<?xml version="1.0" encoding="utf-8" standalone="no"?>
<device schemaVersion="1.1">
  <name>STM32H755ZIT7@M4</name>
  <version>1.0</version>
  <description>STM32H755BIT3@M4,STM32H755BIT6@M4,STM32H755BIT7@M4,STM32H755IIK3@M4,STM32H755IIK6@M4,STM32H755IIK7@M4,STM32H755IIT3@M4,STM32H755IIT6@M4,STM32H755IIT7@M4,STM32H755XIH3@M4,STM32H755XIH6@M4,STM32H755XIH7@M4,STM32H755ZIT3@M4,STM32H755ZIT6@M4,STM32H755ZIT7@M4</description>
  <addressUnitBits>8</addressUnitBits>
  <width>32</width>
  <size>0x20</size>
  <resetValue>0</resetValue>
  <resetMask>0xFFFFFFFF</resetMask>
  <peripherals>
    <peripheral>
      <name>TIM2</name>
      <baseAddress>0x40000000</baseAddress>
      <registers>
        <register>
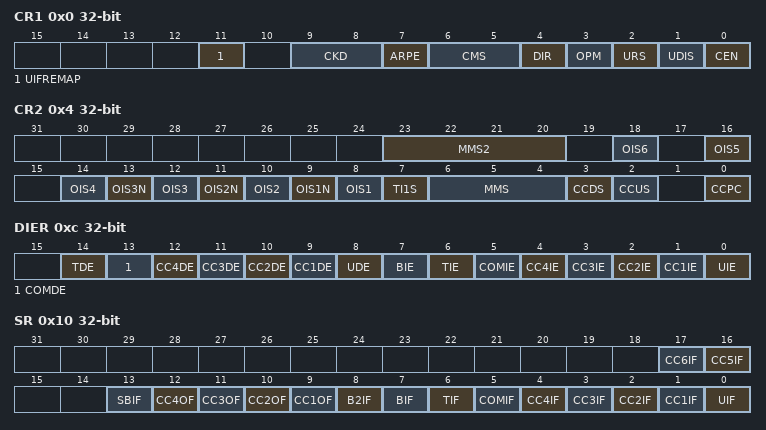
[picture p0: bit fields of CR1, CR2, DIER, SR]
          <name>CR1</name>
          <addressOffset>0x0</addressOffset>
          <size>0x20</size>
          <fields>
            <field>
              <name>CEN</name>
              <bitOffset>0</bitOffset>
              <bitWidth>1</bitWidth>
            </field>
            <field>
              <name>UDIS</name>
              <bitOffset>1</bitOffset>
              <bitWidth>1</bitWidth>
            </field>
            <field>
              <name>URS</name>
              <bitOffset>2</bitOffset>
              <bitWidth>1</bitWidth>
            </field>
            <field>
              <name>OPM</name>
              <bitOffset>3</bitOffset>
              <bitWidth>1</bitWidth>
            </field>
            <field>
              <name>DIR</name>
              <bitOffset>4</bitOffset>
              <bitWidth>1</bitWidth>
            </field>
            <field>
              <name>CMS</name>
              <bitOffset>5</bitOffset>
              <bitWidth>2</bitWidth>
            </field>
            <field>
              <name>ARPE</name>
              <bitOffset>7</bitOffset>
              <bitWidth>1</bitWidth>
            </field>
            <field>
              <name>CKD</name>
              <bitOffset>8</bitOffset>
              <bitWidth>2</bitWidth>
            </field>
            <field>
              <name>UIFREMAP</name>
              <bitOffset>11</bitOffset>
              <bitWidth>1</bitWidth>
            </field>
          </fields>
        </register>
        <register>
          <name>CR2</name>
          <addressOffset>0x4</addressOffset>
          <size>0x20</size>
          <fields>
            <field>
              <name>CCPC</name>
              <bitOffset>0</bitOffset>
              <bitWidth>1</bitWidth>
            </field>
            <field>
              <name>CCUS</name>
              <bitOffset>2</bitOffset>
              <bitWidth>1</bitWidth>
            </field>
            <field>
              <name>CCDS</name>
              <bitOffset>3</bitOffset>
              <bitWidth>1</bitWidth>
            </field>
            <field>
              <name>MMS</name>
              <bitOffset>4</bitOffset>
              <bitWidth>3</bitWidth>
            </field>
            <field>
              <name>TI1S</name>
              <bitOffset>7</bitOffset>
              <bitWidth>1</bitWidth>
            </field>
            <field>
              <name>OIS1</name>
              <bitOffset>8</bitOffset>
              <bitWidth>1</bitWidth>
            </field>
            <field>
              <name>OIS1N</name>
              <bitOffset>9</bitOffset>
              <bitWidth>1</bitWidth>
            </field>
            <field>
              <name>OIS2</name>
              <bitOffset>10</bitOffset>
              <bitWidth>1</bitWidth>
            </field>
            <field>
              <name>OIS2N</name>
              <bitOffset>11</bitOffset>
              <bitWidth>1</bitWidth>
            </field>
            <field>
              <name>OIS3</name>
              <bitOffset>12</bitOffset>
              <bitWidth>1</bitWidth>
            </field>
            <field>
              <name>OIS3N</name>
              <bitOffset>13</bitOffset>
              <bitWidth>1</bitWidth>
            </field>
            <field>
              <name>OIS4</name>
              <bitOffset>14</bitOffset>
              <bitWidth>1</bitWidth>
            </field>
            <field>
              <name>OIS5</name>
              <bitOffset>16</bitOffset>
              <bitWidth>1</bitWidth>
            </field>
            <field>
              <name>OIS6</name>
              <bitOffset>18</bitOffset>
              <bitWidth>1</bitWidth>
            </field>
            <field>
              <name>MMS2</name>
              <bitOffset>20</bitOffset>
              <bitWidth>4</bitWidth>
            </field>
          </fields>
        </register>
        <register>
          <name>SMCR</name>
          <addressOffset>0x8</addressOffset>
          <size>0x20</size>
          <fields>
            <field>
              <name>SMS</name>
              <bitOffset>0</bitOffset>
              <bitWidth>17</bitWidth>
            </field>
            <field>
              <name>TS</name>
              <bitOffset>4</bitOffset>
              <bitWidth>18</bitWidth>
            </field>
            <field>
              <name>MSM</name>
              <bitOffset>7</bitOffset>
              <bitWidth>1</bitWidth>
            </field>
            <field>
              <name>ETF</name>
              <bitOffset>8</bitOffset>
              <bitWidth>4</bitWidth>
            </field>
            <field>
              <name>ETPS</name>
              <bitOffset>12</bitOffset>
              <bitWidth>2</bitWidth>
            </field>
            <field>
              <name>ECE</name>
              <bitOffset>14</bitOffset>
              <bitWidth>1</bitWidth>
            </field>
            <field>
              <name>ETP</name>
              <bitOffset>15</bitOffset>
              <bitWidth>1</bitWidth>
            </field>
          </fields>
        </register>
        <register>
          <name>DIER</name>
          <addressOffset>0xc</addressOffset>
          <size>0x20</size>
          <fields>
            <field>
              <name>UIE</name>
              <bitOffset>0</bitOffset>
              <bitWidth>1</bitWidth>
            </field>
            <field>
              <name>CC1IE</name>
              <bitOffset>1</bitOffset>
              <bitWidth>1</bitWidth>
            </field>
            <field>
              <name>CC2IE</name>
              <bitOffset>2</bitOffset>
              <bitWidth>1</bitWidth>
            </field>
            <field>
              <name>CC3IE</name>
              <bitOffset>3</bitOffset>
              <bitWidth>1</bitWidth>
            </field>
            <field>
              <name>CC4IE</name>
              <bitOffset>4</bitOffset>
              <bitWidth>1</bitWidth>
            </field>
            <field>
              <name>COMIE</name>
              <bitOffset>5</bitOffset>
              <bitWidth>1</bitWidth>
            </field>
            <field>
              <name>TIE</name>
              <bitOffset>6</bitOffset>
              <bitWidth>1</bitWidth>
            </field>
            <field>
              <name>BIE</name>
              <bitOffset>7</bitOffset>
              <bitWidth>1</bitWidth>
            </field>
            <field>
              <name>UDE</name>
              <bitOffset>8</bitOffset>
              <bitWidth>1</bitWidth>
            </field>
            <field>
              <name>CC1DE</name>
              <bitOffset>9</bitOffset>
              <bitWidth>1</bitWidth>
            </field>
            <field>
              <name>CC2DE</name>
              <bitOffset>10</bitOffset>
              <bitWidth>1</bitWidth>
            </field>
            <field>
              <name>CC3DE</name>
              <bitOffset>11</bitOffset>
              <bitWidth>1</bitWidth>
            </field>
            <field>
              <name>CC4DE</name>
              <bitOffset>12</bitOffset>
              <bitWidth>1</bitWidth>
            </field>
            <field>
              <name>COMDE</name>
              <bitOffset>13</bitOffset>
              <bitWidth>1</bitWidth>
            </field>
            <field>
              <name>TDE</name>
              <bitOffset>14</bitOffset>
              <bitWidth>1</bitWidth>
            </field>
          </fields>
        </register>
        <register>
          <name>SR</name>
          <addressOffset>0x10</addressOffset>
          <size>0x20</size>
          <fields>
            <field>
              <name>UIF</name>
              <bitOffset>0</bitOffset>
              <bitWidth>1</bitWidth>
            </field>
            <field>
              <name>CC1IF</name>
              <bitOffset>1</bitOffset>
              <bitWidth>1</bitWidth>
            </field>
            <field>
              <name>CC2IF</name>
              <bitOffset>2</bitOffset>
              <bitWidth>1</bitWidth>
            </field>
            <field>
              <name>CC3IF</name>
              <bitOffset>3</bitOffset>
              <bitWidth>1</bitWidth>
            </field>
            <field>
              <name>CC4IF</name>
              <bitOffset>4</bitOffset>
              <bitWidth>1</bitWidth>
            </field>
            <field>
              <name>COMIF</name>
              <bitOffset>5</bitOffset>
              <bitWidth>1</bitWidth>
            </field>
            <field>
              <name>TIF</name>
              <bitOffset>6</bitOffset>
              <bitWidth>1</bitWidth>
            </field>
            <field>
              <name>BIF</name>
              <bitOffset>7</bitOffset>
              <bitWidth>1</bitWidth>
            </field>
            <field>
              <name>B2IF</name>
              <bitOffset>8</bitOffset>
              <bitWidth>1</bitWidth>
            </field>
            <field>
              <name>CC1OF</name>
              <bitOffset>9</bitOffset>
              <bitWidth>1</bitWidth>
            </field>
            <field>
              <name>CC2OF</name>
              <bitOffset>10</bitOffset>
              <bitWidth>1</bitWidth>
            </field>
            <field>
              <name>CC3OF</name>
              <bitOffset>11</bitOffset>
              <bitWidth>1</bitWidth>
            </field>
            <field>
              <name>CC4OF</name>
              <bitOffset>12</bitOffset>
              <bitWidth>1</bitWidth>
            </field>
            <field>
              <name>SBIF</name>
              <bitOffset>13</bitOffset>
              <bitWidth>1</bitWidth>
            </field>
            <field>
              <name>CC5IF</name>
              <bitOffset>16</bitOffset>
              <bitWidth>1</bitWidth>
            </field>
            <field>
              <name>CC6IF</name>
              <bitOffset>17</bitOffset>
              <bitWidth>1</bitWidth>
            </field>
          </fields>
        </register>
        <register>
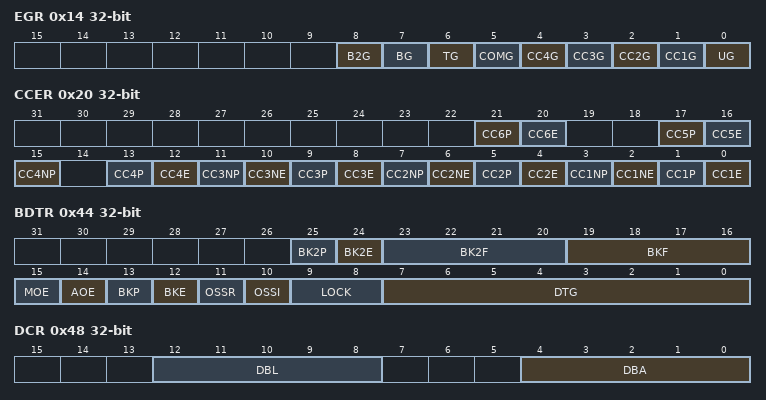
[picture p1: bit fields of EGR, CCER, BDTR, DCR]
          <name>EGR</name>
          <addressOffset>0x14</addressOffset>
          <size>0x20</size>
          <fields>
            <field>
              <name>UG</name>
              <bitOffset>0</bitOffset>
              <bitWidth>1</bitWidth>
            </field>
            <field>
              <name>CC1G</name>
              <bitOffset>1</bitOffset>
              <bitWidth>1</bitWidth>
            </field>
            <field>
              <name>CC2G</name>
              <bitOffset>2</bitOffset>
              <bitWidth>1</bitWidth>
            </field>
            <field>
              <name>CC3G</name>
              <bitOffset>3</bitOffset>
              <bitWidth>1</bitWidth>
            </field>
            <field>
              <name>CC4G</name>
              <bitOffset>4</bitOffset>
              <bitWidth>1</bitWidth>
            </field>
            <field>
              <name>COMG</name>
              <bitOffset>5</bitOffset>
              <bitWidth>1</bitWidth>
            </field>
            <field>
              <name>TG</name>
              <bitOffset>6</bitOffset>
              <bitWidth>1</bitWidth>
            </field>
            <field>
              <name>BG</name>
              <bitOffset>7</bitOffset>
              <bitWidth>1</bitWidth>
            </field>
            <field>
              <name>B2G</name>
              <bitOffset>8</bitOffset>
              <bitWidth>1</bitWidth>
            </field>
          </fields>
        </register>
        <register>
          <name>CCMR1</name>
          <addressOffset>0x18</addressOffset>
          <size>0x20</size>
          <fields>
            <field>
              <name>CC1S</name>
              <bitOffset>0</bitOffset>
              <bitWidth>2</bitWidth>
            </field>
            <field>
              <name>OC1FE</name>
              <bitOffset>2</bitOffset>
              <bitWidth>1</bitWidth>
            </field>
            <field>
              <name>OC1PE</name>
              <bitOffset>3</bitOffset>
              <bitWidth>1</bitWidth>
            </field>
            <field>
              <name>OC1M</name>
              <bitOffset>4</bitOffset>
              <bitWidth>13</bitWidth>
            </field>
            <field>
              <name>OC1CE</name>
              <bitOffset>7</bitOffset>
              <bitWidth>1</bitWidth>
            </field>
            <field>
              <name>CC2S</name>
              <bitOffset>8</bitOffset>
              <bitWidth>2</bitWidth>
            </field>
            <field>
              <name>OC2FE</name>
              <bitOffset>10</bitOffset>
              <bitWidth>1</bitWidth>
            </field>
            <field>
              <name>OC2PE</name>
              <bitOffset>11</bitOffset>
              <bitWidth>1</bitWidth>
            </field>
            <field>
              <name>OC2M</name>
              <bitOffset>12</bitOffset>
              <bitWidth>13</bitWidth>
            </field>
            <field>
              <name>OC2CE</name>
              <bitOffset>15</bitOffset>
              <bitWidth>1</bitWidth>
            </field>
          </fields>
        </register>
        <register>
          <name>CCMR2</name>
          <addressOffset>0x1c</addressOffset>
          <size>0x20</size>
          <fields>
            <field>
              <name>CC3S</name>
              <bitOffset>0</bitOffset>
              <bitWidth>2</bitWidth>
            </field>
            <field>
              <name>OC3FE</name>
              <bitOffset>2</bitOffset>
              <bitWidth>1</bitWidth>
            </field>
            <field>
              <name>OC3PE</name>
              <bitOffset>3</bitOffset>
              <bitWidth>1</bitWidth>
            </field>
            <field>
              <name>OC3M</name>
              <bitOffset>4</bitOffset>
              <bitWidth>13</bitWidth>
            </field>
            <field>
              <name>OC3CE</name>
              <bitOffset>7</bitOffset>
              <bitWidth>1</bitWidth>
            </field>
            <field>
              <name>CC4S</name>
              <bitOffset>8</bitOffset>
              <bitWidth>2</bitWidth>
            </field>
            <field>
              <name>OC4FE</name>
              <bitOffset>10</bitOffset>
              <bitWidth>1</bitWidth>
            </field>
            <field>
              <name>OC4PE</name>
              <bitOffset>11</bitOffset>
              <bitWidth>1</bitWidth>
            </field>
            <field>
              <name>OC4M</name>
              <bitOffset>12</bitOffset>
              <bitWidth>13</bitWidth>
            </field>
            <field>
              <name>OC4CE</name>
              <bitOffset>15</bitOffset>
              <bitWidth>1</bitWidth>
            </field>
          </fields>
        </register>
        <register>
          <name>CCER</name>
          <addressOffset>0x20</addressOffset>
          <size>0x20</size>
          <fields>
            <field>
              <name>CC1E</name>
              <bitOffset>0</bitOffset>
              <bitWidth>1</bitWidth>
            </field>
            <field>
              <name>CC1P</name>
              <bitOffset>1</bitOffset>
              <bitWidth>1</bitWidth>
            </field>
            <field>
              <name>CC1NE</name>
              <bitOffset>2</bitOffset>
              <bitWidth>1</bitWidth>
            </field>
            <field>
              <name>CC1NP</name>
              <bitOffset>3</bitOffset>
              <bitWidth>1</bitWidth>
            </field>
            <field>
              <name>CC2E</name>
              <bitOffset>4</bitOffset>
              <bitWidth>1</bitWidth>
            </field>
            <field>
              <name>CC2P</name>
              <bitOffset>5</bitOffset>
              <bitWidth>1</bitWidth>
            </field>
            <field>
              <name>CC2NE</name>
              <bitOffset>6</bitOffset>
              <bitWidth>1</bitWidth>
            </field>
            <field>
              <name>CC2NP</name>
              <bitOffset>7</bitOffset>
              <bitWidth>1</bitWidth>
            </field>
            <field>
              <name>CC3E</name>
              <bitOffset>8</bitOffset>
              <bitWidth>1</bitWidth>
            </field>
            <field>
              <name>CC3P</name>
              <bitOffset>9</bitOffset>
              <bitWidth>1</bitWidth>
            </field>
            <field>
              <name>CC3NE</name>
              <bitOffset>10</bitOffset>
              <bitWidth>1</bitWidth>
            </field>
            <field>
              <name>CC3NP</name>
              <bitOffset>11</bitOffset>
              <bitWidth>1</bitWidth>
            </field>
            <field>
              <name>CC4E</name>
              <bitOffset>12</bitOffset>
              <bitWidth>1</bitWidth>
            </field>
            <field>
              <name>CC4P</name>
              <bitOffset>13</bitOffset>
              <bitWidth>1</bitWidth>
            </field>
            <field>
              <name>CC4NP</name>
              <bitOffset>15</bitOffset>
              <bitWidth>1</bitWidth>
            </field>
            <field>
              <name>CC5E</name>
              <bitOffset>16</bitOffset>
              <bitWidth>1</bitWidth>
            </field>
            <field>
              <name>CC5P</name>
              <bitOffset>17</bitOffset>
              <bitWidth>1</bitWidth>
            </field>
            <field>
              <name>CC6E</name>
              <bitOffset>20</bitOffset>
              <bitWidth>1</bitWidth>
            </field>
            <field>
              <name>CC6P</name>
              <bitOffset>21</bitOffset>
              <bitWidth>1</bitWidth>
            </field>
          </fields>
        </register>
        <register>
          <name>CNT</name>
          <addressOffset>0x24</addressOffset>
          <size>0x20</size>
          <fields>
            <field>
              <name>CNT</name>
              <bitOffset>0</bitOffset>
              <bitWidth>32</bitWidth>
            </field>
            <field>
              <name>UIFCPY</name>
              <bitOffset>31</bitOffset>
              <bitWidth>1</bitWidth>
            </field>
          </fields>
        </register>
        <register>
          <name>PSC</name>
          <addressOffset>0x28</addressOffset>
          <size>0x20</size>
          <fields>
            <field>
              <name>PSC</name>
              <bitOffset>0</bitOffset>
              <bitWidth>16</bitWidth>
            </field>
          </fields>
        </register>
        <register>
          <name>ARR</name>
          <addressOffset>0x2c</addressOffset>
          <size>0x20</size>
          <fields>
            <field>
              <name>ARR</name>
              <bitOffset>0</bitOffset>
              <bitWidth>32</bitWidth>
            </field>
          </fields>
        </register>
        <register>
          <name>RCR</name>
          <addressOffset>0x30</addressOffset>
          <size>0x20</size>
          <fields>
            <field>
              <name>REP</name>
              <bitOffset>0</bitOffset>
              <bitWidth>8</bitWidth>
            </field>
          </fields>
        </register>
        <register>
          <name>CCR1</name>
          <addressOffset>0x34</addressOffset>
          <size>0x20</size>
          <fields>
            <field>
              <name>CCR1</name>
              <bitOffset>0</bitOffset>
              <bitWidth>16</bitWidth>
            </field>
          </fields>
        </register>
        <register>
          <name>CCR2</name>
          <addressOffset>0x38</addressOffset>
          <size>0x20</size>
          <fields>
            <field>
              <name>CCR2</name>
              <bitOffset>0</bitOffset>
              <bitWidth>16</bitWidth>
            </field>
          </fields>
        </register>
        <register>
          <name>CCR3</name>
          <addressOffset>0x3c</addressOffset>
          <size>0x20</size>
          <fields>
            <field>
              <name>CCR3</name>
              <bitOffset>0</bitOffset>
              <bitWidth>16</bitWidth>
            </field>
          </fields>
        </register>
        <register>
          <name>CCR4</name>
          <addressOffset>0x40</addressOffset>
          <size>0x20</size>
          <fields>
            <field>
              <name>CCR4</name>
              <bitOffset>0</bitOffset>
              <bitWidth>16</bitWidth>
            </field>
          </fields>
        </register>
        <register>
          <name>BDTR</name>
          <addressOffset>0x44</addressOffset>
          <size>0x20</size>
          <fields>
            <field>
              <name>DTG</name>
              <bitOffset>0</bitOffset>
              <bitWidth>8</bitWidth>
            </field>
            <field>
              <name>LOCK</name>
              <bitOffset>8</bitOffset>
              <bitWidth>2</bitWidth>
            </field>
            <field>
              <name>OSSI</name>
              <bitOffset>10</bitOffset>
              <bitWidth>1</bitWidth>
            </field>
            <field>
              <name>OSSR</name>
              <bitOffset>11</bitOffset>
              <bitWidth>1</bitWidth>
            </field>
            <field>
              <name>BKE</name>
              <bitOffset>12</bitOffset>
              <bitWidth>1</bitWidth>
            </field>
            <field>
              <name>BKP</name>
              <bitOffset>13</bitOffset>
              <bitWidth>1</bitWidth>
            </field>
            <field>
              <name>AOE</name>
              <bitOffset>14</bitOffset>
              <bitWidth>1</bitWidth>
            </field>
            <field>
              <name>MOE</name>
              <bitOffset>15</bitOffset>
              <bitWidth>1</bitWidth>
            </field>
            <field>
              <name>BKF</name>
              <bitOffset>16</bitOffset>
              <bitWidth>4</bitWidth>
            </field>
            <field>
              <name>BK2F</name>
              <bitOffset>20</bitOffset>
              <bitWidth>4</bitWidth>
            </field>
            <field>
              <name>BK2E</name>
              <bitOffset>24</bitOffset>
              <bitWidth>1</bitWidth>
            </field>
            <field>
              <name>BK2P</name>
              <bitOffset>25</bitOffset>
              <bitWidth>1</bitWidth>
            </field>
          </fields>
        </register>
        <register>
          <name>DCR</name>
          <addressOffset>0x48</addressOffset>
          <size>0x20</size>
          <fields>
            <field>
              <name>DBA</name>
              <bitOffset>0</bitOffset>
              <bitWidth>5</bitWidth>
            </field>
            <field>
              <name>DBL</name>
              <bitOffset>8</bitOffset>
              <bitWidth>5</bitWidth>
            </field>
          </fields>
        </register>
        <register>
          <name>DMAR</name>
          <addressOffset>0x4c</addressOffset>
          <size>0x20</size>
          <fields>
            <field>
              <name>DMAB</name>
              <bitOffset>0</bitOffset>
              <bitWidth>16</bitWidth>
            </field>
          </fields>
        </register>
        <register>
          <name>CCMR3</name>
          <addressOffset>0x54</addressOffset>
          <size>0x20</size>
          <fields>
            <field>
              <name>OC5FE</name>
              <bitOffset>2</bitOffset>
              <bitWidth>1</bitWidth>
            </field>
            <field>
              <name>OC5PE</name>
              <bitOffset>3</bitOffset>
              <bitWidth>1</bitWidth>
            </field>
            <field>
              <name>OC5M</name>
              <bitOffset>4</bitOffset>
              <bitWidth>13</bitWidth>
            </field>
            <field>
              <name>OC5CE</name>
              <bitOffset>7</bitOffset>
              <bitWidth>1</bitWidth>
            </field>
            <field>
              <name>OC6FE</name>
              <bitOffset>10</bitOffset>
              <bitWidth>1</bitWidth>
            </field>
            <field>
              <name>OC6PE</name>
              <bitOffset>11</bitOffset>
              <bitWidth>1</bitWidth>
            </field>
            <field>
              <name>OC6M</name>
              <bitOffset>12</bitOffset>
              <bitWidth>13</bitWidth>
            </field>
            <field>
              <name>OC6CE</name>
              <bitOffset>15</bitOffset>
              <bitWidth>1</bitWidth>
            </field>
          </fields>
        </register>
        <register>
          <name>CCR5</name>
          <addressOffset>0x58</addressOffset>
          <size>0x20</size>
          <fields>
            <field>
              <name>CCR5</name>
              <bitOffset>0</bitOffset>
              <bitWidth>32</bitWidth>
            </field>
            <field>
              <name>GC5C1</name>
              <bitOffset>29</bitOffset>
              <bitWidth>1</bitWidth>
            </field>
            <field>
              <name>GC5C2</name>
              <bitOffset>30</bitOffset>
              <bitWidth>1</bitWidth>
            </field>
            <field>
              <name>GC5C3</name>
              <bitOffset>31</bitOffset>
              <bitWidth>1</bitWidth>
            </field>
          </fields>
        </register>
        <register>
          <name>CCR6</name>
          <addressOffset>0x5c</addressOffset>
          <size>0x20</size>
          <fields>
            <field>
              <name>CCR6</name>
              <bitOffset>0</bitOffset>
              <bitWidth>16</bitWidth>
            </field>
          </fields>
        </register>
        <register>
          <name>AF1</name>
          <addressOffset>0x60</addressOffset>
          <size>0x20</size>
        </register>
        <register>
          <name>AF2</name>
          <addressOffset>0x64</addressOffset>
          <size>0x20</size>
        </register>
        <register>
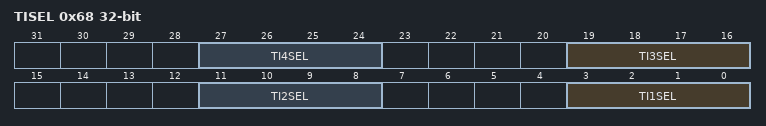
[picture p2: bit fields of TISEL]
          <name>TISEL</name>
          <addressOffset>0x68</addressOffset>
          <size>0x20</size>
          <fields>
            <field>
              <name>TI1SEL</name>
              <bitOffset>0</bitOffset>
              <bitWidth>4</bitWidth>
            </field>
            <field>
              <name>TI2SEL</name>
              <bitOffset>8</bitOffset>
              <bitWidth>4</bitWidth>
            </field>
            <field>
              <name>TI3SEL</name>
              <bitOffset>16</bitOffset>
              <bitWidth>4</bitWidth>
            </field>
            <field>
              <name>TI4SEL</name>
              <bitOffset>24</bitOffset>
              <bitWidth>4</bitWidth>
            </field>
          </fields>
        </register>
      </registers>
    </peripheral>
    <peripheral>
      <name>TIM3</name>
      <baseAddress>0x40000400</baseAddress>
      <registers>
        <register>
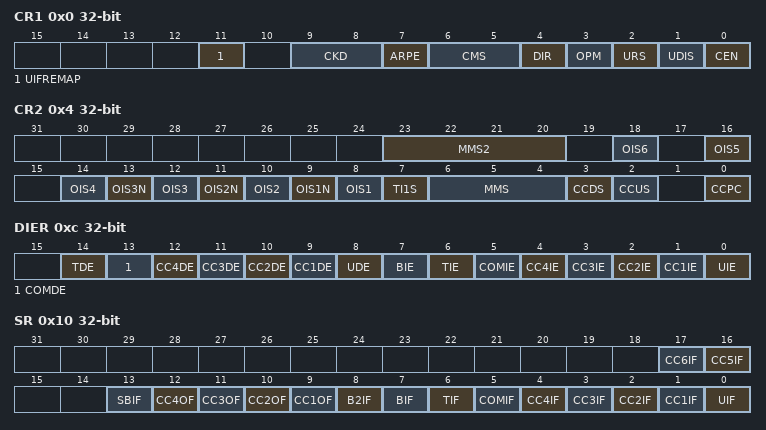
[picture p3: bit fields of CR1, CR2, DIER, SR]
          <name>CR1</name>
          <addressOffset>0x0</addressOffset>
          <size>0x20</size>
          <fields>
            <field>
              <name>CEN</name>
              <bitOffset>0</bitOffset>
              <bitWidth>1</bitWidth>
            </field>
            <field>
              <name>UDIS</name>
              <bitOffset>1</bitOffset>
              <bitWidth>1</bitWidth>
            </field>
            <field>
              <name>URS</name>
              <bitOffset>2</bitOffset>
              <bitWidth>1</bitWidth>
            </field>
            <field>
              <name>OPM</name>
              <bitOffset>3</bitOffset>
              <bitWidth>1</bitWidth>
            </field>
            <field>
              <name>DIR</name>
              <bitOffset>4</bitOffset>
              <bitWidth>1</bitWidth>
            </field>
            <field>
              <name>CMS</name>
              <bitOffset>5</bitOffset>
              <bitWidth>2</bitWidth>
            </field>
            <field>
              <name>ARPE</name>
              <bitOffset>7</bitOffset>
              <bitWidth>1</bitWidth>
            </field>
            <field>
              <name>CKD</name>
              <bitOffset>8</bitOffset>
              <bitWidth>2</bitWidth>
            </field>
            <field>
              <name>UIFREMAP</name>
              <bitOffset>11</bitOffset>
              <bitWidth>1</bitWidth>
            </field>
          </fields>
        </register>
        <register>
          <name>CR2</name>
          <addressOffset>0x4</addressOffset>
          <size>0x20</size>
          <fields>
            <field>
              <name>CCPC</name>
              <bitOffset>0</bitOffset>
              <bitWidth>1</bitWidth>
            </field>
            <field>
              <name>CCUS</name>
              <bitOffset>2</bitOffset>
              <bitWidth>1</bitWidth>
            </field>
            <field>
              <name>CCDS</name>
              <bitOffset>3</bitOffset>
              <bitWidth>1</bitWidth>
            </field>
            <field>
              <name>MMS</name>
              <bitOffset>4</bitOffset>
              <bitWidth>3</bitWidth>
            </field>
            <field>
              <name>TI1S</name>
              <bitOffset>7</bitOffset>
              <bitWidth>1</bitWidth>
            </field>
            <field>
              <name>OIS1</name>
              <bitOffset>8</bitOffset>
              <bitWidth>1</bitWidth>
            </field>
            <field>
              <name>OIS1N</name>
              <bitOffset>9</bitOffset>
              <bitWidth>1</bitWidth>
            </field>
            <field>
              <name>OIS2</name>
              <bitOffset>10</bitOffset>
              <bitWidth>1</bitWidth>
            </field>
            <field>
              <name>OIS2N</name>
              <bitOffset>11</bitOffset>
              <bitWidth>1</bitWidth>
            </field>
            <field>
              <name>OIS3</name>
              <bitOffset>12</bitOffset>
              <bitWidth>1</bitWidth>
            </field>
            <field>
              <name>OIS3N</name>
              <bitOffset>13</bitOffset>
              <bitWidth>1</bitWidth>
            </field>
            <field>
              <name>OIS4</name>
              <bitOffset>14</bitOffset>
              <bitWidth>1</bitWidth>
            </field>
            <field>
              <name>OIS5</name>
              <bitOffset>16</bitOffset>
              <bitWidth>1</bitWidth>
            </field>
            <field>
              <name>OIS6</name>
              <bitOffset>18</bitOffset>
              <bitWidth>1</bitWidth>
            </field>
            <field>
              <name>MMS2</name>
              <bitOffset>20</bitOffset>
              <bitWidth>4</bitWidth>
            </field>
          </fields>
        </register>
        <register>
          <name>SMCR</name>
          <addressOffset>0x8</addressOffset>
          <size>0x20</size>
          <fields>
            <field>
              <name>SMS</name>
              <bitOffset>0</bitOffset>
              <bitWidth>17</bitWidth>
            </field>
            <field>
              <name>TS</name>
              <bitOffset>4</bitOffset>
              <bitWidth>18</bitWidth>
            </field>
            <field>
              <name>MSM</name>
              <bitOffset>7</bitOffset>
              <bitWidth>1</bitWidth>
            </field>
            <field>
              <name>ETF</name>
              <bitOffset>8</bitOffset>
              <bitWidth>4</bitWidth>
            </field>
            <field>
              <name>ETPS</name>
              <bitOffset>12</bitOffset>
              <bitWidth>2</bitWidth>
            </field>
            <field>
              <name>ECE</name>
              <bitOffset>14</bitOffset>
              <bitWidth>1</bitWidth>
            </field>
            <field>
              <name>ETP</name>
              <bitOffset>15</bitOffset>
              <bitWidth>1</bitWidth>
            </field>
          </fields>
        </register>
        <register>
          <name>DIER</name>
          <addressOffset>0xc</addressOffset>
          <size>0x20</size>
          <fields>
            <field>
              <name>UIE</name>
              <bitOffset>0</bitOffset>
              <bitWidth>1</bitWidth>
            </field>
            <field>
              <name>CC1IE</name>
              <bitOffset>1</bitOffset>
              <bitWidth>1</bitWidth>
            </field>
            <field>
              <name>CC2IE</name>
              <bitOffset>2</bitOffset>
              <bitWidth>1</bitWidth>
            </field>
            <field>
              <name>CC3IE</name>
              <bitOffset>3</bitOffset>
              <bitWidth>1</bitWidth>
            </field>
            <field>
              <name>CC4IE</name>
              <bitOffset>4</bitOffset>
              <bitWidth>1</bitWidth>
            </field>
            <field>
              <name>COMIE</name>
              <bitOffset>5</bitOffset>
              <bitWidth>1</bitWidth>
            </field>
            <field>
              <name>TIE</name>
              <bitOffset>6</bitOffset>
              <bitWidth>1</bitWidth>
            </field>
            <field>
              <name>BIE</name>
              <bitOffset>7</bitOffset>
              <bitWidth>1</bitWidth>
            </field>
            <field>
              <name>UDE</name>
              <bitOffset>8</bitOffset>
              <bitWidth>1</bitWidth>
            </field>
            <field>
              <name>CC1DE</name>
              <bitOffset>9</bitOffset>
              <bitWidth>1</bitWidth>
            </field>
            <field>
              <name>CC2DE</name>
              <bitOffset>10</bitOffset>
              <bitWidth>1</bitWidth>
            </field>
            <field>
              <name>CC3DE</name>
              <bitOffset>11</bitOffset>
              <bitWidth>1</bitWidth>
            </field>
            <field>
              <name>CC4DE</name>
              <bitOffset>12</bitOffset>
              <bitWidth>1</bitWidth>
            </field>
            <field>
              <name>COMDE</name>
              <bitOffset>13</bitOffset>
              <bitWidth>1</bitWidth>
            </field>
            <field>
              <name>TDE</name>
              <bitOffset>14</bitOffset>
              <bitWidth>1</bitWidth>
            </field>
          </fields>
        </register>
        <register>
          <name>SR</name>
          <addressOffset>0x10</addressOffset>
          <size>0x20</size>
          <fields>
            <field>
              <name>UIF</name>
              <bitOffset>0</bitOffset>
              <bitWidth>1</bitWidth>
            </field>
            <field>
              <name>CC1IF</name>
              <bitOffset>1</bitOffset>
              <bitWidth>1</bitWidth>
            </field>
            <field>
              <name>CC2IF</name>
              <bitOffset>2</bitOffset>
              <bitWidth>1</bitWidth>
            </field>
            <field>
              <name>CC3IF</name>
              <bitOffset>3</bitOffset>
              <bitWidth>1</bitWidth>
            </field>
            <field>
              <name>CC4IF</name>
              <bitOffset>4</bitOffset>
              <bitWidth>1</bitWidth>
            </field>
            <field>
              <name>COMIF</name>
              <bitOffset>5</bitOffset>
              <bitWidth>1</bitWidth>
            </field>
            <field>
              <name>TIF</name>
              <bitOffset>6</bitOffset>
              <bitWidth>1</bitWidth>
            </field>
            <field>
              <name>BIF</name>
              <bitOffset>7</bitOffset>
              <bitWidth>1</bitWidth>
            </field>
            <field>
              <name>B2IF</name>
              <bitOffset>8</bitOffset>
              <bitWidth>1</bitWidth>
            </field>
            <field>
              <name>CC1OF</name>
              <bitOffset>9</bitOffset>
              <bitWidth>1</bitWidth>
            </field>
            <field>
              <name>CC2OF</name>
              <bitOffset>10</bitOffset>
              <bitWidth>1</bitWidth>
            </field>
            <field>
              <name>CC3OF</name>
              <bitOffset>11</bitOffset>
              <bitWidth>1</bitWidth>
            </field>
            <field>
              <name>CC4OF</name>
              <bitOffset>12</bitOffset>
              <bitWidth>1</bitWidth>
            </field>
            <field>
              <name>SBIF</name>
              <bitOffset>13</bitOffset>
              <bitWidth>1</bitWidth>
            </field>
            <field>
              <name>CC5IF</name>
              <bitOffset>16</bitOffset>
              <bitWidth>1</bitWidth>
            </field>
            <field>
              <name>CC6IF</name>
              <bitOffset>17</bitOffset>
              <bitWidth>1</bitWidth>
            </field>
          </fields>
        </register>
        <register>
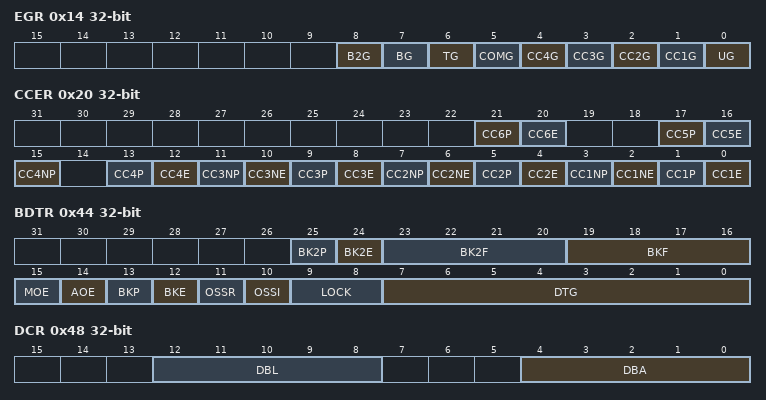
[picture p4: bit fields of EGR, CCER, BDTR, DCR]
          <name>EGR</name>
          <addressOffset>0x14</addressOffset>
          <size>0x20</size>
          <fields>
            <field>
              <name>UG</name>
              <bitOffset>0</bitOffset>
              <bitWidth>1</bitWidth>
            </field>
            <field>
              <name>CC1G</name>
              <bitOffset>1</bitOffset>
              <bitWidth>1</bitWidth>
            </field>
            <field>
              <name>CC2G</name>
              <bitOffset>2</bitOffset>
              <bitWidth>1</bitWidth>
            </field>
            <field>
              <name>CC3G</name>
              <bitOffset>3</bitOffset>
              <bitWidth>1</bitWidth>
            </field>
            <field>
              <name>CC4G</name>
              <bitOffset>4</bitOffset>
              <bitWidth>1</bitWidth>
            </field>
            <field>
              <name>COMG</name>
              <bitOffset>5</bitOffset>
              <bitWidth>1</bitWidth>
            </field>
            <field>
              <name>TG</name>
              <bitOffset>6</bitOffset>
              <bitWidth>1</bitWidth>
            </field>
            <field>
              <name>BG</name>
              <bitOffset>7</bitOffset>
              <bitWidth>1</bitWidth>
            </field>
            <field>
              <name>B2G</name>
              <bitOffset>8</bitOffset>
              <bitWidth>1</bitWidth>
            </field>
          </fields>
        </register>
        <register>
          <name>CCMR1</name>
          <addressOffset>0x18</addressOffset>
          <size>0x20</size>
          <fields>
            <field>
              <name>CC1S</name>
              <bitOffset>0</bitOffset>
              <bitWidth>2</bitWidth>
            </field>
            <field>
              <name>OC1FE</name>
              <bitOffset>2</bitOffset>
              <bitWidth>1</bitWidth>
            </field>
            <field>
              <name>OC1PE</name>
              <bitOffset>3</bitOffset>
              <bitWidth>1</bitWidth>
            </field>
            <field>
              <name>OC1M</name>
              <bitOffset>4</bitOffset>
              <bitWidth>13</bitWidth>
            </field>
            <field>
              <name>OC1CE</name>
              <bitOffset>7</bitOffset>
              <bitWidth>1</bitWidth>
            </field>
            <field>
              <name>CC2S</name>
              <bitOffset>8</bitOffset>
              <bitWidth>2</bitWidth>
            </field>
            <field>
              <name>OC2FE</name>
              <bitOffset>10</bitOffset>
              <bitWidth>1</bitWidth>
            </field>
            <field>
              <name>OC2PE</name>
              <bitOffset>11</bitOffset>
              <bitWidth>1</bitWidth>
            </field>
            <field>
              <name>OC2M</name>
              <bitOffset>12</bitOffset>
              <bitWidth>13</bitWidth>
            </field>
            <field>
              <name>OC2CE</name>
              <bitOffset>15</bitOffset>
              <bitWidth>1</bitWidth>
            </field>
          </fields>
        </register>
        <register>
          <name>CCMR2</name>
          <addressOffset>0x1c</addressOffset>
          <size>0x20</size>
          <fields>
            <field>
              <name>CC3S</name>
              <bitOffset>0</bitOffset>
              <bitWidth>2</bitWidth>
            </field>
            <field>
              <name>OC3FE</name>
              <bitOffset>2</bitOffset>
              <bitWidth>1</bitWidth>
            </field>
            <field>
              <name>OC3PE</name>
              <bitOffset>3</bitOffset>
              <bitWidth>1</bitWidth>
            </field>
            <field>
              <name>OC3M</name>
              <bitOffset>4</bitOffset>
              <bitWidth>13</bitWidth>
            </field>
            <field>
              <name>OC3CE</name>
              <bitOffset>7</bitOffset>
              <bitWidth>1</bitWidth>
            </field>
            <field>
              <name>CC4S</name>
              <bitOffset>8</bitOffset>
              <bitWidth>2</bitWidth>
            </field>
            <field>
              <name>OC4FE</name>
              <bitOffset>10</bitOffset>
              <bitWidth>1</bitWidth>
            </field>
            <field>
              <name>OC4PE</name>
              <bitOffset>11</bitOffset>
              <bitWidth>1</bitWidth>
            </field>
            <field>
              <name>OC4M</name>
              <bitOffset>12</bitOffset>
              <bitWidth>13</bitWidth>
            </field>
            <field>
              <name>OC4CE</name>
              <bitOffset>15</bitOffset>
              <bitWidth>1</bitWidth>
            </field>
          </fields>
        </register>
        <register>
          <name>CCER</name>
          <addressOffset>0x20</addressOffset>
          <size>0x20</size>
          <fields>
            <field>
              <name>CC1E</name>
              <bitOffset>0</bitOffset>
              <bitWidth>1</bitWidth>
            </field>
            <field>
              <name>CC1P</name>
              <bitOffset>1</bitOffset>
              <bitWidth>1</bitWidth>
            </field>
            <field>
              <name>CC1NE</name>
              <bitOffset>2</bitOffset>
              <bitWidth>1</bitWidth>
            </field>
            <field>
              <name>CC1NP</name>
              <bitOffset>3</bitOffset>
              <bitWidth>1</bitWidth>
            </field>
            <field>
              <name>CC2E</name>
              <bitOffset>4</bitOffset>
              <bitWidth>1</bitWidth>
            </field>
            <field>
              <name>CC2P</name>
              <bitOffset>5</bitOffset>
              <bitWidth>1</bitWidth>
            </field>
            <field>
              <name>CC2NE</name>
              <bitOffset>6</bitOffset>
              <bitWidth>1</bitWidth>
            </field>
            <field>
              <name>CC2NP</name>
              <bitOffset>7</bitOffset>
              <bitWidth>1</bitWidth>
            </field>
            <field>
              <name>CC3E</name>
              <bitOffset>8</bitOffset>
              <bitWidth>1</bitWidth>
            </field>
            <field>
              <name>CC3P</name>
              <bitOffset>9</bitOffset>
              <bitWidth>1</bitWidth>
            </field>
            <field>
              <name>CC3NE</name>
              <bitOffset>10</bitOffset>
              <bitWidth>1</bitWidth>
            </field>
            <field>
              <name>CC3NP</name>
              <bitOffset>11</bitOffset>
              <bitWidth>1</bitWidth>
            </field>
            <field>
              <name>CC4E</name>
              <bitOffset>12</bitOffset>
              <bitWidth>1</bitWidth>
            </field>
            <field>
              <name>CC4P</name>
              <bitOffset>13</bitOffset>
              <bitWidth>1</bitWidth>
            </field>
            <field>
              <name>CC4NP</name>
              <bitOffset>15</bitOffset>
              <bitWidth>1</bitWidth>
            </field>
            <field>
              <name>CC5E</name>
              <bitOffset>16</bitOffset>
              <bitWidth>1</bitWidth>
            </field>
            <field>
              <name>CC5P</name>
              <bitOffset>17</bitOffset>
              <bitWidth>1</bitWidth>
            </field>
            <field>
              <name>CC6E</name>
              <bitOffset>20</bitOffset>
              <bitWidth>1</bitWidth>
            </field>
            <field>
              <name>CC6P</name>
              <bitOffset>21</bitOffset>
              <bitWidth>1</bitWidth>
            </field>
          </fields>
        </register>
        <register>
          <name>CNT</name>
          <addressOffset>0x24</addressOffset>
          <size>0x20</size>
          <fields>
            <field>
              <name>CNT</name>
              <bitOffset>0</bitOffset>
              <bitWidth>32</bitWidth>
            </field>
            <field>
              <name>UIFCPY</name>
              <bitOffset>31</bitOffset>
              <bitWidth>1</bitWidth>
            </field>
          </fields>
        </register>
        <register>
          <name>PSC</name>
          <addressOffset>0x28</addressOffset>
          <size>0x20</size>
          <fields>
            <field>
              <name>PSC</name>
              <bitOffset>0</bitOffset>
              <bitWidth>16</bitWidth>
            </field>
          </fields>
        </register>
        <register>
          <name>ARR</name>
          <addressOffset>0x2c</addressOffset>
          <size>0x20</size>
          <fields>
            <field>
              <name>ARR</name>
              <bitOffset>0</bitOffset>
              <bitWidth>32</bitWidth>
            </field>
          </fields>
        </register>
        <register>
          <name>RCR</name>
          <addressOffset>0x30</addressOffset>
          <size>0x20</size>
          <fields>
            <field>
              <name>REP</name>
              <bitOffset>0</bitOffset>
              <bitWidth>8</bitWidth>
            </field>
          </fields>
        </register>
        <register>
          <name>CCR1</name>
          <addressOffset>0x34</addressOffset>
          <size>0x20</size>
          <fields>
            <field>
              <name>CCR1</name>
              <bitOffset>0</bitOffset>
              <bitWidth>16</bitWidth>
            </field>
          </fields>
        </register>
        <register>
          <name>CCR2</name>
          <addressOffset>0x38</addressOffset>
          <size>0x20</size>
          <fields>
            <field>
              <name>CCR2</name>
              <bitOffset>0</bitOffset>
              <bitWidth>16</bitWidth>
            </field>
          </fields>
        </register>
        <register>
          <name>CCR3</name>
          <addressOffset>0x3c</addressOffset>
          <size>0x20</size>
          <fields>
            <field>
              <name>CCR3</name>
              <bitOffset>0</bitOffset>
              <bitWidth>16</bitWidth>
            </field>
          </fields>
        </register>
        <register>
          <name>CCR4</name>
          <addressOffset>0x40</addressOffset>
          <size>0x20</size>
          <fields>
            <field>
              <name>CCR4</name>
              <bitOffset>0</bitOffset>
              <bitWidth>16</bitWidth>
            </field>
          </fields>
        </register>
        <register>
          <name>BDTR</name>
          <addressOffset>0x44</addressOffset>
          <size>0x20</size>
          <fields>
            <field>
              <name>DTG</name>
              <bitOffset>0</bitOffset>
              <bitWidth>8</bitWidth>
            </field>
            <field>
              <name>LOCK</name>
              <bitOffset>8</bitOffset>
              <bitWidth>2</bitWidth>
            </field>
            <field>
              <name>OSSI</name>
              <bitOffset>10</bitOffset>
              <bitWidth>1</bitWidth>
            </field>
            <field>
              <name>OSSR</name>
              <bitOffset>11</bitOffset>
              <bitWidth>1</bitWidth>
            </field>
            <field>
              <name>BKE</name>
              <bitOffset>12</bitOffset>
              <bitWidth>1</bitWidth>
            </field>
            <field>
              <name>BKP</name>
              <bitOffset>13</bitOffset>
              <bitWidth>1</bitWidth>
            </field>
            <field>
              <name>AOE</name>
              <bitOffset>14</bitOffset>
              <bitWidth>1</bitWidth>
            </field>
            <field>
              <name>MOE</name>
              <bitOffset>15</bitOffset>
              <bitWidth>1</bitWidth>
            </field>
            <field>
              <name>BKF</name>
              <bitOffset>16</bitOffset>
              <bitWidth>4</bitWidth>
            </field>
            <field>
              <name>BK2F</name>
              <bitOffset>20</bitOffset>
              <bitWidth>4</bitWidth>
            </field>
            <field>
              <name>BK2E</name>
              <bitOffset>24</bitOffset>
              <bitWidth>1</bitWidth>
            </field>
            <field>
              <name>BK2P</name>
              <bitOffset>25</bitOffset>
              <bitWidth>1</bitWidth>
            </field>
          </fields>
        </register>
        <register>
          <name>DCR</name>
          <addressOffset>0x48</addressOffset>
          <size>0x20</size>
          <fields>
            <field>
              <name>DBA</name>
              <bitOffset>0</bitOffset>
              <bitWidth>5</bitWidth>
            </field>
            <field>
              <name>DBL</name>
              <bitOffset>8</bitOffset>
              <bitWidth>5</bitWidth>
            </field>
          </fields>
        </register>
        <register>
          <name>DMAR</name>
          <addressOffset>0x4c</addressOffset>
          <size>0x20</size>
          <fields>
            <field>
              <name>DMAB</name>
              <bitOffset>0</bitOffset>
              <bitWidth>16</bitWidth>
            </field>
          </fields>
        </register>
        <register>
          <name>CCMR3</name>
          <addressOffset>0x54</addressOffset>
          <size>0x20</size>
          <fields>
            <field>
              <name>OC5FE</name>
              <bitOffset>2</bitOffset>
              <bitWidth>1</bitWidth>
            </field>
            <field>
              <name>OC5PE</name>
              <bitOffset>3</bitOffset>
              <bitWidth>1</bitWidth>
            </field>
            <field>
              <name>OC5M</name>
              <bitOffset>4</bitOffset>
              <bitWidth>13</bitWidth>
            </field>
            <field>
              <name>OC5CE</name>
              <bitOffset>7</bitOffset>
              <bitWidth>1</bitWidth>
            </field>
            <field>
              <name>OC6FE</name>
              <bitOffset>10</bitOffset>
              <bitWidth>1</bitWidth>
            </field>
            <field>
              <name>OC6PE</name>
              <bitOffset>11</bitOffset>
              <bitWidth>1</bitWidth>
            </field>
            <field>
              <name>OC6M</name>
              <bitOffset>12</bitOffset>
              <bitWidth>13</bitWidth>
            </field>
            <field>
              <name>OC6CE</name>
              <bitOffset>15</bitOffset>
              <bitWidth>1</bitWidth>
            </field>
          </fields>
        </register>
        <register>
          <name>CCR5</name>
          <addressOffset>0x58</addressOffset>
          <size>0x20</size>
          <fields>
            <field>
              <name>CCR5</name>
              <bitOffset>0</bitOffset>
              <bitWidth>32</bitWidth>
            </field>
            <field>
              <name>GC5C1</name>
              <bitOffset>29</bitOffset>
              <bitWidth>1</bitWidth>
            </field>
            <field>
              <name>GC5C2</name>
              <bitOffset>30</bitOffset>
              <bitWidth>1</bitWidth>
            </field>
            <field>
              <name>GC5C3</name>
              <bitOffset>31</bitOffset>
              <bitWidth>1</bitWidth>
            </field>
          </fields>
        </register>
        <register>
          <name>CCR6</name>
          <addressOffset>0x5c</addressOffset>
          <size>0x20</size>
          <fields>
            <field>
              <name>CCR6</name>
              <bitOffset>0</bitOffset>
              <bitWidth>16</bitWidth>
            </field>
          </fields>
        </register>
        <register>
          <name>AF1</name>
          <addressOffset>0x60</addressOffset>
          <size>0x20</size>
        </register>
        <register>
          <name>AF2</name>
          <addressOffset>0x64</addressOffset>
          <size>0x20</size>
        </register>
        <register>
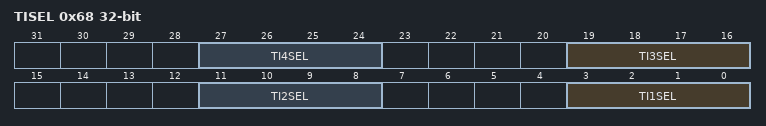
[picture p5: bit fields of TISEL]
          <name>TISEL</name>
          <addressOffset>0x68</addressOffset>
          <size>0x20</size>
          <fields>
            <field>
              <name>TI1SEL</name>
              <bitOffset>0</bitOffset>
              <bitWidth>4</bitWidth>
            </field>
            <field>
              <name>TI2SEL</name>
              <bitOffset>8</bitOffset>
              <bitWidth>4</bitWidth>
            </field>
            <field>
              <name>TI3SEL</name>
              <bitOffset>16</bitOffset>
              <bitWidth>4</bitWidth>
            </field>
            <field>
              <name>TI4SEL</name>
              <bitOffset>24</bitOffset>
              <bitWidth>4</bitWidth>
            </field>
          </fields>
        </register>
      </registers>
    </peripheral>
    <peripheral>
      <name>TIM4</name>
      <baseAddress>0x40000800</baseAddress>
      <registers>
        <register>
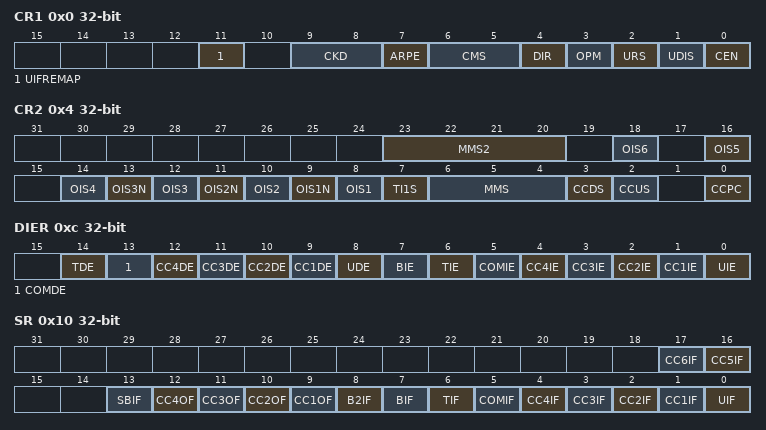
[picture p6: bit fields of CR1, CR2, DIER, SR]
          <name>CR1</name>
          <addressOffset>0x0</addressOffset>
          <size>0x20</size>
          <fields>
            <field>
              <name>CEN</name>
              <bitOffset>0</bitOffset>
              <bitWidth>1</bitWidth>
            </field>
            <field>
              <name>UDIS</name>
              <bitOffset>1</bitOffset>
              <bitWidth>1</bitWidth>
            </field>
            <field>
              <name>URS</name>
              <bitOffset>2</bitOffset>
              <bitWidth>1</bitWidth>
            </field>
            <field>
              <name>OPM</name>
              <bitOffset>3</bitOffset>
              <bitWidth>1</bitWidth>
            </field>
            <field>
              <name>DIR</name>
              <bitOffset>4</bitOffset>
              <bitWidth>1</bitWidth>
            </field>
            <field>
              <name>CMS</name>
              <bitOffset>5</bitOffset>
              <bitWidth>2</bitWidth>
            </field>
            <field>
              <name>ARPE</name>
              <bitOffset>7</bitOffset>
              <bitWidth>1</bitWidth>
            </field>
            <field>
              <name>CKD</name>
              <bitOffset>8</bitOffset>
              <bitWidth>2</bitWidth>
            </field>
            <field>
              <name>UIFREMAP</name>
              <bitOffset>11</bitOffset>
              <bitWidth>1</bitWidth>
            </field>
          </fields>
        </register>
        <register>
          <name>CR2</name>
          <addressOffset>0x4</addressOffset>
          <size>0x20</size>
          <fields>
            <field>
              <name>CCPC</name>
              <bitOffset>0</bitOffset>
              <bitWidth>1</bitWidth>
            </field>
            <field>
              <name>CCUS</name>
              <bitOffset>2</bitOffset>
              <bitWidth>1</bitWidth>
            </field>
            <field>
              <name>CCDS</name>
              <bitOffset>3</bitOffset>
              <bitWidth>1</bitWidth>
            </field>
            <field>
              <name>MMS</name>
              <bitOffset>4</bitOffset>
              <bitWidth>3</bitWidth>
            </field>
            <field>
              <name>TI1S</name>
              <bitOffset>7</bitOffset>
              <bitWidth>1</bitWidth>
            </field>
            <field>
              <name>OIS1</name>
              <bitOffset>8</bitOffset>
              <bitWidth>1</bitWidth>
            </field>
            <field>
              <name>OIS1N</name>
              <bitOffset>9</bitOffset>
              <bitWidth>1</bitWidth>
            </field>
            <field>
              <name>OIS2</name>
              <bitOffset>10</bitOffset>
              <bitWidth>1</bitWidth>
            </field>
            <field>
              <name>OIS2N</name>
              <bitOffset>11</bitOffset>
              <bitWidth>1</bitWidth>
            </field>
            <field>
              <name>OIS3</name>
              <bitOffset>12</bitOffset>
              <bitWidth>1</bitWidth>
            </field>
            <field>
              <name>OIS3N</name>
              <bitOffset>13</bitOffset>
              <bitWidth>1</bitWidth>
            </field>
            <field>
              <name>OIS4</name>
              <bitOffset>14</bitOffset>
              <bitWidth>1</bitWidth>
            </field>
            <field>
              <name>OIS5</name>
              <bitOffset>16</bitOffset>
              <bitWidth>1</bitWidth>
            </field>
            <field>
              <name>OIS6</name>
              <bitOffset>18</bitOffset>
              <bitWidth>1</bitWidth>
            </field>
            <field>
              <name>MMS2</name>
              <bitOffset>20</bitOffset>
              <bitWidth>4</bitWidth>
            </field>
          </fields>
        </register>
        <register>
          <name>SMCR</name>
          <addressOffset>0x8</addressOffset>
          <size>0x20</size>
          <fields>
            <field>
              <name>SMS</name>
              <bitOffset>0</bitOffset>
              <bitWidth>17</bitWidth>
            </field>
            <field>
              <name>TS</name>
              <bitOffset>4</bitOffset>
              <bitWidth>18</bitWidth>
            </field>
            <field>
              <name>MSM</name>
              <bitOffset>7</bitOffset>
              <bitWidth>1</bitWidth>
            </field>
            <field>
              <name>ETF</name>
              <bitOffset>8</bitOffset>
              <bitWidth>4</bitWidth>
            </field>
            <field>
              <name>ETPS</name>
              <bitOffset>12</bitOffset>
              <bitWidth>2</bitWidth>
            </field>
            <field>
              <name>ECE</name>
              <bitOffset>14</bitOffset>
              <bitWidth>1</bitWidth>
            </field>
            <field>
              <name>ETP</name>
              <bitOffset>15</bitOffset>
              <bitWidth>1</bitWidth>
            </field>
          </fields>
        </register>
        <register>
          <name>DIER</name>
          <addressOffset>0xc</addressOffset>
          <size>0x20</size>
          <fields>
            <field>
              <name>UIE</name>
              <bitOffset>0</bitOffset>
              <bitWidth>1</bitWidth>
            </field>
            <field>
              <name>CC1IE</name>
              <bitOffset>1</bitOffset>
              <bitWidth>1</bitWidth>
            </field>
            <field>
              <name>CC2IE</name>
              <bitOffset>2</bitOffset>
              <bitWidth>1</bitWidth>
            </field>
            <field>
              <name>CC3IE</name>
              <bitOffset>3</bitOffset>
              <bitWidth>1</bitWidth>
            </field>
            <field>
              <name>CC4IE</name>
              <bitOffset>4</bitOffset>
              <bitWidth>1</bitWidth>
            </field>
            <field>
              <name>COMIE</name>
              <bitOffset>5</bitOffset>
              <bitWidth>1</bitWidth>
            </field>
            <field>
              <name>TIE</name>
              <bitOffset>6</bitOffset>
              <bitWidth>1</bitWidth>
            </field>
            <field>
              <name>BIE</name>
              <bitOffset>7</bitOffset>
              <bitWidth>1</bitWidth>
            </field>
            <field>
              <name>UDE</name>
              <bitOffset>8</bitOffset>
              <bitWidth>1</bitWidth>
            </field>
            <field>
              <name>CC1DE</name>
              <bitOffset>9</bitOffset>
              <bitWidth>1</bitWidth>
            </field>
            <field>
              <name>CC2DE</name>
              <bitOffset>10</bitOffset>
              <bitWidth>1</bitWidth>
            </field>
            <field>
              <name>CC3DE</name>
              <bitOffset>11</bitOffset>
              <bitWidth>1</bitWidth>
            </field>
            <field>
              <name>CC4DE</name>
              <bitOffset>12</bitOffset>
              <bitWidth>1</bitWidth>
            </field>
            <field>
              <name>COMDE</name>
              <bitOffset>13</bitOffset>
              <bitWidth>1</bitWidth>
            </field>
            <field>
              <name>TDE</name>
              <bitOffset>14</bitOffset>
              <bitWidth>1</bitWidth>
            </field>
          </fields>
        </register>
        <register>
          <name>SR</name>
          <addressOffset>0x10</addressOffset>
          <size>0x20</size>
          <fields>
            <field>
              <name>UIF</name>
              <bitOffset>0</bitOffset>
              <bitWidth>1</bitWidth>
            </field>
            <field>
              <name>CC1IF</name>
              <bitOffset>1</bitOffset>
              <bitWidth>1</bitWidth>
            </field>
            <field>
              <name>CC2IF</name>
              <bitOffset>2</bitOffset>
              <bitWidth>1</bitWidth>
            </field>
            <field>
              <name>CC3IF</name>
              <bitOffset>3</bitOffset>
              <bitWidth>1</bitWidth>
            </field>
            <field>
              <name>CC4IF</name>
              <bitOffset>4</bitOffset>
              <bitWidth>1</bitWidth>
            </field>
            <field>
              <name>COMIF</name>
              <bitOffset>5</bitOffset>
              <bitWidth>1</bitWidth>
            </field>
            <field>
              <name>TIF</name>
              <bitOffset>6</bitOffset>
              <bitWidth>1</bitWidth>
            </field>
            <field>
              <name>BIF</name>
              <bitOffset>7</bitOffset>
              <bitWidth>1</bitWidth>
            </field>
            <field>
              <name>B2IF</name>
              <bitOffset>8</bitOffset>
              <bitWidth>1</bitWidth>
            </field>
            <field>
              <name>CC1OF</name>
              <bitOffset>9</bitOffset>
              <bitWidth>1</bitWidth>
            </field>
            <field>
              <name>CC2OF</name>
              <bitOffset>10</bitOffset>
              <bitWidth>1</bitWidth>
            </field>
            <field>
              <name>CC3OF</name>
              <bitOffset>11</bitOffset>
              <bitWidth>1</bitWidth>
            </field>
            <field>
              <name>CC4OF</name>
              <bitOffset>12</bitOffset>
              <bitWidth>1</bitWidth>
            </field>
            <field>
              <name>SBIF</name>
              <bitOffset>13</bitOffset>
              <bitWidth>1</bitWidth>
            </field>
            <field>
              <name>CC5IF</name>
              <bitOffset>16</bitOffset>
              <bitWidth>1</bitWidth>
            </field>
            <field>
              <name>CC6IF</name>
              <bitOffset>17</bitOffset>
              <bitWidth>1</bitWidth>
            </field>
          </fields>
        </register>
        <register>
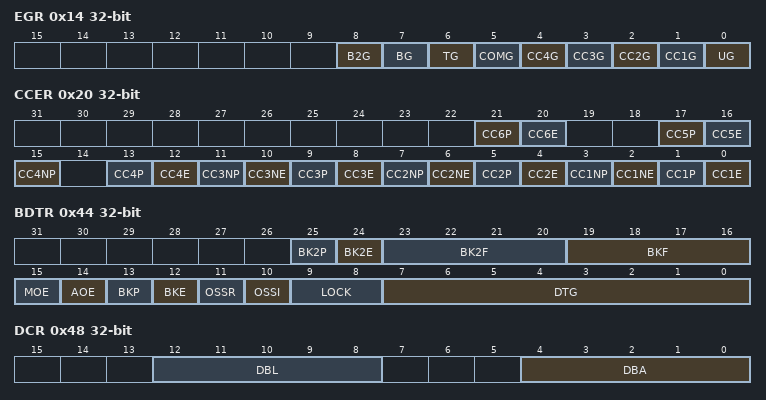
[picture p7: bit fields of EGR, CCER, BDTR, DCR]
          <name>EGR</name>
          <addressOffset>0x14</addressOffset>
          <size>0x20</size>
          <fields>
            <field>
              <name>UG</name>
              <bitOffset>0</bitOffset>
              <bitWidth>1</bitWidth>
            </field>
            <field>
              <name>CC1G</name>
              <bitOffset>1</bitOffset>
              <bitWidth>1</bitWidth>
            </field>
            <field>
              <name>CC2G</name>
              <bitOffset>2</bitOffset>
              <bitWidth>1</bitWidth>
            </field>
            <field>
              <name>CC3G</name>
              <bitOffset>3</bitOffset>
              <bitWidth>1</bitWidth>
            </field>
            <field>
              <name>CC4G</name>
              <bitOffset>4</bitOffset>
              <bitWidth>1</bitWidth>
            </field>
            <field>
              <name>COMG</name>
              <bitOffset>5</bitOffset>
              <bitWidth>1</bitWidth>
            </field>
            <field>
              <name>TG</name>
              <bitOffset>6</bitOffset>
              <bitWidth>1</bitWidth>
            </field>
            <field>
              <name>BG</name>
              <bitOffset>7</bitOffset>
              <bitWidth>1</bitWidth>
            </field>
            <field>
              <name>B2G</name>
              <bitOffset>8</bitOffset>
              <bitWidth>1</bitWidth>
            </field>
          </fields>
        </register>
        <register>
          <name>CCMR1</name>
          <addressOffset>0x18</addressOffset>
          <size>0x20</size>
          <fields>
            <field>
              <name>CC1S</name>
              <bitOffset>0</bitOffset>
              <bitWidth>2</bitWidth>
            </field>
            <field>
              <name>OC1FE</name>
              <bitOffset>2</bitOffset>
              <bitWidth>1</bitWidth>
            </field>
            <field>
              <name>OC1PE</name>
              <bitOffset>3</bitOffset>
              <bitWidth>1</bitWidth>
            </field>
            <field>
              <name>OC1M</name>
              <bitOffset>4</bitOffset>
              <bitWidth>13</bitWidth>
            </field>
            <field>
              <name>OC1CE</name>
              <bitOffset>7</bitOffset>
              <bitWidth>1</bitWidth>
            </field>
            <field>
              <name>CC2S</name>
              <bitOffset>8</bitOffset>
              <bitWidth>2</bitWidth>
            </field>
            <field>
              <name>OC2FE</name>
              <bitOffset>10</bitOffset>
              <bitWidth>1</bitWidth>
            </field>
            <field>
              <name>OC2PE</name>
              <bitOffset>11</bitOffset>
              <bitWidth>1</bitWidth>
            </field>
            <field>
              <name>OC2M</name>
              <bitOffset>12</bitOffset>
              <bitWidth>13</bitWidth>
            </field>
            <field>
              <name>OC2CE</name>
              <bitOffset>15</bitOffset>
              <bitWidth>1</bitWidth>
            </field>
          </fields>
        </register>
        <register>
          <name>CCMR2</name>
          <addressOffset>0x1c</addressOffset>
          <size>0x20</size>
          <fields>
            <field>
              <name>CC3S</name>
              <bitOffset>0</bitOffset>
              <bitWidth>2</bitWidth>
            </field>
            <field>
              <name>OC3FE</name>
              <bitOffset>2</bitOffset>
              <bitWidth>1</bitWidth>
            </field>
            <field>
              <name>OC3PE</name>
              <bitOffset>3</bitOffset>
              <bitWidth>1</bitWidth>
            </field>
            <field>
              <name>OC3M</name>
              <bitOffset>4</bitOffset>
              <bitWidth>13</bitWidth>
            </field>
            <field>
              <name>OC3CE</name>
              <bitOffset>7</bitOffset>
              <bitWidth>1</bitWidth>
            </field>
            <field>
              <name>CC4S</name>
              <bitOffset>8</bitOffset>
              <bitWidth>2</bitWidth>
            </field>
            <field>
              <name>OC4FE</name>
              <bitOffset>10</bitOffset>
              <bitWidth>1</bitWidth>
            </field>
            <field>
              <name>OC4PE</name>
              <bitOffset>11</bitOffset>
              <bitWidth>1</bitWidth>
            </field>
            <field>
              <name>OC4M</name>
              <bitOffset>12</bitOffset>
              <bitWidth>13</bitWidth>
            </field>
            <field>
              <name>OC4CE</name>
              <bitOffset>15</bitOffset>
              <bitWidth>1</bitWidth>
            </field>
          </fields>
        </register>
        <register>
          <name>CCER</name>
          <addressOffset>0x20</addressOffset>
          <size>0x20</size>
          <fields>
            <field>
              <name>CC1E</name>
              <bitOffset>0</bitOffset>
              <bitWidth>1</bitWidth>
            </field>
            <field>
              <name>CC1P</name>
              <bitOffset>1</bitOffset>
              <bitWidth>1</bitWidth>
            </field>
            <field>
              <name>CC1NE</name>
              <bitOffset>2</bitOffset>
              <bitWidth>1</bitWidth>
            </field>
            <field>
              <name>CC1NP</name>
              <bitOffset>3</bitOffset>
              <bitWidth>1</bitWidth>
            </field>
            <field>
              <name>CC2E</name>
              <bitOffset>4</bitOffset>
              <bitWidth>1</bitWidth>
            </field>
            <field>
              <name>CC2P</name>
              <bitOffset>5</bitOffset>
              <bitWidth>1</bitWidth>
            </field>
            <field>
              <name>CC2NE</name>
              <bitOffset>6</bitOffset>
              <bitWidth>1</bitWidth>
            </field>
            <field>
              <name>CC2NP</name>
              <bitOffset>7</bitOffset>
              <bitWidth>1</bitWidth>
            </field>
            <field>
              <name>CC3E</name>
              <bitOffset>8</bitOffset>
              <bitWidth>1</bitWidth>
            </field>
            <field>
              <name>CC3P</name>
              <bitOffset>9</bitOffset>
              <bitWidth>1</bitWidth>
            </field>
            <field>
              <name>CC3NE</name>
              <bitOffset>10</bitOffset>
              <bitWidth>1</bitWidth>
            </field>
            <field>
              <name>CC3NP</name>
              <bitOffset>11</bitOffset>
              <bitWidth>1</bitWidth>
            </field>
            <field>
              <name>CC4E</name>
              <bitOffset>12</bitOffset>
              <bitWidth>1</bitWidth>
            </field>
            <field>
              <name>CC4P</name>
              <bitOffset>13</bitOffset>
              <bitWidth>1</bitWidth>
            </field>
            <field>
              <name>CC4NP</name>
              <bitOffset>15</bitOffset>
              <bitWidth>1</bitWidth>
            </field>
            <field>
              <name>CC5E</name>
              <bitOffset>16</bitOffset>
              <bitWidth>1</bitWidth>
            </field>
            <field>
              <name>CC5P</name>
              <bitOffset>17</bitOffset>
              <bitWidth>1</bitWidth>
            </field>
            <field>
              <name>CC6E</name>
              <bitOffset>20</bitOffset>
              <bitWidth>1</bitWidth>
            </field>
            <field>
              <name>CC6P</name>
              <bitOffset>21</bitOffset>
              <bitWidth>1</bitWidth>
            </field>
          </fields>
        </register>
        <register>
          <name>CNT</name>
          <addressOffset>0x24</addressOffset>
          <size>0x20</size>
          <fields>
            <field>
              <name>CNT</name>
              <bitOffset>0</bitOffset>
              <bitWidth>32</bitWidth>
            </field>
            <field>
              <name>UIFCPY</name>
              <bitOffset>31</bitOffset>
              <bitWidth>1</bitWidth>
            </field>
          </fields>
        </register>
        <register>
          <name>PSC</name>
          <addressOffset>0x28</addressOffset>
          <size>0x20</size>
          <fields>
            <field>
              <name>PSC</name>
              <bitOffset>0</bitOffset>
              <bitWidth>16</bitWidth>
            </field>
          </fields>
        </register>
        <register>
          <name>ARR</name>
          <addressOffset>0x2c</addressOffset>
          <size>0x20</size>
          <fields>
            <field>
              <name>ARR</name>
              <bitOffset>0</bitOffset>
              <bitWidth>32</bitWidth>
            </field>
          </fields>
        </register>
        <register>
          <name>RCR</name>
          <addressOffset>0x30</addressOffset>
          <size>0x20</size>
          <fields>
            <field>
              <name>REP</name>
              <bitOffset>0</bitOffset>
              <bitWidth>8</bitWidth>
            </field>
          </fields>
        </register>
        <register>
          <name>CCR1</name>
          <addressOffset>0x34</addressOffset>
          <size>0x20</size>
          <fields>
            <field>
              <name>CCR1</name>
              <bitOffset>0</bitOffset>
              <bitWidth>16</bitWidth>
            </field>
          </fields>
        </register>
        <register>
          <name>CCR2</name>
          <addressOffset>0x38</addressOffset>
          <size>0x20</size>
          <fields>
            <field>
              <name>CCR2</name>
              <bitOffset>0</bitOffset>
              <bitWidth>16</bitWidth>
            </field>
          </fields>
        </register>
        <register>
          <name>CCR3</name>
          <addressOffset>0x3c</addressOffset>
          <size>0x20</size>
          <fields>
            <field>
              <name>CCR3</name>
              <bitOffset>0</bitOffset>
              <bitWidth>16</bitWidth>
            </field>
          </fields>
        </register>
        <register>
          <name>CCR4</name>
          <addressOffset>0x40</addressOffset>
          <size>0x20</size>
          <fields>
            <field>
              <name>CCR4</name>
              <bitOffset>0</bitOffset>
              <bitWidth>16</bitWidth>
            </field>
          </fields>
        </register>
        <register>
          <name>BDTR</name>
          <addressOffset>0x44</addressOffset>
          <size>0x20</size>
          <fields>
            <field>
              <name>DTG</name>
              <bitOffset>0</bitOffset>
              <bitWidth>8</bitWidth>
            </field>
            <field>
              <name>LOCK</name>
              <bitOffset>8</bitOffset>
              <bitWidth>2</bitWidth>
            </field>
            <field>
              <name>OSSI</name>
              <bitOffset>10</bitOffset>
              <bitWidth>1</bitWidth>
            </field>
            <field>
              <name>OSSR</name>
              <bitOffset>11</bitOffset>
              <bitWidth>1</bitWidth>
            </field>
            <field>
              <name>BKE</name>
              <bitOffset>12</bitOffset>
              <bitWidth>1</bitWidth>
            </field>
            <field>
              <name>BKP</name>
              <bitOffset>13</bitOffset>
              <bitWidth>1</bitWidth>
            </field>
            <field>
              <name>AOE</name>
              <bitOffset>14</bitOffset>
              <bitWidth>1</bitWidth>
            </field>
            <field>
              <name>MOE</name>
              <bitOffset>15</bitOffset>
              <bitWidth>1</bitWidth>
            </field>
            <field>
              <name>BKF</name>
              <bitOffset>16</bitOffset>
              <bitWidth>4</bitWidth>
            </field>
            <field>
              <name>BK2F</name>
              <bitOffset>20</bitOffset>
              <bitWidth>4</bitWidth>
            </field>
            <field>
              <name>BK2E</name>
              <bitOffset>24</bitOffset>
              <bitWidth>1</bitWidth>
            </field>
            <field>
              <name>BK2P</name>
              <bitOffset>25</bitOffset>
              <bitWidth>1</bitWidth>
            </field>
          </fields>
        </register>
        <register>
          <name>DCR</name>
          <addressOffset>0x48</addressOffset>
          <size>0x20</size>
          <fields>
            <field>
              <name>DBA</name>
              <bitOffset>0</bitOffset>
              <bitWidth>5</bitWidth>
            </field>
            <field>
              <name>DBL</name>
              <bitOffset>8</bitOffset>
              <bitWidth>5</bitWidth>
            </field>
          </fields>
        </register>
        <register>
          <name>DMAR</name>
          <addressOffset>0x4c</addressOffset>
          <size>0x20</size>
          <fields>
            <field>
              <name>DMAB</name>
              <bitOffset>0</bitOffset>
              <bitWidth>16</bitWidth>
            </field>
          </fields>
        </register>
        <register>
          <name>CCMR3</name>
          <addressOffset>0x54</addressOffset>
          <size>0x20</size>
          <fields>
            <field>
              <name>OC5FE</name>
              <bitOffset>2</bitOffset>
              <bitWidth>1</bitWidth>
            </field>
            <field>
              <name>OC5PE</name>
              <bitOffset>3</bitOffset>
              <bitWidth>1</bitWidth>
            </field>
            <field>
              <name>OC5M</name>
              <bitOffset>4</bitOffset>
              <bitWidth>13</bitWidth>
            </field>
            <field>
              <name>OC5CE</name>
              <bitOffset>7</bitOffset>
              <bitWidth>1</bitWidth>
            </field>
            <field>
              <name>OC6FE</name>
              <bitOffset>10</bitOffset>
              <bitWidth>1</bitWidth>
            </field>
            <field>
              <name>OC6PE</name>
              <bitOffset>11</bitOffset>
              <bitWidth>1</bitWidth>
            </field>
            <field>
              <name>OC6M</name>
              <bitOffset>12</bitOffset>
              <bitWidth>13</bitWidth>
            </field>
            <field>
              <name>OC6CE</name>
              <bitOffset>15</bitOffset>
              <bitWidth>1</bitWidth>
            </field>
          </fields>
        </register>
        <register>
          <name>CCR5</name>
          <addressOffset>0x58</addressOffset>
          <size>0x20</size>
          <fields>
            <field>
              <name>CCR5</name>
              <bitOffset>0</bitOffset>
              <bitWidth>32</bitWidth>
            </field>
            <field>
              <name>GC5C1</name>
              <bitOffset>29</bitOffset>
              <bitWidth>1</bitWidth>
            </field>
            <field>
              <name>GC5C2</name>
              <bitOffset>30</bitOffset>
              <bitWidth>1</bitWidth>
            </field>
            <field>
              <name>GC5C3</name>
              <bitOffset>31</bitOffset>
              <bitWidth>1</bitWidth>
            </field>
          </fields>
        </register>
        <register>
          <name>CCR6</name>
          <addressOffset>0x5c</addressOffset>
          <size>0x20</size>
          <fields>
            <field>
              <name>CCR6</name>
              <bitOffset>0</bitOffset>
              <bitWidth>16</bitWidth>
            </field>
          </fields>
        </register>
        <register>
          <name>AF1</name>
          <addressOffset>0x60</addressOffset>
          <size>0x20</size>
        </register>
        <register>
          <name>AF2</name>
          <addressOffset>0x64</addressOffset>
          <size>0x20</size>
        </register>
        <register>
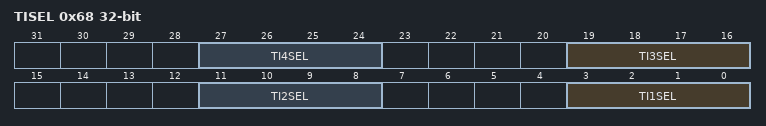
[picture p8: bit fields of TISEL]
          <name>TISEL</name>
          <addressOffset>0x68</addressOffset>
          <size>0x20</size>
          <fields>
            <field>
              <name>TI1SEL</name>
              <bitOffset>0</bitOffset>
              <bitWidth>4</bitWidth>
            </field>
            <field>
              <name>TI2SEL</name>
              <bitOffset>8</bitOffset>
              <bitWidth>4</bitWidth>
            </field>
            <field>
              <name>TI3SEL</name>
              <bitOffset>16</bitOffset>
              <bitWidth>4</bitWidth>
            </field>
            <field>
              <name>TI4SEL</name>
              <bitOffset>24</bitOffset>
              <bitWidth>4</bitWidth>
            </field>
          </fields>
        </register>
      </registers>
    </peripheral>
    <peripheral>
      <name>TIM5</name>
      <baseAddress>0x40000c00</baseAddress>
      <registers>
        <register>
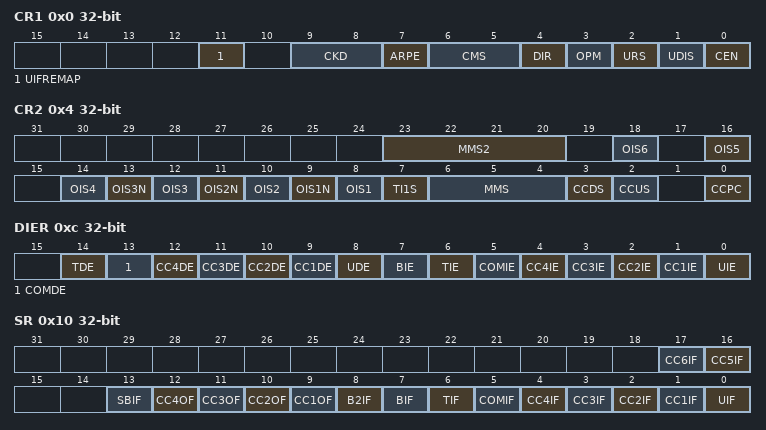
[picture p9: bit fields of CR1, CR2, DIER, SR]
          <name>CR1</name>
          <addressOffset>0x0</addressOffset>
          <size>0x20</size>
          <fields>
            <field>
              <name>CEN</name>
              <bitOffset>0</bitOffset>
              <bitWidth>1</bitWidth>
            </field>
            <field>
              <name>UDIS</name>
              <bitOffset>1</bitOffset>
              <bitWidth>1</bitWidth>
            </field>
            <field>
              <name>URS</name>
              <bitOffset>2</bitOffset>
              <bitWidth>1</bitWidth>
            </field>
            <field>
              <name>OPM</name>
              <bitOffset>3</bitOffset>
              <bitWidth>1</bitWidth>
            </field>
            <field>
              <name>DIR</name>
              <bitOffset>4</bitOffset>
              <bitWidth>1</bitWidth>
            </field>
            <field>
              <name>CMS</name>
              <bitOffset>5</bitOffset>
              <bitWidth>2</bitWidth>
            </field>
            <field>
              <name>ARPE</name>
              <bitOffset>7</bitOffset>
              <bitWidth>1</bitWidth>
            </field>
            <field>
              <name>CKD</name>
              <bitOffset>8</bitOffset>
              <bitWidth>2</bitWidth>
            </field>
            <field>
              <name>UIFREMAP</name>
              <bitOffset>11</bitOffset>
              <bitWidth>1</bitWidth>
            </field>
          </fields>
        </register>
        <register>
          <name>CR2</name>
          <addressOffset>0x4</addressOffset>
          <size>0x20</size>
          <fields>
            <field>
              <name>CCPC</name>
              <bitOffset>0</bitOffset>
              <bitWidth>1</bitWidth>
            </field>
            <field>
              <name>CCUS</name>
              <bitOffset>2</bitOffset>
              <bitWidth>1</bitWidth>
            </field>
            <field>
              <name>CCDS</name>
              <bitOffset>3</bitOffset>
              <bitWidth>1</bitWidth>
            </field>
            <field>
              <name>MMS</name>
              <bitOffset>4</bitOffset>
              <bitWidth>3</bitWidth>
            </field>
            <field>
              <name>TI1S</name>
              <bitOffset>7</bitOffset>
              <bitWidth>1</bitWidth>
            </field>
            <field>
              <name>OIS1</name>
              <bitOffset>8</bitOffset>
              <bitWidth>1</bitWidth>
            </field>
            <field>
              <name>OIS1N</name>
              <bitOffset>9</bitOffset>
              <bitWidth>1</bitWidth>
            </field>
            <field>
              <name>OIS2</name>
              <bitOffset>10</bitOffset>
              <bitWidth>1</bitWidth>
            </field>
            <field>
              <name>OIS2N</name>
              <bitOffset>11</bitOffset>
              <bitWidth>1</bitWidth>
            </field>
            <field>
              <name>OIS3</name>
              <bitOffset>12</bitOffset>
              <bitWidth>1</bitWidth>
            </field>
            <field>
              <name>OIS3N</name>
              <bitOffset>13</bitOffset>
              <bitWidth>1</bitWidth>
            </field>
            <field>
              <name>OIS4</name>
              <bitOffset>14</bitOffset>
              <bitWidth>1</bitWidth>
            </field>
            <field>
              <name>OIS5</name>
              <bitOffset>16</bitOffset>
              <bitWidth>1</bitWidth>
            </field>
            <field>
              <name>OIS6</name>
              <bitOffset>18</bitOffset>
              <bitWidth>1</bitWidth>
            </field>
            <field>
              <name>MMS2</name>
              <bitOffset>20</bitOffset>
              <bitWidth>4</bitWidth>
            </field>
          </fields>
        </register>
        <register>
          <name>SMCR</name>
          <addressOffset>0x8</addressOffset>
          <size>0x20</size>
          <fields>
            <field>
              <name>SMS</name>
              <bitOffset>0</bitOffset>
              <bitWidth>17</bitWidth>
            </field>
            <field>
              <name>TS</name>
              <bitOffset>4</bitOffset>
              <bitWidth>18</bitWidth>
            </field>
            <field>
              <name>MSM</name>
              <bitOffset>7</bitOffset>
              <bitWidth>1</bitWidth>
            </field>
            <field>
              <name>ETF</name>
              <bitOffset>8</bitOffset>
              <bitWidth>4</bitWidth>
            </field>
            <field>
              <name>ETPS</name>
              <bitOffset>12</bitOffset>
              <bitWidth>2</bitWidth>
            </field>
            <field>
              <name>ECE</name>
              <bitOffset>14</bitOffset>
              <bitWidth>1</bitWidth>
            </field>
            <field>
              <name>ETP</name>
              <bitOffset>15</bitOffset>
              <bitWidth>1</bitWidth>
            </field>
          </fields>
        </register>
        <register>
          <name>DIER</name>
          <addressOffset>0xc</addressOffset>
          <size>0x20</size>
          <fields>
            <field>
              <name>UIE</name>
              <bitOffset>0</bitOffset>
              <bitWidth>1</bitWidth>
            </field>
            <field>
              <name>CC1IE</name>
              <bitOffset>1</bitOffset>
              <bitWidth>1</bitWidth>
            </field>
            <field>
              <name>CC2IE</name>
              <bitOffset>2</bitOffset>
              <bitWidth>1</bitWidth>
            </field>
            <field>
              <name>CC3IE</name>
              <bitOffset>3</bitOffset>
              <bitWidth>1</bitWidth>
            </field>
            <field>
              <name>CC4IE</name>
              <bitOffset>4</bitOffset>
              <bitWidth>1</bitWidth>
            </field>
            <field>
              <name>COMIE</name>
              <bitOffset>5</bitOffset>
              <bitWidth>1</bitWidth>
            </field>
            <field>
              <name>TIE</name>
              <bitOffset>6</bitOffset>
              <bitWidth>1</bitWidth>
            </field>
            <field>
              <name>BIE</name>
              <bitOffset>7</bitOffset>
              <bitWidth>1</bitWidth>
            </field>
            <field>
              <name>UDE</name>
              <bitOffset>8</bitOffset>
              <bitWidth>1</bitWidth>
            </field>
            <field>
              <name>CC1DE</name>
              <bitOffset>9</bitOffset>
              <bitWidth>1</bitWidth>
            </field>
            <field>
              <name>CC2DE</name>
              <bitOffset>10</bitOffset>
              <bitWidth>1</bitWidth>
            </field>
            <field>
              <name>CC3DE</name>
              <bitOffset>11</bitOffset>
              <bitWidth>1</bitWidth>
            </field>
            <field>
              <name>CC4DE</name>
              <bitOffset>12</bitOffset>
              <bitWidth>1</bitWidth>
            </field>
            <field>
              <name>COMDE</name>
              <bitOffset>13</bitOffset>
              <bitWidth>1</bitWidth>
            </field>
            <field>
              <name>TDE</name>
              <bitOffset>14</bitOffset>
              <bitWidth>1</bitWidth>
            </field>
          </fields>
        </register>
        <register>
          <name>SR</name>
          <addressOffset>0x10</addressOffset>
          <size>0x20</size>
          <fields>
            <field>
              <name>UIF</name>
              <bitOffset>0</bitOffset>
              <bitWidth>1</bitWidth>
            </field>
            <field>
              <name>CC1IF</name>
              <bitOffset>1</bitOffset>
              <bitWidth>1</bitWidth>
            </field>
            <field>
              <name>CC2IF</name>
              <bitOffset>2</bitOffset>
              <bitWidth>1</bitWidth>
            </field>
            <field>
              <name>CC3IF</name>
              <bitOffset>3</bitOffset>
              <bitWidth>1</bitWidth>
            </field>
            <field>
              <name>CC4IF</name>
              <bitOffset>4</bitOffset>
              <bitWidth>1</bitWidth>
            </field>
            <field>
              <name>COMIF</name>
              <bitOffset>5</bitOffset>
              <bitWidth>1</bitWidth>
            </field>
            <field>
              <name>TIF</name>
              <bitOffset>6</bitOffset>
              <bitWidth>1</bitWidth>
            </field>
            <field>
              <name>BIF</name>
              <bitOffset>7</bitOffset>
              <bitWidth>1</bitWidth>
            </field>
            <field>
              <name>B2IF</name>
              <bitOffset>8</bitOffset>
              <bitWidth>1</bitWidth>
            </field>
            <field>
              <name>CC1OF</name>
              <bitOffset>9</bitOffset>
              <bitWidth>1</bitWidth>
            </field>
            <field>
              <name>CC2OF</name>
              <bitOffset>10</bitOffset>
              <bitWidth>1</bitWidth>
            </field>
            <field>
              <name>CC3OF</name>
              <bitOffset>11</bitOffset>
              <bitWidth>1</bitWidth>
            </field>
            <field>
              <name>CC4OF</name>
              <bitOffset>12</bitOffset>
              <bitWidth>1</bitWidth>
            </field>
            <field>
              <name>SBIF</name>
              <bitOffset>13</bitOffset>
              <bitWidth>1</bitWidth>
            </field>
            <field>
              <name>CC5IF</name>
              <bitOffset>16</bitOffset>
              <bitWidth>1</bitWidth>
            </field>
            <field>
              <name>CC6IF</name>
              <bitOffset>17</bitOffset>
              <bitWidth>1</bitWidth>
            </field>
          </fields>
        </register>
        <register>
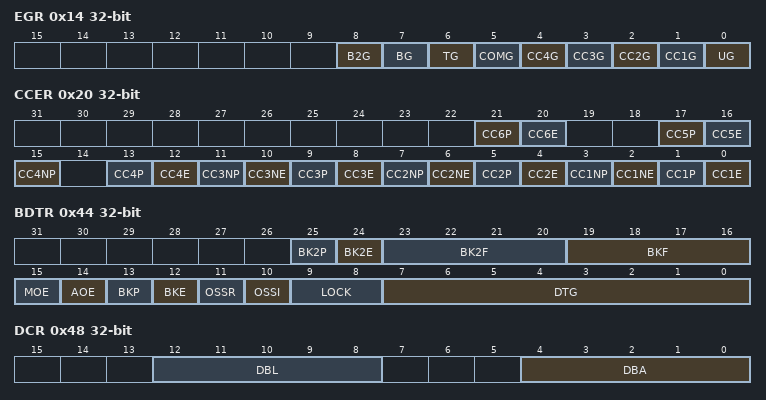
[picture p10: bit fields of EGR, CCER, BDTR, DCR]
          <name>EGR</name>
          <addressOffset>0x14</addressOffset>
          <size>0x20</size>
          <fields>
            <field>
              <name>UG</name>
              <bitOffset>0</bitOffset>
              <bitWidth>1</bitWidth>
            </field>
            <field>
              <name>CC1G</name>
              <bitOffset>1</bitOffset>
              <bitWidth>1</bitWidth>
            </field>
            <field>
              <name>CC2G</name>
              <bitOffset>2</bitOffset>
              <bitWidth>1</bitWidth>
            </field>
            <field>
              <name>CC3G</name>
              <bitOffset>3</bitOffset>
              <bitWidth>1</bitWidth>
            </field>
            <field>
              <name>CC4G</name>
              <bitOffset>4</bitOffset>
              <bitWidth>1</bitWidth>
            </field>
            <field>
              <name>COMG</name>
              <bitOffset>5</bitOffset>
              <bitWidth>1</bitWidth>
            </field>
            <field>
              <name>TG</name>
              <bitOffset>6</bitOffset>
              <bitWidth>1</bitWidth>
            </field>
            <field>
              <name>BG</name>
              <bitOffset>7</bitOffset>
              <bitWidth>1</bitWidth>
            </field>
            <field>
              <name>B2G</name>
              <bitOffset>8</bitOffset>
              <bitWidth>1</bitWidth>
            </field>
          </fields>
        </register>
        <register>
          <name>CCMR1</name>
          <addressOffset>0x18</addressOffset>
          <size>0x20</size>
          <fields>
            <field>
              <name>CC1S</name>
              <bitOffset>0</bitOffset>
              <bitWidth>2</bitWidth>
            </field>
            <field>
              <name>OC1FE</name>
              <bitOffset>2</bitOffset>
              <bitWidth>1</bitWidth>
            </field>
            <field>
              <name>OC1PE</name>
              <bitOffset>3</bitOffset>
              <bitWidth>1</bitWidth>
            </field>
            <field>
              <name>OC1M</name>
              <bitOffset>4</bitOffset>
              <bitWidth>13</bitWidth>
            </field>
            <field>
              <name>OC1CE</name>
              <bitOffset>7</bitOffset>
              <bitWidth>1</bitWidth>
            </field>
            <field>
              <name>CC2S</name>
              <bitOffset>8</bitOffset>
              <bitWidth>2</bitWidth>
            </field>
            <field>
              <name>OC2FE</name>
              <bitOffset>10</bitOffset>
              <bitWidth>1</bitWidth>
            </field>
            <field>
              <name>OC2PE</name>
              <bitOffset>11</bitOffset>
              <bitWidth>1</bitWidth>
            </field>
            <field>
              <name>OC2M</name>
              <bitOffset>12</bitOffset>
              <bitWidth>13</bitWidth>
            </field>
            <field>
              <name>OC2CE</name>
              <bitOffset>15</bitOffset>
              <bitWidth>1</bitWidth>
            </field>
          </fields>
        </register>
        <register>
          <name>CCMR2</name>
          <addressOffset>0x1c</addressOffset>
          <size>0x20</size>
          <fields>
            <field>
              <name>CC3S</name>
              <bitOffset>0</bitOffset>
              <bitWidth>2</bitWidth>
            </field>
            <field>
              <name>OC3FE</name>
              <bitOffset>2</bitOffset>
              <bitWidth>1</bitWidth>
            </field>
            <field>
              <name>OC3PE</name>
              <bitOffset>3</bitOffset>
              <bitWidth>1</bitWidth>
            </field>
            <field>
              <name>OC3M</name>
              <bitOffset>4</bitOffset>
              <bitWidth>13</bitWidth>
            </field>
            <field>
              <name>OC3CE</name>
              <bitOffset>7</bitOffset>
              <bitWidth>1</bitWidth>
            </field>
            <field>
              <name>CC4S</name>
              <bitOffset>8</bitOffset>
              <bitWidth>2</bitWidth>
            </field>
            <field>
              <name>OC4FE</name>
              <bitOffset>10</bitOffset>
              <bitWidth>1</bitWidth>
            </field>
            <field>
              <name>OC4PE</name>
              <bitOffset>11</bitOffset>
              <bitWidth>1</bitWidth>
            </field>
            <field>
              <name>OC4M</name>
              <bitOffset>12</bitOffset>
              <bitWidth>13</bitWidth>
            </field>
            <field>
              <name>OC4CE</name>
              <bitOffset>15</bitOffset>
              <bitWidth>1</bitWidth>
            </field>
          </fields>
        </register>
        <register>
          <name>CCER</name>
          <addressOffset>0x20</addressOffset>
          <size>0x20</size>
          <fields>
            <field>
              <name>CC1E</name>
              <bitOffset>0</bitOffset>
              <bitWidth>1</bitWidth>
            </field>
            <field>
              <name>CC1P</name>
              <bitOffset>1</bitOffset>
              <bitWidth>1</bitWidth>
            </field>
            <field>
              <name>CC1NE</name>
              <bitOffset>2</bitOffset>
              <bitWidth>1</bitWidth>
            </field>
            <field>
              <name>CC1NP</name>
              <bitOffset>3</bitOffset>
              <bitWidth>1</bitWidth>
            </field>
            <field>
              <name>CC2E</name>
              <bitOffset>4</bitOffset>
              <bitWidth>1</bitWidth>
            </field>
            <field>
              <name>CC2P</name>
              <bitOffset>5</bitOffset>
              <bitWidth>1</bitWidth>
            </field>
            <field>
              <name>CC2NE</name>
              <bitOffset>6</bitOffset>
              <bitWidth>1</bitWidth>
            </field>
            <field>
              <name>CC2NP</name>
              <bitOffset>7</bitOffset>
              <bitWidth>1</bitWidth>
            </field>
            <field>
              <name>CC3E</name>
              <bitOffset>8</bitOffset>
              <bitWidth>1</bitWidth>
            </field>
            <field>
              <name>CC3P</name>
              <bitOffset>9</bitOffset>
              <bitWidth>1</bitWidth>
            </field>
            <field>
              <name>CC3NE</name>
              <bitOffset>10</bitOffset>
              <bitWidth>1</bitWidth>
            </field>
            <field>
              <name>CC3NP</name>
              <bitOffset>11</bitOffset>
              <bitWidth>1</bitWidth>
            </field>
            <field>
              <name>CC4E</name>
              <bitOffset>12</bitOffset>
              <bitWidth>1</bitWidth>
            </field>
            <field>
              <name>CC4P</name>
              <bitOffset>13</bitOffset>
              <bitWidth>1</bitWidth>
            </field>
            <field>
              <name>CC4NP</name>
              <bitOffset>15</bitOffset>
              <bitWidth>1</bitWidth>
            </field>
            <field>
              <name>CC5E</name>
              <bitOffset>16</bitOffset>
              <bitWidth>1</bitWidth>
            </field>
            <field>
              <name>CC5P</name>
              <bitOffset>17</bitOffset>
              <bitWidth>1</bitWidth>
            </field>
            <field>
              <name>CC6E</name>
              <bitOffset>20</bitOffset>
              <bitWidth>1</bitWidth>
            </field>
            <field>
              <name>CC6P</name>
              <bitOffset>21</bitOffset>
              <bitWidth>1</bitWidth>
            </field>
          </fields>
        </register>
        <register>
          <name>CNT</name>
          <addressOffset>0x24</addressOffset>
          <size>0x20</size>
          <fields>
            <field>
              <name>CNT</name>
              <bitOffset>0</bitOffset>
              <bitWidth>32</bitWidth>
            </field>
            <field>
              <name>UIFCPY</name>
              <bitOffset>31</bitOffset>
              <bitWidth>1</bitWidth>
            </field>
          </fields>
        </register>
        <register>
          <name>PSC</name>
          <addressOffset>0x28</addressOffset>
          <size>0x20</size>
          <fields>
            <field>
              <name>PSC</name>
              <bitOffset>0</bitOffset>
              <bitWidth>16</bitWidth>
            </field>
          </fields>
        </register>
        <register>
          <name>ARR</name>
          <addressOffset>0x2c</addressOffset>
          <size>0x20</size>
          <fields>
            <field>
              <name>ARR</name>
              <bitOffset>0</bitOffset>
              <bitWidth>32</bitWidth>
            </field>
          </fields>
        </register>
        <register>
          <name>RCR</name>
          <addressOffset>0x30</addressOffset>
          <size>0x20</size>
          <fields>
            <field>
              <name>REP</name>
              <bitOffset>0</bitOffset>
              <bitWidth>8</bitWidth>
            </field>
          </fields>
        </register>
        <register>
          <name>CCR1</name>
          <addressOffset>0x34</addressOffset>
          <size>0x20</size>
          <fields>
            <field>
              <name>CCR1</name>
              <bitOffset>0</bitOffset>
              <bitWidth>16</bitWidth>
            </field>
          </fields>
        </register>
        <register>
          <name>CCR2</name>
          <addressOffset>0x38</addressOffset>
          <size>0x20</size>
          <fields>
            <field>
              <name>CCR2</name>
              <bitOffset>0</bitOffset>
              <bitWidth>16</bitWidth>
            </field>
          </fields>
        </register>
        <register>
          <name>CCR3</name>
          <addressOffset>0x3c</addressOffset>
          <size>0x20</size>
          <fields>
            <field>
              <name>CCR3</name>
              <bitOffset>0</bitOffset>
              <bitWidth>16</bitWidth>
            </field>
          </fields>
        </register>
        <register>
          <name>CCR4</name>
          <addressOffset>0x40</addressOffset>
          <size>0x20</size>
          <fields>
            <field>
              <name>CCR4</name>
              <bitOffset>0</bitOffset>
              <bitWidth>16</bitWidth>
            </field>
          </fields>
        </register>
        <register>
          <name>BDTR</name>
          <addressOffset>0x44</addressOffset>
          <size>0x20</size>
          <fields>
            <field>
              <name>DTG</name>
              <bitOffset>0</bitOffset>
              <bitWidth>8</bitWidth>
            </field>
            <field>
              <name>LOCK</name>
              <bitOffset>8</bitOffset>
              <bitWidth>2</bitWidth>
            </field>
            <field>
              <name>OSSI</name>
              <bitOffset>10</bitOffset>
              <bitWidth>1</bitWidth>
            </field>
            <field>
              <name>OSSR</name>
              <bitOffset>11</bitOffset>
              <bitWidth>1</bitWidth>
            </field>
            <field>
              <name>BKE</name>
              <bitOffset>12</bitOffset>
              <bitWidth>1</bitWidth>
            </field>
            <field>
              <name>BKP</name>
              <bitOffset>13</bitOffset>
              <bitWidth>1</bitWidth>
            </field>
            <field>
              <name>AOE</name>
              <bitOffset>14</bitOffset>
              <bitWidth>1</bitWidth>
            </field>
            <field>
              <name>MOE</name>
              <bitOffset>15</bitOffset>
              <bitWidth>1</bitWidth>
            </field>
            <field>
              <name>BKF</name>
              <bitOffset>16</bitOffset>
              <bitWidth>4</bitWidth>
            </field>
            <field>
              <name>BK2F</name>
              <bitOffset>20</bitOffset>
              <bitWidth>4</bitWidth>
            </field>
            <field>
              <name>BK2E</name>
              <bitOffset>24</bitOffset>
              <bitWidth>1</bitWidth>
            </field>
            <field>
              <name>BK2P</name>
              <bitOffset>25</bitOffset>
              <bitWidth>1</bitWidth>
            </field>
          </fields>
        </register>
        <register>
          <name>DCR</name>
          <addressOffset>0x48</addressOffset>
          <size>0x20</size>
          <fields>
            <field>
              <name>DBA</name>
              <bitOffset>0</bitOffset>
              <bitWidth>5</bitWidth>
            </field>
            <field>
              <name>DBL</name>
              <bitOffset>8</bitOffset>
              <bitWidth>5</bitWidth>
            </field>
          </fields>
        </register>
        <register>
          <name>DMAR</name>
          <addressOffset>0x4c</addressOffset>
          <size>0x20</size>
          <fields>
            <field>
              <name>DMAB</name>
              <bitOffset>0</bitOffset>
              <bitWidth>16</bitWidth>
            </field>
          </fields>
        </register>
        <register>
          <name>CCMR3</name>
          <addressOffset>0x54</addressOffset>
          <size>0x20</size>
          <fields>
            <field>
              <name>OC5FE</name>
              <bitOffset>2</bitOffset>
              <bitWidth>1</bitWidth>
            </field>
            <field>
              <name>OC5PE</name>
              <bitOffset>3</bitOffset>
              <bitWidth>1</bitWidth>
            </field>
            <field>
              <name>OC5M</name>
              <bitOffset>4</bitOffset>
              <bitWidth>13</bitWidth>
            </field>
            <field>
              <name>OC5CE</name>
              <bitOffset>7</bitOffset>
              <bitWidth>1</bitWidth>
            </field>
            <field>
              <name>OC6FE</name>
              <bitOffset>10</bitOffset>
              <bitWidth>1</bitWidth>
            </field>
            <field>
              <name>OC6PE</name>
              <bitOffset>11</bitOffset>
              <bitWidth>1</bitWidth>
            </field>
            <field>
              <name>OC6M</name>
              <bitOffset>12</bitOffset>
              <bitWidth>13</bitWidth>
            </field>
            <field>
              <name>OC6CE</name>
              <bitOffset>15</bitOffset>
              <bitWidth>1</bitWidth>
            </field>
          </fields>
        </register>
        <register>
          <name>CCR5</name>
          <addressOffset>0x58</addressOffset>
          <size>0x20</size>
          <fields>
            <field>
              <name>CCR5</name>
              <bitOffset>0</bitOffset>
              <bitWidth>32</bitWidth>
            </field>
            <field>
              <name>GC5C1</name>
              <bitOffset>29</bitOffset>
              <bitWidth>1</bitWidth>
            </field>
            <field>
              <name>GC5C2</name>
              <bitOffset>30</bitOffset>
              <bitWidth>1</bitWidth>
            </field>
            <field>
              <name>GC5C3</name>
              <bitOffset>31</bitOffset>
              <bitWidth>1</bitWidth>
            </field>
          </fields>
        </register>
        <register>
          <name>CCR6</name>
          <addressOffset>0x5c</addressOffset>
          <size>0x20</size>
          <fields>
            <field>
              <name>CCR6</name>
              <bitOffset>0</bitOffset>
              <bitWidth>16</bitWidth>
            </field>
          </fields>
        </register>
        <register>
          <name>AF1</name>
          <addressOffset>0x60</addressOffset>
          <size>0x20</size>
        </register>
        <register>
          <name>AF2</name>
          <addressOffset>0x64</addressOffset>
          <size>0x20</size>
        </register>
        <register>
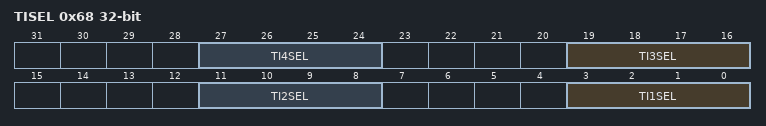
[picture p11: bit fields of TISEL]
          <name>TISEL</name>
          <addressOffset>0x68</addressOffset>
          <size>0x20</size>
          <fields>
            <field>
              <name>TI1SEL</name>
              <bitOffset>0</bitOffset>
              <bitWidth>4</bitWidth>
            </field>
            <field>
              <name>TI2SEL</name>
              <bitOffset>8</bitOffset>
              <bitWidth>4</bitWidth>
            </field>
            <field>
              <name>TI3SEL</name>
              <bitOffset>16</bitOffset>
              <bitWidth>4</bitWidth>
            </field>
            <field>
              <name>TI4SEL</name>
              <bitOffset>24</bitOffset>
              <bitWidth>4</bitWidth>
            </field>
          </fields>
        </register>
      </registers>
    </peripheral>
    <peripheral>
      <name>TIM6</name>
      <baseAddress>0x40001000</baseAddress>
      <registers>
        <register>
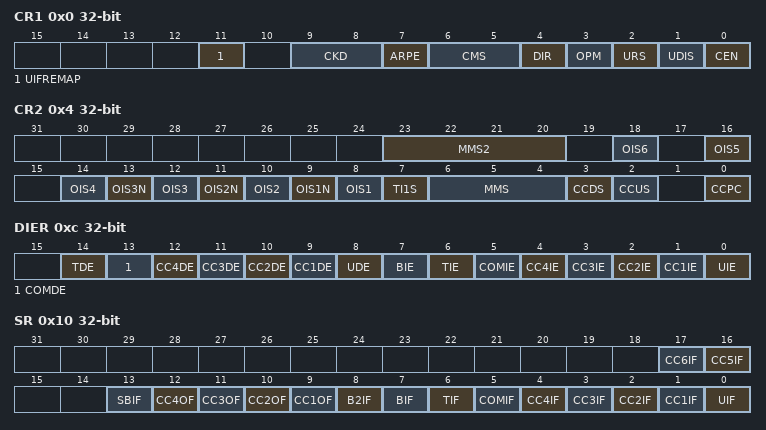
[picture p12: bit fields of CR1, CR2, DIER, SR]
          <name>CR1</name>
          <addressOffset>0x0</addressOffset>
          <size>0x20</size>
          <fields>
            <field>
              <name>CEN</name>
              <bitOffset>0</bitOffset>
              <bitWidth>1</bitWidth>
            </field>
            <field>
              <name>UDIS</name>
              <bitOffset>1</bitOffset>
              <bitWidth>1</bitWidth>
            </field>
            <field>
              <name>URS</name>
              <bitOffset>2</bitOffset>
              <bitWidth>1</bitWidth>
            </field>
            <field>
              <name>OPM</name>
              <bitOffset>3</bitOffset>
              <bitWidth>1</bitWidth>
            </field>
            <field>
              <name>DIR</name>
              <bitOffset>4</bitOffset>
              <bitWidth>1</bitWidth>
            </field>
            <field>
              <name>CMS</name>
              <bitOffset>5</bitOffset>
              <bitWidth>2</bitWidth>
            </field>
            <field>
              <name>ARPE</name>
              <bitOffset>7</bitOffset>
              <bitWidth>1</bitWidth>
            </field>
            <field>
              <name>CKD</name>
              <bitOffset>8</bitOffset>
              <bitWidth>2</bitWidth>
            </field>
            <field>
              <name>UIFREMAP</name>
              <bitOffset>11</bitOffset>
              <bitWidth>1</bitWidth>
            </field>
          </fields>
        </register>
        <register>
          <name>CR2</name>
          <addressOffset>0x4</addressOffset>
          <size>0x20</size>
          <fields>
            <field>
              <name>CCPC</name>
              <bitOffset>0</bitOffset>
              <bitWidth>1</bitWidth>
            </field>
            <field>
              <name>CCUS</name>
              <bitOffset>2</bitOffset>
              <bitWidth>1</bitWidth>
            </field>
            <field>
              <name>CCDS</name>
              <bitOffset>3</bitOffset>
              <bitWidth>1</bitWidth>
            </field>
            <field>
              <name>MMS</name>
              <bitOffset>4</bitOffset>
              <bitWidth>3</bitWidth>
            </field>
            <field>
              <name>TI1S</name>
              <bitOffset>7</bitOffset>
              <bitWidth>1</bitWidth>
            </field>
            <field>
              <name>OIS1</name>
              <bitOffset>8</bitOffset>
              <bitWidth>1</bitWidth>
            </field>
            <field>
              <name>OIS1N</name>
              <bitOffset>9</bitOffset>
              <bitWidth>1</bitWidth>
            </field>
            <field>
              <name>OIS2</name>
              <bitOffset>10</bitOffset>
              <bitWidth>1</bitWidth>
            </field>
            <field>
              <name>OIS2N</name>
              <bitOffset>11</bitOffset>
              <bitWidth>1</bitWidth>
            </field>
            <field>
              <name>OIS3</name>
              <bitOffset>12</bitOffset>
              <bitWidth>1</bitWidth>
            </field>
            <field>
              <name>OIS3N</name>
              <bitOffset>13</bitOffset>
              <bitWidth>1</bitWidth>
            </field>
            <field>
              <name>OIS4</name>
              <bitOffset>14</bitOffset>
              <bitWidth>1</bitWidth>
            </field>
            <field>
              <name>OIS5</name>
              <bitOffset>16</bitOffset>
              <bitWidth>1</bitWidth>
            </field>
            <field>
              <name>OIS6</name>
              <bitOffset>18</bitOffset>
              <bitWidth>1</bitWidth>
            </field>
            <field>
              <name>MMS2</name>
              <bitOffset>20</bitOffset>
              <bitWidth>4</bitWidth>
            </field>
          </fields>
        </register>
        <register>
          <name>SMCR</name>
          <addressOffset>0x8</addressOffset>
          <size>0x20</size>
          <fields>
            <field>
              <name>SMS</name>
              <bitOffset>0</bitOffset>
              <bitWidth>17</bitWidth>
            </field>
            <field>
              <name>TS</name>
              <bitOffset>4</bitOffset>
              <bitWidth>18</bitWidth>
            </field>
            <field>
              <name>MSM</name>
              <bitOffset>7</bitOffset>
              <bitWidth>1</bitWidth>
            </field>
            <field>
              <name>ETF</name>
              <bitOffset>8</bitOffset>
              <bitWidth>4</bitWidth>
            </field>
            <field>
              <name>ETPS</name>
              <bitOffset>12</bitOffset>
              <bitWidth>2</bitWidth>
            </field>
            <field>
              <name>ECE</name>
              <bitOffset>14</bitOffset>
              <bitWidth>1</bitWidth>
            </field>
            <field>
              <name>ETP</name>
              <bitOffset>15</bitOffset>
              <bitWidth>1</bitWidth>
            </field>
          </fields>
        </register>
        <register>
          <name>DIER</name>
          <addressOffset>0xc</addressOffset>
          <size>0x20</size>
          <fields>
            <field>
              <name>UIE</name>
              <bitOffset>0</bitOffset>
              <bitWidth>1</bitWidth>
            </field>
            <field>
              <name>CC1IE</name>
              <bitOffset>1</bitOffset>
              <bitWidth>1</bitWidth>
            </field>
            <field>
              <name>CC2IE</name>
              <bitOffset>2</bitOffset>
              <bitWidth>1</bitWidth>
            </field>
            <field>
              <name>CC3IE</name>
              <bitOffset>3</bitOffset>
              <bitWidth>1</bitWidth>
            </field>
            <field>
              <name>CC4IE</name>
              <bitOffset>4</bitOffset>
              <bitWidth>1</bitWidth>
            </field>
            <field>
              <name>COMIE</name>
              <bitOffset>5</bitOffset>
              <bitWidth>1</bitWidth>
            </field>
            <field>
              <name>TIE</name>
              <bitOffset>6</bitOffset>
              <bitWidth>1</bitWidth>
            </field>
            <field>
              <name>BIE</name>
              <bitOffset>7</bitOffset>
              <bitWidth>1</bitWidth>
            </field>
            <field>
              <name>UDE</name>
              <bitOffset>8</bitOffset>
              <bitWidth>1</bitWidth>
            </field>
            <field>
              <name>CC1DE</name>
              <bitOffset>9</bitOffset>
              <bitWidth>1</bitWidth>
            </field>
            <field>
              <name>CC2DE</name>
              <bitOffset>10</bitOffset>
              <bitWidth>1</bitWidth>
            </field>
            <field>
              <name>CC3DE</name>
              <bitOffset>11</bitOffset>
              <bitWidth>1</bitWidth>
            </field>
            <field>
              <name>CC4DE</name>
              <bitOffset>12</bitOffset>
              <bitWidth>1</bitWidth>
            </field>
            <field>
              <name>COMDE</name>
              <bitOffset>13</bitOffset>
              <bitWidth>1</bitWidth>
            </field>
            <field>
              <name>TDE</name>
              <bitOffset>14</bitOffset>
              <bitWidth>1</bitWidth>
            </field>
          </fields>
        </register>
        <register>
          <name>SR</name>
          <addressOffset>0x10</addressOffset>
          <size>0x20</size>
          <fields>
            <field>
              <name>UIF</name>
              <bitOffset>0</bitOffset>
              <bitWidth>1</bitWidth>
            </field>
            <field>
              <name>CC1IF</name>
              <bitOffset>1</bitOffset>
              <bitWidth>1</bitWidth>
            </field>
            <field>
              <name>CC2IF</name>
              <bitOffset>2</bitOffset>
              <bitWidth>1</bitWidth>
            </field>
            <field>
              <name>CC3IF</name>
              <bitOffset>3</bitOffset>
              <bitWidth>1</bitWidth>
            </field>
            <field>
              <name>CC4IF</name>
              <bitOffset>4</bitOffset>
              <bitWidth>1</bitWidth>
            </field>
            <field>
              <name>COMIF</name>
              <bitOffset>5</bitOffset>
              <bitWidth>1</bitWidth>
            </field>
            <field>
              <name>TIF</name>
              <bitOffset>6</bitOffset>
              <bitWidth>1</bitWidth>
            </field>
            <field>
              <name>BIF</name>
              <bitOffset>7</bitOffset>
              <bitWidth>1</bitWidth>
            </field>
            <field>
              <name>B2IF</name>
              <bitOffset>8</bitOffset>
              <bitWidth>1</bitWidth>
            </field>
            <field>
              <name>CC1OF</name>
              <bitOffset>9</bitOffset>
              <bitWidth>1</bitWidth>
            </field>
            <field>
              <name>CC2OF</name>
              <bitOffset>10</bitOffset>
              <bitWidth>1</bitWidth>
            </field>
            <field>
              <name>CC3OF</name>
              <bitOffset>11</bitOffset>
              <bitWidth>1</bitWidth>
            </field>
            <field>
              <name>CC4OF</name>
              <bitOffset>12</bitOffset>
              <bitWidth>1</bitWidth>
            </field>
            <field>
              <name>SBIF</name>
              <bitOffset>13</bitOffset>
              <bitWidth>1</bitWidth>
            </field>
            <field>
              <name>CC5IF</name>
              <bitOffset>16</bitOffset>
              <bitWidth>1</bitWidth>
            </field>
            <field>
              <name>CC6IF</name>
              <bitOffset>17</bitOffset>
              <bitWidth>1</bitWidth>
            </field>
          </fields>
        </register>
        <register>
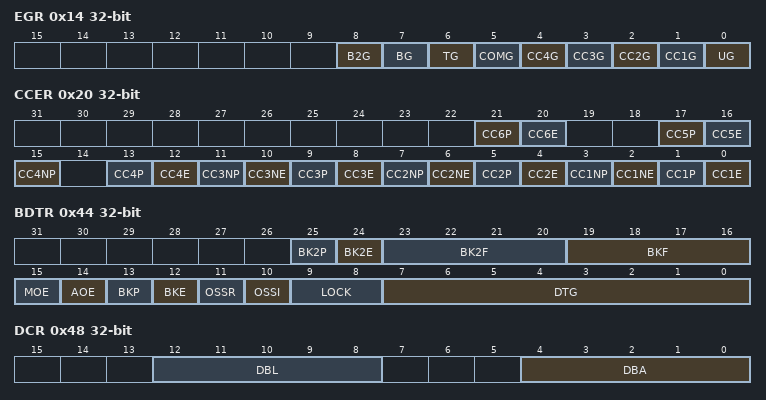
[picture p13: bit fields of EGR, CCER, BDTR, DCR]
          <name>EGR</name>
          <addressOffset>0x14</addressOffset>
          <size>0x20</size>
          <fields>
            <field>
              <name>UG</name>
              <bitOffset>0</bitOffset>
              <bitWidth>1</bitWidth>
            </field>
            <field>
              <name>CC1G</name>
              <bitOffset>1</bitOffset>
              <bitWidth>1</bitWidth>
            </field>
            <field>
              <name>CC2G</name>
              <bitOffset>2</bitOffset>
              <bitWidth>1</bitWidth>
            </field>
            <field>
              <name>CC3G</name>
              <bitOffset>3</bitOffset>
              <bitWidth>1</bitWidth>
            </field>
            <field>
              <name>CC4G</name>
              <bitOffset>4</bitOffset>
              <bitWidth>1</bitWidth>
            </field>
            <field>
              <name>COMG</name>
              <bitOffset>5</bitOffset>
              <bitWidth>1</bitWidth>
            </field>
            <field>
              <name>TG</name>
              <bitOffset>6</bitOffset>
              <bitWidth>1</bitWidth>
            </field>
            <field>
              <name>BG</name>
              <bitOffset>7</bitOffset>
              <bitWidth>1</bitWidth>
            </field>
            <field>
              <name>B2G</name>
              <bitOffset>8</bitOffset>
              <bitWidth>1</bitWidth>
            </field>
          </fields>
        </register>
        <register>
          <name>CCMR1</name>
          <addressOffset>0x18</addressOffset>
          <size>0x20</size>
          <fields>
            <field>
              <name>CC1S</name>
              <bitOffset>0</bitOffset>
              <bitWidth>2</bitWidth>
            </field>
            <field>
              <name>OC1FE</name>
              <bitOffset>2</bitOffset>
              <bitWidth>1</bitWidth>
            </field>
            <field>
              <name>OC1PE</name>
              <bitOffset>3</bitOffset>
              <bitWidth>1</bitWidth>
            </field>
            <field>
              <name>OC1M</name>
              <bitOffset>4</bitOffset>
              <bitWidth>13</bitWidth>
            </field>
            <field>
              <name>OC1CE</name>
              <bitOffset>7</bitOffset>
              <bitWidth>1</bitWidth>
            </field>
            <field>
              <name>CC2S</name>
              <bitOffset>8</bitOffset>
              <bitWidth>2</bitWidth>
            </field>
            <field>
              <name>OC2FE</name>
              <bitOffset>10</bitOffset>
              <bitWidth>1</bitWidth>
            </field>
            <field>
              <name>OC2PE</name>
              <bitOffset>11</bitOffset>
              <bitWidth>1</bitWidth>
            </field>
            <field>
              <name>OC2M</name>
              <bitOffset>12</bitOffset>
              <bitWidth>13</bitWidth>
            </field>
            <field>
              <name>OC2CE</name>
              <bitOffset>15</bitOffset>
              <bitWidth>1</bitWidth>
            </field>
          </fields>
        </register>
        <register>
          <name>CCMR2</name>
          <addressOffset>0x1c</addressOffset>
          <size>0x20</size>
          <fields>
            <field>
              <name>CC3S</name>
              <bitOffset>0</bitOffset>
              <bitWidth>2</bitWidth>
            </field>
            <field>
              <name>OC3FE</name>
              <bitOffset>2</bitOffset>
              <bitWidth>1</bitWidth>
            </field>
            <field>
              <name>OC3PE</name>
              <bitOffset>3</bitOffset>
              <bitWidth>1</bitWidth>
            </field>
            <field>
              <name>OC3M</name>
              <bitOffset>4</bitOffset>
              <bitWidth>13</bitWidth>
            </field>
            <field>
              <name>OC3CE</name>
              <bitOffset>7</bitOffset>
              <bitWidth>1</bitWidth>
            </field>
            <field>
              <name>CC4S</name>
              <bitOffset>8</bitOffset>
              <bitWidth>2</bitWidth>
            </field>
            <field>
              <name>OC4FE</name>
              <bitOffset>10</bitOffset>
              <bitWidth>1</bitWidth>
            </field>
            <field>
              <name>OC4PE</name>
              <bitOffset>11</bitOffset>
              <bitWidth>1</bitWidth>
            </field>
            <field>
              <name>OC4M</name>
              <bitOffset>12</bitOffset>
              <bitWidth>13</bitWidth>
            </field>
            <field>
              <name>OC4CE</name>
              <bitOffset>15</bitOffset>
              <bitWidth>1</bitWidth>
            </field>
          </fields>
        </register>
        <register>
          <name>CCER</name>
          <addressOffset>0x20</addressOffset>
          <size>0x20</size>
          <fields>
            <field>
              <name>CC1E</name>
              <bitOffset>0</bitOffset>
              <bitWidth>1</bitWidth>
            </field>
            <field>
              <name>CC1P</name>
              <bitOffset>1</bitOffset>
              <bitWidth>1</bitWidth>
            </field>
            <field>
              <name>CC1NE</name>
              <bitOffset>2</bitOffset>
              <bitWidth>1</bitWidth>
            </field>
            <field>
              <name>CC1NP</name>
              <bitOffset>3</bitOffset>
              <bitWidth>1</bitWidth>
            </field>
            <field>
              <name>CC2E</name>
              <bitOffset>4</bitOffset>
              <bitWidth>1</bitWidth>
            </field>
            <field>
              <name>CC2P</name>
              <bitOffset>5</bitOffset>
              <bitWidth>1</bitWidth>
            </field>
            <field>
              <name>CC2NE</name>
              <bitOffset>6</bitOffset>
              <bitWidth>1</bitWidth>
            </field>
            <field>
              <name>CC2NP</name>
              <bitOffset>7</bitOffset>
              <bitWidth>1</bitWidth>
            </field>
            <field>
              <name>CC3E</name>
              <bitOffset>8</bitOffset>
              <bitWidth>1</bitWidth>
            </field>
            <field>
              <name>CC3P</name>
              <bitOffset>9</bitOffset>
              <bitWidth>1</bitWidth>
            </field>
            <field>
              <name>CC3NE</name>
              <bitOffset>10</bitOffset>
              <bitWidth>1</bitWidth>
            </field>
            <field>
              <name>CC3NP</name>
              <bitOffset>11</bitOffset>
              <bitWidth>1</bitWidth>
            </field>
            <field>
              <name>CC4E</name>
              <bitOffset>12</bitOffset>
              <bitWidth>1</bitWidth>
            </field>
            <field>
              <name>CC4P</name>
              <bitOffset>13</bitOffset>
              <bitWidth>1</bitWidth>
            </field>
            <field>
              <name>CC4NP</name>
              <bitOffset>15</bitOffset>
              <bitWidth>1</bitWidth>
            </field>
            <field>
              <name>CC5E</name>
              <bitOffset>16</bitOffset>
              <bitWidth>1</bitWidth>
            </field>
            <field>
              <name>CC5P</name>
              <bitOffset>17</bitOffset>
              <bitWidth>1</bitWidth>
            </field>
            <field>
              <name>CC6E</name>
              <bitOffset>20</bitOffset>
              <bitWidth>1</bitWidth>
            </field>
            <field>
              <name>CC6P</name>
              <bitOffset>21</bitOffset>
              <bitWidth>1</bitWidth>
            </field>
          </fields>
        </register>
        <register>
          <name>CNT</name>
          <addressOffset>0x24</addressOffset>
          <size>0x20</size>
          <fields>
            <field>
              <name>CNT</name>
              <bitOffset>0</bitOffset>
              <bitWidth>32</bitWidth>
            </field>
            <field>
              <name>UIFCPY</name>
              <bitOffset>31</bitOffset>
              <bitWidth>1</bitWidth>
            </field>
          </fields>
        </register>
        <register>
          <name>PSC</name>
          <addressOffset>0x28</addressOffset>
          <size>0x20</size>
          <fields>
            <field>
              <name>PSC</name>
              <bitOffset>0</bitOffset>
              <bitWidth>16</bitWidth>
            </field>
          </fields>
        </register>
        <register>
          <name>ARR</name>
          <addressOffset>0x2c</addressOffset>
          <size>0x20</size>
          <fields>
            <field>
              <name>ARR</name>
              <bitOffset>0</bitOffset>
              <bitWidth>32</bitWidth>
            </field>
          </fields>
        </register>
        <register>
          <name>RCR</name>
          <addressOffset>0x30</addressOffset>
          <size>0x20</size>
          <fields>
            <field>
              <name>REP</name>
              <bitOffset>0</bitOffset>
              <bitWidth>8</bitWidth>
            </field>
          </fields>
        </register>
        <register>
          <name>CCR1</name>
          <addressOffset>0x34</addressOffset>
          <size>0x20</size>
          <fields>
            <field>
              <name>CCR1</name>
              <bitOffset>0</bitOffset>
              <bitWidth>16</bitWidth>
            </field>
          </fields>
        </register>
        <register>
          <name>CCR2</name>
          <addressOffset>0x38</addressOffset>
          <size>0x20</size>
          <fields>
            <field>
              <name>CCR2</name>
              <bitOffset>0</bitOffset>
              <bitWidth>16</bitWidth>
            </field>
          </fields>
        </register>
        <register>
          <name>CCR3</name>
          <addressOffset>0x3c</addressOffset>
          <size>0x20</size>
          <fields>
            <field>
              <name>CCR3</name>
              <bitOffset>0</bitOffset>
              <bitWidth>16</bitWidth>
            </field>
          </fields>
        </register>
        <register>
          <name>CCR4</name>
          <addressOffset>0x40</addressOffset>
          <size>0x20</size>
          <fields>
            <field>
              <name>CCR4</name>
              <bitOffset>0</bitOffset>
              <bitWidth>16</bitWidth>
            </field>
          </fields>
        </register>
        <register>
          <name>BDTR</name>
          <addressOffset>0x44</addressOffset>
          <size>0x20</size>
          <fields>
            <field>
              <name>DTG</name>
              <bitOffset>0</bitOffset>
              <bitWidth>8</bitWidth>
            </field>
            <field>
              <name>LOCK</name>
              <bitOffset>8</bitOffset>
              <bitWidth>2</bitWidth>
            </field>
            <field>
              <name>OSSI</name>
              <bitOffset>10</bitOffset>
              <bitWidth>1</bitWidth>
            </field>
            <field>
              <name>OSSR</name>
              <bitOffset>11</bitOffset>
              <bitWidth>1</bitWidth>
            </field>
            <field>
              <name>BKE</name>
              <bitOffset>12</bitOffset>
              <bitWidth>1</bitWidth>
            </field>
            <field>
              <name>BKP</name>
              <bitOffset>13</bitOffset>
              <bitWidth>1</bitWidth>
            </field>
            <field>
              <name>AOE</name>
              <bitOffset>14</bitOffset>
              <bitWidth>1</bitWidth>
            </field>
            <field>
              <name>MOE</name>
              <bitOffset>15</bitOffset>
              <bitWidth>1</bitWidth>
            </field>
            <field>
              <name>BKF</name>
              <bitOffset>16</bitOffset>
              <bitWidth>4</bitWidth>
            </field>
            <field>
              <name>BK2F</name>
              <bitOffset>20</bitOffset>
              <bitWidth>4</bitWidth>
            </field>
            <field>
              <name>BK2E</name>
              <bitOffset>24</bitOffset>
              <bitWidth>1</bitWidth>
            </field>
            <field>
              <name>BK2P</name>
              <bitOffset>25</bitOffset>
              <bitWidth>1</bitWidth>
            </field>
          </fields>
        </register>
        <register>
          <name>DCR</name>
          <addressOffset>0x48</addressOffset>
          <size>0x20</size>
          <fields>
            <field>
              <name>DBA</name>
              <bitOffset>0</bitOffset>
              <bitWidth>5</bitWidth>
            </field>
            <field>
              <name>DBL</name>
              <bitOffset>8</bitOffset>
              <bitWidth>5</bitWidth>
            </field>
          </fields>
        </register>
        <register>
          <name>DMAR</name>
          <addressOffset>0x4c</addressOffset>
          <size>0x20</size>
          <fields>
            <field>
              <name>DMAB</name>
              <bitOffset>0</bitOffset>
              <bitWidth>16</bitWidth>
            </field>
          </fields>
        </register>
        <register>
          <name>CCMR3</name>
          <addressOffset>0x54</addressOffset>
          <size>0x20</size>
          <fields>
            <field>
              <name>OC5FE</name>
              <bitOffset>2</bitOffset>
              <bitWidth>1</bitWidth>
            </field>
            <field>
              <name>OC5PE</name>
              <bitOffset>3</bitOffset>
              <bitWidth>1</bitWidth>
            </field>
            <field>
              <name>OC5M</name>
              <bitOffset>4</bitOffset>
              <bitWidth>13</bitWidth>
            </field>
            <field>
              <name>OC5CE</name>
              <bitOffset>7</bitOffset>
              <bitWidth>1</bitWidth>
            </field>
            <field>
              <name>OC6FE</name>
              <bitOffset>10</bitOffset>
              <bitWidth>1</bitWidth>
            </field>
            <field>
              <name>OC6PE</name>
              <bitOffset>11</bitOffset>
              <bitWidth>1</bitWidth>
            </field>
            <field>
              <name>OC6M</name>
              <bitOffset>12</bitOffset>
              <bitWidth>13</bitWidth>
            </field>
            <field>
              <name>OC6CE</name>
              <bitOffset>15</bitOffset>
              <bitWidth>1</bitWidth>
            </field>
          </fields>
        </register>
        <register>
          <name>CCR5</name>
          <addressOffset>0x58</addressOffset>
          <size>0x20</size>
          <fields>
            <field>
              <name>CCR5</name>
              <bitOffset>0</bitOffset>
              <bitWidth>32</bitWidth>
            </field>
            <field>
              <name>GC5C1</name>
              <bitOffset>29</bitOffset>
              <bitWidth>1</bitWidth>
            </field>
            <field>
              <name>GC5C2</name>
              <bitOffset>30</bitOffset>
              <bitWidth>1</bitWidth>
            </field>
            <field>
              <name>GC5C3</name>
              <bitOffset>31</bitOffset>
              <bitWidth>1</bitWidth>
            </field>
          </fields>
        </register>
        <register>
          <name>CCR6</name>
          <addressOffset>0x5c</addressOffset>
          <size>0x20</size>
          <fields>
            <field>
              <name>CCR6</name>
              <bitOffset>0</bitOffset>
              <bitWidth>16</bitWidth>
            </field>
          </fields>
        </register>
        <register>
          <name>AF1</name>
          <addressOffset>0x60</addressOffset>
          <size>0x20</size>
        </register>
        <register>
          <name>AF2</name>
          <addressOffset>0x64</addressOffset>
          <size>0x20</size>
        </register>
        <register>
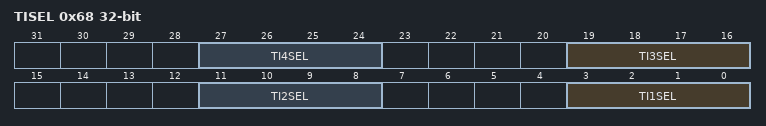
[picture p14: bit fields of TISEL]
          <name>TISEL</name>
          <addressOffset>0x68</addressOffset>
          <size>0x20</size>
          <fields>
            <field>
              <name>TI1SEL</name>
              <bitOffset>0</bitOffset>
              <bitWidth>4</bitWidth>
            </field>
            <field>
              <name>TI2SEL</name>
              <bitOffset>8</bitOffset>
              <bitWidth>4</bitWidth>
            </field>
            <field>
              <name>TI3SEL</name>
              <bitOffset>16</bitOffset>
              <bitWidth>4</bitWidth>
            </field>
            <field>
              <name>TI4SEL</name>
              <bitOffset>24</bitOffset>
              <bitWidth>4</bitWidth>
            </field>
          </fields>
        </register>
      </registers>
    </peripheral>
    <peripheral>
      <name>TIM7</name>
      <baseAddress>0x40001400</baseAddress>
      <registers>
        <register>
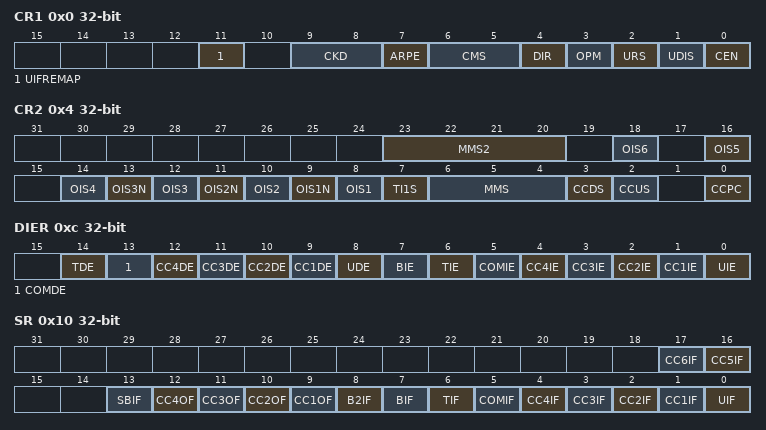
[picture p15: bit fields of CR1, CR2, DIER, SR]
          <name>CR1</name>
          <addressOffset>0x0</addressOffset>
          <size>0x20</size>
          <fields>
            <field>
              <name>CEN</name>
              <bitOffset>0</bitOffset>
              <bitWidth>1</bitWidth>
            </field>
            <field>
              <name>UDIS</name>
              <bitOffset>1</bitOffset>
              <bitWidth>1</bitWidth>
            </field>
            <field>
              <name>URS</name>
              <bitOffset>2</bitOffset>
              <bitWidth>1</bitWidth>
            </field>
            <field>
              <name>OPM</name>
              <bitOffset>3</bitOffset>
              <bitWidth>1</bitWidth>
            </field>
            <field>
              <name>DIR</name>
              <bitOffset>4</bitOffset>
              <bitWidth>1</bitWidth>
            </field>
            <field>
              <name>CMS</name>
              <bitOffset>5</bitOffset>
              <bitWidth>2</bitWidth>
            </field>
            <field>
              <name>ARPE</name>
              <bitOffset>7</bitOffset>
              <bitWidth>1</bitWidth>
            </field>
            <field>
              <name>CKD</name>
              <bitOffset>8</bitOffset>
              <bitWidth>2</bitWidth>
            </field>
            <field>
              <name>UIFREMAP</name>
              <bitOffset>11</bitOffset>
              <bitWidth>1</bitWidth>
            </field>
          </fields>
        </register>
        <register>
          <name>CR2</name>
          <addressOffset>0x4</addressOffset>
          <size>0x20</size>
          <fields>
            <field>
              <name>CCPC</name>
              <bitOffset>0</bitOffset>
              <bitWidth>1</bitWidth>
            </field>
            <field>
              <name>CCUS</name>
              <bitOffset>2</bitOffset>
              <bitWidth>1</bitWidth>
            </field>
            <field>
              <name>CCDS</name>
              <bitOffset>3</bitOffset>
              <bitWidth>1</bitWidth>
            </field>
            <field>
              <name>MMS</name>
              <bitOffset>4</bitOffset>
              <bitWidth>3</bitWidth>
            </field>
            <field>
              <name>TI1S</name>
              <bitOffset>7</bitOffset>
              <bitWidth>1</bitWidth>
            </field>
            <field>
              <name>OIS1</name>
              <bitOffset>8</bitOffset>
              <bitWidth>1</bitWidth>
            </field>
            <field>
              <name>OIS1N</name>
              <bitOffset>9</bitOffset>
              <bitWidth>1</bitWidth>
            </field>
            <field>
              <name>OIS2</name>
              <bitOffset>10</bitOffset>
              <bitWidth>1</bitWidth>
            </field>
            <field>
              <name>OIS2N</name>
              <bitOffset>11</bitOffset>
              <bitWidth>1</bitWidth>
            </field>
            <field>
              <name>OIS3</name>
              <bitOffset>12</bitOffset>
              <bitWidth>1</bitWidth>
            </field>
            <field>
              <name>OIS3N</name>
              <bitOffset>13</bitOffset>
              <bitWidth>1</bitWidth>
            </field>
            <field>
              <name>OIS4</name>
              <bitOffset>14</bitOffset>
              <bitWidth>1</bitWidth>
            </field>
            <field>
              <name>OIS5</name>
              <bitOffset>16</bitOffset>
              <bitWidth>1</bitWidth>
            </field>
            <field>
              <name>OIS6</name>
              <bitOffset>18</bitOffset>
              <bitWidth>1</bitWidth>
            </field>
            <field>
              <name>MMS2</name>
              <bitOffset>20</bitOffset>
              <bitWidth>4</bitWidth>
            </field>
          </fields>
        </register>
        <register>
          <name>SMCR</name>
          <addressOffset>0x8</addressOffset>
          <size>0x20</size>
          <fields>
            <field>
              <name>SMS</name>
              <bitOffset>0</bitOffset>
              <bitWidth>17</bitWidth>
            </field>
            <field>
              <name>TS</name>
              <bitOffset>4</bitOffset>
              <bitWidth>18</bitWidth>
            </field>
            <field>
              <name>MSM</name>
              <bitOffset>7</bitOffset>
              <bitWidth>1</bitWidth>
            </field>
            <field>
              <name>ETF</name>
              <bitOffset>8</bitOffset>
              <bitWidth>4</bitWidth>
            </field>
            <field>
              <name>ETPS</name>
              <bitOffset>12</bitOffset>
              <bitWidth>2</bitWidth>
            </field>
            <field>
              <name>ECE</name>
              <bitOffset>14</bitOffset>
              <bitWidth>1</bitWidth>
            </field>
            <field>
              <name>ETP</name>
              <bitOffset>15</bitOffset>
              <bitWidth>1</bitWidth>
            </field>
          </fields>
        </register>
        <register>
          <name>DIER</name>
          <addressOffset>0xc</addressOffset>
          <size>0x20</size>
          <fields>
            <field>
              <name>UIE</name>
              <bitOffset>0</bitOffset>
              <bitWidth>1</bitWidth>
            </field>
            <field>
              <name>CC1IE</name>
              <bitOffset>1</bitOffset>
              <bitWidth>1</bitWidth>
            </field>
            <field>
              <name>CC2IE</name>
              <bitOffset>2</bitOffset>
              <bitWidth>1</bitWidth>
            </field>
            <field>
              <name>CC3IE</name>
              <bitOffset>3</bitOffset>
              <bitWidth>1</bitWidth>
            </field>
            <field>
              <name>CC4IE</name>
              <bitOffset>4</bitOffset>
              <bitWidth>1</bitWidth>
            </field>
            <field>
              <name>COMIE</name>
              <bitOffset>5</bitOffset>
              <bitWidth>1</bitWidth>
            </field>
            <field>
              <name>TIE</name>
              <bitOffset>6</bitOffset>
              <bitWidth>1</bitWidth>
            </field>
            <field>
              <name>BIE</name>
              <bitOffset>7</bitOffset>
              <bitWidth>1</bitWidth>
            </field>
            <field>
              <name>UDE</name>
              <bitOffset>8</bitOffset>
              <bitWidth>1</bitWidth>
            </field>
            <field>
              <name>CC1DE</name>
              <bitOffset>9</bitOffset>
              <bitWidth>1</bitWidth>
            </field>
            <field>
              <name>CC2DE</name>
              <bitOffset>10</bitOffset>
              <bitWidth>1</bitWidth>
            </field>
            <field>
              <name>CC3DE</name>
              <bitOffset>11</bitOffset>
              <bitWidth>1</bitWidth>
            </field>
            <field>
              <name>CC4DE</name>
              <bitOffset>12</bitOffset>
              <bitWidth>1</bitWidth>
            </field>
            <field>
              <name>COMDE</name>
              <bitOffset>13</bitOffset>
              <bitWidth>1</bitWidth>
            </field>
            <field>
              <name>TDE</name>
              <bitOffset>14</bitOffset>
              <bitWidth>1</bitWidth>
            </field>
          </fields>
        </register>
        <register>
          <name>SR</name>
          <addressOffset>0x10</addressOffset>
          <size>0x20</size>
          <fields>
            <field>
              <name>UIF</name>
              <bitOffset>0</bitOffset>
              <bitWidth>1</bitWidth>
            </field>
            <field>
              <name>CC1IF</name>
              <bitOffset>1</bitOffset>
              <bitWidth>1</bitWidth>
            </field>
            <field>
              <name>CC2IF</name>
              <bitOffset>2</bitOffset>
              <bitWidth>1</bitWidth>
            </field>
            <field>
              <name>CC3IF</name>
              <bitOffset>3</bitOffset>
              <bitWidth>1</bitWidth>
            </field>
            <field>
              <name>CC4IF</name>
              <bitOffset>4</bitOffset>
              <bitWidth>1</bitWidth>
            </field>
            <field>
              <name>COMIF</name>
              <bitOffset>5</bitOffset>
              <bitWidth>1</bitWidth>
            </field>
            <field>
              <name>TIF</name>
              <bitOffset>6</bitOffset>
              <bitWidth>1</bitWidth>
            </field>
            <field>
              <name>BIF</name>
              <bitOffset>7</bitOffset>
              <bitWidth>1</bitWidth>
            </field>
            <field>
              <name>B2IF</name>
              <bitOffset>8</bitOffset>
              <bitWidth>1</bitWidth>
            </field>
            <field>
              <name>CC1OF</name>
              <bitOffset>9</bitOffset>
              <bitWidth>1</bitWidth>
            </field>
            <field>
              <name>CC2OF</name>
              <bitOffset>10</bitOffset>
              <bitWidth>1</bitWidth>
            </field>
            <field>
              <name>CC3OF</name>
              <bitOffset>11</bitOffset>
              <bitWidth>1</bitWidth>
            </field>
            <field>
              <name>CC4OF</name>
              <bitOffset>12</bitOffset>
              <bitWidth>1</bitWidth>
            </field>
            <field>
              <name>SBIF</name>
              <bitOffset>13</bitOffset>
              <bitWidth>1</bitWidth>
            </field>
            <field>
              <name>CC5IF</name>
              <bitOffset>16</bitOffset>
              <bitWidth>1</bitWidth>
            </field>
            <field>
              <name>CC6IF</name>
              <bitOffset>17</bitOffset>
              <bitWidth>1</bitWidth>
            </field>
          </fields>
        </register>
        <register>
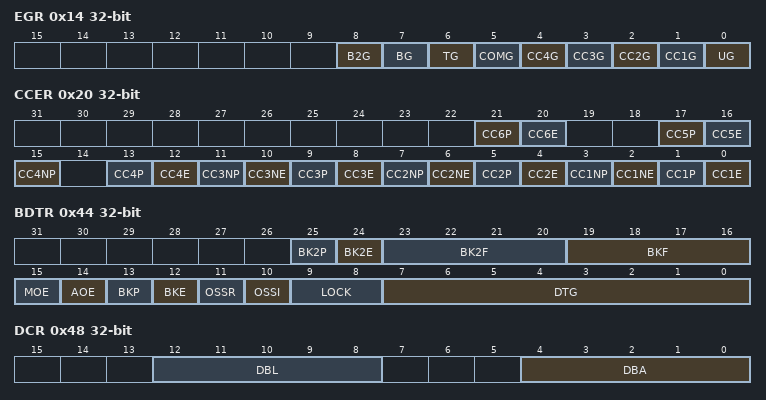
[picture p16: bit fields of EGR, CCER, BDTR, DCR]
          <name>EGR</name>
          <addressOffset>0x14</addressOffset>
          <size>0x20</size>
          <fields>
            <field>
              <name>UG</name>
              <bitOffset>0</bitOffset>
              <bitWidth>1</bitWidth>
            </field>
            <field>
              <name>CC1G</name>
              <bitOffset>1</bitOffset>
              <bitWidth>1</bitWidth>
            </field>
            <field>
              <name>CC2G</name>
              <bitOffset>2</bitOffset>
              <bitWidth>1</bitWidth>
            </field>
            <field>
              <name>CC3G</name>
              <bitOffset>3</bitOffset>
              <bitWidth>1</bitWidth>
            </field>
            <field>
              <name>CC4G</name>
              <bitOffset>4</bitOffset>
              <bitWidth>1</bitWidth>
            </field>
            <field>
              <name>COMG</name>
              <bitOffset>5</bitOffset>
              <bitWidth>1</bitWidth>
            </field>
            <field>
              <name>TG</name>
              <bitOffset>6</bitOffset>
              <bitWidth>1</bitWidth>
            </field>
            <field>
              <name>BG</name>
              <bitOffset>7</bitOffset>
              <bitWidth>1</bitWidth>
            </field>
            <field>
              <name>B2G</name>
              <bitOffset>8</bitOffset>
              <bitWidth>1</bitWidth>
            </field>
          </fields>
        </register>
        <register>
          <name>CCMR1</name>
          <addressOffset>0x18</addressOffset>
          <size>0x20</size>
          <fields>
            <field>
              <name>CC1S</name>
              <bitOffset>0</bitOffset>
              <bitWidth>2</bitWidth>
            </field>
            <field>
              <name>OC1FE</name>
              <bitOffset>2</bitOffset>
              <bitWidth>1</bitWidth>
            </field>
            <field>
              <name>OC1PE</name>
              <bitOffset>3</bitOffset>
              <bitWidth>1</bitWidth>
            </field>
            <field>
              <name>OC1M</name>
              <bitOffset>4</bitOffset>
              <bitWidth>13</bitWidth>
            </field>
            <field>
              <name>OC1CE</name>
              <bitOffset>7</bitOffset>
              <bitWidth>1</bitWidth>
            </field>
            <field>
              <name>CC2S</name>
              <bitOffset>8</bitOffset>
              <bitWidth>2</bitWidth>
            </field>
            <field>
              <name>OC2FE</name>
              <bitOffset>10</bitOffset>
              <bitWidth>1</bitWidth>
            </field>
            <field>
              <name>OC2PE</name>
              <bitOffset>11</bitOffset>
              <bitWidth>1</bitWidth>
            </field>
            <field>
              <name>OC2M</name>
              <bitOffset>12</bitOffset>
              <bitWidth>13</bitWidth>
            </field>
            <field>
              <name>OC2CE</name>
              <bitOffset>15</bitOffset>
              <bitWidth>1</bitWidth>
            </field>
          </fields>
        </register>
        <register>
          <name>CCMR2</name>
          <addressOffset>0x1c</addressOffset>
          <size>0x20</size>
          <fields>
            <field>
              <name>CC3S</name>
              <bitOffset>0</bitOffset>
              <bitWidth>2</bitWidth>
            </field>
            <field>
              <name>OC3FE</name>
              <bitOffset>2</bitOffset>
              <bitWidth>1</bitWidth>
            </field>
            <field>
              <name>OC3PE</name>
              <bitOffset>3</bitOffset>
              <bitWidth>1</bitWidth>
            </field>
            <field>
              <name>OC3M</name>
              <bitOffset>4</bitOffset>
              <bitWidth>13</bitWidth>
            </field>
            <field>
              <name>OC3CE</name>
              <bitOffset>7</bitOffset>
              <bitWidth>1</bitWidth>
            </field>
            <field>
              <name>CC4S</name>
              <bitOffset>8</bitOffset>
              <bitWidth>2</bitWidth>
            </field>
            <field>
              <name>OC4FE</name>
              <bitOffset>10</bitOffset>
              <bitWidth>1</bitWidth>
            </field>
            <field>
              <name>OC4PE</name>
              <bitOffset>11</bitOffset>
              <bitWidth>1</bitWidth>
            </field>
            <field>
              <name>OC4M</name>
              <bitOffset>12</bitOffset>
              <bitWidth>13</bitWidth>
            </field>
            <field>
              <name>OC4CE</name>
              <bitOffset>15</bitOffset>
              <bitWidth>1</bitWidth>
            </field>
          </fields>
        </register>
        <register>
          <name>CCER</name>
          <addressOffset>0x20</addressOffset>
          <size>0x20</size>
          <fields>
            <field>
              <name>CC1E</name>
              <bitOffset>0</bitOffset>
              <bitWidth>1</bitWidth>
            </field>
            <field>
              <name>CC1P</name>
              <bitOffset>1</bitOffset>
              <bitWidth>1</bitWidth>
            </field>
            <field>
              <name>CC1NE</name>
              <bitOffset>2</bitOffset>
              <bitWidth>1</bitWidth>
            </field>
            <field>
              <name>CC1NP</name>
              <bitOffset>3</bitOffset>
              <bitWidth>1</bitWidth>
            </field>
            <field>
              <name>CC2E</name>
              <bitOffset>4</bitOffset>
              <bitWidth>1</bitWidth>
            </field>
            <field>
              <name>CC2P</name>
              <bitOffset>5</bitOffset>
              <bitWidth>1</bitWidth>
            </field>
            <field>
              <name>CC2NE</name>
              <bitOffset>6</bitOffset>
              <bitWidth>1</bitWidth>
            </field>
            <field>
              <name>CC2NP</name>
              <bitOffset>7</bitOffset>
              <bitWidth>1</bitWidth>
            </field>
            <field>
              <name>CC3E</name>
              <bitOffset>8</bitOffset>
              <bitWidth>1</bitWidth>
            </field>
            <field>
              <name>CC3P</name>
              <bitOffset>9</bitOffset>
              <bitWidth>1</bitWidth>
            </field>
            <field>
              <name>CC3NE</name>
              <bitOffset>10</bitOffset>
              <bitWidth>1</bitWidth>
            </field>
            <field>
              <name>CC3NP</name>
              <bitOffset>11</bitOffset>
              <bitWidth>1</bitWidth>
            </field>
            <field>
              <name>CC4E</name>
              <bitOffset>12</bitOffset>
              <bitWidth>1</bitWidth>
            </field>
            <field>
              <name>CC4P</name>
              <bitOffset>13</bitOffset>
              <bitWidth>1</bitWidth>
            </field>
            <field>
              <name>CC4NP</name>
              <bitOffset>15</bitOffset>
              <bitWidth>1</bitWidth>
            </field>
            <field>
              <name>CC5E</name>
              <bitOffset>16</bitOffset>
              <bitWidth>1</bitWidth>
            </field>
            <field>
              <name>CC5P</name>
              <bitOffset>17</bitOffset>
              <bitWidth>1</bitWidth>
            </field>
            <field>
              <name>CC6E</name>
              <bitOffset>20</bitOffset>
              <bitWidth>1</bitWidth>
            </field>
            <field>
              <name>CC6P</name>
              <bitOffset>21</bitOffset>
              <bitWidth>1</bitWidth>
            </field>
          </fields>
        </register>
        <register>
          <name>CNT</name>
          <addressOffset>0x24</addressOffset>
          <size>0x20</size>
          <fields>
            <field>
              <name>CNT</name>
              <bitOffset>0</bitOffset>
              <bitWidth>32</bitWidth>
            </field>
            <field>
              <name>UIFCPY</name>
              <bitOffset>31</bitOffset>
              <bitWidth>1</bitWidth>
            </field>
          </fields>
        </register>
        <register>
          <name>PSC</name>
          <addressOffset>0x28</addressOffset>
          <size>0x20</size>
          <fields>
            <field>
              <name>PSC</name>
              <bitOffset>0</bitOffset>
              <bitWidth>16</bitWidth>
            </field>
          </fields>
        </register>
        <register>
          <name>ARR</name>
          <addressOffset>0x2c</addressOffset>
          <size>0x20</size>
          <fields>
            <field>
              <name>ARR</name>
              <bitOffset>0</bitOffset>
              <bitWidth>32</bitWidth>
            </field>
          </fields>
        </register>
        <register>
          <name>RCR</name>
          <addressOffset>0x30</addressOffset>
          <size>0x20</size>
          <fields>
            <field>
              <name>REP</name>
              <bitOffset>0</bitOffset>
              <bitWidth>8</bitWidth>
            </field>
          </fields>
        </register>
        <register>
          <name>CCR1</name>
          <addressOffset>0x34</addressOffset>
          <size>0x20</size>
          <fields>
            <field>
              <name>CCR1</name>
              <bitOffset>0</bitOffset>
              <bitWidth>16</bitWidth>
            </field>
          </fields>
        </register>
        <register>
          <name>CCR2</name>
          <addressOffset>0x38</addressOffset>
          <size>0x20</size>
          <fields>
            <field>
              <name>CCR2</name>
              <bitOffset>0</bitOffset>
              <bitWidth>16</bitWidth>
            </field>
          </fields>
        </register>
        <register>
          <name>CCR3</name>
          <addressOffset>0x3c</addressOffset>
          <size>0x20</size>
          <fields>
            <field>
              <name>CCR3</name>
              <bitOffset>0</bitOffset>
              <bitWidth>16</bitWidth>
            </field>
          </fields>
        </register>
        <register>
          <name>CCR4</name>
          <addressOffset>0x40</addressOffset>
          <size>0x20</size>
          <fields>
            <field>
              <name>CCR4</name>
              <bitOffset>0</bitOffset>
              <bitWidth>16</bitWidth>
            </field>
          </fields>
        </register>
        <register>
          <name>BDTR</name>
          <addressOffset>0x44</addressOffset>
          <size>0x20</size>
          <fields>
            <field>
              <name>DTG</name>
              <bitOffset>0</bitOffset>
              <bitWidth>8</bitWidth>
            </field>
            <field>
              <name>LOCK</name>
              <bitOffset>8</bitOffset>
              <bitWidth>2</bitWidth>
            </field>
            <field>
              <name>OSSI</name>
              <bitOffset>10</bitOffset>
              <bitWidth>1</bitWidth>
            </field>
            <field>
              <name>OSSR</name>
              <bitOffset>11</bitOffset>
              <bitWidth>1</bitWidth>
            </field>
            <field>
              <name>BKE</name>
              <bitOffset>12</bitOffset>
              <bitWidth>1</bitWidth>
            </field>
            <field>
              <name>BKP</name>
              <bitOffset>13</bitOffset>
              <bitWidth>1</bitWidth>
            </field>
            <field>
              <name>AOE</name>
              <bitOffset>14</bitOffset>
              <bitWidth>1</bitWidth>
            </field>
            <field>
              <name>MOE</name>
              <bitOffset>15</bitOffset>
              <bitWidth>1</bitWidth>
            </field>
            <field>
              <name>BKF</name>
              <bitOffset>16</bitOffset>
              <bitWidth>4</bitWidth>
            </field>
            <field>
              <name>BK2F</name>
              <bitOffset>20</bitOffset>
              <bitWidth>4</bitWidth>
            </field>
            <field>
              <name>BK2E</name>
              <bitOffset>24</bitOffset>
              <bitWidth>1</bitWidth>
            </field>
            <field>
              <name>BK2P</name>
              <bitOffset>25</bitOffset>
              <bitWidth>1</bitWidth>
            </field>
          </fields>
        </register>
        <register>
          <name>DCR</name>
          <addressOffset>0x48</addressOffset>
          <size>0x20</size>
          <fields>
            <field>
              <name>DBA</name>
              <bitOffset>0</bitOffset>
              <bitWidth>5</bitWidth>
            </field>
            <field>
              <name>DBL</name>
              <bitOffset>8</bitOffset>
              <bitWidth>5</bitWidth>
            </field>
          </fields>
        </register>
        <register>
          <name>DMAR</name>
          <addressOffset>0x4c</addressOffset>
          <size>0x20</size>
          <fields>
            <field>
              <name>DMAB</name>
              <bitOffset>0</bitOffset>
              <bitWidth>16</bitWidth>
            </field>
          </fields>
        </register>
        <register>
          <name>CCMR3</name>
          <addressOffset>0x54</addressOffset>
          <size>0x20</size>
          <fields>
            <field>
              <name>OC5FE</name>
              <bitOffset>2</bitOffset>
              <bitWidth>1</bitWidth>
            </field>
            <field>
              <name>OC5PE</name>
              <bitOffset>3</bitOffset>
              <bitWidth>1</bitWidth>
            </field>
            <field>
              <name>OC5M</name>
              <bitOffset>4</bitOffset>
              <bitWidth>13</bitWidth>
            </field>
            <field>
              <name>OC5CE</name>
              <bitOffset>7</bitOffset>
              <bitWidth>1</bitWidth>
            </field>
            <field>
              <name>OC6FE</name>
              <bitOffset>10</bitOffset>
              <bitWidth>1</bitWidth>
            </field>
            <field>
              <name>OC6PE</name>
              <bitOffset>11</bitOffset>
              <bitWidth>1</bitWidth>
            </field>
            <field>
              <name>OC6M</name>
              <bitOffset>12</bitOffset>
              <bitWidth>13</bitWidth>
            </field>
            <field>
              <name>OC6CE</name>
              <bitOffset>15</bitOffset>
              <bitWidth>1</bitWidth>
            </field>
          </fields>
        </register>
        <register>
          <name>CCR5</name>
          <addressOffset>0x58</addressOffset>
          <size>0x20</size>
          <fields>
            <field>
              <name>CCR5</name>
              <bitOffset>0</bitOffset>
              <bitWidth>32</bitWidth>
            </field>
            <field>
              <name>GC5C1</name>
              <bitOffset>29</bitOffset>
              <bitWidth>1</bitWidth>
            </field>
            <field>
              <name>GC5C2</name>
              <bitOffset>30</bitOffset>
              <bitWidth>1</bitWidth>
            </field>
            <field>
              <name>GC5C3</name>
              <bitOffset>31</bitOffset>
              <bitWidth>1</bitWidth>
            </field>
          </fields>
        </register>
        <register>
          <name>CCR6</name>
          <addressOffset>0x5c</addressOffset>
          <size>0x20</size>
          <fields>
            <field>
              <name>CCR6</name>
              <bitOffset>0</bitOffset>
              <bitWidth>16</bitWidth>
            </field>
          </fields>
        </register>
        <register>
          <name>AF1</name>
          <addressOffset>0x60</addressOffset>
          <size>0x20</size>
        </register>
        <register>
          <name>AF2</name>
          <addressOffset>0x64</addressOffset>
          <size>0x20</size>
        </register>
        <register>
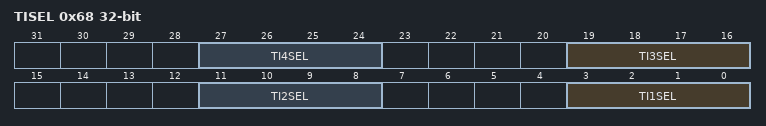
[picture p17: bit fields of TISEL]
          <name>TISEL</name>
          <addressOffset>0x68</addressOffset>
          <size>0x20</size>
          <fields>
            <field>
              <name>TI1SEL</name>
              <bitOffset>0</bitOffset>
              <bitWidth>4</bitWidth>
            </field>
            <field>
              <name>TI2SEL</name>
              <bitOffset>8</bitOffset>
              <bitWidth>4</bitWidth>
            </field>
            <field>
              <name>TI3SEL</name>
              <bitOffset>16</bitOffset>
              <bitWidth>4</bitWidth>
            </field>
            <field>
              <name>TI4SEL</name>
              <bitOffset>24</bitOffset>
              <bitWidth>4</bitWidth>
            </field>
          </fields>
        </register>
      </registers>
    </peripheral>
    <peripheral>
      <name>TIM12</name>
      <baseAddress>0x40001800</baseAddress>
      <registers>
        <register>
          <name>CR1</name>
          <addressOffset>0x0</addressOffset>
          <size>0x20</size>
          <fields>
            <field>
              <name>CEN</name>
              <bitOffset>0</bitOffset>
              <bitWidth>1</bitWidth>
            </field>
            <field>
              <name>UDIS</name>
              <bitOffset>1</bitOffset>
              <bitWidth>1</bitWidth>
            </field>
            <field>
              <name>URS</name>
              <bitOffset>2</bitOffset>
              <bitWidth>1</bitWidth>
            </field>
            <field>
              <name>OPM</name>
              <bitOffset>3</bitOffset>
              <bitWidth>1</bitWidth>
            </field>
            <field>
              <name>DIR</name>
              <bitOffset>4</bitOffset>
              <bitWidth>1</bitWidth>
            </field>
            <field>
              <name>CMS</name>
              <bitOffset>5</bitOffset>
              <bitWidth>2</bitWidth>
            </field>
            <field>
              <name>ARPE</name>
              <bitOffset>7</bitOffset>
              <bitWidth>1</bitWidth>
            </field>
            <field>
              <name>CKD</name>
              <bitOffset>8</bitOffset>
              <bitWidth>2</bitWidth>
            </field>
            <field>
              <name>UIFREMAP</name>
              <bitOffset>11</bitOffset>
              <bitWidth>1</bitWidth>
            </field>
          </fields>
        </register>
        <register>
          <name>CR2</name>
          <addressOffset>0x4</addressOffset>
          <size>0x20</size>
          <fields>
            <field>
              <name>CCPC</name>
              <bitOffset>0</bitOffset>
              <bitWidth>1</bitWidth>
            </field>
            <field>
              <name>CCUS</name>
              <bitOffset>2</bitOffset>
              <bitWidth>1</bitWidth>
            </field>
            <field>
              <name>CCDS</name>
              <bitOffset>3</bitOffset>
              <bitWidth>1</bitWidth>
            </field>
            <field>
              <name>MMS</name>
              <bitOffset>4</bitOffset>
              <bitWidth>3</bitWidth>
            </field>
            <field>
              <name>TI1S</name>
              <bitOffset>7</bitOffset>
              <bitWidth>1</bitWidth>
            </field>
            <field>
              <name>OIS1</name>
              <bitOffset>8</bitOffset>
              <bitWidth>1</bitWidth>
            </field>
            <field>
              <name>OIS1N</name>
              <bitOffset>9</bitOffset>
              <bitWidth>1</bitWidth>
            </field>
            <field>
              <name>OIS2</name>
              <bitOffset>10</bitOffset>
              <bitWidth>1</bitWidth>
            </field>
            <field>
              <name>OIS2N</name>
              <bitOffset>11</bitOffset>
              <bitWidth>1</bitWidth>
            </field>
            <field>
              <name>OIS3</name>
              <bitOffset>12</bitOffset>
              <bitWidth>1</bitWidth>
            </field>
            <field>
              <name>OIS3N</name>
              <bitOffset>13</bitOffset>
              <bitWidth>1</bitWidth>
            </field>
            <field>
              <name>OIS4</name>
              <bitOffset>14</bitOffset>
              <bitWidth>1</bitWidth>
            </field>
            <field>
              <name>OIS5</name>
              <bitOffset>16</bitOffset>
              <bitWidth>1</bitWidth>
            </field>
            <field>
              <name>OIS6</name>
              <bitOffset>18</bitOffset>
              <bitWidth>1</bitWidth>
            </field>
            <field>
              <name>MMS2</name>
              <bitOffset>20</bitOffset>
              <bitWidth>4</bitWidth>
            </field>
          </fields>
        </register>
        <register>
          <name>SMCR</name>
          <addressOffset>0x8</addressOffset>
          <size>0x20</size>
          <fields>
            <field>
              <name>SMS</name>
              <bitOffset>0</bitOffset>
              <bitWidth>17</bitWidth>
            </field>
            <field>
              <name>TS</name>
              <bitOffset>4</bitOffset>
              <bitWidth>18</bitWidth>
            </field>
            <field>
              <name>MSM</name>
              <bitOffset>7</bitOffset>
              <bitWidth>1</bitWidth>
            </field>
            <field>
              <name>ETF</name>
              <bitOffset>8</bitOffset>
              <bitWidth>4</bitWidth>
            </field>
            <field>
              <name>ETPS</name>
              <bitOffset>12</bitOffset>
              <bitWidth>2</bitWidth>
            </field>
            <field>
              <name>ECE</name>
              <bitOffset>14</bitOffset>
              <bitWidth>1</bitWidth>
            </field>
            <field>
              <name>ETP</name>
              <bitOffset>15</bitOffset>
              <bitWidth>1</bitWidth>
            </field>
          </fields>
        </register>
        <register>
          <name>DIER</name>
          <addressOffset>0xc</addressOffset>
          <size>0x20</size>
          <fields>
            <field>
              <name>UIE</name>
              <bitOffset>0</bitOffset>
              <bitWidth>1</bitWidth>
            </field>
            <field>
              <name>CC1IE</name>
              <bitOffset>1</bitOffset>
              <bitWidth>1</bitWidth>
            </field>
            <field>
              <name>CC2IE</name>
              <bitOffset>2</bitOffset>
              <bitWidth>1</bitWidth>
            </field>
            <field>
              <name>CC3IE</name>
              <bitOffset>3</bitOffset>
              <bitWidth>1</bitWidth>
            </field>
            <field>
              <name>CC4IE</name>
              <bitOffset>4</bitOffset>
              <bitWidth>1</bitWidth>
            </field>
            <field>
              <name>COMIE</name>
              <bitOffset>5</bitOffset>
              <bitWidth>1</bitWidth>
            </field>
            <field>
              <name>TIE</name>
              <bitOffset>6</bitOffset>
              <bitWidth>1</bitWidth>
            </field>
            <field>
              <name>BIE</name>
              <bitOffset>7</bitOffset>
              <bitWidth>1</bitWidth>
            </field>
            <field>
              <name>UDE</name>
              <bitOffset>8</bitOffset>
              <bitWidth>1</bitWidth>
            </field>
            <field>
              <name>CC1DE</name>
              <bitOffset>9</bitOffset>
              <bitWidth>1</bitWidth>
            </field>
            <field>
              <name>CC2DE</name>
              <bitOffset>10</bitOffset>
              <bitWidth>1</bitWidth>
            </field>
            <field>
              <name>CC3DE</name>
              <bitOffset>11</bitOffset>
              <bitWidth>1</bitWidth>
            </field>
            <field>
              <name>CC4DE</name>
              <bitOffset>12</bitOffset>
              <bitWidth>1</bitWidth>
            </field>
            <field>
              <name>COMDE</name>
              <bitOffset>13</bitOffset>
              <bitWidth>1</bitWidth>
            </field>
            <field>
              <name>TDE</name>
              <bitOffset>14</bitOffset>
              <bitWidth>1</bitWidth>
            </field>
          </fields>
        </register>
        <register>
          <name>SR</name>
          <addressOffset>0x10</addressOffset>
          <size>0x20</size>
          <fields>
            <field>
              <name>UIF</name>
              <bitOffset>0</bitOffset>
              <bitWidth>1</bitWidth>
            </field>
            <field>
              <name>CC1IF</name>
              <bitOffset>1</bitOffset>
              <bitWidth>1</bitWidth>
            </field>
            <field>
              <name>CC2IF</name>
              <bitOffset>2</bitOffset>
              <bitWidth>1</bitWidth>
            </field>
            <field>
              <name>CC3IF</name>
              <bitOffset>3</bitOffset>
              <bitWidth>1</bitWidth>
            </field>
            <field>
              <name>CC4IF</name>
              <bitOffset>4</bitOffset>
              <bitWidth>1</bitWidth>
            </field>
            <field>
              <name>COMIF</name>
              <bitOffset>5</bitOffset>
              <bitWidth>1</bitWidth>
            </field>
            <field>
              <name>TIF</name>
              <bitOffset>6</bitOffset>
              <bitWidth>1</bitWidth>
            </field>
            <field>
              <name>BIF</name>
              <bitOffset>7</bitOffset>
              <bitWidth>1</bitWidth>
            </field>
            <field>
              <name>B2IF</name>
              <bitOffset>8</bitOffset>
              <bitWidth>1</bitWidth>
            </field>
            <field>
              <name>CC1OF</name>
              <bitOffset>9</bitOffset>
              <bitWidth>1</bitWidth>
            </field>
            <field>
              <name>CC2OF</name>
              <bitOffset>10</bitOffset>
              <bitWidth>1</bitWidth>
            </field>
            <field>
              <name>CC3OF</name>
              <bitOffset>11</bitOffset>
              <bitWidth>1</bitWidth>
            </field>
            <field>
              <name>CC4OF</name>
              <bitOffset>12</bitOffset>
              <bitWidth>1</bitWidth>
            </field>
            <field>
              <name>SBIF</name>
              <bitOffset>13</bitOffset>
              <bitWidth>1</bitWidth>
            </field>
            <field>
              <name>CC5IF</name>
              <bitOffset>16</bitOffset>
              <bitWidth>1</bitWidth>
            </field>
            <field>
              <name>CC6IF</name>
              <bitOffset>17</bitOffset>
              <bitWidth>1</bitWidth>
            </field>
          </fields>
        </register>
        <register>
          <name>EGR</name>
          <addressOffset>0x14</addressOffset>
          <size>0x20</size>
          <fields>
            <field>
              <name>UG</name>
              <bitOffset>0</bitOffset>
              <bitWidth>1</bitWidth>
            </field>
            <field>
              <name>CC1G</name>
              <bitOffset>1</bitOffset>
              <bitWidth>1</bitWidth>
            </field>
            <field>
              <name>CC2G</name>
              <bitOffset>2</bitOffset>
              <bitWidth>1</bitWidth>
            </field>
            <field>
              <name>CC3G</name>
              <bitOffset>3</bitOffset>
              <bitWidth>1</bitWidth>
            </field>
            <field>
              <name>CC4G</name>
              <bitOffset>4</bitOffset>
              <bitWidth>1</bitWidth>
            </field>
            <field>
              <name>COMG</name>
              <bitOffset>5</bitOffset>
              <bitWidth>1</bitWidth>
            </field>
            <field>
              <name>TG</name>
              <bitOffset>6</bitOffset>
              <bitWidth>1</bitWidth>
            </field>
            <field>
              <name>BG</name>
              <bitOffset>7</bitOffset>
              <bitWidth>1</bitWidth>
            </field>
            <field>
              <name>B2G</name>
              <bitOffset>8</bitOffset>
              <bitWidth>1</bitWidth>
            </field>
          </fields>
        </register>
        <register>
          <name>CCMR1</name>
          <addressOffset>0x18</addressOffset>
          <size>0x20</size>
          <fields>
            <field>
              <name>CC1S</name>
              <bitOffset>0</bitOffset>
              <bitWidth>2</bitWidth>
            </field>
            <field>
              <name>OC1FE</name>
              <bitOffset>2</bitOffset>
              <bitWidth>1</bitWidth>
            </field>
            <field>
              <name>OC1PE</name>
              <bitOffset>3</bitOffset>
              <bitWidth>1</bitWidth>
            </field>
            <field>
              <name>OC1M</name>
              <bitOffset>4</bitOffset>
              <bitWidth>13</bitWidth>
            </field>
            <field>
              <name>OC1CE</name>
              <bitOffset>7</bitOffset>
              <bitWidth>1</bitWidth>
            </field>
            <field>
              <name>CC2S</name>
              <bitOffset>8</bitOffset>
              <bitWidth>2</bitWidth>
            </field>
            <field>
              <name>OC2FE</name>
              <bitOffset>10</bitOffset>
              <bitWidth>1</bitWidth>
            </field>
            <field>
              <name>OC2PE</name>
              <bitOffset>11</bitOffset>
              <bitWidth>1</bitWidth>
            </field>
            <field>
              <name>OC2M</name>
              <bitOffset>12</bitOffset>
              <bitWidth>13</bitWidth>
            </field>
            <field>
              <name>OC2CE</name>
              <bitOffset>15</bitOffset>
              <bitWidth>1</bitWidth>
            </field>
          </fields>
        </register>
        <register>
          <name>CCMR2</name>
          <addressOffset>0x1c</addressOffset>
          <size>0x20</size>
          <fields>
            <field>
              <name>CC3S</name>
              <bitOffset>0</bitOffset>
              <bitWidth>2</bitWidth>
            </field>
            <field>
              <name>OC3FE</name>
              <bitOffset>2</bitOffset>
              <bitWidth>1</bitWidth>
            </field>
            <field>
              <name>OC3PE</name>
              <bitOffset>3</bitOffset>
              <bitWidth>1</bitWidth>
            </field>
            <field>
              <name>OC3M</name>
              <bitOffset>4</bitOffset>
              <bitWidth>13</bitWidth>
            </field>
            <field>
              <name>OC3CE</name>
              <bitOffset>7</bitOffset>
              <bitWidth>1</bitWidth>
            </field>
            <field>
              <name>CC4S</name>
              <bitOffset>8</bitOffset>
              <bitWidth>2</bitWidth>
            </field>
            <field>
              <name>OC4FE</name>
              <bitOffset>10</bitOffset>
              <bitWidth>1</bitWidth>
            </field>
            <field>
              <name>OC4PE</name>
              <bitOffset>11</bitOffset>
              <bitWidth>1</bitWidth>
            </field>
            <field>
              <name>OC4M</name>
              <bitOffset>12</bitOffset>
              <bitWidth>13</bitWidth>
            </field>
            <field>
              <name>OC4CE</name>
              <bitOffset>15</bitOffset>
              <bitWidth>1</bitWidth>
            </field>
          </fields>
        </register>
        <register>
          <name>CCER</name>
          <addressOffset>0x20</addressOffset>
          <size>0x20</size>
          <fields>
            <field>
              <name>CC1E</name>
              <bitOffset>0</bitOffset>
              <bitWidth>1</bitWidth>
            </field>
            <field>
              <name>CC1P</name>
              <bitOffset>1</bitOffset>
              <bitWidth>1</bitWidth>
            </field>
            <field>
              <name>CC1NE</name>
              <bitOffset>2</bitOffset>
              <bitWidth>1</bitWidth>
            </field>
            <field>
              <name>CC1NP</name>
              <bitOffset>3</bitOffset>
              <bitWidth>1</bitWidth>
            </field>
            <field>
              <name>CC2E</name>
              <bitOffset>4</bitOffset>
              <bitWidth>1</bitWidth>
            </field>
            <field>
              <name>CC2P</name>
              <bitOffset>5</bitOffset>
              <bitWidth>1</bitWidth>
            </field>
            <field>
              <name>CC2NE</name>
              <bitOffset>6</bitOffset>
              <bitWidth>1</bitWidth>
            </field>
            <field>
              <name>CC2NP</name>
              <bitOffset>7</bitOffset>
              <bitWidth>1</bitWidth>
            </field>
            <field>
              <name>CC3E</name>
              <bitOffset>8</bitOffset>
              <bitWidth>1</bitWidth>
            </field>
            <field>
              <name>CC3P</name>
              <bitOffset>9</bitOffset>
              <bitWidth>1</bitWidth>
            </field>
            <field>
              <name>CC3NE</name>
              <bitOffset>10</bitOffset>
              <bitWidth>1</bitWidth>
            </field>
            <field>
              <name>CC3NP</name>
              <bitOffset>11</bitOffset>
              <bitWidth>1</bitWidth>
            </field>
            <field>
              <name>CC4E</name>
              <bitOffset>12</bitOffset>
              <bitWidth>1</bitWidth>
            </field>
            <field>
              <name>CC4P</name>
              <bitOffset>13</bitOffset>
              <bitWidth>1</bitWidth>
            </field>
            <field>
              <name>CC4NP</name>
              <bitOffset>15</bitOffset>
              <bitWidth>1</bitWidth>
            </field>
            <field>
              <name>CC5E</name>
              <bitOffset>16</bitOffset>
              <bitWidth>1</bitWidth>
            </field>
            <field>
              <name>CC5P</name>
              <bitOffset>17</bitOffset>
              <bitWidth>1</bitWidth>
            </field>
            <field>
              <name>CC6E</name>
              <bitOffset>20</bitOffset>
              <bitWidth>1</bitWidth>
            </field>
            <field>
              <name>CC6P</name>
              <bitOffset>21</bitOffset>
              <bitWidth>1</bitWidth>
            </field>
          </fields>
        </register>
        <register>
          <name>CNT</name>
          <addressOffset>0x24</addressOffset>
          <size>0x20</size>
          <fields>
            <field>
              <name>CNT</name>
              <bitOffset>0</bitOffset>
              <bitWidth>32</bitWidth>
            </field>
            <field>
              <name>UIFCPY</name>
              <bitOffset>31</bitOffset>
              <bitWidth>1</bitWidth>
            </field>
          </fields>
        </register>
        <register>
          <name>PSC</name>
          <addressOffset>0x28</addressOffset>
          <size>0x20</size>
          <fields>
            <field>
              <name>PSC</name>
              <bitOffset>0</bitOffset>
              <bitWidth>16</bitWidth>
            </field>
          </fields>
        </register>
        <register>
          <name>ARR</name>
          <addressOffset>0x2c</addressOffset>
          <size>0x20</size>
          <fields>
            <field>
              <name>ARR</name>
              <bitOffset>0</bitOffset>
              <bitWidth>32</bitWidth>
            </field>
          </fields>
        </register>
        <register>
          <name>RCR</name>
          <addressOffset>0x30</addressOffset>
          <size>0x20</size>
          <fields>
            <field>
              <name>REP</name>
              <bitOffset>0</bitOffset>
              <bitWidth>8</bitWidth>
            </field>
          </fields>
        </register>
        <register>
          <name>CCR1</name>
          <addressOffset>0x34</addressOffset>
          <size>0x20</size>
          <fields>
            <field>
              <name>CCR1</name>
              <bitOffset>0</bitOffset>
              <bitWidth>16</bitWidth>
            </field>
          </fields>
        </register>
        <register>
          <name>CCR2</name>
          <addressOffset>0x38</addressOffset>
          <size>0x20</size>
          <fields>
            <field>
              <name>CCR2</name>
              <bitOffset>0</bitOffset>
              <bitWidth>16</bitWidth>
            </field>
          </fields>
        </register>
        <register>
          <name>CCR3</name>
          <addressOffset>0x3c</addressOffset>
          <size>0x20</size>
          <fields>
            <field>
              <name>CCR3</name>
              <bitOffset>0</bitOffset>
              <bitWidth>16</bitWidth>
            </field>
          </fields>
        </register>
        <register>
          <name>CCR4</name>
          <addressOffset>0x40</addressOffset>
          <size>0x20</size>
          <fields>
            <field>
              <name>CCR4</name>
              <bitOffset>0</bitOffset>
              <bitWidth>16</bitWidth>
            </field>
          </fields>
        </register>
        <register>
          <name>BDTR</name>
          <addressOffset>0x44</addressOffset>
          <size>0x20</size>
          <fields>
            <field>
              <name>DTG</name>
              <bitOffset>0</bitOffset>
              <bitWidth>8</bitWidth>
            </field>
            <field>
              <name>LOCK</name>
              <bitOffset>8</bitOffset>
              <bitWidth>2</bitWidth>
            </field>
            <field>
              <name>OSSI</name>
              <bitOffset>10</bitOffset>
              <bitWidth>1</bitWidth>
            </field>
            <field>
              <name>OSSR</name>
              <bitOffset>11</bitOffset>
              <bitWidth>1</bitWidth>
            </field>
            <field>
              <name>BKE</name>
              <bitOffset>12</bitOffset>
              <bitWidth>1</bitWidth>
            </field>
            <field>
              <name>BKP</name>
              <bitOffset>13</bitOffset>
              <bitWidth>1</bitWidth>
            </field>
            <field>
              <name>AOE</name>
              <bitOffset>14</bitOffset>
              <bitWidth>1</bitWidth>
            </field>
            <field>
              <name>MOE</name>
              <bitOffset>15</bitOffset>
              <bitWidth>1</bitWidth>
            </field>
            <field>
              <name>BKF</name>
              <bitOffset>16</bitOffset>
              <bitWidth>4</bitWidth>
            </field>
            <field>
              <name>BK2F</name>
              <bitOffset>20</bitOffset>
              <bitWidth>4</bitWidth>
            </field>
            <field>
              <name>BK2E</name>
              <bitOffset>24</bitOffset>
              <bitWidth>1</bitWidth>
            </field>
            <field>
              <name>BK2P</name>
              <bitOffset>25</bitOffset>
              <bitWidth>1</bitWidth>
            </field>
          </fields>
        </register>
        <register>
          <name>DCR</name>
          <addressOffset>0x48</addressOffset>
          <size>0x20</size>
          <fields>
            <field>
              <name>DBA</name>
              <bitOffset>0</bitOffset>
              <bitWidth>5</bitWidth>
            </field>
            <field>
              <name>DBL</name>
              <bitOffset>8</bitOffset>
              <bitWidth>5</bitWidth>
            </field>
          </fields>
        </register>
        <register>
          <name>DMAR</name>
          <addressOffset>0x4c</addressOffset>
          <size>0x20</size>
          <fields>
            <field>
              <name>DMAB</name>
              <bitOffset>0</bitOffset>
              <bitWidth>16</bitWidth>
            </field>
          </fields>
        </register>
        <register>
          <name>CCMR3</name>
          <addressOffset>0x54</addressOffset>
          <size>0x20</size>
          <fields>
            <field>
              <name>OC5FE</name>
              <bitOffset>2</bitOffset>
              <bitWidth>1</bitWidth>
            </field>
            <field>
              <name>OC5PE</name>
              <bitOffset>3</bitOffset>
              <bitWidth>1</bitWidth>
            </field>
            <field>
              <name>OC5M</name>
              <bitOffset>4</bitOffset>
              <bitWidth>13</bitWidth>
            </field>
            <field>
              <name>OC5CE</name>
              <bitOffset>7</bitOffset>
              <bitWidth>1</bitWidth>
            </field>
            <field>
              <name>OC6FE</name>
              <bitOffset>10</bitOffset>
              <bitWidth>1</bitWidth>
            </field>
            <field>
              <name>OC6PE</name>
              <bitOffset>11</bitOffset>
              <bitWidth>1</bitWidth>
            </field>
            <field>
              <name>OC6M</name>
              <bitOffset>12</bitOffset>
              <bitWidth>13</bitWidth>
            </field>
            <field>
              <name>OC6CE</name>
              <bitOffset>15</bitOffset>
              <bitWidth>1</bitWidth>
            </field>
          </fields>
        </register>
        <register>
          <name>CCR5</name>
          <addressOffset>0x58</addressOffset>
          <size>0x20</size>
          <fields>
            <field>
              <name>CCR5</name>
              <bitOffset>0</bitOffset>
              <bitWidth>32</bitWidth>
            </field>
            <field>
              <name>GC5C1</name>
              <bitOffset>29</bitOffset>
              <bitWidth>1</bitWidth>
            </field>
            <field>
              <name>GC5C2</name>
              <bitOffset>30</bitOffset>
              <bitWidth>1</bitWidth>
            </field>
            <field>
              <name>GC5C3</name>
              <bitOffset>31</bitOffset>
              <bitWidth>1</bitWidth>
            </field>
          </fields>
        </register>
        <register>
          <name>CCR6</name>
          <addressOffset>0x5c</addressOffset>
          <size>0x20</size>
          <fields>
            <field>
              <name>CCR6</name>
              <bitOffset>0</bitOffset>
              <bitWidth>16</bitWidth>
            </field>
          </fields>
        </register>
        <register>
          <name>AF1</name>
          <addressOffset>0x60</addressOffset>
          <size>0x20</size>
        </register>
        <register>
          <name>AF2</name>
          <addressOffset>0x64</addressOffset>
          <size>0x20</size>
        </register>
        <register>
          <name>TISEL</name>
          <addressOffset>0x68</addressOffset>
          <size>0x20</size>
          <fields>
            <field>
              <name>TI1SEL</name>
              <bitOffset>0</bitOffset>
              <bitWidth>4</bitWidth>
            </field>
            <field>
              <name>TI2SEL</name>
              <bitOffset>8</bitOffset>
              <bitWidth>4</bitWidth>
            </field>
            <field>
              <name>TI3SEL</name>
              <bitOffset>16</bitOffset>
              <bitWidth>4</bitWidth>
            </field>
            <field>
              <name>TI4SEL</name>
              <bitOffset>24</bitOffset>
              <bitWidth>4</bitWidth>
            </field>
          </fields>
        </register>
      </registers>
    </peripheral>
    <peripheral>
      <name>TIM13</name>
      <baseAddress>0x40001c00</baseAddress>
      <registers>
        <register>
          <name>CR1</name>
          <addressOffset>0x0</addressOffset>
          <size>0x20</size>
          <fields>
            <field>
              <name>CEN</name>
              <bitOffset>0</bitOffset>
              <bitWidth>1</bitWidth>
            </field>
            <field>
              <name>UDIS</name>
              <bitOffset>1</bitOffset>
              <bitWidth>1</bitWidth>
            </field>
            <field>
              <name>URS</name>
              <bitOffset>2</bitOffset>
              <bitWidth>1</bitWidth>
            </field>
            <field>
              <name>OPM</name>
              <bitOffset>3</bitOffset>
              <bitWidth>1</bitWidth>
            </field>
            <field>
              <name>DIR</name>
              <bitOffset>4</bitOffset>
              <bitWidth>1</bitWidth>
            </field>
            <field>
              <name>CMS</name>
              <bitOffset>5</bitOffset>
              <bitWidth>2</bitWidth>
            </field>
            <field>
              <name>ARPE</name>
              <bitOffset>7</bitOffset>
              <bitWidth>1</bitWidth>
            </field>
            <field>
              <name>CKD</name>
              <bitOffset>8</bitOffset>
              <bitWidth>2</bitWidth>
            </field>
            <field>
              <name>UIFREMAP</name>
              <bitOffset>11</bitOffset>
              <bitWidth>1</bitWidth>
            </field>
          </fields>
        </register>
        <register>
          <name>CR2</name>
          <addressOffset>0x4</addressOffset>
          <size>0x20</size>
          <fields>
            <field>
              <name>CCPC</name>
              <bitOffset>0</bitOffset>
              <bitWidth>1</bitWidth>
            </field>
            <field>
              <name>CCUS</name>
              <bitOffset>2</bitOffset>
              <bitWidth>1</bitWidth>
            </field>
            <field>
              <name>CCDS</name>
              <bitOffset>3</bitOffset>
              <bitWidth>1</bitWidth>
            </field>
            <field>
              <name>MMS</name>
              <bitOffset>4</bitOffset>
              <bitWidth>3</bitWidth>
            </field>
            <field>
              <name>TI1S</name>
              <bitOffset>7</bitOffset>
              <bitWidth>1</bitWidth>
            </field>
            <field>
              <name>OIS1</name>
              <bitOffset>8</bitOffset>
              <bitWidth>1</bitWidth>
            </field>
            <field>
              <name>OIS1N</name>
              <bitOffset>9</bitOffset>
              <bitWidth>1</bitWidth>
            </field>
            <field>
              <name>OIS2</name>
              <bitOffset>10</bitOffset>
              <bitWidth>1</bitWidth>
            </field>
            <field>
              <name>OIS2N</name>
              <bitOffset>11</bitOffset>
              <bitWidth>1</bitWidth>
            </field>
            <field>
              <name>OIS3</name>
              <bitOffset>12</bitOffset>
              <bitWidth>1</bitWidth>
            </field>
            <field>
              <name>OIS3N</name>
              <bitOffset>13</bitOffset>
              <bitWidth>1</bitWidth>
            </field>
            <field>
              <name>OIS4</name>
              <bitOffset>14</bitOffset>
              <bitWidth>1</bitWidth>
            </field>
            <field>
              <name>OIS5</name>
              <bitOffset>16</bitOffset>
              <bitWidth>1</bitWidth>
            </field>
            <field>
              <name>OIS6</name>
              <bitOffset>18</bitOffset>
              <bitWidth>1</bitWidth>
            </field>
            <field>
              <name>MMS2</name>
              <bitOffset>20</bitOffset>
              <bitWidth>4</bitWidth>
            </field>
          </fields>
        </register>
        <register>
          <name>SMCR</name>
          <addressOffset>0x8</addressOffset>
          <size>0x20</size>
          <fields>
            <field>
              <name>SMS</name>
              <bitOffset>0</bitOffset>
              <bitWidth>17</bitWidth>
            </field>
            <field>
              <name>TS</name>
              <bitOffset>4</bitOffset>
              <bitWidth>18</bitWidth>
            </field>
            <field>
              <name>MSM</name>
              <bitOffset>7</bitOffset>
              <bitWidth>1</bitWidth>
            </field>
            <field>
              <name>ETF</name>
              <bitOffset>8</bitOffset>
              <bitWidth>4</bitWidth>
            </field>
            <field>
              <name>ETPS</name>
              <bitOffset>12</bitOffset>
              <bitWidth>2</bitWidth>
            </field>
            <field>
              <name>ECE</name>
              <bitOffset>14</bitOffset>
              <bitWidth>1</bitWidth>
            </field>
            <field>
              <name>ETP</name>
              <bitOffset>15</bitOffset>
              <bitWidth>1</bitWidth>
            </field>
          </fields>
        </register>
        <register>
          <name>DIER</name>
          <addressOffset>0xc</addressOffset>
          <size>0x20</size>
          <fields>
            <field>
              <name>UIE</name>
              <bitOffset>0</bitOffset>
              <bitWidth>1</bitWidth>
            </field>
            <field>
              <name>CC1IE</name>
              <bitOffset>1</bitOffset>
              <bitWidth>1</bitWidth>
            </field>
            <field>
              <name>CC2IE</name>
              <bitOffset>2</bitOffset>
              <bitWidth>1</bitWidth>
            </field>
            <field>
              <name>CC3IE</name>
              <bitOffset>3</bitOffset>
              <bitWidth>1</bitWidth>
            </field>
            <field>
              <name>CC4IE</name>
              <bitOffset>4</bitOffset>
              <bitWidth>1</bitWidth>
            </field>
            <field>
              <name>COMIE</name>
              <bitOffset>5</bitOffset>
              <bitWidth>1</bitWidth>
            </field>
            <field>
              <name>TIE</name>
              <bitOffset>6</bitOffset>
              <bitWidth>1</bitWidth>
            </field>
            <field>
              <name>BIE</name>
              <bitOffset>7</bitOffset>
              <bitWidth>1</bitWidth>
            </field>
            <field>
              <name>UDE</name>
              <bitOffset>8</bitOffset>
              <bitWidth>1</bitWidth>
            </field>
            <field>
              <name>CC1DE</name>
              <bitOffset>9</bitOffset>
              <bitWidth>1</bitWidth>
            </field>
            <field>
              <name>CC2DE</name>
              <bitOffset>10</bitOffset>
              <bitWidth>1</bitWidth>
            </field>
            <field>
              <name>CC3DE</name>
              <bitOffset>11</bitOffset>
              <bitWidth>1</bitWidth>
            </field>
            <field>
              <name>CC4DE</name>
              <bitOffset>12</bitOffset>
              <bitWidth>1</bitWidth>
            </field>
            <field>
              <name>COMDE</name>
              <bitOffset>13</bitOffset>
              <bitWidth>1</bitWidth>
            </field>
            <field>
              <name>TDE</name>
              <bitOffset>14</bitOffset>
              <bitWidth>1</bitWidth>
            </field>
          </fields>
        </register>
        <register>
          <name>SR</name>
          <addressOffset>0x10</addressOffset>
          <size>0x20</size>
          <fields>
            <field>
              <name>UIF</name>
              <bitOffset>0</bitOffset>
              <bitWidth>1</bitWidth>
            </field>
            <field>
              <name>CC1IF</name>
              <bitOffset>1</bitOffset>
              <bitWidth>1</bitWidth>
            </field>
            <field>
              <name>CC2IF</name>
              <bitOffset>2</bitOffset>
              <bitWidth>1</bitWidth>
            </field>
            <field>
              <name>CC3IF</name>
              <bitOffset>3</bitOffset>
              <bitWidth>1</bitWidth>
            </field>
            <field>
              <name>CC4IF</name>
              <bitOffset>4</bitOffset>
              <bitWidth>1</bitWidth>
            </field>
            <field>
              <name>COMIF</name>
              <bitOffset>5</bitOffset>
              <bitWidth>1</bitWidth>
            </field>
            <field>
              <name>TIF</name>
              <bitOffset>6</bitOffset>
              <bitWidth>1</bitWidth>
            </field>
            <field>
              <name>BIF</name>
              <bitOffset>7</bitOffset>
              <bitWidth>1</bitWidth>
            </field>
            <field>
              <name>B2IF</name>
              <bitOffset>8</bitOffset>
              <bitWidth>1</bitWidth>
            </field>
            <field>
              <name>CC1OF</name>
              <bitOffset>9</bitOffset>
              <bitWidth>1</bitWidth>
            </field>
            <field>
              <name>CC2OF</name>
              <bitOffset>10</bitOffset>
              <bitWidth>1</bitWidth>
            </field>
            <field>
              <name>CC3OF</name>
              <bitOffset>11</bitOffset>
              <bitWidth>1</bitWidth>
            </field>
            <field>
              <name>CC4OF</name>
              <bitOffset>12</bitOffset>
              <bitWidth>1</bitWidth>
            </field>
            <field>
              <name>SBIF</name>
              <bitOffset>13</bitOffset>
              <bitWidth>1</bitWidth>
            </field>
            <field>
              <name>CC5IF</name>
              <bitOffset>16</bitOffset>
              <bitWidth>1</bitWidth>
            </field>
            <field>
              <name>CC6IF</name>
              <bitOffset>17</bitOffset>
              <bitWidth>1</bitWidth>
            </field>
          </fields>
        </register>
        <register>
          <name>EGR</name>
          <addressOffset>0x14</addressOffset>
          <size>0x20</size>
          <fields>
            <field>
              <name>UG</name>
              <bitOffset>0</bitOffset>
              <bitWidth>1</bitWidth>
            </field>
            <field>
              <name>CC1G</name>
              <bitOffset>1</bitOffset>
              <bitWidth>1</bitWidth>
            </field>
            <field>
              <name>CC2G</name>
              <bitOffset>2</bitOffset>
              <bitWidth>1</bitWidth>
            </field>
            <field>
              <name>CC3G</name>
              <bitOffset>3</bitOffset>
              <bitWidth>1</bitWidth>
            </field>
            <field>
              <name>CC4G</name>
              <bitOffset>4</bitOffset>
              <bitWidth>1</bitWidth>
            </field>
            <field>
              <name>COMG</name>
              <bitOffset>5</bitOffset>
              <bitWidth>1</bitWidth>
            </field>
            <field>
              <name>TG</name>
              <bitOffset>6</bitOffset>
              <bitWidth>1</bitWidth>
            </field>
            <field>
              <name>BG</name>
              <bitOffset>7</bitOffset>
              <bitWidth>1</bitWidth>
            </field>
            <field>
              <name>B2G</name>
              <bitOffset>8</bitOffset>
              <bitWidth>1</bitWidth>
            </field>
          </fields>
        </register>
        <register>
          <name>CCMR1</name>
          <addressOffset>0x18</addressOffset>
          <size>0x20</size>
          <fields>
            <field>
              <name>CC1S</name>
              <bitOffset>0</bitOffset>
              <bitWidth>2</bitWidth>
            </field>
            <field>
              <name>OC1FE</name>
              <bitOffset>2</bitOffset>
              <bitWidth>1</bitWidth>
            </field>
            <field>
              <name>OC1PE</name>
              <bitOffset>3</bitOffset>
              <bitWidth>1</bitWidth>
            </field>
            <field>
              <name>OC1M</name>
              <bitOffset>4</bitOffset>
              <bitWidth>13</bitWidth>
            </field>
            <field>
              <name>OC1CE</name>
              <bitOffset>7</bitOffset>
              <bitWidth>1</bitWidth>
            </field>
            <field>
              <name>CC2S</name>
              <bitOffset>8</bitOffset>
              <bitWidth>2</bitWidth>
            </field>
            <field>
              <name>OC2FE</name>
              <bitOffset>10</bitOffset>
              <bitWidth>1</bitWidth>
            </field>
            <field>
              <name>OC2PE</name>
              <bitOffset>11</bitOffset>
              <bitWidth>1</bitWidth>
            </field>
            <field>
              <name>OC2M</name>
              <bitOffset>12</bitOffset>
              <bitWidth>13</bitWidth>
            </field>
            <field>
              <name>OC2CE</name>
              <bitOffset>15</bitOffset>
              <bitWidth>1</bitWidth>
            </field>
          </fields>
        </register>
        <register>
          <name>CCMR2</name>
          <addressOffset>0x1c</addressOffset>
          <size>0x20</size>
          <fields>
            <field>
              <name>CC3S</name>
              <bitOffset>0</bitOffset>
              <bitWidth>2</bitWidth>
            </field>
            <field>
              <name>OC3FE</name>
              <bitOffset>2</bitOffset>
              <bitWidth>1</bitWidth>
            </field>
            <field>
              <name>OC3PE</name>
              <bitOffset>3</bitOffset>
              <bitWidth>1</bitWidth>
            </field>
            <field>
              <name>OC3M</name>
              <bitOffset>4</bitOffset>
              <bitWidth>13</bitWidth>
            </field>
            <field>
              <name>OC3CE</name>
              <bitOffset>7</bitOffset>
              <bitWidth>1</bitWidth>
            </field>
            <field>
              <name>CC4S</name>
              <bitOffset>8</bitOffset>
              <bitWidth>2</bitWidth>
            </field>
            <field>
              <name>OC4FE</name>
              <bitOffset>10</bitOffset>
              <bitWidth>1</bitWidth>
            </field>
            <field>
              <name>OC4PE</name>
              <bitOffset>11</bitOffset>
              <bitWidth>1</bitWidth>
            </field>
            <field>
              <name>OC4M</name>
              <bitOffset>12</bitOffset>
              <bitWidth>13</bitWidth>
            </field>
            <field>
              <name>OC4CE</name>
              <bitOffset>15</bitOffset>
              <bitWidth>1</bitWidth>
            </field>
          </fields>
        </register>
        <register>
          <name>CCER</name>
          <addressOffset>0x20</addressOffset>
          <size>0x20</size>
          <fields>
            <field>
              <name>CC1E</name>
              <bitOffset>0</bitOffset>
              <bitWidth>1</bitWidth>
            </field>
            <field>
              <name>CC1P</name>
              <bitOffset>1</bitOffset>
              <bitWidth>1</bitWidth>
            </field>
            <field>
              <name>CC1NE</name>
              <bitOffset>2</bitOffset>
              <bitWidth>1</bitWidth>
            </field>
            <field>
              <name>CC1NP</name>
              <bitOffset>3</bitOffset>
              <bitWidth>1</bitWidth>
            </field>
            <field>
              <name>CC2E</name>
              <bitOffset>4</bitOffset>
              <bitWidth>1</bitWidth>
            </field>
            <field>
              <name>CC2P</name>
              <bitOffset>5</bitOffset>
              <bitWidth>1</bitWidth>
            </field>
            <field>
              <name>CC2NE</name>
              <bitOffset>6</bitOffset>
              <bitWidth>1</bitWidth>
            </field>
            <field>
              <name>CC2NP</name>
              <bitOffset>7</bitOffset>
              <bitWidth>1</bitWidth>
            </field>
            <field>
              <name>CC3E</name>
              <bitOffset>8</bitOffset>
              <bitWidth>1</bitWidth>
            </field>
            <field>
              <name>CC3P</name>
              <bitOffset>9</bitOffset>
              <bitWidth>1</bitWidth>
            </field>
            <field>
              <name>CC3NE</name>
              <bitOffset>10</bitOffset>
              <bitWidth>1</bitWidth>
            </field>
            <field>
              <name>CC3NP</name>
              <bitOffset>11</bitOffset>
              <bitWidth>1</bitWidth>
            </field>
            <field>
              <name>CC4E</name>
              <bitOffset>12</bitOffset>
              <bitWidth>1</bitWidth>
            </field>
            <field>
              <name>CC4P</name>
              <bitOffset>13</bitOffset>
              <bitWidth>1</bitWidth>
            </field>
            <field>
              <name>CC4NP</name>
              <bitOffset>15</bitOffset>
              <bitWidth>1</bitWidth>
            </field>
            <field>
              <name>CC5E</name>
              <bitOffset>16</bitOffset>
              <bitWidth>1</bitWidth>
            </field>
            <field>
              <name>CC5P</name>
              <bitOffset>17</bitOffset>
              <bitWidth>1</bitWidth>
            </field>
            <field>
              <name>CC6E</name>
              <bitOffset>20</bitOffset>
              <bitWidth>1</bitWidth>
            </field>
            <field>
              <name>CC6P</name>
              <bitOffset>21</bitOffset>
              <bitWidth>1</bitWidth>
            </field>
          </fields>
        </register>
        <register>
          <name>CNT</name>
          <addressOffset>0x24</addressOffset>
          <size>0x20</size>
          <fields>
            <field>
              <name>CNT</name>
              <bitOffset>0</bitOffset>
              <bitWidth>32</bitWidth>
            </field>
            <field>
              <name>UIFCPY</name>
              <bitOffset>31</bitOffset>
              <bitWidth>1</bitWidth>
            </field>
          </fields>
        </register>
        <register>
          <name>PSC</name>
          <addressOffset>0x28</addressOffset>
          <size>0x20</size>
          <fields>
            <field>
              <name>PSC</name>
              <bitOffset>0</bitOffset>
              <bitWidth>16</bitWidth>
            </field>
          </fields>
        </register>
        <register>
          <name>ARR</name>
          <addressOffset>0x2c</addressOffset>
          <size>0x20</size>
          <fields>
            <field>
              <name>ARR</name>
              <bitOffset>0</bitOffset>
              <bitWidth>32</bitWidth>
            </field>
          </fields>
        </register>
        <register>
          <name>RCR</name>
          <addressOffset>0x30</addressOffset>
          <size>0x20</size>
          <fields>
            <field>
              <name>REP</name>
              <bitOffset>0</bitOffset>
              <bitWidth>8</bitWidth>
            </field>
          </fields>
        </register>
        <register>
          <name>CCR1</name>
          <addressOffset>0x34</addressOffset>
          <size>0x20</size>
          <fields>
            <field>
              <name>CCR1</name>
              <bitOffset>0</bitOffset>
              <bitWidth>16</bitWidth>
            </field>
          </fields>
        </register>
        <register>
          <name>CCR2</name>
          <addressOffset>0x38</addressOffset>
          <size>0x20</size>
          <fields>
            <field>
              <name>CCR2</name>
              <bitOffset>0</bitOffset>
              <bitWidth>16</bitWidth>
            </field>
          </fields>
        </register>
        <register>
          <name>CCR3</name>
          <addressOffset>0x3c</addressOffset>
          <size>0x20</size>
          <fields>
            <field>
              <name>CCR3</name>
              <bitOffset>0</bitOffset>
              <bitWidth>16</bitWidth>
            </field>
          </fields>
        </register>
        <register>
          <name>CCR4</name>
          <addressOffset>0x40</addressOffset>
          <size>0x20</size>
          <fields>
            <field>
              <name>CCR4</name>
              <bitOffset>0</bitOffset>
              <bitWidth>16</bitWidth>
            </field>
          </fields>
        </register>
        <register>
          <name>BDTR</name>
          <addressOffset>0x44</addressOffset>
          <size>0x20</size>
          <fields>
            <field>
              <name>DTG</name>
              <bitOffset>0</bitOffset>
              <bitWidth>8</bitWidth>
            </field>
            <field>
              <name>LOCK</name>
              <bitOffset>8</bitOffset>
              <bitWidth>2</bitWidth>
            </field>
            <field>
              <name>OSSI</name>
              <bitOffset>10</bitOffset>
              <bitWidth>1</bitWidth>
            </field>
            <field>
              <name>OSSR</name>
              <bitOffset>11</bitOffset>
              <bitWidth>1</bitWidth>
            </field>
            <field>
              <name>BKE</name>
              <bitOffset>12</bitOffset>
              <bitWidth>1</bitWidth>
            </field>
            <field>
              <name>BKP</name>
              <bitOffset>13</bitOffset>
              <bitWidth>1</bitWidth>
            </field>
            <field>
              <name>AOE</name>
              <bitOffset>14</bitOffset>
              <bitWidth>1</bitWidth>
            </field>
            <field>
              <name>MOE</name>
              <bitOffset>15</bitOffset>
              <bitWidth>1</bitWidth>
            </field>
            <field>
              <name>BKF</name>
              <bitOffset>16</bitOffset>
              <bitWidth>4</bitWidth>
            </field>
            <field>
              <name>BK2F</name>
              <bitOffset>20</bitOffset>
              <bitWidth>4</bitWidth>
            </field>
            <field>
              <name>BK2E</name>
              <bitOffset>24</bitOffset>
              <bitWidth>1</bitWidth>
            </field>
            <field>
              <name>BK2P</name>
              <bitOffset>25</bitOffset>
              <bitWidth>1</bitWidth>
            </field>
          </fields>
        </register>
        <register>
          <name>DCR</name>
          <addressOffset>0x48</addressOffset>
          <size>0x20</size>
          <fields>
            <field>
              <name>DBA</name>
              <bitOffset>0</bitOffset>
              <bitWidth>5</bitWidth>
            </field>
            <field>
              <name>DBL</name>
              <bitOffset>8</bitOffset>
              <bitWidth>5</bitWidth>
            </field>
          </fields>
        </register>
        <register>
          <name>DMAR</name>
          <addressOffset>0x4c</addressOffset>
          <size>0x20</size>
          <fields>
            <field>
              <name>DMAB</name>
              <bitOffset>0</bitOffset>
              <bitWidth>16</bitWidth>
            </field>
          </fields>
        </register>
        <register>
          <name>CCMR3</name>
          <addressOffset>0x54</addressOffset>
          <size>0x20</size>
          <fields>
            <field>
              <name>OC5FE</name>
              <bitOffset>2</bitOffset>
              <bitWidth>1</bitWidth>
            </field>
            <field>
              <name>OC5PE</name>
              <bitOffset>3</bitOffset>
              <bitWidth>1</bitWidth>
            </field>
            <field>
              <name>OC5M</name>
              <bitOffset>4</bitOffset>
              <bitWidth>13</bitWidth>
            </field>
            <field>
              <name>OC5CE</name>
              <bitOffset>7</bitOffset>
              <bitWidth>1</bitWidth>
            </field>
            <field>
              <name>OC6FE</name>
              <bitOffset>10</bitOffset>
              <bitWidth>1</bitWidth>
            </field>
            <field>
              <name>OC6PE</name>
              <bitOffset>11</bitOffset>
              <bitWidth>1</bitWidth>
            </field>
            <field>
              <name>OC6M</name>
              <bitOffset>12</bitOffset>
              <bitWidth>13</bitWidth>
            </field>
            <field>
              <name>OC6CE</name>
              <bitOffset>15</bitOffset>
              <bitWidth>1</bitWidth>
            </field>
          </fields>
        </register>
        <register>
          <name>CCR5</name>
          <addressOffset>0x58</addressOffset>
          <size>0x20</size>
          <fields>
            <field>
              <name>CCR5</name>
              <bitOffset>0</bitOffset>
              <bitWidth>32</bitWidth>
            </field>
            <field>
              <name>GC5C1</name>
              <bitOffset>29</bitOffset>
              <bitWidth>1</bitWidth>
            </field>
            <field>
              <name>GC5C2</name>
              <bitOffset>30</bitOffset>
              <bitWidth>1</bitWidth>
            </field>
            <field>
              <name>GC5C3</name>
              <bitOffset>31</bitOffset>
              <bitWidth>1</bitWidth>
            </field>
          </fields>
        </register>
        <register>
          <name>CCR6</name>
          <addressOffset>0x5c</addressOffset>
          <size>0x20</size>
          <fields>
            <field>
              <name>CCR6</name>
              <bitOffset>0</bitOffset>
              <bitWidth>16</bitWidth>
            </field>
          </fields>
        </register>
        <register>
          <name>AF1</name>
          <addressOffset>0x60</addressOffset>
          <size>0x20</size>
        </register>
        <register>
          <name>AF2</name>
          <addressOffset>0x64</addressOffset>
          <size>0x20</size>
        </register>
        <register>
          <name>TISEL</name>
          <addressOffset>0x68</addressOffset>
          <size>0x20</size>
          <fields>
            <field>
              <name>TI1SEL</name>
              <bitOffset>0</bitOffset>
              <bitWidth>4</bitWidth>
            </field>
            <field>
              <name>TI2SEL</name>
              <bitOffset>8</bitOffset>
              <bitWidth>4</bitWidth>
            </field>
            <field>
              <name>TI3SEL</name>
              <bitOffset>16</bitOffset>
              <bitWidth>4</bitWidth>
            </field>
            <field>
              <name>TI4SEL</name>
              <bitOffset>24</bitOffset>
              <bitWidth>4</bitWidth>
            </field>
          </fields>
        </register>
      </registers>
    </peripheral>
    <peripheral>
      <name>TIM14</name>
      <baseAddress>0x40002000</baseAddress>
      <registers>
        <register>
          <name>CR1</name>
          <addressOffset>0x0</addressOffset>
          <size>0x20</size>
          <fields>
            <field>
              <name>CEN</name>
              <bitOffset>0</bitOffset>
              <bitWidth>1</bitWidth>
            </field>
            <field>
              <name>UDIS</name>
              <bitOffset>1</bitOffset>
              <bitWidth>1</bitWidth>
            </field>
            <field>
              <name>URS</name>
              <bitOffset>2</bitOffset>
              <bitWidth>1</bitWidth>
            </field>
            <field>
              <name>OPM</name>
              <bitOffset>3</bitOffset>
              <bitWidth>1</bitWidth>
            </field>
            <field>
              <name>DIR</name>
              <bitOffset>4</bitOffset>
              <bitWidth>1</bitWidth>
            </field>
            <field>
              <name>CMS</name>
              <bitOffset>5</bitOffset>
              <bitWidth>2</bitWidth>
            </field>
            <field>
              <name>ARPE</name>
              <bitOffset>7</bitOffset>
              <bitWidth>1</bitWidth>
            </field>
            <field>
              <name>CKD</name>
              <bitOffset>8</bitOffset>
              <bitWidth>2</bitWidth>
            </field>
            <field>
              <name>UIFREMAP</name>
              <bitOffset>11</bitOffset>
              <bitWidth>1</bitWidth>
            </field>
          </fields>
        </register>
        <register>
          <name>CR2</name>
          <addressOffset>0x4</addressOffset>
          <size>0x20</size>
          <fields>
            <field>
              <name>CCPC</name>
              <bitOffset>0</bitOffset>
              <bitWidth>1</bitWidth>
            </field>
            <field>
              <name>CCUS</name>
              <bitOffset>2</bitOffset>
              <bitWidth>1</bitWidth>
            </field>
            <field>
              <name>CCDS</name>
              <bitOffset>3</bitOffset>
              <bitWidth>1</bitWidth>
            </field>
            <field>
              <name>MMS</name>
              <bitOffset>4</bitOffset>
              <bitWidth>3</bitWidth>
            </field>
            <field>
              <name>TI1S</name>
              <bitOffset>7</bitOffset>
              <bitWidth>1</bitWidth>
            </field>
            <field>
              <name>OIS1</name>
              <bitOffset>8</bitOffset>
              <bitWidth>1</bitWidth>
            </field>
            <field>
              <name>OIS1N</name>
              <bitOffset>9</bitOffset>
              <bitWidth>1</bitWidth>
            </field>
            <field>
              <name>OIS2</name>
              <bitOffset>10</bitOffset>
              <bitWidth>1</bitWidth>
            </field>
            <field>
              <name>OIS2N</name>
              <bitOffset>11</bitOffset>
              <bitWidth>1</bitWidth>
            </field>
            <field>
              <name>OIS3</name>
              <bitOffset>12</bitOffset>
              <bitWidth>1</bitWidth>
            </field>
            <field>
              <name>OIS3N</name>
              <bitOffset>13</bitOffset>
              <bitWidth>1</bitWidth>
            </field>
            <field>
              <name>OIS4</name>
              <bitOffset>14</bitOffset>
              <bitWidth>1</bitWidth>
            </field>
            <field>
              <name>OIS5</name>
              <bitOffset>16</bitOffset>
              <bitWidth>1</bitWidth>
            </field>
            <field>
              <name>OIS6</name>
              <bitOffset>18</bitOffset>
              <bitWidth>1</bitWidth>
            </field>
            <field>
              <name>MMS2</name>
              <bitOffset>20</bitOffset>
              <bitWidth>4</bitWidth>
            </field>
          </fields>
        </register>
        <register>
          <name>SMCR</name>
          <addressOffset>0x8</addressOffset>
          <size>0x20</size>
          <fields>
            <field>
              <name>SMS</name>
              <bitOffset>0</bitOffset>
              <bitWidth>17</bitWidth>
            </field>
            <field>
              <name>TS</name>
              <bitOffset>4</bitOffset>
              <bitWidth>18</bitWidth>
            </field>
            <field>
              <name>MSM</name>
              <bitOffset>7</bitOffset>
              <bitWidth>1</bitWidth>
            </field>
            <field>
              <name>ETF</name>
              <bitOffset>8</bitOffset>
              <bitWidth>4</bitWidth>
            </field>
            <field>
              <name>ETPS</name>
              <bitOffset>12</bitOffset>
              <bitWidth>2</bitWidth>
            </field>
            <field>
              <name>ECE</name>
              <bitOffset>14</bitOffset>
              <bitWidth>1</bitWidth>
            </field>
            <field>
              <name>ETP</name>
              <bitOffset>15</bitOffset>
              <bitWidth>1</bitWidth>
            </field>
          </fields>
        </register>
        <register>
          <name>DIER</name>
          <addressOffset>0xc</addressOffset>
          <size>0x20</size>
          <fields>
            <field>
              <name>UIE</name>
              <bitOffset>0</bitOffset>
              <bitWidth>1</bitWidth>
            </field>
            <field>
              <name>CC1IE</name>
              <bitOffset>1</bitOffset>
              <bitWidth>1</bitWidth>
            </field>
            <field>
              <name>CC2IE</name>
              <bitOffset>2</bitOffset>
              <bitWidth>1</bitWidth>
            </field>
            <field>
              <name>CC3IE</name>
              <bitOffset>3</bitOffset>
              <bitWidth>1</bitWidth>
            </field>
            <field>
              <name>CC4IE</name>
              <bitOffset>4</bitOffset>
              <bitWidth>1</bitWidth>
            </field>
            <field>
              <name>COMIE</name>
              <bitOffset>5</bitOffset>
              <bitWidth>1</bitWidth>
            </field>
            <field>
              <name>TIE</name>
              <bitOffset>6</bitOffset>
              <bitWidth>1</bitWidth>
            </field>
            <field>
              <name>BIE</name>
              <bitOffset>7</bitOffset>
              <bitWidth>1</bitWidth>
            </field>
            <field>
              <name>UDE</name>
              <bitOffset>8</bitOffset>
              <bitWidth>1</bitWidth>
            </field>
            <field>
              <name>CC1DE</name>
              <bitOffset>9</bitOffset>
              <bitWidth>1</bitWidth>
            </field>
            <field>
              <name>CC2DE</name>
              <bitOffset>10</bitOffset>
              <bitWidth>1</bitWidth>
            </field>
            <field>
              <name>CC3DE</name>
              <bitOffset>11</bitOffset>
              <bitWidth>1</bitWidth>
            </field>
            <field>
              <name>CC4DE</name>
              <bitOffset>12</bitOffset>
              <bitWidth>1</bitWidth>
            </field>
            <field>
              <name>COMDE</name>
              <bitOffset>13</bitOffset>
              <bitWidth>1</bitWidth>
            </field>
            <field>
              <name>TDE</name>
              <bitOffset>14</bitOffset>
              <bitWidth>1</bitWidth>
            </field>
          </fields>
        </register>
        <register>
          <name>SR</name>
          <addressOffset>0x10</addressOffset>
          <size>0x20</size>
          <fields>
            <field>
              <name>UIF</name>
              <bitOffset>0</bitOffset>
              <bitWidth>1</bitWidth>
            </field>
            <field>
              <name>CC1IF</name>
              <bitOffset>1</bitOffset>
              <bitWidth>1</bitWidth>
            </field>
            <field>
              <name>CC2IF</name>
              <bitOffset>2</bitOffset>
              <bitWidth>1</bitWidth>
            </field>
            <field>
              <name>CC3IF</name>
              <bitOffset>3</bitOffset>
              <bitWidth>1</bitWidth>
            </field>
            <field>
              <name>CC4IF</name>
              <bitOffset>4</bitOffset>
              <bitWidth>1</bitWidth>
            </field>
            <field>
              <name>COMIF</name>
              <bitOffset>5</bitOffset>
              <bitWidth>1</bitWidth>
            </field>
            <field>
              <name>TIF</name>
              <bitOffset>6</bitOffset>
              <bitWidth>1</bitWidth>
            </field>
            <field>
              <name>BIF</name>
              <bitOffset>7</bitOffset>
              <bitWidth>1</bitWidth>
            </field>
            <field>
              <name>B2IF</name>
              <bitOffset>8</bitOffset>
              <bitWidth>1</bitWidth>
            </field>
            <field>
              <name>CC1OF</name>
              <bitOffset>9</bitOffset>
              <bitWidth>1</bitWidth>
            </field>
            <field>
              <name>CC2OF</name>
              <bitOffset>10</bitOffset>
              <bitWidth>1</bitWidth>
            </field>
            <field>
              <name>CC3OF</name>
              <bitOffset>11</bitOffset>
              <bitWidth>1</bitWidth>
            </field>
            <field>
              <name>CC4OF</name>
              <bitOffset>12</bitOffset>
              <bitWidth>1</bitWidth>
            </field>
            <field>
              <name>SBIF</name>
              <bitOffset>13</bitOffset>
              <bitWidth>1</bitWidth>
            </field>
            <field>
              <name>CC5IF</name>
              <bitOffset>16</bitOffset>
              <bitWidth>1</bitWidth>
            </field>
            <field>
              <name>CC6IF</name>
              <bitOffset>17</bitOffset>
              <bitWidth>1</bitWidth>
            </field>
          </fields>
        </register>
        <register>
          <name>EGR</name>
          <addressOffset>0x14</addressOffset>
          <size>0x20</size>
          <fields>
            <field>
              <name>UG</name>
              <bitOffset>0</bitOffset>
              <bitWidth>1</bitWidth>
            </field>
            <field>
              <name>CC1G</name>
              <bitOffset>1</bitOffset>
              <bitWidth>1</bitWidth>
            </field>
            <field>
              <name>CC2G</name>
              <bitOffset>2</bitOffset>
              <bitWidth>1</bitWidth>
            </field>
            <field>
              <name>CC3G</name>
              <bitOffset>3</bitOffset>
              <bitWidth>1</bitWidth>
            </field>
            <field>
              <name>CC4G</name>
              <bitOffset>4</bitOffset>
              <bitWidth>1</bitWidth>
            </field>
            <field>
              <name>COMG</name>
              <bitOffset>5</bitOffset>
              <bitWidth>1</bitWidth>
            </field>
            <field>
              <name>TG</name>
              <bitOffset>6</bitOffset>
              <bitWidth>1</bitWidth>
            </field>
            <field>
              <name>BG</name>
              <bitOffset>7</bitOffset>
              <bitWidth>1</bitWidth>
            </field>
            <field>
              <name>B2G</name>
              <bitOffset>8</bitOffset>
              <bitWidth>1</bitWidth>
            </field>
          </fields>
        </register>
        <register>
          <name>CCMR1</name>
          <addressOffset>0x18</addressOffset>
          <size>0x20</size>
          <fields>
            <field>
              <name>CC1S</name>
              <bitOffset>0</bitOffset>
              <bitWidth>2</bitWidth>
            </field>
            <field>
              <name>OC1FE</name>
              <bitOffset>2</bitOffset>
              <bitWidth>1</bitWidth>
            </field>
            <field>
              <name>OC1PE</name>
              <bitOffset>3</bitOffset>
              <bitWidth>1</bitWidth>
            </field>
            <field>
              <name>OC1M</name>
              <bitOffset>4</bitOffset>
              <bitWidth>13</bitWidth>
            </field>
            <field>
              <name>OC1CE</name>
              <bitOffset>7</bitOffset>
              <bitWidth>1</bitWidth>
            </field>
            <field>
              <name>CC2S</name>
              <bitOffset>8</bitOffset>
              <bitWidth>2</bitWidth>
            </field>
            <field>
              <name>OC2FE</name>
              <bitOffset>10</bitOffset>
              <bitWidth>1</bitWidth>
            </field>
            <field>
              <name>OC2PE</name>
              <bitOffset>11</bitOffset>
              <bitWidth>1</bitWidth>
            </field>
            <field>
              <name>OC2M</name>
              <bitOffset>12</bitOffset>
              <bitWidth>13</bitWidth>
            </field>
            <field>
              <name>OC2CE</name>
              <bitOffset>15</bitOffset>
              <bitWidth>1</bitWidth>
            </field>
          </fields>
        </register>
        <register>
          <name>CCMR2</name>
          <addressOffset>0x1c</addressOffset>
          <size>0x20</size>
          <fields>
            <field>
              <name>CC3S</name>
              <bitOffset>0</bitOffset>
              <bitWidth>2</bitWidth>
            </field>
            <field>
              <name>OC3FE</name>
              <bitOffset>2</bitOffset>
              <bitWidth>1</bitWidth>
            </field>
            <field>
              <name>OC3PE</name>
              <bitOffset>3</bitOffset>
              <bitWidth>1</bitWidth>
            </field>
            <field>
              <name>OC3M</name>
              <bitOffset>4</bitOffset>
              <bitWidth>13</bitWidth>
            </field>
            <field>
              <name>OC3CE</name>
              <bitOffset>7</bitOffset>
              <bitWidth>1</bitWidth>
            </field>
            <field>
              <name>CC4S</name>
              <bitOffset>8</bitOffset>
              <bitWidth>2</bitWidth>
            </field>
            <field>
              <name>OC4FE</name>
              <bitOffset>10</bitOffset>
              <bitWidth>1</bitWidth>
            </field>
            <field>
              <name>OC4PE</name>
              <bitOffset>11</bitOffset>
              <bitWidth>1</bitWidth>
            </field>
            <field>
              <name>OC4M</name>
              <bitOffset>12</bitOffset>
              <bitWidth>13</bitWidth>
            </field>
            <field>
              <name>OC4CE</name>
              <bitOffset>15</bitOffset>
              <bitWidth>1</bitWidth>
            </field>
          </fields>
        </register>
        <register>
          <name>CCER</name>
          <addressOffset>0x20</addressOffset>
          <size>0x20</size>
          <fields>
            <field>
              <name>CC1E</name>
              <bitOffset>0</bitOffset>
              <bitWidth>1</bitWidth>
            </field>
            <field>
              <name>CC1P</name>
              <bitOffset>1</bitOffset>
              <bitWidth>1</bitWidth>
            </field>
            <field>
              <name>CC1NE</name>
              <bitOffset>2</bitOffset>
              <bitWidth>1</bitWidth>
            </field>
            <field>
              <name>CC1NP</name>
              <bitOffset>3</bitOffset>
              <bitWidth>1</bitWidth>
            </field>
            <field>
              <name>CC2E</name>
              <bitOffset>4</bitOffset>
              <bitWidth>1</bitWidth>
            </field>
            <field>
              <name>CC2P</name>
              <bitOffset>5</bitOffset>
              <bitWidth>1</bitWidth>
            </field>
            <field>
              <name>CC2NE</name>
              <bitOffset>6</bitOffset>
              <bitWidth>1</bitWidth>
            </field>
            <field>
              <name>CC2NP</name>
              <bitOffset>7</bitOffset>
              <bitWidth>1</bitWidth>
            </field>
            <field>
              <name>CC3E</name>
              <bitOffset>8</bitOffset>
              <bitWidth>1</bitWidth>
            </field>
            <field>
              <name>CC3P</name>
              <bitOffset>9</bitOffset>
              <bitWidth>1</bitWidth>
            </field>
            <field>
              <name>CC3NE</name>
              <bitOffset>10</bitOffset>
              <bitWidth>1</bitWidth>
            </field>
            <field>
              <name>CC3NP</name>
              <bitOffset>11</bitOffset>
              <bitWidth>1</bitWidth>
            </field>
            <field>
              <name>CC4E</name>
              <bitOffset>12</bitOffset>
              <bitWidth>1</bitWidth>
            </field>
            <field>
              <name>CC4P</name>
              <bitOffset>13</bitOffset>
              <bitWidth>1</bitWidth>
            </field>
            <field>
              <name>CC4NP</name>
              <bitOffset>15</bitOffset>
              <bitWidth>1</bitWidth>
            </field>
            <field>
              <name>CC5E</name>
              <bitOffset>16</bitOffset>
              <bitWidth>1</bitWidth>
            </field>
            <field>
              <name>CC5P</name>
              <bitOffset>17</bitOffset>
              <bitWidth>1</bitWidth>
            </field>
            <field>
              <name>CC6E</name>
              <bitOffset>20</bitOffset>
              <bitWidth>1</bitWidth>
            </field>
            <field>
              <name>CC6P</name>
              <bitOffset>21</bitOffset>
              <bitWidth>1</bitWidth>
            </field>
          </fields>
        </register>
        <register>
          <name>CNT</name>
          <addressOffset>0x24</addressOffset>
          <size>0x20</size>
          <fields>
            <field>
              <name>CNT</name>
              <bitOffset>0</bitOffset>
              <bitWidth>32</bitWidth>
            </field>
            <field>
              <name>UIFCPY</name>
              <bitOffset>31</bitOffset>
              <bitWidth>1</bitWidth>
            </field>
          </fields>
        </register>
        <register>
          <name>PSC</name>
          <addressOffset>0x28</addressOffset>
          <size>0x20</size>
          <fields>
            <field>
              <name>PSC</name>
              <bitOffset>0</bitOffset>
              <bitWidth>16</bitWidth>
            </field>
          </fields>
        </register>
        <register>
          <name>ARR</name>
          <addressOffset>0x2c</addressOffset>
          <size>0x20</size>
          <fields>
            <field>
              <name>ARR</name>
              <bitOffset>0</bitOffset>
              <bitWidth>32</bitWidth>
            </field>
          </fields>
        </register>
        <register>
          <name>RCR</name>
          <addressOffset>0x30</addressOffset>
          <size>0x20</size>
          <fields>
            <field>
              <name>REP</name>
              <bitOffset>0</bitOffset>
              <bitWidth>8</bitWidth>
            </field>
          </fields>
        </register>
        <register>
          <name>CCR1</name>
          <addressOffset>0x34</addressOffset>
          <size>0x20</size>
          <fields>
            <field>
              <name>CCR1</name>
              <bitOffset>0</bitOffset>
              <bitWidth>16</bitWidth>
            </field>
          </fields>
        </register>
        <register>
          <name>CCR2</name>
          <addressOffset>0x38</addressOffset>
          <size>0x20</size>
          <fields>
            <field>
              <name>CCR2</name>
              <bitOffset>0</bitOffset>
              <bitWidth>16</bitWidth>
            </field>
          </fields>
        </register>
        <register>
          <name>CCR3</name>
          <addressOffset>0x3c</addressOffset>
          <size>0x20</size>
          <fields>
            <field>
              <name>CCR3</name>
              <bitOffset>0</bitOffset>
              <bitWidth>16</bitWidth>
            </field>
          </fields>
        </register>
        <register>
          <name>CCR4</name>
          <addressOffset>0x40</addressOffset>
          <size>0x20</size>
          <fields>
            <field>
              <name>CCR4</name>
              <bitOffset>0</bitOffset>
              <bitWidth>16</bitWidth>
            </field>
          </fields>
        </register>
        <register>
          <name>BDTR</name>
          <addressOffset>0x44</addressOffset>
          <size>0x20</size>
          <fields>
            <field>
              <name>DTG</name>
              <bitOffset>0</bitOffset>
              <bitWidth>8</bitWidth>
            </field>
            <field>
              <name>LOCK</name>
              <bitOffset>8</bitOffset>
              <bitWidth>2</bitWidth>
            </field>
            <field>
              <name>OSSI</name>
              <bitOffset>10</bitOffset>
              <bitWidth>1</bitWidth>
            </field>
            <field>
              <name>OSSR</name>
              <bitOffset>11</bitOffset>
              <bitWidth>1</bitWidth>
            </field>
            <field>
              <name>BKE</name>
              <bitOffset>12</bitOffset>
              <bitWidth>1</bitWidth>
            </field>
            <field>
              <name>BKP</name>
              <bitOffset>13</bitOffset>
              <bitWidth>1</bitWidth>
            </field>
            <field>
              <name>AOE</name>
              <bitOffset>14</bitOffset>
              <bitWidth>1</bitWidth>
            </field>
            <field>
              <name>MOE</name>
              <bitOffset>15</bitOffset>
              <bitWidth>1</bitWidth>
            </field>
            <field>
              <name>BKF</name>
              <bitOffset>16</bitOffset>
              <bitWidth>4</bitWidth>
            </field>
            <field>
              <name>BK2F</name>
              <bitOffset>20</bitOffset>
              <bitWidth>4</bitWidth>
            </field>
            <field>
              <name>BK2E</name>
              <bitOffset>24</bitOffset>
              <bitWidth>1</bitWidth>
            </field>
            <field>
              <name>BK2P</name>
              <bitOffset>25</bitOffset>
              <bitWidth>1</bitWidth>
            </field>
          </fields>
        </register>
        <register>
          <name>DCR</name>
          <addressOffset>0x48</addressOffset>
          <size>0x20</size>
          <fields>
            <field>
              <name>DBA</name>
              <bitOffset>0</bitOffset>
              <bitWidth>5</bitWidth>
            </field>
            <field>
              <name>DBL</name>
              <bitOffset>8</bitOffset>
              <bitWidth>5</bitWidth>
            </field>
          </fields>
        </register>
        <register>
          <name>DMAR</name>
          <addressOffset>0x4c</addressOffset>
          <size>0x20</size>
          <fields>
            <field>
              <name>DMAB</name>
              <bitOffset>0</bitOffset>
              <bitWidth>16</bitWidth>
            </field>
          </fields>
        </register>
        <register>
          <name>CCMR3</name>
          <addressOffset>0x54</addressOffset>
          <size>0x20</size>
          <fields>
            <field>
              <name>OC5FE</name>
              <bitOffset>2</bitOffset>
              <bitWidth>1</bitWidth>
            </field>
            <field>
              <name>OC5PE</name>
              <bitOffset>3</bitOffset>
              <bitWidth>1</bitWidth>
            </field>
            <field>
              <name>OC5M</name>
              <bitOffset>4</bitOffset>
              <bitWidth>13</bitWidth>
            </field>
            <field>
              <name>OC5CE</name>
              <bitOffset>7</bitOffset>
              <bitWidth>1</bitWidth>
            </field>
            <field>
              <name>OC6FE</name>
              <bitOffset>10</bitOffset>
              <bitWidth>1</bitWidth>
            </field>
            <field>
              <name>OC6PE</name>
              <bitOffset>11</bitOffset>
              <bitWidth>1</bitWidth>
            </field>
            <field>
              <name>OC6M</name>
              <bitOffset>12</bitOffset>
              <bitWidth>13</bitWidth>
            </field>
            <field>
              <name>OC6CE</name>
              <bitOffset>15</bitOffset>
              <bitWidth>1</bitWidth>
            </field>
          </fields>
        </register>
        <register>
          <name>CCR5</name>
          <addressOffset>0x58</addressOffset>
          <size>0x20</size>
          <fields>
            <field>
              <name>CCR5</name>
              <bitOffset>0</bitOffset>
              <bitWidth>32</bitWidth>
            </field>
            <field>
              <name>GC5C1</name>
              <bitOffset>29</bitOffset>
              <bitWidth>1</bitWidth>
            </field>
            <field>
              <name>GC5C2</name>
              <bitOffset>30</bitOffset>
              <bitWidth>1</bitWidth>
            </field>
            <field>
              <name>GC5C3</name>
              <bitOffset>31</bitOffset>
              <bitWidth>1</bitWidth>
            </field>
          </fields>
        </register>
        <register>
          <name>CCR6</name>
          <addressOffset>0x5c</addressOffset>
          <size>0x20</size>
          <fields>
            <field>
              <name>CCR6</name>
              <bitOffset>0</bitOffset>
              <bitWidth>16</bitWidth>
            </field>
          </fields>
        </register>
        <register>
          <name>AF1</name>
          <addressOffset>0x60</addressOffset>
          <size>0x20</size>
        </register>
        <register>
          <name>AF2</name>
          <addressOffset>0x64</addressOffset>
          <size>0x20</size>
        </register>
        <register>
          <name>TISEL</name>
          <addressOffset>0x68</addressOffset>
          <size>0x20</size>
          <fields>
            <field>
              <name>TI1SEL</name>
              <bitOffset>0</bitOffset>
              <bitWidth>4</bitWidth>
            </field>
            <field>
              <name>TI2SEL</name>
              <bitOffset>8</bitOffset>
              <bitWidth>4</bitWidth>
            </field>
            <field>
              <name>TI3SEL</name>
              <bitOffset>16</bitOffset>
              <bitWidth>4</bitWidth>
            </field>
            <field>
              <name>TI4SEL</name>
              <bitOffset>24</bitOffset>
              <bitWidth>4</bitWidth>
            </field>
          </fields>
        </register>
      </registers>
    </peripheral>
    <peripheral>
      <name>LPTIM1</name>
      <baseAddress>0x40002400</baseAddress>
      <registers>
        <register>
          <name>ISR</name>
          <addressOffset>0x0</addressOffset>
          <size>0x20</size>
          <fields>
            <field>
              <name>CMPM</name>
              <bitOffset>0</bitOffset>
              <bitWidth>1</bitWidth>
            </field>
            <field>
              <name>ARRM</name>
              <bitOffset>1</bitOffset>
              <bitWidth>1</bitWidth>
            </field>
            <field>
              <name>EXTTRIG</name>
              <bitOffset>2</bitOffset>
              <bitWidth>1</bitWidth>
            </field>
            <field>
              <name>CMPOK</name>
              <bitOffset>3</bitOffset>
              <bitWidth>1</bitWidth>
            </field>
            <field>
              <name>ARROK</name>
              <bitOffset>4</bitOffset>
              <bitWidth>1</bitWidth>
            </field>
            <field>
              <name>UP</name>
              <bitOffset>5</bitOffset>
              <bitWidth>1</bitWidth>
            </field>
            <field>
              <name>DOWN</name>
              <bitOffset>6</bitOffset>
              <bitWidth>1</bitWidth>
            </field>
          </fields>
        </register>
        <register>
          <name>ICR</name>
          <addressOffset>0x4</addressOffset>
          <size>0x20</size>
          <fields>
            <field>
              <name>CMPMCF</name>
              <bitOffset>0</bitOffset>
              <bitWidth>1</bitWidth>
            </field>
            <field>
              <name>ARRMCF</name>
              <bitOffset>1</bitOffset>
              <bitWidth>1</bitWidth>
            </field>
            <field>
              <name>EXTTRIGCF</name>
              <bitOffset>2</bitOffset>
              <bitWidth>1</bitWidth>
            </field>
            <field>
              <name>CMPOKCF</name>
              <bitOffset>3</bitOffset>
              <bitWidth>1</bitWidth>
            </field>
            <field>
              <name>ARROKCF</name>
              <bitOffset>4</bitOffset>
              <bitWidth>1</bitWidth>
            </field>
            <field>
              <name>UPCF</name>
              <bitOffset>5</bitOffset>
              <bitWidth>1</bitWidth>
            </field>
            <field>
              <name>DOWNCF</name>
              <bitOffset>6</bitOffset>
              <bitWidth>1</bitWidth>
            </field>
          </fields>
        </register>
        <register>
          <name>IER</name>
          <addressOffset>0x8</addressOffset>
          <size>0x20</size>
          <fields>
            <field>
              <name>CMPMIE</name>
              <bitOffset>0</bitOffset>
              <bitWidth>1</bitWidth>
            </field>
            <field>
              <name>ARRMIE</name>
              <bitOffset>1</bitOffset>
              <bitWidth>1</bitWidth>
            </field>
            <field>
              <name>EXTTRIGIE</name>
              <bitOffset>2</bitOffset>
              <bitWidth>1</bitWidth>
            </field>
            <field>
              <name>CMPOKIE</name>
              <bitOffset>3</bitOffset>
              <bitWidth>1</bitWidth>
            </field>
            <field>
              <name>ARROKIE</name>
              <bitOffset>4</bitOffset>
              <bitWidth>1</bitWidth>
            </field>
            <field>
              <name>UPIE</name>
              <bitOffset>5</bitOffset>
              <bitWidth>1</bitWidth>
            </field>
            <field>
              <name>DOWNIE</name>
              <bitOffset>6</bitOffset>
              <bitWidth>1</bitWidth>
            </field>
          </fields>
        </register>
        <register>
          <name>CFGR</name>
          <addressOffset>0xc</addressOffset>
          <size>0x20</size>
          <fields>
            <field>
              <name>CKSEL</name>
              <bitOffset>0</bitOffset>
              <bitWidth>1</bitWidth>
            </field>
            <field>
              <name>CKPOL</name>
              <bitOffset>1</bitOffset>
              <bitWidth>2</bitWidth>
            </field>
            <field>
              <name>CKFLT</name>
              <bitOffset>3</bitOffset>
              <bitWidth>2</bitWidth>
            </field>
            <field>
              <name>TRGFLT</name>
              <bitOffset>6</bitOffset>
              <bitWidth>2</bitWidth>
            </field>
            <field>
              <name>PRESC</name>
              <bitOffset>9</bitOffset>
              <bitWidth>3</bitWidth>
            </field>
            <field>
              <name>TRIGSEL</name>
              <bitOffset>13</bitOffset>
              <bitWidth>3</bitWidth>
            </field>
            <field>
              <name>TRIGEN</name>
              <bitOffset>17</bitOffset>
              <bitWidth>2</bitWidth>
            </field>
            <field>
              <name>TIMOUT</name>
              <bitOffset>19</bitOffset>
              <bitWidth>1</bitWidth>
            </field>
            <field>
              <name>WAVE</name>
              <bitOffset>20</bitOffset>
              <bitWidth>1</bitWidth>
            </field>
            <field>
              <name>WAVPOL</name>
              <bitOffset>21</bitOffset>
              <bitWidth>1</bitWidth>
            </field>
            <field>
              <name>PRELOAD</name>
              <bitOffset>22</bitOffset>
              <bitWidth>1</bitWidth>
            </field>
            <field>
              <name>COUNTMODE</name>
              <bitOffset>23</bitOffset>
              <bitWidth>1</bitWidth>
            </field>
            <field>
              <name>ENC</name>
              <bitOffset>24</bitOffset>
              <bitWidth>1</bitWidth>
            </field>
          </fields>
        </register>
        <register>
          <name>CR</name>
          <addressOffset>0x10</addressOffset>
          <size>0x20</size>
          <fields>
            <field>
              <name>ENABLE</name>
              <bitOffset>0</bitOffset>
              <bitWidth>1</bitWidth>
            </field>
            <field>
              <name>SNGSTRT</name>
              <bitOffset>1</bitOffset>
              <bitWidth>19</bitWidth>
            </field>
            <field>
              <name>CNTSTRT</name>
              <bitOffset>2</bitOffset>
              <bitWidth>1</bitWidth>
            </field>
            <field>
              <name>COUNTRST</name>
              <bitOffset>3</bitOffset>
              <bitWidth>1</bitWidth>
            </field>
            <field>
              <name>RSTARE</name>
              <bitOffset>4</bitOffset>
              <bitWidth>1</bitWidth>
            </field>
          </fields>
        </register>
        <register>
          <name>CMP</name>
          <addressOffset>0x14</addressOffset>
          <size>0x20</size>
          <fields>
            <field>
              <name>CMP</name>
              <bitOffset>0</bitOffset>
              <bitWidth>16</bitWidth>
            </field>
          </fields>
        </register>
        <register>
          <name>ARR</name>
          <addressOffset>0x18</addressOffset>
          <size>0x20</size>
          <fields>
            <field>
              <name>ARR</name>
              <bitOffset>0</bitOffset>
              <bitWidth>16</bitWidth>
            </field>
          </fields>
        </register>
        <register>
          <name>CNT</name>
          <addressOffset>0x1c</addressOffset>
          <size>0x20</size>
          <fields>
            <field>
              <name>CNT</name>
              <bitOffset>0</bitOffset>
              <bitWidth>16</bitWidth>
            </field>
          </fields>
        </register>
        <register>
          <name>CFGR2</name>
          <addressOffset>0x24</addressOffset>
          <size>0x20</size>
          <fields>
            <field>
              <name>IN1SEL</name>
              <bitOffset>0</bitOffset>
              <bitWidth>2</bitWidth>
            </field>
            <field>
              <name>IN2SEL</name>
              <bitOffset>4</bitOffset>
              <bitWidth>2</bitWidth>
            </field>
          </fields>
        </register>
      </registers>
    </peripheral>
    <peripheral>
      <name>WWDG2</name>
      <baseAddress>0x40002c00</baseAddress>
      <registers>
        <register>
          <name>CR</name>
          <addressOffset>0x0</addressOffset>
          <size>0x20</size>
          <fields>
            <field>
              <name>T</name>
              <bitOffset>0</bitOffset>
              <bitWidth>7</bitWidth>
            </field>
            <field>
              <name>WDGA</name>
              <bitOffset>7</bitOffset>
              <bitWidth>1</bitWidth>
            </field>
          </fields>
        </register>
        <register>
          <name>CFR</name>
          <addressOffset>0x4</addressOffset>
          <size>0x20</size>
          <fields>
            <field>
              <name>W</name>
              <bitOffset>0</bitOffset>
              <bitWidth>7</bitWidth>
            </field>
            <field>
              <name>EWI</name>
              <bitOffset>9</bitOffset>
              <bitWidth>1</bitWidth>
            </field>
            <field>
              <name>WDGTB</name>
              <bitOffset>11</bitOffset>
              <bitWidth>3</bitWidth>
            </field>
          </fields>
        </register>
        <register>
          <name>SR</name>
          <addressOffset>0x8</addressOffset>
          <size>0x20</size>
          <fields>
            <field>
              <name>EWIF</name>
              <bitOffset>0</bitOffset>
              <bitWidth>1</bitWidth>
            </field>
          </fields>
        </register>
      </registers>
    </peripheral>
    <peripheral>
      <name>SPI2</name>
      <baseAddress>0x40003800</baseAddress>
      <registers>
        <register>
          <name>CR1</name>
          <addressOffset>0x0</addressOffset>
          <size>0x20</size>
          <fields>
            <field>
              <name>SPE</name>
              <bitOffset>0</bitOffset>
              <bitWidth>1</bitWidth>
            </field>
            <field>
              <name>MASRX</name>
              <bitOffset>8</bitOffset>
              <bitWidth>1</bitWidth>
            </field>
            <field>
              <name>CSTART</name>
              <bitOffset>9</bitOffset>
              <bitWidth>1</bitWidth>
            </field>
            <field>
              <name>CSUSP</name>
              <bitOffset>10</bitOffset>
              <bitWidth>1</bitWidth>
            </field>
            <field>
              <name>HDDIR</name>
              <bitOffset>11</bitOffset>
              <bitWidth>1</bitWidth>
            </field>
            <field>
              <name>SSI</name>
              <bitOffset>12</bitOffset>
              <bitWidth>1</bitWidth>
            </field>
            <field>
              <name>CRC33_17</name>
              <bitOffset>13</bitOffset>
              <bitWidth>1</bitWidth>
            </field>
            <field>
              <name>RCRCINI</name>
              <bitOffset>14</bitOffset>
              <bitWidth>1</bitWidth>
            </field>
            <field>
              <name>TCRCINI</name>
              <bitOffset>15</bitOffset>
              <bitWidth>1</bitWidth>
            </field>
            <field>
              <name>IOLOCK</name>
              <bitOffset>16</bitOffset>
              <bitWidth>1</bitWidth>
            </field>
          </fields>
        </register>
        <register>
          <name>CR2</name>
          <addressOffset>0x4</addressOffset>
          <size>0x20</size>
          <fields>
            <field>
              <name>TSIZE</name>
              <bitOffset>0</bitOffset>
              <bitWidth>16</bitWidth>
            </field>
            <field>
              <name>TSER</name>
              <bitOffset>16</bitOffset>
              <bitWidth>16</bitWidth>
            </field>
          </fields>
        </register>
        <register>
          <name>CFG1</name>
          <addressOffset>0x8</addressOffset>
          <size>0x20</size>
          <fields>
            <field>
              <name>DSIZE</name>
              <bitOffset>0</bitOffset>
              <bitWidth>5</bitWidth>
            </field>
            <field>
              <name>FTHLV</name>
              <bitOffset>5</bitOffset>
              <bitWidth>4</bitWidth>
            </field>
            <field>
              <name>UDRCFG</name>
              <bitOffset>9</bitOffset>
              <bitWidth>2</bitWidth>
            </field>
            <field>
              <name>UDRDET</name>
              <bitOffset>11</bitOffset>
              <bitWidth>2</bitWidth>
            </field>
            <field>
              <name>RXDMAEN</name>
              <bitOffset>14</bitOffset>
              <bitWidth>1</bitWidth>
            </field>
            <field>
              <name>TXDMAEN</name>
              <bitOffset>15</bitOffset>
              <bitWidth>1</bitWidth>
            </field>
            <field>
              <name>CRCSIZE</name>
              <bitOffset>16</bitOffset>
              <bitWidth>5</bitWidth>
            </field>
            <field>
              <name>CRCEN</name>
              <bitOffset>22</bitOffset>
              <bitWidth>1</bitWidth>
            </field>
            <field>
              <name>MBR</name>
              <bitOffset>28</bitOffset>
              <bitWidth>3</bitWidth>
            </field>
          </fields>
        </register>
        <register>
          <name>CFG2</name>
          <addressOffset>0xc</addressOffset>
          <size>0x20</size>
          <fields>
            <field>
              <name>MSSI</name>
              <bitOffset>0</bitOffset>
              <bitWidth>4</bitWidth>
            </field>
            <field>
              <name>MIDI</name>
              <bitOffset>4</bitOffset>
              <bitWidth>4</bitWidth>
            </field>
            <field>
              <name>IOSWP</name>
              <bitOffset>15</bitOffset>
              <bitWidth>1</bitWidth>
            </field>
            <field>
              <name>COMM</name>
              <bitOffset>17</bitOffset>
              <bitWidth>2</bitWidth>
            </field>
            <field>
              <name>SP</name>
              <bitOffset>19</bitOffset>
              <bitWidth>3</bitWidth>
            </field>
            <field>
              <name>MASTER</name>
              <bitOffset>22</bitOffset>
              <bitWidth>1</bitWidth>
            </field>
            <field>
              <name>LSBFRST</name>
              <bitOffset>23</bitOffset>
              <bitWidth>1</bitWidth>
            </field>
            <field>
              <name>CPHA</name>
              <bitOffset>24</bitOffset>
              <bitWidth>1</bitWidth>
            </field>
            <field>
              <name>CPOL</name>
              <bitOffset>25</bitOffset>
              <bitWidth>1</bitWidth>
            </field>
            <field>
              <name>SSM</name>
              <bitOffset>26</bitOffset>
              <bitWidth>1</bitWidth>
            </field>
            <field>
              <name>SSIOP</name>
              <bitOffset>28</bitOffset>
              <bitWidth>1</bitWidth>
            </field>
            <field>
              <name>SSOE</name>
              <bitOffset>29</bitOffset>
              <bitWidth>1</bitWidth>
            </field>
            <field>
              <name>SSOM</name>
              <bitOffset>30</bitOffset>
              <bitWidth>1</bitWidth>
            </field>
            <field>
              <name>AFCNTR</name>
              <bitOffset>31</bitOffset>
              <bitWidth>1</bitWidth>
            </field>
          </fields>
        </register>
        <register>
          <name>IER</name>
          <addressOffset>0x10</addressOffset>
          <size>0x20</size>
          <fields>
            <field>
              <name>RXPIE</name>
              <bitOffset>0</bitOffset>
              <bitWidth>1</bitWidth>
            </field>
            <field>
              <name>TXPIE</name>
              <bitOffset>1</bitOffset>
              <bitWidth>1</bitWidth>
            </field>
            <field>
              <name>DXPIE</name>
              <bitOffset>2</bitOffset>
              <bitWidth>1</bitWidth>
            </field>
            <field>
              <name>EOTIE</name>
              <bitOffset>3</bitOffset>
              <bitWidth>1</bitWidth>
            </field>
            <field>
              <name>TXTFIE</name>
              <bitOffset>4</bitOffset>
              <bitWidth>1</bitWidth>
            </field>
            <field>
              <name>UDRIE</name>
              <bitOffset>5</bitOffset>
              <bitWidth>1</bitWidth>
            </field>
            <field>
              <name>OVRIE</name>
              <bitOffset>6</bitOffset>
              <bitWidth>1</bitWidth>
            </field>
            <field>
              <name>CRCEIE</name>
              <bitOffset>7</bitOffset>
              <bitWidth>1</bitWidth>
            </field>
            <field>
              <name>TIFREIE</name>
              <bitOffset>8</bitOffset>
              <bitWidth>1</bitWidth>
            </field>
            <field>
              <name>MODFIE</name>
              <bitOffset>9</bitOffset>
              <bitWidth>1</bitWidth>
            </field>
            <field>
              <name>TSERFIE</name>
              <bitOffset>10</bitOffset>
              <bitWidth>1</bitWidth>
            </field>
          </fields>
        </register>
        <register>
          <name>SR</name>
          <addressOffset>0x14</addressOffset>
          <size>0x20</size>
          <fields>
            <field>
              <name>RXP</name>
              <bitOffset>0</bitOffset>
              <bitWidth>1</bitWidth>
            </field>
            <field>
              <name>TXP</name>
              <bitOffset>1</bitOffset>
              <bitWidth>1</bitWidth>
            </field>
            <field>
              <name>DXP</name>
              <bitOffset>2</bitOffset>
              <bitWidth>1</bitWidth>
            </field>
            <field>
              <name>EOT</name>
              <bitOffset>3</bitOffset>
              <bitWidth>1</bitWidth>
            </field>
            <field>
              <name>TXTF</name>
              <bitOffset>4</bitOffset>
              <bitWidth>1</bitWidth>
            </field>
            <field>
              <name>UDR</name>
              <bitOffset>5</bitOffset>
              <bitWidth>1</bitWidth>
            </field>
            <field>
              <name>OVR</name>
              <bitOffset>6</bitOffset>
              <bitWidth>1</bitWidth>
            </field>
            <field>
              <name>CRCE</name>
              <bitOffset>7</bitOffset>
              <bitWidth>1</bitWidth>
            </field>
            <field>
              <name>TIFRE</name>
              <bitOffset>8</bitOffset>
              <bitWidth>1</bitWidth>
            </field>
            <field>
              <name>MODF</name>
              <bitOffset>9</bitOffset>
              <bitWidth>1</bitWidth>
            </field>
            <field>
              <name>TSERF</name>
              <bitOffset>10</bitOffset>
              <bitWidth>1</bitWidth>
            </field>
            <field>
              <name>SUSP</name>
              <bitOffset>11</bitOffset>
              <bitWidth>1</bitWidth>
            </field>
            <field>
              <name>TXC</name>
              <bitOffset>12</bitOffset>
              <bitWidth>1</bitWidth>
            </field>
            <field>
              <name>RXPLVL</name>
              <bitOffset>13</bitOffset>
              <bitWidth>2</bitWidth>
            </field>
            <field>
              <name>RXWNE</name>
              <bitOffset>15</bitOffset>
              <bitWidth>1</bitWidth>
            </field>
            <field>
              <name>CTSIZE</name>
              <bitOffset>16</bitOffset>
              <bitWidth>16</bitWidth>
            </field>
          </fields>
        </register>
        <register>
          <name>IFCR</name>
          <addressOffset>0x18</addressOffset>
          <size>0x20</size>
          <fields>
            <field>
              <name>EOTC</name>
              <bitOffset>3</bitOffset>
              <bitWidth>1</bitWidth>
            </field>
            <field>
              <name>TXTFC</name>
              <bitOffset>4</bitOffset>
              <bitWidth>1</bitWidth>
            </field>
            <field>
              <name>UDRC</name>
              <bitOffset>5</bitOffset>
              <bitWidth>1</bitWidth>
            </field>
            <field>
              <name>OVRC</name>
              <bitOffset>6</bitOffset>
              <bitWidth>1</bitWidth>
            </field>
            <field>
              <name>CRCEC</name>
              <bitOffset>7</bitOffset>
              <bitWidth>1</bitWidth>
            </field>
            <field>
              <name>TIFREC</name>
              <bitOffset>8</bitOffset>
              <bitWidth>1</bitWidth>
            </field>
            <field>
              <name>MODFC</name>
              <bitOffset>9</bitOffset>
              <bitWidth>1</bitWidth>
            </field>
            <field>
              <name>TSERFC</name>
              <bitOffset>10</bitOffset>
              <bitWidth>1</bitWidth>
            </field>
            <field>
              <name>SUSPC</name>
              <bitOffset>11</bitOffset>
              <bitWidth>1</bitWidth>
            </field>
          </fields>
        </register>
        <register>
          <name>TXDR</name>
          <addressOffset>0x20</addressOffset>
          <size>0x20</size>
          <fields>
            <field>
              <name>TXDR</name>
              <bitOffset>0</bitOffset>
              <bitWidth>32</bitWidth>
            </field>
          </fields>
        </register>
        <register>
          <name>RXDR</name>
          <addressOffset>0x30</addressOffset>
          <size>0x20</size>
          <fields>
            <field>
              <name>RXDR</name>
              <bitOffset>0</bitOffset>
              <bitWidth>32</bitWidth>
            </field>
          </fields>
        </register>
        <register>
          <name>CRCPOLY</name>
          <addressOffset>0x40</addressOffset>
          <size>0x20</size>
          <fields>
            <field>
              <name>CRCPOLY</name>
              <bitOffset>0</bitOffset>
              <bitWidth>32</bitWidth>
            </field>
          </fields>
        </register>
        <register>
          <name>TXCRC</name>
          <addressOffset>0x44</addressOffset>
          <size>0x20</size>
          <fields>
            <field>
              <name>TXCRC</name>
              <bitOffset>0</bitOffset>
              <bitWidth>32</bitWidth>
            </field>
          </fields>
        </register>
        <register>
          <name>RXCRC</name>
          <addressOffset>0x48</addressOffset>
          <size>0x20</size>
          <fields>
            <field>
              <name>RXCRC</name>
              <bitOffset>0</bitOffset>
              <bitWidth>32</bitWidth>
            </field>
          </fields>
        </register>
        <register>
          <name>UDRDR</name>
          <addressOffset>0x4c</addressOffset>
          <size>0x20</size>
          <fields>
            <field>
              <name>UDRDR</name>
              <bitOffset>0</bitOffset>
              <bitWidth>32</bitWidth>
            </field>
          </fields>
        </register>
        <register>
          <name>I2SCFGR</name>
          <addressOffset>0x50</addressOffset>
          <size>0x20</size>
          <fields>
            <field>
              <name>I2SMOD</name>
              <bitOffset>0</bitOffset>
              <bitWidth>1</bitWidth>
            </field>
            <field>
              <name>I2SCFG</name>
              <bitOffset>1</bitOffset>
              <bitWidth>3</bitWidth>
            </field>
            <field>
              <name>I2SSTD</name>
              <bitOffset>4</bitOffset>
              <bitWidth>2</bitWidth>
            </field>
            <field>
              <name>PCMSYNC</name>
              <bitOffset>7</bitOffset>
              <bitWidth>1</bitWidth>
            </field>
            <field>
              <name>DATLEN</name>
              <bitOffset>8</bitOffset>
              <bitWidth>2</bitWidth>
            </field>
            <field>
              <name>CHLEN</name>
              <bitOffset>10</bitOffset>
              <bitWidth>1</bitWidth>
            </field>
            <field>
              <name>CKPOL</name>
              <bitOffset>11</bitOffset>
              <bitWidth>1</bitWidth>
            </field>
            <field>
              <name>FIXCH</name>
              <bitOffset>12</bitOffset>
              <bitWidth>1</bitWidth>
            </field>
            <field>
              <name>WSINV</name>
              <bitOffset>13</bitOffset>
              <bitWidth>1</bitWidth>
            </field>
            <field>
              <name>DATFMT</name>
              <bitOffset>14</bitOffset>
              <bitWidth>1</bitWidth>
            </field>
            <field>
              <name>I2SDIV</name>
              <bitOffset>16</bitOffset>
              <bitWidth>8</bitWidth>
            </field>
            <field>
              <name>ODD</name>
              <bitOffset>24</bitOffset>
              <bitWidth>1</bitWidth>
            </field>
            <field>
              <name>MCKOE</name>
              <bitOffset>25</bitOffset>
              <bitWidth>1</bitWidth>
            </field>
          </fields>
        </register>
      </registers>
    </peripheral>
    <peripheral>
      <name>SPI3</name>
      <baseAddress>0x40003c00</baseAddress>
      <registers>
        <register>
          <name>CR1</name>
          <addressOffset>0x0</addressOffset>
          <size>0x20</size>
          <fields>
            <field>
              <name>SPE</name>
              <bitOffset>0</bitOffset>
              <bitWidth>1</bitWidth>
            </field>
            <field>
              <name>MASRX</name>
              <bitOffset>8</bitOffset>
              <bitWidth>1</bitWidth>
            </field>
            <field>
              <name>CSTART</name>
              <bitOffset>9</bitOffset>
              <bitWidth>1</bitWidth>
            </field>
            <field>
              <name>CSUSP</name>
              <bitOffset>10</bitOffset>
              <bitWidth>1</bitWidth>
            </field>
            <field>
              <name>HDDIR</name>
              <bitOffset>11</bitOffset>
              <bitWidth>1</bitWidth>
            </field>
            <field>
              <name>SSI</name>
              <bitOffset>12</bitOffset>
              <bitWidth>1</bitWidth>
            </field>
            <field>
              <name>CRC33_17</name>
              <bitOffset>13</bitOffset>
              <bitWidth>1</bitWidth>
            </field>
            <field>
              <name>RCRCINI</name>
              <bitOffset>14</bitOffset>
              <bitWidth>1</bitWidth>
            </field>
            <field>
              <name>TCRCINI</name>
              <bitOffset>15</bitOffset>
              <bitWidth>1</bitWidth>
            </field>
            <field>
              <name>IOLOCK</name>
              <bitOffset>16</bitOffset>
              <bitWidth>1</bitWidth>
            </field>
          </fields>
        </register>
        <register>
          <name>CR2</name>
          <addressOffset>0x4</addressOffset>
          <size>0x20</size>
          <fields>
            <field>
              <name>TSIZE</name>
              <bitOffset>0</bitOffset>
              <bitWidth>16</bitWidth>
            </field>
            <field>
              <name>TSER</name>
              <bitOffset>16</bitOffset>
              <bitWidth>16</bitWidth>
            </field>
          </fields>
        </register>
        <register>
          <name>CFG1</name>
          <addressOffset>0x8</addressOffset>
          <size>0x20</size>
          <fields>
            <field>
              <name>DSIZE</name>
              <bitOffset>0</bitOffset>
              <bitWidth>5</bitWidth>
            </field>
            <field>
              <name>FTHLV</name>
              <bitOffset>5</bitOffset>
              <bitWidth>4</bitWidth>
            </field>
            <field>
              <name>UDRCFG</name>
              <bitOffset>9</bitOffset>
              <bitWidth>2</bitWidth>
            </field>
            <field>
              <name>UDRDET</name>
              <bitOffset>11</bitOffset>
              <bitWidth>2</bitWidth>
            </field>
            <field>
              <name>RXDMAEN</name>
              <bitOffset>14</bitOffset>
              <bitWidth>1</bitWidth>
            </field>
            <field>
              <name>TXDMAEN</name>
              <bitOffset>15</bitOffset>
              <bitWidth>1</bitWidth>
            </field>
            <field>
              <name>CRCSIZE</name>
              <bitOffset>16</bitOffset>
              <bitWidth>5</bitWidth>
            </field>
            <field>
              <name>CRCEN</name>
              <bitOffset>22</bitOffset>
              <bitWidth>1</bitWidth>
            </field>
            <field>
              <name>MBR</name>
              <bitOffset>28</bitOffset>
              <bitWidth>3</bitWidth>
            </field>
          </fields>
        </register>
        <register>
          <name>CFG2</name>
          <addressOffset>0xc</addressOffset>
          <size>0x20</size>
          <fields>
            <field>
              <name>MSSI</name>
              <bitOffset>0</bitOffset>
              <bitWidth>4</bitWidth>
            </field>
            <field>
              <name>MIDI</name>
              <bitOffset>4</bitOffset>
              <bitWidth>4</bitWidth>
            </field>
            <field>
              <name>IOSWP</name>
              <bitOffset>15</bitOffset>
              <bitWidth>1</bitWidth>
            </field>
            <field>
              <name>COMM</name>
              <bitOffset>17</bitOffset>
              <bitWidth>2</bitWidth>
            </field>
            <field>
              <name>SP</name>
              <bitOffset>19</bitOffset>
              <bitWidth>3</bitWidth>
            </field>
            <field>
              <name>MASTER</name>
              <bitOffset>22</bitOffset>
              <bitWidth>1</bitWidth>
            </field>
            <field>
              <name>LSBFRST</name>
              <bitOffset>23</bitOffset>
              <bitWidth>1</bitWidth>
            </field>
            <field>
              <name>CPHA</name>
              <bitOffset>24</bitOffset>
              <bitWidth>1</bitWidth>
            </field>
            <field>
              <name>CPOL</name>
              <bitOffset>25</bitOffset>
              <bitWidth>1</bitWidth>
            </field>
            <field>
              <name>SSM</name>
              <bitOffset>26</bitOffset>
              <bitWidth>1</bitWidth>
            </field>
            <field>
              <name>SSIOP</name>
              <bitOffset>28</bitOffset>
              <bitWidth>1</bitWidth>
            </field>
            <field>
              <name>SSOE</name>
              <bitOffset>29</bitOffset>
              <bitWidth>1</bitWidth>
            </field>
            <field>
              <name>SSOM</name>
              <bitOffset>30</bitOffset>
              <bitWidth>1</bitWidth>
            </field>
            <field>
              <name>AFCNTR</name>
              <bitOffset>31</bitOffset>
              <bitWidth>1</bitWidth>
            </field>
          </fields>
        </register>
        <register>
          <name>IER</name>
          <addressOffset>0x10</addressOffset>
          <size>0x20</size>
          <fields>
            <field>
              <name>RXPIE</name>
              <bitOffset>0</bitOffset>
              <bitWidth>1</bitWidth>
            </field>
            <field>
              <name>TXPIE</name>
              <bitOffset>1</bitOffset>
              <bitWidth>1</bitWidth>
            </field>
            <field>
              <name>DXPIE</name>
              <bitOffset>2</bitOffset>
              <bitWidth>1</bitWidth>
            </field>
            <field>
              <name>EOTIE</name>
              <bitOffset>3</bitOffset>
              <bitWidth>1</bitWidth>
            </field>
            <field>
              <name>TXTFIE</name>
              <bitOffset>4</bitOffset>
              <bitWidth>1</bitWidth>
            </field>
            <field>
              <name>UDRIE</name>
              <bitOffset>5</bitOffset>
              <bitWidth>1</bitWidth>
            </field>
            <field>
              <name>OVRIE</name>
              <bitOffset>6</bitOffset>
              <bitWidth>1</bitWidth>
            </field>
            <field>
              <name>CRCEIE</name>
              <bitOffset>7</bitOffset>
              <bitWidth>1</bitWidth>
            </field>
            <field>
              <name>TIFREIE</name>
              <bitOffset>8</bitOffset>
              <bitWidth>1</bitWidth>
            </field>
            <field>
              <name>MODFIE</name>
              <bitOffset>9</bitOffset>
              <bitWidth>1</bitWidth>
            </field>
            <field>
              <name>TSERFIE</name>
              <bitOffset>10</bitOffset>
              <bitWidth>1</bitWidth>
            </field>
          </fields>
        </register>
        <register>
          <name>SR</name>
          <addressOffset>0x14</addressOffset>
          <size>0x20</size>
          <fields>
            <field>
              <name>RXP</name>
              <bitOffset>0</bitOffset>
              <bitWidth>1</bitWidth>
            </field>
            <field>
              <name>TXP</name>
              <bitOffset>1</bitOffset>
              <bitWidth>1</bitWidth>
            </field>
            <field>
              <name>DXP</name>
              <bitOffset>2</bitOffset>
              <bitWidth>1</bitWidth>
            </field>
            <field>
              <name>EOT</name>
              <bitOffset>3</bitOffset>
              <bitWidth>1</bitWidth>
            </field>
            <field>
              <name>TXTF</name>
              <bitOffset>4</bitOffset>
              <bitWidth>1</bitWidth>
            </field>
            <field>
              <name>UDR</name>
              <bitOffset>5</bitOffset>
              <bitWidth>1</bitWidth>
            </field>
            <field>
              <name>OVR</name>
              <bitOffset>6</bitOffset>
              <bitWidth>1</bitWidth>
            </field>
            <field>
              <name>CRCE</name>
              <bitOffset>7</bitOffset>
              <bitWidth>1</bitWidth>
            </field>
            <field>
              <name>TIFRE</name>
              <bitOffset>8</bitOffset>
              <bitWidth>1</bitWidth>
            </field>
            <field>
              <name>MODF</name>
              <bitOffset>9</bitOffset>
              <bitWidth>1</bitWidth>
            </field>
            <field>
              <name>TSERF</name>
              <bitOffset>10</bitOffset>
              <bitWidth>1</bitWidth>
            </field>
            <field>
              <name>SUSP</name>
              <bitOffset>11</bitOffset>
              <bitWidth>1</bitWidth>
            </field>
            <field>
              <name>TXC</name>
              <bitOffset>12</bitOffset>
              <bitWidth>1</bitWidth>
            </field>
            <field>
              <name>RXPLVL</name>
              <bitOffset>13</bitOffset>
              <bitWidth>2</bitWidth>
            </field>
            <field>
              <name>RXWNE</name>
              <bitOffset>15</bitOffset>
              <bitWidth>1</bitWidth>
            </field>
            <field>
              <name>CTSIZE</name>
              <bitOffset>16</bitOffset>
              <bitWidth>16</bitWidth>
            </field>
          </fields>
        </register>
        <register>
          <name>IFCR</name>
          <addressOffset>0x18</addressOffset>
          <size>0x20</size>
          <fields>
            <field>
              <name>EOTC</name>
              <bitOffset>3</bitOffset>
              <bitWidth>1</bitWidth>
            </field>
            <field>
              <name>TXTFC</name>
              <bitOffset>4</bitOffset>
              <bitWidth>1</bitWidth>
            </field>
            <field>
              <name>UDRC</name>
              <bitOffset>5</bitOffset>
              <bitWidth>1</bitWidth>
            </field>
            <field>
              <name>OVRC</name>
              <bitOffset>6</bitOffset>
              <bitWidth>1</bitWidth>
            </field>
            <field>
              <name>CRCEC</name>
              <bitOffset>7</bitOffset>
              <bitWidth>1</bitWidth>
            </field>
            <field>
              <name>TIFREC</name>
              <bitOffset>8</bitOffset>
              <bitWidth>1</bitWidth>
            </field>
            <field>
              <name>MODFC</name>
              <bitOffset>9</bitOffset>
              <bitWidth>1</bitWidth>
            </field>
            <field>
              <name>TSERFC</name>
              <bitOffset>10</bitOffset>
              <bitWidth>1</bitWidth>
            </field>
            <field>
              <name>SUSPC</name>
              <bitOffset>11</bitOffset>
              <bitWidth>1</bitWidth>
            </field>
          </fields>
        </register>
        <register>
          <name>TXDR</name>
          <addressOffset>0x20</addressOffset>
          <size>0x20</size>
          <fields>
            <field>
              <name>TXDR</name>
              <bitOffset>0</bitOffset>
              <bitWidth>32</bitWidth>
            </field>
          </fields>
        </register>
        <register>
          <name>RXDR</name>
          <addressOffset>0x30</addressOffset>
          <size>0x20</size>
          <fields>
            <field>
              <name>RXDR</name>
              <bitOffset>0</bitOffset>
              <bitWidth>32</bitWidth>
            </field>
          </fields>
        </register>
        <register>
          <name>CRCPOLY</name>
          <addressOffset>0x40</addressOffset>
          <size>0x20</size>
          <fields>
            <field>
              <name>CRCPOLY</name>
              <bitOffset>0</bitOffset>
              <bitWidth>32</bitWidth>
            </field>
          </fields>
        </register>
        <register>
          <name>TXCRC</name>
          <addressOffset>0x44</addressOffset>
          <size>0x20</size>
          <fields>
            <field>
              <name>TXCRC</name>
              <bitOffset>0</bitOffset>
              <bitWidth>32</bitWidth>
            </field>
          </fields>
        </register>
        <register>
          <name>RXCRC</name>
          <addressOffset>0x48</addressOffset>
          <size>0x20</size>
          <fields>
            <field>
              <name>RXCRC</name>
              <bitOffset>0</bitOffset>
              <bitWidth>32</bitWidth>
            </field>
          </fields>
        </register>
        <register>
          <name>UDRDR</name>
          <addressOffset>0x4c</addressOffset>
          <size>0x20</size>
          <fields>
            <field>
              <name>UDRDR</name>
              <bitOffset>0</bitOffset>
              <bitWidth>32</bitWidth>
            </field>
          </fields>
        </register>
        <register>
          <name>I2SCFGR</name>
          <addressOffset>0x50</addressOffset>
          <size>0x20</size>
          <fields>
            <field>
              <name>I2SMOD</name>
              <bitOffset>0</bitOffset>
              <bitWidth>1</bitWidth>
            </field>
            <field>
              <name>I2SCFG</name>
              <bitOffset>1</bitOffset>
              <bitWidth>3</bitWidth>
            </field>
            <field>
              <name>I2SSTD</name>
              <bitOffset>4</bitOffset>
              <bitWidth>2</bitWidth>
            </field>
            <field>
              <name>PCMSYNC</name>
              <bitOffset>7</bitOffset>
              <bitWidth>1</bitWidth>
            </field>
            <field>
              <name>DATLEN</name>
              <bitOffset>8</bitOffset>
              <bitWidth>2</bitWidth>
            </field>
            <field>
              <name>CHLEN</name>
              <bitOffset>10</bitOffset>
              <bitWidth>1</bitWidth>
            </field>
            <field>
              <name>CKPOL</name>
              <bitOffset>11</bitOffset>
              <bitWidth>1</bitWidth>
            </field>
            <field>
              <name>FIXCH</name>
              <bitOffset>12</bitOffset>
              <bitWidth>1</bitWidth>
            </field>
            <field>
              <name>WSINV</name>
              <bitOffset>13</bitOffset>
              <bitWidth>1</bitWidth>
            </field>
            <field>
              <name>DATFMT</name>
              <bitOffset>14</bitOffset>
              <bitWidth>1</bitWidth>
            </field>
            <field>
              <name>I2SDIV</name>
              <bitOffset>16</bitOffset>
              <bitWidth>8</bitWidth>
            </field>
            <field>
              <name>ODD</name>
              <bitOffset>24</bitOffset>
              <bitWidth>1</bitWidth>
            </field>
            <field>
              <name>MCKOE</name>
              <bitOffset>25</bitOffset>
              <bitWidth>1</bitWidth>
            </field>
          </fields>
        </register>
      </registers>
    </peripheral>
    <peripheral>
      <name>SPDIFRX</name>
      <baseAddress>0x40004000</baseAddress>
      <registers>
        <register>
          <name>CR</name>
          <addressOffset>0x0</addressOffset>
          <size>0x20</size>
          <fields>
            <field>
              <name>SPDIFEN</name>
              <bitOffset>0</bitOffset>
              <bitWidth>2</bitWidth>
            </field>
            <field>
              <name>RXDMAEN</name>
              <bitOffset>2</bitOffset>
              <bitWidth>1</bitWidth>
            </field>
            <field>
              <name>RXSTEO</name>
              <bitOffset>3</bitOffset>
              <bitWidth>1</bitWidth>
            </field>
            <field>
              <name>DRFMT</name>
              <bitOffset>4</bitOffset>
              <bitWidth>2</bitWidth>
            </field>
            <field>
              <name>PMSK</name>
              <bitOffset>6</bitOffset>
              <bitWidth>1</bitWidth>
            </field>
            <field>
              <name>VMSK</name>
              <bitOffset>7</bitOffset>
              <bitWidth>1</bitWidth>
            </field>
            <field>
              <name>CUMSK</name>
              <bitOffset>8</bitOffset>
              <bitWidth>1</bitWidth>
            </field>
            <field>
              <name>PTMSK</name>
              <bitOffset>9</bitOffset>
              <bitWidth>1</bitWidth>
            </field>
            <field>
              <name>CBDMAEN</name>
              <bitOffset>10</bitOffset>
              <bitWidth>1</bitWidth>
            </field>
            <field>
              <name>CHSEL</name>
              <bitOffset>11</bitOffset>
              <bitWidth>1</bitWidth>
            </field>
            <field>
              <name>NBTR</name>
              <bitOffset>12</bitOffset>
              <bitWidth>2</bitWidth>
            </field>
            <field>
              <name>WFA</name>
              <bitOffset>14</bitOffset>
              <bitWidth>1</bitWidth>
            </field>
            <field>
              <name>INSEL</name>
              <bitOffset>16</bitOffset>
              <bitWidth>3</bitWidth>
            </field>
            <field>
              <name>CKSEN</name>
              <bitOffset>20</bitOffset>
              <bitWidth>1</bitWidth>
            </field>
            <field>
              <name>CKSBKPEN</name>
              <bitOffset>21</bitOffset>
              <bitWidth>1</bitWidth>
            </field>
          </fields>
        </register>
        <register>
          <name>IMR</name>
          <addressOffset>0x4</addressOffset>
          <size>0x20</size>
          <fields>
            <field>
              <name>RXNEIE</name>
              <bitOffset>0</bitOffset>
              <bitWidth>1</bitWidth>
            </field>
            <field>
              <name>CSRNEIE</name>
              <bitOffset>1</bitOffset>
              <bitWidth>1</bitWidth>
            </field>
            <field>
              <name>PERRIE</name>
              <bitOffset>2</bitOffset>
              <bitWidth>1</bitWidth>
            </field>
            <field>
              <name>OVRIE</name>
              <bitOffset>3</bitOffset>
              <bitWidth>1</bitWidth>
            </field>
            <field>
              <name>SBLKIE</name>
              <bitOffset>4</bitOffset>
              <bitWidth>1</bitWidth>
            </field>
            <field>
              <name>SYNCDIE</name>
              <bitOffset>5</bitOffset>
              <bitWidth>1</bitWidth>
            </field>
            <field>
              <name>IFEIE</name>
              <bitOffset>6</bitOffset>
              <bitWidth>1</bitWidth>
            </field>
          </fields>
        </register>
        <register>
          <name>SR</name>
          <addressOffset>0x8</addressOffset>
          <size>0x20</size>
          <fields>
            <field>
              <name>RXNE</name>
              <bitOffset>0</bitOffset>
              <bitWidth>1</bitWidth>
            </field>
            <field>
              <name>CSRNE</name>
              <bitOffset>1</bitOffset>
              <bitWidth>1</bitWidth>
            </field>
            <field>
              <name>PERR</name>
              <bitOffset>2</bitOffset>
              <bitWidth>1</bitWidth>
            </field>
            <field>
              <name>OVR</name>
              <bitOffset>3</bitOffset>
              <bitWidth>1</bitWidth>
            </field>
            <field>
              <name>SBD</name>
              <bitOffset>4</bitOffset>
              <bitWidth>1</bitWidth>
            </field>
            <field>
              <name>SYNCD</name>
              <bitOffset>5</bitOffset>
              <bitWidth>1</bitWidth>
            </field>
            <field>
              <name>FERR</name>
              <bitOffset>6</bitOffset>
              <bitWidth>1</bitWidth>
            </field>
            <field>
              <name>SERR</name>
              <bitOffset>7</bitOffset>
              <bitWidth>1</bitWidth>
            </field>
            <field>
              <name>TERR</name>
              <bitOffset>8</bitOffset>
              <bitWidth>1</bitWidth>
            </field>
            <field>
              <name>WIDTH5</name>
              <bitOffset>16</bitOffset>
              <bitWidth>15</bitWidth>
            </field>
          </fields>
        </register>
        <register>
          <name>IFCR</name>
          <addressOffset>0xc</addressOffset>
          <size>0x20</size>
          <fields>
            <field>
              <name>PERRCF</name>
              <bitOffset>2</bitOffset>
              <bitWidth>1</bitWidth>
            </field>
            <field>
              <name>OVRCF</name>
              <bitOffset>3</bitOffset>
              <bitWidth>1</bitWidth>
            </field>
            <field>
              <name>SBDCF</name>
              <bitOffset>4</bitOffset>
              <bitWidth>1</bitWidth>
            </field>
            <field>
              <name>SYNCDCF</name>
              <bitOffset>5</bitOffset>
              <bitWidth>1</bitWidth>
            </field>
          </fields>
        </register>
        <register>
          <name>DR</name>
          <addressOffset>0x10</addressOffset>
          <size>0x20</size>
        </register>
        <register>
          <name>CSR</name>
          <addressOffset>0x14</addressOffset>
          <size>0x20</size>
          <fields>
            <field>
              <name>USR</name>
              <bitOffset>0</bitOffset>
              <bitWidth>16</bitWidth>
            </field>
            <field>
              <name>CS</name>
              <bitOffset>16</bitOffset>
              <bitWidth>8</bitWidth>
            </field>
            <field>
              <name>SOB</name>
              <bitOffset>24</bitOffset>
              <bitWidth>1</bitWidth>
            </field>
          </fields>
        </register>
        <register>
          <name>DIR</name>
          <addressOffset>0x18</addressOffset>
          <size>0x20</size>
          <fields>
            <field>
              <name>THI</name>
              <bitOffset>0</bitOffset>
              <bitWidth>13</bitWidth>
            </field>
            <field>
              <name>TLO</name>
              <bitOffset>16</bitOffset>
              <bitWidth>13</bitWidth>
            </field>
          </fields>
        </register>
      </registers>
    </peripheral>
    <peripheral>
      <name>USART2</name>
      <baseAddress>0x40004400</baseAddress>
      <registers>
        <register>
          <name>CR1</name>
          <addressOffset>0x0</addressOffset>
          <size>0x20</size>
          <fields>
            <field>
              <name>UE</name>
              <bitOffset>0</bitOffset>
              <bitWidth>1</bitWidth>
            </field>
            <field>
              <name>UESM</name>
              <bitOffset>1</bitOffset>
              <bitWidth>1</bitWidth>
            </field>
            <field>
              <name>RE</name>
              <bitOffset>2</bitOffset>
              <bitWidth>1</bitWidth>
            </field>
            <field>
              <name>TE</name>
              <bitOffset>3</bitOffset>
              <bitWidth>1</bitWidth>
            </field>
            <field>
              <name>IDLEIE</name>
              <bitOffset>4</bitOffset>
              <bitWidth>1</bitWidth>
            </field>
            <field>
              <name>RXNEIE_RXFNEIE</name>
              <bitOffset>5</bitOffset>
              <bitWidth>1</bitWidth>
            </field>
            <field>
              <name>TCIE</name>
              <bitOffset>6</bitOffset>
              <bitWidth>1</bitWidth>
            </field>
            <field>
              <name>TXEIE_TXFNFIE</name>
              <bitOffset>7</bitOffset>
              <bitWidth>1</bitWidth>
            </field>
            <field>
              <name>PEIE</name>
              <bitOffset>8</bitOffset>
              <bitWidth>1</bitWidth>
            </field>
            <field>
              <name>PS</name>
              <bitOffset>9</bitOffset>
              <bitWidth>1</bitWidth>
            </field>
            <field>
              <name>PCE</name>
              <bitOffset>10</bitOffset>
              <bitWidth>1</bitWidth>
            </field>
            <field>
              <name>WAKE</name>
              <bitOffset>11</bitOffset>
              <bitWidth>1</bitWidth>
            </field>
            <field>
              <name>M0</name>
              <bitOffset>12</bitOffset>
              <bitWidth>1</bitWidth>
            </field>
            <field>
              <name>MME</name>
              <bitOffset>13</bitOffset>
              <bitWidth>1</bitWidth>
            </field>
            <field>
              <name>CMIE</name>
              <bitOffset>14</bitOffset>
              <bitWidth>1</bitWidth>
            </field>
            <field>
              <name>OVER8</name>
              <bitOffset>15</bitOffset>
              <bitWidth>1</bitWidth>
            </field>
            <field>
              <name>DEDT</name>
              <bitOffset>16</bitOffset>
              <bitWidth>5</bitWidth>
            </field>
            <field>
              <name>DEAT</name>
              <bitOffset>21</bitOffset>
              <bitWidth>5</bitWidth>
            </field>
            <field>
              <name>RTOIE</name>
              <bitOffset>26</bitOffset>
              <bitWidth>1</bitWidth>
            </field>
            <field>
              <name>EOBIE</name>
              <bitOffset>27</bitOffset>
              <bitWidth>1</bitWidth>
            </field>
            <field>
              <name>M1</name>
              <bitOffset>28</bitOffset>
              <bitWidth>1</bitWidth>
            </field>
            <field>
              <name>FIFOEN</name>
              <bitOffset>29</bitOffset>
              <bitWidth>1</bitWidth>
            </field>
            <field>
              <name>TXFEIE</name>
              <bitOffset>30</bitOffset>
              <bitWidth>1</bitWidth>
            </field>
            <field>
              <name>RXFFIE</name>
              <bitOffset>31</bitOffset>
              <bitWidth>1</bitWidth>
            </field>
          </fields>
        </register>
        <register>
          <name>CR2</name>
          <addressOffset>0x4</addressOffset>
          <size>0x20</size>
          <fields>
            <field>
              <name>SLVEN</name>
              <bitOffset>0</bitOffset>
              <bitWidth>1</bitWidth>
            </field>
            <field>
              <name>DIS_NSS</name>
              <bitOffset>3</bitOffset>
              <bitWidth>1</bitWidth>
            </field>
            <field>
              <name>ADDM7</name>
              <bitOffset>4</bitOffset>
              <bitWidth>1</bitWidth>
            </field>
            <field>
              <name>LBDL</name>
              <bitOffset>5</bitOffset>
              <bitWidth>1</bitWidth>
            </field>
            <field>
              <name>LBDIE</name>
              <bitOffset>6</bitOffset>
              <bitWidth>1</bitWidth>
            </field>
            <field>
              <name>LBCL</name>
              <bitOffset>8</bitOffset>
              <bitWidth>1</bitWidth>
            </field>
            <field>
              <name>CPHA</name>
              <bitOffset>9</bitOffset>
              <bitWidth>1</bitWidth>
            </field>
            <field>
              <name>CPOL</name>
              <bitOffset>10</bitOffset>
              <bitWidth>1</bitWidth>
            </field>
            <field>
              <name>CLKEN</name>
              <bitOffset>11</bitOffset>
              <bitWidth>1</bitWidth>
            </field>
            <field>
              <name>STOP</name>
              <bitOffset>12</bitOffset>
              <bitWidth>2</bitWidth>
            </field>
            <field>
              <name>LINEN</name>
              <bitOffset>14</bitOffset>
              <bitWidth>1</bitWidth>
            </field>
            <field>
              <name>SWAP</name>
              <bitOffset>15</bitOffset>
              <bitWidth>1</bitWidth>
            </field>
            <field>
              <name>RXINV</name>
              <bitOffset>16</bitOffset>
              <bitWidth>1</bitWidth>
            </field>
            <field>
              <name>TXINV</name>
              <bitOffset>17</bitOffset>
              <bitWidth>1</bitWidth>
            </field>
            <field>
              <name>DATAINV</name>
              <bitOffset>18</bitOffset>
              <bitWidth>1</bitWidth>
            </field>
            <field>
              <name>MSBFIRST</name>
              <bitOffset>19</bitOffset>
              <bitWidth>1</bitWidth>
            </field>
            <field>
              <name>ABREN</name>
              <bitOffset>20</bitOffset>
              <bitWidth>1</bitWidth>
            </field>
            <field>
              <name>ABRMODE</name>
              <bitOffset>21</bitOffset>
              <bitWidth>2</bitWidth>
            </field>
            <field>
              <name>RTOEN</name>
              <bitOffset>23</bitOffset>
              <bitWidth>1</bitWidth>
            </field>
            <field>
              <name>ADD</name>
              <bitOffset>24</bitOffset>
              <bitWidth>8</bitWidth>
            </field>
          </fields>
        </register>
        <register>
          <name>CR3</name>
          <addressOffset>0x8</addressOffset>
          <size>0x20</size>
          <fields>
            <field>
              <name>EIE</name>
              <bitOffset>0</bitOffset>
              <bitWidth>1</bitWidth>
            </field>
            <field>
              <name>IREN</name>
              <bitOffset>1</bitOffset>
              <bitWidth>1</bitWidth>
            </field>
            <field>
              <name>IRLP</name>
              <bitOffset>2</bitOffset>
              <bitWidth>1</bitWidth>
            </field>
            <field>
              <name>HDSEL</name>
              <bitOffset>3</bitOffset>
              <bitWidth>1</bitWidth>
            </field>
            <field>
              <name>NACK</name>
              <bitOffset>4</bitOffset>
              <bitWidth>1</bitWidth>
            </field>
            <field>
              <name>SCEN</name>
              <bitOffset>5</bitOffset>
              <bitWidth>1</bitWidth>
            </field>
            <field>
              <name>DMAR</name>
              <bitOffset>6</bitOffset>
              <bitWidth>1</bitWidth>
            </field>
            <field>
              <name>DMAT</name>
              <bitOffset>7</bitOffset>
              <bitWidth>1</bitWidth>
            </field>
            <field>
              <name>RTSE</name>
              <bitOffset>8</bitOffset>
              <bitWidth>1</bitWidth>
            </field>
            <field>
              <name>CTSE</name>
              <bitOffset>9</bitOffset>
              <bitWidth>1</bitWidth>
            </field>
            <field>
              <name>CTSIE</name>
              <bitOffset>10</bitOffset>
              <bitWidth>1</bitWidth>
            </field>
            <field>
              <name>ONEBIT</name>
              <bitOffset>11</bitOffset>
              <bitWidth>1</bitWidth>
            </field>
            <field>
              <name>OVRDIS</name>
              <bitOffset>12</bitOffset>
              <bitWidth>1</bitWidth>
            </field>
            <field>
              <name>DDRE</name>
              <bitOffset>13</bitOffset>
              <bitWidth>1</bitWidth>
            </field>
            <field>
              <name>DEM</name>
              <bitOffset>14</bitOffset>
              <bitWidth>1</bitWidth>
            </field>
            <field>
              <name>DEP</name>
              <bitOffset>15</bitOffset>
              <bitWidth>1</bitWidth>
            </field>
            <field>
              <name>SCARCNT</name>
              <bitOffset>17</bitOffset>
              <bitWidth>3</bitWidth>
            </field>
            <field>
              <name>WUS</name>
              <bitOffset>20</bitOffset>
              <bitWidth>2</bitWidth>
            </field>
            <field>
              <name>WUFIE</name>
              <bitOffset>22</bitOffset>
              <bitWidth>1</bitWidth>
            </field>
            <field>
              <name>TXFTIE</name>
              <bitOffset>23</bitOffset>
              <bitWidth>1</bitWidth>
            </field>
            <field>
              <name>TCBGTIE</name>
              <bitOffset>24</bitOffset>
              <bitWidth>1</bitWidth>
            </field>
            <field>
              <name>RXFTCFG</name>
              <bitOffset>25</bitOffset>
              <bitWidth>3</bitWidth>
            </field>
            <field>
              <name>RXFTIE</name>
              <bitOffset>28</bitOffset>
              <bitWidth>1</bitWidth>
            </field>
            <field>
              <name>TXFTCFG</name>
              <bitOffset>29</bitOffset>
              <bitWidth>3</bitWidth>
            </field>
          </fields>
        </register>
        <register>
          <name>BRR</name>
          <addressOffset>0xc</addressOffset>
          <size>0x20</size>
          <fields>
            <field>
              <name>DIV_FRACTION</name>
              <bitOffset>0</bitOffset>
              <bitWidth>4</bitWidth>
            </field>
            <field>
              <name>DIV_MANTISSA</name>
              <bitOffset>4</bitOffset>
              <bitWidth>12</bitWidth>
            </field>
          </fields>
        </register>
        <register>
          <name>GTPR</name>
          <addressOffset>0x10</addressOffset>
          <size>0x20</size>
          <fields>
            <field>
              <name>PSC</name>
              <bitOffset>0</bitOffset>
              <bitWidth>8</bitWidth>
            </field>
            <field>
              <name>GT</name>
              <bitOffset>8</bitOffset>
              <bitWidth>8</bitWidth>
            </field>
          </fields>
        </register>
        <register>
          <name>RTOR</name>
          <addressOffset>0x14</addressOffset>
          <size>0x20</size>
          <fields>
            <field>
              <name>RTO</name>
              <bitOffset>0</bitOffset>
              <bitWidth>24</bitWidth>
            </field>
            <field>
              <name>BLEN</name>
              <bitOffset>24</bitOffset>
              <bitWidth>8</bitWidth>
            </field>
          </fields>
        </register>
        <register>
          <name>RQR</name>
          <addressOffset>0x18</addressOffset>
          <size>0x20</size>
          <fields>
            <field>
              <name>ABRRQ</name>
              <bitOffset>0</bitOffset>
              <bitWidth>1</bitWidth>
            </field>
            <field>
              <name>SBKRQ</name>
              <bitOffset>1</bitOffset>
              <bitWidth>1</bitWidth>
            </field>
            <field>
              <name>MMRQ</name>
              <bitOffset>2</bitOffset>
              <bitWidth>1</bitWidth>
            </field>
            <field>
              <name>RXFRQ</name>
              <bitOffset>3</bitOffset>
              <bitWidth>1</bitWidth>
            </field>
            <field>
              <name>TXFRQ</name>
              <bitOffset>4</bitOffset>
              <bitWidth>1</bitWidth>
            </field>
          </fields>
        </register>
        <register>
          <name>ISR</name>
          <addressOffset>0x1c</addressOffset>
          <size>0x20</size>
          <fields>
            <field>
              <name>PE</name>
              <bitOffset>0</bitOffset>
              <bitWidth>1</bitWidth>
            </field>
            <field>
              <name>FE</name>
              <bitOffset>1</bitOffset>
              <bitWidth>1</bitWidth>
            </field>
            <field>
              <name>NE</name>
              <bitOffset>2</bitOffset>
              <bitWidth>1</bitWidth>
            </field>
            <field>
              <name>ORE</name>
              <bitOffset>3</bitOffset>
              <bitWidth>1</bitWidth>
            </field>
            <field>
              <name>IDLE</name>
              <bitOffset>4</bitOffset>
              <bitWidth>1</bitWidth>
            </field>
            <field>
              <name>RXNE_RXFNE</name>
              <bitOffset>5</bitOffset>
              <bitWidth>1</bitWidth>
            </field>
            <field>
              <name>TC</name>
              <bitOffset>6</bitOffset>
              <bitWidth>1</bitWidth>
            </field>
            <field>
              <name>TXE_TXFNF</name>
              <bitOffset>7</bitOffset>
              <bitWidth>1</bitWidth>
            </field>
            <field>
              <name>LBDF</name>
              <bitOffset>8</bitOffset>
              <bitWidth>1</bitWidth>
            </field>
            <field>
              <name>CTSIF</name>
              <bitOffset>9</bitOffset>
              <bitWidth>1</bitWidth>
            </field>
            <field>
              <name>CTS</name>
              <bitOffset>10</bitOffset>
              <bitWidth>1</bitWidth>
            </field>
            <field>
              <name>RTOF</name>
              <bitOffset>11</bitOffset>
              <bitWidth>1</bitWidth>
            </field>
            <field>
              <name>EOBF</name>
              <bitOffset>12</bitOffset>
              <bitWidth>1</bitWidth>
            </field>
            <field>
              <name>UDR</name>
              <bitOffset>13</bitOffset>
              <bitWidth>1</bitWidth>
            </field>
            <field>
              <name>ABRE</name>
              <bitOffset>14</bitOffset>
              <bitWidth>1</bitWidth>
            </field>
            <field>
              <name>ABRF</name>
              <bitOffset>15</bitOffset>
              <bitWidth>1</bitWidth>
            </field>
            <field>
              <name>BUSY</name>
              <bitOffset>16</bitOffset>
              <bitWidth>1</bitWidth>
            </field>
            <field>
              <name>CMF</name>
              <bitOffset>17</bitOffset>
              <bitWidth>1</bitWidth>
            </field>
            <field>
              <name>SBKF</name>
              <bitOffset>18</bitOffset>
              <bitWidth>1</bitWidth>
            </field>
            <field>
              <name>RWU</name>
              <bitOffset>19</bitOffset>
              <bitWidth>1</bitWidth>
            </field>
            <field>
              <name>WUF</name>
              <bitOffset>20</bitOffset>
              <bitWidth>1</bitWidth>
            </field>
            <field>
              <name>TEACK</name>
              <bitOffset>21</bitOffset>
              <bitWidth>1</bitWidth>
            </field>
            <field>
              <name>REACK</name>
              <bitOffset>22</bitOffset>
              <bitWidth>1</bitWidth>
            </field>
            <field>
              <name>TXFE</name>
              <bitOffset>23</bitOffset>
              <bitWidth>1</bitWidth>
            </field>
            <field>
              <name>RXFF</name>
              <bitOffset>24</bitOffset>
              <bitWidth>1</bitWidth>
            </field>
            <field>
              <name>TCBGT</name>
              <bitOffset>25</bitOffset>
              <bitWidth>1</bitWidth>
            </field>
            <field>
              <name>RXFT</name>
              <bitOffset>26</bitOffset>
              <bitWidth>1</bitWidth>
            </field>
            <field>
              <name>TXFT</name>
              <bitOffset>27</bitOffset>
              <bitWidth>1</bitWidth>
            </field>
          </fields>
        </register>
        <register>
          <name>ICR</name>
          <addressOffset>0x20</addressOffset>
          <size>0x20</size>
          <fields>
            <field>
              <name>PECF</name>
              <bitOffset>0</bitOffset>
              <bitWidth>1</bitWidth>
            </field>
            <field>
              <name>FECF</name>
              <bitOffset>1</bitOffset>
              <bitWidth>1</bitWidth>
            </field>
            <field>
              <name>NECF</name>
              <bitOffset>2</bitOffset>
              <bitWidth>1</bitWidth>
            </field>
            <field>
              <name>ORECF</name>
              <bitOffset>3</bitOffset>
              <bitWidth>1</bitWidth>
            </field>
            <field>
              <name>IDLECF</name>
              <bitOffset>4</bitOffset>
              <bitWidth>1</bitWidth>
            </field>
            <field>
              <name>TXFECF</name>
              <bitOffset>5</bitOffset>
              <bitWidth>1</bitWidth>
            </field>
            <field>
              <name>TCCF</name>
              <bitOffset>6</bitOffset>
              <bitWidth>1</bitWidth>
            </field>
            <field>
              <name>TCBGTCF</name>
              <bitOffset>7</bitOffset>
              <bitWidth>1</bitWidth>
            </field>
            <field>
              <name>LBDCF</name>
              <bitOffset>8</bitOffset>
              <bitWidth>1</bitWidth>
            </field>
            <field>
              <name>CTSCF</name>
              <bitOffset>9</bitOffset>
              <bitWidth>1</bitWidth>
            </field>
            <field>
              <name>RTOCF</name>
              <bitOffset>11</bitOffset>
              <bitWidth>1</bitWidth>
            </field>
            <field>
              <name>EOBCF</name>
              <bitOffset>12</bitOffset>
              <bitWidth>1</bitWidth>
            </field>
            <field>
              <name>UDRCF</name>
              <bitOffset>13</bitOffset>
              <bitWidth>1</bitWidth>
            </field>
            <field>
              <name>CMCF</name>
              <bitOffset>17</bitOffset>
              <bitWidth>1</bitWidth>
            </field>
            <field>
              <name>WUCF</name>
              <bitOffset>20</bitOffset>
              <bitWidth>1</bitWidth>
            </field>
          </fields>
        </register>
        <register>
          <name>RDR</name>
          <addressOffset>0x24</addressOffset>
          <size>0x20</size>
          <fields>
            <field>
              <name>RDR</name>
              <bitOffset>0</bitOffset>
              <bitWidth>9</bitWidth>
            </field>
          </fields>
        </register>
        <register>
          <name>TDR</name>
          <addressOffset>0x28</addressOffset>
          <size>0x20</size>
          <fields>
            <field>
              <name>TDR</name>
              <bitOffset>0</bitOffset>
              <bitWidth>9</bitWidth>
            </field>
          </fields>
        </register>
        <register>
          <name>PRESC</name>
          <addressOffset>0x2c</addressOffset>
          <size>0x20</size>
          <fields>
            <field>
              <name>PRESCALER</name>
              <bitOffset>0</bitOffset>
              <bitWidth>4</bitWidth>
            </field>
          </fields>
        </register>
      </registers>
    </peripheral>
    <peripheral>
      <name>USART3</name>
      <baseAddress>0x40004800</baseAddress>
      <registers>
        <register>
          <name>CR1</name>
          <addressOffset>0x0</addressOffset>
          <size>0x20</size>
          <fields>
            <field>
              <name>UE</name>
              <bitOffset>0</bitOffset>
              <bitWidth>1</bitWidth>
            </field>
            <field>
              <name>UESM</name>
              <bitOffset>1</bitOffset>
              <bitWidth>1</bitWidth>
            </field>
            <field>
              <name>RE</name>
              <bitOffset>2</bitOffset>
              <bitWidth>1</bitWidth>
            </field>
            <field>
              <name>TE</name>
              <bitOffset>3</bitOffset>
              <bitWidth>1</bitWidth>
            </field>
            <field>
              <name>IDLEIE</name>
              <bitOffset>4</bitOffset>
              <bitWidth>1</bitWidth>
            </field>
            <field>
              <name>RXNEIE_RXFNEIE</name>
              <bitOffset>5</bitOffset>
              <bitWidth>1</bitWidth>
            </field>
            <field>
              <name>TCIE</name>
              <bitOffset>6</bitOffset>
              <bitWidth>1</bitWidth>
            </field>
            <field>
              <name>TXEIE_TXFNFIE</name>
              <bitOffset>7</bitOffset>
              <bitWidth>1</bitWidth>
            </field>
            <field>
              <name>PEIE</name>
              <bitOffset>8</bitOffset>
              <bitWidth>1</bitWidth>
            </field>
            <field>
              <name>PS</name>
              <bitOffset>9</bitOffset>
              <bitWidth>1</bitWidth>
            </field>
            <field>
              <name>PCE</name>
              <bitOffset>10</bitOffset>
              <bitWidth>1</bitWidth>
            </field>
            <field>
              <name>WAKE</name>
              <bitOffset>11</bitOffset>
              <bitWidth>1</bitWidth>
            </field>
            <field>
              <name>M0</name>
              <bitOffset>12</bitOffset>
              <bitWidth>1</bitWidth>
            </field>
            <field>
              <name>MME</name>
              <bitOffset>13</bitOffset>
              <bitWidth>1</bitWidth>
            </field>
            <field>
              <name>CMIE</name>
              <bitOffset>14</bitOffset>
              <bitWidth>1</bitWidth>
            </field>
            <field>
              <name>OVER8</name>
              <bitOffset>15</bitOffset>
              <bitWidth>1</bitWidth>
            </field>
            <field>
              <name>DEDT</name>
              <bitOffset>16</bitOffset>
              <bitWidth>5</bitWidth>
            </field>
            <field>
              <name>DEAT</name>
              <bitOffset>21</bitOffset>
              <bitWidth>5</bitWidth>
            </field>
            <field>
              <name>RTOIE</name>
              <bitOffset>26</bitOffset>
              <bitWidth>1</bitWidth>
            </field>
            <field>
              <name>EOBIE</name>
              <bitOffset>27</bitOffset>
              <bitWidth>1</bitWidth>
            </field>
            <field>
              <name>M1</name>
              <bitOffset>28</bitOffset>
              <bitWidth>1</bitWidth>
            </field>
            <field>
              <name>FIFOEN</name>
              <bitOffset>29</bitOffset>
              <bitWidth>1</bitWidth>
            </field>
            <field>
              <name>TXFEIE</name>
              <bitOffset>30</bitOffset>
              <bitWidth>1</bitWidth>
            </field>
            <field>
              <name>RXFFIE</name>
              <bitOffset>31</bitOffset>
              <bitWidth>1</bitWidth>
            </field>
          </fields>
        </register>
        <register>
          <name>CR2</name>
          <addressOffset>0x4</addressOffset>
          <size>0x20</size>
          <fields>
            <field>
              <name>SLVEN</name>
              <bitOffset>0</bitOffset>
              <bitWidth>1</bitWidth>
            </field>
            <field>
              <name>DIS_NSS</name>
              <bitOffset>3</bitOffset>
              <bitWidth>1</bitWidth>
            </field>
            <field>
              <name>ADDM7</name>
              <bitOffset>4</bitOffset>
              <bitWidth>1</bitWidth>
            </field>
            <field>
              <name>LBDL</name>
              <bitOffset>5</bitOffset>
              <bitWidth>1</bitWidth>
            </field>
            <field>
              <name>LBDIE</name>
              <bitOffset>6</bitOffset>
              <bitWidth>1</bitWidth>
            </field>
            <field>
              <name>LBCL</name>
              <bitOffset>8</bitOffset>
              <bitWidth>1</bitWidth>
            </field>
            <field>
              <name>CPHA</name>
              <bitOffset>9</bitOffset>
              <bitWidth>1</bitWidth>
            </field>
            <field>
              <name>CPOL</name>
              <bitOffset>10</bitOffset>
              <bitWidth>1</bitWidth>
            </field>
            <field>
              <name>CLKEN</name>
              <bitOffset>11</bitOffset>
              <bitWidth>1</bitWidth>
            </field>
            <field>
              <name>STOP</name>
              <bitOffset>12</bitOffset>
              <bitWidth>2</bitWidth>
            </field>
            <field>
              <name>LINEN</name>
              <bitOffset>14</bitOffset>
              <bitWidth>1</bitWidth>
            </field>
            <field>
              <name>SWAP</name>
              <bitOffset>15</bitOffset>
              <bitWidth>1</bitWidth>
            </field>
            <field>
              <name>RXINV</name>
              <bitOffset>16</bitOffset>
              <bitWidth>1</bitWidth>
            </field>
            <field>
              <name>TXINV</name>
              <bitOffset>17</bitOffset>
              <bitWidth>1</bitWidth>
            </field>
            <field>
              <name>DATAINV</name>
              <bitOffset>18</bitOffset>
              <bitWidth>1</bitWidth>
            </field>
            <field>
              <name>MSBFIRST</name>
              <bitOffset>19</bitOffset>
              <bitWidth>1</bitWidth>
            </field>
            <field>
              <name>ABREN</name>
              <bitOffset>20</bitOffset>
              <bitWidth>1</bitWidth>
            </field>
            <field>
              <name>ABRMODE</name>
              <bitOffset>21</bitOffset>
              <bitWidth>2</bitWidth>
            </field>
            <field>
              <name>RTOEN</name>
              <bitOffset>23</bitOffset>
              <bitWidth>1</bitWidth>
            </field>
            <field>
              <name>ADD</name>
              <bitOffset>24</bitOffset>
              <bitWidth>8</bitWidth>
            </field>
          </fields>
        </register>
        <register>
          <name>CR3</name>
          <addressOffset>0x8</addressOffset>
          <size>0x20</size>
          <fields>
            <field>
              <name>EIE</name>
              <bitOffset>0</bitOffset>
              <bitWidth>1</bitWidth>
            </field>
            <field>
              <name>IREN</name>
              <bitOffset>1</bitOffset>
              <bitWidth>1</bitWidth>
            </field>
            <field>
              <name>IRLP</name>
              <bitOffset>2</bitOffset>
              <bitWidth>1</bitWidth>
            </field>
            <field>
              <name>HDSEL</name>
              <bitOffset>3</bitOffset>
              <bitWidth>1</bitWidth>
            </field>
            <field>
              <name>NACK</name>
              <bitOffset>4</bitOffset>
              <bitWidth>1</bitWidth>
            </field>
            <field>
              <name>SCEN</name>
              <bitOffset>5</bitOffset>
              <bitWidth>1</bitWidth>
            </field>
            <field>
              <name>DMAR</name>
              <bitOffset>6</bitOffset>
              <bitWidth>1</bitWidth>
            </field>
            <field>
              <name>DMAT</name>
              <bitOffset>7</bitOffset>
              <bitWidth>1</bitWidth>
            </field>
            <field>
              <name>RTSE</name>
              <bitOffset>8</bitOffset>
              <bitWidth>1</bitWidth>
            </field>
            <field>
              <name>CTSE</name>
              <bitOffset>9</bitOffset>
              <bitWidth>1</bitWidth>
            </field>
            <field>
              <name>CTSIE</name>
              <bitOffset>10</bitOffset>
              <bitWidth>1</bitWidth>
            </field>
            <field>
              <name>ONEBIT</name>
              <bitOffset>11</bitOffset>
              <bitWidth>1</bitWidth>
            </field>
            <field>
              <name>OVRDIS</name>
              <bitOffset>12</bitOffset>
              <bitWidth>1</bitWidth>
            </field>
            <field>
              <name>DDRE</name>
              <bitOffset>13</bitOffset>
              <bitWidth>1</bitWidth>
            </field>
            <field>
              <name>DEM</name>
              <bitOffset>14</bitOffset>
              <bitWidth>1</bitWidth>
            </field>
            <field>
              <name>DEP</name>
              <bitOffset>15</bitOffset>
              <bitWidth>1</bitWidth>
            </field>
            <field>
              <name>SCARCNT</name>
              <bitOffset>17</bitOffset>
              <bitWidth>3</bitWidth>
            </field>
            <field>
              <name>WUS</name>
              <bitOffset>20</bitOffset>
              <bitWidth>2</bitWidth>
            </field>
            <field>
              <name>WUFIE</name>
              <bitOffset>22</bitOffset>
              <bitWidth>1</bitWidth>
            </field>
            <field>
              <name>TXFTIE</name>
              <bitOffset>23</bitOffset>
              <bitWidth>1</bitWidth>
            </field>
            <field>
              <name>TCBGTIE</name>
              <bitOffset>24</bitOffset>
              <bitWidth>1</bitWidth>
            </field>
            <field>
              <name>RXFTCFG</name>
              <bitOffset>25</bitOffset>
              <bitWidth>3</bitWidth>
            </field>
            <field>
              <name>RXFTIE</name>
              <bitOffset>28</bitOffset>
              <bitWidth>1</bitWidth>
            </field>
            <field>
              <name>TXFTCFG</name>
              <bitOffset>29</bitOffset>
              <bitWidth>3</bitWidth>
            </field>
          </fields>
        </register>
        <register>
          <name>BRR</name>
          <addressOffset>0xc</addressOffset>
          <size>0x20</size>
          <fields>
            <field>
              <name>DIV_FRACTION</name>
              <bitOffset>0</bitOffset>
              <bitWidth>4</bitWidth>
            </field>
            <field>
              <name>DIV_MANTISSA</name>
              <bitOffset>4</bitOffset>
              <bitWidth>12</bitWidth>
            </field>
          </fields>
        </register>
        <register>
          <name>GTPR</name>
          <addressOffset>0x10</addressOffset>
          <size>0x20</size>
          <fields>
            <field>
              <name>PSC</name>
              <bitOffset>0</bitOffset>
              <bitWidth>8</bitWidth>
            </field>
            <field>
              <name>GT</name>
              <bitOffset>8</bitOffset>
              <bitWidth>8</bitWidth>
            </field>
          </fields>
        </register>
        <register>
          <name>RTOR</name>
          <addressOffset>0x14</addressOffset>
          <size>0x20</size>
          <fields>
            <field>
              <name>RTO</name>
              <bitOffset>0</bitOffset>
              <bitWidth>24</bitWidth>
            </field>
            <field>
              <name>BLEN</name>
              <bitOffset>24</bitOffset>
              <bitWidth>8</bitWidth>
            </field>
          </fields>
        </register>
        <register>
          <name>RQR</name>
          <addressOffset>0x18</addressOffset>
          <size>0x20</size>
          <fields>
            <field>
              <name>ABRRQ</name>
              <bitOffset>0</bitOffset>
              <bitWidth>1</bitWidth>
            </field>
            <field>
              <name>SBKRQ</name>
              <bitOffset>1</bitOffset>
              <bitWidth>1</bitWidth>
            </field>
            <field>
              <name>MMRQ</name>
              <bitOffset>2</bitOffset>
              <bitWidth>1</bitWidth>
            </field>
            <field>
              <name>RXFRQ</name>
              <bitOffset>3</bitOffset>
              <bitWidth>1</bitWidth>
            </field>
            <field>
              <name>TXFRQ</name>
              <bitOffset>4</bitOffset>
              <bitWidth>1</bitWidth>
            </field>
          </fields>
        </register>
        <register>
          <name>ISR</name>
          <addressOffset>0x1c</addressOffset>
          <size>0x20</size>
          <fields>
            <field>
              <name>PE</name>
              <bitOffset>0</bitOffset>
              <bitWidth>1</bitWidth>
            </field>
            <field>
              <name>FE</name>
              <bitOffset>1</bitOffset>
              <bitWidth>1</bitWidth>
            </field>
            <field>
              <name>NE</name>
              <bitOffset>2</bitOffset>
              <bitWidth>1</bitWidth>
            </field>
            <field>
              <name>ORE</name>
              <bitOffset>3</bitOffset>
              <bitWidth>1</bitWidth>
            </field>
            <field>
              <name>IDLE</name>
              <bitOffset>4</bitOffset>
              <bitWidth>1</bitWidth>
            </field>
            <field>
              <name>RXNE_RXFNE</name>
              <bitOffset>5</bitOffset>
              <bitWidth>1</bitWidth>
            </field>
            <field>
              <name>TC</name>
              <bitOffset>6</bitOffset>
              <bitWidth>1</bitWidth>
            </field>
            <field>
              <name>TXE_TXFNF</name>
              <bitOffset>7</bitOffset>
              <bitWidth>1</bitWidth>
            </field>
            <field>
              <name>LBDF</name>
              <bitOffset>8</bitOffset>
              <bitWidth>1</bitWidth>
            </field>
            <field>
              <name>CTSIF</name>
              <bitOffset>9</bitOffset>
              <bitWidth>1</bitWidth>
            </field>
            <field>
              <name>CTS</name>
              <bitOffset>10</bitOffset>
              <bitWidth>1</bitWidth>
            </field>
            <field>
              <name>RTOF</name>
              <bitOffset>11</bitOffset>
              <bitWidth>1</bitWidth>
            </field>
            <field>
              <name>EOBF</name>
              <bitOffset>12</bitOffset>
              <bitWidth>1</bitWidth>
            </field>
            <field>
              <name>UDR</name>
              <bitOffset>13</bitOffset>
              <bitWidth>1</bitWidth>
            </field>
            <field>
              <name>ABRE</name>
              <bitOffset>14</bitOffset>
              <bitWidth>1</bitWidth>
            </field>
            <field>
              <name>ABRF</name>
              <bitOffset>15</bitOffset>
              <bitWidth>1</bitWidth>
            </field>
            <field>
              <name>BUSY</name>
              <bitOffset>16</bitOffset>
              <bitWidth>1</bitWidth>
            </field>
            <field>
              <name>CMF</name>
              <bitOffset>17</bitOffset>
              <bitWidth>1</bitWidth>
            </field>
            <field>
              <name>SBKF</name>
              <bitOffset>18</bitOffset>
              <bitWidth>1</bitWidth>
            </field>
            <field>
              <name>RWU</name>
              <bitOffset>19</bitOffset>
              <bitWidth>1</bitWidth>
            </field>
            <field>
              <name>WUF</name>
              <bitOffset>20</bitOffset>
              <bitWidth>1</bitWidth>
            </field>
            <field>
              <name>TEACK</name>
              <bitOffset>21</bitOffset>
              <bitWidth>1</bitWidth>
            </field>
            <field>
              <name>REACK</name>
              <bitOffset>22</bitOffset>
              <bitWidth>1</bitWidth>
            </field>
            <field>
              <name>TXFE</name>
              <bitOffset>23</bitOffset>
              <bitWidth>1</bitWidth>
            </field>
            <field>
              <name>RXFF</name>
              <bitOffset>24</bitOffset>
              <bitWidth>1</bitWidth>
            </field>
            <field>
              <name>TCBGT</name>
              <bitOffset>25</bitOffset>
              <bitWidth>1</bitWidth>
            </field>
            <field>
              <name>RXFT</name>
              <bitOffset>26</bitOffset>
              <bitWidth>1</bitWidth>
            </field>
            <field>
              <name>TXFT</name>
              <bitOffset>27</bitOffset>
              <bitWidth>1</bitWidth>
            </field>
          </fields>
        </register>
        <register>
          <name>ICR</name>
          <addressOffset>0x20</addressOffset>
          <size>0x20</size>
          <fields>
            <field>
              <name>PECF</name>
              <bitOffset>0</bitOffset>
              <bitWidth>1</bitWidth>
            </field>
            <field>
              <name>FECF</name>
              <bitOffset>1</bitOffset>
              <bitWidth>1</bitWidth>
            </field>
            <field>
              <name>NECF</name>
              <bitOffset>2</bitOffset>
              <bitWidth>1</bitWidth>
            </field>
            <field>
              <name>ORECF</name>
              <bitOffset>3</bitOffset>
              <bitWidth>1</bitWidth>
            </field>
            <field>
              <name>IDLECF</name>
              <bitOffset>4</bitOffset>
              <bitWidth>1</bitWidth>
            </field>
            <field>
              <name>TXFECF</name>
              <bitOffset>5</bitOffset>
              <bitWidth>1</bitWidth>
            </field>
            <field>
              <name>TCCF</name>
              <bitOffset>6</bitOffset>
              <bitWidth>1</bitWidth>
            </field>
            <field>
              <name>TCBGTCF</name>
              <bitOffset>7</bitOffset>
              <bitWidth>1</bitWidth>
            </field>
            <field>
              <name>LBDCF</name>
              <bitOffset>8</bitOffset>
              <bitWidth>1</bitWidth>
            </field>
            <field>
              <name>CTSCF</name>
              <bitOffset>9</bitOffset>
              <bitWidth>1</bitWidth>
            </field>
            <field>
              <name>RTOCF</name>
              <bitOffset>11</bitOffset>
              <bitWidth>1</bitWidth>
            </field>
            <field>
              <name>EOBCF</name>
              <bitOffset>12</bitOffset>
              <bitWidth>1</bitWidth>
            </field>
            <field>
              <name>UDRCF</name>
              <bitOffset>13</bitOffset>
              <bitWidth>1</bitWidth>
            </field>
            <field>
              <name>CMCF</name>
              <bitOffset>17</bitOffset>
              <bitWidth>1</bitWidth>
            </field>
            <field>
              <name>WUCF</name>
              <bitOffset>20</bitOffset>
              <bitWidth>1</bitWidth>
            </field>
          </fields>
        </register>
        <register>
          <name>RDR</name>
          <addressOffset>0x24</addressOffset>
          <size>0x20</size>
          <fields>
            <field>
              <name>RDR</name>
              <bitOffset>0</bitOffset>
              <bitWidth>9</bitWidth>
            </field>
          </fields>
        </register>
        <register>
          <name>TDR</name>
          <addressOffset>0x28</addressOffset>
          <size>0x20</size>
          <fields>
            <field>
              <name>TDR</name>
              <bitOffset>0</bitOffset>
              <bitWidth>9</bitWidth>
            </field>
          </fields>
        </register>
        <register>
          <name>PRESC</name>
          <addressOffset>0x2c</addressOffset>
          <size>0x20</size>
          <fields>
            <field>
              <name>PRESCALER</name>
              <bitOffset>0</bitOffset>
              <bitWidth>4</bitWidth>
            </field>
          </fields>
        </register>
      </registers>
    </peripheral>
    <peripheral>
      <name>UART4</name>
      <baseAddress>0x40004c00</baseAddress>
      <registers>
        <register>
          <name>CR1</name>
          <addressOffset>0x0</addressOffset>
          <size>0x20</size>
          <fields>
            <field>
              <name>UE</name>
              <bitOffset>0</bitOffset>
              <bitWidth>1</bitWidth>
            </field>
            <field>
              <name>UESM</name>
              <bitOffset>1</bitOffset>
              <bitWidth>1</bitWidth>
            </field>
            <field>
              <name>RE</name>
              <bitOffset>2</bitOffset>
              <bitWidth>1</bitWidth>
            </field>
            <field>
              <name>TE</name>
              <bitOffset>3</bitOffset>
              <bitWidth>1</bitWidth>
            </field>
            <field>
              <name>IDLEIE</name>
              <bitOffset>4</bitOffset>
              <bitWidth>1</bitWidth>
            </field>
            <field>
              <name>RXNEIE_RXFNEIE</name>
              <bitOffset>5</bitOffset>
              <bitWidth>1</bitWidth>
            </field>
            <field>
              <name>TCIE</name>
              <bitOffset>6</bitOffset>
              <bitWidth>1</bitWidth>
            </field>
            <field>
              <name>TXEIE_TXFNFIE</name>
              <bitOffset>7</bitOffset>
              <bitWidth>1</bitWidth>
            </field>
            <field>
              <name>PEIE</name>
              <bitOffset>8</bitOffset>
              <bitWidth>1</bitWidth>
            </field>
            <field>
              <name>PS</name>
              <bitOffset>9</bitOffset>
              <bitWidth>1</bitWidth>
            </field>
            <field>
              <name>PCE</name>
              <bitOffset>10</bitOffset>
              <bitWidth>1</bitWidth>
            </field>
            <field>
              <name>WAKE</name>
              <bitOffset>11</bitOffset>
              <bitWidth>1</bitWidth>
            </field>
            <field>
              <name>M0</name>
              <bitOffset>12</bitOffset>
              <bitWidth>1</bitWidth>
            </field>
            <field>
              <name>MME</name>
              <bitOffset>13</bitOffset>
              <bitWidth>1</bitWidth>
            </field>
            <field>
              <name>CMIE</name>
              <bitOffset>14</bitOffset>
              <bitWidth>1</bitWidth>
            </field>
            <field>
              <name>OVER8</name>
              <bitOffset>15</bitOffset>
              <bitWidth>1</bitWidth>
            </field>
            <field>
              <name>DEDT</name>
              <bitOffset>16</bitOffset>
              <bitWidth>5</bitWidth>
            </field>
            <field>
              <name>DEAT</name>
              <bitOffset>21</bitOffset>
              <bitWidth>5</bitWidth>
            </field>
            <field>
              <name>RTOIE</name>
              <bitOffset>26</bitOffset>
              <bitWidth>1</bitWidth>
            </field>
            <field>
              <name>EOBIE</name>
              <bitOffset>27</bitOffset>
              <bitWidth>1</bitWidth>
            </field>
            <field>
              <name>M1</name>
              <bitOffset>28</bitOffset>
              <bitWidth>1</bitWidth>
            </field>
            <field>
              <name>FIFOEN</name>
              <bitOffset>29</bitOffset>
              <bitWidth>1</bitWidth>
            </field>
            <field>
              <name>TXFEIE</name>
              <bitOffset>30</bitOffset>
              <bitWidth>1</bitWidth>
            </field>
            <field>
              <name>RXFFIE</name>
              <bitOffset>31</bitOffset>
              <bitWidth>1</bitWidth>
            </field>
          </fields>
        </register>
        <register>
          <name>CR2</name>
          <addressOffset>0x4</addressOffset>
          <size>0x20</size>
          <fields>
            <field>
              <name>SLVEN</name>
              <bitOffset>0</bitOffset>
              <bitWidth>1</bitWidth>
            </field>
            <field>
              <name>DIS_NSS</name>
              <bitOffset>3</bitOffset>
              <bitWidth>1</bitWidth>
            </field>
            <field>
              <name>ADDM7</name>
              <bitOffset>4</bitOffset>
              <bitWidth>1</bitWidth>
            </field>
            <field>
              <name>LBDL</name>
              <bitOffset>5</bitOffset>
              <bitWidth>1</bitWidth>
            </field>
            <field>
              <name>LBDIE</name>
              <bitOffset>6</bitOffset>
              <bitWidth>1</bitWidth>
            </field>
            <field>
              <name>LBCL</name>
              <bitOffset>8</bitOffset>
              <bitWidth>1</bitWidth>
            </field>
            <field>
              <name>CPHA</name>
              <bitOffset>9</bitOffset>
              <bitWidth>1</bitWidth>
            </field>
            <field>
              <name>CPOL</name>
              <bitOffset>10</bitOffset>
              <bitWidth>1</bitWidth>
            </field>
            <field>
              <name>CLKEN</name>
              <bitOffset>11</bitOffset>
              <bitWidth>1</bitWidth>
            </field>
            <field>
              <name>STOP</name>
              <bitOffset>12</bitOffset>
              <bitWidth>2</bitWidth>
            </field>
            <field>
              <name>LINEN</name>
              <bitOffset>14</bitOffset>
              <bitWidth>1</bitWidth>
            </field>
            <field>
              <name>SWAP</name>
              <bitOffset>15</bitOffset>
              <bitWidth>1</bitWidth>
            </field>
            <field>
              <name>RXINV</name>
              <bitOffset>16</bitOffset>
              <bitWidth>1</bitWidth>
            </field>
            <field>
              <name>TXINV</name>
              <bitOffset>17</bitOffset>
              <bitWidth>1</bitWidth>
            </field>
            <field>
              <name>DATAINV</name>
              <bitOffset>18</bitOffset>
              <bitWidth>1</bitWidth>
            </field>
            <field>
              <name>MSBFIRST</name>
              <bitOffset>19</bitOffset>
              <bitWidth>1</bitWidth>
            </field>
            <field>
              <name>ABREN</name>
              <bitOffset>20</bitOffset>
              <bitWidth>1</bitWidth>
            </field>
            <field>
              <name>ABRMODE</name>
              <bitOffset>21</bitOffset>
              <bitWidth>2</bitWidth>
            </field>
            <field>
              <name>RTOEN</name>
              <bitOffset>23</bitOffset>
              <bitWidth>1</bitWidth>
            </field>
            <field>
              <name>ADD</name>
              <bitOffset>24</bitOffset>
              <bitWidth>8</bitWidth>
            </field>
          </fields>
        </register>
        <register>
          <name>CR3</name>
          <addressOffset>0x8</addressOffset>
          <size>0x20</size>
          <fields>
            <field>
              <name>EIE</name>
              <bitOffset>0</bitOffset>
              <bitWidth>1</bitWidth>
            </field>
            <field>
              <name>IREN</name>
              <bitOffset>1</bitOffset>
              <bitWidth>1</bitWidth>
            </field>
            <field>
              <name>IRLP</name>
              <bitOffset>2</bitOffset>
              <bitWidth>1</bitWidth>
            </field>
            <field>
              <name>HDSEL</name>
              <bitOffset>3</bitOffset>
              <bitWidth>1</bitWidth>
            </field>
            <field>
              <name>NACK</name>
              <bitOffset>4</bitOffset>
              <bitWidth>1</bitWidth>
            </field>
            <field>
              <name>SCEN</name>
              <bitOffset>5</bitOffset>
              <bitWidth>1</bitWidth>
            </field>
            <field>
              <name>DMAR</name>
              <bitOffset>6</bitOffset>
              <bitWidth>1</bitWidth>
            </field>
            <field>
              <name>DMAT</name>
              <bitOffset>7</bitOffset>
              <bitWidth>1</bitWidth>
            </field>
            <field>
              <name>RTSE</name>
              <bitOffset>8</bitOffset>
              <bitWidth>1</bitWidth>
            </field>
            <field>
              <name>CTSE</name>
              <bitOffset>9</bitOffset>
              <bitWidth>1</bitWidth>
            </field>
            <field>
              <name>CTSIE</name>
              <bitOffset>10</bitOffset>
              <bitWidth>1</bitWidth>
            </field>
            <field>
              <name>ONEBIT</name>
              <bitOffset>11</bitOffset>
              <bitWidth>1</bitWidth>
            </field>
            <field>
              <name>OVRDIS</name>
              <bitOffset>12</bitOffset>
              <bitWidth>1</bitWidth>
            </field>
            <field>
              <name>DDRE</name>
              <bitOffset>13</bitOffset>
              <bitWidth>1</bitWidth>
            </field>
            <field>
              <name>DEM</name>
              <bitOffset>14</bitOffset>
              <bitWidth>1</bitWidth>
            </field>
            <field>
              <name>DEP</name>
              <bitOffset>15</bitOffset>
              <bitWidth>1</bitWidth>
            </field>
            <field>
              <name>SCARCNT</name>
              <bitOffset>17</bitOffset>
              <bitWidth>3</bitWidth>
            </field>
            <field>
              <name>WUS</name>
              <bitOffset>20</bitOffset>
              <bitWidth>2</bitWidth>
            </field>
            <field>
              <name>WUFIE</name>
              <bitOffset>22</bitOffset>
              <bitWidth>1</bitWidth>
            </field>
            <field>
              <name>TXFTIE</name>
              <bitOffset>23</bitOffset>
              <bitWidth>1</bitWidth>
            </field>
            <field>
              <name>TCBGTIE</name>
              <bitOffset>24</bitOffset>
              <bitWidth>1</bitWidth>
            </field>
            <field>
              <name>RXFTCFG</name>
              <bitOffset>25</bitOffset>
              <bitWidth>3</bitWidth>
            </field>
            <field>
              <name>RXFTIE</name>
              <bitOffset>28</bitOffset>
              <bitWidth>1</bitWidth>
            </field>
            <field>
              <name>TXFTCFG</name>
              <bitOffset>29</bitOffset>
              <bitWidth>3</bitWidth>
            </field>
          </fields>
        </register>
        <register>
          <name>BRR</name>
          <addressOffset>0xc</addressOffset>
          <size>0x20</size>
          <fields>
            <field>
              <name>DIV_FRACTION</name>
              <bitOffset>0</bitOffset>
              <bitWidth>4</bitWidth>
            </field>
            <field>
              <name>DIV_MANTISSA</name>
              <bitOffset>4</bitOffset>
              <bitWidth>12</bitWidth>
            </field>
          </fields>
        </register>
        <register>
          <name>GTPR</name>
          <addressOffset>0x10</addressOffset>
          <size>0x20</size>
          <fields>
            <field>
              <name>PSC</name>
              <bitOffset>0</bitOffset>
              <bitWidth>8</bitWidth>
            </field>
            <field>
              <name>GT</name>
              <bitOffset>8</bitOffset>
              <bitWidth>8</bitWidth>
            </field>
          </fields>
        </register>
        <register>
          <name>RTOR</name>
          <addressOffset>0x14</addressOffset>
          <size>0x20</size>
          <fields>
            <field>
              <name>RTO</name>
              <bitOffset>0</bitOffset>
              <bitWidth>24</bitWidth>
            </field>
            <field>
              <name>BLEN</name>
              <bitOffset>24</bitOffset>
              <bitWidth>8</bitWidth>
            </field>
          </fields>
        </register>
        <register>
          <name>RQR</name>
          <addressOffset>0x18</addressOffset>
          <size>0x20</size>
          <fields>
            <field>
              <name>ABRRQ</name>
              <bitOffset>0</bitOffset>
              <bitWidth>1</bitWidth>
            </field>
            <field>
              <name>SBKRQ</name>
              <bitOffset>1</bitOffset>
              <bitWidth>1</bitWidth>
            </field>
            <field>
              <name>MMRQ</name>
              <bitOffset>2</bitOffset>
              <bitWidth>1</bitWidth>
            </field>
            <field>
              <name>RXFRQ</name>
              <bitOffset>3</bitOffset>
              <bitWidth>1</bitWidth>
            </field>
            <field>
              <name>TXFRQ</name>
              <bitOffset>4</bitOffset>
              <bitWidth>1</bitWidth>
            </field>
          </fields>
        </register>
        <register>
          <name>ISR</name>
          <addressOffset>0x1c</addressOffset>
          <size>0x20</size>
          <fields>
            <field>
              <name>PE</name>
              <bitOffset>0</bitOffset>
              <bitWidth>1</bitWidth>
            </field>
            <field>
              <name>FE</name>
              <bitOffset>1</bitOffset>
              <bitWidth>1</bitWidth>
            </field>
            <field>
              <name>NE</name>
              <bitOffset>2</bitOffset>
              <bitWidth>1</bitWidth>
            </field>
            <field>
              <name>ORE</name>
              <bitOffset>3</bitOffset>
              <bitWidth>1</bitWidth>
            </field>
            <field>
              <name>IDLE</name>
              <bitOffset>4</bitOffset>
              <bitWidth>1</bitWidth>
            </field>
            <field>
              <name>RXNE_RXFNE</name>
              <bitOffset>5</bitOffset>
              <bitWidth>1</bitWidth>
            </field>
            <field>
              <name>TC</name>
              <bitOffset>6</bitOffset>
              <bitWidth>1</bitWidth>
            </field>
            <field>
              <name>TXE_TXFNF</name>
              <bitOffset>7</bitOffset>
              <bitWidth>1</bitWidth>
            </field>
            <field>
              <name>LBDF</name>
              <bitOffset>8</bitOffset>
              <bitWidth>1</bitWidth>
            </field>
            <field>
              <name>CTSIF</name>
              <bitOffset>9</bitOffset>
              <bitWidth>1</bitWidth>
            </field>
            <field>
              <name>CTS</name>
              <bitOffset>10</bitOffset>
              <bitWidth>1</bitWidth>
            </field>
            <field>
              <name>RTOF</name>
              <bitOffset>11</bitOffset>
              <bitWidth>1</bitWidth>
            </field>
            <field>
              <name>EOBF</name>
              <bitOffset>12</bitOffset>
              <bitWidth>1</bitWidth>
            </field>
            <field>
              <name>UDR</name>
              <bitOffset>13</bitOffset>
              <bitWidth>1</bitWidth>
            </field>
            <field>
              <name>ABRE</name>
              <bitOffset>14</bitOffset>
              <bitWidth>1</bitWidth>
            </field>
            <field>
              <name>ABRF</name>
              <bitOffset>15</bitOffset>
              <bitWidth>1</bitWidth>
            </field>
            <field>
              <name>BUSY</name>
              <bitOffset>16</bitOffset>
              <bitWidth>1</bitWidth>
            </field>
            <field>
              <name>CMF</name>
              <bitOffset>17</bitOffset>
              <bitWidth>1</bitWidth>
            </field>
            <field>
              <name>SBKF</name>
              <bitOffset>18</bitOffset>
              <bitWidth>1</bitWidth>
            </field>
            <field>
              <name>RWU</name>
              <bitOffset>19</bitOffset>
              <bitWidth>1</bitWidth>
            </field>
            <field>
              <name>WUF</name>
              <bitOffset>20</bitOffset>
              <bitWidth>1</bitWidth>
            </field>
            <field>
              <name>TEACK</name>
              <bitOffset>21</bitOffset>
              <bitWidth>1</bitWidth>
            </field>
            <field>
              <name>REACK</name>
              <bitOffset>22</bitOffset>
              <bitWidth>1</bitWidth>
            </field>
            <field>
              <name>TXFE</name>
              <bitOffset>23</bitOffset>
              <bitWidth>1</bitWidth>
            </field>
            <field>
              <name>RXFF</name>
              <bitOffset>24</bitOffset>
              <bitWidth>1</bitWidth>
            </field>
            <field>
              <name>TCBGT</name>
              <bitOffset>25</bitOffset>
              <bitWidth>1</bitWidth>
            </field>
            <field>
              <name>RXFT</name>
              <bitOffset>26</bitOffset>
              <bitWidth>1</bitWidth>
            </field>
            <field>
              <name>TXFT</name>
              <bitOffset>27</bitOffset>
              <bitWidth>1</bitWidth>
            </field>
          </fields>
        </register>
        <register>
          <name>ICR</name>
          <addressOffset>0x20</addressOffset>
          <size>0x20</size>
          <fields>
            <field>
              <name>PECF</name>
              <bitOffset>0</bitOffset>
              <bitWidth>1</bitWidth>
            </field>
            <field>
              <name>FECF</name>
              <bitOffset>1</bitOffset>
              <bitWidth>1</bitWidth>
            </field>
            <field>
              <name>NECF</name>
              <bitOffset>2</bitOffset>
              <bitWidth>1</bitWidth>
            </field>
            <field>
              <name>ORECF</name>
              <bitOffset>3</bitOffset>
              <bitWidth>1</bitWidth>
            </field>
            <field>
              <name>IDLECF</name>
              <bitOffset>4</bitOffset>
              <bitWidth>1</bitWidth>
            </field>
            <field>
              <name>TXFECF</name>
              <bitOffset>5</bitOffset>
              <bitWidth>1</bitWidth>
            </field>
            <field>
              <name>TCCF</name>
              <bitOffset>6</bitOffset>
              <bitWidth>1</bitWidth>
            </field>
            <field>
              <name>TCBGTCF</name>
              <bitOffset>7</bitOffset>
              <bitWidth>1</bitWidth>
            </field>
            <field>
              <name>LBDCF</name>
              <bitOffset>8</bitOffset>
              <bitWidth>1</bitWidth>
            </field>
            <field>
              <name>CTSCF</name>
              <bitOffset>9</bitOffset>
              <bitWidth>1</bitWidth>
            </field>
            <field>
              <name>RTOCF</name>
              <bitOffset>11</bitOffset>
              <bitWidth>1</bitWidth>
            </field>
            <field>
              <name>EOBCF</name>
              <bitOffset>12</bitOffset>
              <bitWidth>1</bitWidth>
            </field>
            <field>
              <name>UDRCF</name>
              <bitOffset>13</bitOffset>
              <bitWidth>1</bitWidth>
            </field>
            <field>
              <name>CMCF</name>
              <bitOffset>17</bitOffset>
              <bitWidth>1</bitWidth>
            </field>
            <field>
              <name>WUCF</name>
              <bitOffset>20</bitOffset>
              <bitWidth>1</bitWidth>
            </field>
          </fields>
        </register>
        <register>
          <name>RDR</name>
          <addressOffset>0x24</addressOffset>
          <size>0x20</size>
          <fields>
            <field>
              <name>RDR</name>
              <bitOffset>0</bitOffset>
              <bitWidth>9</bitWidth>
            </field>
          </fields>
        </register>
        <register>
          <name>TDR</name>
          <addressOffset>0x28</addressOffset>
          <size>0x20</size>
          <fields>
            <field>
              <name>TDR</name>
              <bitOffset>0</bitOffset>
              <bitWidth>9</bitWidth>
            </field>
          </fields>
        </register>
        <register>
          <name>PRESC</name>
          <addressOffset>0x2c</addressOffset>
          <size>0x20</size>
          <fields>
            <field>
              <name>PRESCALER</name>
              <bitOffset>0</bitOffset>
              <bitWidth>4</bitWidth>
            </field>
          </fields>
        </register>
      </registers>
    </peripheral>
    <peripheral>
      <name>UART5</name>
      <baseAddress>0x40005000</baseAddress>
      <registers>
        <register>
          <name>CR1</name>
          <addressOffset>0x0</addressOffset>
          <size>0x20</size>
          <fields>
            <field>
              <name>UE</name>
              <bitOffset>0</bitOffset>
              <bitWidth>1</bitWidth>
            </field>
            <field>
              <name>UESM</name>
              <bitOffset>1</bitOffset>
              <bitWidth>1</bitWidth>
            </field>
            <field>
              <name>RE</name>
              <bitOffset>2</bitOffset>
              <bitWidth>1</bitWidth>
            </field>
            <field>
              <name>TE</name>
              <bitOffset>3</bitOffset>
              <bitWidth>1</bitWidth>
            </field>
            <field>
              <name>IDLEIE</name>
              <bitOffset>4</bitOffset>
              <bitWidth>1</bitWidth>
            </field>
            <field>
              <name>RXNEIE_RXFNEIE</name>
              <bitOffset>5</bitOffset>
              <bitWidth>1</bitWidth>
            </field>
            <field>
              <name>TCIE</name>
              <bitOffset>6</bitOffset>
              <bitWidth>1</bitWidth>
            </field>
            <field>
              <name>TXEIE_TXFNFIE</name>
              <bitOffset>7</bitOffset>
              <bitWidth>1</bitWidth>
            </field>
            <field>
              <name>PEIE</name>
              <bitOffset>8</bitOffset>
              <bitWidth>1</bitWidth>
            </field>
            <field>
              <name>PS</name>
              <bitOffset>9</bitOffset>
              <bitWidth>1</bitWidth>
            </field>
            <field>
              <name>PCE</name>
              <bitOffset>10</bitOffset>
              <bitWidth>1</bitWidth>
            </field>
            <field>
              <name>WAKE</name>
              <bitOffset>11</bitOffset>
              <bitWidth>1</bitWidth>
            </field>
            <field>
              <name>M0</name>
              <bitOffset>12</bitOffset>
              <bitWidth>1</bitWidth>
            </field>
            <field>
              <name>MME</name>
              <bitOffset>13</bitOffset>
              <bitWidth>1</bitWidth>
            </field>
            <field>
              <name>CMIE</name>
              <bitOffset>14</bitOffset>
              <bitWidth>1</bitWidth>
            </field>
            <field>
              <name>OVER8</name>
              <bitOffset>15</bitOffset>
              <bitWidth>1</bitWidth>
            </field>
            <field>
              <name>DEDT</name>
              <bitOffset>16</bitOffset>
              <bitWidth>5</bitWidth>
            </field>
            <field>
              <name>DEAT</name>
              <bitOffset>21</bitOffset>
              <bitWidth>5</bitWidth>
            </field>
            <field>
              <name>RTOIE</name>
              <bitOffset>26</bitOffset>
              <bitWidth>1</bitWidth>
            </field>
            <field>
              <name>EOBIE</name>
              <bitOffset>27</bitOffset>
              <bitWidth>1</bitWidth>
            </field>
            <field>
              <name>M1</name>
              <bitOffset>28</bitOffset>
              <bitWidth>1</bitWidth>
            </field>
            <field>
              <name>FIFOEN</name>
              <bitOffset>29</bitOffset>
              <bitWidth>1</bitWidth>
            </field>
            <field>
              <name>TXFEIE</name>
              <bitOffset>30</bitOffset>
              <bitWidth>1</bitWidth>
            </field>
            <field>
              <name>RXFFIE</name>
              <bitOffset>31</bitOffset>
              <bitWidth>1</bitWidth>
            </field>
          </fields>
        </register>
        <register>
          <name>CR2</name>
          <addressOffset>0x4</addressOffset>
          <size>0x20</size>
          <fields>
            <field>
              <name>SLVEN</name>
              <bitOffset>0</bitOffset>
              <bitWidth>1</bitWidth>
            </field>
            <field>
              <name>DIS_NSS</name>
              <bitOffset>3</bitOffset>
              <bitWidth>1</bitWidth>
            </field>
            <field>
              <name>ADDM7</name>
              <bitOffset>4</bitOffset>
              <bitWidth>1</bitWidth>
            </field>
            <field>
              <name>LBDL</name>
              <bitOffset>5</bitOffset>
              <bitWidth>1</bitWidth>
            </field>
            <field>
              <name>LBDIE</name>
              <bitOffset>6</bitOffset>
              <bitWidth>1</bitWidth>
            </field>
            <field>
              <name>LBCL</name>
              <bitOffset>8</bitOffset>
              <bitWidth>1</bitWidth>
            </field>
            <field>
              <name>CPHA</name>
              <bitOffset>9</bitOffset>
              <bitWidth>1</bitWidth>
            </field>
            <field>
              <name>CPOL</name>
              <bitOffset>10</bitOffset>
              <bitWidth>1</bitWidth>
            </field>
            <field>
              <name>CLKEN</name>
              <bitOffset>11</bitOffset>
              <bitWidth>1</bitWidth>
            </field>
            <field>
              <name>STOP</name>
              <bitOffset>12</bitOffset>
              <bitWidth>2</bitWidth>
            </field>
            <field>
              <name>LINEN</name>
              <bitOffset>14</bitOffset>
              <bitWidth>1</bitWidth>
            </field>
            <field>
              <name>SWAP</name>
              <bitOffset>15</bitOffset>
              <bitWidth>1</bitWidth>
            </field>
            <field>
              <name>RXINV</name>
              <bitOffset>16</bitOffset>
              <bitWidth>1</bitWidth>
            </field>
            <field>
              <name>TXINV</name>
              <bitOffset>17</bitOffset>
              <bitWidth>1</bitWidth>
            </field>
            <field>
              <name>DATAINV</name>
              <bitOffset>18</bitOffset>
              <bitWidth>1</bitWidth>
            </field>
            <field>
              <name>MSBFIRST</name>
              <bitOffset>19</bitOffset>
              <bitWidth>1</bitWidth>
            </field>
            <field>
              <name>ABREN</name>
              <bitOffset>20</bitOffset>
              <bitWidth>1</bitWidth>
            </field>
            <field>
              <name>ABRMODE</name>
              <bitOffset>21</bitOffset>
              <bitWidth>2</bitWidth>
            </field>
            <field>
              <name>RTOEN</name>
              <bitOffset>23</bitOffset>
              <bitWidth>1</bitWidth>
            </field>
            <field>
              <name>ADD</name>
              <bitOffset>24</bitOffset>
              <bitWidth>8</bitWidth>
            </field>
          </fields>
        </register>
        <register>
          <name>CR3</name>
          <addressOffset>0x8</addressOffset>
          <size>0x20</size>
          <fields>
            <field>
              <name>EIE</name>
              <bitOffset>0</bitOffset>
              <bitWidth>1</bitWidth>
            </field>
            <field>
              <name>IREN</name>
              <bitOffset>1</bitOffset>
              <bitWidth>1</bitWidth>
            </field>
            <field>
              <name>IRLP</name>
              <bitOffset>2</bitOffset>
              <bitWidth>1</bitWidth>
            </field>
            <field>
              <name>HDSEL</name>
              <bitOffset>3</bitOffset>
              <bitWidth>1</bitWidth>
            </field>
            <field>
              <name>NACK</name>
              <bitOffset>4</bitOffset>
              <bitWidth>1</bitWidth>
            </field>
            <field>
              <name>SCEN</name>
              <bitOffset>5</bitOffset>
              <bitWidth>1</bitWidth>
            </field>
            <field>
              <name>DMAR</name>
              <bitOffset>6</bitOffset>
              <bitWidth>1</bitWidth>
            </field>
            <field>
              <name>DMAT</name>
              <bitOffset>7</bitOffset>
              <bitWidth>1</bitWidth>
            </field>
            <field>
              <name>RTSE</name>
              <bitOffset>8</bitOffset>
              <bitWidth>1</bitWidth>
            </field>
            <field>
              <name>CTSE</name>
              <bitOffset>9</bitOffset>
              <bitWidth>1</bitWidth>
            </field>
            <field>
              <name>CTSIE</name>
              <bitOffset>10</bitOffset>
              <bitWidth>1</bitWidth>
            </field>
            <field>
              <name>ONEBIT</name>
              <bitOffset>11</bitOffset>
              <bitWidth>1</bitWidth>
            </field>
            <field>
              <name>OVRDIS</name>
              <bitOffset>12</bitOffset>
              <bitWidth>1</bitWidth>
            </field>
            <field>
              <name>DDRE</name>
              <bitOffset>13</bitOffset>
              <bitWidth>1</bitWidth>
            </field>
            <field>
              <name>DEM</name>
              <bitOffset>14</bitOffset>
              <bitWidth>1</bitWidth>
            </field>
            <field>
              <name>DEP</name>
              <bitOffset>15</bitOffset>
              <bitWidth>1</bitWidth>
            </field>
            <field>
              <name>SCARCNT</name>
              <bitOffset>17</bitOffset>
              <bitWidth>3</bitWidth>
            </field>
            <field>
              <name>WUS</name>
              <bitOffset>20</bitOffset>
              <bitWidth>2</bitWidth>
            </field>
            <field>
              <name>WUFIE</name>
              <bitOffset>22</bitOffset>
              <bitWidth>1</bitWidth>
            </field>
            <field>
              <name>TXFTIE</name>
              <bitOffset>23</bitOffset>
              <bitWidth>1</bitWidth>
            </field>
            <field>
              <name>TCBGTIE</name>
              <bitOffset>24</bitOffset>
              <bitWidth>1</bitWidth>
            </field>
            <field>
              <name>RXFTCFG</name>
              <bitOffset>25</bitOffset>
              <bitWidth>3</bitWidth>
            </field>
            <field>
              <name>RXFTIE</name>
              <bitOffset>28</bitOffset>
              <bitWidth>1</bitWidth>
            </field>
            <field>
              <name>TXFTCFG</name>
              <bitOffset>29</bitOffset>
              <bitWidth>3</bitWidth>
            </field>
          </fields>
        </register>
        <register>
          <name>BRR</name>
          <addressOffset>0xc</addressOffset>
          <size>0x20</size>
          <fields>
            <field>
              <name>DIV_FRACTION</name>
              <bitOffset>0</bitOffset>
              <bitWidth>4</bitWidth>
            </field>
            <field>
              <name>DIV_MANTISSA</name>
              <bitOffset>4</bitOffset>
              <bitWidth>12</bitWidth>
            </field>
          </fields>
        </register>
        <register>
          <name>GTPR</name>
          <addressOffset>0x10</addressOffset>
          <size>0x20</size>
          <fields>
            <field>
              <name>PSC</name>
              <bitOffset>0</bitOffset>
              <bitWidth>8</bitWidth>
            </field>
            <field>
              <name>GT</name>
              <bitOffset>8</bitOffset>
              <bitWidth>8</bitWidth>
            </field>
          </fields>
        </register>
        <register>
          <name>RTOR</name>
          <addressOffset>0x14</addressOffset>
          <size>0x20</size>
          <fields>
            <field>
              <name>RTO</name>
              <bitOffset>0</bitOffset>
              <bitWidth>24</bitWidth>
            </field>
            <field>
              <name>BLEN</name>
              <bitOffset>24</bitOffset>
              <bitWidth>8</bitWidth>
            </field>
          </fields>
        </register>
        <register>
          <name>RQR</name>
          <addressOffset>0x18</addressOffset>
          <size>0x20</size>
          <fields>
            <field>
              <name>ABRRQ</name>
              <bitOffset>0</bitOffset>
              <bitWidth>1</bitWidth>
            </field>
            <field>
              <name>SBKRQ</name>
              <bitOffset>1</bitOffset>
              <bitWidth>1</bitWidth>
            </field>
            <field>
              <name>MMRQ</name>
              <bitOffset>2</bitOffset>
              <bitWidth>1</bitWidth>
            </field>
            <field>
              <name>RXFRQ</name>
              <bitOffset>3</bitOffset>
              <bitWidth>1</bitWidth>
            </field>
            <field>
              <name>TXFRQ</name>
              <bitOffset>4</bitOffset>
              <bitWidth>1</bitWidth>
            </field>
          </fields>
        </register>
        <register>
          <name>ISR</name>
          <addressOffset>0x1c</addressOffset>
          <size>0x20</size>
          <fields>
            <field>
              <name>PE</name>
              <bitOffset>0</bitOffset>
              <bitWidth>1</bitWidth>
            </field>
            <field>
              <name>FE</name>
              <bitOffset>1</bitOffset>
              <bitWidth>1</bitWidth>
            </field>
            <field>
              <name>NE</name>
              <bitOffset>2</bitOffset>
              <bitWidth>1</bitWidth>
            </field>
            <field>
              <name>ORE</name>
              <bitOffset>3</bitOffset>
              <bitWidth>1</bitWidth>
            </field>
            <field>
              <name>IDLE</name>
              <bitOffset>4</bitOffset>
              <bitWidth>1</bitWidth>
            </field>
            <field>
              <name>RXNE_RXFNE</name>
              <bitOffset>5</bitOffset>
              <bitWidth>1</bitWidth>
            </field>
            <field>
              <name>TC</name>
              <bitOffset>6</bitOffset>
              <bitWidth>1</bitWidth>
            </field>
            <field>
              <name>TXE_TXFNF</name>
              <bitOffset>7</bitOffset>
              <bitWidth>1</bitWidth>
            </field>
            <field>
              <name>LBDF</name>
              <bitOffset>8</bitOffset>
              <bitWidth>1</bitWidth>
            </field>
            <field>
              <name>CTSIF</name>
              <bitOffset>9</bitOffset>
              <bitWidth>1</bitWidth>
            </field>
            <field>
              <name>CTS</name>
              <bitOffset>10</bitOffset>
              <bitWidth>1</bitWidth>
            </field>
            <field>
              <name>RTOF</name>
              <bitOffset>11</bitOffset>
              <bitWidth>1</bitWidth>
            </field>
            <field>
              <name>EOBF</name>
              <bitOffset>12</bitOffset>
              <bitWidth>1</bitWidth>
            </field>
            <field>
              <name>UDR</name>
              <bitOffset>13</bitOffset>
              <bitWidth>1</bitWidth>
            </field>
            <field>
              <name>ABRE</name>
              <bitOffset>14</bitOffset>
              <bitWidth>1</bitWidth>
            </field>
            <field>
              <name>ABRF</name>
              <bitOffset>15</bitOffset>
              <bitWidth>1</bitWidth>
            </field>
            <field>
              <name>BUSY</name>
              <bitOffset>16</bitOffset>
              <bitWidth>1</bitWidth>
            </field>
            <field>
              <name>CMF</name>
              <bitOffset>17</bitOffset>
              <bitWidth>1</bitWidth>
            </field>
            <field>
              <name>SBKF</name>
              <bitOffset>18</bitOffset>
              <bitWidth>1</bitWidth>
            </field>
            <field>
              <name>RWU</name>
              <bitOffset>19</bitOffset>
              <bitWidth>1</bitWidth>
            </field>
            <field>
              <name>WUF</name>
              <bitOffset>20</bitOffset>
              <bitWidth>1</bitWidth>
            </field>
            <field>
              <name>TEACK</name>
              <bitOffset>21</bitOffset>
              <bitWidth>1</bitWidth>
            </field>
            <field>
              <name>REACK</name>
              <bitOffset>22</bitOffset>
              <bitWidth>1</bitWidth>
            </field>
            <field>
              <name>TXFE</name>
              <bitOffset>23</bitOffset>
              <bitWidth>1</bitWidth>
            </field>
            <field>
              <name>RXFF</name>
              <bitOffset>24</bitOffset>
              <bitWidth>1</bitWidth>
            </field>
            <field>
              <name>TCBGT</name>
              <bitOffset>25</bitOffset>
              <bitWidth>1</bitWidth>
            </field>
            <field>
              <name>RXFT</name>
              <bitOffset>26</bitOffset>
              <bitWidth>1</bitWidth>
            </field>
            <field>
              <name>TXFT</name>
              <bitOffset>27</bitOffset>
              <bitWidth>1</bitWidth>
            </field>
          </fields>
        </register>
        <register>
          <name>ICR</name>
          <addressOffset>0x20</addressOffset>
          <size>0x20</size>
          <fields>
            <field>
              <name>PECF</name>
              <bitOffset>0</bitOffset>
              <bitWidth>1</bitWidth>
            </field>
            <field>
              <name>FECF</name>
              <bitOffset>1</bitOffset>
              <bitWidth>1</bitWidth>
            </field>
            <field>
              <name>NECF</name>
              <bitOffset>2</bitOffset>
              <bitWidth>1</bitWidth>
            </field>
            <field>
              <name>ORECF</name>
              <bitOffset>3</bitOffset>
              <bitWidth>1</bitWidth>
            </field>
            <field>
              <name>IDLECF</name>
              <bitOffset>4</bitOffset>
              <bitWidth>1</bitWidth>
            </field>
            <field>
              <name>TXFECF</name>
              <bitOffset>5</bitOffset>
              <bitWidth>1</bitWidth>
            </field>
            <field>
              <name>TCCF</name>
              <bitOffset>6</bitOffset>
              <bitWidth>1</bitWidth>
            </field>
            <field>
              <name>TCBGTCF</name>
              <bitOffset>7</bitOffset>
              <bitWidth>1</bitWidth>
            </field>
            <field>
              <name>LBDCF</name>
              <bitOffset>8</bitOffset>
              <bitWidth>1</bitWidth>
            </field>
            <field>
              <name>CTSCF</name>
              <bitOffset>9</bitOffset>
              <bitWidth>1</bitWidth>
            </field>
            <field>
              <name>RTOCF</name>
              <bitOffset>11</bitOffset>
              <bitWidth>1</bitWidth>
            </field>
            <field>
              <name>EOBCF</name>
              <bitOffset>12</bitOffset>
              <bitWidth>1</bitWidth>
            </field>
            <field>
              <name>UDRCF</name>
              <bitOffset>13</bitOffset>
              <bitWidth>1</bitWidth>
            </field>
            <field>
              <name>CMCF</name>
              <bitOffset>17</bitOffset>
              <bitWidth>1</bitWidth>
            </field>
            <field>
              <name>WUCF</name>
              <bitOffset>20</bitOffset>
              <bitWidth>1</bitWidth>
            </field>
          </fields>
        </register>
        <register>
          <name>RDR</name>
          <addressOffset>0x24</addressOffset>
          <size>0x20</size>
          <fields>
            <field>
              <name>RDR</name>
              <bitOffset>0</bitOffset>
              <bitWidth>9</bitWidth>
            </field>
          </fields>
        </register>
        <register>
          <name>TDR</name>
          <addressOffset>0x28</addressOffset>
          <size>0x20</size>
          <fields>
            <field>
              <name>TDR</name>
              <bitOffset>0</bitOffset>
              <bitWidth>9</bitWidth>
            </field>
          </fields>
        </register>
        <register>
          <name>PRESC</name>
          <addressOffset>0x2c</addressOffset>
          <size>0x20</size>
          <fields>
            <field>
              <name>PRESCALER</name>
              <bitOffset>0</bitOffset>
              <bitWidth>4</bitWidth>
            </field>
          </fields>
        </register>
      </registers>
    </peripheral>
    <peripheral>
      <name>I2C1</name>
      <baseAddress>0x40005400</baseAddress>
      <registers>
        <register>
          <name>CR1</name>
          <addressOffset>0x0</addressOffset>
          <size>0x20</size>
          <fields>
            <field>
              <name>PE</name>
              <bitOffset>0</bitOffset>
              <bitWidth>1</bitWidth>
            </field>
            <field>
              <name>TXIE</name>
              <bitOffset>1</bitOffset>
              <bitWidth>1</bitWidth>
            </field>
            <field>
              <name>RXIE</name>
              <bitOffset>2</bitOffset>
              <bitWidth>1</bitWidth>
            </field>
            <field>
              <name>ADDRIE</name>
              <bitOffset>3</bitOffset>
              <bitWidth>1</bitWidth>
            </field>
            <field>
              <name>NACKIE</name>
              <bitOffset>4</bitOffset>
              <bitWidth>1</bitWidth>
            </field>
            <field>
              <name>STOPIE</name>
              <bitOffset>5</bitOffset>
              <bitWidth>1</bitWidth>
            </field>
            <field>
              <name>TCIE</name>
              <bitOffset>6</bitOffset>
              <bitWidth>1</bitWidth>
            </field>
            <field>
              <name>ERRIE</name>
              <bitOffset>7</bitOffset>
              <bitWidth>1</bitWidth>
            </field>
            <field>
              <name>DNF</name>
              <bitOffset>8</bitOffset>
              <bitWidth>4</bitWidth>
            </field>
            <field>
              <name>ANFOFF</name>
              <bitOffset>12</bitOffset>
              <bitWidth>1</bitWidth>
            </field>
            <field>
              <name>TXDMAEN</name>
              <bitOffset>14</bitOffset>
              <bitWidth>1</bitWidth>
            </field>
            <field>
              <name>RXDMAEN</name>
              <bitOffset>15</bitOffset>
              <bitWidth>1</bitWidth>
            </field>
            <field>
              <name>SBC</name>
              <bitOffset>16</bitOffset>
              <bitWidth>1</bitWidth>
            </field>
            <field>
              <name>NOSTRETCH</name>
              <bitOffset>17</bitOffset>
              <bitWidth>1</bitWidth>
            </field>
            <field>
              <name>WUPEN</name>
              <bitOffset>18</bitOffset>
              <bitWidth>1</bitWidth>
            </field>
            <field>
              <name>GCEN</name>
              <bitOffset>19</bitOffset>
              <bitWidth>1</bitWidth>
            </field>
            <field>
              <name>SMBHEN</name>
              <bitOffset>20</bitOffset>
              <bitWidth>1</bitWidth>
            </field>
            <field>
              <name>SMBDEN</name>
              <bitOffset>21</bitOffset>
              <bitWidth>1</bitWidth>
            </field>
            <field>
              <name>ALERTEN</name>
              <bitOffset>22</bitOffset>
              <bitWidth>1</bitWidth>
            </field>
            <field>
              <name>PECEN</name>
              <bitOffset>23</bitOffset>
              <bitWidth>1</bitWidth>
            </field>
          </fields>
        </register>
        <register>
          <name>CR2</name>
          <addressOffset>0x4</addressOffset>
          <size>0x20</size>
          <fields>
            <field>
              <name>SADD</name>
              <bitOffset>0</bitOffset>
              <bitWidth>10</bitWidth>
            </field>
            <field>
              <name>RD_WRN</name>
              <bitOffset>10</bitOffset>
              <bitWidth>1</bitWidth>
            </field>
            <field>
              <name>ADD10</name>
              <bitOffset>11</bitOffset>
              <bitWidth>1</bitWidth>
            </field>
            <field>
              <name>HEAD10R</name>
              <bitOffset>12</bitOffset>
              <bitWidth>1</bitWidth>
            </field>
            <field>
              <name>START</name>
              <bitOffset>13</bitOffset>
              <bitWidth>1</bitWidth>
            </field>
            <field>
              <name>STOP</name>
              <bitOffset>14</bitOffset>
              <bitWidth>1</bitWidth>
            </field>
            <field>
              <name>NACK</name>
              <bitOffset>15</bitOffset>
              <bitWidth>1</bitWidth>
            </field>
            <field>
              <name>NBYTES</name>
              <bitOffset>16</bitOffset>
              <bitWidth>8</bitWidth>
            </field>
            <field>
              <name>RELOAD</name>
              <bitOffset>24</bitOffset>
              <bitWidth>1</bitWidth>
            </field>
            <field>
              <name>AUTOEND</name>
              <bitOffset>25</bitOffset>
              <bitWidth>1</bitWidth>
            </field>
            <field>
              <name>PECBYTE</name>
              <bitOffset>26</bitOffset>
              <bitWidth>1</bitWidth>
            </field>
          </fields>
        </register>
        <register>
          <name>OAR1</name>
          <addressOffset>0x8</addressOffset>
          <size>0x20</size>
          <fields>
            <field>
              <name>OA1</name>
              <bitOffset>0</bitOffset>
              <bitWidth>10</bitWidth>
            </field>
            <field>
              <name>OA1MODE</name>
              <bitOffset>10</bitOffset>
              <bitWidth>1</bitWidth>
            </field>
            <field>
              <name>OA1EN</name>
              <bitOffset>15</bitOffset>
              <bitWidth>1</bitWidth>
            </field>
          </fields>
        </register>
        <register>
          <name>OAR2</name>
          <addressOffset>0xc</addressOffset>
          <size>0x20</size>
          <fields>
            <field>
              <name>OA2</name>
              <bitOffset>1</bitOffset>
              <bitWidth>7</bitWidth>
            </field>
            <field>
              <name>OA2MSK</name>
              <bitOffset>8</bitOffset>
              <bitWidth>3</bitWidth>
            </field>
            <field>
              <name>OA2MASK06</name>
              <bitOffset>9</bitOffset>
              <bitWidth>2</bitWidth>
            </field>
            <field>
              <name>OA2MASK04</name>
              <bitOffset>10</bitOffset>
              <bitWidth>1</bitWidth>
            </field>
            <field>
              <name>OA2EN</name>
              <bitOffset>15</bitOffset>
              <bitWidth>1</bitWidth>
            </field>
          </fields>
        </register>
        <register>
          <name>TIMINGR</name>
          <addressOffset>0x10</addressOffset>
          <size>0x20</size>
          <fields>
            <field>
              <name>SCLL</name>
              <bitOffset>0</bitOffset>
              <bitWidth>8</bitWidth>
            </field>
            <field>
              <name>SCLH</name>
              <bitOffset>8</bitOffset>
              <bitWidth>8</bitWidth>
            </field>
            <field>
              <name>SDADEL</name>
              <bitOffset>16</bitOffset>
              <bitWidth>4</bitWidth>
            </field>
            <field>
              <name>SCLDEL</name>
              <bitOffset>20</bitOffset>
              <bitWidth>4</bitWidth>
            </field>
            <field>
              <name>PRESC</name>
              <bitOffset>28</bitOffset>
              <bitWidth>4</bitWidth>
            </field>
          </fields>
        </register>
        <register>
          <name>TIMEOUTR</name>
          <addressOffset>0x14</addressOffset>
          <size>0x20</size>
          <fields>
            <field>
              <name>TIMEOUTA</name>
              <bitOffset>0</bitOffset>
              <bitWidth>12</bitWidth>
            </field>
            <field>
              <name>TIDLE</name>
              <bitOffset>12</bitOffset>
              <bitWidth>1</bitWidth>
            </field>
            <field>
              <name>TIMOUTEN</name>
              <bitOffset>15</bitOffset>
              <bitWidth>1</bitWidth>
            </field>
            <field>
              <name>TIMEOUTB</name>
              <bitOffset>16</bitOffset>
              <bitWidth>12</bitWidth>
            </field>
            <field>
              <name>TEXTEN</name>
              <bitOffset>31</bitOffset>
              <bitWidth>1</bitWidth>
            </field>
          </fields>
        </register>
        <register>
          <name>ISR</name>
          <addressOffset>0x18</addressOffset>
          <size>0x20</size>
          <fields>
            <field>
              <name>TXE</name>
              <bitOffset>0</bitOffset>
              <bitWidth>1</bitWidth>
            </field>
            <field>
              <name>TXIS</name>
              <bitOffset>1</bitOffset>
              <bitWidth>1</bitWidth>
            </field>
            <field>
              <name>RXNE</name>
              <bitOffset>2</bitOffset>
              <bitWidth>1</bitWidth>
            </field>
            <field>
              <name>ADDR</name>
              <bitOffset>3</bitOffset>
              <bitWidth>1</bitWidth>
            </field>
            <field>
              <name>NACKF</name>
              <bitOffset>4</bitOffset>
              <bitWidth>1</bitWidth>
            </field>
            <field>
              <name>STOPF</name>
              <bitOffset>5</bitOffset>
              <bitWidth>1</bitWidth>
            </field>
            <field>
              <name>TC</name>
              <bitOffset>6</bitOffset>
              <bitWidth>1</bitWidth>
            </field>
            <field>
              <name>TCR</name>
              <bitOffset>7</bitOffset>
              <bitWidth>1</bitWidth>
            </field>
            <field>
              <name>BERR</name>
              <bitOffset>8</bitOffset>
              <bitWidth>1</bitWidth>
            </field>
            <field>
              <name>ARLO</name>
              <bitOffset>9</bitOffset>
              <bitWidth>1</bitWidth>
            </field>
            <field>
              <name>OVR</name>
              <bitOffset>10</bitOffset>
              <bitWidth>1</bitWidth>
            </field>
            <field>
              <name>PECERR</name>
              <bitOffset>11</bitOffset>
              <bitWidth>1</bitWidth>
            </field>
            <field>
              <name>TIMEOUT</name>
              <bitOffset>12</bitOffset>
              <bitWidth>1</bitWidth>
            </field>
            <field>
              <name>ALERT</name>
              <bitOffset>13</bitOffset>
              <bitWidth>1</bitWidth>
            </field>
            <field>
              <name>BUSY</name>
              <bitOffset>15</bitOffset>
              <bitWidth>1</bitWidth>
            </field>
            <field>
              <name>DIR</name>
              <bitOffset>16</bitOffset>
              <bitWidth>1</bitWidth>
            </field>
            <field>
              <name>ADDCODE</name>
              <bitOffset>17</bitOffset>
              <bitWidth>7</bitWidth>
            </field>
          </fields>
        </register>
        <register>
          <name>ICR</name>
          <addressOffset>0x1c</addressOffset>
          <size>0x20</size>
          <fields>
            <field>
              <name>ADDRCF</name>
              <bitOffset>3</bitOffset>
              <bitWidth>1</bitWidth>
            </field>
            <field>
              <name>NACKCF</name>
              <bitOffset>4</bitOffset>
              <bitWidth>1</bitWidth>
            </field>
            <field>
              <name>STOPCF</name>
              <bitOffset>5</bitOffset>
              <bitWidth>1</bitWidth>
            </field>
            <field>
              <name>BERRCF</name>
              <bitOffset>8</bitOffset>
              <bitWidth>1</bitWidth>
            </field>
            <field>
              <name>ARLOCF</name>
              <bitOffset>9</bitOffset>
              <bitWidth>1</bitWidth>
            </field>
            <field>
              <name>OVRCF</name>
              <bitOffset>10</bitOffset>
              <bitWidth>1</bitWidth>
            </field>
            <field>
              <name>PECCF</name>
              <bitOffset>11</bitOffset>
              <bitWidth>1</bitWidth>
            </field>
            <field>
              <name>TIMOUTCF</name>
              <bitOffset>12</bitOffset>
              <bitWidth>1</bitWidth>
            </field>
            <field>
              <name>ALERTCF</name>
              <bitOffset>13</bitOffset>
              <bitWidth>1</bitWidth>
            </field>
          </fields>
        </register>
        <register>
          <name>PECR</name>
          <addressOffset>0x20</addressOffset>
          <size>0x20</size>
          <fields>
            <field>
              <name>PEC</name>
              <bitOffset>0</bitOffset>
              <bitWidth>8</bitWidth>
            </field>
          </fields>
        </register>
        <register>
          <name>RXDR</name>
          <addressOffset>0x24</addressOffset>
          <size>0x20</size>
          <fields>
            <field>
              <name>RXDATA</name>
              <bitOffset>0</bitOffset>
              <bitWidth>8</bitWidth>
            </field>
          </fields>
        </register>
        <register>
          <name>TXDR</name>
          <addressOffset>0x28</addressOffset>
          <size>0x20</size>
          <fields>
            <field>
              <name>TXDATA</name>
              <bitOffset>0</bitOffset>
              <bitWidth>8</bitWidth>
            </field>
          </fields>
        </register>
      </registers>
    </peripheral>
    <peripheral>
      <name>I2C2</name>
      <baseAddress>0x40005800</baseAddress>
      <registers>
        <register>
          <name>CR1</name>
          <addressOffset>0x0</addressOffset>
          <size>0x20</size>
          <fields>
            <field>
              <name>PE</name>
              <bitOffset>0</bitOffset>
              <bitWidth>1</bitWidth>
            </field>
            <field>
              <name>TXIE</name>
              <bitOffset>1</bitOffset>
              <bitWidth>1</bitWidth>
            </field>
            <field>
              <name>RXIE</name>
              <bitOffset>2</bitOffset>
              <bitWidth>1</bitWidth>
            </field>
            <field>
              <name>ADDRIE</name>
              <bitOffset>3</bitOffset>
              <bitWidth>1</bitWidth>
            </field>
            <field>
              <name>NACKIE</name>
              <bitOffset>4</bitOffset>
              <bitWidth>1</bitWidth>
            </field>
            <field>
              <name>STOPIE</name>
              <bitOffset>5</bitOffset>
              <bitWidth>1</bitWidth>
            </field>
            <field>
              <name>TCIE</name>
              <bitOffset>6</bitOffset>
              <bitWidth>1</bitWidth>
            </field>
            <field>
              <name>ERRIE</name>
              <bitOffset>7</bitOffset>
              <bitWidth>1</bitWidth>
            </field>
            <field>
              <name>DNF</name>
              <bitOffset>8</bitOffset>
              <bitWidth>4</bitWidth>
            </field>
            <field>
              <name>ANFOFF</name>
              <bitOffset>12</bitOffset>
              <bitWidth>1</bitWidth>
            </field>
            <field>
              <name>TXDMAEN</name>
              <bitOffset>14</bitOffset>
              <bitWidth>1</bitWidth>
            </field>
            <field>
              <name>RXDMAEN</name>
              <bitOffset>15</bitOffset>
              <bitWidth>1</bitWidth>
            </field>
            <field>
              <name>SBC</name>
              <bitOffset>16</bitOffset>
              <bitWidth>1</bitWidth>
            </field>
            <field>
              <name>NOSTRETCH</name>
              <bitOffset>17</bitOffset>
              <bitWidth>1</bitWidth>
            </field>
            <field>
              <name>WUPEN</name>
              <bitOffset>18</bitOffset>
              <bitWidth>1</bitWidth>
            </field>
            <field>
              <name>GCEN</name>
              <bitOffset>19</bitOffset>
              <bitWidth>1</bitWidth>
            </field>
            <field>
              <name>SMBHEN</name>
              <bitOffset>20</bitOffset>
              <bitWidth>1</bitWidth>
            </field>
            <field>
              <name>SMBDEN</name>
              <bitOffset>21</bitOffset>
              <bitWidth>1</bitWidth>
            </field>
            <field>
              <name>ALERTEN</name>
              <bitOffset>22</bitOffset>
              <bitWidth>1</bitWidth>
            </field>
            <field>
              <name>PECEN</name>
              <bitOffset>23</bitOffset>
              <bitWidth>1</bitWidth>
            </field>
          </fields>
        </register>
        <register>
          <name>CR2</name>
          <addressOffset>0x4</addressOffset>
          <size>0x20</size>
          <fields>
            <field>
              <name>SADD</name>
              <bitOffset>0</bitOffset>
              <bitWidth>10</bitWidth>
            </field>
            <field>
              <name>RD_WRN</name>
              <bitOffset>10</bitOffset>
              <bitWidth>1</bitWidth>
            </field>
            <field>
              <name>ADD10</name>
              <bitOffset>11</bitOffset>
              <bitWidth>1</bitWidth>
            </field>
            <field>
              <name>HEAD10R</name>
              <bitOffset>12</bitOffset>
              <bitWidth>1</bitWidth>
            </field>
            <field>
              <name>START</name>
              <bitOffset>13</bitOffset>
              <bitWidth>1</bitWidth>
            </field>
            <field>
              <name>STOP</name>
              <bitOffset>14</bitOffset>
              <bitWidth>1</bitWidth>
            </field>
            <field>
              <name>NACK</name>
              <bitOffset>15</bitOffset>
              <bitWidth>1</bitWidth>
            </field>
            <field>
              <name>NBYTES</name>
              <bitOffset>16</bitOffset>
              <bitWidth>8</bitWidth>
            </field>
            <field>
              <name>RELOAD</name>
              <bitOffset>24</bitOffset>
              <bitWidth>1</bitWidth>
            </field>
            <field>
              <name>AUTOEND</name>
              <bitOffset>25</bitOffset>
              <bitWidth>1</bitWidth>
            </field>
            <field>
              <name>PECBYTE</name>
              <bitOffset>26</bitOffset>
              <bitWidth>1</bitWidth>
            </field>
          </fields>
        </register>
        <register>
          <name>OAR1</name>
          <addressOffset>0x8</addressOffset>
          <size>0x20</size>
          <fields>
            <field>
              <name>OA1</name>
              <bitOffset>0</bitOffset>
              <bitWidth>10</bitWidth>
            </field>
            <field>
              <name>OA1MODE</name>
              <bitOffset>10</bitOffset>
              <bitWidth>1</bitWidth>
            </field>
            <field>
              <name>OA1EN</name>
              <bitOffset>15</bitOffset>
              <bitWidth>1</bitWidth>
            </field>
          </fields>
        </register>
        <register>
          <name>OAR2</name>
          <addressOffset>0xc</addressOffset>
          <size>0x20</size>
          <fields>
            <field>
              <name>OA2</name>
              <bitOffset>1</bitOffset>
              <bitWidth>7</bitWidth>
            </field>
            <field>
              <name>OA2MSK</name>
              <bitOffset>8</bitOffset>
              <bitWidth>3</bitWidth>
            </field>
            <field>
              <name>OA2MASK06</name>
              <bitOffset>9</bitOffset>
              <bitWidth>2</bitWidth>
            </field>
            <field>
              <name>OA2MASK04</name>
              <bitOffset>10</bitOffset>
              <bitWidth>1</bitWidth>
            </field>
            <field>
              <name>OA2EN</name>
              <bitOffset>15</bitOffset>
              <bitWidth>1</bitWidth>
            </field>
          </fields>
        </register>
        <register>
          <name>TIMINGR</name>
          <addressOffset>0x10</addressOffset>
          <size>0x20</size>
          <fields>
            <field>
              <name>SCLL</name>
              <bitOffset>0</bitOffset>
              <bitWidth>8</bitWidth>
            </field>
            <field>
              <name>SCLH</name>
              <bitOffset>8</bitOffset>
              <bitWidth>8</bitWidth>
            </field>
            <field>
              <name>SDADEL</name>
              <bitOffset>16</bitOffset>
              <bitWidth>4</bitWidth>
            </field>
            <field>
              <name>SCLDEL</name>
              <bitOffset>20</bitOffset>
              <bitWidth>4</bitWidth>
            </field>
            <field>
              <name>PRESC</name>
              <bitOffset>28</bitOffset>
              <bitWidth>4</bitWidth>
            </field>
          </fields>
        </register>
        <register>
          <name>TIMEOUTR</name>
          <addressOffset>0x14</addressOffset>
          <size>0x20</size>
          <fields>
            <field>
              <name>TIMEOUTA</name>
              <bitOffset>0</bitOffset>
              <bitWidth>12</bitWidth>
            </field>
            <field>
              <name>TIDLE</name>
              <bitOffset>12</bitOffset>
              <bitWidth>1</bitWidth>
            </field>
            <field>
              <name>TIMOUTEN</name>
              <bitOffset>15</bitOffset>
              <bitWidth>1</bitWidth>
            </field>
            <field>
              <name>TIMEOUTB</name>
              <bitOffset>16</bitOffset>
              <bitWidth>12</bitWidth>
            </field>
            <field>
              <name>TEXTEN</name>
              <bitOffset>31</bitOffset>
              <bitWidth>1</bitWidth>
            </field>
          </fields>
        </register>
        <register>
          <name>ISR</name>
          <addressOffset>0x18</addressOffset>
          <size>0x20</size>
          <fields>
            <field>
              <name>TXE</name>
              <bitOffset>0</bitOffset>
              <bitWidth>1</bitWidth>
            </field>
            <field>
              <name>TXIS</name>
              <bitOffset>1</bitOffset>
              <bitWidth>1</bitWidth>
            </field>
            <field>
              <name>RXNE</name>
              <bitOffset>2</bitOffset>
              <bitWidth>1</bitWidth>
            </field>
            <field>
              <name>ADDR</name>
              <bitOffset>3</bitOffset>
              <bitWidth>1</bitWidth>
            </field>
            <field>
              <name>NACKF</name>
              <bitOffset>4</bitOffset>
              <bitWidth>1</bitWidth>
            </field>
            <field>
              <name>STOPF</name>
              <bitOffset>5</bitOffset>
              <bitWidth>1</bitWidth>
            </field>
            <field>
              <name>TC</name>
              <bitOffset>6</bitOffset>
              <bitWidth>1</bitWidth>
            </field>
            <field>
              <name>TCR</name>
              <bitOffset>7</bitOffset>
              <bitWidth>1</bitWidth>
            </field>
            <field>
              <name>BERR</name>
              <bitOffset>8</bitOffset>
              <bitWidth>1</bitWidth>
            </field>
            <field>
              <name>ARLO</name>
              <bitOffset>9</bitOffset>
              <bitWidth>1</bitWidth>
            </field>
            <field>
              <name>OVR</name>
              <bitOffset>10</bitOffset>
              <bitWidth>1</bitWidth>
            </field>
            <field>
              <name>PECERR</name>
              <bitOffset>11</bitOffset>
              <bitWidth>1</bitWidth>
            </field>
            <field>
              <name>TIMEOUT</name>
              <bitOffset>12</bitOffset>
              <bitWidth>1</bitWidth>
            </field>
            <field>
              <name>ALERT</name>
              <bitOffset>13</bitOffset>
              <bitWidth>1</bitWidth>
            </field>
            <field>
              <name>BUSY</name>
              <bitOffset>15</bitOffset>
              <bitWidth>1</bitWidth>
            </field>
            <field>
              <name>DIR</name>
              <bitOffset>16</bitOffset>
              <bitWidth>1</bitWidth>
            </field>
            <field>
              <name>ADDCODE</name>
              <bitOffset>17</bitOffset>
              <bitWidth>7</bitWidth>
            </field>
          </fields>
        </register>
        <register>
          <name>ICR</name>
          <addressOffset>0x1c</addressOffset>
          <size>0x20</size>
          <fields>
            <field>
              <name>ADDRCF</name>
              <bitOffset>3</bitOffset>
              <bitWidth>1</bitWidth>
            </field>
            <field>
              <name>NACKCF</name>
              <bitOffset>4</bitOffset>
              <bitWidth>1</bitWidth>
            </field>
            <field>
              <name>STOPCF</name>
              <bitOffset>5</bitOffset>
              <bitWidth>1</bitWidth>
            </field>
            <field>
              <name>BERRCF</name>
              <bitOffset>8</bitOffset>
              <bitWidth>1</bitWidth>
            </field>
            <field>
              <name>ARLOCF</name>
              <bitOffset>9</bitOffset>
              <bitWidth>1</bitWidth>
            </field>
            <field>
              <name>OVRCF</name>
              <bitOffset>10</bitOffset>
              <bitWidth>1</bitWidth>
            </field>
            <field>
              <name>PECCF</name>
              <bitOffset>11</bitOffset>
              <bitWidth>1</bitWidth>
            </field>
            <field>
              <name>TIMOUTCF</name>
              <bitOffset>12</bitOffset>
              <bitWidth>1</bitWidth>
            </field>
            <field>
              <name>ALERTCF</name>
              <bitOffset>13</bitOffset>
              <bitWidth>1</bitWidth>
            </field>
          </fields>
        </register>
        <register>
          <name>PECR</name>
          <addressOffset>0x20</addressOffset>
          <size>0x20</size>
          <fields>
            <field>
              <name>PEC</name>
              <bitOffset>0</bitOffset>
              <bitWidth>8</bitWidth>
            </field>
          </fields>
        </register>
        <register>
          <name>RXDR</name>
          <addressOffset>0x24</addressOffset>
          <size>0x20</size>
          <fields>
            <field>
              <name>RXDATA</name>
              <bitOffset>0</bitOffset>
              <bitWidth>8</bitWidth>
            </field>
          </fields>
        </register>
        <register>
          <name>TXDR</name>
          <addressOffset>0x28</addressOffset>
          <size>0x20</size>
          <fields>
            <field>
              <name>TXDATA</name>
              <bitOffset>0</bitOffset>
              <bitWidth>8</bitWidth>
            </field>
          </fields>
        </register>
      </registers>
    </peripheral>
    <peripheral>
      <name>I2C3</name>
      <baseAddress>0x40005c00</baseAddress>
      <registers>
        <register>
          <name>CR1</name>
          <addressOffset>0x0</addressOffset>
          <size>0x20</size>
          <fields>
            <field>
              <name>PE</name>
              <bitOffset>0</bitOffset>
              <bitWidth>1</bitWidth>
            </field>
            <field>
              <name>TXIE</name>
              <bitOffset>1</bitOffset>
              <bitWidth>1</bitWidth>
            </field>
            <field>
              <name>RXIE</name>
              <bitOffset>2</bitOffset>
              <bitWidth>1</bitWidth>
            </field>
            <field>
              <name>ADDRIE</name>
              <bitOffset>3</bitOffset>
              <bitWidth>1</bitWidth>
            </field>
            <field>
              <name>NACKIE</name>
              <bitOffset>4</bitOffset>
              <bitWidth>1</bitWidth>
            </field>
            <field>
              <name>STOPIE</name>
              <bitOffset>5</bitOffset>
              <bitWidth>1</bitWidth>
            </field>
            <field>
              <name>TCIE</name>
              <bitOffset>6</bitOffset>
              <bitWidth>1</bitWidth>
            </field>
            <field>
              <name>ERRIE</name>
              <bitOffset>7</bitOffset>
              <bitWidth>1</bitWidth>
            </field>
            <field>
              <name>DNF</name>
              <bitOffset>8</bitOffset>
              <bitWidth>4</bitWidth>
            </field>
            <field>
              <name>ANFOFF</name>
              <bitOffset>12</bitOffset>
              <bitWidth>1</bitWidth>
            </field>
            <field>
              <name>TXDMAEN</name>
              <bitOffset>14</bitOffset>
              <bitWidth>1</bitWidth>
            </field>
            <field>
              <name>RXDMAEN</name>
              <bitOffset>15</bitOffset>
              <bitWidth>1</bitWidth>
            </field>
            <field>
              <name>SBC</name>
              <bitOffset>16</bitOffset>
              <bitWidth>1</bitWidth>
            </field>
            <field>
              <name>NOSTRETCH</name>
              <bitOffset>17</bitOffset>
              <bitWidth>1</bitWidth>
            </field>
            <field>
              <name>WUPEN</name>
              <bitOffset>18</bitOffset>
              <bitWidth>1</bitWidth>
            </field>
            <field>
              <name>GCEN</name>
              <bitOffset>19</bitOffset>
              <bitWidth>1</bitWidth>
            </field>
            <field>
              <name>SMBHEN</name>
              <bitOffset>20</bitOffset>
              <bitWidth>1</bitWidth>
            </field>
            <field>
              <name>SMBDEN</name>
              <bitOffset>21</bitOffset>
              <bitWidth>1</bitWidth>
            </field>
            <field>
              <name>ALERTEN</name>
              <bitOffset>22</bitOffset>
              <bitWidth>1</bitWidth>
            </field>
            <field>
              <name>PECEN</name>
              <bitOffset>23</bitOffset>
              <bitWidth>1</bitWidth>
            </field>
          </fields>
        </register>
        <register>
          <name>CR2</name>
          <addressOffset>0x4</addressOffset>
          <size>0x20</size>
          <fields>
            <field>
              <name>SADD</name>
              <bitOffset>0</bitOffset>
              <bitWidth>10</bitWidth>
            </field>
            <field>
              <name>RD_WRN</name>
              <bitOffset>10</bitOffset>
              <bitWidth>1</bitWidth>
            </field>
            <field>
              <name>ADD10</name>
              <bitOffset>11</bitOffset>
              <bitWidth>1</bitWidth>
            </field>
            <field>
              <name>HEAD10R</name>
              <bitOffset>12</bitOffset>
              <bitWidth>1</bitWidth>
            </field>
            <field>
              <name>START</name>
              <bitOffset>13</bitOffset>
              <bitWidth>1</bitWidth>
            </field>
            <field>
              <name>STOP</name>
              <bitOffset>14</bitOffset>
              <bitWidth>1</bitWidth>
            </field>
            <field>
              <name>NACK</name>
              <bitOffset>15</bitOffset>
              <bitWidth>1</bitWidth>
            </field>
            <field>
              <name>NBYTES</name>
              <bitOffset>16</bitOffset>
              <bitWidth>8</bitWidth>
            </field>
            <field>
              <name>RELOAD</name>
              <bitOffset>24</bitOffset>
              <bitWidth>1</bitWidth>
            </field>
            <field>
              <name>AUTOEND</name>
              <bitOffset>25</bitOffset>
              <bitWidth>1</bitWidth>
            </field>
            <field>
              <name>PECBYTE</name>
              <bitOffset>26</bitOffset>
              <bitWidth>1</bitWidth>
            </field>
          </fields>
        </register>
        <register>
          <name>OAR1</name>
          <addressOffset>0x8</addressOffset>
          <size>0x20</size>
          <fields>
            <field>
              <name>OA1</name>
              <bitOffset>0</bitOffset>
              <bitWidth>10</bitWidth>
            </field>
            <field>
              <name>OA1MODE</name>
              <bitOffset>10</bitOffset>
              <bitWidth>1</bitWidth>
            </field>
            <field>
              <name>OA1EN</name>
              <bitOffset>15</bitOffset>
              <bitWidth>1</bitWidth>
            </field>
          </fields>
        </register>
        <register>
          <name>OAR2</name>
          <addressOffset>0xc</addressOffset>
          <size>0x20</size>
          <fields>
            <field>
              <name>OA2</name>
              <bitOffset>1</bitOffset>
              <bitWidth>7</bitWidth>
            </field>
            <field>
              <name>OA2MSK</name>
              <bitOffset>8</bitOffset>
              <bitWidth>3</bitWidth>
            </field>
            <field>
              <name>OA2MASK06</name>
              <bitOffset>9</bitOffset>
              <bitWidth>2</bitWidth>
            </field>
            <field>
              <name>OA2MASK04</name>
              <bitOffset>10</bitOffset>
              <bitWidth>1</bitWidth>
            </field>
            <field>
              <name>OA2EN</name>
              <bitOffset>15</bitOffset>
              <bitWidth>1</bitWidth>
            </field>
          </fields>
        </register>
        <register>
          <name>TIMINGR</name>
          <addressOffset>0x10</addressOffset>
          <size>0x20</size>
          <fields>
            <field>
              <name>SCLL</name>
              <bitOffset>0</bitOffset>
              <bitWidth>8</bitWidth>
            </field>
            <field>
              <name>SCLH</name>
              <bitOffset>8</bitOffset>
              <bitWidth>8</bitWidth>
            </field>
            <field>
              <name>SDADEL</name>
              <bitOffset>16</bitOffset>
              <bitWidth>4</bitWidth>
            </field>
            <field>
              <name>SCLDEL</name>
              <bitOffset>20</bitOffset>
              <bitWidth>4</bitWidth>
            </field>
            <field>
              <name>PRESC</name>
              <bitOffset>28</bitOffset>
              <bitWidth>4</bitWidth>
            </field>
          </fields>
        </register>
        <register>
          <name>TIMEOUTR</name>
          <addressOffset>0x14</addressOffset>
          <size>0x20</size>
          <fields>
            <field>
              <name>TIMEOUTA</name>
              <bitOffset>0</bitOffset>
              <bitWidth>12</bitWidth>
            </field>
            <field>
              <name>TIDLE</name>
              <bitOffset>12</bitOffset>
              <bitWidth>1</bitWidth>
            </field>
            <field>
              <name>TIMOUTEN</name>
              <bitOffset>15</bitOffset>
              <bitWidth>1</bitWidth>
            </field>
            <field>
              <name>TIMEOUTB</name>
              <bitOffset>16</bitOffset>
              <bitWidth>12</bitWidth>
            </field>
            <field>
              <name>TEXTEN</name>
              <bitOffset>31</bitOffset>
              <bitWidth>1</bitWidth>
            </field>
          </fields>
        </register>
        <register>
          <name>ISR</name>
          <addressOffset>0x18</addressOffset>
          <size>0x20</size>
          <fields>
            <field>
              <name>TXE</name>
              <bitOffset>0</bitOffset>
              <bitWidth>1</bitWidth>
            </field>
            <field>
              <name>TXIS</name>
              <bitOffset>1</bitOffset>
              <bitWidth>1</bitWidth>
            </field>
            <field>
              <name>RXNE</name>
              <bitOffset>2</bitOffset>
              <bitWidth>1</bitWidth>
            </field>
            <field>
              <name>ADDR</name>
              <bitOffset>3</bitOffset>
              <bitWidth>1</bitWidth>
            </field>
            <field>
              <name>NACKF</name>
              <bitOffset>4</bitOffset>
              <bitWidth>1</bitWidth>
            </field>
            <field>
              <name>STOPF</name>
              <bitOffset>5</bitOffset>
              <bitWidth>1</bitWidth>
            </field>
            <field>
              <name>TC</name>
              <bitOffset>6</bitOffset>
              <bitWidth>1</bitWidth>
            </field>
            <field>
              <name>TCR</name>
              <bitOffset>7</bitOffset>
              <bitWidth>1</bitWidth>
            </field>
            <field>
              <name>BERR</name>
              <bitOffset>8</bitOffset>
              <bitWidth>1</bitWidth>
            </field>
            <field>
              <name>ARLO</name>
              <bitOffset>9</bitOffset>
              <bitWidth>1</bitWidth>
            </field>
            <field>
              <name>OVR</name>
              <bitOffset>10</bitOffset>
              <bitWidth>1</bitWidth>
            </field>
            <field>
              <name>PECERR</name>
              <bitOffset>11</bitOffset>
              <bitWidth>1</bitWidth>
            </field>
            <field>
              <name>TIMEOUT</name>
              <bitOffset>12</bitOffset>
              <bitWidth>1</bitWidth>
            </field>
            <field>
              <name>ALERT</name>
              <bitOffset>13</bitOffset>
              <bitWidth>1</bitWidth>
            </field>
            <field>
              <name>BUSY</name>
              <bitOffset>15</bitOffset>
              <bitWidth>1</bitWidth>
            </field>
            <field>
              <name>DIR</name>
              <bitOffset>16</bitOffset>
              <bitWidth>1</bitWidth>
            </field>
            <field>
              <name>ADDCODE</name>
              <bitOffset>17</bitOffset>
              <bitWidth>7</bitWidth>
            </field>
          </fields>
        </register>
        <register>
          <name>ICR</name>
          <addressOffset>0x1c</addressOffset>
          <size>0x20</size>
          <fields>
            <field>
              <name>ADDRCF</name>
              <bitOffset>3</bitOffset>
              <bitWidth>1</bitWidth>
            </field>
            <field>
              <name>NACKCF</name>
              <bitOffset>4</bitOffset>
              <bitWidth>1</bitWidth>
            </field>
            <field>
              <name>STOPCF</name>
              <bitOffset>5</bitOffset>
              <bitWidth>1</bitWidth>
            </field>
            <field>
              <name>BERRCF</name>
              <bitOffset>8</bitOffset>
              <bitWidth>1</bitWidth>
            </field>
            <field>
              <name>ARLOCF</name>
              <bitOffset>9</bitOffset>
              <bitWidth>1</bitWidth>
            </field>
            <field>
              <name>OVRCF</name>
              <bitOffset>10</bitOffset>
              <bitWidth>1</bitWidth>
            </field>
            <field>
              <name>PECCF</name>
              <bitOffset>11</bitOffset>
              <bitWidth>1</bitWidth>
            </field>
            <field>
              <name>TIMOUTCF</name>
              <bitOffset>12</bitOffset>
              <bitWidth>1</bitWidth>
            </field>
            <field>
              <name>ALERTCF</name>
              <bitOffset>13</bitOffset>
              <bitWidth>1</bitWidth>
            </field>
          </fields>
        </register>
        <register>
          <name>PECR</name>
          <addressOffset>0x20</addressOffset>
          <size>0x20</size>
          <fields>
            <field>
              <name>PEC</name>
              <bitOffset>0</bitOffset>
              <bitWidth>8</bitWidth>
            </field>
          </fields>
        </register>
        <register>
          <name>RXDR</name>
          <addressOffset>0x24</addressOffset>
          <size>0x20</size>
          <fields>
            <field>
              <name>RXDATA</name>
              <bitOffset>0</bitOffset>
              <bitWidth>8</bitWidth>
            </field>
          </fields>
        </register>
        <register>
          <name>TXDR</name>
          <addressOffset>0x28</addressOffset>
          <size>0x20</size>
          <fields>
            <field>
              <name>TXDATA</name>
              <bitOffset>0</bitOffset>
              <bitWidth>8</bitWidth>
            </field>
          </fields>
        </register>
      </registers>
    </peripheral>
    <peripheral>
      <name>CEC</name>
      <baseAddress>0x40006c00</baseAddress>
      <registers>
        <register>
          <name>CR</name>
          <addressOffset>0x0</addressOffset>
          <size>0x20</size>
          <fields>
            <field>
              <name>CECEN</name>
              <bitOffset>0</bitOffset>
              <bitWidth>1</bitWidth>
            </field>
            <field>
              <name>TXSOM</name>
              <bitOffset>1</bitOffset>
              <bitWidth>1</bitWidth>
            </field>
            <field>
              <name>TXEOM</name>
              <bitOffset>2</bitOffset>
              <bitWidth>1</bitWidth>
            </field>
          </fields>
        </register>
        <register>
          <name>CFGR</name>
          <addressOffset>0x4</addressOffset>
          <size>0x20</size>
          <fields>
            <field>
              <name>SFT</name>
              <bitOffset>0</bitOffset>
              <bitWidth>3</bitWidth>
            </field>
            <field>
              <name>RXTOL</name>
              <bitOffset>3</bitOffset>
              <bitWidth>1</bitWidth>
            </field>
            <field>
              <name>BRESTP</name>
              <bitOffset>4</bitOffset>
              <bitWidth>1</bitWidth>
            </field>
            <field>
              <name>BREGEN</name>
              <bitOffset>5</bitOffset>
              <bitWidth>1</bitWidth>
            </field>
            <field>
              <name>LBPEGEN</name>
              <bitOffset>6</bitOffset>
              <bitWidth>1</bitWidth>
            </field>
            <field>
              <name>BRDNOGEN</name>
              <bitOffset>7</bitOffset>
              <bitWidth>1</bitWidth>
            </field>
            <field>
              <name>SFTOPT</name>
              <bitOffset>8</bitOffset>
              <bitWidth>1</bitWidth>
            </field>
            <field>
              <name>OAR</name>
              <bitOffset>16</bitOffset>
              <bitWidth>15</bitWidth>
            </field>
            <field>
              <name>LSTN</name>
              <bitOffset>31</bitOffset>
              <bitWidth>1</bitWidth>
            </field>
          </fields>
        </register>
        <register>
          <name>TXDR</name>
          <addressOffset>0x8</addressOffset>
          <size>0x20</size>
          <fields>
            <field>
              <name>TXD</name>
              <bitOffset>0</bitOffset>
              <bitWidth>8</bitWidth>
            </field>
          </fields>
        </register>
        <register>
          <name>RXDR</name>
          <addressOffset>0xc</addressOffset>
          <size>0x20</size>
          <fields>
            <field>
              <name>RXD</name>
              <bitOffset>0</bitOffset>
              <bitWidth>8</bitWidth>
            </field>
          </fields>
        </register>
        <register>
          <name>ISR</name>
          <addressOffset>0x10</addressOffset>
          <size>0x20</size>
          <fields>
            <field>
              <name>RXBR</name>
              <bitOffset>0</bitOffset>
              <bitWidth>1</bitWidth>
            </field>
            <field>
              <name>RXEND</name>
              <bitOffset>1</bitOffset>
              <bitWidth>1</bitWidth>
            </field>
            <field>
              <name>RXOVR</name>
              <bitOffset>2</bitOffset>
              <bitWidth>1</bitWidth>
            </field>
            <field>
              <name>BRE</name>
              <bitOffset>3</bitOffset>
              <bitWidth>1</bitWidth>
            </field>
            <field>
              <name>SBPE</name>
              <bitOffset>4</bitOffset>
              <bitWidth>1</bitWidth>
            </field>
            <field>
              <name>LBPE</name>
              <bitOffset>5</bitOffset>
              <bitWidth>1</bitWidth>
            </field>
            <field>
              <name>RXACKE</name>
              <bitOffset>6</bitOffset>
              <bitWidth>1</bitWidth>
            </field>
            <field>
              <name>ARBLST</name>
              <bitOffset>7</bitOffset>
              <bitWidth>1</bitWidth>
            </field>
            <field>
              <name>TXBR</name>
              <bitOffset>8</bitOffset>
              <bitWidth>1</bitWidth>
            </field>
            <field>
              <name>TXEND</name>
              <bitOffset>9</bitOffset>
              <bitWidth>1</bitWidth>
            </field>
            <field>
              <name>TXUDR</name>
              <bitOffset>10</bitOffset>
              <bitWidth>1</bitWidth>
            </field>
            <field>
              <name>TXERR</name>
              <bitOffset>11</bitOffset>
              <bitWidth>1</bitWidth>
            </field>
            <field>
              <name>TXACKE</name>
              <bitOffset>12</bitOffset>
              <bitWidth>1</bitWidth>
            </field>
          </fields>
        </register>
        <register>
          <name>IER</name>
          <addressOffset>0x14</addressOffset>
          <size>0x20</size>
          <fields>
            <field>
              <name>RXBRIE</name>
              <bitOffset>0</bitOffset>
              <bitWidth>1</bitWidth>
            </field>
            <field>
              <name>RXENDIE</name>
              <bitOffset>1</bitOffset>
              <bitWidth>1</bitWidth>
            </field>
            <field>
              <name>RXOVRIE</name>
              <bitOffset>2</bitOffset>
              <bitWidth>1</bitWidth>
            </field>
            <field>
              <name>BREIE</name>
              <bitOffset>3</bitOffset>
              <bitWidth>1</bitWidth>
            </field>
            <field>
              <name>SBPEIE</name>
              <bitOffset>4</bitOffset>
              <bitWidth>1</bitWidth>
            </field>
            <field>
              <name>LBPEIE</name>
              <bitOffset>5</bitOffset>
              <bitWidth>1</bitWidth>
            </field>
            <field>
              <name>RXACKEIE</name>
              <bitOffset>6</bitOffset>
              <bitWidth>1</bitWidth>
            </field>
            <field>
              <name>ARBLSTIE</name>
              <bitOffset>7</bitOffset>
              <bitWidth>1</bitWidth>
            </field>
            <field>
              <name>TXBRIE</name>
              <bitOffset>8</bitOffset>
              <bitWidth>1</bitWidth>
            </field>
            <field>
              <name>TXENDIE</name>
              <bitOffset>9</bitOffset>
              <bitWidth>1</bitWidth>
            </field>
            <field>
              <name>TXUDRIE</name>
              <bitOffset>10</bitOffset>
              <bitWidth>1</bitWidth>
            </field>
            <field>
              <name>TXERRIE</name>
              <bitOffset>11</bitOffset>
              <bitWidth>1</bitWidth>
            </field>
            <field>
              <name>TXACKEIE</name>
              <bitOffset>12</bitOffset>
              <bitWidth>1</bitWidth>
            </field>
          </fields>
        </register>
      </registers>
    </peripheral>
    <peripheral>
      <name>DAC1</name>
      <baseAddress>0x40007400</baseAddress>
      <registers>
        <register>
          <name>CR</name>
          <addressOffset>0x0</addressOffset>
          <size>0x20</size>
          <fields>
            <field>
              <name>EN1</name>
              <bitOffset>0</bitOffset>
              <bitWidth>1</bitWidth>
            </field>
            <field>
              <name>TEN1</name>
              <bitOffset>1</bitOffset>
              <bitWidth>1</bitWidth>
            </field>
            <field>
              <name>TSEL1</name>
              <bitOffset>2</bitOffset>
              <bitWidth>4</bitWidth>
            </field>
            <field>
              <name>WAVE1</name>
              <bitOffset>6</bitOffset>
              <bitWidth>2</bitWidth>
            </field>
            <field>
              <name>MAMP1</name>
              <bitOffset>8</bitOffset>
              <bitWidth>4</bitWidth>
            </field>
            <field>
              <name>DMAEN1</name>
              <bitOffset>12</bitOffset>
              <bitWidth>1</bitWidth>
            </field>
            <field>
              <name>DMAUDRIE1</name>
              <bitOffset>13</bitOffset>
              <bitWidth>1</bitWidth>
            </field>
            <field>
              <name>CEN1</name>
              <bitOffset>14</bitOffset>
              <bitWidth>1</bitWidth>
            </field>
            <field>
              <name>EN2</name>
              <bitOffset>16</bitOffset>
              <bitWidth>1</bitWidth>
            </field>
            <field>
              <name>TEN2</name>
              <bitOffset>17</bitOffset>
              <bitWidth>1</bitWidth>
            </field>
            <field>
              <name>TSEL2</name>
              <bitOffset>18</bitOffset>
              <bitWidth>4</bitWidth>
            </field>
            <field>
              <name>WAVE2</name>
              <bitOffset>22</bitOffset>
              <bitWidth>2</bitWidth>
            </field>
            <field>
              <name>MAMP2</name>
              <bitOffset>24</bitOffset>
              <bitWidth>4</bitWidth>
            </field>
            <field>
              <name>DMAEN2</name>
              <bitOffset>28</bitOffset>
              <bitWidth>1</bitWidth>
            </field>
            <field>
              <name>DMAUDRIE2</name>
              <bitOffset>29</bitOffset>
              <bitWidth>1</bitWidth>
            </field>
            <field>
              <name>CEN2</name>
              <bitOffset>30</bitOffset>
              <bitWidth>1</bitWidth>
            </field>
          </fields>
        </register>
        <register>
          <name>SWTRIGR</name>
          <addressOffset>0x4</addressOffset>
          <size>0x20</size>
          <fields>
            <field>
              <name>SWTRIG1</name>
              <bitOffset>0</bitOffset>
              <bitWidth>1</bitWidth>
            </field>
            <field>
              <name>SWTRIG2</name>
              <bitOffset>1</bitOffset>
              <bitWidth>1</bitWidth>
            </field>
          </fields>
        </register>
        <register>
          <name>DHR12R1</name>
          <addressOffset>0x8</addressOffset>
          <size>0x20</size>
          <fields>
            <field>
              <name>DACC1DHR</name>
              <bitOffset>0</bitOffset>
              <bitWidth>12</bitWidth>
            </field>
          </fields>
        </register>
        <register>
          <name>DHR12L1</name>
          <addressOffset>0xc</addressOffset>
          <size>0x20</size>
          <fields>
            <field>
              <name>DACC1DHR</name>
              <bitOffset>4</bitOffset>
              <bitWidth>12</bitWidth>
            </field>
          </fields>
        </register>
        <register>
          <name>DHR8R1</name>
          <addressOffset>0x10</addressOffset>
          <size>0x20</size>
          <fields>
            <field>
              <name>DACC1DHR</name>
              <bitOffset>0</bitOffset>
              <bitWidth>8</bitWidth>
            </field>
          </fields>
        </register>
        <register>
          <name>DHR12R2</name>
          <addressOffset>0x14</addressOffset>
          <size>0x20</size>
          <fields>
            <field>
              <name>DACC2DHR</name>
              <bitOffset>0</bitOffset>
              <bitWidth>12</bitWidth>
            </field>
          </fields>
        </register>
        <register>
          <name>DHR12L2</name>
          <addressOffset>0x18</addressOffset>
          <size>0x20</size>
          <fields>
            <field>
              <name>DACC2DHR</name>
              <bitOffset>4</bitOffset>
              <bitWidth>12</bitWidth>
            </field>
          </fields>
        </register>
        <register>
          <name>DHR8R2</name>
          <addressOffset>0x1c</addressOffset>
          <size>0x20</size>
          <fields>
            <field>
              <name>DACC2DHR</name>
              <bitOffset>0</bitOffset>
              <bitWidth>8</bitWidth>
            </field>
          </fields>
        </register>
        <register>
          <name>DHR12RD</name>
          <addressOffset>0x20</addressOffset>
          <size>0x20</size>
          <fields>
            <field>
              <name>DACC1DHR</name>
              <bitOffset>0</bitOffset>
              <bitWidth>12</bitWidth>
            </field>
            <field>
              <name>DACC2DHR</name>
              <bitOffset>16</bitOffset>
              <bitWidth>12</bitWidth>
            </field>
          </fields>
        </register>
        <register>
          <name>DHR12LD</name>
          <addressOffset>0x24</addressOffset>
          <size>0x20</size>
          <fields>
            <field>
              <name>DACC1DHR</name>
              <bitOffset>4</bitOffset>
              <bitWidth>12</bitWidth>
            </field>
            <field>
              <name>DACC2DHR</name>
              <bitOffset>20</bitOffset>
              <bitWidth>12</bitWidth>
            </field>
          </fields>
        </register>
        <register>
          <name>DHR8RD</name>
          <addressOffset>0x28</addressOffset>
          <size>0x20</size>
          <fields>
            <field>
              <name>DACC1DHR</name>
              <bitOffset>0</bitOffset>
              <bitWidth>8</bitWidth>
            </field>
            <field>
              <name>DACC2DHR</name>
              <bitOffset>8</bitOffset>
              <bitWidth>8</bitWidth>
            </field>
          </fields>
        </register>
        <register>
          <name>DOR1</name>
          <addressOffset>0x2c</addressOffset>
          <size>0x20</size>
          <fields>
            <field>
              <name>DACC1DOR</name>
              <bitOffset>0</bitOffset>
              <bitWidth>12</bitWidth>
            </field>
          </fields>
        </register>
        <register>
          <name>DOR2</name>
          <addressOffset>0x30</addressOffset>
          <size>0x20</size>
          <fields>
            <field>
              <name>DACC2DOR</name>
              <bitOffset>0</bitOffset>
              <bitWidth>12</bitWidth>
            </field>
          </fields>
        </register>
        <register>
          <name>SR</name>
          <addressOffset>0x34</addressOffset>
          <size>0x20</size>
          <fields>
            <field>
              <name>DMAUDR1</name>
              <bitOffset>13</bitOffset>
              <bitWidth>1</bitWidth>
            </field>
            <field>
              <name>CAL_FLAG1</name>
              <bitOffset>14</bitOffset>
              <bitWidth>1</bitWidth>
            </field>
            <field>
              <name>BWST1</name>
              <bitOffset>15</bitOffset>
              <bitWidth>15</bitWidth>
            </field>
            <field>
              <name>DMAUDR2</name>
              <bitOffset>29</bitOffset>
              <bitWidth>1</bitWidth>
            </field>
            <field>
              <name>CAL_FLAG2</name>
              <bitOffset>30</bitOffset>
              <bitWidth>1</bitWidth>
            </field>
            <field>
              <name>BWST2</name>
              <bitOffset>31</bitOffset>
              <bitWidth>1</bitWidth>
            </field>
          </fields>
        </register>
        <register>
          <name>CCR</name>
          <addressOffset>0x38</addressOffset>
          <size>0x20</size>
          <fields>
            <field>
              <name>OTRIM1</name>
              <bitOffset>0</bitOffset>
              <bitWidth>5</bitWidth>
            </field>
            <field>
              <name>OTRIM2</name>
              <bitOffset>16</bitOffset>
              <bitWidth>5</bitWidth>
            </field>
          </fields>
        </register>
        <register>
          <name>MCR</name>
          <addressOffset>0x3c</addressOffset>
          <size>0x20</size>
          <fields>
            <field>
              <name>MODE1</name>
              <bitOffset>0</bitOffset>
              <bitWidth>3</bitWidth>
            </field>
            <field>
              <name>MODE2</name>
              <bitOffset>16</bitOffset>
              <bitWidth>3</bitWidth>
            </field>
          </fields>
        </register>
        <register>
          <name>SHSR1</name>
          <addressOffset>0x40</addressOffset>
          <size>0x20</size>
          <fields>
            <field>
              <name>TSAMPLE1</name>
              <bitOffset>0</bitOffset>
              <bitWidth>10</bitWidth>
            </field>
          </fields>
        </register>
        <register>
          <name>SHSR2</name>
          <addressOffset>0x44</addressOffset>
          <size>0x20</size>
          <fields>
            <field>
              <name>TSAMPLE2</name>
              <bitOffset>0</bitOffset>
              <bitWidth>10</bitWidth>
            </field>
          </fields>
        </register>
        <register>
          <name>SHHR</name>
          <addressOffset>0x48</addressOffset>
          <size>0x20</size>
          <fields>
            <field>
              <name>THOLD1</name>
              <bitOffset>0</bitOffset>
              <bitWidth>10</bitWidth>
            </field>
            <field>
              <name>THOLD2</name>
              <bitOffset>16</bitOffset>
              <bitWidth>10</bitWidth>
            </field>
          </fields>
        </register>
        <register>
          <name>SHRR</name>
          <addressOffset>0x4c</addressOffset>
          <size>0x20</size>
          <fields>
            <field>
              <name>TREFRESH1</name>
              <bitOffset>0</bitOffset>
              <bitWidth>8</bitWidth>
            </field>
            <field>
              <name>TREFRESH2</name>
              <bitOffset>16</bitOffset>
              <bitWidth>8</bitWidth>
            </field>
          </fields>
        </register>
      </registers>
    </peripheral>
    <peripheral>
      <name>UART7</name>
      <baseAddress>0x40007800</baseAddress>
      <registers>
        <register>
          <name>CR1</name>
          <addressOffset>0x0</addressOffset>
          <size>0x20</size>
          <fields>
            <field>
              <name>UE</name>
              <bitOffset>0</bitOffset>
              <bitWidth>1</bitWidth>
            </field>
            <field>
              <name>UESM</name>
              <bitOffset>1</bitOffset>
              <bitWidth>1</bitWidth>
            </field>
            <field>
              <name>RE</name>
              <bitOffset>2</bitOffset>
              <bitWidth>1</bitWidth>
            </field>
            <field>
              <name>TE</name>
              <bitOffset>3</bitOffset>
              <bitWidth>1</bitWidth>
            </field>
            <field>
              <name>IDLEIE</name>
              <bitOffset>4</bitOffset>
              <bitWidth>1</bitWidth>
            </field>
            <field>
              <name>RXNEIE_RXFNEIE</name>
              <bitOffset>5</bitOffset>
              <bitWidth>1</bitWidth>
            </field>
            <field>
              <name>TCIE</name>
              <bitOffset>6</bitOffset>
              <bitWidth>1</bitWidth>
            </field>
            <field>
              <name>TXEIE_TXFNFIE</name>
              <bitOffset>7</bitOffset>
              <bitWidth>1</bitWidth>
            </field>
            <field>
              <name>PEIE</name>
              <bitOffset>8</bitOffset>
              <bitWidth>1</bitWidth>
            </field>
            <field>
              <name>PS</name>
              <bitOffset>9</bitOffset>
              <bitWidth>1</bitWidth>
            </field>
            <field>
              <name>PCE</name>
              <bitOffset>10</bitOffset>
              <bitWidth>1</bitWidth>
            </field>
            <field>
              <name>WAKE</name>
              <bitOffset>11</bitOffset>
              <bitWidth>1</bitWidth>
            </field>
            <field>
              <name>M0</name>
              <bitOffset>12</bitOffset>
              <bitWidth>1</bitWidth>
            </field>
            <field>
              <name>MME</name>
              <bitOffset>13</bitOffset>
              <bitWidth>1</bitWidth>
            </field>
            <field>
              <name>CMIE</name>
              <bitOffset>14</bitOffset>
              <bitWidth>1</bitWidth>
            </field>
            <field>
              <name>OVER8</name>
              <bitOffset>15</bitOffset>
              <bitWidth>1</bitWidth>
            </field>
            <field>
              <name>DEDT</name>
              <bitOffset>16</bitOffset>
              <bitWidth>5</bitWidth>
            </field>
            <field>
              <name>DEAT</name>
              <bitOffset>21</bitOffset>
              <bitWidth>5</bitWidth>
            </field>
            <field>
              <name>RTOIE</name>
              <bitOffset>26</bitOffset>
              <bitWidth>1</bitWidth>
            </field>
            <field>
              <name>EOBIE</name>
              <bitOffset>27</bitOffset>
              <bitWidth>1</bitWidth>
            </field>
            <field>
              <name>M1</name>
              <bitOffset>28</bitOffset>
              <bitWidth>1</bitWidth>
            </field>
            <field>
              <name>FIFOEN</name>
              <bitOffset>29</bitOffset>
              <bitWidth>1</bitWidth>
            </field>
            <field>
              <name>TXFEIE</name>
              <bitOffset>30</bitOffset>
              <bitWidth>1</bitWidth>
            </field>
            <field>
              <name>RXFFIE</name>
              <bitOffset>31</bitOffset>
              <bitWidth>1</bitWidth>
            </field>
          </fields>
        </register>
        <register>
          <name>CR2</name>
          <addressOffset>0x4</addressOffset>
          <size>0x20</size>
          <fields>
            <field>
              <name>SLVEN</name>
              <bitOffset>0</bitOffset>
              <bitWidth>1</bitWidth>
            </field>
            <field>
              <name>DIS_NSS</name>
              <bitOffset>3</bitOffset>
              <bitWidth>1</bitWidth>
            </field>
            <field>
              <name>ADDM7</name>
              <bitOffset>4</bitOffset>
              <bitWidth>1</bitWidth>
            </field>
            <field>
              <name>LBDL</name>
              <bitOffset>5</bitOffset>
              <bitWidth>1</bitWidth>
            </field>
            <field>
              <name>LBDIE</name>
              <bitOffset>6</bitOffset>
              <bitWidth>1</bitWidth>
            </field>
            <field>
              <name>LBCL</name>
              <bitOffset>8</bitOffset>
              <bitWidth>1</bitWidth>
            </field>
            <field>
              <name>CPHA</name>
              <bitOffset>9</bitOffset>
              <bitWidth>1</bitWidth>
            </field>
            <field>
              <name>CPOL</name>
              <bitOffset>10</bitOffset>
              <bitWidth>1</bitWidth>
            </field>
            <field>
              <name>CLKEN</name>
              <bitOffset>11</bitOffset>
              <bitWidth>1</bitWidth>
            </field>
            <field>
              <name>STOP</name>
              <bitOffset>12</bitOffset>
              <bitWidth>2</bitWidth>
            </field>
            <field>
              <name>LINEN</name>
              <bitOffset>14</bitOffset>
              <bitWidth>1</bitWidth>
            </field>
            <field>
              <name>SWAP</name>
              <bitOffset>15</bitOffset>
              <bitWidth>1</bitWidth>
            </field>
            <field>
              <name>RXINV</name>
              <bitOffset>16</bitOffset>
              <bitWidth>1</bitWidth>
            </field>
            <field>
              <name>TXINV</name>
              <bitOffset>17</bitOffset>
              <bitWidth>1</bitWidth>
            </field>
            <field>
              <name>DATAINV</name>
              <bitOffset>18</bitOffset>
              <bitWidth>1</bitWidth>
            </field>
            <field>
              <name>MSBFIRST</name>
              <bitOffset>19</bitOffset>
              <bitWidth>1</bitWidth>
            </field>
            <field>
              <name>ABREN</name>
              <bitOffset>20</bitOffset>
              <bitWidth>1</bitWidth>
            </field>
            <field>
              <name>ABRMODE</name>
              <bitOffset>21</bitOffset>
              <bitWidth>2</bitWidth>
            </field>
            <field>
              <name>RTOEN</name>
              <bitOffset>23</bitOffset>
              <bitWidth>1</bitWidth>
            </field>
            <field>
              <name>ADD</name>
              <bitOffset>24</bitOffset>
              <bitWidth>8</bitWidth>
            </field>
          </fields>
        </register>
        <register>
          <name>CR3</name>
          <addressOffset>0x8</addressOffset>
          <size>0x20</size>
          <fields>
            <field>
              <name>EIE</name>
              <bitOffset>0</bitOffset>
              <bitWidth>1</bitWidth>
            </field>
            <field>
              <name>IREN</name>
              <bitOffset>1</bitOffset>
              <bitWidth>1</bitWidth>
            </field>
            <field>
              <name>IRLP</name>
              <bitOffset>2</bitOffset>
              <bitWidth>1</bitWidth>
            </field>
            <field>
              <name>HDSEL</name>
              <bitOffset>3</bitOffset>
              <bitWidth>1</bitWidth>
            </field>
            <field>
              <name>NACK</name>
              <bitOffset>4</bitOffset>
              <bitWidth>1</bitWidth>
            </field>
            <field>
              <name>SCEN</name>
              <bitOffset>5</bitOffset>
              <bitWidth>1</bitWidth>
            </field>
            <field>
              <name>DMAR</name>
              <bitOffset>6</bitOffset>
              <bitWidth>1</bitWidth>
            </field>
            <field>
              <name>DMAT</name>
              <bitOffset>7</bitOffset>
              <bitWidth>1</bitWidth>
            </field>
            <field>
              <name>RTSE</name>
              <bitOffset>8</bitOffset>
              <bitWidth>1</bitWidth>
            </field>
            <field>
              <name>CTSE</name>
              <bitOffset>9</bitOffset>
              <bitWidth>1</bitWidth>
            </field>
            <field>
              <name>CTSIE</name>
              <bitOffset>10</bitOffset>
              <bitWidth>1</bitWidth>
            </field>
            <field>
              <name>ONEBIT</name>
              <bitOffset>11</bitOffset>
              <bitWidth>1</bitWidth>
            </field>
            <field>
              <name>OVRDIS</name>
              <bitOffset>12</bitOffset>
              <bitWidth>1</bitWidth>
            </field>
            <field>
              <name>DDRE</name>
              <bitOffset>13</bitOffset>
              <bitWidth>1</bitWidth>
            </field>
            <field>
              <name>DEM</name>
              <bitOffset>14</bitOffset>
              <bitWidth>1</bitWidth>
            </field>
            <field>
              <name>DEP</name>
              <bitOffset>15</bitOffset>
              <bitWidth>1</bitWidth>
            </field>
            <field>
              <name>SCARCNT</name>
              <bitOffset>17</bitOffset>
              <bitWidth>3</bitWidth>
            </field>
            <field>
              <name>WUS</name>
              <bitOffset>20</bitOffset>
              <bitWidth>2</bitWidth>
            </field>
            <field>
              <name>WUFIE</name>
              <bitOffset>22</bitOffset>
              <bitWidth>1</bitWidth>
            </field>
            <field>
              <name>TXFTIE</name>
              <bitOffset>23</bitOffset>
              <bitWidth>1</bitWidth>
            </field>
            <field>
              <name>TCBGTIE</name>
              <bitOffset>24</bitOffset>
              <bitWidth>1</bitWidth>
            </field>
            <field>
              <name>RXFTCFG</name>
              <bitOffset>25</bitOffset>
              <bitWidth>3</bitWidth>
            </field>
            <field>
              <name>RXFTIE</name>
              <bitOffset>28</bitOffset>
              <bitWidth>1</bitWidth>
            </field>
            <field>
              <name>TXFTCFG</name>
              <bitOffset>29</bitOffset>
              <bitWidth>3</bitWidth>
            </field>
          </fields>
        </register>
        <register>
          <name>BRR</name>
          <addressOffset>0xc</addressOffset>
          <size>0x20</size>
          <fields>
            <field>
              <name>DIV_FRACTION</name>
              <bitOffset>0</bitOffset>
              <bitWidth>4</bitWidth>
            </field>
            <field>
              <name>DIV_MANTISSA</name>
              <bitOffset>4</bitOffset>
              <bitWidth>12</bitWidth>
            </field>
          </fields>
        </register>
        <register>
          <name>GTPR</name>
          <addressOffset>0x10</addressOffset>
          <size>0x20</size>
          <fields>
            <field>
              <name>PSC</name>
              <bitOffset>0</bitOffset>
              <bitWidth>8</bitWidth>
            </field>
            <field>
              <name>GT</name>
              <bitOffset>8</bitOffset>
              <bitWidth>8</bitWidth>
            </field>
          </fields>
        </register>
        <register>
          <name>RTOR</name>
          <addressOffset>0x14</addressOffset>
          <size>0x20</size>
          <fields>
            <field>
              <name>RTO</name>
              <bitOffset>0</bitOffset>
              <bitWidth>24</bitWidth>
            </field>
            <field>
              <name>BLEN</name>
              <bitOffset>24</bitOffset>
              <bitWidth>8</bitWidth>
            </field>
          </fields>
        </register>
        <register>
          <name>RQR</name>
          <addressOffset>0x18</addressOffset>
          <size>0x20</size>
          <fields>
            <field>
              <name>ABRRQ</name>
              <bitOffset>0</bitOffset>
              <bitWidth>1</bitWidth>
            </field>
            <field>
              <name>SBKRQ</name>
              <bitOffset>1</bitOffset>
              <bitWidth>1</bitWidth>
            </field>
            <field>
              <name>MMRQ</name>
              <bitOffset>2</bitOffset>
              <bitWidth>1</bitWidth>
            </field>
            <field>
              <name>RXFRQ</name>
              <bitOffset>3</bitOffset>
              <bitWidth>1</bitWidth>
            </field>
            <field>
              <name>TXFRQ</name>
              <bitOffset>4</bitOffset>
              <bitWidth>1</bitWidth>
            </field>
          </fields>
        </register>
        <register>
          <name>ISR</name>
          <addressOffset>0x1c</addressOffset>
          <size>0x20</size>
          <fields>
            <field>
              <name>PE</name>
              <bitOffset>0</bitOffset>
              <bitWidth>1</bitWidth>
            </field>
            <field>
              <name>FE</name>
              <bitOffset>1</bitOffset>
              <bitWidth>1</bitWidth>
            </field>
            <field>
              <name>NE</name>
              <bitOffset>2</bitOffset>
              <bitWidth>1</bitWidth>
            </field>
            <field>
              <name>ORE</name>
              <bitOffset>3</bitOffset>
              <bitWidth>1</bitWidth>
            </field>
            <field>
              <name>IDLE</name>
              <bitOffset>4</bitOffset>
              <bitWidth>1</bitWidth>
            </field>
            <field>
              <name>RXNE_RXFNE</name>
              <bitOffset>5</bitOffset>
              <bitWidth>1</bitWidth>
            </field>
            <field>
              <name>TC</name>
              <bitOffset>6</bitOffset>
              <bitWidth>1</bitWidth>
            </field>
            <field>
              <name>TXE_TXFNF</name>
              <bitOffset>7</bitOffset>
              <bitWidth>1</bitWidth>
            </field>
            <field>
              <name>LBDF</name>
              <bitOffset>8</bitOffset>
              <bitWidth>1</bitWidth>
            </field>
            <field>
              <name>CTSIF</name>
              <bitOffset>9</bitOffset>
              <bitWidth>1</bitWidth>
            </field>
            <field>
              <name>CTS</name>
              <bitOffset>10</bitOffset>
              <bitWidth>1</bitWidth>
            </field>
            <field>
              <name>RTOF</name>
              <bitOffset>11</bitOffset>
              <bitWidth>1</bitWidth>
            </field>
            <field>
              <name>EOBF</name>
              <bitOffset>12</bitOffset>
              <bitWidth>1</bitWidth>
            </field>
            <field>
              <name>UDR</name>
              <bitOffset>13</bitOffset>
              <bitWidth>1</bitWidth>
            </field>
            <field>
              <name>ABRE</name>
              <bitOffset>14</bitOffset>
              <bitWidth>1</bitWidth>
            </field>
            <field>
              <name>ABRF</name>
              <bitOffset>15</bitOffset>
              <bitWidth>1</bitWidth>
            </field>
            <field>
              <name>BUSY</name>
              <bitOffset>16</bitOffset>
              <bitWidth>1</bitWidth>
            </field>
            <field>
              <name>CMF</name>
              <bitOffset>17</bitOffset>
              <bitWidth>1</bitWidth>
            </field>
            <field>
              <name>SBKF</name>
              <bitOffset>18</bitOffset>
              <bitWidth>1</bitWidth>
            </field>
            <field>
              <name>RWU</name>
              <bitOffset>19</bitOffset>
              <bitWidth>1</bitWidth>
            </field>
            <field>
              <name>WUF</name>
              <bitOffset>20</bitOffset>
              <bitWidth>1</bitWidth>
            </field>
            <field>
              <name>TEACK</name>
              <bitOffset>21</bitOffset>
              <bitWidth>1</bitWidth>
            </field>
            <field>
              <name>REACK</name>
              <bitOffset>22</bitOffset>
              <bitWidth>1</bitWidth>
            </field>
            <field>
              <name>TXFE</name>
              <bitOffset>23</bitOffset>
              <bitWidth>1</bitWidth>
            </field>
            <field>
              <name>RXFF</name>
              <bitOffset>24</bitOffset>
              <bitWidth>1</bitWidth>
            </field>
            <field>
              <name>TCBGT</name>
              <bitOffset>25</bitOffset>
              <bitWidth>1</bitWidth>
            </field>
            <field>
              <name>RXFT</name>
              <bitOffset>26</bitOffset>
              <bitWidth>1</bitWidth>
            </field>
            <field>
              <name>TXFT</name>
              <bitOffset>27</bitOffset>
              <bitWidth>1</bitWidth>
            </field>
          </fields>
        </register>
        <register>
          <name>ICR</name>
          <addressOffset>0x20</addressOffset>
          <size>0x20</size>
          <fields>
            <field>
              <name>PECF</name>
              <bitOffset>0</bitOffset>
              <bitWidth>1</bitWidth>
            </field>
            <field>
              <name>FECF</name>
              <bitOffset>1</bitOffset>
              <bitWidth>1</bitWidth>
            </field>
            <field>
              <name>NECF</name>
              <bitOffset>2</bitOffset>
              <bitWidth>1</bitWidth>
            </field>
            <field>
              <name>ORECF</name>
              <bitOffset>3</bitOffset>
              <bitWidth>1</bitWidth>
            </field>
            <field>
              <name>IDLECF</name>
              <bitOffset>4</bitOffset>
              <bitWidth>1</bitWidth>
            </field>
            <field>
              <name>TXFECF</name>
              <bitOffset>5</bitOffset>
              <bitWidth>1</bitWidth>
            </field>
            <field>
              <name>TCCF</name>
              <bitOffset>6</bitOffset>
              <bitWidth>1</bitWidth>
            </field>
            <field>
              <name>TCBGTCF</name>
              <bitOffset>7</bitOffset>
              <bitWidth>1</bitWidth>
            </field>
            <field>
              <name>LBDCF</name>
              <bitOffset>8</bitOffset>
              <bitWidth>1</bitWidth>
            </field>
            <field>
              <name>CTSCF</name>
              <bitOffset>9</bitOffset>
              <bitWidth>1</bitWidth>
            </field>
            <field>
              <name>RTOCF</name>
              <bitOffset>11</bitOffset>
              <bitWidth>1</bitWidth>
            </field>
            <field>
              <name>EOBCF</name>
              <bitOffset>12</bitOffset>
              <bitWidth>1</bitWidth>
            </field>
            <field>
              <name>UDRCF</name>
              <bitOffset>13</bitOffset>
              <bitWidth>1</bitWidth>
            </field>
            <field>
              <name>CMCF</name>
              <bitOffset>17</bitOffset>
              <bitWidth>1</bitWidth>
            </field>
            <field>
              <name>WUCF</name>
              <bitOffset>20</bitOffset>
              <bitWidth>1</bitWidth>
            </field>
          </fields>
        </register>
        <register>
          <name>RDR</name>
          <addressOffset>0x24</addressOffset>
          <size>0x20</size>
          <fields>
            <field>
              <name>RDR</name>
              <bitOffset>0</bitOffset>
              <bitWidth>9</bitWidth>
            </field>
          </fields>
        </register>
        <register>
          <name>TDR</name>
          <addressOffset>0x28</addressOffset>
          <size>0x20</size>
          <fields>
            <field>
              <name>TDR</name>
              <bitOffset>0</bitOffset>
              <bitWidth>9</bitWidth>
            </field>
          </fields>
        </register>
        <register>
          <name>PRESC</name>
          <addressOffset>0x2c</addressOffset>
          <size>0x20</size>
          <fields>
            <field>
              <name>PRESCALER</name>
              <bitOffset>0</bitOffset>
              <bitWidth>4</bitWidth>
            </field>
          </fields>
        </register>
      </registers>
    </peripheral>
    <peripheral>
      <name>UART8</name>
      <baseAddress>0x40007c00</baseAddress>
      <registers>
        <register>
          <name>CR1</name>
          <addressOffset>0x0</addressOffset>
          <size>0x20</size>
          <fields>
            <field>
              <name>UE</name>
              <bitOffset>0</bitOffset>
              <bitWidth>1</bitWidth>
            </field>
            <field>
              <name>UESM</name>
              <bitOffset>1</bitOffset>
              <bitWidth>1</bitWidth>
            </field>
            <field>
              <name>RE</name>
              <bitOffset>2</bitOffset>
              <bitWidth>1</bitWidth>
            </field>
            <field>
              <name>TE</name>
              <bitOffset>3</bitOffset>
              <bitWidth>1</bitWidth>
            </field>
            <field>
              <name>IDLEIE</name>
              <bitOffset>4</bitOffset>
              <bitWidth>1</bitWidth>
            </field>
            <field>
              <name>RXNEIE_RXFNEIE</name>
              <bitOffset>5</bitOffset>
              <bitWidth>1</bitWidth>
            </field>
            <field>
              <name>TCIE</name>
              <bitOffset>6</bitOffset>
              <bitWidth>1</bitWidth>
            </field>
            <field>
              <name>TXEIE_TXFNFIE</name>
              <bitOffset>7</bitOffset>
              <bitWidth>1</bitWidth>
            </field>
            <field>
              <name>PEIE</name>
              <bitOffset>8</bitOffset>
              <bitWidth>1</bitWidth>
            </field>
            <field>
              <name>PS</name>
              <bitOffset>9</bitOffset>
              <bitWidth>1</bitWidth>
            </field>
            <field>
              <name>PCE</name>
              <bitOffset>10</bitOffset>
              <bitWidth>1</bitWidth>
            </field>
            <field>
              <name>WAKE</name>
              <bitOffset>11</bitOffset>
              <bitWidth>1</bitWidth>
            </field>
            <field>
              <name>M0</name>
              <bitOffset>12</bitOffset>
              <bitWidth>1</bitWidth>
            </field>
            <field>
              <name>MME</name>
              <bitOffset>13</bitOffset>
              <bitWidth>1</bitWidth>
            </field>
            <field>
              <name>CMIE</name>
              <bitOffset>14</bitOffset>
              <bitWidth>1</bitWidth>
            </field>
            <field>
              <name>OVER8</name>
              <bitOffset>15</bitOffset>
              <bitWidth>1</bitWidth>
            </field>
            <field>
              <name>DEDT</name>
              <bitOffset>16</bitOffset>
              <bitWidth>5</bitWidth>
            </field>
            <field>
              <name>DEAT</name>
              <bitOffset>21</bitOffset>
              <bitWidth>5</bitWidth>
            </field>
            <field>
              <name>RTOIE</name>
              <bitOffset>26</bitOffset>
              <bitWidth>1</bitWidth>
            </field>
            <field>
              <name>EOBIE</name>
              <bitOffset>27</bitOffset>
              <bitWidth>1</bitWidth>
            </field>
            <field>
              <name>M1</name>
              <bitOffset>28</bitOffset>
              <bitWidth>1</bitWidth>
            </field>
            <field>
              <name>FIFOEN</name>
              <bitOffset>29</bitOffset>
              <bitWidth>1</bitWidth>
            </field>
            <field>
              <name>TXFEIE</name>
              <bitOffset>30</bitOffset>
              <bitWidth>1</bitWidth>
            </field>
            <field>
              <name>RXFFIE</name>
              <bitOffset>31</bitOffset>
              <bitWidth>1</bitWidth>
            </field>
          </fields>
        </register>
        <register>
          <name>CR2</name>
          <addressOffset>0x4</addressOffset>
          <size>0x20</size>
          <fields>
            <field>
              <name>SLVEN</name>
              <bitOffset>0</bitOffset>
              <bitWidth>1</bitWidth>
            </field>
            <field>
              <name>DIS_NSS</name>
              <bitOffset>3</bitOffset>
              <bitWidth>1</bitWidth>
            </field>
            <field>
              <name>ADDM7</name>
              <bitOffset>4</bitOffset>
              <bitWidth>1</bitWidth>
            </field>
            <field>
              <name>LBDL</name>
              <bitOffset>5</bitOffset>
              <bitWidth>1</bitWidth>
            </field>
            <field>
              <name>LBDIE</name>
              <bitOffset>6</bitOffset>
              <bitWidth>1</bitWidth>
            </field>
            <field>
              <name>LBCL</name>
              <bitOffset>8</bitOffset>
              <bitWidth>1</bitWidth>
            </field>
            <field>
              <name>CPHA</name>
              <bitOffset>9</bitOffset>
              <bitWidth>1</bitWidth>
            </field>
            <field>
              <name>CPOL</name>
              <bitOffset>10</bitOffset>
              <bitWidth>1</bitWidth>
            </field>
            <field>
              <name>CLKEN</name>
              <bitOffset>11</bitOffset>
              <bitWidth>1</bitWidth>
            </field>
            <field>
              <name>STOP</name>
              <bitOffset>12</bitOffset>
              <bitWidth>2</bitWidth>
            </field>
            <field>
              <name>LINEN</name>
              <bitOffset>14</bitOffset>
              <bitWidth>1</bitWidth>
            </field>
            <field>
              <name>SWAP</name>
              <bitOffset>15</bitOffset>
              <bitWidth>1</bitWidth>
            </field>
            <field>
              <name>RXINV</name>
              <bitOffset>16</bitOffset>
              <bitWidth>1</bitWidth>
            </field>
            <field>
              <name>TXINV</name>
              <bitOffset>17</bitOffset>
              <bitWidth>1</bitWidth>
            </field>
            <field>
              <name>DATAINV</name>
              <bitOffset>18</bitOffset>
              <bitWidth>1</bitWidth>
            </field>
            <field>
              <name>MSBFIRST</name>
              <bitOffset>19</bitOffset>
              <bitWidth>1</bitWidth>
            </field>
            <field>
              <name>ABREN</name>
              <bitOffset>20</bitOffset>
              <bitWidth>1</bitWidth>
            </field>
            <field>
              <name>ABRMODE</name>
              <bitOffset>21</bitOffset>
              <bitWidth>2</bitWidth>
            </field>
            <field>
              <name>RTOEN</name>
              <bitOffset>23</bitOffset>
              <bitWidth>1</bitWidth>
            </field>
            <field>
              <name>ADD</name>
              <bitOffset>24</bitOffset>
              <bitWidth>8</bitWidth>
            </field>
          </fields>
        </register>
        <register>
          <name>CR3</name>
          <addressOffset>0x8</addressOffset>
          <size>0x20</size>
          <fields>
            <field>
              <name>EIE</name>
              <bitOffset>0</bitOffset>
              <bitWidth>1</bitWidth>
            </field>
            <field>
              <name>IREN</name>
              <bitOffset>1</bitOffset>
              <bitWidth>1</bitWidth>
            </field>
            <field>
              <name>IRLP</name>
              <bitOffset>2</bitOffset>
              <bitWidth>1</bitWidth>
            </field>
            <field>
              <name>HDSEL</name>
              <bitOffset>3</bitOffset>
              <bitWidth>1</bitWidth>
            </field>
            <field>
              <name>NACK</name>
              <bitOffset>4</bitOffset>
              <bitWidth>1</bitWidth>
            </field>
            <field>
              <name>SCEN</name>
              <bitOffset>5</bitOffset>
              <bitWidth>1</bitWidth>
            </field>
            <field>
              <name>DMAR</name>
              <bitOffset>6</bitOffset>
              <bitWidth>1</bitWidth>
            </field>
            <field>
              <name>DMAT</name>
              <bitOffset>7</bitOffset>
              <bitWidth>1</bitWidth>
            </field>
            <field>
              <name>RTSE</name>
              <bitOffset>8</bitOffset>
              <bitWidth>1</bitWidth>
            </field>
            <field>
              <name>CTSE</name>
              <bitOffset>9</bitOffset>
              <bitWidth>1</bitWidth>
            </field>
            <field>
              <name>CTSIE</name>
              <bitOffset>10</bitOffset>
              <bitWidth>1</bitWidth>
            </field>
            <field>
              <name>ONEBIT</name>
              <bitOffset>11</bitOffset>
              <bitWidth>1</bitWidth>
            </field>
            <field>
              <name>OVRDIS</name>
              <bitOffset>12</bitOffset>
              <bitWidth>1</bitWidth>
            </field>
            <field>
              <name>DDRE</name>
              <bitOffset>13</bitOffset>
              <bitWidth>1</bitWidth>
            </field>
            <field>
              <name>DEM</name>
              <bitOffset>14</bitOffset>
              <bitWidth>1</bitWidth>
            </field>
            <field>
              <name>DEP</name>
              <bitOffset>15</bitOffset>
              <bitWidth>1</bitWidth>
            </field>
            <field>
              <name>SCARCNT</name>
              <bitOffset>17</bitOffset>
              <bitWidth>3</bitWidth>
            </field>
            <field>
              <name>WUS</name>
              <bitOffset>20</bitOffset>
              <bitWidth>2</bitWidth>
            </field>
            <field>
              <name>WUFIE</name>
              <bitOffset>22</bitOffset>
              <bitWidth>1</bitWidth>
            </field>
            <field>
              <name>TXFTIE</name>
              <bitOffset>23</bitOffset>
              <bitWidth>1</bitWidth>
            </field>
            <field>
              <name>TCBGTIE</name>
              <bitOffset>24</bitOffset>
              <bitWidth>1</bitWidth>
            </field>
            <field>
              <name>RXFTCFG</name>
              <bitOffset>25</bitOffset>
              <bitWidth>3</bitWidth>
            </field>
            <field>
              <name>RXFTIE</name>
              <bitOffset>28</bitOffset>
              <bitWidth>1</bitWidth>
            </field>
            <field>
              <name>TXFTCFG</name>
              <bitOffset>29</bitOffset>
              <bitWidth>3</bitWidth>
            </field>
          </fields>
        </register>
        <register>
          <name>BRR</name>
          <addressOffset>0xc</addressOffset>
          <size>0x20</size>
          <fields>
            <field>
              <name>DIV_FRACTION</name>
              <bitOffset>0</bitOffset>
              <bitWidth>4</bitWidth>
            </field>
            <field>
              <name>DIV_MANTISSA</name>
              <bitOffset>4</bitOffset>
              <bitWidth>12</bitWidth>
            </field>
          </fields>
        </register>
        <register>
          <name>GTPR</name>
          <addressOffset>0x10</addressOffset>
          <size>0x20</size>
          <fields>
            <field>
              <name>PSC</name>
              <bitOffset>0</bitOffset>
              <bitWidth>8</bitWidth>
            </field>
            <field>
              <name>GT</name>
              <bitOffset>8</bitOffset>
              <bitWidth>8</bitWidth>
            </field>
          </fields>
        </register>
        <register>
          <name>RTOR</name>
          <addressOffset>0x14</addressOffset>
          <size>0x20</size>
          <fields>
            <field>
              <name>RTO</name>
              <bitOffset>0</bitOffset>
              <bitWidth>24</bitWidth>
            </field>
            <field>
              <name>BLEN</name>
              <bitOffset>24</bitOffset>
              <bitWidth>8</bitWidth>
            </field>
          </fields>
        </register>
        <register>
          <name>RQR</name>
          <addressOffset>0x18</addressOffset>
          <size>0x20</size>
          <fields>
            <field>
              <name>ABRRQ</name>
              <bitOffset>0</bitOffset>
              <bitWidth>1</bitWidth>
            </field>
            <field>
              <name>SBKRQ</name>
              <bitOffset>1</bitOffset>
              <bitWidth>1</bitWidth>
            </field>
            <field>
              <name>MMRQ</name>
              <bitOffset>2</bitOffset>
              <bitWidth>1</bitWidth>
            </field>
            <field>
              <name>RXFRQ</name>
              <bitOffset>3</bitOffset>
              <bitWidth>1</bitWidth>
            </field>
            <field>
              <name>TXFRQ</name>
              <bitOffset>4</bitOffset>
              <bitWidth>1</bitWidth>
            </field>
          </fields>
        </register>
        <register>
          <name>ISR</name>
          <addressOffset>0x1c</addressOffset>
          <size>0x20</size>
          <fields>
            <field>
              <name>PE</name>
              <bitOffset>0</bitOffset>
              <bitWidth>1</bitWidth>
            </field>
            <field>
              <name>FE</name>
              <bitOffset>1</bitOffset>
              <bitWidth>1</bitWidth>
            </field>
            <field>
              <name>NE</name>
              <bitOffset>2</bitOffset>
              <bitWidth>1</bitWidth>
            </field>
            <field>
              <name>ORE</name>
              <bitOffset>3</bitOffset>
              <bitWidth>1</bitWidth>
            </field>
            <field>
              <name>IDLE</name>
              <bitOffset>4</bitOffset>
              <bitWidth>1</bitWidth>
            </field>
            <field>
              <name>RXNE_RXFNE</name>
              <bitOffset>5</bitOffset>
              <bitWidth>1</bitWidth>
            </field>
            <field>
              <name>TC</name>
              <bitOffset>6</bitOffset>
              <bitWidth>1</bitWidth>
            </field>
            <field>
              <name>TXE_TXFNF</name>
              <bitOffset>7</bitOffset>
              <bitWidth>1</bitWidth>
            </field>
            <field>
              <name>LBDF</name>
              <bitOffset>8</bitOffset>
              <bitWidth>1</bitWidth>
            </field>
            <field>
              <name>CTSIF</name>
              <bitOffset>9</bitOffset>
              <bitWidth>1</bitWidth>
            </field>
            <field>
              <name>CTS</name>
              <bitOffset>10</bitOffset>
              <bitWidth>1</bitWidth>
            </field>
            <field>
              <name>RTOF</name>
              <bitOffset>11</bitOffset>
              <bitWidth>1</bitWidth>
            </field>
            <field>
              <name>EOBF</name>
              <bitOffset>12</bitOffset>
              <bitWidth>1</bitWidth>
            </field>
            <field>
              <name>UDR</name>
              <bitOffset>13</bitOffset>
              <bitWidth>1</bitWidth>
            </field>
            <field>
              <name>ABRE</name>
              <bitOffset>14</bitOffset>
              <bitWidth>1</bitWidth>
            </field>
            <field>
              <name>ABRF</name>
              <bitOffset>15</bitOffset>
              <bitWidth>1</bitWidth>
            </field>
            <field>
              <name>BUSY</name>
              <bitOffset>16</bitOffset>
              <bitWidth>1</bitWidth>
            </field>
            <field>
              <name>CMF</name>
              <bitOffset>17</bitOffset>
              <bitWidth>1</bitWidth>
            </field>
            <field>
              <name>SBKF</name>
              <bitOffset>18</bitOffset>
              <bitWidth>1</bitWidth>
            </field>
            <field>
              <name>RWU</name>
              <bitOffset>19</bitOffset>
              <bitWidth>1</bitWidth>
            </field>
            <field>
              <name>WUF</name>
              <bitOffset>20</bitOffset>
              <bitWidth>1</bitWidth>
            </field>
            <field>
              <name>TEACK</name>
              <bitOffset>21</bitOffset>
              <bitWidth>1</bitWidth>
            </field>
            <field>
              <name>REACK</name>
              <bitOffset>22</bitOffset>
              <bitWidth>1</bitWidth>
            </field>
            <field>
              <name>TXFE</name>
              <bitOffset>23</bitOffset>
              <bitWidth>1</bitWidth>
            </field>
            <field>
              <name>RXFF</name>
              <bitOffset>24</bitOffset>
              <bitWidth>1</bitWidth>
            </field>
            <field>
              <name>TCBGT</name>
              <bitOffset>25</bitOffset>
              <bitWidth>1</bitWidth>
            </field>
            <field>
              <name>RXFT</name>
              <bitOffset>26</bitOffset>
              <bitWidth>1</bitWidth>
            </field>
            <field>
              <name>TXFT</name>
              <bitOffset>27</bitOffset>
              <bitWidth>1</bitWidth>
            </field>
          </fields>
        </register>
        <register>
          <name>ICR</name>
          <addressOffset>0x20</addressOffset>
          <size>0x20</size>
          <fields>
            <field>
              <name>PECF</name>
              <bitOffset>0</bitOffset>
              <bitWidth>1</bitWidth>
            </field>
            <field>
              <name>FECF</name>
              <bitOffset>1</bitOffset>
              <bitWidth>1</bitWidth>
            </field>
            <field>
              <name>NECF</name>
              <bitOffset>2</bitOffset>
              <bitWidth>1</bitWidth>
            </field>
            <field>
              <name>ORECF</name>
              <bitOffset>3</bitOffset>
              <bitWidth>1</bitWidth>
            </field>
            <field>
              <name>IDLECF</name>
              <bitOffset>4</bitOffset>
              <bitWidth>1</bitWidth>
            </field>
            <field>
              <name>TXFECF</name>
              <bitOffset>5</bitOffset>
              <bitWidth>1</bitWidth>
            </field>
            <field>
              <name>TCCF</name>
              <bitOffset>6</bitOffset>
              <bitWidth>1</bitWidth>
            </field>
            <field>
              <name>TCBGTCF</name>
              <bitOffset>7</bitOffset>
              <bitWidth>1</bitWidth>
            </field>
            <field>
              <name>LBDCF</name>
              <bitOffset>8</bitOffset>
              <bitWidth>1</bitWidth>
            </field>
            <field>
              <name>CTSCF</name>
              <bitOffset>9</bitOffset>
              <bitWidth>1</bitWidth>
            </field>
            <field>
              <name>RTOCF</name>
              <bitOffset>11</bitOffset>
              <bitWidth>1</bitWidth>
            </field>
            <field>
              <name>EOBCF</name>
              <bitOffset>12</bitOffset>
              <bitWidth>1</bitWidth>
            </field>
            <field>
              <name>UDRCF</name>
              <bitOffset>13</bitOffset>
              <bitWidth>1</bitWidth>
            </field>
            <field>
              <name>CMCF</name>
              <bitOffset>17</bitOffset>
              <bitWidth>1</bitWidth>
            </field>
            <field>
              <name>WUCF</name>
              <bitOffset>20</bitOffset>
              <bitWidth>1</bitWidth>
            </field>
          </fields>
        </register>
        <register>
          <name>RDR</name>
          <addressOffset>0x24</addressOffset>
          <size>0x20</size>
          <fields>
            <field>
              <name>RDR</name>
              <bitOffset>0</bitOffset>
              <bitWidth>9</bitWidth>
            </field>
          </fields>
        </register>
        <register>
          <name>TDR</name>
          <addressOffset>0x28</addressOffset>
          <size>0x20</size>
          <fields>
            <field>
              <name>TDR</name>
              <bitOffset>0</bitOffset>
              <bitWidth>9</bitWidth>
            </field>
          </fields>
        </register>
        <register>
          <name>PRESC</name>
          <addressOffset>0x2c</addressOffset>
          <size>0x20</size>
          <fields>
            <field>
              <name>PRESCALER</name>
              <bitOffset>0</bitOffset>
              <bitWidth>4</bitWidth>
            </field>
          </fields>
        </register>
      </registers>
    </peripheral>
    <peripheral>
      <name>CRS</name>
      <baseAddress>0x40008400</baseAddress>
      <registers>
        <register>
          <name>CR</name>
          <addressOffset>0x0</addressOffset>
          <size>0x20</size>
          <fields>
            <field>
              <name>SYNCOKIE</name>
              <bitOffset>0</bitOffset>
              <bitWidth>1</bitWidth>
            </field>
            <field>
              <name>SYNCWARNIE</name>
              <bitOffset>1</bitOffset>
              <bitWidth>1</bitWidth>
            </field>
            <field>
              <name>ERRIE</name>
              <bitOffset>2</bitOffset>
              <bitWidth>1</bitWidth>
            </field>
            <field>
              <name>ESYNCIE</name>
              <bitOffset>3</bitOffset>
              <bitWidth>1</bitWidth>
            </field>
            <field>
              <name>CEN</name>
              <bitOffset>5</bitOffset>
              <bitWidth>1</bitWidth>
            </field>
            <field>
              <name>AUTOTRIMEN</name>
              <bitOffset>6</bitOffset>
              <bitWidth>1</bitWidth>
            </field>
            <field>
              <name>SWSYNC</name>
              <bitOffset>7</bitOffset>
              <bitWidth>1</bitWidth>
            </field>
            <field>
              <name>TRIM</name>
              <bitOffset>8</bitOffset>
              <bitWidth>6</bitWidth>
            </field>
          </fields>
        </register>
        <register>
          <name>CFGR</name>
          <addressOffset>0x4</addressOffset>
          <size>0x20</size>
          <fields>
            <field>
              <name>RELOAD</name>
              <bitOffset>0</bitOffset>
              <bitWidth>16</bitWidth>
            </field>
            <field>
              <name>FELIM</name>
              <bitOffset>16</bitOffset>
              <bitWidth>8</bitWidth>
            </field>
            <field>
              <name>SYNCDIV</name>
              <bitOffset>24</bitOffset>
              <bitWidth>3</bitWidth>
            </field>
            <field>
              <name>SYNCSRC</name>
              <bitOffset>28</bitOffset>
              <bitWidth>2</bitWidth>
            </field>
            <field>
              <name>SYNCPOL</name>
              <bitOffset>31</bitOffset>
              <bitWidth>1</bitWidth>
            </field>
          </fields>
        </register>
        <register>
          <name>ISR</name>
          <addressOffset>0x8</addressOffset>
          <size>0x20</size>
          <fields>
            <field>
              <name>SYNCOKF</name>
              <bitOffset>0</bitOffset>
              <bitWidth>1</bitWidth>
            </field>
            <field>
              <name>SYNCWARNF</name>
              <bitOffset>1</bitOffset>
              <bitWidth>1</bitWidth>
            </field>
            <field>
              <name>ERRF</name>
              <bitOffset>2</bitOffset>
              <bitWidth>1</bitWidth>
            </field>
            <field>
              <name>ESYNCF</name>
              <bitOffset>3</bitOffset>
              <bitWidth>1</bitWidth>
            </field>
            <field>
              <name>SYNCERR</name>
              <bitOffset>8</bitOffset>
              <bitWidth>1</bitWidth>
            </field>
            <field>
              <name>SYNCMISS</name>
              <bitOffset>9</bitOffset>
              <bitWidth>1</bitWidth>
            </field>
            <field>
              <name>TRIMOVF</name>
              <bitOffset>10</bitOffset>
              <bitWidth>1</bitWidth>
            </field>
            <field>
              <name>FEDIR</name>
              <bitOffset>15</bitOffset>
              <bitWidth>1</bitWidth>
            </field>
            <field>
              <name>FECAP</name>
              <bitOffset>16</bitOffset>
              <bitWidth>16</bitWidth>
            </field>
          </fields>
        </register>
        <register>
          <name>ICR</name>
          <addressOffset>0xc</addressOffset>
          <size>0x20</size>
          <fields>
            <field>
              <name>SYNCOKC</name>
              <bitOffset>0</bitOffset>
              <bitWidth>1</bitWidth>
            </field>
            <field>
              <name>SYNCWARNC</name>
              <bitOffset>1</bitOffset>
              <bitWidth>1</bitWidth>
            </field>
            <field>
              <name>ERRC</name>
              <bitOffset>2</bitOffset>
              <bitWidth>1</bitWidth>
            </field>
            <field>
              <name>ESYNCC</name>
              <bitOffset>3</bitOffset>
              <bitWidth>1</bitWidth>
            </field>
          </fields>
        </register>
      </registers>
    </peripheral>
    <peripheral>
      <name>SWPMI1</name>
      <baseAddress>0x40008800</baseAddress>
      <registers>
        <register>
          <name>CR</name>
          <addressOffset>0x0</addressOffset>
          <size>0x20</size>
          <fields>
            <field>
              <name>RXDMA</name>
              <bitOffset>0</bitOffset>
              <bitWidth>1</bitWidth>
            </field>
            <field>
              <name>TXDMA</name>
              <bitOffset>1</bitOffset>
              <bitWidth>1</bitWidth>
            </field>
            <field>
              <name>RXMODE</name>
              <bitOffset>2</bitOffset>
              <bitWidth>1</bitWidth>
            </field>
            <field>
              <name>TXMODE</name>
              <bitOffset>3</bitOffset>
              <bitWidth>1</bitWidth>
            </field>
            <field>
              <name>LPBK</name>
              <bitOffset>4</bitOffset>
              <bitWidth>1</bitWidth>
            </field>
            <field>
              <name>SWPACT</name>
              <bitOffset>5</bitOffset>
              <bitWidth>1</bitWidth>
            </field>
            <field>
              <name>DEACT</name>
              <bitOffset>10</bitOffset>
              <bitWidth>1</bitWidth>
            </field>
            <field>
              <name>SWPEN</name>
              <bitOffset>11</bitOffset>
              <bitWidth>1</bitWidth>
            </field>
          </fields>
        </register>
        <register>
          <name>BRR</name>
          <addressOffset>0x4</addressOffset>
          <size>0x20</size>
          <fields>
            <field>
              <name>BR</name>
              <bitOffset>0</bitOffset>
              <bitWidth>8</bitWidth>
            </field>
          </fields>
        </register>
        <register>
          <name>ISR</name>
          <addressOffset>0xc</addressOffset>
          <size>0x20</size>
          <fields>
            <field>
              <name>RXBFF</name>
              <bitOffset>0</bitOffset>
              <bitWidth>1</bitWidth>
            </field>
            <field>
              <name>TXBEF</name>
              <bitOffset>1</bitOffset>
              <bitWidth>1</bitWidth>
            </field>
            <field>
              <name>RXBERF</name>
              <bitOffset>2</bitOffset>
              <bitWidth>1</bitWidth>
            </field>
            <field>
              <name>RXOVRF</name>
              <bitOffset>3</bitOffset>
              <bitWidth>1</bitWidth>
            </field>
            <field>
              <name>TXUNRF</name>
              <bitOffset>4</bitOffset>
              <bitWidth>1</bitWidth>
            </field>
            <field>
              <name>RXNE</name>
              <bitOffset>5</bitOffset>
              <bitWidth>1</bitWidth>
            </field>
            <field>
              <name>TXE</name>
              <bitOffset>6</bitOffset>
              <bitWidth>1</bitWidth>
            </field>
            <field>
              <name>TCF</name>
              <bitOffset>7</bitOffset>
              <bitWidth>1</bitWidth>
            </field>
            <field>
              <name>SRF</name>
              <bitOffset>8</bitOffset>
              <bitWidth>1</bitWidth>
            </field>
            <field>
              <name>SUSP</name>
              <bitOffset>9</bitOffset>
              <bitWidth>1</bitWidth>
            </field>
            <field>
              <name>DEACTF</name>
              <bitOffset>10</bitOffset>
              <bitWidth>1</bitWidth>
            </field>
            <field>
              <name>RDYF</name>
              <bitOffset>11</bitOffset>
              <bitWidth>1</bitWidth>
            </field>
          </fields>
        </register>
        <register>
          <name>ICR</name>
          <addressOffset>0x10</addressOffset>
          <size>0x20</size>
          <fields>
            <field>
              <name>CRXBFF</name>
              <bitOffset>0</bitOffset>
              <bitWidth>1</bitWidth>
            </field>
            <field>
              <name>CTXBEF</name>
              <bitOffset>1</bitOffset>
              <bitWidth>1</bitWidth>
            </field>
            <field>
              <name>CRXBERF</name>
              <bitOffset>2</bitOffset>
              <bitWidth>1</bitWidth>
            </field>
            <field>
              <name>CRXOVRF</name>
              <bitOffset>3</bitOffset>
              <bitWidth>1</bitWidth>
            </field>
            <field>
              <name>CTXUNRF</name>
              <bitOffset>4</bitOffset>
              <bitWidth>1</bitWidth>
            </field>
            <field>
              <name>CTCF</name>
              <bitOffset>7</bitOffset>
              <bitWidth>1</bitWidth>
            </field>
            <field>
              <name>CSRF</name>
              <bitOffset>8</bitOffset>
              <bitWidth>1</bitWidth>
            </field>
            <field>
              <name>CRDYF</name>
              <bitOffset>11</bitOffset>
              <bitWidth>1</bitWidth>
            </field>
          </fields>
        </register>
        <register>
          <name>IER</name>
          <addressOffset>0x14</addressOffset>
          <size>0x20</size>
          <fields>
            <field>
              <name>RXBFIE</name>
              <bitOffset>0</bitOffset>
              <bitWidth>1</bitWidth>
            </field>
            <field>
              <name>TXBEIE</name>
              <bitOffset>1</bitOffset>
              <bitWidth>1</bitWidth>
            </field>
            <field>
              <name>RXBERIE</name>
              <bitOffset>2</bitOffset>
              <bitWidth>1</bitWidth>
            </field>
            <field>
              <name>RXOVRIE</name>
              <bitOffset>3</bitOffset>
              <bitWidth>1</bitWidth>
            </field>
            <field>
              <name>TXUNRIE</name>
              <bitOffset>4</bitOffset>
              <bitWidth>1</bitWidth>
            </field>
            <field>
              <name>RIE</name>
              <bitOffset>5</bitOffset>
              <bitWidth>1</bitWidth>
            </field>
            <field>
              <name>TIE</name>
              <bitOffset>6</bitOffset>
              <bitWidth>1</bitWidth>
            </field>
            <field>
              <name>TCIE</name>
              <bitOffset>7</bitOffset>
              <bitWidth>1</bitWidth>
            </field>
            <field>
              <name>SRIE</name>
              <bitOffset>8</bitOffset>
              <bitWidth>1</bitWidth>
            </field>
            <field>
              <name>RDYIE</name>
              <bitOffset>11</bitOffset>
              <bitWidth>1</bitWidth>
            </field>
          </fields>
        </register>
        <register>
          <name>RFL</name>
          <addressOffset>0x18</addressOffset>
          <size>0x20</size>
          <fields>
            <field>
              <name>RFL</name>
              <bitOffset>0</bitOffset>
              <bitWidth>5</bitWidth>
            </field>
          </fields>
        </register>
        <register>
          <name>TDR</name>
          <addressOffset>0x1c</addressOffset>
          <size>0x20</size>
          <fields>
            <field>
              <name>TD</name>
              <bitOffset>0</bitOffset>
              <bitWidth>32</bitWidth>
            </field>
          </fields>
        </register>
        <register>
          <name>RDR</name>
          <addressOffset>0x20</addressOffset>
          <size>0x20</size>
          <fields>
            <field>
              <name>RD</name>
              <bitOffset>0</bitOffset>
              <bitWidth>32</bitWidth>
            </field>
          </fields>
        </register>
        <register>
          <name>OR</name>
          <addressOffset>0x24</addressOffset>
          <size>0x20</size>
          <fields>
            <field>
              <name>TBYP</name>
              <bitOffset>0</bitOffset>
              <bitWidth>1</bitWidth>
            </field>
            <field>
              <name>CLASS</name>
              <bitOffset>1</bitOffset>
              <bitWidth>1</bitWidth>
            </field>
          </fields>
        </register>
      </registers>
    </peripheral>
    <peripheral>
      <name>OPAMP</name>
      <baseAddress>0x40009000</baseAddress>
      <registers>
        <register>
          <name>CSR</name>
          <addressOffset>0x0</addressOffset>
          <size>0x20</size>
          <fields>
            <field>
              <name>OPAMPxEN</name>
              <bitOffset>0</bitOffset>
              <bitWidth>1</bitWidth>
            </field>
            <field>
              <name>FORCEVP</name>
              <bitOffset>1</bitOffset>
              <bitWidth>1</bitWidth>
            </field>
            <field>
              <name>VPSEL</name>
              <bitOffset>2</bitOffset>
              <bitWidth>2</bitWidth>
            </field>
            <field>
              <name>VMSEL</name>
              <bitOffset>5</bitOffset>
              <bitWidth>2</bitWidth>
            </field>
            <field>
              <name>OPAHSM</name>
              <bitOffset>8</bitOffset>
              <bitWidth>1</bitWidth>
            </field>
            <field>
              <name>CALON</name>
              <bitOffset>11</bitOffset>
              <bitWidth>1</bitWidth>
            </field>
            <field>
              <name>CALSEL</name>
              <bitOffset>12</bitOffset>
              <bitWidth>2</bitWidth>
            </field>
            <field>
              <name>PGGAIN</name>
              <bitOffset>14</bitOffset>
              <bitWidth>4</bitWidth>
            </field>
            <field>
              <name>USERTRIM</name>
              <bitOffset>18</bitOffset>
              <bitWidth>1</bitWidth>
            </field>
            <field>
              <name>TSTREF</name>
              <bitOffset>29</bitOffset>
              <bitWidth>1</bitWidth>
            </field>
            <field>
              <name>CALOUT</name>
              <bitOffset>30</bitOffset>
              <bitWidth>1</bitWidth>
            </field>
          </fields>
        </register>
        <register>
          <name>OTR</name>
          <addressOffset>0x4</addressOffset>
          <size>0x20</size>
          <fields>
            <field>
              <name>TRIMOFFSETN</name>
              <bitOffset>0</bitOffset>
              <bitWidth>5</bitWidth>
            </field>
            <field>
              <name>TRIMOFFSETP</name>
              <bitOffset>8</bitOffset>
              <bitWidth>5</bitWidth>
            </field>
          </fields>
        </register>
        <register>
          <name>HSOTR</name>
          <addressOffset>0x8</addressOffset>
          <size>0x20</size>
          <fields>
            <field>
              <name>TRIMHSOFFSETN</name>
              <bitOffset>0</bitOffset>
              <bitWidth>5</bitWidth>
            </field>
            <field>
              <name>TRIMHSOFFSETP</name>
              <bitOffset>8</bitOffset>
              <bitWidth>5</bitWidth>
            </field>
          </fields>
        </register>
      </registers>
    </peripheral>
    <peripheral>
      <name>OPAMP1</name>
      <baseAddress>0x40009000</baseAddress>
      <registers>
        <register>
          <name>CSR</name>
          <addressOffset>0x0</addressOffset>
          <size>0x20</size>
          <fields>
            <field>
              <name>OPAMPxEN</name>
              <bitOffset>0</bitOffset>
              <bitWidth>1</bitWidth>
            </field>
            <field>
              <name>FORCEVP</name>
              <bitOffset>1</bitOffset>
              <bitWidth>1</bitWidth>
            </field>
            <field>
              <name>VPSEL</name>
              <bitOffset>2</bitOffset>
              <bitWidth>2</bitWidth>
            </field>
            <field>
              <name>VMSEL</name>
              <bitOffset>5</bitOffset>
              <bitWidth>2</bitWidth>
            </field>
            <field>
              <name>OPAHSM</name>
              <bitOffset>8</bitOffset>
              <bitWidth>1</bitWidth>
            </field>
            <field>
              <name>CALON</name>
              <bitOffset>11</bitOffset>
              <bitWidth>1</bitWidth>
            </field>
            <field>
              <name>CALSEL</name>
              <bitOffset>12</bitOffset>
              <bitWidth>2</bitWidth>
            </field>
            <field>
              <name>PGGAIN</name>
              <bitOffset>14</bitOffset>
              <bitWidth>4</bitWidth>
            </field>
            <field>
              <name>USERTRIM</name>
              <bitOffset>18</bitOffset>
              <bitWidth>1</bitWidth>
            </field>
            <field>
              <name>TSTREF</name>
              <bitOffset>29</bitOffset>
              <bitWidth>1</bitWidth>
            </field>
            <field>
              <name>CALOUT</name>
              <bitOffset>30</bitOffset>
              <bitWidth>1</bitWidth>
            </field>
          </fields>
        </register>
        <register>
          <name>OTR</name>
          <addressOffset>0x4</addressOffset>
          <size>0x20</size>
          <fields>
            <field>
              <name>TRIMOFFSETN</name>
              <bitOffset>0</bitOffset>
              <bitWidth>5</bitWidth>
            </field>
            <field>
              <name>TRIMOFFSETP</name>
              <bitOffset>8</bitOffset>
              <bitWidth>5</bitWidth>
            </field>
          </fields>
        </register>
        <register>
          <name>HSOTR</name>
          <addressOffset>0x8</addressOffset>
          <size>0x20</size>
          <fields>
            <field>
              <name>TRIMHSOFFSETN</name>
              <bitOffset>0</bitOffset>
              <bitWidth>5</bitWidth>
            </field>
            <field>
              <name>TRIMHSOFFSETP</name>
              <bitOffset>8</bitOffset>
              <bitWidth>5</bitWidth>
            </field>
          </fields>
        </register>
      </registers>
    </peripheral>
    <peripheral>
      <name>OPAMP2</name>
      <baseAddress>0x40009010</baseAddress>
      <registers>
        <register>
          <name>CSR</name>
          <addressOffset>0x0</addressOffset>
          <size>0x20</size>
          <fields>
            <field>
              <name>OPAMPxEN</name>
              <bitOffset>0</bitOffset>
              <bitWidth>1</bitWidth>
            </field>
            <field>
              <name>FORCEVP</name>
              <bitOffset>1</bitOffset>
              <bitWidth>1</bitWidth>
            </field>
            <field>
              <name>VPSEL</name>
              <bitOffset>2</bitOffset>
              <bitWidth>2</bitWidth>
            </field>
            <field>
              <name>VMSEL</name>
              <bitOffset>5</bitOffset>
              <bitWidth>2</bitWidth>
            </field>
            <field>
              <name>OPAHSM</name>
              <bitOffset>8</bitOffset>
              <bitWidth>1</bitWidth>
            </field>
            <field>
              <name>CALON</name>
              <bitOffset>11</bitOffset>
              <bitWidth>1</bitWidth>
            </field>
            <field>
              <name>CALSEL</name>
              <bitOffset>12</bitOffset>
              <bitWidth>2</bitWidth>
            </field>
            <field>
              <name>PGGAIN</name>
              <bitOffset>14</bitOffset>
              <bitWidth>4</bitWidth>
            </field>
            <field>
              <name>USERTRIM</name>
              <bitOffset>18</bitOffset>
              <bitWidth>1</bitWidth>
            </field>
            <field>
              <name>TSTREF</name>
              <bitOffset>29</bitOffset>
              <bitWidth>1</bitWidth>
            </field>
            <field>
              <name>CALOUT</name>
              <bitOffset>30</bitOffset>
              <bitWidth>1</bitWidth>
            </field>
          </fields>
        </register>
        <register>
          <name>OTR</name>
          <addressOffset>0x4</addressOffset>
          <size>0x20</size>
          <fields>
            <field>
              <name>TRIMOFFSETN</name>
              <bitOffset>0</bitOffset>
              <bitWidth>5</bitWidth>
            </field>
            <field>
              <name>TRIMOFFSETP</name>
              <bitOffset>8</bitOffset>
              <bitWidth>5</bitWidth>
            </field>
          </fields>
        </register>
        <register>
          <name>HSOTR</name>
          <addressOffset>0x8</addressOffset>
          <size>0x20</size>
          <fields>
            <field>
              <name>TRIMHSOFFSETN</name>
              <bitOffset>0</bitOffset>
              <bitWidth>5</bitWidth>
            </field>
            <field>
              <name>TRIMHSOFFSETP</name>
              <bitOffset>8</bitOffset>
              <bitWidth>5</bitWidth>
            </field>
          </fields>
        </register>
      </registers>
    </peripheral>
    <peripheral>
      <name>MDIOS</name>
      <baseAddress>0x40009400</baseAddress>
      <registers>
        <register>
          <name>CR</name>
          <addressOffset>0x0</addressOffset>
          <size>0x20</size>
          <fields>
            <field>
              <name>EN</name>
              <bitOffset>0</bitOffset>
              <bitWidth>1</bitWidth>
            </field>
            <field>
              <name>WRIE</name>
              <bitOffset>1</bitOffset>
              <bitWidth>1</bitWidth>
            </field>
            <field>
              <name>RDIE</name>
              <bitOffset>2</bitOffset>
              <bitWidth>1</bitWidth>
            </field>
            <field>
              <name>EIE</name>
              <bitOffset>3</bitOffset>
              <bitWidth>1</bitWidth>
            </field>
            <field>
              <name>DPC</name>
              <bitOffset>7</bitOffset>
              <bitWidth>1</bitWidth>
            </field>
            <field>
              <name>PORT_ADDRESS</name>
              <bitOffset>8</bitOffset>
              <bitWidth>5</bitWidth>
            </field>
          </fields>
        </register>
        <register>
          <name>WRFR</name>
          <addressOffset>0x4</addressOffset>
          <size>0x20</size>
        </register>
        <register>
          <name>CWRFR</name>
          <addressOffset>0x8</addressOffset>
          <size>0x20</size>
        </register>
        <register>
          <name>RDFR</name>
          <addressOffset>0xc</addressOffset>
          <size>0x20</size>
        </register>
        <register>
          <name>CRDFR</name>
          <addressOffset>0x10</addressOffset>
          <size>0x20</size>
        </register>
        <register>
          <name>SR</name>
          <addressOffset>0x14</addressOffset>
          <size>0x20</size>
          <fields>
            <field>
              <name>PERF</name>
              <bitOffset>0</bitOffset>
              <bitWidth>1</bitWidth>
            </field>
            <field>
              <name>SERF</name>
              <bitOffset>1</bitOffset>
              <bitWidth>1</bitWidth>
            </field>
            <field>
              <name>TERF</name>
              <bitOffset>2</bitOffset>
              <bitWidth>1</bitWidth>
            </field>
          </fields>
        </register>
        <register>
          <name>CLRFR</name>
          <addressOffset>0x18</addressOffset>
          <size>0x20</size>
        </register>
        <register>
          <name>DINR0</name>
          <addressOffset>0x100</addressOffset>
          <size>0x20</size>
        </register>
        <register>
          <name>DINR1</name>
          <addressOffset>0x104</addressOffset>
          <size>0x20</size>
        </register>
        <register>
          <name>DINR2</name>
          <addressOffset>0x108</addressOffset>
          <size>0x20</size>
        </register>
        <register>
          <name>DINR3</name>
          <addressOffset>0x10c</addressOffset>
          <size>0x20</size>
        </register>
        <register>
          <name>DINR4</name>
          <addressOffset>0x110</addressOffset>
          <size>0x20</size>
        </register>
        <register>
          <name>DINR5</name>
          <addressOffset>0x114</addressOffset>
          <size>0x20</size>
        </register>
        <register>
          <name>DINR6</name>
          <addressOffset>0x118</addressOffset>
          <size>0x20</size>
        </register>
        <register>
          <name>DINR7</name>
          <addressOffset>0x11c</addressOffset>
          <size>0x20</size>
        </register>
        <register>
          <name>DINR8</name>
          <addressOffset>0x120</addressOffset>
          <size>0x20</size>
        </register>
        <register>
          <name>DINR9</name>
          <addressOffset>0x124</addressOffset>
          <size>0x20</size>
        </register>
        <register>
          <name>DINR10</name>
          <addressOffset>0x128</addressOffset>
          <size>0x20</size>
        </register>
        <register>
          <name>DINR11</name>
          <addressOffset>0x12c</addressOffset>
          <size>0x20</size>
        </register>
        <register>
          <name>DINR12</name>
          <addressOffset>0x130</addressOffset>
          <size>0x20</size>
        </register>
        <register>
          <name>DINR13</name>
          <addressOffset>0x134</addressOffset>
          <size>0x20</size>
        </register>
        <register>
          <name>DINR14</name>
          <addressOffset>0x138</addressOffset>
          <size>0x20</size>
        </register>
        <register>
          <name>DINR15</name>
          <addressOffset>0x13c</addressOffset>
          <size>0x20</size>
        </register>
        <register>
          <name>DINR16</name>
          <addressOffset>0x140</addressOffset>
          <size>0x20</size>
        </register>
        <register>
          <name>DINR17</name>
          <addressOffset>0x144</addressOffset>
          <size>0x20</size>
        </register>
        <register>
          <name>DINR18</name>
          <addressOffset>0x148</addressOffset>
          <size>0x20</size>
        </register>
        <register>
          <name>DINR19</name>
          <addressOffset>0x14c</addressOffset>
          <size>0x20</size>
        </register>
        <register>
          <name>DINR20</name>
          <addressOffset>0x150</addressOffset>
          <size>0x20</size>
        </register>
        <register>
          <name>DINR21</name>
          <addressOffset>0x154</addressOffset>
          <size>0x20</size>
        </register>
        <register>
          <name>DINR22</name>
          <addressOffset>0x158</addressOffset>
          <size>0x20</size>
        </register>
        <register>
          <name>DINR23</name>
          <addressOffset>0x15c</addressOffset>
          <size>0x20</size>
        </register>
        <register>
          <name>DINR24</name>
          <addressOffset>0x160</addressOffset>
          <size>0x20</size>
        </register>
        <register>
          <name>DINR25</name>
          <addressOffset>0x164</addressOffset>
          <size>0x20</size>
        </register>
        <register>
          <name>DINR26</name>
          <addressOffset>0x168</addressOffset>
          <size>0x20</size>
        </register>
        <register>
          <name>DINR27</name>
          <addressOffset>0x16c</addressOffset>
          <size>0x20</size>
        </register>
        <register>
          <name>DINR28</name>
          <addressOffset>0x170</addressOffset>
          <size>0x20</size>
        </register>
        <register>
          <name>DINR29</name>
          <addressOffset>0x174</addressOffset>
          <size>0x20</size>
        </register>
        <register>
          <name>DINR30</name>
          <addressOffset>0x178</addressOffset>
          <size>0x20</size>
        </register>
        <register>
          <name>DINR31</name>
          <addressOffset>0x17c</addressOffset>
          <size>0x20</size>
        </register>
        <register>
          <name>DOUTR0</name>
          <addressOffset>0x180</addressOffset>
          <size>0x20</size>
        </register>
        <register>
          <name>DOUTR1</name>
          <addressOffset>0x184</addressOffset>
          <size>0x20</size>
        </register>
        <register>
          <name>DOUTR2</name>
          <addressOffset>0x188</addressOffset>
          <size>0x20</size>
        </register>
        <register>
          <name>DOUTR3</name>
          <addressOffset>0x18c</addressOffset>
          <size>0x20</size>
        </register>
        <register>
          <name>DOUTR4</name>
          <addressOffset>0x190</addressOffset>
          <size>0x20</size>
        </register>
        <register>
          <name>DOUTR5</name>
          <addressOffset>0x194</addressOffset>
          <size>0x20</size>
        </register>
        <register>
          <name>DOUTR6</name>
          <addressOffset>0x198</addressOffset>
          <size>0x20</size>
        </register>
        <register>
          <name>DOUTR7</name>
          <addressOffset>0x19c</addressOffset>
          <size>0x20</size>
        </register>
        <register>
          <name>DOUTR8</name>
          <addressOffset>0x1a0</addressOffset>
          <size>0x20</size>
        </register>
        <register>
          <name>DOUTR9</name>
          <addressOffset>0x1a4</addressOffset>
          <size>0x20</size>
        </register>
        <register>
          <name>DOUTR10</name>
          <addressOffset>0x1a8</addressOffset>
          <size>0x20</size>
        </register>
        <register>
          <name>DOUTR11</name>
          <addressOffset>0x1ac</addressOffset>
          <size>0x20</size>
        </register>
        <register>
          <name>DOUTR12</name>
          <addressOffset>0x1b0</addressOffset>
          <size>0x20</size>
        </register>
        <register>
          <name>DOUTR13</name>
          <addressOffset>0x1b4</addressOffset>
          <size>0x20</size>
        </register>
        <register>
          <name>DOUTR14</name>
          <addressOffset>0x1b8</addressOffset>
          <size>0x20</size>
        </register>
        <register>
          <name>DOUTR15</name>
          <addressOffset>0x1bc</addressOffset>
          <size>0x20</size>
        </register>
        <register>
          <name>DOUTR16</name>
          <addressOffset>0x1c0</addressOffset>
          <size>0x20</size>
        </register>
        <register>
          <name>DOUTR17</name>
          <addressOffset>0x1c4</addressOffset>
          <size>0x20</size>
        </register>
        <register>
          <name>DOUTR18</name>
          <addressOffset>0x1c8</addressOffset>
          <size>0x20</size>
        </register>
        <register>
          <name>DOUTR19</name>
          <addressOffset>0x1cc</addressOffset>
          <size>0x20</size>
        </register>
        <register>
          <name>DOUTR20</name>
          <addressOffset>0x1d0</addressOffset>
          <size>0x20</size>
        </register>
        <register>
          <name>DOUTR21</name>
          <addressOffset>0x1d4</addressOffset>
          <size>0x20</size>
        </register>
        <register>
          <name>DOUTR22</name>
          <addressOffset>0x1d8</addressOffset>
          <size>0x20</size>
        </register>
        <register>
          <name>DOUTR23</name>
          <addressOffset>0x1dc</addressOffset>
          <size>0x20</size>
        </register>
        <register>
          <name>DOUTR24</name>
          <addressOffset>0x1e0</addressOffset>
          <size>0x20</size>
        </register>
        <register>
          <name>DOUTR25</name>
          <addressOffset>0x1e4</addressOffset>
          <size>0x20</size>
        </register>
        <register>
          <name>DOUTR26</name>
          <addressOffset>0x1e8</addressOffset>
          <size>0x20</size>
        </register>
        <register>
          <name>DOUTR27</name>
          <addressOffset>0x1ec</addressOffset>
          <size>0x20</size>
        </register>
        <register>
          <name>DOUTR28</name>
          <addressOffset>0x1f0</addressOffset>
          <size>0x20</size>
        </register>
        <register>
          <name>DOUTR29</name>
          <addressOffset>0x1f4</addressOffset>
          <size>0x20</size>
        </register>
        <register>
          <name>DOUTR30</name>
          <addressOffset>0x1f8</addressOffset>
          <size>0x20</size>
        </register>
        <register>
          <name>DOUTR31</name>
          <addressOffset>0x1fc</addressOffset>
          <size>0x20</size>
        </register>
      </registers>
    </peripheral>
    <peripheral>
      <name>FDCAN1</name>
      <baseAddress>0x4000a000</baseAddress>
      <registers>
        <register>
          <name>CREL</name>
          <addressOffset>0x0</addressOffset>
          <size>0x20</size>
          <fields>
            <field>
              <name>DAY</name>
              <bitOffset>0</bitOffset>
              <bitWidth>8</bitWidth>
            </field>
            <field>
              <name>MON</name>
              <bitOffset>8</bitOffset>
              <bitWidth>8</bitWidth>
            </field>
            <field>
              <name>YEAR</name>
              <bitOffset>16</bitOffset>
              <bitWidth>4</bitWidth>
            </field>
            <field>
              <name>SUBSTEP</name>
              <bitOffset>20</bitOffset>
              <bitWidth>4</bitWidth>
            </field>
            <field>
              <name>STEP</name>
              <bitOffset>24</bitOffset>
              <bitWidth>4</bitWidth>
            </field>
            <field>
              <name>REL</name>
              <bitOffset>28</bitOffset>
              <bitWidth>4</bitWidth>
            </field>
          </fields>
        </register>
        <register>
          <name>ENDN</name>
          <addressOffset>0x4</addressOffset>
          <size>0x20</size>
          <fields>
            <field>
              <name>ETV</name>
              <bitOffset>0</bitOffset>
              <bitWidth>32</bitWidth>
            </field>
          </fields>
        </register>
        <register>
          <name>DBTP</name>
          <addressOffset>0xc</addressOffset>
          <size>0x20</size>
          <fields>
            <field>
              <name>DSJW</name>
              <bitOffset>0</bitOffset>
              <bitWidth>4</bitWidth>
            </field>
            <field>
              <name>DTSEG2</name>
              <bitOffset>4</bitOffset>
              <bitWidth>4</bitWidth>
            </field>
            <field>
              <name>DTSEG1</name>
              <bitOffset>8</bitOffset>
              <bitWidth>5</bitWidth>
            </field>
            <field>
              <name>DBRP</name>
              <bitOffset>16</bitOffset>
              <bitWidth>5</bitWidth>
            </field>
            <field>
              <name>TDC</name>
              <bitOffset>23</bitOffset>
              <bitWidth>1</bitWidth>
            </field>
          </fields>
        </register>
        <register>
          <name>TEST</name>
          <addressOffset>0x10</addressOffset>
          <size>0x20</size>
          <fields>
            <field>
              <name>LBCK</name>
              <bitOffset>4</bitOffset>
              <bitWidth>1</bitWidth>
            </field>
            <field>
              <name>TX</name>
              <bitOffset>5</bitOffset>
              <bitWidth>2</bitWidth>
            </field>
            <field>
              <name>RX</name>
              <bitOffset>7</bitOffset>
              <bitWidth>1</bitWidth>
            </field>
          </fields>
        </register>
        <register>
          <name>RWD</name>
          <addressOffset>0x14</addressOffset>
          <size>0x20</size>
          <fields>
            <field>
              <name>WDC</name>
              <bitOffset>0</bitOffset>
              <bitWidth>8</bitWidth>
            </field>
            <field>
              <name>WDV</name>
              <bitOffset>8</bitOffset>
              <bitWidth>8</bitWidth>
            </field>
          </fields>
        </register>
        <register>
          <name>CCCR</name>
          <addressOffset>0x18</addressOffset>
          <size>0x20</size>
          <fields>
            <field>
              <name>INIT</name>
              <bitOffset>0</bitOffset>
              <bitWidth>1</bitWidth>
            </field>
            <field>
              <name>CCE</name>
              <bitOffset>1</bitOffset>
              <bitWidth>1</bitWidth>
            </field>
            <field>
              <name>ASM</name>
              <bitOffset>2</bitOffset>
              <bitWidth>1</bitWidth>
            </field>
            <field>
              <name>CSA</name>
              <bitOffset>3</bitOffset>
              <bitWidth>1</bitWidth>
            </field>
            <field>
              <name>CSR</name>
              <bitOffset>4</bitOffset>
              <bitWidth>1</bitWidth>
            </field>
            <field>
              <name>MON</name>
              <bitOffset>5</bitOffset>
              <bitWidth>1</bitWidth>
            </field>
            <field>
              <name>DAR</name>
              <bitOffset>6</bitOffset>
              <bitWidth>1</bitWidth>
            </field>
            <field>
              <name>TEST</name>
              <bitOffset>7</bitOffset>
              <bitWidth>1</bitWidth>
            </field>
            <field>
              <name>FDOE</name>
              <bitOffset>8</bitOffset>
              <bitWidth>1</bitWidth>
            </field>
            <field>
              <name>BRSE</name>
              <bitOffset>9</bitOffset>
              <bitWidth>1</bitWidth>
            </field>
            <field>
              <name>PXHD</name>
              <bitOffset>12</bitOffset>
              <bitWidth>1</bitWidth>
            </field>
            <field>
              <name>EFBI</name>
              <bitOffset>13</bitOffset>
              <bitWidth>1</bitWidth>
            </field>
            <field>
              <name>TXP</name>
              <bitOffset>14</bitOffset>
              <bitWidth>1</bitWidth>
            </field>
            <field>
              <name>NISO</name>
              <bitOffset>15</bitOffset>
              <bitWidth>1</bitWidth>
            </field>
          </fields>
        </register>
        <register>
          <name>NBTP</name>
          <addressOffset>0x1c</addressOffset>
          <size>0x20</size>
          <fields>
            <field>
              <name>NTSEG2</name>
              <bitOffset>0</bitOffset>
              <bitWidth>7</bitWidth>
            </field>
            <field>
              <name>NTSEG1</name>
              <bitOffset>8</bitOffset>
              <bitWidth>8</bitWidth>
            </field>
            <field>
              <name>NBRP</name>
              <bitOffset>16</bitOffset>
              <bitWidth>9</bitWidth>
            </field>
            <field>
              <name>NSJW</name>
              <bitOffset>25</bitOffset>
              <bitWidth>7</bitWidth>
            </field>
          </fields>
        </register>
        <register>
          <name>TSCC</name>
          <addressOffset>0x20</addressOffset>
          <size>0x20</size>
          <fields>
            <field>
              <name>TSS</name>
              <bitOffset>0</bitOffset>
              <bitWidth>2</bitWidth>
            </field>
            <field>
              <name>TCP</name>
              <bitOffset>16</bitOffset>
              <bitWidth>4</bitWidth>
            </field>
          </fields>
        </register>
        <register>
          <name>TSCV</name>
          <addressOffset>0x24</addressOffset>
          <size>0x20</size>
          <fields>
            <field>
              <name>TSC</name>
              <bitOffset>0</bitOffset>
              <bitWidth>16</bitWidth>
            </field>
          </fields>
        </register>
        <register>
          <name>TOCC</name>
          <addressOffset>0x28</addressOffset>
          <size>0x20</size>
          <fields>
            <field>
              <name>ETOC</name>
              <bitOffset>0</bitOffset>
              <bitWidth>1</bitWidth>
            </field>
            <field>
              <name>TOS</name>
              <bitOffset>1</bitOffset>
              <bitWidth>2</bitWidth>
            </field>
            <field>
              <name>TOP</name>
              <bitOffset>16</bitOffset>
              <bitWidth>16</bitWidth>
            </field>
          </fields>
        </register>
        <register>
          <name>TOCV</name>
          <addressOffset>0x2c</addressOffset>
          <size>0x20</size>
          <fields>
            <field>
              <name>TOC</name>
              <bitOffset>0</bitOffset>
              <bitWidth>16</bitWidth>
            </field>
          </fields>
        </register>
        <register>
          <name>ECR</name>
          <addressOffset>0x40</addressOffset>
          <size>0x20</size>
          <fields>
            <field>
              <name>TEC</name>
              <bitOffset>0</bitOffset>
              <bitWidth>8</bitWidth>
            </field>
            <field>
              <name>REC</name>
              <bitOffset>8</bitOffset>
              <bitWidth>7</bitWidth>
            </field>
            <field>
              <name>RP</name>
              <bitOffset>15</bitOffset>
              <bitWidth>1</bitWidth>
            </field>
            <field>
              <name>CEL</name>
              <bitOffset>16</bitOffset>
              <bitWidth>8</bitWidth>
            </field>
          </fields>
        </register>
        <register>
          <name>PSR</name>
          <addressOffset>0x44</addressOffset>
          <size>0x20</size>
          <fields>
            <field>
              <name>LEC</name>
              <bitOffset>0</bitOffset>
              <bitWidth>3</bitWidth>
            </field>
            <field>
              <name>ACT</name>
              <bitOffset>3</bitOffset>
              <bitWidth>2</bitWidth>
            </field>
            <field>
              <name>EP</name>
              <bitOffset>5</bitOffset>
              <bitWidth>1</bitWidth>
            </field>
            <field>
              <name>EW</name>
              <bitOffset>6</bitOffset>
              <bitWidth>1</bitWidth>
            </field>
            <field>
              <name>BO</name>
              <bitOffset>7</bitOffset>
              <bitWidth>1</bitWidth>
            </field>
            <field>
              <name>DLEC</name>
              <bitOffset>8</bitOffset>
              <bitWidth>3</bitWidth>
            </field>
            <field>
              <name>RESI</name>
              <bitOffset>11</bitOffset>
              <bitWidth>1</bitWidth>
            </field>
            <field>
              <name>RBRS</name>
              <bitOffset>12</bitOffset>
              <bitWidth>1</bitWidth>
            </field>
            <field>
              <name>REDL</name>
              <bitOffset>13</bitOffset>
              <bitWidth>1</bitWidth>
            </field>
            <field>
              <name>PXE</name>
              <bitOffset>14</bitOffset>
              <bitWidth>1</bitWidth>
            </field>
            <field>
              <name>TDCV</name>
              <bitOffset>16</bitOffset>
              <bitWidth>7</bitWidth>
            </field>
          </fields>
        </register>
        <register>
          <name>TDCR</name>
          <addressOffset>0x48</addressOffset>
          <size>0x20</size>
          <fields>
            <field>
              <name>TDCF</name>
              <bitOffset>0</bitOffset>
              <bitWidth>7</bitWidth>
            </field>
            <field>
              <name>TDCO</name>
              <bitOffset>8</bitOffset>
              <bitWidth>7</bitWidth>
            </field>
          </fields>
        </register>
        <register>
          <name>IR</name>
          <addressOffset>0x50</addressOffset>
          <size>0x20</size>
          <fields>
            <field>
              <name>RF0N</name>
              <bitOffset>0</bitOffset>
              <bitWidth>1</bitWidth>
            </field>
            <field>
              <name>RF0W</name>
              <bitOffset>1</bitOffset>
              <bitWidth>1</bitWidth>
            </field>
            <field>
              <name>RF0F</name>
              <bitOffset>2</bitOffset>
              <bitWidth>1</bitWidth>
            </field>
            <field>
              <name>RF0L</name>
              <bitOffset>3</bitOffset>
              <bitWidth>1</bitWidth>
            </field>
            <field>
              <name>RF1N</name>
              <bitOffset>4</bitOffset>
              <bitWidth>1</bitWidth>
            </field>
            <field>
              <name>RF1W</name>
              <bitOffset>5</bitOffset>
              <bitWidth>1</bitWidth>
            </field>
            <field>
              <name>RF1F</name>
              <bitOffset>6</bitOffset>
              <bitWidth>1</bitWidth>
            </field>
            <field>
              <name>RF1L</name>
              <bitOffset>7</bitOffset>
              <bitWidth>1</bitWidth>
            </field>
            <field>
              <name>HPM</name>
              <bitOffset>8</bitOffset>
              <bitWidth>1</bitWidth>
            </field>
            <field>
              <name>TC</name>
              <bitOffset>9</bitOffset>
              <bitWidth>1</bitWidth>
            </field>
            <field>
              <name>TCF</name>
              <bitOffset>10</bitOffset>
              <bitWidth>1</bitWidth>
            </field>
            <field>
              <name>TFE</name>
              <bitOffset>11</bitOffset>
              <bitWidth>1</bitWidth>
            </field>
            <field>
              <name>TEFN</name>
              <bitOffset>12</bitOffset>
              <bitWidth>1</bitWidth>
            </field>
            <field>
              <name>TEFW</name>
              <bitOffset>13</bitOffset>
              <bitWidth>1</bitWidth>
            </field>
            <field>
              <name>TEFF</name>
              <bitOffset>14</bitOffset>
              <bitWidth>1</bitWidth>
            </field>
            <field>
              <name>TEFL</name>
              <bitOffset>15</bitOffset>
              <bitWidth>1</bitWidth>
            </field>
            <field>
              <name>TSW</name>
              <bitOffset>16</bitOffset>
              <bitWidth>1</bitWidth>
            </field>
            <field>
              <name>MRAF</name>
              <bitOffset>17</bitOffset>
              <bitWidth>1</bitWidth>
            </field>
            <field>
              <name>TOO</name>
              <bitOffset>18</bitOffset>
              <bitWidth>1</bitWidth>
            </field>
            <field>
              <name>DRX</name>
              <bitOffset>19</bitOffset>
              <bitWidth>1</bitWidth>
            </field>
            <field>
              <name>ELO</name>
              <bitOffset>22</bitOffset>
              <bitWidth>1</bitWidth>
            </field>
            <field>
              <name>EP</name>
              <bitOffset>23</bitOffset>
              <bitWidth>1</bitWidth>
            </field>
            <field>
              <name>EW</name>
              <bitOffset>24</bitOffset>
              <bitWidth>1</bitWidth>
            </field>
            <field>
              <name>BO</name>
              <bitOffset>25</bitOffset>
              <bitWidth>1</bitWidth>
            </field>
            <field>
              <name>WDI</name>
              <bitOffset>26</bitOffset>
              <bitWidth>1</bitWidth>
            </field>
            <field>
              <name>PEA</name>
              <bitOffset>27</bitOffset>
              <bitWidth>1</bitWidth>
            </field>
            <field>
              <name>PED</name>
              <bitOffset>28</bitOffset>
              <bitWidth>1</bitWidth>
            </field>
            <field>
              <name>ARA</name>
              <bitOffset>29</bitOffset>
              <bitWidth>1</bitWidth>
            </field>
          </fields>
        </register>
        <register>
          <name>IE</name>
          <addressOffset>0x54</addressOffset>
          <size>0x20</size>
          <fields>
            <field>
              <name>RF0NE</name>
              <bitOffset>0</bitOffset>
              <bitWidth>1</bitWidth>
            </field>
            <field>
              <name>RF0WE</name>
              <bitOffset>1</bitOffset>
              <bitWidth>1</bitWidth>
            </field>
            <field>
              <name>RF0FE</name>
              <bitOffset>2</bitOffset>
              <bitWidth>1</bitWidth>
            </field>
            <field>
              <name>RF0LE</name>
              <bitOffset>3</bitOffset>
              <bitWidth>1</bitWidth>
            </field>
            <field>
              <name>RF1NE</name>
              <bitOffset>4</bitOffset>
              <bitWidth>1</bitWidth>
            </field>
            <field>
              <name>RF1WE</name>
              <bitOffset>5</bitOffset>
              <bitWidth>1</bitWidth>
            </field>
            <field>
              <name>RF1FE</name>
              <bitOffset>6</bitOffset>
              <bitWidth>1</bitWidth>
            </field>
            <field>
              <name>RF1LE</name>
              <bitOffset>7</bitOffset>
              <bitWidth>1</bitWidth>
            </field>
            <field>
              <name>HPME</name>
              <bitOffset>8</bitOffset>
              <bitWidth>1</bitWidth>
            </field>
            <field>
              <name>TCE</name>
              <bitOffset>9</bitOffset>
              <bitWidth>1</bitWidth>
            </field>
            <field>
              <name>TCFE</name>
              <bitOffset>10</bitOffset>
              <bitWidth>1</bitWidth>
            </field>
            <field>
              <name>TFEE</name>
              <bitOffset>11</bitOffset>
              <bitWidth>1</bitWidth>
            </field>
            <field>
              <name>TEFNE</name>
              <bitOffset>12</bitOffset>
              <bitWidth>1</bitWidth>
            </field>
            <field>
              <name>TEFWE</name>
              <bitOffset>13</bitOffset>
              <bitWidth>1</bitWidth>
            </field>
            <field>
              <name>TEFFE</name>
              <bitOffset>14</bitOffset>
              <bitWidth>1</bitWidth>
            </field>
            <field>
              <name>TEFLE</name>
              <bitOffset>15</bitOffset>
              <bitWidth>1</bitWidth>
            </field>
            <field>
              <name>TSWE</name>
              <bitOffset>16</bitOffset>
              <bitWidth>1</bitWidth>
            </field>
            <field>
              <name>MRAFE</name>
              <bitOffset>17</bitOffset>
              <bitWidth>1</bitWidth>
            </field>
            <field>
              <name>TOOE</name>
              <bitOffset>18</bitOffset>
              <bitWidth>1</bitWidth>
            </field>
            <field>
              <name>DRXE</name>
              <bitOffset>19</bitOffset>
              <bitWidth>1</bitWidth>
            </field>
            <field>
              <name>BECE</name>
              <bitOffset>20</bitOffset>
              <bitWidth>1</bitWidth>
            </field>
            <field>
              <name>BEUE</name>
              <bitOffset>21</bitOffset>
              <bitWidth>1</bitWidth>
            </field>
            <field>
              <name>ELOE</name>
              <bitOffset>22</bitOffset>
              <bitWidth>1</bitWidth>
            </field>
            <field>
              <name>EPE</name>
              <bitOffset>23</bitOffset>
              <bitWidth>1</bitWidth>
            </field>
            <field>
              <name>EWE</name>
              <bitOffset>24</bitOffset>
              <bitWidth>1</bitWidth>
            </field>
            <field>
              <name>BOE</name>
              <bitOffset>25</bitOffset>
              <bitWidth>1</bitWidth>
            </field>
            <field>
              <name>WDIE</name>
              <bitOffset>26</bitOffset>
              <bitWidth>1</bitWidth>
            </field>
            <field>
              <name>PEAE</name>
              <bitOffset>27</bitOffset>
              <bitWidth>1</bitWidth>
            </field>
            <field>
              <name>PEDE</name>
              <bitOffset>28</bitOffset>
              <bitWidth>1</bitWidth>
            </field>
            <field>
              <name>ARAE</name>
              <bitOffset>29</bitOffset>
              <bitWidth>1</bitWidth>
            </field>
          </fields>
        </register>
        <register>
          <name>ILS</name>
          <addressOffset>0x58</addressOffset>
          <size>0x20</size>
          <fields>
            <field>
              <name>RF0NL</name>
              <bitOffset>0</bitOffset>
              <bitWidth>1</bitWidth>
            </field>
            <field>
              <name>RF0WL</name>
              <bitOffset>1</bitOffset>
              <bitWidth>1</bitWidth>
            </field>
            <field>
              <name>RF0FL</name>
              <bitOffset>2</bitOffset>
              <bitWidth>1</bitWidth>
            </field>
            <field>
              <name>RF0LL</name>
              <bitOffset>3</bitOffset>
              <bitWidth>1</bitWidth>
            </field>
            <field>
              <name>RF1NL</name>
              <bitOffset>4</bitOffset>
              <bitWidth>1</bitWidth>
            </field>
            <field>
              <name>RF1WL</name>
              <bitOffset>5</bitOffset>
              <bitWidth>1</bitWidth>
            </field>
            <field>
              <name>RF1FL</name>
              <bitOffset>6</bitOffset>
              <bitWidth>1</bitWidth>
            </field>
            <field>
              <name>RF1LL</name>
              <bitOffset>7</bitOffset>
              <bitWidth>1</bitWidth>
            </field>
            <field>
              <name>HPML</name>
              <bitOffset>8</bitOffset>
              <bitWidth>1</bitWidth>
            </field>
            <field>
              <name>TCL</name>
              <bitOffset>9</bitOffset>
              <bitWidth>1</bitWidth>
            </field>
            <field>
              <name>TCFL</name>
              <bitOffset>10</bitOffset>
              <bitWidth>1</bitWidth>
            </field>
            <field>
              <name>TFEL</name>
              <bitOffset>11</bitOffset>
              <bitWidth>1</bitWidth>
            </field>
            <field>
              <name>TEFNL</name>
              <bitOffset>12</bitOffset>
              <bitWidth>1</bitWidth>
            </field>
            <field>
              <name>TEFWL</name>
              <bitOffset>13</bitOffset>
              <bitWidth>1</bitWidth>
            </field>
            <field>
              <name>TEFFL</name>
              <bitOffset>14</bitOffset>
              <bitWidth>1</bitWidth>
            </field>
            <field>
              <name>TEFLL</name>
              <bitOffset>15</bitOffset>
              <bitWidth>1</bitWidth>
            </field>
            <field>
              <name>TSWL</name>
              <bitOffset>16</bitOffset>
              <bitWidth>1</bitWidth>
            </field>
            <field>
              <name>MRAFE</name>
              <bitOffset>17</bitOffset>
              <bitWidth>1</bitWidth>
            </field>
            <field>
              <name>TOOE</name>
              <bitOffset>18</bitOffset>
              <bitWidth>1</bitWidth>
            </field>
            <field>
              <name>DRXE</name>
              <bitOffset>19</bitOffset>
              <bitWidth>1</bitWidth>
            </field>
            <field>
              <name>BECE</name>
              <bitOffset>20</bitOffset>
              <bitWidth>1</bitWidth>
            </field>
            <field>
              <name>BEUE</name>
              <bitOffset>21</bitOffset>
              <bitWidth>1</bitWidth>
            </field>
            <field>
              <name>ELOE</name>
              <bitOffset>22</bitOffset>
              <bitWidth>1</bitWidth>
            </field>
            <field>
              <name>EPE</name>
              <bitOffset>23</bitOffset>
              <bitWidth>1</bitWidth>
            </field>
            <field>
              <name>EWE</name>
              <bitOffset>24</bitOffset>
              <bitWidth>1</bitWidth>
            </field>
            <field>
              <name>BOE</name>
              <bitOffset>25</bitOffset>
              <bitWidth>1</bitWidth>
            </field>
            <field>
              <name>WDIE</name>
              <bitOffset>26</bitOffset>
              <bitWidth>1</bitWidth>
            </field>
            <field>
              <name>PEAE</name>
              <bitOffset>27</bitOffset>
              <bitWidth>1</bitWidth>
            </field>
            <field>
              <name>PEDE</name>
              <bitOffset>28</bitOffset>
              <bitWidth>1</bitWidth>
            </field>
            <field>
              <name>ARAE</name>
              <bitOffset>29</bitOffset>
              <bitWidth>1</bitWidth>
            </field>
          </fields>
        </register>
        <register>
          <name>ILE</name>
          <addressOffset>0x5c</addressOffset>
          <size>0x20</size>
          <fields>
            <field>
              <name>EINT0</name>
              <bitOffset>0</bitOffset>
              <bitWidth>1</bitWidth>
            </field>
            <field>
              <name>EINT1</name>
              <bitOffset>1</bitOffset>
              <bitWidth>1</bitWidth>
            </field>
          </fields>
        </register>
        <register>
          <name>GFC</name>
          <addressOffset>0x80</addressOffset>
          <size>0x20</size>
          <fields>
            <field>
              <name>RRFE</name>
              <bitOffset>0</bitOffset>
              <bitWidth>1</bitWidth>
            </field>
            <field>
              <name>RRFS</name>
              <bitOffset>1</bitOffset>
              <bitWidth>1</bitWidth>
            </field>
            <field>
              <name>ANFE</name>
              <bitOffset>2</bitOffset>
              <bitWidth>2</bitWidth>
            </field>
            <field>
              <name>ANFS</name>
              <bitOffset>4</bitOffset>
              <bitWidth>2</bitWidth>
            </field>
          </fields>
        </register>
        <register>
          <name>SIDFC</name>
          <addressOffset>0x84</addressOffset>
          <size>0x20</size>
          <fields>
            <field>
              <name>FLSSA</name>
              <bitOffset>2</bitOffset>
              <bitWidth>14</bitWidth>
            </field>
            <field>
              <name>LSS</name>
              <bitOffset>16</bitOffset>
              <bitWidth>8</bitWidth>
            </field>
          </fields>
        </register>
        <register>
          <name>XIDFC</name>
          <addressOffset>0x88</addressOffset>
          <size>0x20</size>
          <fields>
            <field>
              <name>FLESA</name>
              <bitOffset>2</bitOffset>
              <bitWidth>14</bitWidth>
            </field>
            <field>
              <name>LSE</name>
              <bitOffset>16</bitOffset>
              <bitWidth>7</bitWidth>
            </field>
          </fields>
        </register>
        <register>
          <name>XIDAM</name>
          <addressOffset>0x90</addressOffset>
          <size>0x20</size>
          <fields>
            <field>
              <name>EIDM</name>
              <bitOffset>0</bitOffset>
              <bitWidth>29</bitWidth>
            </field>
          </fields>
        </register>
        <register>
          <name>HPMS</name>
          <addressOffset>0x94</addressOffset>
          <size>0x20</size>
          <fields>
            <field>
              <name>BIDX</name>
              <bitOffset>0</bitOffset>
              <bitWidth>6</bitWidth>
            </field>
            <field>
              <name>MSI</name>
              <bitOffset>6</bitOffset>
              <bitWidth>2</bitWidth>
            </field>
            <field>
              <name>FIDX</name>
              <bitOffset>8</bitOffset>
              <bitWidth>7</bitWidth>
            </field>
            <field>
              <name>FLST</name>
              <bitOffset>15</bitOffset>
              <bitWidth>1</bitWidth>
            </field>
          </fields>
        </register>
        <register>
          <name>NDAT1</name>
          <addressOffset>0x98</addressOffset>
          <size>0x20</size>
          <fields>
            <field>
              <name>ND0</name>
              <bitOffset>0</bitOffset>
              <bitWidth>1</bitWidth>
            </field>
            <field>
              <name>ND1</name>
              <bitOffset>1</bitOffset>
              <bitWidth>1</bitWidth>
            </field>
            <field>
              <name>ND2</name>
              <bitOffset>2</bitOffset>
              <bitWidth>1</bitWidth>
            </field>
            <field>
              <name>ND3</name>
              <bitOffset>3</bitOffset>
              <bitWidth>1</bitWidth>
            </field>
            <field>
              <name>ND4</name>
              <bitOffset>4</bitOffset>
              <bitWidth>1</bitWidth>
            </field>
            <field>
              <name>ND5</name>
              <bitOffset>5</bitOffset>
              <bitWidth>1</bitWidth>
            </field>
            <field>
              <name>ND6</name>
              <bitOffset>6</bitOffset>
              <bitWidth>1</bitWidth>
            </field>
            <field>
              <name>ND7</name>
              <bitOffset>7</bitOffset>
              <bitWidth>1</bitWidth>
            </field>
            <field>
              <name>ND8</name>
              <bitOffset>8</bitOffset>
              <bitWidth>1</bitWidth>
            </field>
            <field>
              <name>ND9</name>
              <bitOffset>9</bitOffset>
              <bitWidth>1</bitWidth>
            </field>
            <field>
              <name>ND10</name>
              <bitOffset>10</bitOffset>
              <bitWidth>1</bitWidth>
            </field>
            <field>
              <name>ND11</name>
              <bitOffset>11</bitOffset>
              <bitWidth>1</bitWidth>
            </field>
            <field>
              <name>ND12</name>
              <bitOffset>12</bitOffset>
              <bitWidth>1</bitWidth>
            </field>
            <field>
              <name>ND13</name>
              <bitOffset>13</bitOffset>
              <bitWidth>1</bitWidth>
            </field>
            <field>
              <name>ND14</name>
              <bitOffset>14</bitOffset>
              <bitWidth>1</bitWidth>
            </field>
            <field>
              <name>ND15</name>
              <bitOffset>15</bitOffset>
              <bitWidth>1</bitWidth>
            </field>
            <field>
              <name>ND16</name>
              <bitOffset>16</bitOffset>
              <bitWidth>1</bitWidth>
            </field>
            <field>
              <name>ND17</name>
              <bitOffset>17</bitOffset>
              <bitWidth>1</bitWidth>
            </field>
            <field>
              <name>ND18</name>
              <bitOffset>18</bitOffset>
              <bitWidth>1</bitWidth>
            </field>
            <field>
              <name>ND19</name>
              <bitOffset>19</bitOffset>
              <bitWidth>1</bitWidth>
            </field>
            <field>
              <name>ND20</name>
              <bitOffset>20</bitOffset>
              <bitWidth>1</bitWidth>
            </field>
            <field>
              <name>ND21</name>
              <bitOffset>21</bitOffset>
              <bitWidth>1</bitWidth>
            </field>
            <field>
              <name>ND22</name>
              <bitOffset>22</bitOffset>
              <bitWidth>1</bitWidth>
            </field>
            <field>
              <name>ND23</name>
              <bitOffset>23</bitOffset>
              <bitWidth>1</bitWidth>
            </field>
            <field>
              <name>ND24</name>
              <bitOffset>24</bitOffset>
              <bitWidth>1</bitWidth>
            </field>
            <field>
              <name>ND25</name>
              <bitOffset>25</bitOffset>
              <bitWidth>1</bitWidth>
            </field>
            <field>
              <name>ND26</name>
              <bitOffset>26</bitOffset>
              <bitWidth>1</bitWidth>
            </field>
            <field>
              <name>ND27</name>
              <bitOffset>27</bitOffset>
              <bitWidth>1</bitWidth>
            </field>
            <field>
              <name>ND28</name>
              <bitOffset>28</bitOffset>
              <bitWidth>1</bitWidth>
            </field>
            <field>
              <name>ND29</name>
              <bitOffset>29</bitOffset>
              <bitWidth>1</bitWidth>
            </field>
            <field>
              <name>ND30</name>
              <bitOffset>30</bitOffset>
              <bitWidth>1</bitWidth>
            </field>
            <field>
              <name>ND31</name>
              <bitOffset>31</bitOffset>
              <bitWidth>1</bitWidth>
            </field>
          </fields>
        </register>
        <register>
          <name>NDAT2</name>
          <addressOffset>0x9c</addressOffset>
          <size>0x20</size>
          <fields>
            <field>
              <name>ND32</name>
              <bitOffset>0</bitOffset>
              <bitWidth>1</bitWidth>
            </field>
            <field>
              <name>ND33</name>
              <bitOffset>1</bitOffset>
              <bitWidth>1</bitWidth>
            </field>
            <field>
              <name>ND34</name>
              <bitOffset>2</bitOffset>
              <bitWidth>1</bitWidth>
            </field>
            <field>
              <name>ND35</name>
              <bitOffset>3</bitOffset>
              <bitWidth>1</bitWidth>
            </field>
            <field>
              <name>ND36</name>
              <bitOffset>4</bitOffset>
              <bitWidth>1</bitWidth>
            </field>
            <field>
              <name>ND37</name>
              <bitOffset>5</bitOffset>
              <bitWidth>1</bitWidth>
            </field>
            <field>
              <name>ND38</name>
              <bitOffset>6</bitOffset>
              <bitWidth>1</bitWidth>
            </field>
            <field>
              <name>ND39</name>
              <bitOffset>7</bitOffset>
              <bitWidth>1</bitWidth>
            </field>
            <field>
              <name>ND40</name>
              <bitOffset>8</bitOffset>
              <bitWidth>1</bitWidth>
            </field>
            <field>
              <name>ND41</name>
              <bitOffset>9</bitOffset>
              <bitWidth>1</bitWidth>
            </field>
            <field>
              <name>ND42</name>
              <bitOffset>10</bitOffset>
              <bitWidth>1</bitWidth>
            </field>
            <field>
              <name>ND43</name>
              <bitOffset>11</bitOffset>
              <bitWidth>1</bitWidth>
            </field>
            <field>
              <name>ND44</name>
              <bitOffset>12</bitOffset>
              <bitWidth>1</bitWidth>
            </field>
            <field>
              <name>ND45</name>
              <bitOffset>13</bitOffset>
              <bitWidth>1</bitWidth>
            </field>
            <field>
              <name>ND46</name>
              <bitOffset>14</bitOffset>
              <bitWidth>1</bitWidth>
            </field>
            <field>
              <name>ND47</name>
              <bitOffset>15</bitOffset>
              <bitWidth>1</bitWidth>
            </field>
            <field>
              <name>ND48</name>
              <bitOffset>16</bitOffset>
              <bitWidth>1</bitWidth>
            </field>
            <field>
              <name>ND49</name>
              <bitOffset>17</bitOffset>
              <bitWidth>1</bitWidth>
            </field>
            <field>
              <name>ND50</name>
              <bitOffset>18</bitOffset>
              <bitWidth>1</bitWidth>
            </field>
            <field>
              <name>ND51</name>
              <bitOffset>19</bitOffset>
              <bitWidth>1</bitWidth>
            </field>
            <field>
              <name>ND52</name>
              <bitOffset>20</bitOffset>
              <bitWidth>1</bitWidth>
            </field>
            <field>
              <name>ND53</name>
              <bitOffset>21</bitOffset>
              <bitWidth>1</bitWidth>
            </field>
            <field>
              <name>ND54</name>
              <bitOffset>22</bitOffset>
              <bitWidth>1</bitWidth>
            </field>
            <field>
              <name>ND55</name>
              <bitOffset>23</bitOffset>
              <bitWidth>1</bitWidth>
            </field>
            <field>
              <name>ND56</name>
              <bitOffset>24</bitOffset>
              <bitWidth>1</bitWidth>
            </field>
            <field>
              <name>ND57</name>
              <bitOffset>25</bitOffset>
              <bitWidth>1</bitWidth>
            </field>
            <field>
              <name>ND58</name>
              <bitOffset>26</bitOffset>
              <bitWidth>1</bitWidth>
            </field>
            <field>
              <name>ND59</name>
              <bitOffset>27</bitOffset>
              <bitWidth>1</bitWidth>
            </field>
            <field>
              <name>ND60</name>
              <bitOffset>28</bitOffset>
              <bitWidth>1</bitWidth>
            </field>
            <field>
              <name>ND61</name>
              <bitOffset>29</bitOffset>
              <bitWidth>1</bitWidth>
            </field>
            <field>
              <name>ND62</name>
              <bitOffset>30</bitOffset>
              <bitWidth>1</bitWidth>
            </field>
            <field>
              <name>ND63</name>
              <bitOffset>31</bitOffset>
              <bitWidth>1</bitWidth>
            </field>
          </fields>
        </register>
        <register>
          <name>RXF0C</name>
          <addressOffset>0xa0</addressOffset>
          <size>0x20</size>
          <fields>
            <field>
              <name>F0SA</name>
              <bitOffset>2</bitOffset>
              <bitWidth>14</bitWidth>
            </field>
            <field>
              <name>F0S</name>
              <bitOffset>16</bitOffset>
              <bitWidth>7</bitWidth>
            </field>
            <field>
              <name>F0WM</name>
              <bitOffset>24</bitOffset>
              <bitWidth>7</bitWidth>
            </field>
            <field>
              <name>F0OM</name>
              <bitOffset>31</bitOffset>
              <bitWidth>1</bitWidth>
            </field>
          </fields>
        </register>
        <register>
          <name>RXF0S</name>
          <addressOffset>0xa4</addressOffset>
          <size>0x20</size>
          <fields>
            <field>
              <name>F0FL</name>
              <bitOffset>0</bitOffset>
              <bitWidth>7</bitWidth>
            </field>
            <field>
              <name>F0GI</name>
              <bitOffset>8</bitOffset>
              <bitWidth>6</bitWidth>
            </field>
            <field>
              <name>F0PI</name>
              <bitOffset>16</bitOffset>
              <bitWidth>6</bitWidth>
            </field>
            <field>
              <name>F0F</name>
              <bitOffset>24</bitOffset>
              <bitWidth>1</bitWidth>
            </field>
            <field>
              <name>RF0L</name>
              <bitOffset>25</bitOffset>
              <bitWidth>1</bitWidth>
            </field>
          </fields>
        </register>
        <register>
          <name>RXF0A</name>
          <addressOffset>0xa8</addressOffset>
          <size>0x20</size>
          <fields>
            <field>
              <name>F0AI</name>
              <bitOffset>0</bitOffset>
              <bitWidth>6</bitWidth>
            </field>
          </fields>
        </register>
        <register>
          <name>RXBC</name>
          <addressOffset>0xac</addressOffset>
          <size>0x20</size>
          <fields>
            <field>
              <name>RBSA</name>
              <bitOffset>2</bitOffset>
              <bitWidth>14</bitWidth>
            </field>
          </fields>
        </register>
        <register>
          <name>RXF1C</name>
          <addressOffset>0xb0</addressOffset>
          <size>0x20</size>
          <fields>
            <field>
              <name>F1SA</name>
              <bitOffset>2</bitOffset>
              <bitWidth>14</bitWidth>
            </field>
            <field>
              <name>F1S</name>
              <bitOffset>16</bitOffset>
              <bitWidth>7</bitWidth>
            </field>
            <field>
              <name>F1WM</name>
              <bitOffset>24</bitOffset>
              <bitWidth>7</bitWidth>
            </field>
            <field>
              <name>F1OM</name>
              <bitOffset>31</bitOffset>
              <bitWidth>1</bitWidth>
            </field>
          </fields>
        </register>
        <register>
          <name>RXF1S</name>
          <addressOffset>0xb4</addressOffset>
          <size>0x20</size>
          <fields>
            <field>
              <name>F1FL</name>
              <bitOffset>0</bitOffset>
              <bitWidth>7</bitWidth>
            </field>
            <field>
              <name>F1GI</name>
              <bitOffset>8</bitOffset>
              <bitWidth>6</bitWidth>
            </field>
            <field>
              <name>F1PI</name>
              <bitOffset>16</bitOffset>
              <bitWidth>6</bitWidth>
            </field>
            <field>
              <name>F1F</name>
              <bitOffset>24</bitOffset>
              <bitWidth>1</bitWidth>
            </field>
            <field>
              <name>RF1L</name>
              <bitOffset>25</bitOffset>
              <bitWidth>1</bitWidth>
            </field>
          </fields>
        </register>
        <register>
          <name>RXF1A</name>
          <addressOffset>0xb8</addressOffset>
          <size>0x20</size>
          <fields>
            <field>
              <name>F1AI</name>
              <bitOffset>0</bitOffset>
              <bitWidth>6</bitWidth>
            </field>
          </fields>
        </register>
        <register>
          <name>RXESC</name>
          <addressOffset>0xbc</addressOffset>
          <size>0x20</size>
          <fields>
            <field>
              <name>F0DS</name>
              <bitOffset>0</bitOffset>
              <bitWidth>3</bitWidth>
            </field>
            <field>
              <name>F1DS</name>
              <bitOffset>4</bitOffset>
              <bitWidth>3</bitWidth>
            </field>
            <field>
              <name>RBDS</name>
              <bitOffset>8</bitOffset>
              <bitWidth>3</bitWidth>
            </field>
          </fields>
        </register>
        <register>
          <name>TXBC</name>
          <addressOffset>0xc0</addressOffset>
          <size>0x20</size>
          <fields>
            <field>
              <name>TBSA</name>
              <bitOffset>2</bitOffset>
              <bitWidth>14</bitWidth>
            </field>
            <field>
              <name>NDTB</name>
              <bitOffset>16</bitOffset>
              <bitWidth>6</bitWidth>
            </field>
            <field>
              <name>TFQS</name>
              <bitOffset>24</bitOffset>
              <bitWidth>6</bitWidth>
            </field>
            <field>
              <name>TFQM</name>
              <bitOffset>30</bitOffset>
              <bitWidth>1</bitWidth>
            </field>
          </fields>
        </register>
        <register>
          <name>TXFQS</name>
          <addressOffset>0xc4</addressOffset>
          <size>0x20</size>
          <fields>
            <field>
              <name>TFFL</name>
              <bitOffset>0</bitOffset>
              <bitWidth>6</bitWidth>
            </field>
            <field>
              <name>TFGI</name>
              <bitOffset>8</bitOffset>
              <bitWidth>5</bitWidth>
            </field>
            <field>
              <name>TFQPI</name>
              <bitOffset>16</bitOffset>
              <bitWidth>5</bitWidth>
            </field>
            <field>
              <name>TFQF</name>
              <bitOffset>21</bitOffset>
              <bitWidth>1</bitWidth>
            </field>
          </fields>
        </register>
        <register>
          <name>TXESC</name>
          <addressOffset>0xc8</addressOffset>
          <size>0x20</size>
          <fields>
            <field>
              <name>TBDS</name>
              <bitOffset>0</bitOffset>
              <bitWidth>3</bitWidth>
            </field>
          </fields>
        </register>
        <register>
          <name>TXBRP</name>
          <addressOffset>0xcc</addressOffset>
          <size>0x20</size>
          <fields>
            <field>
              <name>TRP</name>
              <bitOffset>0</bitOffset>
              <bitWidth>32</bitWidth>
            </field>
          </fields>
        </register>
        <register>
          <name>TXBAR</name>
          <addressOffset>0xd0</addressOffset>
          <size>0x20</size>
          <fields>
            <field>
              <name>AR</name>
              <bitOffset>0</bitOffset>
              <bitWidth>32</bitWidth>
            </field>
          </fields>
        </register>
        <register>
          <name>TXBCR</name>
          <addressOffset>0xd4</addressOffset>
          <size>0x20</size>
          <fields>
            <field>
              <name>CR</name>
              <bitOffset>0</bitOffset>
              <bitWidth>32</bitWidth>
            </field>
          </fields>
        </register>
        <register>
          <name>TXBTO</name>
          <addressOffset>0xd8</addressOffset>
          <size>0x20</size>
          <fields>
            <field>
              <name>TO</name>
              <bitOffset>0</bitOffset>
              <bitWidth>32</bitWidth>
            </field>
          </fields>
        </register>
        <register>
          <name>TXBCF</name>
          <addressOffset>0xdc</addressOffset>
          <size>0x20</size>
          <fields>
            <field>
              <name>CF</name>
              <bitOffset>0</bitOffset>
              <bitWidth>32</bitWidth>
            </field>
          </fields>
        </register>
        <register>
          <name>TXBTIE</name>
          <addressOffset>0xe0</addressOffset>
          <size>0x20</size>
          <fields>
            <field>
              <name>TIE</name>
              <bitOffset>0</bitOffset>
              <bitWidth>32</bitWidth>
            </field>
          </fields>
        </register>
        <register>
          <name>TXBCIE</name>
          <addressOffset>0xe4</addressOffset>
          <size>0x20</size>
          <fields>
            <field>
              <name>CFIE</name>
              <bitOffset>0</bitOffset>
              <bitWidth>32</bitWidth>
            </field>
          </fields>
        </register>
        <register>
          <name>TXEFC</name>
          <addressOffset>0xf0</addressOffset>
          <size>0x20</size>
          <fields>
            <field>
              <name>EFSA</name>
              <bitOffset>2</bitOffset>
              <bitWidth>14</bitWidth>
            </field>
            <field>
              <name>EFS</name>
              <bitOffset>16</bitOffset>
              <bitWidth>6</bitWidth>
            </field>
            <field>
              <name>EFWM</name>
              <bitOffset>24</bitOffset>
              <bitWidth>6</bitWidth>
            </field>
          </fields>
        </register>
        <register>
          <name>TXEFS</name>
          <addressOffset>0xf4</addressOffset>
          <size>0x20</size>
          <fields>
            <field>
              <name>EFFL</name>
              <bitOffset>0</bitOffset>
              <bitWidth>6</bitWidth>
            </field>
            <field>
              <name>EFGI</name>
              <bitOffset>8</bitOffset>
              <bitWidth>5</bitWidth>
            </field>
            <field>
              <name>EFPI</name>
              <bitOffset>16</bitOffset>
              <bitWidth>5</bitWidth>
            </field>
            <field>
              <name>EFF</name>
              <bitOffset>24</bitOffset>
              <bitWidth>1</bitWidth>
            </field>
            <field>
              <name>TEFL</name>
              <bitOffset>25</bitOffset>
              <bitWidth>1</bitWidth>
            </field>
          </fields>
        </register>
        <register>
          <name>TXEFA</name>
          <addressOffset>0xf8</addressOffset>
          <size>0x20</size>
          <fields>
            <field>
              <name>EFAI</name>
              <bitOffset>0</bitOffset>
              <bitWidth>5</bitWidth>
            </field>
          </fields>
        </register>
      </registers>
    </peripheral>
    <peripheral>
      <name>FDCAN2</name>
      <baseAddress>0x4000a400</baseAddress>
      <registers>
        <register>
          <name>CREL</name>
          <addressOffset>0x0</addressOffset>
          <size>0x20</size>
          <fields>
            <field>
              <name>DAY</name>
              <bitOffset>0</bitOffset>
              <bitWidth>8</bitWidth>
            </field>
            <field>
              <name>MON</name>
              <bitOffset>8</bitOffset>
              <bitWidth>8</bitWidth>
            </field>
            <field>
              <name>YEAR</name>
              <bitOffset>16</bitOffset>
              <bitWidth>4</bitWidth>
            </field>
            <field>
              <name>SUBSTEP</name>
              <bitOffset>20</bitOffset>
              <bitWidth>4</bitWidth>
            </field>
            <field>
              <name>STEP</name>
              <bitOffset>24</bitOffset>
              <bitWidth>4</bitWidth>
            </field>
            <field>
              <name>REL</name>
              <bitOffset>28</bitOffset>
              <bitWidth>4</bitWidth>
            </field>
          </fields>
        </register>
        <register>
          <name>ENDN</name>
          <addressOffset>0x4</addressOffset>
          <size>0x20</size>
          <fields>
            <field>
              <name>ETV</name>
              <bitOffset>0</bitOffset>
              <bitWidth>32</bitWidth>
            </field>
          </fields>
        </register>
        <register>
          <name>DBTP</name>
          <addressOffset>0xc</addressOffset>
          <size>0x20</size>
          <fields>
            <field>
              <name>DSJW</name>
              <bitOffset>0</bitOffset>
              <bitWidth>4</bitWidth>
            </field>
            <field>
              <name>DTSEG2</name>
              <bitOffset>4</bitOffset>
              <bitWidth>4</bitWidth>
            </field>
            <field>
              <name>DTSEG1</name>
              <bitOffset>8</bitOffset>
              <bitWidth>5</bitWidth>
            </field>
            <field>
              <name>DBRP</name>
              <bitOffset>16</bitOffset>
              <bitWidth>5</bitWidth>
            </field>
            <field>
              <name>TDC</name>
              <bitOffset>23</bitOffset>
              <bitWidth>1</bitWidth>
            </field>
          </fields>
        </register>
        <register>
          <name>TEST</name>
          <addressOffset>0x10</addressOffset>
          <size>0x20</size>
          <fields>
            <field>
              <name>LBCK</name>
              <bitOffset>4</bitOffset>
              <bitWidth>1</bitWidth>
            </field>
            <field>
              <name>TX</name>
              <bitOffset>5</bitOffset>
              <bitWidth>2</bitWidth>
            </field>
            <field>
              <name>RX</name>
              <bitOffset>7</bitOffset>
              <bitWidth>1</bitWidth>
            </field>
          </fields>
        </register>
        <register>
          <name>RWD</name>
          <addressOffset>0x14</addressOffset>
          <size>0x20</size>
          <fields>
            <field>
              <name>WDC</name>
              <bitOffset>0</bitOffset>
              <bitWidth>8</bitWidth>
            </field>
            <field>
              <name>WDV</name>
              <bitOffset>8</bitOffset>
              <bitWidth>8</bitWidth>
            </field>
          </fields>
        </register>
        <register>
          <name>CCCR</name>
          <addressOffset>0x18</addressOffset>
          <size>0x20</size>
          <fields>
            <field>
              <name>INIT</name>
              <bitOffset>0</bitOffset>
              <bitWidth>1</bitWidth>
            </field>
            <field>
              <name>CCE</name>
              <bitOffset>1</bitOffset>
              <bitWidth>1</bitWidth>
            </field>
            <field>
              <name>ASM</name>
              <bitOffset>2</bitOffset>
              <bitWidth>1</bitWidth>
            </field>
            <field>
              <name>CSA</name>
              <bitOffset>3</bitOffset>
              <bitWidth>1</bitWidth>
            </field>
            <field>
              <name>CSR</name>
              <bitOffset>4</bitOffset>
              <bitWidth>1</bitWidth>
            </field>
            <field>
              <name>MON</name>
              <bitOffset>5</bitOffset>
              <bitWidth>1</bitWidth>
            </field>
            <field>
              <name>DAR</name>
              <bitOffset>6</bitOffset>
              <bitWidth>1</bitWidth>
            </field>
            <field>
              <name>TEST</name>
              <bitOffset>7</bitOffset>
              <bitWidth>1</bitWidth>
            </field>
            <field>
              <name>FDOE</name>
              <bitOffset>8</bitOffset>
              <bitWidth>1</bitWidth>
            </field>
            <field>
              <name>BRSE</name>
              <bitOffset>9</bitOffset>
              <bitWidth>1</bitWidth>
            </field>
            <field>
              <name>PXHD</name>
              <bitOffset>12</bitOffset>
              <bitWidth>1</bitWidth>
            </field>
            <field>
              <name>EFBI</name>
              <bitOffset>13</bitOffset>
              <bitWidth>1</bitWidth>
            </field>
            <field>
              <name>TXP</name>
              <bitOffset>14</bitOffset>
              <bitWidth>1</bitWidth>
            </field>
            <field>
              <name>NISO</name>
              <bitOffset>15</bitOffset>
              <bitWidth>1</bitWidth>
            </field>
          </fields>
        </register>
        <register>
          <name>NBTP</name>
          <addressOffset>0x1c</addressOffset>
          <size>0x20</size>
          <fields>
            <field>
              <name>NTSEG2</name>
              <bitOffset>0</bitOffset>
              <bitWidth>7</bitWidth>
            </field>
            <field>
              <name>NTSEG1</name>
              <bitOffset>8</bitOffset>
              <bitWidth>8</bitWidth>
            </field>
            <field>
              <name>NBRP</name>
              <bitOffset>16</bitOffset>
              <bitWidth>9</bitWidth>
            </field>
            <field>
              <name>NSJW</name>
              <bitOffset>25</bitOffset>
              <bitWidth>7</bitWidth>
            </field>
          </fields>
        </register>
        <register>
          <name>TSCC</name>
          <addressOffset>0x20</addressOffset>
          <size>0x20</size>
          <fields>
            <field>
              <name>TSS</name>
              <bitOffset>0</bitOffset>
              <bitWidth>2</bitWidth>
            </field>
            <field>
              <name>TCP</name>
              <bitOffset>16</bitOffset>
              <bitWidth>4</bitWidth>
            </field>
          </fields>
        </register>
        <register>
          <name>TSCV</name>
          <addressOffset>0x24</addressOffset>
          <size>0x20</size>
          <fields>
            <field>
              <name>TSC</name>
              <bitOffset>0</bitOffset>
              <bitWidth>16</bitWidth>
            </field>
          </fields>
        </register>
        <register>
          <name>TOCC</name>
          <addressOffset>0x28</addressOffset>
          <size>0x20</size>
          <fields>
            <field>
              <name>ETOC</name>
              <bitOffset>0</bitOffset>
              <bitWidth>1</bitWidth>
            </field>
            <field>
              <name>TOS</name>
              <bitOffset>1</bitOffset>
              <bitWidth>2</bitWidth>
            </field>
            <field>
              <name>TOP</name>
              <bitOffset>16</bitOffset>
              <bitWidth>16</bitWidth>
            </field>
          </fields>
        </register>
        <register>
          <name>TOCV</name>
          <addressOffset>0x2c</addressOffset>
          <size>0x20</size>
          <fields>
            <field>
              <name>TOC</name>
              <bitOffset>0</bitOffset>
              <bitWidth>16</bitWidth>
            </field>
          </fields>
        </register>
        <register>
          <name>ECR</name>
          <addressOffset>0x40</addressOffset>
          <size>0x20</size>
          <fields>
            <field>
              <name>TEC</name>
              <bitOffset>0</bitOffset>
              <bitWidth>8</bitWidth>
            </field>
            <field>
              <name>REC</name>
              <bitOffset>8</bitOffset>
              <bitWidth>7</bitWidth>
            </field>
            <field>
              <name>RP</name>
              <bitOffset>15</bitOffset>
              <bitWidth>1</bitWidth>
            </field>
            <field>
              <name>CEL</name>
              <bitOffset>16</bitOffset>
              <bitWidth>8</bitWidth>
            </field>
          </fields>
        </register>
        <register>
          <name>PSR</name>
          <addressOffset>0x44</addressOffset>
          <size>0x20</size>
          <fields>
            <field>
              <name>LEC</name>
              <bitOffset>0</bitOffset>
              <bitWidth>3</bitWidth>
            </field>
            <field>
              <name>ACT</name>
              <bitOffset>3</bitOffset>
              <bitWidth>2</bitWidth>
            </field>
            <field>
              <name>EP</name>
              <bitOffset>5</bitOffset>
              <bitWidth>1</bitWidth>
            </field>
            <field>
              <name>EW</name>
              <bitOffset>6</bitOffset>
              <bitWidth>1</bitWidth>
            </field>
            <field>
              <name>BO</name>
              <bitOffset>7</bitOffset>
              <bitWidth>1</bitWidth>
            </field>
            <field>
              <name>DLEC</name>
              <bitOffset>8</bitOffset>
              <bitWidth>3</bitWidth>
            </field>
            <field>
              <name>RESI</name>
              <bitOffset>11</bitOffset>
              <bitWidth>1</bitWidth>
            </field>
            <field>
              <name>RBRS</name>
              <bitOffset>12</bitOffset>
              <bitWidth>1</bitWidth>
            </field>
            <field>
              <name>REDL</name>
              <bitOffset>13</bitOffset>
              <bitWidth>1</bitWidth>
            </field>
            <field>
              <name>PXE</name>
              <bitOffset>14</bitOffset>
              <bitWidth>1</bitWidth>
            </field>
            <field>
              <name>TDCV</name>
              <bitOffset>16</bitOffset>
              <bitWidth>7</bitWidth>
            </field>
          </fields>
        </register>
        <register>
          <name>TDCR</name>
          <addressOffset>0x48</addressOffset>
          <size>0x20</size>
          <fields>
            <field>
              <name>TDCF</name>
              <bitOffset>0</bitOffset>
              <bitWidth>7</bitWidth>
            </field>
            <field>
              <name>TDCO</name>
              <bitOffset>8</bitOffset>
              <bitWidth>7</bitWidth>
            </field>
          </fields>
        </register>
        <register>
          <name>IR</name>
          <addressOffset>0x50</addressOffset>
          <size>0x20</size>
          <fields>
            <field>
              <name>RF0N</name>
              <bitOffset>0</bitOffset>
              <bitWidth>1</bitWidth>
            </field>
            <field>
              <name>RF0W</name>
              <bitOffset>1</bitOffset>
              <bitWidth>1</bitWidth>
            </field>
            <field>
              <name>RF0F</name>
              <bitOffset>2</bitOffset>
              <bitWidth>1</bitWidth>
            </field>
            <field>
              <name>RF0L</name>
              <bitOffset>3</bitOffset>
              <bitWidth>1</bitWidth>
            </field>
            <field>
              <name>RF1N</name>
              <bitOffset>4</bitOffset>
              <bitWidth>1</bitWidth>
            </field>
            <field>
              <name>RF1W</name>
              <bitOffset>5</bitOffset>
              <bitWidth>1</bitWidth>
            </field>
            <field>
              <name>RF1F</name>
              <bitOffset>6</bitOffset>
              <bitWidth>1</bitWidth>
            </field>
            <field>
              <name>RF1L</name>
              <bitOffset>7</bitOffset>
              <bitWidth>1</bitWidth>
            </field>
            <field>
              <name>HPM</name>
              <bitOffset>8</bitOffset>
              <bitWidth>1</bitWidth>
            </field>
            <field>
              <name>TC</name>
              <bitOffset>9</bitOffset>
              <bitWidth>1</bitWidth>
            </field>
            <field>
              <name>TCF</name>
              <bitOffset>10</bitOffset>
              <bitWidth>1</bitWidth>
            </field>
            <field>
              <name>TFE</name>
              <bitOffset>11</bitOffset>
              <bitWidth>1</bitWidth>
            </field>
            <field>
              <name>TEFN</name>
              <bitOffset>12</bitOffset>
              <bitWidth>1</bitWidth>
            </field>
            <field>
              <name>TEFW</name>
              <bitOffset>13</bitOffset>
              <bitWidth>1</bitWidth>
            </field>
            <field>
              <name>TEFF</name>
              <bitOffset>14</bitOffset>
              <bitWidth>1</bitWidth>
            </field>
            <field>
              <name>TEFL</name>
              <bitOffset>15</bitOffset>
              <bitWidth>1</bitWidth>
            </field>
            <field>
              <name>TSW</name>
              <bitOffset>16</bitOffset>
              <bitWidth>1</bitWidth>
            </field>
            <field>
              <name>MRAF</name>
              <bitOffset>17</bitOffset>
              <bitWidth>1</bitWidth>
            </field>
            <field>
              <name>TOO</name>
              <bitOffset>18</bitOffset>
              <bitWidth>1</bitWidth>
            </field>
            <field>
              <name>DRX</name>
              <bitOffset>19</bitOffset>
              <bitWidth>1</bitWidth>
            </field>
            <field>
              <name>ELO</name>
              <bitOffset>22</bitOffset>
              <bitWidth>1</bitWidth>
            </field>
            <field>
              <name>EP</name>
              <bitOffset>23</bitOffset>
              <bitWidth>1</bitWidth>
            </field>
            <field>
              <name>EW</name>
              <bitOffset>24</bitOffset>
              <bitWidth>1</bitWidth>
            </field>
            <field>
              <name>BO</name>
              <bitOffset>25</bitOffset>
              <bitWidth>1</bitWidth>
            </field>
            <field>
              <name>WDI</name>
              <bitOffset>26</bitOffset>
              <bitWidth>1</bitWidth>
            </field>
            <field>
              <name>PEA</name>
              <bitOffset>27</bitOffset>
              <bitWidth>1</bitWidth>
            </field>
            <field>
              <name>PED</name>
              <bitOffset>28</bitOffset>
              <bitWidth>1</bitWidth>
            </field>
            <field>
              <name>ARA</name>
              <bitOffset>29</bitOffset>
              <bitWidth>1</bitWidth>
            </field>
          </fields>
        </register>
        <register>
          <name>IE</name>
          <addressOffset>0x54</addressOffset>
          <size>0x20</size>
          <fields>
            <field>
              <name>RF0NE</name>
              <bitOffset>0</bitOffset>
              <bitWidth>1</bitWidth>
            </field>
            <field>
              <name>RF0WE</name>
              <bitOffset>1</bitOffset>
              <bitWidth>1</bitWidth>
            </field>
            <field>
              <name>RF0FE</name>
              <bitOffset>2</bitOffset>
              <bitWidth>1</bitWidth>
            </field>
            <field>
              <name>RF0LE</name>
              <bitOffset>3</bitOffset>
              <bitWidth>1</bitWidth>
            </field>
            <field>
              <name>RF1NE</name>
              <bitOffset>4</bitOffset>
              <bitWidth>1</bitWidth>
            </field>
            <field>
              <name>RF1WE</name>
              <bitOffset>5</bitOffset>
              <bitWidth>1</bitWidth>
            </field>
            <field>
              <name>RF1FE</name>
              <bitOffset>6</bitOffset>
              <bitWidth>1</bitWidth>
            </field>
            <field>
              <name>RF1LE</name>
              <bitOffset>7</bitOffset>
              <bitWidth>1</bitWidth>
            </field>
            <field>
              <name>HPME</name>
              <bitOffset>8</bitOffset>
              <bitWidth>1</bitWidth>
            </field>
            <field>
              <name>TCE</name>
              <bitOffset>9</bitOffset>
              <bitWidth>1</bitWidth>
            </field>
            <field>
              <name>TCFE</name>
              <bitOffset>10</bitOffset>
              <bitWidth>1</bitWidth>
            </field>
            <field>
              <name>TFEE</name>
              <bitOffset>11</bitOffset>
              <bitWidth>1</bitWidth>
            </field>
            <field>
              <name>TEFNE</name>
              <bitOffset>12</bitOffset>
              <bitWidth>1</bitWidth>
            </field>
            <field>
              <name>TEFWE</name>
              <bitOffset>13</bitOffset>
              <bitWidth>1</bitWidth>
            </field>
            <field>
              <name>TEFFE</name>
              <bitOffset>14</bitOffset>
              <bitWidth>1</bitWidth>
            </field>
            <field>
              <name>TEFLE</name>
              <bitOffset>15</bitOffset>
              <bitWidth>1</bitWidth>
            </field>
            <field>
              <name>TSWE</name>
              <bitOffset>16</bitOffset>
              <bitWidth>1</bitWidth>
            </field>
            <field>
              <name>MRAFE</name>
              <bitOffset>17</bitOffset>
              <bitWidth>1</bitWidth>
            </field>
            <field>
              <name>TOOE</name>
              <bitOffset>18</bitOffset>
              <bitWidth>1</bitWidth>
            </field>
            <field>
              <name>DRXE</name>
              <bitOffset>19</bitOffset>
              <bitWidth>1</bitWidth>
            </field>
            <field>
              <name>BECE</name>
              <bitOffset>20</bitOffset>
              <bitWidth>1</bitWidth>
            </field>
            <field>
              <name>BEUE</name>
              <bitOffset>21</bitOffset>
              <bitWidth>1</bitWidth>
            </field>
            <field>
              <name>ELOE</name>
              <bitOffset>22</bitOffset>
              <bitWidth>1</bitWidth>
            </field>
            <field>
              <name>EPE</name>
              <bitOffset>23</bitOffset>
              <bitWidth>1</bitWidth>
            </field>
            <field>
              <name>EWE</name>
              <bitOffset>24</bitOffset>
              <bitWidth>1</bitWidth>
            </field>
            <field>
              <name>BOE</name>
              <bitOffset>25</bitOffset>
              <bitWidth>1</bitWidth>
            </field>
            <field>
              <name>WDIE</name>
              <bitOffset>26</bitOffset>
              <bitWidth>1</bitWidth>
            </field>
            <field>
              <name>PEAE</name>
              <bitOffset>27</bitOffset>
              <bitWidth>1</bitWidth>
            </field>
            <field>
              <name>PEDE</name>
              <bitOffset>28</bitOffset>
              <bitWidth>1</bitWidth>
            </field>
            <field>
              <name>ARAE</name>
              <bitOffset>29</bitOffset>
              <bitWidth>1</bitWidth>
            </field>
          </fields>
        </register>
        <register>
          <name>ILS</name>
          <addressOffset>0x58</addressOffset>
          <size>0x20</size>
          <fields>
            <field>
              <name>RF0NL</name>
              <bitOffset>0</bitOffset>
              <bitWidth>1</bitWidth>
            </field>
            <field>
              <name>RF0WL</name>
              <bitOffset>1</bitOffset>
              <bitWidth>1</bitWidth>
            </field>
            <field>
              <name>RF0FL</name>
              <bitOffset>2</bitOffset>
              <bitWidth>1</bitWidth>
            </field>
            <field>
              <name>RF0LL</name>
              <bitOffset>3</bitOffset>
              <bitWidth>1</bitWidth>
            </field>
            <field>
              <name>RF1NL</name>
              <bitOffset>4</bitOffset>
              <bitWidth>1</bitWidth>
            </field>
            <field>
              <name>RF1WL</name>
              <bitOffset>5</bitOffset>
              <bitWidth>1</bitWidth>
            </field>
            <field>
              <name>RF1FL</name>
              <bitOffset>6</bitOffset>
              <bitWidth>1</bitWidth>
            </field>
            <field>
              <name>RF1LL</name>
              <bitOffset>7</bitOffset>
              <bitWidth>1</bitWidth>
            </field>
            <field>
              <name>HPML</name>
              <bitOffset>8</bitOffset>
              <bitWidth>1</bitWidth>
            </field>
            <field>
              <name>TCL</name>
              <bitOffset>9</bitOffset>
              <bitWidth>1</bitWidth>
            </field>
            <field>
              <name>TCFL</name>
              <bitOffset>10</bitOffset>
              <bitWidth>1</bitWidth>
            </field>
            <field>
              <name>TFEL</name>
              <bitOffset>11</bitOffset>
              <bitWidth>1</bitWidth>
            </field>
            <field>
              <name>TEFNL</name>
              <bitOffset>12</bitOffset>
              <bitWidth>1</bitWidth>
            </field>
            <field>
              <name>TEFWL</name>
              <bitOffset>13</bitOffset>
              <bitWidth>1</bitWidth>
            </field>
            <field>
              <name>TEFFL</name>
              <bitOffset>14</bitOffset>
              <bitWidth>1</bitWidth>
            </field>
            <field>
              <name>TEFLL</name>
              <bitOffset>15</bitOffset>
              <bitWidth>1</bitWidth>
            </field>
            <field>
              <name>TSWL</name>
              <bitOffset>16</bitOffset>
              <bitWidth>1</bitWidth>
            </field>
            <field>
              <name>MRAFE</name>
              <bitOffset>17</bitOffset>
              <bitWidth>1</bitWidth>
            </field>
            <field>
              <name>TOOE</name>
              <bitOffset>18</bitOffset>
              <bitWidth>1</bitWidth>
            </field>
            <field>
              <name>DRXE</name>
              <bitOffset>19</bitOffset>
              <bitWidth>1</bitWidth>
            </field>
            <field>
              <name>BECE</name>
              <bitOffset>20</bitOffset>
              <bitWidth>1</bitWidth>
            </field>
            <field>
              <name>BEUE</name>
              <bitOffset>21</bitOffset>
              <bitWidth>1</bitWidth>
            </field>
            <field>
              <name>ELOE</name>
              <bitOffset>22</bitOffset>
              <bitWidth>1</bitWidth>
            </field>
            <field>
              <name>EPE</name>
              <bitOffset>23</bitOffset>
              <bitWidth>1</bitWidth>
            </field>
            <field>
              <name>EWE</name>
              <bitOffset>24</bitOffset>
              <bitWidth>1</bitWidth>
            </field>
            <field>
              <name>BOE</name>
              <bitOffset>25</bitOffset>
              <bitWidth>1</bitWidth>
            </field>
            <field>
              <name>WDIE</name>
              <bitOffset>26</bitOffset>
              <bitWidth>1</bitWidth>
            </field>
            <field>
              <name>PEAE</name>
              <bitOffset>27</bitOffset>
              <bitWidth>1</bitWidth>
            </field>
            <field>
              <name>PEDE</name>
              <bitOffset>28</bitOffset>
              <bitWidth>1</bitWidth>
            </field>
            <field>
              <name>ARAE</name>
              <bitOffset>29</bitOffset>
              <bitWidth>1</bitWidth>
            </field>
          </fields>
        </register>
        <register>
          <name>ILE</name>
          <addressOffset>0x5c</addressOffset>
          <size>0x20</size>
          <fields>
            <field>
              <name>EINT0</name>
              <bitOffset>0</bitOffset>
              <bitWidth>1</bitWidth>
            </field>
            <field>
              <name>EINT1</name>
              <bitOffset>1</bitOffset>
              <bitWidth>1</bitWidth>
            </field>
          </fields>
        </register>
        <register>
          <name>GFC</name>
          <addressOffset>0x80</addressOffset>
          <size>0x20</size>
          <fields>
            <field>
              <name>RRFE</name>
              <bitOffset>0</bitOffset>
              <bitWidth>1</bitWidth>
            </field>
            <field>
              <name>RRFS</name>
              <bitOffset>1</bitOffset>
              <bitWidth>1</bitWidth>
            </field>
            <field>
              <name>ANFE</name>
              <bitOffset>2</bitOffset>
              <bitWidth>2</bitWidth>
            </field>
            <field>
              <name>ANFS</name>
              <bitOffset>4</bitOffset>
              <bitWidth>2</bitWidth>
            </field>
          </fields>
        </register>
        <register>
          <name>SIDFC</name>
          <addressOffset>0x84</addressOffset>
          <size>0x20</size>
          <fields>
            <field>
              <name>FLSSA</name>
              <bitOffset>2</bitOffset>
              <bitWidth>14</bitWidth>
            </field>
            <field>
              <name>LSS</name>
              <bitOffset>16</bitOffset>
              <bitWidth>8</bitWidth>
            </field>
          </fields>
        </register>
        <register>
          <name>XIDFC</name>
          <addressOffset>0x88</addressOffset>
          <size>0x20</size>
          <fields>
            <field>
              <name>FLESA</name>
              <bitOffset>2</bitOffset>
              <bitWidth>14</bitWidth>
            </field>
            <field>
              <name>LSE</name>
              <bitOffset>16</bitOffset>
              <bitWidth>7</bitWidth>
            </field>
          </fields>
        </register>
        <register>
          <name>XIDAM</name>
          <addressOffset>0x90</addressOffset>
          <size>0x20</size>
          <fields>
            <field>
              <name>EIDM</name>
              <bitOffset>0</bitOffset>
              <bitWidth>29</bitWidth>
            </field>
          </fields>
        </register>
        <register>
          <name>HPMS</name>
          <addressOffset>0x94</addressOffset>
          <size>0x20</size>
          <fields>
            <field>
              <name>BIDX</name>
              <bitOffset>0</bitOffset>
              <bitWidth>6</bitWidth>
            </field>
            <field>
              <name>MSI</name>
              <bitOffset>6</bitOffset>
              <bitWidth>2</bitWidth>
            </field>
            <field>
              <name>FIDX</name>
              <bitOffset>8</bitOffset>
              <bitWidth>7</bitWidth>
            </field>
            <field>
              <name>FLST</name>
              <bitOffset>15</bitOffset>
              <bitWidth>1</bitWidth>
            </field>
          </fields>
        </register>
        <register>
          <name>NDAT1</name>
          <addressOffset>0x98</addressOffset>
          <size>0x20</size>
          <fields>
            <field>
              <name>ND0</name>
              <bitOffset>0</bitOffset>
              <bitWidth>1</bitWidth>
            </field>
            <field>
              <name>ND1</name>
              <bitOffset>1</bitOffset>
              <bitWidth>1</bitWidth>
            </field>
            <field>
              <name>ND2</name>
              <bitOffset>2</bitOffset>
              <bitWidth>1</bitWidth>
            </field>
            <field>
              <name>ND3</name>
              <bitOffset>3</bitOffset>
              <bitWidth>1</bitWidth>
            </field>
            <field>
              <name>ND4</name>
              <bitOffset>4</bitOffset>
              <bitWidth>1</bitWidth>
            </field>
            <field>
              <name>ND5</name>
              <bitOffset>5</bitOffset>
              <bitWidth>1</bitWidth>
            </field>
            <field>
              <name>ND6</name>
              <bitOffset>6</bitOffset>
              <bitWidth>1</bitWidth>
            </field>
            <field>
              <name>ND7</name>
              <bitOffset>7</bitOffset>
              <bitWidth>1</bitWidth>
            </field>
            <field>
              <name>ND8</name>
              <bitOffset>8</bitOffset>
              <bitWidth>1</bitWidth>
            </field>
            <field>
              <name>ND9</name>
              <bitOffset>9</bitOffset>
              <bitWidth>1</bitWidth>
            </field>
            <field>
              <name>ND10</name>
              <bitOffset>10</bitOffset>
              <bitWidth>1</bitWidth>
            </field>
            <field>
              <name>ND11</name>
              <bitOffset>11</bitOffset>
              <bitWidth>1</bitWidth>
            </field>
            <field>
              <name>ND12</name>
              <bitOffset>12</bitOffset>
              <bitWidth>1</bitWidth>
            </field>
            <field>
              <name>ND13</name>
              <bitOffset>13</bitOffset>
              <bitWidth>1</bitWidth>
            </field>
            <field>
              <name>ND14</name>
              <bitOffset>14</bitOffset>
              <bitWidth>1</bitWidth>
            </field>
            <field>
              <name>ND15</name>
              <bitOffset>15</bitOffset>
              <bitWidth>1</bitWidth>
            </field>
            <field>
              <name>ND16</name>
              <bitOffset>16</bitOffset>
              <bitWidth>1</bitWidth>
            </field>
            <field>
              <name>ND17</name>
              <bitOffset>17</bitOffset>
              <bitWidth>1</bitWidth>
            </field>
            <field>
              <name>ND18</name>
              <bitOffset>18</bitOffset>
              <bitWidth>1</bitWidth>
            </field>
            <field>
              <name>ND19</name>
              <bitOffset>19</bitOffset>
              <bitWidth>1</bitWidth>
            </field>
            <field>
              <name>ND20</name>
              <bitOffset>20</bitOffset>
              <bitWidth>1</bitWidth>
            </field>
            <field>
              <name>ND21</name>
              <bitOffset>21</bitOffset>
              <bitWidth>1</bitWidth>
            </field>
            <field>
              <name>ND22</name>
              <bitOffset>22</bitOffset>
              <bitWidth>1</bitWidth>
            </field>
            <field>
              <name>ND23</name>
              <bitOffset>23</bitOffset>
              <bitWidth>1</bitWidth>
            </field>
            <field>
              <name>ND24</name>
              <bitOffset>24</bitOffset>
              <bitWidth>1</bitWidth>
            </field>
            <field>
              <name>ND25</name>
              <bitOffset>25</bitOffset>
              <bitWidth>1</bitWidth>
            </field>
            <field>
              <name>ND26</name>
              <bitOffset>26</bitOffset>
              <bitWidth>1</bitWidth>
            </field>
            <field>
              <name>ND27</name>
              <bitOffset>27</bitOffset>
              <bitWidth>1</bitWidth>
            </field>
            <field>
              <name>ND28</name>
              <bitOffset>28</bitOffset>
              <bitWidth>1</bitWidth>
            </field>
            <field>
              <name>ND29</name>
              <bitOffset>29</bitOffset>
              <bitWidth>1</bitWidth>
            </field>
            <field>
              <name>ND30</name>
              <bitOffset>30</bitOffset>
              <bitWidth>1</bitWidth>
            </field>
            <field>
              <name>ND31</name>
              <bitOffset>31</bitOffset>
              <bitWidth>1</bitWidth>
            </field>
          </fields>
        </register>
        <register>
          <name>NDAT2</name>
          <addressOffset>0x9c</addressOffset>
          <size>0x20</size>
          <fields>
            <field>
              <name>ND32</name>
              <bitOffset>0</bitOffset>
              <bitWidth>1</bitWidth>
            </field>
            <field>
              <name>ND33</name>
              <bitOffset>1</bitOffset>
              <bitWidth>1</bitWidth>
            </field>
            <field>
              <name>ND34</name>
              <bitOffset>2</bitOffset>
              <bitWidth>1</bitWidth>
            </field>
            <field>
              <name>ND35</name>
              <bitOffset>3</bitOffset>
              <bitWidth>1</bitWidth>
            </field>
            <field>
              <name>ND36</name>
              <bitOffset>4</bitOffset>
              <bitWidth>1</bitWidth>
            </field>
            <field>
              <name>ND37</name>
              <bitOffset>5</bitOffset>
              <bitWidth>1</bitWidth>
            </field>
            <field>
              <name>ND38</name>
              <bitOffset>6</bitOffset>
              <bitWidth>1</bitWidth>
            </field>
            <field>
              <name>ND39</name>
              <bitOffset>7</bitOffset>
              <bitWidth>1</bitWidth>
            </field>
            <field>
              <name>ND40</name>
              <bitOffset>8</bitOffset>
              <bitWidth>1</bitWidth>
            </field>
            <field>
              <name>ND41</name>
              <bitOffset>9</bitOffset>
              <bitWidth>1</bitWidth>
            </field>
            <field>
              <name>ND42</name>
              <bitOffset>10</bitOffset>
              <bitWidth>1</bitWidth>
            </field>
            <field>
              <name>ND43</name>
              <bitOffset>11</bitOffset>
              <bitWidth>1</bitWidth>
            </field>
            <field>
              <name>ND44</name>
              <bitOffset>12</bitOffset>
              <bitWidth>1</bitWidth>
            </field>
            <field>
              <name>ND45</name>
              <bitOffset>13</bitOffset>
              <bitWidth>1</bitWidth>
            </field>
            <field>
              <name>ND46</name>
              <bitOffset>14</bitOffset>
              <bitWidth>1</bitWidth>
            </field>
            <field>
              <name>ND47</name>
              <bitOffset>15</bitOffset>
              <bitWidth>1</bitWidth>
            </field>
            <field>
              <name>ND48</name>
              <bitOffset>16</bitOffset>
              <bitWidth>1</bitWidth>
            </field>
            <field>
              <name>ND49</name>
              <bitOffset>17</bitOffset>
              <bitWidth>1</bitWidth>
            </field>
            <field>
              <name>ND50</name>
              <bitOffset>18</bitOffset>
              <bitWidth>1</bitWidth>
            </field>
            <field>
              <name>ND51</name>
              <bitOffset>19</bitOffset>
              <bitWidth>1</bitWidth>
            </field>
            <field>
              <name>ND52</name>
              <bitOffset>20</bitOffset>
              <bitWidth>1</bitWidth>
            </field>
            <field>
              <name>ND53</name>
              <bitOffset>21</bitOffset>
              <bitWidth>1</bitWidth>
            </field>
            <field>
              <name>ND54</name>
              <bitOffset>22</bitOffset>
              <bitWidth>1</bitWidth>
            </field>
            <field>
              <name>ND55</name>
              <bitOffset>23</bitOffset>
              <bitWidth>1</bitWidth>
            </field>
            <field>
              <name>ND56</name>
              <bitOffset>24</bitOffset>
              <bitWidth>1</bitWidth>
            </field>
            <field>
              <name>ND57</name>
              <bitOffset>25</bitOffset>
              <bitWidth>1</bitWidth>
            </field>
            <field>
              <name>ND58</name>
              <bitOffset>26</bitOffset>
              <bitWidth>1</bitWidth>
            </field>
            <field>
              <name>ND59</name>
              <bitOffset>27</bitOffset>
              <bitWidth>1</bitWidth>
            </field>
            <field>
              <name>ND60</name>
              <bitOffset>28</bitOffset>
              <bitWidth>1</bitWidth>
            </field>
            <field>
              <name>ND61</name>
              <bitOffset>29</bitOffset>
              <bitWidth>1</bitWidth>
            </field>
            <field>
              <name>ND62</name>
              <bitOffset>30</bitOffset>
              <bitWidth>1</bitWidth>
            </field>
            <field>
              <name>ND63</name>
              <bitOffset>31</bitOffset>
              <bitWidth>1</bitWidth>
            </field>
          </fields>
        </register>
        <register>
          <name>RXF0C</name>
          <addressOffset>0xa0</addressOffset>
          <size>0x20</size>
          <fields>
            <field>
              <name>F0SA</name>
              <bitOffset>2</bitOffset>
              <bitWidth>14</bitWidth>
            </field>
            <field>
              <name>F0S</name>
              <bitOffset>16</bitOffset>
              <bitWidth>7</bitWidth>
            </field>
            <field>
              <name>F0WM</name>
              <bitOffset>24</bitOffset>
              <bitWidth>7</bitWidth>
            </field>
            <field>
              <name>F0OM</name>
              <bitOffset>31</bitOffset>
              <bitWidth>1</bitWidth>
            </field>
          </fields>
        </register>
        <register>
          <name>RXF0S</name>
          <addressOffset>0xa4</addressOffset>
          <size>0x20</size>
          <fields>
            <field>
              <name>F0FL</name>
              <bitOffset>0</bitOffset>
              <bitWidth>7</bitWidth>
            </field>
            <field>
              <name>F0GI</name>
              <bitOffset>8</bitOffset>
              <bitWidth>6</bitWidth>
            </field>
            <field>
              <name>F0PI</name>
              <bitOffset>16</bitOffset>
              <bitWidth>6</bitWidth>
            </field>
            <field>
              <name>F0F</name>
              <bitOffset>24</bitOffset>
              <bitWidth>1</bitWidth>
            </field>
            <field>
              <name>RF0L</name>
              <bitOffset>25</bitOffset>
              <bitWidth>1</bitWidth>
            </field>
          </fields>
        </register>
        <register>
          <name>RXF0A</name>
          <addressOffset>0xa8</addressOffset>
          <size>0x20</size>
          <fields>
            <field>
              <name>F0AI</name>
              <bitOffset>0</bitOffset>
              <bitWidth>6</bitWidth>
            </field>
          </fields>
        </register>
        <register>
          <name>RXBC</name>
          <addressOffset>0xac</addressOffset>
          <size>0x20</size>
          <fields>
            <field>
              <name>RBSA</name>
              <bitOffset>2</bitOffset>
              <bitWidth>14</bitWidth>
            </field>
          </fields>
        </register>
        <register>
          <name>RXF1C</name>
          <addressOffset>0xb0</addressOffset>
          <size>0x20</size>
          <fields>
            <field>
              <name>F1SA</name>
              <bitOffset>2</bitOffset>
              <bitWidth>14</bitWidth>
            </field>
            <field>
              <name>F1S</name>
              <bitOffset>16</bitOffset>
              <bitWidth>7</bitWidth>
            </field>
            <field>
              <name>F1WM</name>
              <bitOffset>24</bitOffset>
              <bitWidth>7</bitWidth>
            </field>
            <field>
              <name>F1OM</name>
              <bitOffset>31</bitOffset>
              <bitWidth>1</bitWidth>
            </field>
          </fields>
        </register>
        <register>
          <name>RXF1S</name>
          <addressOffset>0xb4</addressOffset>
          <size>0x20</size>
          <fields>
            <field>
              <name>F1FL</name>
              <bitOffset>0</bitOffset>
              <bitWidth>7</bitWidth>
            </field>
            <field>
              <name>F1GI</name>
              <bitOffset>8</bitOffset>
              <bitWidth>6</bitWidth>
            </field>
            <field>
              <name>F1PI</name>
              <bitOffset>16</bitOffset>
              <bitWidth>6</bitWidth>
            </field>
            <field>
              <name>F1F</name>
              <bitOffset>24</bitOffset>
              <bitWidth>1</bitWidth>
            </field>
            <field>
              <name>RF1L</name>
              <bitOffset>25</bitOffset>
              <bitWidth>1</bitWidth>
            </field>
          </fields>
        </register>
        <register>
          <name>RXF1A</name>
          <addressOffset>0xb8</addressOffset>
          <size>0x20</size>
          <fields>
            <field>
              <name>F1AI</name>
              <bitOffset>0</bitOffset>
              <bitWidth>6</bitWidth>
            </field>
          </fields>
        </register>
        <register>
          <name>RXESC</name>
          <addressOffset>0xbc</addressOffset>
          <size>0x20</size>
          <fields>
            <field>
              <name>F0DS</name>
              <bitOffset>0</bitOffset>
              <bitWidth>3</bitWidth>
            </field>
            <field>
              <name>F1DS</name>
              <bitOffset>4</bitOffset>
              <bitWidth>3</bitWidth>
            </field>
            <field>
              <name>RBDS</name>
              <bitOffset>8</bitOffset>
              <bitWidth>3</bitWidth>
            </field>
          </fields>
        </register>
        <register>
          <name>TXBC</name>
          <addressOffset>0xc0</addressOffset>
          <size>0x20</size>
          <fields>
            <field>
              <name>TBSA</name>
              <bitOffset>2</bitOffset>
              <bitWidth>14</bitWidth>
            </field>
            <field>
              <name>NDTB</name>
              <bitOffset>16</bitOffset>
              <bitWidth>6</bitWidth>
            </field>
            <field>
              <name>TFQS</name>
              <bitOffset>24</bitOffset>
              <bitWidth>6</bitWidth>
            </field>
            <field>
              <name>TFQM</name>
              <bitOffset>30</bitOffset>
              <bitWidth>1</bitWidth>
            </field>
          </fields>
        </register>
        <register>
          <name>TXFQS</name>
          <addressOffset>0xc4</addressOffset>
          <size>0x20</size>
          <fields>
            <field>
              <name>TFFL</name>
              <bitOffset>0</bitOffset>
              <bitWidth>6</bitWidth>
            </field>
            <field>
              <name>TFGI</name>
              <bitOffset>8</bitOffset>
              <bitWidth>5</bitWidth>
            </field>
            <field>
              <name>TFQPI</name>
              <bitOffset>16</bitOffset>
              <bitWidth>5</bitWidth>
            </field>
            <field>
              <name>TFQF</name>
              <bitOffset>21</bitOffset>
              <bitWidth>1</bitWidth>
            </field>
          </fields>
        </register>
        <register>
          <name>TXESC</name>
          <addressOffset>0xc8</addressOffset>
          <size>0x20</size>
          <fields>
            <field>
              <name>TBDS</name>
              <bitOffset>0</bitOffset>
              <bitWidth>3</bitWidth>
            </field>
          </fields>
        </register>
        <register>
          <name>TXBRP</name>
          <addressOffset>0xcc</addressOffset>
          <size>0x20</size>
          <fields>
            <field>
              <name>TRP</name>
              <bitOffset>0</bitOffset>
              <bitWidth>32</bitWidth>
            </field>
          </fields>
        </register>
        <register>
          <name>TXBAR</name>
          <addressOffset>0xd0</addressOffset>
          <size>0x20</size>
          <fields>
            <field>
              <name>AR</name>
              <bitOffset>0</bitOffset>
              <bitWidth>32</bitWidth>
            </field>
          </fields>
        </register>
        <register>
          <name>TXBCR</name>
          <addressOffset>0xd4</addressOffset>
          <size>0x20</size>
          <fields>
            <field>
              <name>CR</name>
              <bitOffset>0</bitOffset>
              <bitWidth>32</bitWidth>
            </field>
          </fields>
        </register>
        <register>
          <name>TXBTO</name>
          <addressOffset>0xd8</addressOffset>
          <size>0x20</size>
          <fields>
            <field>
              <name>TO</name>
              <bitOffset>0</bitOffset>
              <bitWidth>32</bitWidth>
            </field>
          </fields>
        </register>
        <register>
          <name>TXBCF</name>
          <addressOffset>0xdc</addressOffset>
          <size>0x20</size>
          <fields>
            <field>
              <name>CF</name>
              <bitOffset>0</bitOffset>
              <bitWidth>32</bitWidth>
            </field>
          </fields>
        </register>
        <register>
          <name>TXBTIE</name>
          <addressOffset>0xe0</addressOffset>
          <size>0x20</size>
          <fields>
            <field>
              <name>TIE</name>
              <bitOffset>0</bitOffset>
              <bitWidth>32</bitWidth>
            </field>
          </fields>
        </register>
        <register>
          <name>TXBCIE</name>
          <addressOffset>0xe4</addressOffset>
          <size>0x20</size>
          <fields>
            <field>
              <name>CFIE</name>
              <bitOffset>0</bitOffset>
              <bitWidth>32</bitWidth>
            </field>
          </fields>
        </register>
        <register>
          <name>TXEFC</name>
          <addressOffset>0xf0</addressOffset>
          <size>0x20</size>
          <fields>
            <field>
              <name>EFSA</name>
              <bitOffset>2</bitOffset>
              <bitWidth>14</bitWidth>
            </field>
            <field>
              <name>EFS</name>
              <bitOffset>16</bitOffset>
              <bitWidth>6</bitWidth>
            </field>
            <field>
              <name>EFWM</name>
              <bitOffset>24</bitOffset>
              <bitWidth>6</bitWidth>
            </field>
          </fields>
        </register>
        <register>
          <name>TXEFS</name>
          <addressOffset>0xf4</addressOffset>
          <size>0x20</size>
          <fields>
            <field>
              <name>EFFL</name>
              <bitOffset>0</bitOffset>
              <bitWidth>6</bitWidth>
            </field>
            <field>
              <name>EFGI</name>
              <bitOffset>8</bitOffset>
              <bitWidth>5</bitWidth>
            </field>
            <field>
              <name>EFPI</name>
              <bitOffset>16</bitOffset>
              <bitWidth>5</bitWidth>
            </field>
            <field>
              <name>EFF</name>
              <bitOffset>24</bitOffset>
              <bitWidth>1</bitWidth>
            </field>
            <field>
              <name>TEFL</name>
              <bitOffset>25</bitOffset>
              <bitWidth>1</bitWidth>
            </field>
          </fields>
        </register>
        <register>
          <name>TXEFA</name>
          <addressOffset>0xf8</addressOffset>
          <size>0x20</size>
          <fields>
            <field>
              <name>EFAI</name>
              <bitOffset>0</bitOffset>
              <bitWidth>5</bitWidth>
            </field>
          </fields>
        </register>
      </registers>
    </peripheral>
    <peripheral>
      <name>FDCAN_CCU</name>
      <baseAddress>0x4000a800</baseAddress>
      <registers>
        <register>
          <name>CREL</name>
          <addressOffset>0x0</addressOffset>
          <size>0x20</size>
          <fields>
            <field>
              <name>DAY</name>
              <bitOffset>0</bitOffset>
              <bitWidth>8</bitWidth>
            </field>
            <field>
              <name>MON</name>
              <bitOffset>8</bitOffset>
              <bitWidth>8</bitWidth>
            </field>
            <field>
              <name>YEAR</name>
              <bitOffset>16</bitOffset>
              <bitWidth>4</bitWidth>
            </field>
            <field>
              <name>SUBSTEP</name>
              <bitOffset>20</bitOffset>
              <bitWidth>4</bitWidth>
            </field>
            <field>
              <name>STEP</name>
              <bitOffset>24</bitOffset>
              <bitWidth>4</bitWidth>
            </field>
            <field>
              <name>REL</name>
              <bitOffset>28</bitOffset>
              <bitWidth>4</bitWidth>
            </field>
          </fields>
        </register>
        <register>
          <name>CCFG</name>
          <addressOffset>0x4</addressOffset>
          <size>0x20</size>
        </register>
        <register>
          <name>CSTAT</name>
          <addressOffset>0x8</addressOffset>
          <size>0x20</size>
        </register>
        <register>
          <name>CWD</name>
          <addressOffset>0xc</addressOffset>
          <size>0x20</size>
        </register>
        <register>
          <name>IR</name>
          <addressOffset>0x10</addressOffset>
          <size>0x20</size>
          <fields>
            <field>
              <name>RF0N</name>
              <bitOffset>0</bitOffset>
              <bitWidth>1</bitWidth>
            </field>
            <field>
              <name>RF0W</name>
              <bitOffset>1</bitOffset>
              <bitWidth>1</bitWidth>
            </field>
            <field>
              <name>RF0F</name>
              <bitOffset>2</bitOffset>
              <bitWidth>1</bitWidth>
            </field>
            <field>
              <name>RF0L</name>
              <bitOffset>3</bitOffset>
              <bitWidth>1</bitWidth>
            </field>
            <field>
              <name>RF1N</name>
              <bitOffset>4</bitOffset>
              <bitWidth>1</bitWidth>
            </field>
            <field>
              <name>RF1W</name>
              <bitOffset>5</bitOffset>
              <bitWidth>1</bitWidth>
            </field>
            <field>
              <name>RF1F</name>
              <bitOffset>6</bitOffset>
              <bitWidth>1</bitWidth>
            </field>
            <field>
              <name>RF1L</name>
              <bitOffset>7</bitOffset>
              <bitWidth>1</bitWidth>
            </field>
            <field>
              <name>HPM</name>
              <bitOffset>8</bitOffset>
              <bitWidth>1</bitWidth>
            </field>
            <field>
              <name>TC</name>
              <bitOffset>9</bitOffset>
              <bitWidth>1</bitWidth>
            </field>
            <field>
              <name>TCF</name>
              <bitOffset>10</bitOffset>
              <bitWidth>1</bitWidth>
            </field>
            <field>
              <name>TFE</name>
              <bitOffset>11</bitOffset>
              <bitWidth>1</bitWidth>
            </field>
            <field>
              <name>TEFN</name>
              <bitOffset>12</bitOffset>
              <bitWidth>1</bitWidth>
            </field>
            <field>
              <name>TEFW</name>
              <bitOffset>13</bitOffset>
              <bitWidth>1</bitWidth>
            </field>
            <field>
              <name>TEFF</name>
              <bitOffset>14</bitOffset>
              <bitWidth>1</bitWidth>
            </field>
            <field>
              <name>TEFL</name>
              <bitOffset>15</bitOffset>
              <bitWidth>1</bitWidth>
            </field>
            <field>
              <name>TSW</name>
              <bitOffset>16</bitOffset>
              <bitWidth>1</bitWidth>
            </field>
            <field>
              <name>MRAF</name>
              <bitOffset>17</bitOffset>
              <bitWidth>1</bitWidth>
            </field>
            <field>
              <name>TOO</name>
              <bitOffset>18</bitOffset>
              <bitWidth>1</bitWidth>
            </field>
            <field>
              <name>DRX</name>
              <bitOffset>19</bitOffset>
              <bitWidth>1</bitWidth>
            </field>
            <field>
              <name>ELO</name>
              <bitOffset>22</bitOffset>
              <bitWidth>1</bitWidth>
            </field>
            <field>
              <name>EP</name>
              <bitOffset>23</bitOffset>
              <bitWidth>1</bitWidth>
            </field>
            <field>
              <name>EW</name>
              <bitOffset>24</bitOffset>
              <bitWidth>1</bitWidth>
            </field>
            <field>
              <name>BO</name>
              <bitOffset>25</bitOffset>
              <bitWidth>1</bitWidth>
            </field>
            <field>
              <name>WDI</name>
              <bitOffset>26</bitOffset>
              <bitWidth>1</bitWidth>
            </field>
            <field>
              <name>PEA</name>
              <bitOffset>27</bitOffset>
              <bitWidth>1</bitWidth>
            </field>
            <field>
              <name>PED</name>
              <bitOffset>28</bitOffset>
              <bitWidth>1</bitWidth>
            </field>
            <field>
              <name>ARA</name>
              <bitOffset>29</bitOffset>
              <bitWidth>1</bitWidth>
            </field>
          </fields>
        </register>
        <register>
          <name>IE</name>
          <addressOffset>0x14</addressOffset>
          <size>0x20</size>
          <fields>
            <field>
              <name>RF0NE</name>
              <bitOffset>0</bitOffset>
              <bitWidth>1</bitWidth>
            </field>
            <field>
              <name>RF0WE</name>
              <bitOffset>1</bitOffset>
              <bitWidth>1</bitWidth>
            </field>
            <field>
              <name>RF0FE</name>
              <bitOffset>2</bitOffset>
              <bitWidth>1</bitWidth>
            </field>
            <field>
              <name>RF0LE</name>
              <bitOffset>3</bitOffset>
              <bitWidth>1</bitWidth>
            </field>
            <field>
              <name>RF1NE</name>
              <bitOffset>4</bitOffset>
              <bitWidth>1</bitWidth>
            </field>
            <field>
              <name>RF1WE</name>
              <bitOffset>5</bitOffset>
              <bitWidth>1</bitWidth>
            </field>
            <field>
              <name>RF1FE</name>
              <bitOffset>6</bitOffset>
              <bitWidth>1</bitWidth>
            </field>
            <field>
              <name>RF1LE</name>
              <bitOffset>7</bitOffset>
              <bitWidth>1</bitWidth>
            </field>
            <field>
              <name>HPME</name>
              <bitOffset>8</bitOffset>
              <bitWidth>1</bitWidth>
            </field>
            <field>
              <name>TCE</name>
              <bitOffset>9</bitOffset>
              <bitWidth>1</bitWidth>
            </field>
            <field>
              <name>TCFE</name>
              <bitOffset>10</bitOffset>
              <bitWidth>1</bitWidth>
            </field>
            <field>
              <name>TFEE</name>
              <bitOffset>11</bitOffset>
              <bitWidth>1</bitWidth>
            </field>
            <field>
              <name>TEFNE</name>
              <bitOffset>12</bitOffset>
              <bitWidth>1</bitWidth>
            </field>
            <field>
              <name>TEFWE</name>
              <bitOffset>13</bitOffset>
              <bitWidth>1</bitWidth>
            </field>
            <field>
              <name>TEFFE</name>
              <bitOffset>14</bitOffset>
              <bitWidth>1</bitWidth>
            </field>
            <field>
              <name>TEFLE</name>
              <bitOffset>15</bitOffset>
              <bitWidth>1</bitWidth>
            </field>
            <field>
              <name>TSWE</name>
              <bitOffset>16</bitOffset>
              <bitWidth>1</bitWidth>
            </field>
            <field>
              <name>MRAFE</name>
              <bitOffset>17</bitOffset>
              <bitWidth>1</bitWidth>
            </field>
            <field>
              <name>TOOE</name>
              <bitOffset>18</bitOffset>
              <bitWidth>1</bitWidth>
            </field>
            <field>
              <name>DRXE</name>
              <bitOffset>19</bitOffset>
              <bitWidth>1</bitWidth>
            </field>
            <field>
              <name>BECE</name>
              <bitOffset>20</bitOffset>
              <bitWidth>1</bitWidth>
            </field>
            <field>
              <name>BEUE</name>
              <bitOffset>21</bitOffset>
              <bitWidth>1</bitWidth>
            </field>
            <field>
              <name>ELOE</name>
              <bitOffset>22</bitOffset>
              <bitWidth>1</bitWidth>
            </field>
            <field>
              <name>EPE</name>
              <bitOffset>23</bitOffset>
              <bitWidth>1</bitWidth>
            </field>
            <field>
              <name>EWE</name>
              <bitOffset>24</bitOffset>
              <bitWidth>1</bitWidth>
            </field>
            <field>
              <name>BOE</name>
              <bitOffset>25</bitOffset>
              <bitWidth>1</bitWidth>
            </field>
            <field>
              <name>WDIE</name>
              <bitOffset>26</bitOffset>
              <bitWidth>1</bitWidth>
            </field>
            <field>
              <name>PEAE</name>
              <bitOffset>27</bitOffset>
              <bitWidth>1</bitWidth>
            </field>
            <field>
              <name>PEDE</name>
              <bitOffset>28</bitOffset>
              <bitWidth>1</bitWidth>
            </field>
            <field>
              <name>ARAE</name>
              <bitOffset>29</bitOffset>
              <bitWidth>1</bitWidth>
            </field>
          </fields>
        </register>
      </registers>
    </peripheral>
    <peripheral>
      <name>TIM1</name>
      <baseAddress>0x40010000</baseAddress>
      <registers>
        <register>
          <name>CR1</name>
          <addressOffset>0x0</addressOffset>
          <size>0x20</size>
          <fields>
            <field>
              <name>CEN</name>
              <bitOffset>0</bitOffset>
              <bitWidth>1</bitWidth>
            </field>
            <field>
              <name>UDIS</name>
              <bitOffset>1</bitOffset>
              <bitWidth>1</bitWidth>
            </field>
            <field>
              <name>URS</name>
              <bitOffset>2</bitOffset>
              <bitWidth>1</bitWidth>
            </field>
            <field>
              <name>OPM</name>
              <bitOffset>3</bitOffset>
              <bitWidth>1</bitWidth>
            </field>
            <field>
              <name>DIR</name>
              <bitOffset>4</bitOffset>
              <bitWidth>1</bitWidth>
            </field>
            <field>
              <name>CMS</name>
              <bitOffset>5</bitOffset>
              <bitWidth>2</bitWidth>
            </field>
            <field>
              <name>ARPE</name>
              <bitOffset>7</bitOffset>
              <bitWidth>1</bitWidth>
            </field>
            <field>
              <name>CKD</name>
              <bitOffset>8</bitOffset>
              <bitWidth>2</bitWidth>
            </field>
            <field>
              <name>UIFREMAP</name>
              <bitOffset>11</bitOffset>
              <bitWidth>1</bitWidth>
            </field>
          </fields>
        </register>
        <register>
          <name>CR2</name>
          <addressOffset>0x4</addressOffset>
          <size>0x20</size>
          <fields>
            <field>
              <name>CCPC</name>
              <bitOffset>0</bitOffset>
              <bitWidth>1</bitWidth>
            </field>
            <field>
              <name>CCUS</name>
              <bitOffset>2</bitOffset>
              <bitWidth>1</bitWidth>
            </field>
            <field>
              <name>CCDS</name>
              <bitOffset>3</bitOffset>
              <bitWidth>1</bitWidth>
            </field>
            <field>
              <name>MMS</name>
              <bitOffset>4</bitOffset>
              <bitWidth>3</bitWidth>
            </field>
            <field>
              <name>TI1S</name>
              <bitOffset>7</bitOffset>
              <bitWidth>1</bitWidth>
            </field>
            <field>
              <name>OIS1</name>
              <bitOffset>8</bitOffset>
              <bitWidth>1</bitWidth>
            </field>
            <field>
              <name>OIS1N</name>
              <bitOffset>9</bitOffset>
              <bitWidth>1</bitWidth>
            </field>
            <field>
              <name>OIS2</name>
              <bitOffset>10</bitOffset>
              <bitWidth>1</bitWidth>
            </field>
            <field>
              <name>OIS2N</name>
              <bitOffset>11</bitOffset>
              <bitWidth>1</bitWidth>
            </field>
            <field>
              <name>OIS3</name>
              <bitOffset>12</bitOffset>
              <bitWidth>1</bitWidth>
            </field>
            <field>
              <name>OIS3N</name>
              <bitOffset>13</bitOffset>
              <bitWidth>1</bitWidth>
            </field>
            <field>
              <name>OIS4</name>
              <bitOffset>14</bitOffset>
              <bitWidth>1</bitWidth>
            </field>
            <field>
              <name>OIS5</name>
              <bitOffset>16</bitOffset>
              <bitWidth>1</bitWidth>
            </field>
            <field>
              <name>OIS6</name>
              <bitOffset>18</bitOffset>
              <bitWidth>1</bitWidth>
            </field>
            <field>
              <name>MMS2</name>
              <bitOffset>20</bitOffset>
              <bitWidth>4</bitWidth>
            </field>
          </fields>
        </register>
        <register>
          <name>SMCR</name>
          <addressOffset>0x8</addressOffset>
          <size>0x20</size>
          <fields>
            <field>
              <name>SMS</name>
              <bitOffset>0</bitOffset>
              <bitWidth>17</bitWidth>
            </field>
            <field>
              <name>TS</name>
              <bitOffset>4</bitOffset>
              <bitWidth>18</bitWidth>
            </field>
            <field>
              <name>MSM</name>
              <bitOffset>7</bitOffset>
              <bitWidth>1</bitWidth>
            </field>
            <field>
              <name>ETF</name>
              <bitOffset>8</bitOffset>
              <bitWidth>4</bitWidth>
            </field>
            <field>
              <name>ETPS</name>
              <bitOffset>12</bitOffset>
              <bitWidth>2</bitWidth>
            </field>
            <field>
              <name>ECE</name>
              <bitOffset>14</bitOffset>
              <bitWidth>1</bitWidth>
            </field>
            <field>
              <name>ETP</name>
              <bitOffset>15</bitOffset>
              <bitWidth>1</bitWidth>
            </field>
          </fields>
        </register>
        <register>
          <name>DIER</name>
          <addressOffset>0xc</addressOffset>
          <size>0x20</size>
          <fields>
            <field>
              <name>UIE</name>
              <bitOffset>0</bitOffset>
              <bitWidth>1</bitWidth>
            </field>
            <field>
              <name>CC1IE</name>
              <bitOffset>1</bitOffset>
              <bitWidth>1</bitWidth>
            </field>
            <field>
              <name>CC2IE</name>
              <bitOffset>2</bitOffset>
              <bitWidth>1</bitWidth>
            </field>
            <field>
              <name>CC3IE</name>
              <bitOffset>3</bitOffset>
              <bitWidth>1</bitWidth>
            </field>
            <field>
              <name>CC4IE</name>
              <bitOffset>4</bitOffset>
              <bitWidth>1</bitWidth>
            </field>
            <field>
              <name>COMIE</name>
              <bitOffset>5</bitOffset>
              <bitWidth>1</bitWidth>
            </field>
            <field>
              <name>TIE</name>
              <bitOffset>6</bitOffset>
              <bitWidth>1</bitWidth>
            </field>
            <field>
              <name>BIE</name>
              <bitOffset>7</bitOffset>
              <bitWidth>1</bitWidth>
            </field>
            <field>
              <name>UDE</name>
              <bitOffset>8</bitOffset>
              <bitWidth>1</bitWidth>
            </field>
            <field>
              <name>CC1DE</name>
              <bitOffset>9</bitOffset>
              <bitWidth>1</bitWidth>
            </field>
            <field>
              <name>CC2DE</name>
              <bitOffset>10</bitOffset>
              <bitWidth>1</bitWidth>
            </field>
            <field>
              <name>CC3DE</name>
              <bitOffset>11</bitOffset>
              <bitWidth>1</bitWidth>
            </field>
            <field>
              <name>CC4DE</name>
              <bitOffset>12</bitOffset>
              <bitWidth>1</bitWidth>
            </field>
            <field>
              <name>COMDE</name>
              <bitOffset>13</bitOffset>
              <bitWidth>1</bitWidth>
            </field>
            <field>
              <name>TDE</name>
              <bitOffset>14</bitOffset>
              <bitWidth>1</bitWidth>
            </field>
          </fields>
        </register>
        <register>
          <name>SR</name>
          <addressOffset>0x10</addressOffset>
          <size>0x20</size>
          <fields>
            <field>
              <name>UIF</name>
              <bitOffset>0</bitOffset>
              <bitWidth>1</bitWidth>
            </field>
            <field>
              <name>CC1IF</name>
              <bitOffset>1</bitOffset>
              <bitWidth>1</bitWidth>
            </field>
            <field>
              <name>CC2IF</name>
              <bitOffset>2</bitOffset>
              <bitWidth>1</bitWidth>
            </field>
            <field>
              <name>CC3IF</name>
              <bitOffset>3</bitOffset>
              <bitWidth>1</bitWidth>
            </field>
            <field>
              <name>CC4IF</name>
              <bitOffset>4</bitOffset>
              <bitWidth>1</bitWidth>
            </field>
            <field>
              <name>COMIF</name>
              <bitOffset>5</bitOffset>
              <bitWidth>1</bitWidth>
            </field>
            <field>
              <name>TIF</name>
              <bitOffset>6</bitOffset>
              <bitWidth>1</bitWidth>
            </field>
            <field>
              <name>BIF</name>
              <bitOffset>7</bitOffset>
              <bitWidth>1</bitWidth>
            </field>
            <field>
              <name>B2IF</name>
              <bitOffset>8</bitOffset>
              <bitWidth>1</bitWidth>
            </field>
            <field>
              <name>CC1OF</name>
              <bitOffset>9</bitOffset>
              <bitWidth>1</bitWidth>
            </field>
            <field>
              <name>CC2OF</name>
              <bitOffset>10</bitOffset>
              <bitWidth>1</bitWidth>
            </field>
            <field>
              <name>CC3OF</name>
              <bitOffset>11</bitOffset>
              <bitWidth>1</bitWidth>
            </field>
            <field>
              <name>CC4OF</name>
              <bitOffset>12</bitOffset>
              <bitWidth>1</bitWidth>
            </field>
            <field>
              <name>SBIF</name>
              <bitOffset>13</bitOffset>
              <bitWidth>1</bitWidth>
            </field>
            <field>
              <name>CC5IF</name>
              <bitOffset>16</bitOffset>
              <bitWidth>1</bitWidth>
            </field>
            <field>
              <name>CC6IF</name>
              <bitOffset>17</bitOffset>
              <bitWidth>1</bitWidth>
            </field>
          </fields>
        </register>
        <register>
          <name>EGR</name>
          <addressOffset>0x14</addressOffset>
          <size>0x20</size>
          <fields>
            <field>
              <name>UG</name>
              <bitOffset>0</bitOffset>
              <bitWidth>1</bitWidth>
            </field>
            <field>
              <name>CC1G</name>
              <bitOffset>1</bitOffset>
              <bitWidth>1</bitWidth>
            </field>
            <field>
              <name>CC2G</name>
              <bitOffset>2</bitOffset>
              <bitWidth>1</bitWidth>
            </field>
            <field>
              <name>CC3G</name>
              <bitOffset>3</bitOffset>
              <bitWidth>1</bitWidth>
            </field>
            <field>
              <name>CC4G</name>
              <bitOffset>4</bitOffset>
              <bitWidth>1</bitWidth>
            </field>
            <field>
              <name>COMG</name>
              <bitOffset>5</bitOffset>
              <bitWidth>1</bitWidth>
            </field>
            <field>
              <name>TG</name>
              <bitOffset>6</bitOffset>
              <bitWidth>1</bitWidth>
            </field>
            <field>
              <name>BG</name>
              <bitOffset>7</bitOffset>
              <bitWidth>1</bitWidth>
            </field>
            <field>
              <name>B2G</name>
              <bitOffset>8</bitOffset>
              <bitWidth>1</bitWidth>
            </field>
          </fields>
        </register>
        <register>
          <name>CCMR1</name>
          <addressOffset>0x18</addressOffset>
          <size>0x20</size>
          <fields>
            <field>
              <name>CC1S</name>
              <bitOffset>0</bitOffset>
              <bitWidth>2</bitWidth>
            </field>
            <field>
              <name>OC1FE</name>
              <bitOffset>2</bitOffset>
              <bitWidth>1</bitWidth>
            </field>
            <field>
              <name>OC1PE</name>
              <bitOffset>3</bitOffset>
              <bitWidth>1</bitWidth>
            </field>
            <field>
              <name>OC1M</name>
              <bitOffset>4</bitOffset>
              <bitWidth>13</bitWidth>
            </field>
            <field>
              <name>OC1CE</name>
              <bitOffset>7</bitOffset>
              <bitWidth>1</bitWidth>
            </field>
            <field>
              <name>CC2S</name>
              <bitOffset>8</bitOffset>
              <bitWidth>2</bitWidth>
            </field>
            <field>
              <name>OC2FE</name>
              <bitOffset>10</bitOffset>
              <bitWidth>1</bitWidth>
            </field>
            <field>
              <name>OC2PE</name>
              <bitOffset>11</bitOffset>
              <bitWidth>1</bitWidth>
            </field>
            <field>
              <name>OC2M</name>
              <bitOffset>12</bitOffset>
              <bitWidth>13</bitWidth>
            </field>
            <field>
              <name>OC2CE</name>
              <bitOffset>15</bitOffset>
              <bitWidth>1</bitWidth>
            </field>
          </fields>
        </register>
        <register>
          <name>CCMR2</name>
          <addressOffset>0x1c</addressOffset>
          <size>0x20</size>
          <fields>
            <field>
              <name>CC3S</name>
              <bitOffset>0</bitOffset>
              <bitWidth>2</bitWidth>
            </field>
            <field>
              <name>OC3FE</name>
              <bitOffset>2</bitOffset>
              <bitWidth>1</bitWidth>
            </field>
            <field>
              <name>OC3PE</name>
              <bitOffset>3</bitOffset>
              <bitWidth>1</bitWidth>
            </field>
            <field>
              <name>OC3M</name>
              <bitOffset>4</bitOffset>
              <bitWidth>13</bitWidth>
            </field>
            <field>
              <name>OC3CE</name>
              <bitOffset>7</bitOffset>
              <bitWidth>1</bitWidth>
            </field>
            <field>
              <name>CC4S</name>
              <bitOffset>8</bitOffset>
              <bitWidth>2</bitWidth>
            </field>
            <field>
              <name>OC4FE</name>
              <bitOffset>10</bitOffset>
              <bitWidth>1</bitWidth>
            </field>
            <field>
              <name>OC4PE</name>
              <bitOffset>11</bitOffset>
              <bitWidth>1</bitWidth>
            </field>
            <field>
              <name>OC4M</name>
              <bitOffset>12</bitOffset>
              <bitWidth>13</bitWidth>
            </field>
            <field>
              <name>OC4CE</name>
              <bitOffset>15</bitOffset>
              <bitWidth>1</bitWidth>
            </field>
          </fields>
        </register>
        <register>
          <name>CCER</name>
          <addressOffset>0x20</addressOffset>
          <size>0x20</size>
          <fields>
            <field>
              <name>CC1E</name>
              <bitOffset>0</bitOffset>
              <bitWidth>1</bitWidth>
            </field>
            <field>
              <name>CC1P</name>
              <bitOffset>1</bitOffset>
              <bitWidth>1</bitWidth>
            </field>
            <field>
              <name>CC1NE</name>
              <bitOffset>2</bitOffset>
              <bitWidth>1</bitWidth>
            </field>
            <field>
              <name>CC1NP</name>
              <bitOffset>3</bitOffset>
              <bitWidth>1</bitWidth>
            </field>
            <field>
              <name>CC2E</name>
              <bitOffset>4</bitOffset>
              <bitWidth>1</bitWidth>
            </field>
            <field>
              <name>CC2P</name>
              <bitOffset>5</bitOffset>
              <bitWidth>1</bitWidth>
            </field>
            <field>
              <name>CC2NE</name>
              <bitOffset>6</bitOffset>
              <bitWidth>1</bitWidth>
            </field>
            <field>
              <name>CC2NP</name>
              <bitOffset>7</bitOffset>
              <bitWidth>1</bitWidth>
            </field>
            <field>
              <name>CC3E</name>
              <bitOffset>8</bitOffset>
              <bitWidth>1</bitWidth>
            </field>
            <field>
              <name>CC3P</name>
              <bitOffset>9</bitOffset>
              <bitWidth>1</bitWidth>
            </field>
            <field>
              <name>CC3NE</name>
              <bitOffset>10</bitOffset>
              <bitWidth>1</bitWidth>
            </field>
            <field>
              <name>CC3NP</name>
              <bitOffset>11</bitOffset>
              <bitWidth>1</bitWidth>
            </field>
            <field>
              <name>CC4E</name>
              <bitOffset>12</bitOffset>
              <bitWidth>1</bitWidth>
            </field>
            <field>
              <name>CC4P</name>
              <bitOffset>13</bitOffset>
              <bitWidth>1</bitWidth>
            </field>
            <field>
              <name>CC4NP</name>
              <bitOffset>15</bitOffset>
              <bitWidth>1</bitWidth>
            </field>
            <field>
              <name>CC5E</name>
              <bitOffset>16</bitOffset>
              <bitWidth>1</bitWidth>
            </field>
            <field>
              <name>CC5P</name>
              <bitOffset>17</bitOffset>
              <bitWidth>1</bitWidth>
            </field>
            <field>
              <name>CC6E</name>
              <bitOffset>20</bitOffset>
              <bitWidth>1</bitWidth>
            </field>
            <field>
              <name>CC6P</name>
              <bitOffset>21</bitOffset>
              <bitWidth>1</bitWidth>
            </field>
          </fields>
        </register>
        <register>
          <name>CNT</name>
          <addressOffset>0x24</addressOffset>
          <size>0x20</size>
          <fields>
            <field>
              <name>CNT</name>
              <bitOffset>0</bitOffset>
              <bitWidth>32</bitWidth>
            </field>
            <field>
              <name>UIFCPY</name>
              <bitOffset>31</bitOffset>
              <bitWidth>1</bitWidth>
            </field>
          </fields>
        </register>
        <register>
          <name>PSC</name>
          <addressOffset>0x28</addressOffset>
          <size>0x20</size>
          <fields>
            <field>
              <name>PSC</name>
              <bitOffset>0</bitOffset>
              <bitWidth>16</bitWidth>
            </field>
          </fields>
        </register>
        <register>
          <name>ARR</name>
          <addressOffset>0x2c</addressOffset>
          <size>0x20</size>
          <fields>
            <field>
              <name>ARR</name>
              <bitOffset>0</bitOffset>
              <bitWidth>32</bitWidth>
            </field>
          </fields>
        </register>
        <register>
          <name>RCR</name>
          <addressOffset>0x30</addressOffset>
          <size>0x20</size>
          <fields>
            <field>
              <name>REP</name>
              <bitOffset>0</bitOffset>
              <bitWidth>8</bitWidth>
            </field>
          </fields>
        </register>
        <register>
          <name>CCR1</name>
          <addressOffset>0x34</addressOffset>
          <size>0x20</size>
          <fields>
            <field>
              <name>CCR1</name>
              <bitOffset>0</bitOffset>
              <bitWidth>16</bitWidth>
            </field>
          </fields>
        </register>
        <register>
          <name>CCR2</name>
          <addressOffset>0x38</addressOffset>
          <size>0x20</size>
          <fields>
            <field>
              <name>CCR2</name>
              <bitOffset>0</bitOffset>
              <bitWidth>16</bitWidth>
            </field>
          </fields>
        </register>
        <register>
          <name>CCR3</name>
          <addressOffset>0x3c</addressOffset>
          <size>0x20</size>
          <fields>
            <field>
              <name>CCR3</name>
              <bitOffset>0</bitOffset>
              <bitWidth>16</bitWidth>
            </field>
          </fields>
        </register>
        <register>
          <name>CCR4</name>
          <addressOffset>0x40</addressOffset>
          <size>0x20</size>
          <fields>
            <field>
              <name>CCR4</name>
              <bitOffset>0</bitOffset>
              <bitWidth>16</bitWidth>
            </field>
          </fields>
        </register>
        <register>
          <name>BDTR</name>
          <addressOffset>0x44</addressOffset>
          <size>0x20</size>
          <fields>
            <field>
              <name>DTG</name>
              <bitOffset>0</bitOffset>
              <bitWidth>8</bitWidth>
            </field>
            <field>
              <name>LOCK</name>
              <bitOffset>8</bitOffset>
              <bitWidth>2</bitWidth>
            </field>
            <field>
              <name>OSSI</name>
              <bitOffset>10</bitOffset>
              <bitWidth>1</bitWidth>
            </field>
            <field>
              <name>OSSR</name>
              <bitOffset>11</bitOffset>
              <bitWidth>1</bitWidth>
            </field>
            <field>
              <name>BKE</name>
              <bitOffset>12</bitOffset>
              <bitWidth>1</bitWidth>
            </field>
            <field>
              <name>BKP</name>
              <bitOffset>13</bitOffset>
              <bitWidth>1</bitWidth>
            </field>
            <field>
              <name>AOE</name>
              <bitOffset>14</bitOffset>
              <bitWidth>1</bitWidth>
            </field>
            <field>
              <name>MOE</name>
              <bitOffset>15</bitOffset>
              <bitWidth>1</bitWidth>
            </field>
            <field>
              <name>BKF</name>
              <bitOffset>16</bitOffset>
              <bitWidth>4</bitWidth>
            </field>
            <field>
              <name>BK2F</name>
              <bitOffset>20</bitOffset>
              <bitWidth>4</bitWidth>
            </field>
            <field>
              <name>BK2E</name>
              <bitOffset>24</bitOffset>
              <bitWidth>1</bitWidth>
            </field>
            <field>
              <name>BK2P</name>
              <bitOffset>25</bitOffset>
              <bitWidth>1</bitWidth>
            </field>
          </fields>
        </register>
        <register>
          <name>DCR</name>
          <addressOffset>0x48</addressOffset>
          <size>0x20</size>
          <fields>
            <field>
              <name>DBA</name>
              <bitOffset>0</bitOffset>
              <bitWidth>5</bitWidth>
            </field>
            <field>
              <name>DBL</name>
              <bitOffset>8</bitOffset>
              <bitWidth>5</bitWidth>
            </field>
          </fields>
        </register>
        <register>
          <name>DMAR</name>
          <addressOffset>0x4c</addressOffset>
          <size>0x20</size>
          <fields>
            <field>
              <name>DMAB</name>
              <bitOffset>0</bitOffset>
              <bitWidth>16</bitWidth>
            </field>
          </fields>
        </register>
        <register>
          <name>CCMR3</name>
          <addressOffset>0x54</addressOffset>
          <size>0x20</size>
          <fields>
            <field>
              <name>OC5FE</name>
              <bitOffset>2</bitOffset>
              <bitWidth>1</bitWidth>
            </field>
            <field>
              <name>OC5PE</name>
              <bitOffset>3</bitOffset>
              <bitWidth>1</bitWidth>
            </field>
            <field>
              <name>OC5M</name>
              <bitOffset>4</bitOffset>
              <bitWidth>13</bitWidth>
            </field>
            <field>
              <name>OC5CE</name>
              <bitOffset>7</bitOffset>
              <bitWidth>1</bitWidth>
            </field>
            <field>
              <name>OC6FE</name>
              <bitOffset>10</bitOffset>
              <bitWidth>1</bitWidth>
            </field>
            <field>
              <name>OC6PE</name>
              <bitOffset>11</bitOffset>
              <bitWidth>1</bitWidth>
            </field>
            <field>
              <name>OC6M</name>
              <bitOffset>12</bitOffset>
              <bitWidth>13</bitWidth>
            </field>
            <field>
              <name>OC6CE</name>
              <bitOffset>15</bitOffset>
              <bitWidth>1</bitWidth>
            </field>
          </fields>
        </register>
        <register>
          <name>CCR5</name>
          <addressOffset>0x58</addressOffset>
          <size>0x20</size>
          <fields>
            <field>
              <name>CCR5</name>
              <bitOffset>0</bitOffset>
              <bitWidth>32</bitWidth>
            </field>
            <field>
              <name>GC5C1</name>
              <bitOffset>29</bitOffset>
              <bitWidth>1</bitWidth>
            </field>
            <field>
              <name>GC5C2</name>
              <bitOffset>30</bitOffset>
              <bitWidth>1</bitWidth>
            </field>
            <field>
              <name>GC5C3</name>
              <bitOffset>31</bitOffset>
              <bitWidth>1</bitWidth>
            </field>
          </fields>
        </register>
        <register>
          <name>CCR6</name>
          <addressOffset>0x5c</addressOffset>
          <size>0x20</size>
          <fields>
            <field>
              <name>CCR6</name>
              <bitOffset>0</bitOffset>
              <bitWidth>16</bitWidth>
            </field>
          </fields>
        </register>
        <register>
          <name>AF1</name>
          <addressOffset>0x60</addressOffset>
          <size>0x20</size>
        </register>
        <register>
          <name>AF2</name>
          <addressOffset>0x64</addressOffset>
          <size>0x20</size>
        </register>
        <register>
          <name>TISEL</name>
          <addressOffset>0x68</addressOffset>
          <size>0x20</size>
          <fields>
            <field>
              <name>TI1SEL</name>
              <bitOffset>0</bitOffset>
              <bitWidth>4</bitWidth>
            </field>
            <field>
              <name>TI2SEL</name>
              <bitOffset>8</bitOffset>
              <bitWidth>4</bitWidth>
            </field>
            <field>
              <name>TI3SEL</name>
              <bitOffset>16</bitOffset>
              <bitWidth>4</bitWidth>
            </field>
            <field>
              <name>TI4SEL</name>
              <bitOffset>24</bitOffset>
              <bitWidth>4</bitWidth>
            </field>
          </fields>
        </register>
      </registers>
    </peripheral>
    <peripheral>
      <name>TIM8</name>
      <baseAddress>0x40010400</baseAddress>
      <registers>
        <register>
          <name>CR1</name>
          <addressOffset>0x0</addressOffset>
          <size>0x20</size>
          <fields>
            <field>
              <name>CEN</name>
              <bitOffset>0</bitOffset>
              <bitWidth>1</bitWidth>
            </field>
            <field>
              <name>UDIS</name>
              <bitOffset>1</bitOffset>
              <bitWidth>1</bitWidth>
            </field>
            <field>
              <name>URS</name>
              <bitOffset>2</bitOffset>
              <bitWidth>1</bitWidth>
            </field>
            <field>
              <name>OPM</name>
              <bitOffset>3</bitOffset>
              <bitWidth>1</bitWidth>
            </field>
            <field>
              <name>DIR</name>
              <bitOffset>4</bitOffset>
              <bitWidth>1</bitWidth>
            </field>
            <field>
              <name>CMS</name>
              <bitOffset>5</bitOffset>
              <bitWidth>2</bitWidth>
            </field>
            <field>
              <name>ARPE</name>
              <bitOffset>7</bitOffset>
              <bitWidth>1</bitWidth>
            </field>
            <field>
              <name>CKD</name>
              <bitOffset>8</bitOffset>
              <bitWidth>2</bitWidth>
            </field>
            <field>
              <name>UIFREMAP</name>
              <bitOffset>11</bitOffset>
              <bitWidth>1</bitWidth>
            </field>
          </fields>
        </register>
        <register>
          <name>CR2</name>
          <addressOffset>0x4</addressOffset>
          <size>0x20</size>
          <fields>
            <field>
              <name>CCPC</name>
              <bitOffset>0</bitOffset>
              <bitWidth>1</bitWidth>
            </field>
            <field>
              <name>CCUS</name>
              <bitOffset>2</bitOffset>
              <bitWidth>1</bitWidth>
            </field>
            <field>
              <name>CCDS</name>
              <bitOffset>3</bitOffset>
              <bitWidth>1</bitWidth>
            </field>
            <field>
              <name>MMS</name>
              <bitOffset>4</bitOffset>
              <bitWidth>3</bitWidth>
            </field>
            <field>
              <name>TI1S</name>
              <bitOffset>7</bitOffset>
              <bitWidth>1</bitWidth>
            </field>
            <field>
              <name>OIS1</name>
              <bitOffset>8</bitOffset>
              <bitWidth>1</bitWidth>
            </field>
            <field>
              <name>OIS1N</name>
              <bitOffset>9</bitOffset>
              <bitWidth>1</bitWidth>
            </field>
            <field>
              <name>OIS2</name>
              <bitOffset>10</bitOffset>
              <bitWidth>1</bitWidth>
            </field>
            <field>
              <name>OIS2N</name>
              <bitOffset>11</bitOffset>
              <bitWidth>1</bitWidth>
            </field>
            <field>
              <name>OIS3</name>
              <bitOffset>12</bitOffset>
              <bitWidth>1</bitWidth>
            </field>
            <field>
              <name>OIS3N</name>
              <bitOffset>13</bitOffset>
              <bitWidth>1</bitWidth>
            </field>
            <field>
              <name>OIS4</name>
              <bitOffset>14</bitOffset>
              <bitWidth>1</bitWidth>
            </field>
            <field>
              <name>OIS5</name>
              <bitOffset>16</bitOffset>
              <bitWidth>1</bitWidth>
            </field>
            <field>
              <name>OIS6</name>
              <bitOffset>18</bitOffset>
              <bitWidth>1</bitWidth>
            </field>
            <field>
              <name>MMS2</name>
              <bitOffset>20</bitOffset>
              <bitWidth>4</bitWidth>
            </field>
          </fields>
        </register>
        <register>
          <name>SMCR</name>
          <addressOffset>0x8</addressOffset>
          <size>0x20</size>
          <fields>
            <field>
              <name>SMS</name>
              <bitOffset>0</bitOffset>
              <bitWidth>17</bitWidth>
            </field>
            <field>
              <name>TS</name>
              <bitOffset>4</bitOffset>
              <bitWidth>18</bitWidth>
            </field>
            <field>
              <name>MSM</name>
              <bitOffset>7</bitOffset>
              <bitWidth>1</bitWidth>
            </field>
            <field>
              <name>ETF</name>
              <bitOffset>8</bitOffset>
              <bitWidth>4</bitWidth>
            </field>
            <field>
              <name>ETPS</name>
              <bitOffset>12</bitOffset>
              <bitWidth>2</bitWidth>
            </field>
            <field>
              <name>ECE</name>
              <bitOffset>14</bitOffset>
              <bitWidth>1</bitWidth>
            </field>
            <field>
              <name>ETP</name>
              <bitOffset>15</bitOffset>
              <bitWidth>1</bitWidth>
            </field>
          </fields>
        </register>
        <register>
          <name>DIER</name>
          <addressOffset>0xc</addressOffset>
          <size>0x20</size>
          <fields>
            <field>
              <name>UIE</name>
              <bitOffset>0</bitOffset>
              <bitWidth>1</bitWidth>
            </field>
            <field>
              <name>CC1IE</name>
              <bitOffset>1</bitOffset>
              <bitWidth>1</bitWidth>
            </field>
            <field>
              <name>CC2IE</name>
              <bitOffset>2</bitOffset>
              <bitWidth>1</bitWidth>
            </field>
            <field>
              <name>CC3IE</name>
              <bitOffset>3</bitOffset>
              <bitWidth>1</bitWidth>
            </field>
            <field>
              <name>CC4IE</name>
              <bitOffset>4</bitOffset>
              <bitWidth>1</bitWidth>
            </field>
            <field>
              <name>COMIE</name>
              <bitOffset>5</bitOffset>
              <bitWidth>1</bitWidth>
            </field>
            <field>
              <name>TIE</name>
              <bitOffset>6</bitOffset>
              <bitWidth>1</bitWidth>
            </field>
            <field>
              <name>BIE</name>
              <bitOffset>7</bitOffset>
              <bitWidth>1</bitWidth>
            </field>
            <field>
              <name>UDE</name>
              <bitOffset>8</bitOffset>
              <bitWidth>1</bitWidth>
            </field>
            <field>
              <name>CC1DE</name>
              <bitOffset>9</bitOffset>
              <bitWidth>1</bitWidth>
            </field>
            <field>
              <name>CC2DE</name>
              <bitOffset>10</bitOffset>
              <bitWidth>1</bitWidth>
            </field>
            <field>
              <name>CC3DE</name>
              <bitOffset>11</bitOffset>
              <bitWidth>1</bitWidth>
            </field>
            <field>
              <name>CC4DE</name>
              <bitOffset>12</bitOffset>
              <bitWidth>1</bitWidth>
            </field>
            <field>
              <name>COMDE</name>
              <bitOffset>13</bitOffset>
              <bitWidth>1</bitWidth>
            </field>
            <field>
              <name>TDE</name>
              <bitOffset>14</bitOffset>
              <bitWidth>1</bitWidth>
            </field>
          </fields>
        </register>
        <register>
          <name>SR</name>
          <addressOffset>0x10</addressOffset>
          <size>0x20</size>
          <fields>
            <field>
              <name>UIF</name>
              <bitOffset>0</bitOffset>
              <bitWidth>1</bitWidth>
            </field>
            <field>
              <name>CC1IF</name>
              <bitOffset>1</bitOffset>
              <bitWidth>1</bitWidth>
            </field>
            <field>
              <name>CC2IF</name>
              <bitOffset>2</bitOffset>
              <bitWidth>1</bitWidth>
            </field>
            <field>
              <name>CC3IF</name>
              <bitOffset>3</bitOffset>
              <bitWidth>1</bitWidth>
            </field>
            <field>
              <name>CC4IF</name>
              <bitOffset>4</bitOffset>
              <bitWidth>1</bitWidth>
            </field>
            <field>
              <name>COMIF</name>
              <bitOffset>5</bitOffset>
              <bitWidth>1</bitWidth>
            </field>
            <field>
              <name>TIF</name>
              <bitOffset>6</bitOffset>
              <bitWidth>1</bitWidth>
            </field>
            <field>
              <name>BIF</name>
              <bitOffset>7</bitOffset>
              <bitWidth>1</bitWidth>
            </field>
            <field>
              <name>B2IF</name>
              <bitOffset>8</bitOffset>
              <bitWidth>1</bitWidth>
            </field>
            <field>
              <name>CC1OF</name>
              <bitOffset>9</bitOffset>
              <bitWidth>1</bitWidth>
            </field>
            <field>
              <name>CC2OF</name>
              <bitOffset>10</bitOffset>
              <bitWidth>1</bitWidth>
            </field>
            <field>
              <name>CC3OF</name>
              <bitOffset>11</bitOffset>
              <bitWidth>1</bitWidth>
            </field>
            <field>
              <name>CC4OF</name>
              <bitOffset>12</bitOffset>
              <bitWidth>1</bitWidth>
            </field>
            <field>
              <name>SBIF</name>
              <bitOffset>13</bitOffset>
              <bitWidth>1</bitWidth>
            </field>
            <field>
              <name>CC5IF</name>
              <bitOffset>16</bitOffset>
              <bitWidth>1</bitWidth>
            </field>
            <field>
              <name>CC6IF</name>
              <bitOffset>17</bitOffset>
              <bitWidth>1</bitWidth>
            </field>
          </fields>
        </register>
        <register>
          <name>EGR</name>
          <addressOffset>0x14</addressOffset>
          <size>0x20</size>
          <fields>
            <field>
              <name>UG</name>
              <bitOffset>0</bitOffset>
              <bitWidth>1</bitWidth>
            </field>
            <field>
              <name>CC1G</name>
              <bitOffset>1</bitOffset>
              <bitWidth>1</bitWidth>
            </field>
            <field>
              <name>CC2G</name>
              <bitOffset>2</bitOffset>
              <bitWidth>1</bitWidth>
            </field>
            <field>
              <name>CC3G</name>
              <bitOffset>3</bitOffset>
              <bitWidth>1</bitWidth>
            </field>
            <field>
              <name>CC4G</name>
              <bitOffset>4</bitOffset>
              <bitWidth>1</bitWidth>
            </field>
            <field>
              <name>COMG</name>
              <bitOffset>5</bitOffset>
              <bitWidth>1</bitWidth>
            </field>
            <field>
              <name>TG</name>
              <bitOffset>6</bitOffset>
              <bitWidth>1</bitWidth>
            </field>
            <field>
              <name>BG</name>
              <bitOffset>7</bitOffset>
              <bitWidth>1</bitWidth>
            </field>
            <field>
              <name>B2G</name>
              <bitOffset>8</bitOffset>
              <bitWidth>1</bitWidth>
            </field>
          </fields>
        </register>
        <register>
          <name>CCMR1</name>
          <addressOffset>0x18</addressOffset>
          <size>0x20</size>
          <fields>
            <field>
              <name>CC1S</name>
              <bitOffset>0</bitOffset>
              <bitWidth>2</bitWidth>
            </field>
            <field>
              <name>OC1FE</name>
              <bitOffset>2</bitOffset>
              <bitWidth>1</bitWidth>
            </field>
            <field>
              <name>OC1PE</name>
              <bitOffset>3</bitOffset>
              <bitWidth>1</bitWidth>
            </field>
            <field>
              <name>OC1M</name>
              <bitOffset>4</bitOffset>
              <bitWidth>13</bitWidth>
            </field>
            <field>
              <name>OC1CE</name>
              <bitOffset>7</bitOffset>
              <bitWidth>1</bitWidth>
            </field>
            <field>
              <name>CC2S</name>
              <bitOffset>8</bitOffset>
              <bitWidth>2</bitWidth>
            </field>
            <field>
              <name>OC2FE</name>
              <bitOffset>10</bitOffset>
              <bitWidth>1</bitWidth>
            </field>
            <field>
              <name>OC2PE</name>
              <bitOffset>11</bitOffset>
              <bitWidth>1</bitWidth>
            </field>
            <field>
              <name>OC2M</name>
              <bitOffset>12</bitOffset>
              <bitWidth>13</bitWidth>
            </field>
            <field>
              <name>OC2CE</name>
              <bitOffset>15</bitOffset>
              <bitWidth>1</bitWidth>
            </field>
          </fields>
        </register>
        <register>
          <name>CCMR2</name>
          <addressOffset>0x1c</addressOffset>
          <size>0x20</size>
          <fields>
            <field>
              <name>CC3S</name>
              <bitOffset>0</bitOffset>
              <bitWidth>2</bitWidth>
            </field>
            <field>
              <name>OC3FE</name>
              <bitOffset>2</bitOffset>
              <bitWidth>1</bitWidth>
            </field>
            <field>
              <name>OC3PE</name>
              <bitOffset>3</bitOffset>
              <bitWidth>1</bitWidth>
            </field>
            <field>
              <name>OC3M</name>
              <bitOffset>4</bitOffset>
              <bitWidth>13</bitWidth>
            </field>
            <field>
              <name>OC3CE</name>
              <bitOffset>7</bitOffset>
              <bitWidth>1</bitWidth>
            </field>
            <field>
              <name>CC4S</name>
              <bitOffset>8</bitOffset>
              <bitWidth>2</bitWidth>
            </field>
            <field>
              <name>OC4FE</name>
              <bitOffset>10</bitOffset>
              <bitWidth>1</bitWidth>
            </field>
            <field>
              <name>OC4PE</name>
              <bitOffset>11</bitOffset>
              <bitWidth>1</bitWidth>
            </field>
            <field>
              <name>OC4M</name>
              <bitOffset>12</bitOffset>
              <bitWidth>13</bitWidth>
            </field>
            <field>
              <name>OC4CE</name>
              <bitOffset>15</bitOffset>
              <bitWidth>1</bitWidth>
            </field>
          </fields>
        </register>
        <register>
          <name>CCER</name>
          <addressOffset>0x20</addressOffset>
          <size>0x20</size>
          <fields>
            <field>
              <name>CC1E</name>
              <bitOffset>0</bitOffset>
              <bitWidth>1</bitWidth>
            </field>
            <field>
              <name>CC1P</name>
              <bitOffset>1</bitOffset>
              <bitWidth>1</bitWidth>
            </field>
            <field>
              <name>CC1NE</name>
              <bitOffset>2</bitOffset>
              <bitWidth>1</bitWidth>
            </field>
            <field>
              <name>CC1NP</name>
              <bitOffset>3</bitOffset>
              <bitWidth>1</bitWidth>
            </field>
            <field>
              <name>CC2E</name>
              <bitOffset>4</bitOffset>
              <bitWidth>1</bitWidth>
            </field>
            <field>
              <name>CC2P</name>
              <bitOffset>5</bitOffset>
              <bitWidth>1</bitWidth>
            </field>
            <field>
              <name>CC2NE</name>
              <bitOffset>6</bitOffset>
              <bitWidth>1</bitWidth>
            </field>
            <field>
              <name>CC2NP</name>
              <bitOffset>7</bitOffset>
              <bitWidth>1</bitWidth>
            </field>
            <field>
              <name>CC3E</name>
              <bitOffset>8</bitOffset>
              <bitWidth>1</bitWidth>
            </field>
            <field>
              <name>CC3P</name>
              <bitOffset>9</bitOffset>
              <bitWidth>1</bitWidth>
            </field>
            <field>
              <name>CC3NE</name>
              <bitOffset>10</bitOffset>
              <bitWidth>1</bitWidth>
            </field>
            <field>
              <name>CC3NP</name>
              <bitOffset>11</bitOffset>
              <bitWidth>1</bitWidth>
            </field>
            <field>
              <name>CC4E</name>
              <bitOffset>12</bitOffset>
              <bitWidth>1</bitWidth>
            </field>
            <field>
              <name>CC4P</name>
              <bitOffset>13</bitOffset>
              <bitWidth>1</bitWidth>
            </field>
            <field>
              <name>CC4NP</name>
              <bitOffset>15</bitOffset>
              <bitWidth>1</bitWidth>
            </field>
            <field>
              <name>CC5E</name>
              <bitOffset>16</bitOffset>
              <bitWidth>1</bitWidth>
            </field>
            <field>
              <name>CC5P</name>
              <bitOffset>17</bitOffset>
              <bitWidth>1</bitWidth>
            </field>
            <field>
              <name>CC6E</name>
              <bitOffset>20</bitOffset>
              <bitWidth>1</bitWidth>
            </field>
            <field>
              <name>CC6P</name>
              <bitOffset>21</bitOffset>
              <bitWidth>1</bitWidth>
            </field>
          </fields>
        </register>
        <register>
          <name>CNT</name>
          <addressOffset>0x24</addressOffset>
          <size>0x20</size>
          <fields>
            <field>
              <name>CNT</name>
              <bitOffset>0</bitOffset>
              <bitWidth>32</bitWidth>
            </field>
            <field>
              <name>UIFCPY</name>
              <bitOffset>31</bitOffset>
              <bitWidth>1</bitWidth>
            </field>
          </fields>
        </register>
        <register>
          <name>PSC</name>
          <addressOffset>0x28</addressOffset>
          <size>0x20</size>
          <fields>
            <field>
              <name>PSC</name>
              <bitOffset>0</bitOffset>
              <bitWidth>16</bitWidth>
            </field>
          </fields>
        </register>
        <register>
          <name>ARR</name>
          <addressOffset>0x2c</addressOffset>
          <size>0x20</size>
          <fields>
            <field>
              <name>ARR</name>
              <bitOffset>0</bitOffset>
              <bitWidth>32</bitWidth>
            </field>
          </fields>
        </register>
        <register>
          <name>RCR</name>
          <addressOffset>0x30</addressOffset>
          <size>0x20</size>
          <fields>
            <field>
              <name>REP</name>
              <bitOffset>0</bitOffset>
              <bitWidth>8</bitWidth>
            </field>
          </fields>
        </register>
        <register>
          <name>CCR1</name>
          <addressOffset>0x34</addressOffset>
          <size>0x20</size>
          <fields>
            <field>
              <name>CCR1</name>
              <bitOffset>0</bitOffset>
              <bitWidth>16</bitWidth>
            </field>
          </fields>
        </register>
        <register>
          <name>CCR2</name>
          <addressOffset>0x38</addressOffset>
          <size>0x20</size>
          <fields>
            <field>
              <name>CCR2</name>
              <bitOffset>0</bitOffset>
              <bitWidth>16</bitWidth>
            </field>
          </fields>
        </register>
        <register>
          <name>CCR3</name>
          <addressOffset>0x3c</addressOffset>
          <size>0x20</size>
          <fields>
            <field>
              <name>CCR3</name>
              <bitOffset>0</bitOffset>
              <bitWidth>16</bitWidth>
            </field>
          </fields>
        </register>
        <register>
          <name>CCR4</name>
          <addressOffset>0x40</addressOffset>
          <size>0x20</size>
          <fields>
            <field>
              <name>CCR4</name>
              <bitOffset>0</bitOffset>
              <bitWidth>16</bitWidth>
            </field>
          </fields>
        </register>
        <register>
          <name>BDTR</name>
          <addressOffset>0x44</addressOffset>
          <size>0x20</size>
          <fields>
            <field>
              <name>DTG</name>
              <bitOffset>0</bitOffset>
              <bitWidth>8</bitWidth>
            </field>
            <field>
              <name>LOCK</name>
              <bitOffset>8</bitOffset>
              <bitWidth>2</bitWidth>
            </field>
            <field>
              <name>OSSI</name>
              <bitOffset>10</bitOffset>
              <bitWidth>1</bitWidth>
            </field>
            <field>
              <name>OSSR</name>
              <bitOffset>11</bitOffset>
              <bitWidth>1</bitWidth>
            </field>
            <field>
              <name>BKE</name>
              <bitOffset>12</bitOffset>
              <bitWidth>1</bitWidth>
            </field>
            <field>
              <name>BKP</name>
              <bitOffset>13</bitOffset>
              <bitWidth>1</bitWidth>
            </field>
            <field>
              <name>AOE</name>
              <bitOffset>14</bitOffset>
              <bitWidth>1</bitWidth>
            </field>
            <field>
              <name>MOE</name>
              <bitOffset>15</bitOffset>
              <bitWidth>1</bitWidth>
            </field>
            <field>
              <name>BKF</name>
              <bitOffset>16</bitOffset>
              <bitWidth>4</bitWidth>
            </field>
            <field>
              <name>BK2F</name>
              <bitOffset>20</bitOffset>
              <bitWidth>4</bitWidth>
            </field>
            <field>
              <name>BK2E</name>
              <bitOffset>24</bitOffset>
              <bitWidth>1</bitWidth>
            </field>
            <field>
              <name>BK2P</name>
              <bitOffset>25</bitOffset>
              <bitWidth>1</bitWidth>
            </field>
          </fields>
        </register>
        <register>
          <name>DCR</name>
          <addressOffset>0x48</addressOffset>
          <size>0x20</size>
          <fields>
            <field>
              <name>DBA</name>
              <bitOffset>0</bitOffset>
              <bitWidth>5</bitWidth>
            </field>
            <field>
              <name>DBL</name>
              <bitOffset>8</bitOffset>
              <bitWidth>5</bitWidth>
            </field>
          </fields>
        </register>
        <register>
          <name>DMAR</name>
          <addressOffset>0x4c</addressOffset>
          <size>0x20</size>
          <fields>
            <field>
              <name>DMAB</name>
              <bitOffset>0</bitOffset>
              <bitWidth>16</bitWidth>
            </field>
          </fields>
        </register>
        <register>
          <name>CCMR3</name>
          <addressOffset>0x54</addressOffset>
          <size>0x20</size>
          <fields>
            <field>
              <name>OC5FE</name>
              <bitOffset>2</bitOffset>
              <bitWidth>1</bitWidth>
            </field>
            <field>
              <name>OC5PE</name>
              <bitOffset>3</bitOffset>
              <bitWidth>1</bitWidth>
            </field>
            <field>
              <name>OC5M</name>
              <bitOffset>4</bitOffset>
              <bitWidth>13</bitWidth>
            </field>
            <field>
              <name>OC5CE</name>
              <bitOffset>7</bitOffset>
              <bitWidth>1</bitWidth>
            </field>
            <field>
              <name>OC6FE</name>
              <bitOffset>10</bitOffset>
              <bitWidth>1</bitWidth>
            </field>
            <field>
              <name>OC6PE</name>
              <bitOffset>11</bitOffset>
              <bitWidth>1</bitWidth>
            </field>
            <field>
              <name>OC6M</name>
              <bitOffset>12</bitOffset>
              <bitWidth>13</bitWidth>
            </field>
            <field>
              <name>OC6CE</name>
              <bitOffset>15</bitOffset>
              <bitWidth>1</bitWidth>
            </field>
          </fields>
        </register>
        <register>
          <name>CCR5</name>
          <addressOffset>0x58</addressOffset>
          <size>0x20</size>
          <fields>
            <field>
              <name>CCR5</name>
              <bitOffset>0</bitOffset>
              <bitWidth>32</bitWidth>
            </field>
            <field>
              <name>GC5C1</name>
              <bitOffset>29</bitOffset>
              <bitWidth>1</bitWidth>
            </field>
            <field>
              <name>GC5C2</name>
              <bitOffset>30</bitOffset>
              <bitWidth>1</bitWidth>
            </field>
            <field>
              <name>GC5C3</name>
              <bitOffset>31</bitOffset>
              <bitWidth>1</bitWidth>
            </field>
          </fields>
        </register>
        <register>
          <name>CCR6</name>
          <addressOffset>0x5c</addressOffset>
          <size>0x20</size>
          <fields>
            <field>
              <name>CCR6</name>
              <bitOffset>0</bitOffset>
              <bitWidth>16</bitWidth>
            </field>
          </fields>
        </register>
        <register>
          <name>AF1</name>
          <addressOffset>0x60</addressOffset>
          <size>0x20</size>
        </register>
        <register>
          <name>AF2</name>
          <addressOffset>0x64</addressOffset>
          <size>0x20</size>
        </register>
        <register>
          <name>TISEL</name>
          <addressOffset>0x68</addressOffset>
          <size>0x20</size>
          <fields>
            <field>
              <name>TI1SEL</name>
              <bitOffset>0</bitOffset>
              <bitWidth>4</bitWidth>
            </field>
            <field>
              <name>TI2SEL</name>
              <bitOffset>8</bitOffset>
              <bitWidth>4</bitWidth>
            </field>
            <field>
              <name>TI3SEL</name>
              <bitOffset>16</bitOffset>
              <bitWidth>4</bitWidth>
            </field>
            <field>
              <name>TI4SEL</name>
              <bitOffset>24</bitOffset>
              <bitWidth>4</bitWidth>
            </field>
          </fields>
        </register>
      </registers>
    </peripheral>
    <peripheral>
      <name>USART1</name>
      <baseAddress>0x40011000</baseAddress>
      <registers>
        <register>
          <name>CR1</name>
          <addressOffset>0x0</addressOffset>
          <size>0x20</size>
          <fields>
            <field>
              <name>UE</name>
              <bitOffset>0</bitOffset>
              <bitWidth>1</bitWidth>
            </field>
            <field>
              <name>UESM</name>
              <bitOffset>1</bitOffset>
              <bitWidth>1</bitWidth>
            </field>
            <field>
              <name>RE</name>
              <bitOffset>2</bitOffset>
              <bitWidth>1</bitWidth>
            </field>
            <field>
              <name>TE</name>
              <bitOffset>3</bitOffset>
              <bitWidth>1</bitWidth>
            </field>
            <field>
              <name>IDLEIE</name>
              <bitOffset>4</bitOffset>
              <bitWidth>1</bitWidth>
            </field>
            <field>
              <name>RXNEIE_RXFNEIE</name>
              <bitOffset>5</bitOffset>
              <bitWidth>1</bitWidth>
            </field>
            <field>
              <name>TCIE</name>
              <bitOffset>6</bitOffset>
              <bitWidth>1</bitWidth>
            </field>
            <field>
              <name>TXEIE_TXFNFIE</name>
              <bitOffset>7</bitOffset>
              <bitWidth>1</bitWidth>
            </field>
            <field>
              <name>PEIE</name>
              <bitOffset>8</bitOffset>
              <bitWidth>1</bitWidth>
            </field>
            <field>
              <name>PS</name>
              <bitOffset>9</bitOffset>
              <bitWidth>1</bitWidth>
            </field>
            <field>
              <name>PCE</name>
              <bitOffset>10</bitOffset>
              <bitWidth>1</bitWidth>
            </field>
            <field>
              <name>WAKE</name>
              <bitOffset>11</bitOffset>
              <bitWidth>1</bitWidth>
            </field>
            <field>
              <name>M0</name>
              <bitOffset>12</bitOffset>
              <bitWidth>1</bitWidth>
            </field>
            <field>
              <name>MME</name>
              <bitOffset>13</bitOffset>
              <bitWidth>1</bitWidth>
            </field>
            <field>
              <name>CMIE</name>
              <bitOffset>14</bitOffset>
              <bitWidth>1</bitWidth>
            </field>
            <field>
              <name>OVER8</name>
              <bitOffset>15</bitOffset>
              <bitWidth>1</bitWidth>
            </field>
            <field>
              <name>DEDT</name>
              <bitOffset>16</bitOffset>
              <bitWidth>5</bitWidth>
            </field>
            <field>
              <name>DEAT</name>
              <bitOffset>21</bitOffset>
              <bitWidth>5</bitWidth>
            </field>
            <field>
              <name>RTOIE</name>
              <bitOffset>26</bitOffset>
              <bitWidth>1</bitWidth>
            </field>
            <field>
              <name>EOBIE</name>
              <bitOffset>27</bitOffset>
              <bitWidth>1</bitWidth>
            </field>
            <field>
              <name>M1</name>
              <bitOffset>28</bitOffset>
              <bitWidth>1</bitWidth>
            </field>
            <field>
              <name>FIFOEN</name>
              <bitOffset>29</bitOffset>
              <bitWidth>1</bitWidth>
            </field>
            <field>
              <name>TXFEIE</name>
              <bitOffset>30</bitOffset>
              <bitWidth>1</bitWidth>
            </field>
            <field>
              <name>RXFFIE</name>
              <bitOffset>31</bitOffset>
              <bitWidth>1</bitWidth>
            </field>
          </fields>
        </register>
        <register>
          <name>CR2</name>
          <addressOffset>0x4</addressOffset>
          <size>0x20</size>
          <fields>
            <field>
              <name>SLVEN</name>
              <bitOffset>0</bitOffset>
              <bitWidth>1</bitWidth>
            </field>
            <field>
              <name>DIS_NSS</name>
              <bitOffset>3</bitOffset>
              <bitWidth>1</bitWidth>
            </field>
            <field>
              <name>ADDM7</name>
              <bitOffset>4</bitOffset>
              <bitWidth>1</bitWidth>
            </field>
            <field>
              <name>LBDL</name>
              <bitOffset>5</bitOffset>
              <bitWidth>1</bitWidth>
            </field>
            <field>
              <name>LBDIE</name>
              <bitOffset>6</bitOffset>
              <bitWidth>1</bitWidth>
            </field>
            <field>
              <name>LBCL</name>
              <bitOffset>8</bitOffset>
              <bitWidth>1</bitWidth>
            </field>
            <field>
              <name>CPHA</name>
              <bitOffset>9</bitOffset>
              <bitWidth>1</bitWidth>
            </field>
            <field>
              <name>CPOL</name>
              <bitOffset>10</bitOffset>
              <bitWidth>1</bitWidth>
            </field>
            <field>
              <name>CLKEN</name>
              <bitOffset>11</bitOffset>
              <bitWidth>1</bitWidth>
            </field>
            <field>
              <name>STOP</name>
              <bitOffset>12</bitOffset>
              <bitWidth>2</bitWidth>
            </field>
            <field>
              <name>LINEN</name>
              <bitOffset>14</bitOffset>
              <bitWidth>1</bitWidth>
            </field>
            <field>
              <name>SWAP</name>
              <bitOffset>15</bitOffset>
              <bitWidth>1</bitWidth>
            </field>
            <field>
              <name>RXINV</name>
              <bitOffset>16</bitOffset>
              <bitWidth>1</bitWidth>
            </field>
            <field>
              <name>TXINV</name>
              <bitOffset>17</bitOffset>
              <bitWidth>1</bitWidth>
            </field>
            <field>
              <name>DATAINV</name>
              <bitOffset>18</bitOffset>
              <bitWidth>1</bitWidth>
            </field>
            <field>
              <name>MSBFIRST</name>
              <bitOffset>19</bitOffset>
              <bitWidth>1</bitWidth>
            </field>
            <field>
              <name>ABREN</name>
              <bitOffset>20</bitOffset>
              <bitWidth>1</bitWidth>
            </field>
            <field>
              <name>ABRMODE</name>
              <bitOffset>21</bitOffset>
              <bitWidth>2</bitWidth>
            </field>
            <field>
              <name>RTOEN</name>
              <bitOffset>23</bitOffset>
              <bitWidth>1</bitWidth>
            </field>
            <field>
              <name>ADD</name>
              <bitOffset>24</bitOffset>
              <bitWidth>8</bitWidth>
            </field>
          </fields>
        </register>
        <register>
          <name>CR3</name>
          <addressOffset>0x8</addressOffset>
          <size>0x20</size>
          <fields>
            <field>
              <name>EIE</name>
              <bitOffset>0</bitOffset>
              <bitWidth>1</bitWidth>
            </field>
            <field>
              <name>IREN</name>
              <bitOffset>1</bitOffset>
              <bitWidth>1</bitWidth>
            </field>
            <field>
              <name>IRLP</name>
              <bitOffset>2</bitOffset>
              <bitWidth>1</bitWidth>
            </field>
            <field>
              <name>HDSEL</name>
              <bitOffset>3</bitOffset>
              <bitWidth>1</bitWidth>
            </field>
            <field>
              <name>NACK</name>
              <bitOffset>4</bitOffset>
              <bitWidth>1</bitWidth>
            </field>
            <field>
              <name>SCEN</name>
              <bitOffset>5</bitOffset>
              <bitWidth>1</bitWidth>
            </field>
            <field>
              <name>DMAR</name>
              <bitOffset>6</bitOffset>
              <bitWidth>1</bitWidth>
            </field>
            <field>
              <name>DMAT</name>
              <bitOffset>7</bitOffset>
              <bitWidth>1</bitWidth>
            </field>
            <field>
              <name>RTSE</name>
              <bitOffset>8</bitOffset>
              <bitWidth>1</bitWidth>
            </field>
            <field>
              <name>CTSE</name>
              <bitOffset>9</bitOffset>
              <bitWidth>1</bitWidth>
            </field>
            <field>
              <name>CTSIE</name>
              <bitOffset>10</bitOffset>
              <bitWidth>1</bitWidth>
            </field>
            <field>
              <name>ONEBIT</name>
              <bitOffset>11</bitOffset>
              <bitWidth>1</bitWidth>
            </field>
            <field>
              <name>OVRDIS</name>
              <bitOffset>12</bitOffset>
              <bitWidth>1</bitWidth>
            </field>
            <field>
              <name>DDRE</name>
              <bitOffset>13</bitOffset>
              <bitWidth>1</bitWidth>
            </field>
            <field>
              <name>DEM</name>
              <bitOffset>14</bitOffset>
              <bitWidth>1</bitWidth>
            </field>
            <field>
              <name>DEP</name>
              <bitOffset>15</bitOffset>
              <bitWidth>1</bitWidth>
            </field>
            <field>
              <name>SCARCNT</name>
              <bitOffset>17</bitOffset>
              <bitWidth>3</bitWidth>
            </field>
            <field>
              <name>WUS</name>
              <bitOffset>20</bitOffset>
              <bitWidth>2</bitWidth>
            </field>
            <field>
              <name>WUFIE</name>
              <bitOffset>22</bitOffset>
              <bitWidth>1</bitWidth>
            </field>
            <field>
              <name>TXFTIE</name>
              <bitOffset>23</bitOffset>
              <bitWidth>1</bitWidth>
            </field>
            <field>
              <name>TCBGTIE</name>
              <bitOffset>24</bitOffset>
              <bitWidth>1</bitWidth>
            </field>
            <field>
              <name>RXFTCFG</name>
              <bitOffset>25</bitOffset>
              <bitWidth>3</bitWidth>
            </field>
            <field>
              <name>RXFTIE</name>
              <bitOffset>28</bitOffset>
              <bitWidth>1</bitWidth>
            </field>
            <field>
              <name>TXFTCFG</name>
              <bitOffset>29</bitOffset>
              <bitWidth>3</bitWidth>
            </field>
          </fields>
        </register>
        <register>
          <name>BRR</name>
          <addressOffset>0xc</addressOffset>
          <size>0x20</size>
          <fields>
            <field>
              <name>DIV_FRACTION</name>
              <bitOffset>0</bitOffset>
              <bitWidth>4</bitWidth>
            </field>
            <field>
              <name>DIV_MANTISSA</name>
              <bitOffset>4</bitOffset>
              <bitWidth>12</bitWidth>
            </field>
          </fields>
        </register>
        <register>
          <name>GTPR</name>
          <addressOffset>0x10</addressOffset>
          <size>0x20</size>
          <fields>
            <field>
              <name>PSC</name>
              <bitOffset>0</bitOffset>
              <bitWidth>8</bitWidth>
            </field>
            <field>
              <name>GT</name>
              <bitOffset>8</bitOffset>
              <bitWidth>8</bitWidth>
            </field>
          </fields>
        </register>
        <register>
          <name>RTOR</name>
          <addressOffset>0x14</addressOffset>
          <size>0x20</size>
          <fields>
            <field>
              <name>RTO</name>
              <bitOffset>0</bitOffset>
              <bitWidth>24</bitWidth>
            </field>
            <field>
              <name>BLEN</name>
              <bitOffset>24</bitOffset>
              <bitWidth>8</bitWidth>
            </field>
          </fields>
        </register>
        <register>
          <name>RQR</name>
          <addressOffset>0x18</addressOffset>
          <size>0x20</size>
          <fields>
            <field>
              <name>ABRRQ</name>
              <bitOffset>0</bitOffset>
              <bitWidth>1</bitWidth>
            </field>
            <field>
              <name>SBKRQ</name>
              <bitOffset>1</bitOffset>
              <bitWidth>1</bitWidth>
            </field>
            <field>
              <name>MMRQ</name>
              <bitOffset>2</bitOffset>
              <bitWidth>1</bitWidth>
            </field>
            <field>
              <name>RXFRQ</name>
              <bitOffset>3</bitOffset>
              <bitWidth>1</bitWidth>
            </field>
            <field>
              <name>TXFRQ</name>
              <bitOffset>4</bitOffset>
              <bitWidth>1</bitWidth>
            </field>
          </fields>
        </register>
        <register>
          <name>ISR</name>
          <addressOffset>0x1c</addressOffset>
          <size>0x20</size>
          <fields>
            <field>
              <name>PE</name>
              <bitOffset>0</bitOffset>
              <bitWidth>1</bitWidth>
            </field>
            <field>
              <name>FE</name>
              <bitOffset>1</bitOffset>
              <bitWidth>1</bitWidth>
            </field>
            <field>
              <name>NE</name>
              <bitOffset>2</bitOffset>
              <bitWidth>1</bitWidth>
            </field>
            <field>
              <name>ORE</name>
              <bitOffset>3</bitOffset>
              <bitWidth>1</bitWidth>
            </field>
            <field>
              <name>IDLE</name>
              <bitOffset>4</bitOffset>
              <bitWidth>1</bitWidth>
            </field>
            <field>
              <name>RXNE_RXFNE</name>
              <bitOffset>5</bitOffset>
              <bitWidth>1</bitWidth>
            </field>
            <field>
              <name>TC</name>
              <bitOffset>6</bitOffset>
              <bitWidth>1</bitWidth>
            </field>
            <field>
              <name>TXE_TXFNF</name>
              <bitOffset>7</bitOffset>
              <bitWidth>1</bitWidth>
            </field>
            <field>
              <name>LBDF</name>
              <bitOffset>8</bitOffset>
              <bitWidth>1</bitWidth>
            </field>
            <field>
              <name>CTSIF</name>
              <bitOffset>9</bitOffset>
              <bitWidth>1</bitWidth>
            </field>
            <field>
              <name>CTS</name>
              <bitOffset>10</bitOffset>
              <bitWidth>1</bitWidth>
            </field>
            <field>
              <name>RTOF</name>
              <bitOffset>11</bitOffset>
              <bitWidth>1</bitWidth>
            </field>
            <field>
              <name>EOBF</name>
              <bitOffset>12</bitOffset>
              <bitWidth>1</bitWidth>
            </field>
            <field>
              <name>UDR</name>
              <bitOffset>13</bitOffset>
              <bitWidth>1</bitWidth>
            </field>
            <field>
              <name>ABRE</name>
              <bitOffset>14</bitOffset>
              <bitWidth>1</bitWidth>
            </field>
            <field>
              <name>ABRF</name>
              <bitOffset>15</bitOffset>
              <bitWidth>1</bitWidth>
            </field>
            <field>
              <name>BUSY</name>
              <bitOffset>16</bitOffset>
              <bitWidth>1</bitWidth>
            </field>
            <field>
              <name>CMF</name>
              <bitOffset>17</bitOffset>
              <bitWidth>1</bitWidth>
            </field>
            <field>
              <name>SBKF</name>
              <bitOffset>18</bitOffset>
              <bitWidth>1</bitWidth>
            </field>
            <field>
              <name>RWU</name>
              <bitOffset>19</bitOffset>
              <bitWidth>1</bitWidth>
            </field>
            <field>
              <name>WUF</name>
              <bitOffset>20</bitOffset>
              <bitWidth>1</bitWidth>
            </field>
            <field>
              <name>TEACK</name>
              <bitOffset>21</bitOffset>
              <bitWidth>1</bitWidth>
            </field>
            <field>
              <name>REACK</name>
              <bitOffset>22</bitOffset>
              <bitWidth>1</bitWidth>
            </field>
            <field>
              <name>TXFE</name>
              <bitOffset>23</bitOffset>
              <bitWidth>1</bitWidth>
            </field>
            <field>
              <name>RXFF</name>
              <bitOffset>24</bitOffset>
              <bitWidth>1</bitWidth>
            </field>
            <field>
              <name>TCBGT</name>
              <bitOffset>25</bitOffset>
              <bitWidth>1</bitWidth>
            </field>
            <field>
              <name>RXFT</name>
              <bitOffset>26</bitOffset>
              <bitWidth>1</bitWidth>
            </field>
            <field>
              <name>TXFT</name>
              <bitOffset>27</bitOffset>
              <bitWidth>1</bitWidth>
            </field>
          </fields>
        </register>
        <register>
          <name>ICR</name>
          <addressOffset>0x20</addressOffset>
          <size>0x20</size>
          <fields>
            <field>
              <name>PECF</name>
              <bitOffset>0</bitOffset>
              <bitWidth>1</bitWidth>
            </field>
            <field>
              <name>FECF</name>
              <bitOffset>1</bitOffset>
              <bitWidth>1</bitWidth>
            </field>
            <field>
              <name>NECF</name>
              <bitOffset>2</bitOffset>
              <bitWidth>1</bitWidth>
            </field>
            <field>
              <name>ORECF</name>
              <bitOffset>3</bitOffset>
              <bitWidth>1</bitWidth>
            </field>
            <field>
              <name>IDLECF</name>
              <bitOffset>4</bitOffset>
              <bitWidth>1</bitWidth>
            </field>
            <field>
              <name>TXFECF</name>
              <bitOffset>5</bitOffset>
              <bitWidth>1</bitWidth>
            </field>
            <field>
              <name>TCCF</name>
              <bitOffset>6</bitOffset>
              <bitWidth>1</bitWidth>
            </field>
            <field>
              <name>TCBGTCF</name>
              <bitOffset>7</bitOffset>
              <bitWidth>1</bitWidth>
            </field>
            <field>
              <name>LBDCF</name>
              <bitOffset>8</bitOffset>
              <bitWidth>1</bitWidth>
            </field>
            <field>
              <name>CTSCF</name>
              <bitOffset>9</bitOffset>
              <bitWidth>1</bitWidth>
            </field>
            <field>
              <name>RTOCF</name>
              <bitOffset>11</bitOffset>
              <bitWidth>1</bitWidth>
            </field>
            <field>
              <name>EOBCF</name>
              <bitOffset>12</bitOffset>
              <bitWidth>1</bitWidth>
            </field>
            <field>
              <name>UDRCF</name>
              <bitOffset>13</bitOffset>
              <bitWidth>1</bitWidth>
            </field>
            <field>
              <name>CMCF</name>
              <bitOffset>17</bitOffset>
              <bitWidth>1</bitWidth>
            </field>
            <field>
              <name>WUCF</name>
              <bitOffset>20</bitOffset>
              <bitWidth>1</bitWidth>
            </field>
          </fields>
        </register>
        <register>
          <name>RDR</name>
          <addressOffset>0x24</addressOffset>
          <size>0x20</size>
          <fields>
            <field>
              <name>RDR</name>
              <bitOffset>0</bitOffset>
              <bitWidth>9</bitWidth>
            </field>
          </fields>
        </register>
        <register>
          <name>TDR</name>
          <addressOffset>0x28</addressOffset>
          <size>0x20</size>
          <fields>
            <field>
              <name>TDR</name>
              <bitOffset>0</bitOffset>
              <bitWidth>9</bitWidth>
            </field>
          </fields>
        </register>
        <register>
          <name>PRESC</name>
          <addressOffset>0x2c</addressOffset>
          <size>0x20</size>
          <fields>
            <field>
              <name>PRESCALER</name>
              <bitOffset>0</bitOffset>
              <bitWidth>4</bitWidth>
            </field>
          </fields>
        </register>
      </registers>
    </peripheral>
    <peripheral>
      <name>USART6</name>
      <baseAddress>0x40011400</baseAddress>
      <registers>
        <register>
          <name>CR1</name>
          <addressOffset>0x0</addressOffset>
          <size>0x20</size>
          <fields>
            <field>
              <name>UE</name>
              <bitOffset>0</bitOffset>
              <bitWidth>1</bitWidth>
            </field>
            <field>
              <name>UESM</name>
              <bitOffset>1</bitOffset>
              <bitWidth>1</bitWidth>
            </field>
            <field>
              <name>RE</name>
              <bitOffset>2</bitOffset>
              <bitWidth>1</bitWidth>
            </field>
            <field>
              <name>TE</name>
              <bitOffset>3</bitOffset>
              <bitWidth>1</bitWidth>
            </field>
            <field>
              <name>IDLEIE</name>
              <bitOffset>4</bitOffset>
              <bitWidth>1</bitWidth>
            </field>
            <field>
              <name>RXNEIE_RXFNEIE</name>
              <bitOffset>5</bitOffset>
              <bitWidth>1</bitWidth>
            </field>
            <field>
              <name>TCIE</name>
              <bitOffset>6</bitOffset>
              <bitWidth>1</bitWidth>
            </field>
            <field>
              <name>TXEIE_TXFNFIE</name>
              <bitOffset>7</bitOffset>
              <bitWidth>1</bitWidth>
            </field>
            <field>
              <name>PEIE</name>
              <bitOffset>8</bitOffset>
              <bitWidth>1</bitWidth>
            </field>
            <field>
              <name>PS</name>
              <bitOffset>9</bitOffset>
              <bitWidth>1</bitWidth>
            </field>
            <field>
              <name>PCE</name>
              <bitOffset>10</bitOffset>
              <bitWidth>1</bitWidth>
            </field>
            <field>
              <name>WAKE</name>
              <bitOffset>11</bitOffset>
              <bitWidth>1</bitWidth>
            </field>
            <field>
              <name>M0</name>
              <bitOffset>12</bitOffset>
              <bitWidth>1</bitWidth>
            </field>
            <field>
              <name>MME</name>
              <bitOffset>13</bitOffset>
              <bitWidth>1</bitWidth>
            </field>
            <field>
              <name>CMIE</name>
              <bitOffset>14</bitOffset>
              <bitWidth>1</bitWidth>
            </field>
            <field>
              <name>OVER8</name>
              <bitOffset>15</bitOffset>
              <bitWidth>1</bitWidth>
            </field>
            <field>
              <name>DEDT</name>
              <bitOffset>16</bitOffset>
              <bitWidth>5</bitWidth>
            </field>
            <field>
              <name>DEAT</name>
              <bitOffset>21</bitOffset>
              <bitWidth>5</bitWidth>
            </field>
            <field>
              <name>RTOIE</name>
              <bitOffset>26</bitOffset>
              <bitWidth>1</bitWidth>
            </field>
            <field>
              <name>EOBIE</name>
              <bitOffset>27</bitOffset>
              <bitWidth>1</bitWidth>
            </field>
            <field>
              <name>M1</name>
              <bitOffset>28</bitOffset>
              <bitWidth>1</bitWidth>
            </field>
            <field>
              <name>FIFOEN</name>
              <bitOffset>29</bitOffset>
              <bitWidth>1</bitWidth>
            </field>
            <field>
              <name>TXFEIE</name>
              <bitOffset>30</bitOffset>
              <bitWidth>1</bitWidth>
            </field>
            <field>
              <name>RXFFIE</name>
              <bitOffset>31</bitOffset>
              <bitWidth>1</bitWidth>
            </field>
          </fields>
        </register>
        <register>
          <name>CR2</name>
          <addressOffset>0x4</addressOffset>
          <size>0x20</size>
          <fields>
            <field>
              <name>SLVEN</name>
              <bitOffset>0</bitOffset>
              <bitWidth>1</bitWidth>
            </field>
            <field>
              <name>DIS_NSS</name>
              <bitOffset>3</bitOffset>
              <bitWidth>1</bitWidth>
            </field>
            <field>
              <name>ADDM7</name>
              <bitOffset>4</bitOffset>
              <bitWidth>1</bitWidth>
            </field>
            <field>
              <name>LBDL</name>
              <bitOffset>5</bitOffset>
              <bitWidth>1</bitWidth>
            </field>
            <field>
              <name>LBDIE</name>
              <bitOffset>6</bitOffset>
              <bitWidth>1</bitWidth>
            </field>
            <field>
              <name>LBCL</name>
              <bitOffset>8</bitOffset>
              <bitWidth>1</bitWidth>
            </field>
            <field>
              <name>CPHA</name>
              <bitOffset>9</bitOffset>
              <bitWidth>1</bitWidth>
            </field>
            <field>
              <name>CPOL</name>
              <bitOffset>10</bitOffset>
              <bitWidth>1</bitWidth>
            </field>
            <field>
              <name>CLKEN</name>
              <bitOffset>11</bitOffset>
              <bitWidth>1</bitWidth>
            </field>
            <field>
              <name>STOP</name>
              <bitOffset>12</bitOffset>
              <bitWidth>2</bitWidth>
            </field>
            <field>
              <name>LINEN</name>
              <bitOffset>14</bitOffset>
              <bitWidth>1</bitWidth>
            </field>
            <field>
              <name>SWAP</name>
              <bitOffset>15</bitOffset>
              <bitWidth>1</bitWidth>
            </field>
            <field>
              <name>RXINV</name>
              <bitOffset>16</bitOffset>
              <bitWidth>1</bitWidth>
            </field>
            <field>
              <name>TXINV</name>
              <bitOffset>17</bitOffset>
              <bitWidth>1</bitWidth>
            </field>
            <field>
              <name>DATAINV</name>
              <bitOffset>18</bitOffset>
              <bitWidth>1</bitWidth>
            </field>
            <field>
              <name>MSBFIRST</name>
              <bitOffset>19</bitOffset>
              <bitWidth>1</bitWidth>
            </field>
            <field>
              <name>ABREN</name>
              <bitOffset>20</bitOffset>
              <bitWidth>1</bitWidth>
            </field>
            <field>
              <name>ABRMODE</name>
              <bitOffset>21</bitOffset>
              <bitWidth>2</bitWidth>
            </field>
            <field>
              <name>RTOEN</name>
              <bitOffset>23</bitOffset>
              <bitWidth>1</bitWidth>
            </field>
            <field>
              <name>ADD</name>
              <bitOffset>24</bitOffset>
              <bitWidth>8</bitWidth>
            </field>
          </fields>
        </register>
        <register>
          <name>CR3</name>
          <addressOffset>0x8</addressOffset>
          <size>0x20</size>
          <fields>
            <field>
              <name>EIE</name>
              <bitOffset>0</bitOffset>
              <bitWidth>1</bitWidth>
            </field>
            <field>
              <name>IREN</name>
              <bitOffset>1</bitOffset>
              <bitWidth>1</bitWidth>
            </field>
            <field>
              <name>IRLP</name>
              <bitOffset>2</bitOffset>
              <bitWidth>1</bitWidth>
            </field>
            <field>
              <name>HDSEL</name>
              <bitOffset>3</bitOffset>
              <bitWidth>1</bitWidth>
            </field>
            <field>
              <name>NACK</name>
              <bitOffset>4</bitOffset>
              <bitWidth>1</bitWidth>
            </field>
            <field>
              <name>SCEN</name>
              <bitOffset>5</bitOffset>
              <bitWidth>1</bitWidth>
            </field>
            <field>
              <name>DMAR</name>
              <bitOffset>6</bitOffset>
              <bitWidth>1</bitWidth>
            </field>
            <field>
              <name>DMAT</name>
              <bitOffset>7</bitOffset>
              <bitWidth>1</bitWidth>
            </field>
            <field>
              <name>RTSE</name>
              <bitOffset>8</bitOffset>
              <bitWidth>1</bitWidth>
            </field>
            <field>
              <name>CTSE</name>
              <bitOffset>9</bitOffset>
              <bitWidth>1</bitWidth>
            </field>
            <field>
              <name>CTSIE</name>
              <bitOffset>10</bitOffset>
              <bitWidth>1</bitWidth>
            </field>
            <field>
              <name>ONEBIT</name>
              <bitOffset>11</bitOffset>
              <bitWidth>1</bitWidth>
            </field>
            <field>
              <name>OVRDIS</name>
              <bitOffset>12</bitOffset>
              <bitWidth>1</bitWidth>
            </field>
            <field>
              <name>DDRE</name>
              <bitOffset>13</bitOffset>
              <bitWidth>1</bitWidth>
            </field>
            <field>
              <name>DEM</name>
              <bitOffset>14</bitOffset>
              <bitWidth>1</bitWidth>
            </field>
            <field>
              <name>DEP</name>
              <bitOffset>15</bitOffset>
              <bitWidth>1</bitWidth>
            </field>
            <field>
              <name>SCARCNT</name>
              <bitOffset>17</bitOffset>
              <bitWidth>3</bitWidth>
            </field>
            <field>
              <name>WUS</name>
              <bitOffset>20</bitOffset>
              <bitWidth>2</bitWidth>
            </field>
            <field>
              <name>WUFIE</name>
              <bitOffset>22</bitOffset>
              <bitWidth>1</bitWidth>
            </field>
            <field>
              <name>TXFTIE</name>
              <bitOffset>23</bitOffset>
              <bitWidth>1</bitWidth>
            </field>
            <field>
              <name>TCBGTIE</name>
              <bitOffset>24</bitOffset>
              <bitWidth>1</bitWidth>
            </field>
            <field>
              <name>RXFTCFG</name>
              <bitOffset>25</bitOffset>
              <bitWidth>3</bitWidth>
            </field>
            <field>
              <name>RXFTIE</name>
              <bitOffset>28</bitOffset>
              <bitWidth>1</bitWidth>
            </field>
            <field>
              <name>TXFTCFG</name>
              <bitOffset>29</bitOffset>
              <bitWidth>3</bitWidth>
            </field>
          </fields>
        </register>
        <register>
          <name>BRR</name>
          <addressOffset>0xc</addressOffset>
          <size>0x20</size>
          <fields>
            <field>
              <name>DIV_FRACTION</name>
              <bitOffset>0</bitOffset>
              <bitWidth>4</bitWidth>
            </field>
            <field>
              <name>DIV_MANTISSA</name>
              <bitOffset>4</bitOffset>
              <bitWidth>12</bitWidth>
            </field>
          </fields>
        </register>
        <register>
          <name>GTPR</name>
          <addressOffset>0x10</addressOffset>
          <size>0x20</size>
          <fields>
            <field>
              <name>PSC</name>
              <bitOffset>0</bitOffset>
              <bitWidth>8</bitWidth>
            </field>
            <field>
              <name>GT</name>
              <bitOffset>8</bitOffset>
              <bitWidth>8</bitWidth>
            </field>
          </fields>
        </register>
        <register>
          <name>RTOR</name>
          <addressOffset>0x14</addressOffset>
          <size>0x20</size>
          <fields>
            <field>
              <name>RTO</name>
              <bitOffset>0</bitOffset>
              <bitWidth>24</bitWidth>
            </field>
            <field>
              <name>BLEN</name>
              <bitOffset>24</bitOffset>
              <bitWidth>8</bitWidth>
            </field>
          </fields>
        </register>
        <register>
          <name>RQR</name>
          <addressOffset>0x18</addressOffset>
          <size>0x20</size>
          <fields>
            <field>
              <name>ABRRQ</name>
              <bitOffset>0</bitOffset>
              <bitWidth>1</bitWidth>
            </field>
            <field>
              <name>SBKRQ</name>
              <bitOffset>1</bitOffset>
              <bitWidth>1</bitWidth>
            </field>
            <field>
              <name>MMRQ</name>
              <bitOffset>2</bitOffset>
              <bitWidth>1</bitWidth>
            </field>
            <field>
              <name>RXFRQ</name>
              <bitOffset>3</bitOffset>
              <bitWidth>1</bitWidth>
            </field>
            <field>
              <name>TXFRQ</name>
              <bitOffset>4</bitOffset>
              <bitWidth>1</bitWidth>
            </field>
          </fields>
        </register>
        <register>
          <name>ISR</name>
          <addressOffset>0x1c</addressOffset>
          <size>0x20</size>
          <fields>
            <field>
              <name>PE</name>
              <bitOffset>0</bitOffset>
              <bitWidth>1</bitWidth>
            </field>
            <field>
              <name>FE</name>
              <bitOffset>1</bitOffset>
              <bitWidth>1</bitWidth>
            </field>
            <field>
              <name>NE</name>
              <bitOffset>2</bitOffset>
              <bitWidth>1</bitWidth>
            </field>
            <field>
              <name>ORE</name>
              <bitOffset>3</bitOffset>
              <bitWidth>1</bitWidth>
            </field>
            <field>
              <name>IDLE</name>
              <bitOffset>4</bitOffset>
              <bitWidth>1</bitWidth>
            </field>
            <field>
              <name>RXNE_RXFNE</name>
              <bitOffset>5</bitOffset>
              <bitWidth>1</bitWidth>
            </field>
            <field>
              <name>TC</name>
              <bitOffset>6</bitOffset>
              <bitWidth>1</bitWidth>
            </field>
            <field>
              <name>TXE_TXFNF</name>
              <bitOffset>7</bitOffset>
              <bitWidth>1</bitWidth>
            </field>
            <field>
              <name>LBDF</name>
              <bitOffset>8</bitOffset>
              <bitWidth>1</bitWidth>
            </field>
            <field>
              <name>CTSIF</name>
              <bitOffset>9</bitOffset>
              <bitWidth>1</bitWidth>
            </field>
            <field>
              <name>CTS</name>
              <bitOffset>10</bitOffset>
              <bitWidth>1</bitWidth>
            </field>
            <field>
              <name>RTOF</name>
              <bitOffset>11</bitOffset>
              <bitWidth>1</bitWidth>
            </field>
            <field>
              <name>EOBF</name>
              <bitOffset>12</bitOffset>
              <bitWidth>1</bitWidth>
            </field>
            <field>
              <name>UDR</name>
              <bitOffset>13</bitOffset>
              <bitWidth>1</bitWidth>
            </field>
            <field>
              <name>ABRE</name>
              <bitOffset>14</bitOffset>
              <bitWidth>1</bitWidth>
            </field>
            <field>
              <name>ABRF</name>
              <bitOffset>15</bitOffset>
              <bitWidth>1</bitWidth>
            </field>
            <field>
              <name>BUSY</name>
              <bitOffset>16</bitOffset>
              <bitWidth>1</bitWidth>
            </field>
            <field>
              <name>CMF</name>
              <bitOffset>17</bitOffset>
              <bitWidth>1</bitWidth>
            </field>
            <field>
              <name>SBKF</name>
              <bitOffset>18</bitOffset>
              <bitWidth>1</bitWidth>
            </field>
            <field>
              <name>RWU</name>
              <bitOffset>19</bitOffset>
              <bitWidth>1</bitWidth>
            </field>
            <field>
              <name>WUF</name>
              <bitOffset>20</bitOffset>
              <bitWidth>1</bitWidth>
            </field>
            <field>
              <name>TEACK</name>
              <bitOffset>21</bitOffset>
              <bitWidth>1</bitWidth>
            </field>
            <field>
              <name>REACK</name>
              <bitOffset>22</bitOffset>
              <bitWidth>1</bitWidth>
            </field>
            <field>
              <name>TXFE</name>
              <bitOffset>23</bitOffset>
              <bitWidth>1</bitWidth>
            </field>
            <field>
              <name>RXFF</name>
              <bitOffset>24</bitOffset>
              <bitWidth>1</bitWidth>
            </field>
            <field>
              <name>TCBGT</name>
              <bitOffset>25</bitOffset>
              <bitWidth>1</bitWidth>
            </field>
            <field>
              <name>RXFT</name>
              <bitOffset>26</bitOffset>
              <bitWidth>1</bitWidth>
            </field>
            <field>
              <name>TXFT</name>
              <bitOffset>27</bitOffset>
              <bitWidth>1</bitWidth>
            </field>
          </fields>
        </register>
        <register>
          <name>ICR</name>
          <addressOffset>0x20</addressOffset>
          <size>0x20</size>
          <fields>
            <field>
              <name>PECF</name>
              <bitOffset>0</bitOffset>
              <bitWidth>1</bitWidth>
            </field>
            <field>
              <name>FECF</name>
              <bitOffset>1</bitOffset>
              <bitWidth>1</bitWidth>
            </field>
            <field>
              <name>NECF</name>
              <bitOffset>2</bitOffset>
              <bitWidth>1</bitWidth>
            </field>
            <field>
              <name>ORECF</name>
              <bitOffset>3</bitOffset>
              <bitWidth>1</bitWidth>
            </field>
            <field>
              <name>IDLECF</name>
              <bitOffset>4</bitOffset>
              <bitWidth>1</bitWidth>
            </field>
            <field>
              <name>TXFECF</name>
              <bitOffset>5</bitOffset>
              <bitWidth>1</bitWidth>
            </field>
            <field>
              <name>TCCF</name>
              <bitOffset>6</bitOffset>
              <bitWidth>1</bitWidth>
            </field>
            <field>
              <name>TCBGTCF</name>
              <bitOffset>7</bitOffset>
              <bitWidth>1</bitWidth>
            </field>
            <field>
              <name>LBDCF</name>
              <bitOffset>8</bitOffset>
              <bitWidth>1</bitWidth>
            </field>
            <field>
              <name>CTSCF</name>
              <bitOffset>9</bitOffset>
              <bitWidth>1</bitWidth>
            </field>
            <field>
              <name>RTOCF</name>
              <bitOffset>11</bitOffset>
              <bitWidth>1</bitWidth>
            </field>
            <field>
              <name>EOBCF</name>
              <bitOffset>12</bitOffset>
              <bitWidth>1</bitWidth>
            </field>
            <field>
              <name>UDRCF</name>
              <bitOffset>13</bitOffset>
              <bitWidth>1</bitWidth>
            </field>
            <field>
              <name>CMCF</name>
              <bitOffset>17</bitOffset>
              <bitWidth>1</bitWidth>
            </field>
            <field>
              <name>WUCF</name>
              <bitOffset>20</bitOffset>
              <bitWidth>1</bitWidth>
            </field>
          </fields>
        </register>
        <register>
          <name>RDR</name>
          <addressOffset>0x24</addressOffset>
          <size>0x20</size>
          <fields>
            <field>
              <name>RDR</name>
              <bitOffset>0</bitOffset>
              <bitWidth>9</bitWidth>
            </field>
          </fields>
        </register>
        <register>
          <name>TDR</name>
          <addressOffset>0x28</addressOffset>
          <size>0x20</size>
          <fields>
            <field>
              <name>TDR</name>
              <bitOffset>0</bitOffset>
              <bitWidth>9</bitWidth>
            </field>
          </fields>
        </register>
        <register>
          <name>PRESC</name>
          <addressOffset>0x2c</addressOffset>
          <size>0x20</size>
          <fields>
            <field>
              <name>PRESCALER</name>
              <bitOffset>0</bitOffset>
              <bitWidth>4</bitWidth>
            </field>
          </fields>
        </register>
      </registers>
    </peripheral>
    <peripheral>
      <name>SPI1</name>
      <baseAddress>0x40013000</baseAddress>
      <registers>
        <register>
          <name>CR1</name>
          <addressOffset>0x0</addressOffset>
          <size>0x20</size>
          <fields>
            <field>
              <name>SPE</name>
              <bitOffset>0</bitOffset>
              <bitWidth>1</bitWidth>
            </field>
            <field>
              <name>MASRX</name>
              <bitOffset>8</bitOffset>
              <bitWidth>1</bitWidth>
            </field>
            <field>
              <name>CSTART</name>
              <bitOffset>9</bitOffset>
              <bitWidth>1</bitWidth>
            </field>
            <field>
              <name>CSUSP</name>
              <bitOffset>10</bitOffset>
              <bitWidth>1</bitWidth>
            </field>
            <field>
              <name>HDDIR</name>
              <bitOffset>11</bitOffset>
              <bitWidth>1</bitWidth>
            </field>
            <field>
              <name>SSI</name>
              <bitOffset>12</bitOffset>
              <bitWidth>1</bitWidth>
            </field>
            <field>
              <name>CRC33_17</name>
              <bitOffset>13</bitOffset>
              <bitWidth>1</bitWidth>
            </field>
            <field>
              <name>RCRCINI</name>
              <bitOffset>14</bitOffset>
              <bitWidth>1</bitWidth>
            </field>
            <field>
              <name>TCRCINI</name>
              <bitOffset>15</bitOffset>
              <bitWidth>1</bitWidth>
            </field>
            <field>
              <name>IOLOCK</name>
              <bitOffset>16</bitOffset>
              <bitWidth>1</bitWidth>
            </field>
          </fields>
        </register>
        <register>
          <name>CR2</name>
          <addressOffset>0x4</addressOffset>
          <size>0x20</size>
          <fields>
            <field>
              <name>TSIZE</name>
              <bitOffset>0</bitOffset>
              <bitWidth>16</bitWidth>
            </field>
            <field>
              <name>TSER</name>
              <bitOffset>16</bitOffset>
              <bitWidth>16</bitWidth>
            </field>
          </fields>
        </register>
        <register>
          <name>CFG1</name>
          <addressOffset>0x8</addressOffset>
          <size>0x20</size>
          <fields>
            <field>
              <name>DSIZE</name>
              <bitOffset>0</bitOffset>
              <bitWidth>5</bitWidth>
            </field>
            <field>
              <name>FTHLV</name>
              <bitOffset>5</bitOffset>
              <bitWidth>4</bitWidth>
            </field>
            <field>
              <name>UDRCFG</name>
              <bitOffset>9</bitOffset>
              <bitWidth>2</bitWidth>
            </field>
            <field>
              <name>UDRDET</name>
              <bitOffset>11</bitOffset>
              <bitWidth>2</bitWidth>
            </field>
            <field>
              <name>RXDMAEN</name>
              <bitOffset>14</bitOffset>
              <bitWidth>1</bitWidth>
            </field>
            <field>
              <name>TXDMAEN</name>
              <bitOffset>15</bitOffset>
              <bitWidth>1</bitWidth>
            </field>
            <field>
              <name>CRCSIZE</name>
              <bitOffset>16</bitOffset>
              <bitWidth>5</bitWidth>
            </field>
            <field>
              <name>CRCEN</name>
              <bitOffset>22</bitOffset>
              <bitWidth>1</bitWidth>
            </field>
            <field>
              <name>MBR</name>
              <bitOffset>28</bitOffset>
              <bitWidth>3</bitWidth>
            </field>
          </fields>
        </register>
        <register>
          <name>CFG2</name>
          <addressOffset>0xc</addressOffset>
          <size>0x20</size>
          <fields>
            <field>
              <name>MSSI</name>
              <bitOffset>0</bitOffset>
              <bitWidth>4</bitWidth>
            </field>
            <field>
              <name>MIDI</name>
              <bitOffset>4</bitOffset>
              <bitWidth>4</bitWidth>
            </field>
            <field>
              <name>IOSWP</name>
              <bitOffset>15</bitOffset>
              <bitWidth>1</bitWidth>
            </field>
            <field>
              <name>COMM</name>
              <bitOffset>17</bitOffset>
              <bitWidth>2</bitWidth>
            </field>
            <field>
              <name>SP</name>
              <bitOffset>19</bitOffset>
              <bitWidth>3</bitWidth>
            </field>
            <field>
              <name>MASTER</name>
              <bitOffset>22</bitOffset>
              <bitWidth>1</bitWidth>
            </field>
            <field>
              <name>LSBFRST</name>
              <bitOffset>23</bitOffset>
              <bitWidth>1</bitWidth>
            </field>
            <field>
              <name>CPHA</name>
              <bitOffset>24</bitOffset>
              <bitWidth>1</bitWidth>
            </field>
            <field>
              <name>CPOL</name>
              <bitOffset>25</bitOffset>
              <bitWidth>1</bitWidth>
            </field>
            <field>
              <name>SSM</name>
              <bitOffset>26</bitOffset>
              <bitWidth>1</bitWidth>
            </field>
            <field>
              <name>SSIOP</name>
              <bitOffset>28</bitOffset>
              <bitWidth>1</bitWidth>
            </field>
            <field>
              <name>SSOE</name>
              <bitOffset>29</bitOffset>
              <bitWidth>1</bitWidth>
            </field>
            <field>
              <name>SSOM</name>
              <bitOffset>30</bitOffset>
              <bitWidth>1</bitWidth>
            </field>
            <field>
              <name>AFCNTR</name>
              <bitOffset>31</bitOffset>
              <bitWidth>1</bitWidth>
            </field>
          </fields>
        </register>
        <register>
          <name>IER</name>
          <addressOffset>0x10</addressOffset>
          <size>0x20</size>
          <fields>
            <field>
              <name>RXPIE</name>
              <bitOffset>0</bitOffset>
              <bitWidth>1</bitWidth>
            </field>
            <field>
              <name>TXPIE</name>
              <bitOffset>1</bitOffset>
              <bitWidth>1</bitWidth>
            </field>
            <field>
              <name>DXPIE</name>
              <bitOffset>2</bitOffset>
              <bitWidth>1</bitWidth>
            </field>
            <field>
              <name>EOTIE</name>
              <bitOffset>3</bitOffset>
              <bitWidth>1</bitWidth>
            </field>
            <field>
              <name>TXTFIE</name>
              <bitOffset>4</bitOffset>
              <bitWidth>1</bitWidth>
            </field>
            <field>
              <name>UDRIE</name>
              <bitOffset>5</bitOffset>
              <bitWidth>1</bitWidth>
            </field>
            <field>
              <name>OVRIE</name>
              <bitOffset>6</bitOffset>
              <bitWidth>1</bitWidth>
            </field>
            <field>
              <name>CRCEIE</name>
              <bitOffset>7</bitOffset>
              <bitWidth>1</bitWidth>
            </field>
            <field>
              <name>TIFREIE</name>
              <bitOffset>8</bitOffset>
              <bitWidth>1</bitWidth>
            </field>
            <field>
              <name>MODFIE</name>
              <bitOffset>9</bitOffset>
              <bitWidth>1</bitWidth>
            </field>
            <field>
              <name>TSERFIE</name>
              <bitOffset>10</bitOffset>
              <bitWidth>1</bitWidth>
            </field>
          </fields>
        </register>
        <register>
          <name>SR</name>
          <addressOffset>0x14</addressOffset>
          <size>0x20</size>
          <fields>
            <field>
              <name>RXP</name>
              <bitOffset>0</bitOffset>
              <bitWidth>1</bitWidth>
            </field>
            <field>
              <name>TXP</name>
              <bitOffset>1</bitOffset>
              <bitWidth>1</bitWidth>
            </field>
            <field>
              <name>DXP</name>
              <bitOffset>2</bitOffset>
              <bitWidth>1</bitWidth>
            </field>
            <field>
              <name>EOT</name>
              <bitOffset>3</bitOffset>
              <bitWidth>1</bitWidth>
            </field>
            <field>
              <name>TXTF</name>
              <bitOffset>4</bitOffset>
              <bitWidth>1</bitWidth>
            </field>
            <field>
              <name>UDR</name>
              <bitOffset>5</bitOffset>
              <bitWidth>1</bitWidth>
            </field>
            <field>
              <name>OVR</name>
              <bitOffset>6</bitOffset>
              <bitWidth>1</bitWidth>
            </field>
            <field>
              <name>CRCE</name>
              <bitOffset>7</bitOffset>
              <bitWidth>1</bitWidth>
            </field>
            <field>
              <name>TIFRE</name>
              <bitOffset>8</bitOffset>
              <bitWidth>1</bitWidth>
            </field>
            <field>
              <name>MODF</name>
              <bitOffset>9</bitOffset>
              <bitWidth>1</bitWidth>
            </field>
            <field>
              <name>TSERF</name>
              <bitOffset>10</bitOffset>
              <bitWidth>1</bitWidth>
            </field>
            <field>
              <name>SUSP</name>
              <bitOffset>11</bitOffset>
              <bitWidth>1</bitWidth>
            </field>
            <field>
              <name>TXC</name>
              <bitOffset>12</bitOffset>
              <bitWidth>1</bitWidth>
            </field>
            <field>
              <name>RXPLVL</name>
              <bitOffset>13</bitOffset>
              <bitWidth>2</bitWidth>
            </field>
            <field>
              <name>RXWNE</name>
              <bitOffset>15</bitOffset>
              <bitWidth>1</bitWidth>
            </field>
            <field>
              <name>CTSIZE</name>
              <bitOffset>16</bitOffset>
              <bitWidth>16</bitWidth>
            </field>
          </fields>
        </register>
        <register>
          <name>IFCR</name>
          <addressOffset>0x18</addressOffset>
          <size>0x20</size>
          <fields>
            <field>
              <name>EOTC</name>
              <bitOffset>3</bitOffset>
              <bitWidth>1</bitWidth>
            </field>
            <field>
              <name>TXTFC</name>
              <bitOffset>4</bitOffset>
              <bitWidth>1</bitWidth>
            </field>
            <field>
              <name>UDRC</name>
              <bitOffset>5</bitOffset>
              <bitWidth>1</bitWidth>
            </field>
            <field>
              <name>OVRC</name>
              <bitOffset>6</bitOffset>
              <bitWidth>1</bitWidth>
            </field>
            <field>
              <name>CRCEC</name>
              <bitOffset>7</bitOffset>
              <bitWidth>1</bitWidth>
            </field>
            <field>
              <name>TIFREC</name>
              <bitOffset>8</bitOffset>
              <bitWidth>1</bitWidth>
            </field>
            <field>
              <name>MODFC</name>
              <bitOffset>9</bitOffset>
              <bitWidth>1</bitWidth>
            </field>
            <field>
              <name>TSERFC</name>
              <bitOffset>10</bitOffset>
              <bitWidth>1</bitWidth>
            </field>
            <field>
              <name>SUSPC</name>
              <bitOffset>11</bitOffset>
              <bitWidth>1</bitWidth>
            </field>
          </fields>
        </register>
        <register>
          <name>TXDR</name>
          <addressOffset>0x20</addressOffset>
          <size>0x20</size>
          <fields>
            <field>
              <name>TXDR</name>
              <bitOffset>0</bitOffset>
              <bitWidth>32</bitWidth>
            </field>
          </fields>
        </register>
        <register>
          <name>RXDR</name>
          <addressOffset>0x30</addressOffset>
          <size>0x20</size>
          <fields>
            <field>
              <name>RXDR</name>
              <bitOffset>0</bitOffset>
              <bitWidth>32</bitWidth>
            </field>
          </fields>
        </register>
        <register>
          <name>CRCPOLY</name>
          <addressOffset>0x40</addressOffset>
          <size>0x20</size>
          <fields>
            <field>
              <name>CRCPOLY</name>
              <bitOffset>0</bitOffset>
              <bitWidth>32</bitWidth>
            </field>
          </fields>
        </register>
        <register>
          <name>TXCRC</name>
          <addressOffset>0x44</addressOffset>
          <size>0x20</size>
          <fields>
            <field>
              <name>TXCRC</name>
              <bitOffset>0</bitOffset>
              <bitWidth>32</bitWidth>
            </field>
          </fields>
        </register>
        <register>
          <name>RXCRC</name>
          <addressOffset>0x48</addressOffset>
          <size>0x20</size>
          <fields>
            <field>
              <name>RXCRC</name>
              <bitOffset>0</bitOffset>
              <bitWidth>32</bitWidth>
            </field>
          </fields>
        </register>
        <register>
          <name>UDRDR</name>
          <addressOffset>0x4c</addressOffset>
          <size>0x20</size>
          <fields>
            <field>
              <name>UDRDR</name>
              <bitOffset>0</bitOffset>
              <bitWidth>32</bitWidth>
            </field>
          </fields>
        </register>
        <register>
          <name>I2SCFGR</name>
          <addressOffset>0x50</addressOffset>
          <size>0x20</size>
          <fields>
            <field>
              <name>I2SMOD</name>
              <bitOffset>0</bitOffset>
              <bitWidth>1</bitWidth>
            </field>
            <field>
              <name>I2SCFG</name>
              <bitOffset>1</bitOffset>
              <bitWidth>3</bitWidth>
            </field>
            <field>
              <name>I2SSTD</name>
              <bitOffset>4</bitOffset>
              <bitWidth>2</bitWidth>
            </field>
            <field>
              <name>PCMSYNC</name>
              <bitOffset>7</bitOffset>
              <bitWidth>1</bitWidth>
            </field>
            <field>
              <name>DATLEN</name>
              <bitOffset>8</bitOffset>
              <bitWidth>2</bitWidth>
            </field>
            <field>
              <name>CHLEN</name>
              <bitOffset>10</bitOffset>
              <bitWidth>1</bitWidth>
            </field>
            <field>
              <name>CKPOL</name>
              <bitOffset>11</bitOffset>
              <bitWidth>1</bitWidth>
            </field>
            <field>
              <name>FIXCH</name>
              <bitOffset>12</bitOffset>
              <bitWidth>1</bitWidth>
            </field>
            <field>
              <name>WSINV</name>
              <bitOffset>13</bitOffset>
              <bitWidth>1</bitWidth>
            </field>
            <field>
              <name>DATFMT</name>
              <bitOffset>14</bitOffset>
              <bitWidth>1</bitWidth>
            </field>
            <field>
              <name>I2SDIV</name>
              <bitOffset>16</bitOffset>
              <bitWidth>8</bitWidth>
            </field>
            <field>
              <name>ODD</name>
              <bitOffset>24</bitOffset>
              <bitWidth>1</bitWidth>
            </field>
            <field>
              <name>MCKOE</name>
              <bitOffset>25</bitOffset>
              <bitWidth>1</bitWidth>
            </field>
          </fields>
        </register>
      </registers>
    </peripheral>
    <peripheral>
      <name>SPI4</name>
      <baseAddress>0x40013400</baseAddress>
      <registers>
        <register>
          <name>CR1</name>
          <addressOffset>0x0</addressOffset>
          <size>0x20</size>
          <fields>
            <field>
              <name>SPE</name>
              <bitOffset>0</bitOffset>
              <bitWidth>1</bitWidth>
            </field>
            <field>
              <name>MASRX</name>
              <bitOffset>8</bitOffset>
              <bitWidth>1</bitWidth>
            </field>
            <field>
              <name>CSTART</name>
              <bitOffset>9</bitOffset>
              <bitWidth>1</bitWidth>
            </field>
            <field>
              <name>CSUSP</name>
              <bitOffset>10</bitOffset>
              <bitWidth>1</bitWidth>
            </field>
            <field>
              <name>HDDIR</name>
              <bitOffset>11</bitOffset>
              <bitWidth>1</bitWidth>
            </field>
            <field>
              <name>SSI</name>
              <bitOffset>12</bitOffset>
              <bitWidth>1</bitWidth>
            </field>
            <field>
              <name>CRC33_17</name>
              <bitOffset>13</bitOffset>
              <bitWidth>1</bitWidth>
            </field>
            <field>
              <name>RCRCINI</name>
              <bitOffset>14</bitOffset>
              <bitWidth>1</bitWidth>
            </field>
            <field>
              <name>TCRCINI</name>
              <bitOffset>15</bitOffset>
              <bitWidth>1</bitWidth>
            </field>
            <field>
              <name>IOLOCK</name>
              <bitOffset>16</bitOffset>
              <bitWidth>1</bitWidth>
            </field>
          </fields>
        </register>
        <register>
          <name>CR2</name>
          <addressOffset>0x4</addressOffset>
          <size>0x20</size>
          <fields>
            <field>
              <name>TSIZE</name>
              <bitOffset>0</bitOffset>
              <bitWidth>16</bitWidth>
            </field>
            <field>
              <name>TSER</name>
              <bitOffset>16</bitOffset>
              <bitWidth>16</bitWidth>
            </field>
          </fields>
        </register>
        <register>
          <name>CFG1</name>
          <addressOffset>0x8</addressOffset>
          <size>0x20</size>
          <fields>
            <field>
              <name>DSIZE</name>
              <bitOffset>0</bitOffset>
              <bitWidth>5</bitWidth>
            </field>
            <field>
              <name>FTHLV</name>
              <bitOffset>5</bitOffset>
              <bitWidth>4</bitWidth>
            </field>
            <field>
              <name>UDRCFG</name>
              <bitOffset>9</bitOffset>
              <bitWidth>2</bitWidth>
            </field>
            <field>
              <name>UDRDET</name>
              <bitOffset>11</bitOffset>
              <bitWidth>2</bitWidth>
            </field>
            <field>
              <name>RXDMAEN</name>
              <bitOffset>14</bitOffset>
              <bitWidth>1</bitWidth>
            </field>
            <field>
              <name>TXDMAEN</name>
              <bitOffset>15</bitOffset>
              <bitWidth>1</bitWidth>
            </field>
            <field>
              <name>CRCSIZE</name>
              <bitOffset>16</bitOffset>
              <bitWidth>5</bitWidth>
            </field>
            <field>
              <name>CRCEN</name>
              <bitOffset>22</bitOffset>
              <bitWidth>1</bitWidth>
            </field>
            <field>
              <name>MBR</name>
              <bitOffset>28</bitOffset>
              <bitWidth>3</bitWidth>
            </field>
          </fields>
        </register>
        <register>
          <name>CFG2</name>
          <addressOffset>0xc</addressOffset>
          <size>0x20</size>
          <fields>
            <field>
              <name>MSSI</name>
              <bitOffset>0</bitOffset>
              <bitWidth>4</bitWidth>
            </field>
            <field>
              <name>MIDI</name>
              <bitOffset>4</bitOffset>
              <bitWidth>4</bitWidth>
            </field>
            <field>
              <name>IOSWP</name>
              <bitOffset>15</bitOffset>
              <bitWidth>1</bitWidth>
            </field>
            <field>
              <name>COMM</name>
              <bitOffset>17</bitOffset>
              <bitWidth>2</bitWidth>
            </field>
            <field>
              <name>SP</name>
              <bitOffset>19</bitOffset>
              <bitWidth>3</bitWidth>
            </field>
            <field>
              <name>MASTER</name>
              <bitOffset>22</bitOffset>
              <bitWidth>1</bitWidth>
            </field>
            <field>
              <name>LSBFRST</name>
              <bitOffset>23</bitOffset>
              <bitWidth>1</bitWidth>
            </field>
            <field>
              <name>CPHA</name>
              <bitOffset>24</bitOffset>
              <bitWidth>1</bitWidth>
            </field>
            <field>
              <name>CPOL</name>
              <bitOffset>25</bitOffset>
              <bitWidth>1</bitWidth>
            </field>
            <field>
              <name>SSM</name>
              <bitOffset>26</bitOffset>
              <bitWidth>1</bitWidth>
            </field>
            <field>
              <name>SSIOP</name>
              <bitOffset>28</bitOffset>
              <bitWidth>1</bitWidth>
            </field>
            <field>
              <name>SSOE</name>
              <bitOffset>29</bitOffset>
              <bitWidth>1</bitWidth>
            </field>
            <field>
              <name>SSOM</name>
              <bitOffset>30</bitOffset>
              <bitWidth>1</bitWidth>
            </field>
            <field>
              <name>AFCNTR</name>
              <bitOffset>31</bitOffset>
              <bitWidth>1</bitWidth>
            </field>
          </fields>
        </register>
        <register>
          <name>IER</name>
          <addressOffset>0x10</addressOffset>
          <size>0x20</size>
          <fields>
            <field>
              <name>RXPIE</name>
              <bitOffset>0</bitOffset>
              <bitWidth>1</bitWidth>
            </field>
            <field>
              <name>TXPIE</name>
              <bitOffset>1</bitOffset>
              <bitWidth>1</bitWidth>
            </field>
            <field>
              <name>DXPIE</name>
              <bitOffset>2</bitOffset>
              <bitWidth>1</bitWidth>
            </field>
            <field>
              <name>EOTIE</name>
              <bitOffset>3</bitOffset>
              <bitWidth>1</bitWidth>
            </field>
            <field>
              <name>TXTFIE</name>
              <bitOffset>4</bitOffset>
              <bitWidth>1</bitWidth>
            </field>
            <field>
              <name>UDRIE</name>
              <bitOffset>5</bitOffset>
              <bitWidth>1</bitWidth>
            </field>
            <field>
              <name>OVRIE</name>
              <bitOffset>6</bitOffset>
              <bitWidth>1</bitWidth>
            </field>
            <field>
              <name>CRCEIE</name>
              <bitOffset>7</bitOffset>
              <bitWidth>1</bitWidth>
            </field>
            <field>
              <name>TIFREIE</name>
              <bitOffset>8</bitOffset>
              <bitWidth>1</bitWidth>
            </field>
            <field>
              <name>MODFIE</name>
              <bitOffset>9</bitOffset>
              <bitWidth>1</bitWidth>
            </field>
            <field>
              <name>TSERFIE</name>
              <bitOffset>10</bitOffset>
              <bitWidth>1</bitWidth>
            </field>
          </fields>
        </register>
        <register>
          <name>SR</name>
          <addressOffset>0x14</addressOffset>
          <size>0x20</size>
          <fields>
            <field>
              <name>RXP</name>
              <bitOffset>0</bitOffset>
              <bitWidth>1</bitWidth>
            </field>
            <field>
              <name>TXP</name>
              <bitOffset>1</bitOffset>
              <bitWidth>1</bitWidth>
            </field>
            <field>
              <name>DXP</name>
              <bitOffset>2</bitOffset>
              <bitWidth>1</bitWidth>
            </field>
            <field>
              <name>EOT</name>
              <bitOffset>3</bitOffset>
              <bitWidth>1</bitWidth>
            </field>
            <field>
              <name>TXTF</name>
              <bitOffset>4</bitOffset>
              <bitWidth>1</bitWidth>
            </field>
            <field>
              <name>UDR</name>
              <bitOffset>5</bitOffset>
              <bitWidth>1</bitWidth>
            </field>
            <field>
              <name>OVR</name>
              <bitOffset>6</bitOffset>
              <bitWidth>1</bitWidth>
            </field>
            <field>
              <name>CRCE</name>
              <bitOffset>7</bitOffset>
              <bitWidth>1</bitWidth>
            </field>
            <field>
              <name>TIFRE</name>
              <bitOffset>8</bitOffset>
              <bitWidth>1</bitWidth>
            </field>
            <field>
              <name>MODF</name>
              <bitOffset>9</bitOffset>
              <bitWidth>1</bitWidth>
            </field>
            <field>
              <name>TSERF</name>
              <bitOffset>10</bitOffset>
              <bitWidth>1</bitWidth>
            </field>
            <field>
              <name>SUSP</name>
              <bitOffset>11</bitOffset>
              <bitWidth>1</bitWidth>
            </field>
            <field>
              <name>TXC</name>
              <bitOffset>12</bitOffset>
              <bitWidth>1</bitWidth>
            </field>
            <field>
              <name>RXPLVL</name>
              <bitOffset>13</bitOffset>
              <bitWidth>2</bitWidth>
            </field>
            <field>
              <name>RXWNE</name>
              <bitOffset>15</bitOffset>
              <bitWidth>1</bitWidth>
            </field>
            <field>
              <name>CTSIZE</name>
              <bitOffset>16</bitOffset>
              <bitWidth>16</bitWidth>
            </field>
          </fields>
        </register>
        <register>
          <name>IFCR</name>
          <addressOffset>0x18</addressOffset>
          <size>0x20</size>
          <fields>
            <field>
              <name>EOTC</name>
              <bitOffset>3</bitOffset>
              <bitWidth>1</bitWidth>
            </field>
            <field>
              <name>TXTFC</name>
              <bitOffset>4</bitOffset>
              <bitWidth>1</bitWidth>
            </field>
            <field>
              <name>UDRC</name>
              <bitOffset>5</bitOffset>
              <bitWidth>1</bitWidth>
            </field>
            <field>
              <name>OVRC</name>
              <bitOffset>6</bitOffset>
              <bitWidth>1</bitWidth>
            </field>
            <field>
              <name>CRCEC</name>
              <bitOffset>7</bitOffset>
              <bitWidth>1</bitWidth>
            </field>
            <field>
              <name>TIFREC</name>
              <bitOffset>8</bitOffset>
              <bitWidth>1</bitWidth>
            </field>
            <field>
              <name>MODFC</name>
              <bitOffset>9</bitOffset>
              <bitWidth>1</bitWidth>
            </field>
            <field>
              <name>TSERFC</name>
              <bitOffset>10</bitOffset>
              <bitWidth>1</bitWidth>
            </field>
            <field>
              <name>SUSPC</name>
              <bitOffset>11</bitOffset>
              <bitWidth>1</bitWidth>
            </field>
          </fields>
        </register>
        <register>
          <name>TXDR</name>
          <addressOffset>0x20</addressOffset>
          <size>0x20</size>
          <fields>
            <field>
              <name>TXDR</name>
              <bitOffset>0</bitOffset>
              <bitWidth>32</bitWidth>
            </field>
          </fields>
        </register>
        <register>
          <name>RXDR</name>
          <addressOffset>0x30</addressOffset>
          <size>0x20</size>
          <fields>
            <field>
              <name>RXDR</name>
              <bitOffset>0</bitOffset>
              <bitWidth>32</bitWidth>
            </field>
          </fields>
        </register>
        <register>
          <name>CRCPOLY</name>
          <addressOffset>0x40</addressOffset>
          <size>0x20</size>
          <fields>
            <field>
              <name>CRCPOLY</name>
              <bitOffset>0</bitOffset>
              <bitWidth>32</bitWidth>
            </field>
          </fields>
        </register>
        <register>
          <name>TXCRC</name>
          <addressOffset>0x44</addressOffset>
          <size>0x20</size>
          <fields>
            <field>
              <name>TXCRC</name>
              <bitOffset>0</bitOffset>
              <bitWidth>32</bitWidth>
            </field>
          </fields>
        </register>
        <register>
          <name>RXCRC</name>
          <addressOffset>0x48</addressOffset>
          <size>0x20</size>
          <fields>
            <field>
              <name>RXCRC</name>
              <bitOffset>0</bitOffset>
              <bitWidth>32</bitWidth>
            </field>
          </fields>
        </register>
        <register>
          <name>UDRDR</name>
          <addressOffset>0x4c</addressOffset>
          <size>0x20</size>
          <fields>
            <field>
              <name>UDRDR</name>
              <bitOffset>0</bitOffset>
              <bitWidth>32</bitWidth>
            </field>
          </fields>
        </register>
        <register>
          <name>I2SCFGR</name>
          <addressOffset>0x50</addressOffset>
          <size>0x20</size>
          <fields>
            <field>
              <name>I2SMOD</name>
              <bitOffset>0</bitOffset>
              <bitWidth>1</bitWidth>
            </field>
            <field>
              <name>I2SCFG</name>
              <bitOffset>1</bitOffset>
              <bitWidth>3</bitWidth>
            </field>
            <field>
              <name>I2SSTD</name>
              <bitOffset>4</bitOffset>
              <bitWidth>2</bitWidth>
            </field>
            <field>
              <name>PCMSYNC</name>
              <bitOffset>7</bitOffset>
              <bitWidth>1</bitWidth>
            </field>
            <field>
              <name>DATLEN</name>
              <bitOffset>8</bitOffset>
              <bitWidth>2</bitWidth>
            </field>
            <field>
              <name>CHLEN</name>
              <bitOffset>10</bitOffset>
              <bitWidth>1</bitWidth>
            </field>
            <field>
              <name>CKPOL</name>
              <bitOffset>11</bitOffset>
              <bitWidth>1</bitWidth>
            </field>
            <field>
              <name>FIXCH</name>
              <bitOffset>12</bitOffset>
              <bitWidth>1</bitWidth>
            </field>
            <field>
              <name>WSINV</name>
              <bitOffset>13</bitOffset>
              <bitWidth>1</bitWidth>
            </field>
            <field>
              <name>DATFMT</name>
              <bitOffset>14</bitOffset>
              <bitWidth>1</bitWidth>
            </field>
            <field>
              <name>I2SDIV</name>
              <bitOffset>16</bitOffset>
              <bitWidth>8</bitWidth>
            </field>
            <field>
              <name>ODD</name>
              <bitOffset>24</bitOffset>
              <bitWidth>1</bitWidth>
            </field>
            <field>
              <name>MCKOE</name>
              <bitOffset>25</bitOffset>
              <bitWidth>1</bitWidth>
            </field>
          </fields>
        </register>
      </registers>
    </peripheral>
    <peripheral>
      <name>TIM15</name>
      <baseAddress>0x40014000</baseAddress>
      <registers>
        <register>
          <name>CR1</name>
          <addressOffset>0x0</addressOffset>
          <size>0x20</size>
          <fields>
            <field>
              <name>CEN</name>
              <bitOffset>0</bitOffset>
              <bitWidth>1</bitWidth>
            </field>
            <field>
              <name>UDIS</name>
              <bitOffset>1</bitOffset>
              <bitWidth>1</bitWidth>
            </field>
            <field>
              <name>URS</name>
              <bitOffset>2</bitOffset>
              <bitWidth>1</bitWidth>
            </field>
            <field>
              <name>OPM</name>
              <bitOffset>3</bitOffset>
              <bitWidth>1</bitWidth>
            </field>
            <field>
              <name>DIR</name>
              <bitOffset>4</bitOffset>
              <bitWidth>1</bitWidth>
            </field>
            <field>
              <name>CMS</name>
              <bitOffset>5</bitOffset>
              <bitWidth>2</bitWidth>
            </field>
            <field>
              <name>ARPE</name>
              <bitOffset>7</bitOffset>
              <bitWidth>1</bitWidth>
            </field>
            <field>
              <name>CKD</name>
              <bitOffset>8</bitOffset>
              <bitWidth>2</bitWidth>
            </field>
            <field>
              <name>UIFREMAP</name>
              <bitOffset>11</bitOffset>
              <bitWidth>1</bitWidth>
            </field>
          </fields>
        </register>
        <register>
          <name>CR2</name>
          <addressOffset>0x4</addressOffset>
          <size>0x20</size>
          <fields>
            <field>
              <name>CCPC</name>
              <bitOffset>0</bitOffset>
              <bitWidth>1</bitWidth>
            </field>
            <field>
              <name>CCUS</name>
              <bitOffset>2</bitOffset>
              <bitWidth>1</bitWidth>
            </field>
            <field>
              <name>CCDS</name>
              <bitOffset>3</bitOffset>
              <bitWidth>1</bitWidth>
            </field>
            <field>
              <name>MMS</name>
              <bitOffset>4</bitOffset>
              <bitWidth>3</bitWidth>
            </field>
            <field>
              <name>TI1S</name>
              <bitOffset>7</bitOffset>
              <bitWidth>1</bitWidth>
            </field>
            <field>
              <name>OIS1</name>
              <bitOffset>8</bitOffset>
              <bitWidth>1</bitWidth>
            </field>
            <field>
              <name>OIS1N</name>
              <bitOffset>9</bitOffset>
              <bitWidth>1</bitWidth>
            </field>
            <field>
              <name>OIS2</name>
              <bitOffset>10</bitOffset>
              <bitWidth>1</bitWidth>
            </field>
            <field>
              <name>OIS2N</name>
              <bitOffset>11</bitOffset>
              <bitWidth>1</bitWidth>
            </field>
            <field>
              <name>OIS3</name>
              <bitOffset>12</bitOffset>
              <bitWidth>1</bitWidth>
            </field>
            <field>
              <name>OIS3N</name>
              <bitOffset>13</bitOffset>
              <bitWidth>1</bitWidth>
            </field>
            <field>
              <name>OIS4</name>
              <bitOffset>14</bitOffset>
              <bitWidth>1</bitWidth>
            </field>
            <field>
              <name>OIS5</name>
              <bitOffset>16</bitOffset>
              <bitWidth>1</bitWidth>
            </field>
            <field>
              <name>OIS6</name>
              <bitOffset>18</bitOffset>
              <bitWidth>1</bitWidth>
            </field>
            <field>
              <name>MMS2</name>
              <bitOffset>20</bitOffset>
              <bitWidth>4</bitWidth>
            </field>
          </fields>
        </register>
        <register>
          <name>SMCR</name>
          <addressOffset>0x8</addressOffset>
          <size>0x20</size>
          <fields>
            <field>
              <name>SMS</name>
              <bitOffset>0</bitOffset>
              <bitWidth>17</bitWidth>
            </field>
            <field>
              <name>TS</name>
              <bitOffset>4</bitOffset>
              <bitWidth>18</bitWidth>
            </field>
            <field>
              <name>MSM</name>
              <bitOffset>7</bitOffset>
              <bitWidth>1</bitWidth>
            </field>
            <field>
              <name>ETF</name>
              <bitOffset>8</bitOffset>
              <bitWidth>4</bitWidth>
            </field>
            <field>
              <name>ETPS</name>
              <bitOffset>12</bitOffset>
              <bitWidth>2</bitWidth>
            </field>
            <field>
              <name>ECE</name>
              <bitOffset>14</bitOffset>
              <bitWidth>1</bitWidth>
            </field>
            <field>
              <name>ETP</name>
              <bitOffset>15</bitOffset>
              <bitWidth>1</bitWidth>
            </field>
          </fields>
        </register>
        <register>
          <name>DIER</name>
          <addressOffset>0xc</addressOffset>
          <size>0x20</size>
          <fields>
            <field>
              <name>UIE</name>
              <bitOffset>0</bitOffset>
              <bitWidth>1</bitWidth>
            </field>
            <field>
              <name>CC1IE</name>
              <bitOffset>1</bitOffset>
              <bitWidth>1</bitWidth>
            </field>
            <field>
              <name>CC2IE</name>
              <bitOffset>2</bitOffset>
              <bitWidth>1</bitWidth>
            </field>
            <field>
              <name>CC3IE</name>
              <bitOffset>3</bitOffset>
              <bitWidth>1</bitWidth>
            </field>
            <field>
              <name>CC4IE</name>
              <bitOffset>4</bitOffset>
              <bitWidth>1</bitWidth>
            </field>
            <field>
              <name>COMIE</name>
              <bitOffset>5</bitOffset>
              <bitWidth>1</bitWidth>
            </field>
            <field>
              <name>TIE</name>
              <bitOffset>6</bitOffset>
              <bitWidth>1</bitWidth>
            </field>
            <field>
              <name>BIE</name>
              <bitOffset>7</bitOffset>
              <bitWidth>1</bitWidth>
            </field>
            <field>
              <name>UDE</name>
              <bitOffset>8</bitOffset>
              <bitWidth>1</bitWidth>
            </field>
            <field>
              <name>CC1DE</name>
              <bitOffset>9</bitOffset>
              <bitWidth>1</bitWidth>
            </field>
            <field>
              <name>CC2DE</name>
              <bitOffset>10</bitOffset>
              <bitWidth>1</bitWidth>
            </field>
            <field>
              <name>CC3DE</name>
              <bitOffset>11</bitOffset>
              <bitWidth>1</bitWidth>
            </field>
            <field>
              <name>CC4DE</name>
              <bitOffset>12</bitOffset>
              <bitWidth>1</bitWidth>
            </field>
            <field>
              <name>COMDE</name>
              <bitOffset>13</bitOffset>
              <bitWidth>1</bitWidth>
            </field>
            <field>
              <name>TDE</name>
              <bitOffset>14</bitOffset>
              <bitWidth>1</bitWidth>
            </field>
          </fields>
        </register>
        <register>
          <name>SR</name>
          <addressOffset>0x10</addressOffset>
          <size>0x20</size>
          <fields>
            <field>
              <name>UIF</name>
              <bitOffset>0</bitOffset>
              <bitWidth>1</bitWidth>
            </field>
            <field>
              <name>CC1IF</name>
              <bitOffset>1</bitOffset>
              <bitWidth>1</bitWidth>
            </field>
            <field>
              <name>CC2IF</name>
              <bitOffset>2</bitOffset>
              <bitWidth>1</bitWidth>
            </field>
            <field>
              <name>CC3IF</name>
              <bitOffset>3</bitOffset>
              <bitWidth>1</bitWidth>
            </field>
            <field>
              <name>CC4IF</name>
              <bitOffset>4</bitOffset>
              <bitWidth>1</bitWidth>
            </field>
            <field>
              <name>COMIF</name>
              <bitOffset>5</bitOffset>
              <bitWidth>1</bitWidth>
            </field>
            <field>
              <name>TIF</name>
              <bitOffset>6</bitOffset>
              <bitWidth>1</bitWidth>
            </field>
            <field>
              <name>BIF</name>
              <bitOffset>7</bitOffset>
              <bitWidth>1</bitWidth>
            </field>
            <field>
              <name>B2IF</name>
              <bitOffset>8</bitOffset>
              <bitWidth>1</bitWidth>
            </field>
            <field>
              <name>CC1OF</name>
              <bitOffset>9</bitOffset>
              <bitWidth>1</bitWidth>
            </field>
            <field>
              <name>CC2OF</name>
              <bitOffset>10</bitOffset>
              <bitWidth>1</bitWidth>
            </field>
            <field>
              <name>CC3OF</name>
              <bitOffset>11</bitOffset>
              <bitWidth>1</bitWidth>
            </field>
            <field>
              <name>CC4OF</name>
              <bitOffset>12</bitOffset>
              <bitWidth>1</bitWidth>
            </field>
            <field>
              <name>SBIF</name>
              <bitOffset>13</bitOffset>
              <bitWidth>1</bitWidth>
            </field>
            <field>
              <name>CC5IF</name>
              <bitOffset>16</bitOffset>
              <bitWidth>1</bitWidth>
            </field>
            <field>
              <name>CC6IF</name>
              <bitOffset>17</bitOffset>
              <bitWidth>1</bitWidth>
            </field>
          </fields>
        </register>
        <register>
          <name>EGR</name>
          <addressOffset>0x14</addressOffset>
          <size>0x20</size>
          <fields>
            <field>
              <name>UG</name>
              <bitOffset>0</bitOffset>
              <bitWidth>1</bitWidth>
            </field>
            <field>
              <name>CC1G</name>
              <bitOffset>1</bitOffset>
              <bitWidth>1</bitWidth>
            </field>
            <field>
              <name>CC2G</name>
              <bitOffset>2</bitOffset>
              <bitWidth>1</bitWidth>
            </field>
            <field>
              <name>CC3G</name>
              <bitOffset>3</bitOffset>
              <bitWidth>1</bitWidth>
            </field>
            <field>
              <name>CC4G</name>
              <bitOffset>4</bitOffset>
              <bitWidth>1</bitWidth>
            </field>
            <field>
              <name>COMG</name>
              <bitOffset>5</bitOffset>
              <bitWidth>1</bitWidth>
            </field>
            <field>
              <name>TG</name>
              <bitOffset>6</bitOffset>
              <bitWidth>1</bitWidth>
            </field>
            <field>
              <name>BG</name>
              <bitOffset>7</bitOffset>
              <bitWidth>1</bitWidth>
            </field>
            <field>
              <name>B2G</name>
              <bitOffset>8</bitOffset>
              <bitWidth>1</bitWidth>
            </field>
          </fields>
        </register>
        <register>
          <name>CCMR1</name>
          <addressOffset>0x18</addressOffset>
          <size>0x20</size>
          <fields>
            <field>
              <name>CC1S</name>
              <bitOffset>0</bitOffset>
              <bitWidth>2</bitWidth>
            </field>
            <field>
              <name>OC1FE</name>
              <bitOffset>2</bitOffset>
              <bitWidth>1</bitWidth>
            </field>
            <field>
              <name>OC1PE</name>
              <bitOffset>3</bitOffset>
              <bitWidth>1</bitWidth>
            </field>
            <field>
              <name>OC1M</name>
              <bitOffset>4</bitOffset>
              <bitWidth>13</bitWidth>
            </field>
            <field>
              <name>OC1CE</name>
              <bitOffset>7</bitOffset>
              <bitWidth>1</bitWidth>
            </field>
            <field>
              <name>CC2S</name>
              <bitOffset>8</bitOffset>
              <bitWidth>2</bitWidth>
            </field>
            <field>
              <name>OC2FE</name>
              <bitOffset>10</bitOffset>
              <bitWidth>1</bitWidth>
            </field>
            <field>
              <name>OC2PE</name>
              <bitOffset>11</bitOffset>
              <bitWidth>1</bitWidth>
            </field>
            <field>
              <name>OC2M</name>
              <bitOffset>12</bitOffset>
              <bitWidth>13</bitWidth>
            </field>
            <field>
              <name>OC2CE</name>
              <bitOffset>15</bitOffset>
              <bitWidth>1</bitWidth>
            </field>
          </fields>
        </register>
        <register>
          <name>CCMR2</name>
          <addressOffset>0x1c</addressOffset>
          <size>0x20</size>
          <fields>
            <field>
              <name>CC3S</name>
              <bitOffset>0</bitOffset>
              <bitWidth>2</bitWidth>
            </field>
            <field>
              <name>OC3FE</name>
              <bitOffset>2</bitOffset>
              <bitWidth>1</bitWidth>
            </field>
            <field>
              <name>OC3PE</name>
              <bitOffset>3</bitOffset>
              <bitWidth>1</bitWidth>
            </field>
            <field>
              <name>OC3M</name>
              <bitOffset>4</bitOffset>
              <bitWidth>13</bitWidth>
            </field>
            <field>
              <name>OC3CE</name>
              <bitOffset>7</bitOffset>
              <bitWidth>1</bitWidth>
            </field>
            <field>
              <name>CC4S</name>
              <bitOffset>8</bitOffset>
              <bitWidth>2</bitWidth>
            </field>
            <field>
              <name>OC4FE</name>
              <bitOffset>10</bitOffset>
              <bitWidth>1</bitWidth>
            </field>
            <field>
              <name>OC4PE</name>
              <bitOffset>11</bitOffset>
              <bitWidth>1</bitWidth>
            </field>
            <field>
              <name>OC4M</name>
              <bitOffset>12</bitOffset>
              <bitWidth>13</bitWidth>
            </field>
            <field>
              <name>OC4CE</name>
              <bitOffset>15</bitOffset>
              <bitWidth>1</bitWidth>
            </field>
          </fields>
        </register>
        <register>
          <name>CCER</name>
          <addressOffset>0x20</addressOffset>
          <size>0x20</size>
          <fields>
            <field>
              <name>CC1E</name>
              <bitOffset>0</bitOffset>
              <bitWidth>1</bitWidth>
            </field>
            <field>
              <name>CC1P</name>
              <bitOffset>1</bitOffset>
              <bitWidth>1</bitWidth>
            </field>
            <field>
              <name>CC1NE</name>
              <bitOffset>2</bitOffset>
              <bitWidth>1</bitWidth>
            </field>
            <field>
              <name>CC1NP</name>
              <bitOffset>3</bitOffset>
              <bitWidth>1</bitWidth>
            </field>
            <field>
              <name>CC2E</name>
              <bitOffset>4</bitOffset>
              <bitWidth>1</bitWidth>
            </field>
            <field>
              <name>CC2P</name>
              <bitOffset>5</bitOffset>
              <bitWidth>1</bitWidth>
            </field>
            <field>
              <name>CC2NE</name>
              <bitOffset>6</bitOffset>
              <bitWidth>1</bitWidth>
            </field>
            <field>
              <name>CC2NP</name>
              <bitOffset>7</bitOffset>
              <bitWidth>1</bitWidth>
            </field>
            <field>
              <name>CC3E</name>
              <bitOffset>8</bitOffset>
              <bitWidth>1</bitWidth>
            </field>
            <field>
              <name>CC3P</name>
              <bitOffset>9</bitOffset>
              <bitWidth>1</bitWidth>
            </field>
            <field>
              <name>CC3NE</name>
              <bitOffset>10</bitOffset>
              <bitWidth>1</bitWidth>
            </field>
            <field>
              <name>CC3NP</name>
              <bitOffset>11</bitOffset>
              <bitWidth>1</bitWidth>
            </field>
            <field>
              <name>CC4E</name>
              <bitOffset>12</bitOffset>
              <bitWidth>1</bitWidth>
            </field>
            <field>
              <name>CC4P</name>
              <bitOffset>13</bitOffset>
              <bitWidth>1</bitWidth>
            </field>
            <field>
              <name>CC4NP</name>
              <bitOffset>15</bitOffset>
              <bitWidth>1</bitWidth>
            </field>
            <field>
              <name>CC5E</name>
              <bitOffset>16</bitOffset>
              <bitWidth>1</bitWidth>
            </field>
            <field>
              <name>CC5P</name>
              <bitOffset>17</bitOffset>
              <bitWidth>1</bitWidth>
            </field>
            <field>
              <name>CC6E</name>
              <bitOffset>20</bitOffset>
              <bitWidth>1</bitWidth>
            </field>
            <field>
              <name>CC6P</name>
              <bitOffset>21</bitOffset>
              <bitWidth>1</bitWidth>
            </field>
          </fields>
        </register>
        <register>
          <name>CNT</name>
          <addressOffset>0x24</addressOffset>
          <size>0x20</size>
          <fields>
            <field>
              <name>CNT</name>
              <bitOffset>0</bitOffset>
              <bitWidth>32</bitWidth>
            </field>
            <field>
              <name>UIFCPY</name>
              <bitOffset>31</bitOffset>
              <bitWidth>1</bitWidth>
            </field>
          </fields>
        </register>
        <register>
          <name>PSC</name>
          <addressOffset>0x28</addressOffset>
          <size>0x20</size>
          <fields>
            <field>
              <name>PSC</name>
              <bitOffset>0</bitOffset>
              <bitWidth>16</bitWidth>
            </field>
          </fields>
        </register>
        <register>
          <name>ARR</name>
          <addressOffset>0x2c</addressOffset>
          <size>0x20</size>
          <fields>
            <field>
              <name>ARR</name>
              <bitOffset>0</bitOffset>
              <bitWidth>32</bitWidth>
            </field>
          </fields>
        </register>
        <register>
          <name>RCR</name>
          <addressOffset>0x30</addressOffset>
          <size>0x20</size>
          <fields>
            <field>
              <name>REP</name>
              <bitOffset>0</bitOffset>
              <bitWidth>8</bitWidth>
            </field>
          </fields>
        </register>
        <register>
          <name>CCR1</name>
          <addressOffset>0x34</addressOffset>
          <size>0x20</size>
          <fields>
            <field>
              <name>CCR1</name>
              <bitOffset>0</bitOffset>
              <bitWidth>16</bitWidth>
            </field>
          </fields>
        </register>
        <register>
          <name>CCR2</name>
          <addressOffset>0x38</addressOffset>
          <size>0x20</size>
          <fields>
            <field>
              <name>CCR2</name>
              <bitOffset>0</bitOffset>
              <bitWidth>16</bitWidth>
            </field>
          </fields>
        </register>
        <register>
          <name>CCR3</name>
          <addressOffset>0x3c</addressOffset>
          <size>0x20</size>
          <fields>
            <field>
              <name>CCR3</name>
              <bitOffset>0</bitOffset>
              <bitWidth>16</bitWidth>
            </field>
          </fields>
        </register>
        <register>
          <name>CCR4</name>
          <addressOffset>0x40</addressOffset>
          <size>0x20</size>
          <fields>
            <field>
              <name>CCR4</name>
              <bitOffset>0</bitOffset>
              <bitWidth>16</bitWidth>
            </field>
          </fields>
        </register>
        <register>
          <name>BDTR</name>
          <addressOffset>0x44</addressOffset>
          <size>0x20</size>
          <fields>
            <field>
              <name>DTG</name>
              <bitOffset>0</bitOffset>
              <bitWidth>8</bitWidth>
            </field>
            <field>
              <name>LOCK</name>
              <bitOffset>8</bitOffset>
              <bitWidth>2</bitWidth>
            </field>
            <field>
              <name>OSSI</name>
              <bitOffset>10</bitOffset>
              <bitWidth>1</bitWidth>
            </field>
            <field>
              <name>OSSR</name>
              <bitOffset>11</bitOffset>
              <bitWidth>1</bitWidth>
            </field>
            <field>
              <name>BKE</name>
              <bitOffset>12</bitOffset>
              <bitWidth>1</bitWidth>
            </field>
            <field>
              <name>BKP</name>
              <bitOffset>13</bitOffset>
              <bitWidth>1</bitWidth>
            </field>
            <field>
              <name>AOE</name>
              <bitOffset>14</bitOffset>
              <bitWidth>1</bitWidth>
            </field>
            <field>
              <name>MOE</name>
              <bitOffset>15</bitOffset>
              <bitWidth>1</bitWidth>
            </field>
            <field>
              <name>BKF</name>
              <bitOffset>16</bitOffset>
              <bitWidth>4</bitWidth>
            </field>
            <field>
              <name>BK2F</name>
              <bitOffset>20</bitOffset>
              <bitWidth>4</bitWidth>
            </field>
            <field>
              <name>BK2E</name>
              <bitOffset>24</bitOffset>
              <bitWidth>1</bitWidth>
            </field>
            <field>
              <name>BK2P</name>
              <bitOffset>25</bitOffset>
              <bitWidth>1</bitWidth>
            </field>
          </fields>
        </register>
        <register>
          <name>DCR</name>
          <addressOffset>0x48</addressOffset>
          <size>0x20</size>
          <fields>
            <field>
              <name>DBA</name>
              <bitOffset>0</bitOffset>
              <bitWidth>5</bitWidth>
            </field>
            <field>
              <name>DBL</name>
              <bitOffset>8</bitOffset>
              <bitWidth>5</bitWidth>
            </field>
          </fields>
        </register>
        <register>
          <name>DMAR</name>
          <addressOffset>0x4c</addressOffset>
          <size>0x20</size>
          <fields>
            <field>
              <name>DMAB</name>
              <bitOffset>0</bitOffset>
              <bitWidth>16</bitWidth>
            </field>
          </fields>
        </register>
        <register>
          <name>CCMR3</name>
          <addressOffset>0x54</addressOffset>
          <size>0x20</size>
          <fields>
            <field>
              <name>OC5FE</name>
              <bitOffset>2</bitOffset>
              <bitWidth>1</bitWidth>
            </field>
            <field>
              <name>OC5PE</name>
              <bitOffset>3</bitOffset>
              <bitWidth>1</bitWidth>
            </field>
            <field>
              <name>OC5M</name>
              <bitOffset>4</bitOffset>
              <bitWidth>13</bitWidth>
            </field>
            <field>
              <name>OC5CE</name>
              <bitOffset>7</bitOffset>
              <bitWidth>1</bitWidth>
            </field>
            <field>
              <name>OC6FE</name>
              <bitOffset>10</bitOffset>
              <bitWidth>1</bitWidth>
            </field>
            <field>
              <name>OC6PE</name>
              <bitOffset>11</bitOffset>
              <bitWidth>1</bitWidth>
            </field>
            <field>
              <name>OC6M</name>
              <bitOffset>12</bitOffset>
              <bitWidth>13</bitWidth>
            </field>
            <field>
              <name>OC6CE</name>
              <bitOffset>15</bitOffset>
              <bitWidth>1</bitWidth>
            </field>
          </fields>
        </register>
        <register>
          <name>CCR5</name>
          <addressOffset>0x58</addressOffset>
          <size>0x20</size>
          <fields>
            <field>
              <name>CCR5</name>
              <bitOffset>0</bitOffset>
              <bitWidth>32</bitWidth>
            </field>
            <field>
              <name>GC5C1</name>
              <bitOffset>29</bitOffset>
              <bitWidth>1</bitWidth>
            </field>
            <field>
              <name>GC5C2</name>
              <bitOffset>30</bitOffset>
              <bitWidth>1</bitWidth>
            </field>
            <field>
              <name>GC5C3</name>
              <bitOffset>31</bitOffset>
              <bitWidth>1</bitWidth>
            </field>
          </fields>
        </register>
        <register>
          <name>CCR6</name>
          <addressOffset>0x5c</addressOffset>
          <size>0x20</size>
          <fields>
            <field>
              <name>CCR6</name>
              <bitOffset>0</bitOffset>
              <bitWidth>16</bitWidth>
            </field>
          </fields>
        </register>
        <register>
          <name>AF1</name>
          <addressOffset>0x60</addressOffset>
          <size>0x20</size>
        </register>
        <register>
          <name>AF2</name>
          <addressOffset>0x64</addressOffset>
          <size>0x20</size>
        </register>
        <register>
          <name>TISEL</name>
          <addressOffset>0x68</addressOffset>
          <size>0x20</size>
          <fields>
            <field>
              <name>TI1SEL</name>
              <bitOffset>0</bitOffset>
              <bitWidth>4</bitWidth>
            </field>
            <field>
              <name>TI2SEL</name>
              <bitOffset>8</bitOffset>
              <bitWidth>4</bitWidth>
            </field>
            <field>
              <name>TI3SEL</name>
              <bitOffset>16</bitOffset>
              <bitWidth>4</bitWidth>
            </field>
            <field>
              <name>TI4SEL</name>
              <bitOffset>24</bitOffset>
              <bitWidth>4</bitWidth>
            </field>
          </fields>
        </register>
      </registers>
    </peripheral>
    <peripheral>
      <name>TIM16</name>
      <baseAddress>0x40014400</baseAddress>
      <registers>
        <register>
          <name>CR1</name>
          <addressOffset>0x0</addressOffset>
          <size>0x20</size>
          <fields>
            <field>
              <name>CEN</name>
              <bitOffset>0</bitOffset>
              <bitWidth>1</bitWidth>
            </field>
            <field>
              <name>UDIS</name>
              <bitOffset>1</bitOffset>
              <bitWidth>1</bitWidth>
            </field>
            <field>
              <name>URS</name>
              <bitOffset>2</bitOffset>
              <bitWidth>1</bitWidth>
            </field>
            <field>
              <name>OPM</name>
              <bitOffset>3</bitOffset>
              <bitWidth>1</bitWidth>
            </field>
            <field>
              <name>DIR</name>
              <bitOffset>4</bitOffset>
              <bitWidth>1</bitWidth>
            </field>
            <field>
              <name>CMS</name>
              <bitOffset>5</bitOffset>
              <bitWidth>2</bitWidth>
            </field>
            <field>
              <name>ARPE</name>
              <bitOffset>7</bitOffset>
              <bitWidth>1</bitWidth>
            </field>
            <field>
              <name>CKD</name>
              <bitOffset>8</bitOffset>
              <bitWidth>2</bitWidth>
            </field>
            <field>
              <name>UIFREMAP</name>
              <bitOffset>11</bitOffset>
              <bitWidth>1</bitWidth>
            </field>
          </fields>
        </register>
        <register>
          <name>CR2</name>
          <addressOffset>0x4</addressOffset>
          <size>0x20</size>
          <fields>
            <field>
              <name>CCPC</name>
              <bitOffset>0</bitOffset>
              <bitWidth>1</bitWidth>
            </field>
            <field>
              <name>CCUS</name>
              <bitOffset>2</bitOffset>
              <bitWidth>1</bitWidth>
            </field>
            <field>
              <name>CCDS</name>
              <bitOffset>3</bitOffset>
              <bitWidth>1</bitWidth>
            </field>
            <field>
              <name>MMS</name>
              <bitOffset>4</bitOffset>
              <bitWidth>3</bitWidth>
            </field>
            <field>
              <name>TI1S</name>
              <bitOffset>7</bitOffset>
              <bitWidth>1</bitWidth>
            </field>
            <field>
              <name>OIS1</name>
              <bitOffset>8</bitOffset>
              <bitWidth>1</bitWidth>
            </field>
            <field>
              <name>OIS1N</name>
              <bitOffset>9</bitOffset>
              <bitWidth>1</bitWidth>
            </field>
            <field>
              <name>OIS2</name>
              <bitOffset>10</bitOffset>
              <bitWidth>1</bitWidth>
            </field>
            <field>
              <name>OIS2N</name>
              <bitOffset>11</bitOffset>
              <bitWidth>1</bitWidth>
            </field>
            <field>
              <name>OIS3</name>
              <bitOffset>12</bitOffset>
              <bitWidth>1</bitWidth>
            </field>
            <field>
              <name>OIS3N</name>
              <bitOffset>13</bitOffset>
              <bitWidth>1</bitWidth>
            </field>
            <field>
              <name>OIS4</name>
              <bitOffset>14</bitOffset>
              <bitWidth>1</bitWidth>
            </field>
            <field>
              <name>OIS5</name>
              <bitOffset>16</bitOffset>
              <bitWidth>1</bitWidth>
            </field>
            <field>
              <name>OIS6</name>
              <bitOffset>18</bitOffset>
              <bitWidth>1</bitWidth>
            </field>
            <field>
              <name>MMS2</name>
              <bitOffset>20</bitOffset>
              <bitWidth>4</bitWidth>
            </field>
          </fields>
        </register>
        <register>
          <name>SMCR</name>
          <addressOffset>0x8</addressOffset>
          <size>0x20</size>
          <fields>
            <field>
              <name>SMS</name>
              <bitOffset>0</bitOffset>
              <bitWidth>17</bitWidth>
            </field>
            <field>
              <name>TS</name>
              <bitOffset>4</bitOffset>
              <bitWidth>18</bitWidth>
            </field>
            <field>
              <name>MSM</name>
              <bitOffset>7</bitOffset>
              <bitWidth>1</bitWidth>
            </field>
            <field>
              <name>ETF</name>
              <bitOffset>8</bitOffset>
              <bitWidth>4</bitWidth>
            </field>
            <field>
              <name>ETPS</name>
              <bitOffset>12</bitOffset>
              <bitWidth>2</bitWidth>
            </field>
            <field>
              <name>ECE</name>
              <bitOffset>14</bitOffset>
              <bitWidth>1</bitWidth>
            </field>
            <field>
              <name>ETP</name>
              <bitOffset>15</bitOffset>
              <bitWidth>1</bitWidth>
            </field>
          </fields>
        </register>
        <register>
          <name>DIER</name>
          <addressOffset>0xc</addressOffset>
          <size>0x20</size>
          <fields>
            <field>
              <name>UIE</name>
              <bitOffset>0</bitOffset>
              <bitWidth>1</bitWidth>
            </field>
            <field>
              <name>CC1IE</name>
              <bitOffset>1</bitOffset>
              <bitWidth>1</bitWidth>
            </field>
            <field>
              <name>CC2IE</name>
              <bitOffset>2</bitOffset>
              <bitWidth>1</bitWidth>
            </field>
            <field>
              <name>CC3IE</name>
              <bitOffset>3</bitOffset>
              <bitWidth>1</bitWidth>
            </field>
            <field>
              <name>CC4IE</name>
              <bitOffset>4</bitOffset>
              <bitWidth>1</bitWidth>
            </field>
            <field>
              <name>COMIE</name>
              <bitOffset>5</bitOffset>
              <bitWidth>1</bitWidth>
            </field>
            <field>
              <name>TIE</name>
              <bitOffset>6</bitOffset>
              <bitWidth>1</bitWidth>
            </field>
            <field>
              <name>BIE</name>
              <bitOffset>7</bitOffset>
              <bitWidth>1</bitWidth>
            </field>
            <field>
              <name>UDE</name>
              <bitOffset>8</bitOffset>
              <bitWidth>1</bitWidth>
            </field>
            <field>
              <name>CC1DE</name>
              <bitOffset>9</bitOffset>
              <bitWidth>1</bitWidth>
            </field>
            <field>
              <name>CC2DE</name>
              <bitOffset>10</bitOffset>
              <bitWidth>1</bitWidth>
            </field>
            <field>
              <name>CC3DE</name>
              <bitOffset>11</bitOffset>
              <bitWidth>1</bitWidth>
            </field>
            <field>
              <name>CC4DE</name>
              <bitOffset>12</bitOffset>
              <bitWidth>1</bitWidth>
            </field>
            <field>
              <name>COMDE</name>
              <bitOffset>13</bitOffset>
              <bitWidth>1</bitWidth>
            </field>
            <field>
              <name>TDE</name>
              <bitOffset>14</bitOffset>
              <bitWidth>1</bitWidth>
            </field>
          </fields>
        </register>
        <register>
          <name>SR</name>
          <addressOffset>0x10</addressOffset>
          <size>0x20</size>
          <fields>
            <field>
              <name>UIF</name>
              <bitOffset>0</bitOffset>
              <bitWidth>1</bitWidth>
            </field>
            <field>
              <name>CC1IF</name>
              <bitOffset>1</bitOffset>
              <bitWidth>1</bitWidth>
            </field>
            <field>
              <name>CC2IF</name>
              <bitOffset>2</bitOffset>
              <bitWidth>1</bitWidth>
            </field>
            <field>
              <name>CC3IF</name>
              <bitOffset>3</bitOffset>
              <bitWidth>1</bitWidth>
            </field>
            <field>
              <name>CC4IF</name>
              <bitOffset>4</bitOffset>
              <bitWidth>1</bitWidth>
            </field>
            <field>
              <name>COMIF</name>
              <bitOffset>5</bitOffset>
              <bitWidth>1</bitWidth>
            </field>
            <field>
              <name>TIF</name>
              <bitOffset>6</bitOffset>
              <bitWidth>1</bitWidth>
            </field>
            <field>
              <name>BIF</name>
              <bitOffset>7</bitOffset>
              <bitWidth>1</bitWidth>
            </field>
            <field>
              <name>B2IF</name>
              <bitOffset>8</bitOffset>
              <bitWidth>1</bitWidth>
            </field>
            <field>
              <name>CC1OF</name>
              <bitOffset>9</bitOffset>
              <bitWidth>1</bitWidth>
            </field>
            <field>
              <name>CC2OF</name>
              <bitOffset>10</bitOffset>
              <bitWidth>1</bitWidth>
            </field>
            <field>
              <name>CC3OF</name>
              <bitOffset>11</bitOffset>
              <bitWidth>1</bitWidth>
            </field>
            <field>
              <name>CC4OF</name>
              <bitOffset>12</bitOffset>
              <bitWidth>1</bitWidth>
            </field>
            <field>
              <name>SBIF</name>
              <bitOffset>13</bitOffset>
              <bitWidth>1</bitWidth>
            </field>
            <field>
              <name>CC5IF</name>
              <bitOffset>16</bitOffset>
              <bitWidth>1</bitWidth>
            </field>
            <field>
              <name>CC6IF</name>
              <bitOffset>17</bitOffset>
              <bitWidth>1</bitWidth>
            </field>
          </fields>
        </register>
        <register>
          <name>EGR</name>
          <addressOffset>0x14</addressOffset>
          <size>0x20</size>
          <fields>
            <field>
              <name>UG</name>
              <bitOffset>0</bitOffset>
              <bitWidth>1</bitWidth>
            </field>
            <field>
              <name>CC1G</name>
              <bitOffset>1</bitOffset>
              <bitWidth>1</bitWidth>
            </field>
            <field>
              <name>CC2G</name>
              <bitOffset>2</bitOffset>
              <bitWidth>1</bitWidth>
            </field>
            <field>
              <name>CC3G</name>
              <bitOffset>3</bitOffset>
              <bitWidth>1</bitWidth>
            </field>
            <field>
              <name>CC4G</name>
              <bitOffset>4</bitOffset>
              <bitWidth>1</bitWidth>
            </field>
            <field>
              <name>COMG</name>
              <bitOffset>5</bitOffset>
              <bitWidth>1</bitWidth>
            </field>
            <field>
              <name>TG</name>
              <bitOffset>6</bitOffset>
              <bitWidth>1</bitWidth>
            </field>
            <field>
              <name>BG</name>
              <bitOffset>7</bitOffset>
              <bitWidth>1</bitWidth>
            </field>
            <field>
              <name>B2G</name>
              <bitOffset>8</bitOffset>
              <bitWidth>1</bitWidth>
            </field>
          </fields>
        </register>
        <register>
          <name>CCMR1</name>
          <addressOffset>0x18</addressOffset>
          <size>0x20</size>
          <fields>
            <field>
              <name>CC1S</name>
              <bitOffset>0</bitOffset>
              <bitWidth>2</bitWidth>
            </field>
            <field>
              <name>OC1FE</name>
              <bitOffset>2</bitOffset>
              <bitWidth>1</bitWidth>
            </field>
            <field>
              <name>OC1PE</name>
              <bitOffset>3</bitOffset>
              <bitWidth>1</bitWidth>
            </field>
            <field>
              <name>OC1M</name>
              <bitOffset>4</bitOffset>
              <bitWidth>13</bitWidth>
            </field>
            <field>
              <name>OC1CE</name>
              <bitOffset>7</bitOffset>
              <bitWidth>1</bitWidth>
            </field>
            <field>
              <name>CC2S</name>
              <bitOffset>8</bitOffset>
              <bitWidth>2</bitWidth>
            </field>
            <field>
              <name>OC2FE</name>
              <bitOffset>10</bitOffset>
              <bitWidth>1</bitWidth>
            </field>
            <field>
              <name>OC2PE</name>
              <bitOffset>11</bitOffset>
              <bitWidth>1</bitWidth>
            </field>
            <field>
              <name>OC2M</name>
              <bitOffset>12</bitOffset>
              <bitWidth>13</bitWidth>
            </field>
            <field>
              <name>OC2CE</name>
              <bitOffset>15</bitOffset>
              <bitWidth>1</bitWidth>
            </field>
          </fields>
        </register>
        <register>
          <name>CCMR2</name>
          <addressOffset>0x1c</addressOffset>
          <size>0x20</size>
          <fields>
            <field>
              <name>CC3S</name>
              <bitOffset>0</bitOffset>
              <bitWidth>2</bitWidth>
            </field>
            <field>
              <name>OC3FE</name>
              <bitOffset>2</bitOffset>
              <bitWidth>1</bitWidth>
            </field>
            <field>
              <name>OC3PE</name>
              <bitOffset>3</bitOffset>
              <bitWidth>1</bitWidth>
            </field>
            <field>
              <name>OC3M</name>
              <bitOffset>4</bitOffset>
              <bitWidth>13</bitWidth>
            </field>
            <field>
              <name>OC3CE</name>
              <bitOffset>7</bitOffset>
              <bitWidth>1</bitWidth>
            </field>
            <field>
              <name>CC4S</name>
              <bitOffset>8</bitOffset>
              <bitWidth>2</bitWidth>
            </field>
            <field>
              <name>OC4FE</name>
              <bitOffset>10</bitOffset>
              <bitWidth>1</bitWidth>
            </field>
            <field>
              <name>OC4PE</name>
              <bitOffset>11</bitOffset>
              <bitWidth>1</bitWidth>
            </field>
            <field>
              <name>OC4M</name>
              <bitOffset>12</bitOffset>
              <bitWidth>13</bitWidth>
            </field>
            <field>
              <name>OC4CE</name>
              <bitOffset>15</bitOffset>
              <bitWidth>1</bitWidth>
            </field>
          </fields>
        </register>
        <register>
          <name>CCER</name>
          <addressOffset>0x20</addressOffset>
          <size>0x20</size>
          <fields>
            <field>
              <name>CC1E</name>
              <bitOffset>0</bitOffset>
              <bitWidth>1</bitWidth>
            </field>
            <field>
              <name>CC1P</name>
              <bitOffset>1</bitOffset>
              <bitWidth>1</bitWidth>
            </field>
            <field>
              <name>CC1NE</name>
              <bitOffset>2</bitOffset>
              <bitWidth>1</bitWidth>
            </field>
            <field>
              <name>CC1NP</name>
              <bitOffset>3</bitOffset>
              <bitWidth>1</bitWidth>
            </field>
            <field>
              <name>CC2E</name>
              <bitOffset>4</bitOffset>
              <bitWidth>1</bitWidth>
            </field>
            <field>
              <name>CC2P</name>
              <bitOffset>5</bitOffset>
              <bitWidth>1</bitWidth>
            </field>
            <field>
              <name>CC2NE</name>
              <bitOffset>6</bitOffset>
              <bitWidth>1</bitWidth>
            </field>
            <field>
              <name>CC2NP</name>
              <bitOffset>7</bitOffset>
              <bitWidth>1</bitWidth>
            </field>
            <field>
              <name>CC3E</name>
              <bitOffset>8</bitOffset>
              <bitWidth>1</bitWidth>
            </field>
            <field>
              <name>CC3P</name>
              <bitOffset>9</bitOffset>
              <bitWidth>1</bitWidth>
            </field>
            <field>
              <name>CC3NE</name>
              <bitOffset>10</bitOffset>
              <bitWidth>1</bitWidth>
            </field>
            <field>
              <name>CC3NP</name>
              <bitOffset>11</bitOffset>
              <bitWidth>1</bitWidth>
            </field>
            <field>
              <name>CC4E</name>
              <bitOffset>12</bitOffset>
              <bitWidth>1</bitWidth>
            </field>
            <field>
              <name>CC4P</name>
              <bitOffset>13</bitOffset>
              <bitWidth>1</bitWidth>
            </field>
            <field>
              <name>CC4NP</name>
              <bitOffset>15</bitOffset>
              <bitWidth>1</bitWidth>
            </field>
            <field>
              <name>CC5E</name>
              <bitOffset>16</bitOffset>
              <bitWidth>1</bitWidth>
            </field>
            <field>
              <name>CC5P</name>
              <bitOffset>17</bitOffset>
              <bitWidth>1</bitWidth>
            </field>
            <field>
              <name>CC6E</name>
              <bitOffset>20</bitOffset>
              <bitWidth>1</bitWidth>
            </field>
            <field>
              <name>CC6P</name>
              <bitOffset>21</bitOffset>
              <bitWidth>1</bitWidth>
            </field>
          </fields>
        </register>
        <register>
          <name>CNT</name>
          <addressOffset>0x24</addressOffset>
          <size>0x20</size>
          <fields>
            <field>
              <name>CNT</name>
              <bitOffset>0</bitOffset>
              <bitWidth>32</bitWidth>
            </field>
            <field>
              <name>UIFCPY</name>
              <bitOffset>31</bitOffset>
              <bitWidth>1</bitWidth>
            </field>
          </fields>
        </register>
        <register>
          <name>PSC</name>
          <addressOffset>0x28</addressOffset>
          <size>0x20</size>
          <fields>
            <field>
              <name>PSC</name>
              <bitOffset>0</bitOffset>
              <bitWidth>16</bitWidth>
            </field>
          </fields>
        </register>
        <register>
          <name>ARR</name>
          <addressOffset>0x2c</addressOffset>
          <size>0x20</size>
          <fields>
            <field>
              <name>ARR</name>
              <bitOffset>0</bitOffset>
              <bitWidth>32</bitWidth>
            </field>
          </fields>
        </register>
        <register>
          <name>RCR</name>
          <addressOffset>0x30</addressOffset>
          <size>0x20</size>
          <fields>
            <field>
              <name>REP</name>
              <bitOffset>0</bitOffset>
              <bitWidth>8</bitWidth>
            </field>
          </fields>
        </register>
        <register>
          <name>CCR1</name>
          <addressOffset>0x34</addressOffset>
          <size>0x20</size>
          <fields>
            <field>
              <name>CCR1</name>
              <bitOffset>0</bitOffset>
              <bitWidth>16</bitWidth>
            </field>
          </fields>
        </register>
        <register>
          <name>CCR2</name>
          <addressOffset>0x38</addressOffset>
          <size>0x20</size>
          <fields>
            <field>
              <name>CCR2</name>
              <bitOffset>0</bitOffset>
              <bitWidth>16</bitWidth>
            </field>
          </fields>
        </register>
        <register>
          <name>CCR3</name>
          <addressOffset>0x3c</addressOffset>
          <size>0x20</size>
          <fields>
            <field>
              <name>CCR3</name>
              <bitOffset>0</bitOffset>
              <bitWidth>16</bitWidth>
            </field>
          </fields>
        </register>
        <register>
          <name>CCR4</name>
          <addressOffset>0x40</addressOffset>
          <size>0x20</size>
          <fields>
            <field>
              <name>CCR4</name>
              <bitOffset>0</bitOffset>
              <bitWidth>16</bitWidth>
            </field>
          </fields>
        </register>
        <register>
          <name>BDTR</name>
          <addressOffset>0x44</addressOffset>
          <size>0x20</size>
          <fields>
            <field>
              <name>DTG</name>
              <bitOffset>0</bitOffset>
              <bitWidth>8</bitWidth>
            </field>
            <field>
              <name>LOCK</name>
              <bitOffset>8</bitOffset>
              <bitWidth>2</bitWidth>
            </field>
            <field>
              <name>OSSI</name>
              <bitOffset>10</bitOffset>
              <bitWidth>1</bitWidth>
            </field>
            <field>
              <name>OSSR</name>
              <bitOffset>11</bitOffset>
              <bitWidth>1</bitWidth>
            </field>
            <field>
              <name>BKE</name>
              <bitOffset>12</bitOffset>
              <bitWidth>1</bitWidth>
            </field>
            <field>
              <name>BKP</name>
              <bitOffset>13</bitOffset>
              <bitWidth>1</bitWidth>
            </field>
            <field>
              <name>AOE</name>
              <bitOffset>14</bitOffset>
              <bitWidth>1</bitWidth>
            </field>
            <field>
              <name>MOE</name>
              <bitOffset>15</bitOffset>
              <bitWidth>1</bitWidth>
            </field>
            <field>
              <name>BKF</name>
              <bitOffset>16</bitOffset>
              <bitWidth>4</bitWidth>
            </field>
            <field>
              <name>BK2F</name>
              <bitOffset>20</bitOffset>
              <bitWidth>4</bitWidth>
            </field>
            <field>
              <name>BK2E</name>
              <bitOffset>24</bitOffset>
              <bitWidth>1</bitWidth>
            </field>
            <field>
              <name>BK2P</name>
              <bitOffset>25</bitOffset>
              <bitWidth>1</bitWidth>
            </field>
          </fields>
        </register>
        <register>
          <name>DCR</name>
          <addressOffset>0x48</addressOffset>
          <size>0x20</size>
          <fields>
            <field>
              <name>DBA</name>
              <bitOffset>0</bitOffset>
              <bitWidth>5</bitWidth>
            </field>
            <field>
              <name>DBL</name>
              <bitOffset>8</bitOffset>
              <bitWidth>5</bitWidth>
            </field>
          </fields>
        </register>
        <register>
          <name>DMAR</name>
          <addressOffset>0x4c</addressOffset>
          <size>0x20</size>
          <fields>
            <field>
              <name>DMAB</name>
              <bitOffset>0</bitOffset>
              <bitWidth>16</bitWidth>
            </field>
          </fields>
        </register>
        <register>
          <name>CCMR3</name>
          <addressOffset>0x54</addressOffset>
          <size>0x20</size>
          <fields>
            <field>
              <name>OC5FE</name>
              <bitOffset>2</bitOffset>
              <bitWidth>1</bitWidth>
            </field>
            <field>
              <name>OC5PE</name>
              <bitOffset>3</bitOffset>
              <bitWidth>1</bitWidth>
            </field>
            <field>
              <name>OC5M</name>
              <bitOffset>4</bitOffset>
              <bitWidth>13</bitWidth>
            </field>
            <field>
              <name>OC5CE</name>
              <bitOffset>7</bitOffset>
              <bitWidth>1</bitWidth>
            </field>
            <field>
              <name>OC6FE</name>
              <bitOffset>10</bitOffset>
              <bitWidth>1</bitWidth>
            </field>
            <field>
              <name>OC6PE</name>
              <bitOffset>11</bitOffset>
              <bitWidth>1</bitWidth>
            </field>
            <field>
              <name>OC6M</name>
              <bitOffset>12</bitOffset>
              <bitWidth>13</bitWidth>
            </field>
            <field>
              <name>OC6CE</name>
              <bitOffset>15</bitOffset>
              <bitWidth>1</bitWidth>
            </field>
          </fields>
        </register>
        <register>
          <name>CCR5</name>
          <addressOffset>0x58</addressOffset>
          <size>0x20</size>
          <fields>
            <field>
              <name>CCR5</name>
              <bitOffset>0</bitOffset>
              <bitWidth>32</bitWidth>
            </field>
            <field>
              <name>GC5C1</name>
              <bitOffset>29</bitOffset>
              <bitWidth>1</bitWidth>
            </field>
            <field>
              <name>GC5C2</name>
              <bitOffset>30</bitOffset>
              <bitWidth>1</bitWidth>
            </field>
            <field>
              <name>GC5C3</name>
              <bitOffset>31</bitOffset>
              <bitWidth>1</bitWidth>
            </field>
          </fields>
        </register>
        <register>
          <name>CCR6</name>
          <addressOffset>0x5c</addressOffset>
          <size>0x20</size>
          <fields>
            <field>
              <name>CCR6</name>
              <bitOffset>0</bitOffset>
              <bitWidth>16</bitWidth>
            </field>
          </fields>
        </register>
        <register>
          <name>AF1</name>
          <addressOffset>0x60</addressOffset>
          <size>0x20</size>
        </register>
        <register>
          <name>AF2</name>
          <addressOffset>0x64</addressOffset>
          <size>0x20</size>
        </register>
        <register>
          <name>TISEL</name>
          <addressOffset>0x68</addressOffset>
          <size>0x20</size>
          <fields>
            <field>
              <name>TI1SEL</name>
              <bitOffset>0</bitOffset>
              <bitWidth>4</bitWidth>
            </field>
            <field>
              <name>TI2SEL</name>
              <bitOffset>8</bitOffset>
              <bitWidth>4</bitWidth>
            </field>
            <field>
              <name>TI3SEL</name>
              <bitOffset>16</bitOffset>
              <bitWidth>4</bitWidth>
            </field>
            <field>
              <name>TI4SEL</name>
              <bitOffset>24</bitOffset>
              <bitWidth>4</bitWidth>
            </field>
          </fields>
        </register>
      </registers>
    </peripheral>
    <peripheral>
      <name>TIM17</name>
      <baseAddress>0x40014800</baseAddress>
      <registers>
        <register>
          <name>CR1</name>
          <addressOffset>0x0</addressOffset>
          <size>0x20</size>
          <fields>
            <field>
              <name>CEN</name>
              <bitOffset>0</bitOffset>
              <bitWidth>1</bitWidth>
            </field>
            <field>
              <name>UDIS</name>
              <bitOffset>1</bitOffset>
              <bitWidth>1</bitWidth>
            </field>
            <field>
              <name>URS</name>
              <bitOffset>2</bitOffset>
              <bitWidth>1</bitWidth>
            </field>
            <field>
              <name>OPM</name>
              <bitOffset>3</bitOffset>
              <bitWidth>1</bitWidth>
            </field>
            <field>
              <name>DIR</name>
              <bitOffset>4</bitOffset>
              <bitWidth>1</bitWidth>
            </field>
            <field>
              <name>CMS</name>
              <bitOffset>5</bitOffset>
              <bitWidth>2</bitWidth>
            </field>
            <field>
              <name>ARPE</name>
              <bitOffset>7</bitOffset>
              <bitWidth>1</bitWidth>
            </field>
            <field>
              <name>CKD</name>
              <bitOffset>8</bitOffset>
              <bitWidth>2</bitWidth>
            </field>
            <field>
              <name>UIFREMAP</name>
              <bitOffset>11</bitOffset>
              <bitWidth>1</bitWidth>
            </field>
          </fields>
        </register>
        <register>
          <name>CR2</name>
          <addressOffset>0x4</addressOffset>
          <size>0x20</size>
          <fields>
            <field>
              <name>CCPC</name>
              <bitOffset>0</bitOffset>
              <bitWidth>1</bitWidth>
            </field>
            <field>
              <name>CCUS</name>
              <bitOffset>2</bitOffset>
              <bitWidth>1</bitWidth>
            </field>
            <field>
              <name>CCDS</name>
              <bitOffset>3</bitOffset>
              <bitWidth>1</bitWidth>
            </field>
            <field>
              <name>MMS</name>
              <bitOffset>4</bitOffset>
              <bitWidth>3</bitWidth>
            </field>
            <field>
              <name>TI1S</name>
              <bitOffset>7</bitOffset>
              <bitWidth>1</bitWidth>
            </field>
            <field>
              <name>OIS1</name>
              <bitOffset>8</bitOffset>
              <bitWidth>1</bitWidth>
            </field>
            <field>
              <name>OIS1N</name>
              <bitOffset>9</bitOffset>
              <bitWidth>1</bitWidth>
            </field>
            <field>
              <name>OIS2</name>
              <bitOffset>10</bitOffset>
              <bitWidth>1</bitWidth>
            </field>
            <field>
              <name>OIS2N</name>
              <bitOffset>11</bitOffset>
              <bitWidth>1</bitWidth>
            </field>
            <field>
              <name>OIS3</name>
              <bitOffset>12</bitOffset>
              <bitWidth>1</bitWidth>
            </field>
            <field>
              <name>OIS3N</name>
              <bitOffset>13</bitOffset>
              <bitWidth>1</bitWidth>
            </field>
            <field>
              <name>OIS4</name>
              <bitOffset>14</bitOffset>
              <bitWidth>1</bitWidth>
            </field>
            <field>
              <name>OIS5</name>
              <bitOffset>16</bitOffset>
              <bitWidth>1</bitWidth>
            </field>
            <field>
              <name>OIS6</name>
              <bitOffset>18</bitOffset>
              <bitWidth>1</bitWidth>
            </field>
            <field>
              <name>MMS2</name>
              <bitOffset>20</bitOffset>
              <bitWidth>4</bitWidth>
            </field>
          </fields>
        </register>
        <register>
          <name>SMCR</name>
          <addressOffset>0x8</addressOffset>
          <size>0x20</size>
          <fields>
            <field>
              <name>SMS</name>
              <bitOffset>0</bitOffset>
              <bitWidth>17</bitWidth>
            </field>
            <field>
              <name>TS</name>
              <bitOffset>4</bitOffset>
              <bitWidth>18</bitWidth>
            </field>
            <field>
              <name>MSM</name>
              <bitOffset>7</bitOffset>
              <bitWidth>1</bitWidth>
            </field>
            <field>
              <name>ETF</name>
              <bitOffset>8</bitOffset>
              <bitWidth>4</bitWidth>
            </field>
            <field>
              <name>ETPS</name>
              <bitOffset>12</bitOffset>
              <bitWidth>2</bitWidth>
            </field>
            <field>
              <name>ECE</name>
              <bitOffset>14</bitOffset>
              <bitWidth>1</bitWidth>
            </field>
            <field>
              <name>ETP</name>
              <bitOffset>15</bitOffset>
              <bitWidth>1</bitWidth>
            </field>
          </fields>
        </register>
        <register>
          <name>DIER</name>
          <addressOffset>0xc</addressOffset>
          <size>0x20</size>
          <fields>
            <field>
              <name>UIE</name>
              <bitOffset>0</bitOffset>
              <bitWidth>1</bitWidth>
            </field>
            <field>
              <name>CC1IE</name>
              <bitOffset>1</bitOffset>
              <bitWidth>1</bitWidth>
            </field>
            <field>
              <name>CC2IE</name>
              <bitOffset>2</bitOffset>
              <bitWidth>1</bitWidth>
            </field>
            <field>
              <name>CC3IE</name>
              <bitOffset>3</bitOffset>
              <bitWidth>1</bitWidth>
            </field>
            <field>
              <name>CC4IE</name>
              <bitOffset>4</bitOffset>
              <bitWidth>1</bitWidth>
            </field>
            <field>
              <name>COMIE</name>
              <bitOffset>5</bitOffset>
              <bitWidth>1</bitWidth>
            </field>
            <field>
              <name>TIE</name>
              <bitOffset>6</bitOffset>
              <bitWidth>1</bitWidth>
            </field>
            <field>
              <name>BIE</name>
              <bitOffset>7</bitOffset>
              <bitWidth>1</bitWidth>
            </field>
            <field>
              <name>UDE</name>
              <bitOffset>8</bitOffset>
              <bitWidth>1</bitWidth>
            </field>
            <field>
              <name>CC1DE</name>
              <bitOffset>9</bitOffset>
              <bitWidth>1</bitWidth>
            </field>
            <field>
              <name>CC2DE</name>
              <bitOffset>10</bitOffset>
              <bitWidth>1</bitWidth>
            </field>
            <field>
              <name>CC3DE</name>
              <bitOffset>11</bitOffset>
              <bitWidth>1</bitWidth>
            </field>
            <field>
              <name>CC4DE</name>
              <bitOffset>12</bitOffset>
              <bitWidth>1</bitWidth>
            </field>
            <field>
              <name>COMDE</name>
              <bitOffset>13</bitOffset>
              <bitWidth>1</bitWidth>
            </field>
            <field>
              <name>TDE</name>
              <bitOffset>14</bitOffset>
              <bitWidth>1</bitWidth>
            </field>
          </fields>
        </register>
        <register>
          <name>SR</name>
          <addressOffset>0x10</addressOffset>
          <size>0x20</size>
          <fields>
            <field>
              <name>UIF</name>
              <bitOffset>0</bitOffset>
              <bitWidth>1</bitWidth>
            </field>
            <field>
              <name>CC1IF</name>
              <bitOffset>1</bitOffset>
              <bitWidth>1</bitWidth>
            </field>
            <field>
              <name>CC2IF</name>
              <bitOffset>2</bitOffset>
              <bitWidth>1</bitWidth>
            </field>
            <field>
              <name>CC3IF</name>
              <bitOffset>3</bitOffset>
              <bitWidth>1</bitWidth>
            </field>
            <field>
              <name>CC4IF</name>
              <bitOffset>4</bitOffset>
              <bitWidth>1</bitWidth>
            </field>
            <field>
              <name>COMIF</name>
              <bitOffset>5</bitOffset>
              <bitWidth>1</bitWidth>
            </field>
            <field>
              <name>TIF</name>
              <bitOffset>6</bitOffset>
              <bitWidth>1</bitWidth>
            </field>
            <field>
              <name>BIF</name>
              <bitOffset>7</bitOffset>
              <bitWidth>1</bitWidth>
            </field>
            <field>
              <name>B2IF</name>
              <bitOffset>8</bitOffset>
              <bitWidth>1</bitWidth>
            </field>
            <field>
              <name>CC1OF</name>
              <bitOffset>9</bitOffset>
              <bitWidth>1</bitWidth>
            </field>
            <field>
              <name>CC2OF</name>
              <bitOffset>10</bitOffset>
              <bitWidth>1</bitWidth>
            </field>
            <field>
              <name>CC3OF</name>
              <bitOffset>11</bitOffset>
              <bitWidth>1</bitWidth>
            </field>
            <field>
              <name>CC4OF</name>
              <bitOffset>12</bitOffset>
              <bitWidth>1</bitWidth>
            </field>
            <field>
              <name>SBIF</name>
              <bitOffset>13</bitOffset>
              <bitWidth>1</bitWidth>
            </field>
            <field>
              <name>CC5IF</name>
              <bitOffset>16</bitOffset>
              <bitWidth>1</bitWidth>
            </field>
            <field>
              <name>CC6IF</name>
              <bitOffset>17</bitOffset>
              <bitWidth>1</bitWidth>
            </field>
          </fields>
        </register>
        <register>
          <name>EGR</name>
          <addressOffset>0x14</addressOffset>
          <size>0x20</size>
          <fields>
            <field>
              <name>UG</name>
              <bitOffset>0</bitOffset>
              <bitWidth>1</bitWidth>
            </field>
            <field>
              <name>CC1G</name>
              <bitOffset>1</bitOffset>
              <bitWidth>1</bitWidth>
            </field>
            <field>
              <name>CC2G</name>
              <bitOffset>2</bitOffset>
              <bitWidth>1</bitWidth>
            </field>
            <field>
              <name>CC3G</name>
              <bitOffset>3</bitOffset>
              <bitWidth>1</bitWidth>
            </field>
            <field>
              <name>CC4G</name>
              <bitOffset>4</bitOffset>
              <bitWidth>1</bitWidth>
            </field>
            <field>
              <name>COMG</name>
              <bitOffset>5</bitOffset>
              <bitWidth>1</bitWidth>
            </field>
            <field>
              <name>TG</name>
              <bitOffset>6</bitOffset>
              <bitWidth>1</bitWidth>
            </field>
            <field>
              <name>BG</name>
              <bitOffset>7</bitOffset>
              <bitWidth>1</bitWidth>
            </field>
            <field>
              <name>B2G</name>
              <bitOffset>8</bitOffset>
              <bitWidth>1</bitWidth>
            </field>
          </fields>
        </register>
        <register>
          <name>CCMR1</name>
          <addressOffset>0x18</addressOffset>
          <size>0x20</size>
          <fields>
            <field>
              <name>CC1S</name>
              <bitOffset>0</bitOffset>
              <bitWidth>2</bitWidth>
            </field>
            <field>
              <name>OC1FE</name>
              <bitOffset>2</bitOffset>
              <bitWidth>1</bitWidth>
            </field>
            <field>
              <name>OC1PE</name>
              <bitOffset>3</bitOffset>
              <bitWidth>1</bitWidth>
            </field>
            <field>
              <name>OC1M</name>
              <bitOffset>4</bitOffset>
              <bitWidth>13</bitWidth>
            </field>
            <field>
              <name>OC1CE</name>
              <bitOffset>7</bitOffset>
              <bitWidth>1</bitWidth>
            </field>
            <field>
              <name>CC2S</name>
              <bitOffset>8</bitOffset>
              <bitWidth>2</bitWidth>
            </field>
            <field>
              <name>OC2FE</name>
              <bitOffset>10</bitOffset>
              <bitWidth>1</bitWidth>
            </field>
            <field>
              <name>OC2PE</name>
              <bitOffset>11</bitOffset>
              <bitWidth>1</bitWidth>
            </field>
            <field>
              <name>OC2M</name>
              <bitOffset>12</bitOffset>
              <bitWidth>13</bitWidth>
            </field>
            <field>
              <name>OC2CE</name>
              <bitOffset>15</bitOffset>
              <bitWidth>1</bitWidth>
            </field>
          </fields>
        </register>
        <register>
          <name>CCMR2</name>
          <addressOffset>0x1c</addressOffset>
          <size>0x20</size>
          <fields>
            <field>
              <name>CC3S</name>
              <bitOffset>0</bitOffset>
              <bitWidth>2</bitWidth>
            </field>
            <field>
              <name>OC3FE</name>
              <bitOffset>2</bitOffset>
              <bitWidth>1</bitWidth>
            </field>
            <field>
              <name>OC3PE</name>
              <bitOffset>3</bitOffset>
              <bitWidth>1</bitWidth>
            </field>
            <field>
              <name>OC3M</name>
              <bitOffset>4</bitOffset>
              <bitWidth>13</bitWidth>
            </field>
            <field>
              <name>OC3CE</name>
              <bitOffset>7</bitOffset>
              <bitWidth>1</bitWidth>
            </field>
            <field>
              <name>CC4S</name>
              <bitOffset>8</bitOffset>
              <bitWidth>2</bitWidth>
            </field>
            <field>
              <name>OC4FE</name>
              <bitOffset>10</bitOffset>
              <bitWidth>1</bitWidth>
            </field>
            <field>
              <name>OC4PE</name>
              <bitOffset>11</bitOffset>
              <bitWidth>1</bitWidth>
            </field>
            <field>
              <name>OC4M</name>
              <bitOffset>12</bitOffset>
              <bitWidth>13</bitWidth>
            </field>
            <field>
              <name>OC4CE</name>
              <bitOffset>15</bitOffset>
              <bitWidth>1</bitWidth>
            </field>
          </fields>
        </register>
        <register>
          <name>CCER</name>
          <addressOffset>0x20</addressOffset>
          <size>0x20</size>
          <fields>
            <field>
              <name>CC1E</name>
              <bitOffset>0</bitOffset>
              <bitWidth>1</bitWidth>
            </field>
            <field>
              <name>CC1P</name>
              <bitOffset>1</bitOffset>
              <bitWidth>1</bitWidth>
            </field>
            <field>
              <name>CC1NE</name>
              <bitOffset>2</bitOffset>
              <bitWidth>1</bitWidth>
            </field>
            <field>
              <name>CC1NP</name>
              <bitOffset>3</bitOffset>
              <bitWidth>1</bitWidth>
            </field>
            <field>
              <name>CC2E</name>
              <bitOffset>4</bitOffset>
              <bitWidth>1</bitWidth>
            </field>
            <field>
              <name>CC2P</name>
              <bitOffset>5</bitOffset>
              <bitWidth>1</bitWidth>
            </field>
            <field>
              <name>CC2NE</name>
              <bitOffset>6</bitOffset>
              <bitWidth>1</bitWidth>
            </field>
            <field>
              <name>CC2NP</name>
              <bitOffset>7</bitOffset>
              <bitWidth>1</bitWidth>
            </field>
            <field>
              <name>CC3E</name>
              <bitOffset>8</bitOffset>
              <bitWidth>1</bitWidth>
            </field>
            <field>
              <name>CC3P</name>
              <bitOffset>9</bitOffset>
              <bitWidth>1</bitWidth>
            </field>
            <field>
              <name>CC3NE</name>
              <bitOffset>10</bitOffset>
              <bitWidth>1</bitWidth>
            </field>
            <field>
              <name>CC3NP</name>
              <bitOffset>11</bitOffset>
              <bitWidth>1</bitWidth>
            </field>
            <field>
              <name>CC4E</name>
              <bitOffset>12</bitOffset>
              <bitWidth>1</bitWidth>
            </field>
            <field>
              <name>CC4P</name>
              <bitOffset>13</bitOffset>
              <bitWidth>1</bitWidth>
            </field>
            <field>
              <name>CC4NP</name>
              <bitOffset>15</bitOffset>
              <bitWidth>1</bitWidth>
            </field>
            <field>
              <name>CC5E</name>
              <bitOffset>16</bitOffset>
              <bitWidth>1</bitWidth>
            </field>
            <field>
              <name>CC5P</name>
              <bitOffset>17</bitOffset>
              <bitWidth>1</bitWidth>
            </field>
            <field>
              <name>CC6E</name>
              <bitOffset>20</bitOffset>
              <bitWidth>1</bitWidth>
            </field>
            <field>
              <name>CC6P</name>
              <bitOffset>21</bitOffset>
              <bitWidth>1</bitWidth>
            </field>
          </fields>
        </register>
        <register>
          <name>CNT</name>
          <addressOffset>0x24</addressOffset>
          <size>0x20</size>
          <fields>
            <field>
              <name>CNT</name>
              <bitOffset>0</bitOffset>
              <bitWidth>32</bitWidth>
            </field>
            <field>
              <name>UIFCPY</name>
              <bitOffset>31</bitOffset>
              <bitWidth>1</bitWidth>
            </field>
          </fields>
        </register>
        <register>
          <name>PSC</name>
          <addressOffset>0x28</addressOffset>
          <size>0x20</size>
          <fields>
            <field>
              <name>PSC</name>
              <bitOffset>0</bitOffset>
              <bitWidth>16</bitWidth>
            </field>
          </fields>
        </register>
        <register>
          <name>ARR</name>
          <addressOffset>0x2c</addressOffset>
          <size>0x20</size>
          <fields>
            <field>
              <name>ARR</name>
              <bitOffset>0</bitOffset>
              <bitWidth>32</bitWidth>
            </field>
          </fields>
        </register>
        <register>
          <name>RCR</name>
          <addressOffset>0x30</addressOffset>
          <size>0x20</size>
          <fields>
            <field>
              <name>REP</name>
              <bitOffset>0</bitOffset>
              <bitWidth>8</bitWidth>
            </field>
          </fields>
        </register>
        <register>
          <name>CCR1</name>
          <addressOffset>0x34</addressOffset>
          <size>0x20</size>
          <fields>
            <field>
              <name>CCR1</name>
              <bitOffset>0</bitOffset>
              <bitWidth>16</bitWidth>
            </field>
          </fields>
        </register>
        <register>
          <name>CCR2</name>
          <addressOffset>0x38</addressOffset>
          <size>0x20</size>
          <fields>
            <field>
              <name>CCR2</name>
              <bitOffset>0</bitOffset>
              <bitWidth>16</bitWidth>
            </field>
          </fields>
        </register>
        <register>
          <name>CCR3</name>
          <addressOffset>0x3c</addressOffset>
          <size>0x20</size>
          <fields>
            <field>
              <name>CCR3</name>
              <bitOffset>0</bitOffset>
              <bitWidth>16</bitWidth>
            </field>
          </fields>
        </register>
        <register>
          <name>CCR4</name>
          <addressOffset>0x40</addressOffset>
          <size>0x20</size>
          <fields>
            <field>
              <name>CCR4</name>
              <bitOffset>0</bitOffset>
              <bitWidth>16</bitWidth>
            </field>
          </fields>
        </register>
        <register>
          <name>BDTR</name>
          <addressOffset>0x44</addressOffset>
          <size>0x20</size>
          <fields>
            <field>
              <name>DTG</name>
              <bitOffset>0</bitOffset>
              <bitWidth>8</bitWidth>
            </field>
            <field>
              <name>LOCK</name>
              <bitOffset>8</bitOffset>
              <bitWidth>2</bitWidth>
            </field>
            <field>
              <name>OSSI</name>
              <bitOffset>10</bitOffset>
              <bitWidth>1</bitWidth>
            </field>
            <field>
              <name>OSSR</name>
              <bitOffset>11</bitOffset>
              <bitWidth>1</bitWidth>
            </field>
            <field>
              <name>BKE</name>
              <bitOffset>12</bitOffset>
              <bitWidth>1</bitWidth>
            </field>
            <field>
              <name>BKP</name>
              <bitOffset>13</bitOffset>
              <bitWidth>1</bitWidth>
            </field>
            <field>
              <name>AOE</name>
              <bitOffset>14</bitOffset>
              <bitWidth>1</bitWidth>
            </field>
            <field>
              <name>MOE</name>
              <bitOffset>15</bitOffset>
              <bitWidth>1</bitWidth>
            </field>
            <field>
              <name>BKF</name>
              <bitOffset>16</bitOffset>
              <bitWidth>4</bitWidth>
            </field>
            <field>
              <name>BK2F</name>
              <bitOffset>20</bitOffset>
              <bitWidth>4</bitWidth>
            </field>
            <field>
              <name>BK2E</name>
              <bitOffset>24</bitOffset>
              <bitWidth>1</bitWidth>
            </field>
            <field>
              <name>BK2P</name>
              <bitOffset>25</bitOffset>
              <bitWidth>1</bitWidth>
            </field>
          </fields>
        </register>
        <register>
          <name>DCR</name>
          <addressOffset>0x48</addressOffset>
          <size>0x20</size>
          <fields>
            <field>
              <name>DBA</name>
              <bitOffset>0</bitOffset>
              <bitWidth>5</bitWidth>
            </field>
            <field>
              <name>DBL</name>
              <bitOffset>8</bitOffset>
              <bitWidth>5</bitWidth>
            </field>
          </fields>
        </register>
        <register>
          <name>DMAR</name>
          <addressOffset>0x4c</addressOffset>
          <size>0x20</size>
          <fields>
            <field>
              <name>DMAB</name>
              <bitOffset>0</bitOffset>
              <bitWidth>16</bitWidth>
            </field>
          </fields>
        </register>
        <register>
          <name>CCMR3</name>
          <addressOffset>0x54</addressOffset>
          <size>0x20</size>
          <fields>
            <field>
              <name>OC5FE</name>
              <bitOffset>2</bitOffset>
              <bitWidth>1</bitWidth>
            </field>
            <field>
              <name>OC5PE</name>
              <bitOffset>3</bitOffset>
              <bitWidth>1</bitWidth>
            </field>
            <field>
              <name>OC5M</name>
              <bitOffset>4</bitOffset>
              <bitWidth>13</bitWidth>
            </field>
            <field>
              <name>OC5CE</name>
              <bitOffset>7</bitOffset>
              <bitWidth>1</bitWidth>
            </field>
            <field>
              <name>OC6FE</name>
              <bitOffset>10</bitOffset>
              <bitWidth>1</bitWidth>
            </field>
            <field>
              <name>OC6PE</name>
              <bitOffset>11</bitOffset>
              <bitWidth>1</bitWidth>
            </field>
            <field>
              <name>OC6M</name>
              <bitOffset>12</bitOffset>
              <bitWidth>13</bitWidth>
            </field>
            <field>
              <name>OC6CE</name>
              <bitOffset>15</bitOffset>
              <bitWidth>1</bitWidth>
            </field>
          </fields>
        </register>
        <register>
          <name>CCR5</name>
          <addressOffset>0x58</addressOffset>
          <size>0x20</size>
          <fields>
            <field>
              <name>CCR5</name>
              <bitOffset>0</bitOffset>
              <bitWidth>32</bitWidth>
            </field>
            <field>
              <name>GC5C1</name>
              <bitOffset>29</bitOffset>
              <bitWidth>1</bitWidth>
            </field>
            <field>
              <name>GC5C2</name>
              <bitOffset>30</bitOffset>
              <bitWidth>1</bitWidth>
            </field>
            <field>
              <name>GC5C3</name>
              <bitOffset>31</bitOffset>
              <bitWidth>1</bitWidth>
            </field>
          </fields>
        </register>
        <register>
          <name>CCR6</name>
          <addressOffset>0x5c</addressOffset>
          <size>0x20</size>
          <fields>
            <field>
              <name>CCR6</name>
              <bitOffset>0</bitOffset>
              <bitWidth>16</bitWidth>
            </field>
          </fields>
        </register>
        <register>
          <name>AF1</name>
          <addressOffset>0x60</addressOffset>
          <size>0x20</size>
        </register>
        <register>
          <name>AF2</name>
          <addressOffset>0x64</addressOffset>
          <size>0x20</size>
        </register>
        <register>
          <name>TISEL</name>
          <addressOffset>0x68</addressOffset>
          <size>0x20</size>
          <fields>
            <field>
              <name>TI1SEL</name>
              <bitOffset>0</bitOffset>
              <bitWidth>4</bitWidth>
            </field>
            <field>
              <name>TI2SEL</name>
              <bitOffset>8</bitOffset>
              <bitWidth>4</bitWidth>
            </field>
            <field>
              <name>TI3SEL</name>
              <bitOffset>16</bitOffset>
              <bitWidth>4</bitWidth>
            </field>
            <field>
              <name>TI4SEL</name>
              <bitOffset>24</bitOffset>
              <bitWidth>4</bitWidth>
            </field>
          </fields>
        </register>
      </registers>
    </peripheral>
    <peripheral>
      <name>SPI5</name>
      <baseAddress>0x40015000</baseAddress>
      <registers>
        <register>
          <name>CR1</name>
          <addressOffset>0x0</addressOffset>
          <size>0x20</size>
          <fields>
            <field>
              <name>SPE</name>
              <bitOffset>0</bitOffset>
              <bitWidth>1</bitWidth>
            </field>
            <field>
              <name>MASRX</name>
              <bitOffset>8</bitOffset>
              <bitWidth>1</bitWidth>
            </field>
            <field>
              <name>CSTART</name>
              <bitOffset>9</bitOffset>
              <bitWidth>1</bitWidth>
            </field>
            <field>
              <name>CSUSP</name>
              <bitOffset>10</bitOffset>
              <bitWidth>1</bitWidth>
            </field>
            <field>
              <name>HDDIR</name>
              <bitOffset>11</bitOffset>
              <bitWidth>1</bitWidth>
            </field>
            <field>
              <name>SSI</name>
              <bitOffset>12</bitOffset>
              <bitWidth>1</bitWidth>
            </field>
            <field>
              <name>CRC33_17</name>
              <bitOffset>13</bitOffset>
              <bitWidth>1</bitWidth>
            </field>
            <field>
              <name>RCRCINI</name>
              <bitOffset>14</bitOffset>
              <bitWidth>1</bitWidth>
            </field>
            <field>
              <name>TCRCINI</name>
              <bitOffset>15</bitOffset>
              <bitWidth>1</bitWidth>
            </field>
            <field>
              <name>IOLOCK</name>
              <bitOffset>16</bitOffset>
              <bitWidth>1</bitWidth>
            </field>
          </fields>
        </register>
        <register>
          <name>CR2</name>
          <addressOffset>0x4</addressOffset>
          <size>0x20</size>
          <fields>
            <field>
              <name>TSIZE</name>
              <bitOffset>0</bitOffset>
              <bitWidth>16</bitWidth>
            </field>
            <field>
              <name>TSER</name>
              <bitOffset>16</bitOffset>
              <bitWidth>16</bitWidth>
            </field>
          </fields>
        </register>
        <register>
          <name>CFG1</name>
          <addressOffset>0x8</addressOffset>
          <size>0x20</size>
          <fields>
            <field>
              <name>DSIZE</name>
              <bitOffset>0</bitOffset>
              <bitWidth>5</bitWidth>
            </field>
            <field>
              <name>FTHLV</name>
              <bitOffset>5</bitOffset>
              <bitWidth>4</bitWidth>
            </field>
            <field>
              <name>UDRCFG</name>
              <bitOffset>9</bitOffset>
              <bitWidth>2</bitWidth>
            </field>
            <field>
              <name>UDRDET</name>
              <bitOffset>11</bitOffset>
              <bitWidth>2</bitWidth>
            </field>
            <field>
              <name>RXDMAEN</name>
              <bitOffset>14</bitOffset>
              <bitWidth>1</bitWidth>
            </field>
            <field>
              <name>TXDMAEN</name>
              <bitOffset>15</bitOffset>
              <bitWidth>1</bitWidth>
            </field>
            <field>
              <name>CRCSIZE</name>
              <bitOffset>16</bitOffset>
              <bitWidth>5</bitWidth>
            </field>
            <field>
              <name>CRCEN</name>
              <bitOffset>22</bitOffset>
              <bitWidth>1</bitWidth>
            </field>
            <field>
              <name>MBR</name>
              <bitOffset>28</bitOffset>
              <bitWidth>3</bitWidth>
            </field>
          </fields>
        </register>
        <register>
          <name>CFG2</name>
          <addressOffset>0xc</addressOffset>
          <size>0x20</size>
          <fields>
            <field>
              <name>MSSI</name>
              <bitOffset>0</bitOffset>
              <bitWidth>4</bitWidth>
            </field>
            <field>
              <name>MIDI</name>
              <bitOffset>4</bitOffset>
              <bitWidth>4</bitWidth>
            </field>
            <field>
              <name>IOSWP</name>
              <bitOffset>15</bitOffset>
              <bitWidth>1</bitWidth>
            </field>
            <field>
              <name>COMM</name>
              <bitOffset>17</bitOffset>
              <bitWidth>2</bitWidth>
            </field>
            <field>
              <name>SP</name>
              <bitOffset>19</bitOffset>
              <bitWidth>3</bitWidth>
            </field>
            <field>
              <name>MASTER</name>
              <bitOffset>22</bitOffset>
              <bitWidth>1</bitWidth>
            </field>
            <field>
              <name>LSBFRST</name>
              <bitOffset>23</bitOffset>
              <bitWidth>1</bitWidth>
            </field>
            <field>
              <name>CPHA</name>
              <bitOffset>24</bitOffset>
              <bitWidth>1</bitWidth>
            </field>
            <field>
              <name>CPOL</name>
              <bitOffset>25</bitOffset>
              <bitWidth>1</bitWidth>
            </field>
            <field>
              <name>SSM</name>
              <bitOffset>26</bitOffset>
              <bitWidth>1</bitWidth>
            </field>
            <field>
              <name>SSIOP</name>
              <bitOffset>28</bitOffset>
              <bitWidth>1</bitWidth>
            </field>
            <field>
              <name>SSOE</name>
              <bitOffset>29</bitOffset>
              <bitWidth>1</bitWidth>
            </field>
            <field>
              <name>SSOM</name>
              <bitOffset>30</bitOffset>
              <bitWidth>1</bitWidth>
            </field>
            <field>
              <name>AFCNTR</name>
              <bitOffset>31</bitOffset>
              <bitWidth>1</bitWidth>
            </field>
          </fields>
        </register>
        <register>
          <name>IER</name>
          <addressOffset>0x10</addressOffset>
          <size>0x20</size>
          <fields>
            <field>
              <name>RXPIE</name>
              <bitOffset>0</bitOffset>
              <bitWidth>1</bitWidth>
            </field>
            <field>
              <name>TXPIE</name>
              <bitOffset>1</bitOffset>
              <bitWidth>1</bitWidth>
            </field>
            <field>
              <name>DXPIE</name>
              <bitOffset>2</bitOffset>
              <bitWidth>1</bitWidth>
            </field>
            <field>
              <name>EOTIE</name>
              <bitOffset>3</bitOffset>
              <bitWidth>1</bitWidth>
            </field>
            <field>
              <name>TXTFIE</name>
              <bitOffset>4</bitOffset>
              <bitWidth>1</bitWidth>
            </field>
            <field>
              <name>UDRIE</name>
              <bitOffset>5</bitOffset>
              <bitWidth>1</bitWidth>
            </field>
            <field>
              <name>OVRIE</name>
              <bitOffset>6</bitOffset>
              <bitWidth>1</bitWidth>
            </field>
            <field>
              <name>CRCEIE</name>
              <bitOffset>7</bitOffset>
              <bitWidth>1</bitWidth>
            </field>
            <field>
              <name>TIFREIE</name>
              <bitOffset>8</bitOffset>
              <bitWidth>1</bitWidth>
            </field>
            <field>
              <name>MODFIE</name>
              <bitOffset>9</bitOffset>
              <bitWidth>1</bitWidth>
            </field>
            <field>
              <name>TSERFIE</name>
              <bitOffset>10</bitOffset>
              <bitWidth>1</bitWidth>
            </field>
          </fields>
        </register>
        <register>
          <name>SR</name>
          <addressOffset>0x14</addressOffset>
          <size>0x20</size>
          <fields>
            <field>
              <name>RXP</name>
              <bitOffset>0</bitOffset>
              <bitWidth>1</bitWidth>
            </field>
            <field>
              <name>TXP</name>
              <bitOffset>1</bitOffset>
              <bitWidth>1</bitWidth>
            </field>
            <field>
              <name>DXP</name>
              <bitOffset>2</bitOffset>
              <bitWidth>1</bitWidth>
            </field>
            <field>
              <name>EOT</name>
              <bitOffset>3</bitOffset>
              <bitWidth>1</bitWidth>
            </field>
            <field>
              <name>TXTF</name>
              <bitOffset>4</bitOffset>
              <bitWidth>1</bitWidth>
            </field>
            <field>
              <name>UDR</name>
              <bitOffset>5</bitOffset>
              <bitWidth>1</bitWidth>
            </field>
            <field>
              <name>OVR</name>
              <bitOffset>6</bitOffset>
              <bitWidth>1</bitWidth>
            </field>
            <field>
              <name>CRCE</name>
              <bitOffset>7</bitOffset>
              <bitWidth>1</bitWidth>
            </field>
            <field>
              <name>TIFRE</name>
              <bitOffset>8</bitOffset>
              <bitWidth>1</bitWidth>
            </field>
            <field>
              <name>MODF</name>
              <bitOffset>9</bitOffset>
              <bitWidth>1</bitWidth>
            </field>
            <field>
              <name>TSERF</name>
              <bitOffset>10</bitOffset>
              <bitWidth>1</bitWidth>
            </field>
            <field>
              <name>SUSP</name>
              <bitOffset>11</bitOffset>
              <bitWidth>1</bitWidth>
            </field>
            <field>
              <name>TXC</name>
              <bitOffset>12</bitOffset>
              <bitWidth>1</bitWidth>
            </field>
            <field>
              <name>RXPLVL</name>
              <bitOffset>13</bitOffset>
              <bitWidth>2</bitWidth>
            </field>
            <field>
              <name>RXWNE</name>
              <bitOffset>15</bitOffset>
              <bitWidth>1</bitWidth>
            </field>
            <field>
              <name>CTSIZE</name>
              <bitOffset>16</bitOffset>
              <bitWidth>16</bitWidth>
            </field>
          </fields>
        </register>
        <register>
          <name>IFCR</name>
          <addressOffset>0x18</addressOffset>
          <size>0x20</size>
          <fields>
            <field>
              <name>EOTC</name>
              <bitOffset>3</bitOffset>
              <bitWidth>1</bitWidth>
            </field>
            <field>
              <name>TXTFC</name>
              <bitOffset>4</bitOffset>
              <bitWidth>1</bitWidth>
            </field>
            <field>
              <name>UDRC</name>
              <bitOffset>5</bitOffset>
              <bitWidth>1</bitWidth>
            </field>
            <field>
              <name>OVRC</name>
              <bitOffset>6</bitOffset>
              <bitWidth>1</bitWidth>
            </field>
            <field>
              <name>CRCEC</name>
              <bitOffset>7</bitOffset>
              <bitWidth>1</bitWidth>
            </field>
            <field>
              <name>TIFREC</name>
              <bitOffset>8</bitOffset>
              <bitWidth>1</bitWidth>
            </field>
            <field>
              <name>MODFC</name>
              <bitOffset>9</bitOffset>
              <bitWidth>1</bitWidth>
            </field>
            <field>
              <name>TSERFC</name>
              <bitOffset>10</bitOffset>
              <bitWidth>1</bitWidth>
            </field>
            <field>
              <name>SUSPC</name>
              <bitOffset>11</bitOffset>
              <bitWidth>1</bitWidth>
            </field>
          </fields>
        </register>
        <register>
          <name>TXDR</name>
          <addressOffset>0x20</addressOffset>
          <size>0x20</size>
          <fields>
            <field>
              <name>TXDR</name>
              <bitOffset>0</bitOffset>
              <bitWidth>32</bitWidth>
            </field>
          </fields>
        </register>
        <register>
          <name>RXDR</name>
          <addressOffset>0x30</addressOffset>
          <size>0x20</size>
          <fields>
            <field>
              <name>RXDR</name>
              <bitOffset>0</bitOffset>
              <bitWidth>32</bitWidth>
            </field>
          </fields>
        </register>
        <register>
          <name>CRCPOLY</name>
          <addressOffset>0x40</addressOffset>
          <size>0x20</size>
          <fields>
            <field>
              <name>CRCPOLY</name>
              <bitOffset>0</bitOffset>
              <bitWidth>32</bitWidth>
            </field>
          </fields>
        </register>
        <register>
          <name>TXCRC</name>
          <addressOffset>0x44</addressOffset>
          <size>0x20</size>
          <fields>
            <field>
              <name>TXCRC</name>
              <bitOffset>0</bitOffset>
              <bitWidth>32</bitWidth>
            </field>
          </fields>
        </register>
        <register>
          <name>RXCRC</name>
          <addressOffset>0x48</addressOffset>
          <size>0x20</size>
          <fields>
            <field>
              <name>RXCRC</name>
              <bitOffset>0</bitOffset>
              <bitWidth>32</bitWidth>
            </field>
          </fields>
        </register>
        <register>
          <name>UDRDR</name>
          <addressOffset>0x4c</addressOffset>
          <size>0x20</size>
          <fields>
            <field>
              <name>UDRDR</name>
              <bitOffset>0</bitOffset>
              <bitWidth>32</bitWidth>
            </field>
          </fields>
        </register>
        <register>
          <name>I2SCFGR</name>
          <addressOffset>0x50</addressOffset>
          <size>0x20</size>
          <fields>
            <field>
              <name>I2SMOD</name>
              <bitOffset>0</bitOffset>
              <bitWidth>1</bitWidth>
            </field>
            <field>
              <name>I2SCFG</name>
              <bitOffset>1</bitOffset>
              <bitWidth>3</bitWidth>
            </field>
            <field>
              <name>I2SSTD</name>
              <bitOffset>4</bitOffset>
              <bitWidth>2</bitWidth>
            </field>
            <field>
              <name>PCMSYNC</name>
              <bitOffset>7</bitOffset>
              <bitWidth>1</bitWidth>
            </field>
            <field>
              <name>DATLEN</name>
              <bitOffset>8</bitOffset>
              <bitWidth>2</bitWidth>
            </field>
            <field>
              <name>CHLEN</name>
              <bitOffset>10</bitOffset>
              <bitWidth>1</bitWidth>
            </field>
            <field>
              <name>CKPOL</name>
              <bitOffset>11</bitOffset>
              <bitWidth>1</bitWidth>
            </field>
            <field>
              <name>FIXCH</name>
              <bitOffset>12</bitOffset>
              <bitWidth>1</bitWidth>
            </field>
            <field>
              <name>WSINV</name>
              <bitOffset>13</bitOffset>
              <bitWidth>1</bitWidth>
            </field>
            <field>
              <name>DATFMT</name>
              <bitOffset>14</bitOffset>
              <bitWidth>1</bitWidth>
            </field>
            <field>
              <name>I2SDIV</name>
              <bitOffset>16</bitOffset>
              <bitWidth>8</bitWidth>
            </field>
            <field>
              <name>ODD</name>
              <bitOffset>24</bitOffset>
              <bitWidth>1</bitWidth>
            </field>
            <field>
              <name>MCKOE</name>
              <bitOffset>25</bitOffset>
              <bitWidth>1</bitWidth>
            </field>
          </fields>
        </register>
      </registers>
    </peripheral>
    <peripheral>
      <name>SAI1</name>
      <baseAddress>0x40015800</baseAddress>
      <registers>
        <register>
          <name>GCR</name>
          <addressOffset>0x0</addressOffset>
          <size>0x20</size>
          <fields>
            <field>
              <name>SYNCIN</name>
              <bitOffset>0</bitOffset>
              <bitWidth>2</bitWidth>
            </field>
            <field>
              <name>SYNCOUT</name>
              <bitOffset>4</bitOffset>
              <bitWidth>2</bitWidth>
            </field>
          </fields>
        </register>
        <register>
          <name>CR1A</name>
          <addressOffset>0x4</addressOffset>
          <size>0x20</size>
          <fields>
            <field>
              <name>MODE</name>
              <bitOffset>0</bitOffset>
              <bitWidth>2</bitWidth>
            </field>
            <field>
              <name>PRTCFG</name>
              <bitOffset>2</bitOffset>
              <bitWidth>2</bitWidth>
            </field>
            <field>
              <name>DS</name>
              <bitOffset>5</bitOffset>
              <bitWidth>3</bitWidth>
            </field>
            <field>
              <name>LSBFIRST</name>
              <bitOffset>8</bitOffset>
              <bitWidth>1</bitWidth>
            </field>
            <field>
              <name>CKSTR</name>
              <bitOffset>9</bitOffset>
              <bitWidth>1</bitWidth>
            </field>
            <field>
              <name>SYNCEN</name>
              <bitOffset>10</bitOffset>
              <bitWidth>2</bitWidth>
            </field>
            <field>
              <name>MONO</name>
              <bitOffset>12</bitOffset>
              <bitWidth>1</bitWidth>
            </field>
            <field>
              <name>OUTDRIV</name>
              <bitOffset>13</bitOffset>
              <bitWidth>1</bitWidth>
            </field>
            <field>
              <name>SAIEN</name>
              <bitOffset>16</bitOffset>
              <bitWidth>1</bitWidth>
            </field>
            <field>
              <name>DMAEN</name>
              <bitOffset>17</bitOffset>
              <bitWidth>1</bitWidth>
            </field>
            <field>
              <name>NODIV</name>
              <bitOffset>19</bitOffset>
              <bitWidth>1</bitWidth>
            </field>
            <field>
              <name>MCKDIV</name>
              <bitOffset>20</bitOffset>
              <bitWidth>6</bitWidth>
            </field>
            <field>
              <name>OSR</name>
              <bitOffset>26</bitOffset>
              <bitWidth>1</bitWidth>
            </field>
            <field>
              <name>MCKEN</name>
              <bitOffset>27</bitOffset>
              <bitWidth>1</bitWidth>
            </field>
          </fields>
        </register>
        <register>
          <name>CR1A</name>
          <addressOffset>0x4</addressOffset>
          <size>0x20</size>
          <fields>
            <field>
              <name>MODE</name>
              <bitOffset>0</bitOffset>
              <bitWidth>2</bitWidth>
            </field>
            <field>
              <name>PRTCFG</name>
              <bitOffset>2</bitOffset>
              <bitWidth>2</bitWidth>
            </field>
            <field>
              <name>DS</name>
              <bitOffset>5</bitOffset>
              <bitWidth>3</bitWidth>
            </field>
            <field>
              <name>LSBFIRST</name>
              <bitOffset>8</bitOffset>
              <bitWidth>1</bitWidth>
            </field>
            <field>
              <name>CKSTR</name>
              <bitOffset>9</bitOffset>
              <bitWidth>1</bitWidth>
            </field>
            <field>
              <name>SYNCEN</name>
              <bitOffset>10</bitOffset>
              <bitWidth>2</bitWidth>
            </field>
            <field>
              <name>MONO</name>
              <bitOffset>12</bitOffset>
              <bitWidth>1</bitWidth>
            </field>
            <field>
              <name>OUTDRIV</name>
              <bitOffset>13</bitOffset>
              <bitWidth>1</bitWidth>
            </field>
            <field>
              <name>SAIEN</name>
              <bitOffset>16</bitOffset>
              <bitWidth>1</bitWidth>
            </field>
            <field>
              <name>DMAEN</name>
              <bitOffset>17</bitOffset>
              <bitWidth>1</bitWidth>
            </field>
            <field>
              <name>NODIV</name>
              <bitOffset>19</bitOffset>
              <bitWidth>1</bitWidth>
            </field>
            <field>
              <name>MCKDIV</name>
              <bitOffset>20</bitOffset>
              <bitWidth>6</bitWidth>
            </field>
            <field>
              <name>OSR</name>
              <bitOffset>26</bitOffset>
              <bitWidth>1</bitWidth>
            </field>
            <field>
              <name>MCKEN</name>
              <bitOffset>27</bitOffset>
              <bitWidth>1</bitWidth>
            </field>
          </fields>
        </register>
        <register>
          <name>CR1A</name>
          <addressOffset>0x4</addressOffset>
          <size>0x20</size>
          <fields>
            <field>
              <name>MODE</name>
              <bitOffset>0</bitOffset>
              <bitWidth>2</bitWidth>
            </field>
            <field>
              <name>PRTCFG</name>
              <bitOffset>2</bitOffset>
              <bitWidth>2</bitWidth>
            </field>
            <field>
              <name>DS</name>
              <bitOffset>5</bitOffset>
              <bitWidth>3</bitWidth>
            </field>
            <field>
              <name>LSBFIRST</name>
              <bitOffset>8</bitOffset>
              <bitWidth>1</bitWidth>
            </field>
            <field>
              <name>CKSTR</name>
              <bitOffset>9</bitOffset>
              <bitWidth>1</bitWidth>
            </field>
            <field>
              <name>SYNCEN</name>
              <bitOffset>10</bitOffset>
              <bitWidth>2</bitWidth>
            </field>
            <field>
              <name>MONO</name>
              <bitOffset>12</bitOffset>
              <bitWidth>1</bitWidth>
            </field>
            <field>
              <name>OUTDRIV</name>
              <bitOffset>13</bitOffset>
              <bitWidth>1</bitWidth>
            </field>
            <field>
              <name>SAIEN</name>
              <bitOffset>16</bitOffset>
              <bitWidth>1</bitWidth>
            </field>
            <field>
              <name>DMAEN</name>
              <bitOffset>17</bitOffset>
              <bitWidth>1</bitWidth>
            </field>
            <field>
              <name>NODIV</name>
              <bitOffset>19</bitOffset>
              <bitWidth>1</bitWidth>
            </field>
            <field>
              <name>MCKDIV</name>
              <bitOffset>20</bitOffset>
              <bitWidth>6</bitWidth>
            </field>
            <field>
              <name>OSR</name>
              <bitOffset>26</bitOffset>
              <bitWidth>1</bitWidth>
            </field>
            <field>
              <name>MCKEN</name>
              <bitOffset>27</bitOffset>
              <bitWidth>1</bitWidth>
            </field>
          </fields>
        </register>
        <register>
          <name>CR1A</name>
          <addressOffset>0x4</addressOffset>
          <size>0x20</size>
          <fields>
            <field>
              <name>MODE</name>
              <bitOffset>0</bitOffset>
              <bitWidth>2</bitWidth>
            </field>
            <field>
              <name>PRTCFG</name>
              <bitOffset>2</bitOffset>
              <bitWidth>2</bitWidth>
            </field>
            <field>
              <name>DS</name>
              <bitOffset>5</bitOffset>
              <bitWidth>3</bitWidth>
            </field>
            <field>
              <name>LSBFIRST</name>
              <bitOffset>8</bitOffset>
              <bitWidth>1</bitWidth>
            </field>
            <field>
              <name>CKSTR</name>
              <bitOffset>9</bitOffset>
              <bitWidth>1</bitWidth>
            </field>
            <field>
              <name>SYNCEN</name>
              <bitOffset>10</bitOffset>
              <bitWidth>2</bitWidth>
            </field>
            <field>
              <name>MONO</name>
              <bitOffset>12</bitOffset>
              <bitWidth>1</bitWidth>
            </field>
            <field>
              <name>OUTDRIV</name>
              <bitOffset>13</bitOffset>
              <bitWidth>1</bitWidth>
            </field>
            <field>
              <name>SAIEN</name>
              <bitOffset>16</bitOffset>
              <bitWidth>1</bitWidth>
            </field>
            <field>
              <name>DMAEN</name>
              <bitOffset>17</bitOffset>
              <bitWidth>1</bitWidth>
            </field>
            <field>
              <name>NODIV</name>
              <bitOffset>19</bitOffset>
              <bitWidth>1</bitWidth>
            </field>
            <field>
              <name>MCKDIV</name>
              <bitOffset>20</bitOffset>
              <bitWidth>6</bitWidth>
            </field>
            <field>
              <name>OSR</name>
              <bitOffset>26</bitOffset>
              <bitWidth>1</bitWidth>
            </field>
            <field>
              <name>MCKEN</name>
              <bitOffset>27</bitOffset>
              <bitWidth>1</bitWidth>
            </field>
          </fields>
        </register>
        <register>
          <name>CR2A</name>
          <addressOffset>0x8</addressOffset>
          <size>0x20</size>
          <fields>
            <field>
              <name>FTH</name>
              <bitOffset>0</bitOffset>
              <bitWidth>3</bitWidth>
            </field>
            <field>
              <name>FFLUSH</name>
              <bitOffset>3</bitOffset>
              <bitWidth>1</bitWidth>
            </field>
            <field>
              <name>TRIS</name>
              <bitOffset>4</bitOffset>
              <bitWidth>1</bitWidth>
            </field>
            <field>
              <name>MUTE</name>
              <bitOffset>5</bitOffset>
              <bitWidth>1</bitWidth>
            </field>
            <field>
              <name>MUTEVAL</name>
              <bitOffset>6</bitOffset>
              <bitWidth>1</bitWidth>
            </field>
            <field>
              <name>MUTECNT</name>
              <bitOffset>7</bitOffset>
              <bitWidth>6</bitWidth>
            </field>
            <field>
              <name>CPL</name>
              <bitOffset>13</bitOffset>
              <bitWidth>1</bitWidth>
            </field>
            <field>
              <name>COMP</name>
              <bitOffset>14</bitOffset>
              <bitWidth>2</bitWidth>
            </field>
          </fields>
        </register>
        <register>
          <name>CR2A</name>
          <addressOffset>0x8</addressOffset>
          <size>0x20</size>
          <fields>
            <field>
              <name>FTH</name>
              <bitOffset>0</bitOffset>
              <bitWidth>3</bitWidth>
            </field>
            <field>
              <name>FFLUSH</name>
              <bitOffset>3</bitOffset>
              <bitWidth>1</bitWidth>
            </field>
            <field>
              <name>TRIS</name>
              <bitOffset>4</bitOffset>
              <bitWidth>1</bitWidth>
            </field>
            <field>
              <name>MUTE</name>
              <bitOffset>5</bitOffset>
              <bitWidth>1</bitWidth>
            </field>
            <field>
              <name>MUTEVAL</name>
              <bitOffset>6</bitOffset>
              <bitWidth>1</bitWidth>
            </field>
            <field>
              <name>MUTECNT</name>
              <bitOffset>7</bitOffset>
              <bitWidth>6</bitWidth>
            </field>
            <field>
              <name>CPL</name>
              <bitOffset>13</bitOffset>
              <bitWidth>1</bitWidth>
            </field>
            <field>
              <name>COMP</name>
              <bitOffset>14</bitOffset>
              <bitWidth>2</bitWidth>
            </field>
          </fields>
        </register>
        <register>
          <name>CR2A</name>
          <addressOffset>0x8</addressOffset>
          <size>0x20</size>
          <fields>
            <field>
              <name>FTH</name>
              <bitOffset>0</bitOffset>
              <bitWidth>3</bitWidth>
            </field>
            <field>
              <name>FFLUSH</name>
              <bitOffset>3</bitOffset>
              <bitWidth>1</bitWidth>
            </field>
            <field>
              <name>TRIS</name>
              <bitOffset>4</bitOffset>
              <bitWidth>1</bitWidth>
            </field>
            <field>
              <name>MUTE</name>
              <bitOffset>5</bitOffset>
              <bitWidth>1</bitWidth>
            </field>
            <field>
              <name>MUTEVAL</name>
              <bitOffset>6</bitOffset>
              <bitWidth>1</bitWidth>
            </field>
            <field>
              <name>MUTECNT</name>
              <bitOffset>7</bitOffset>
              <bitWidth>6</bitWidth>
            </field>
            <field>
              <name>CPL</name>
              <bitOffset>13</bitOffset>
              <bitWidth>1</bitWidth>
            </field>
            <field>
              <name>COMP</name>
              <bitOffset>14</bitOffset>
              <bitWidth>2</bitWidth>
            </field>
          </fields>
        </register>
        <register>
          <name>CR2A</name>
          <addressOffset>0x8</addressOffset>
          <size>0x20</size>
          <fields>
            <field>
              <name>FTH</name>
              <bitOffset>0</bitOffset>
              <bitWidth>3</bitWidth>
            </field>
            <field>
              <name>FFLUSH</name>
              <bitOffset>3</bitOffset>
              <bitWidth>1</bitWidth>
            </field>
            <field>
              <name>TRIS</name>
              <bitOffset>4</bitOffset>
              <bitWidth>1</bitWidth>
            </field>
            <field>
              <name>MUTE</name>
              <bitOffset>5</bitOffset>
              <bitWidth>1</bitWidth>
            </field>
            <field>
              <name>MUTEVAL</name>
              <bitOffset>6</bitOffset>
              <bitWidth>1</bitWidth>
            </field>
            <field>
              <name>MUTECNT</name>
              <bitOffset>7</bitOffset>
              <bitWidth>6</bitWidth>
            </field>
            <field>
              <name>CPL</name>
              <bitOffset>13</bitOffset>
              <bitWidth>1</bitWidth>
            </field>
            <field>
              <name>COMP</name>
              <bitOffset>14</bitOffset>
              <bitWidth>2</bitWidth>
            </field>
          </fields>
        </register>
        <register>
          <name>FRCRA</name>
          <addressOffset>0xc</addressOffset>
          <size>0x20</size>
          <fields>
            <field>
              <name>FRL</name>
              <bitOffset>0</bitOffset>
              <bitWidth>8</bitWidth>
            </field>
            <field>
              <name>FSALL</name>
              <bitOffset>8</bitOffset>
              <bitWidth>7</bitWidth>
            </field>
            <field>
              <name>FSDEF</name>
              <bitOffset>16</bitOffset>
              <bitWidth>1</bitWidth>
            </field>
            <field>
              <name>FSPOL</name>
              <bitOffset>17</bitOffset>
              <bitWidth>1</bitWidth>
            </field>
            <field>
              <name>FSOFF</name>
              <bitOffset>18</bitOffset>
              <bitWidth>1</bitWidth>
            </field>
          </fields>
        </register>
        <register>
          <name>FRCRA</name>
          <addressOffset>0xc</addressOffset>
          <size>0x20</size>
          <fields>
            <field>
              <name>FRL</name>
              <bitOffset>0</bitOffset>
              <bitWidth>8</bitWidth>
            </field>
            <field>
              <name>FSALL</name>
              <bitOffset>8</bitOffset>
              <bitWidth>7</bitWidth>
            </field>
            <field>
              <name>FSDEF</name>
              <bitOffset>16</bitOffset>
              <bitWidth>1</bitWidth>
            </field>
            <field>
              <name>FSPOL</name>
              <bitOffset>17</bitOffset>
              <bitWidth>1</bitWidth>
            </field>
            <field>
              <name>FSOFF</name>
              <bitOffset>18</bitOffset>
              <bitWidth>1</bitWidth>
            </field>
          </fields>
        </register>
        <register>
          <name>FRCRA</name>
          <addressOffset>0xc</addressOffset>
          <size>0x20</size>
          <fields>
            <field>
              <name>FRL</name>
              <bitOffset>0</bitOffset>
              <bitWidth>8</bitWidth>
            </field>
            <field>
              <name>FSALL</name>
              <bitOffset>8</bitOffset>
              <bitWidth>7</bitWidth>
            </field>
            <field>
              <name>FSDEF</name>
              <bitOffset>16</bitOffset>
              <bitWidth>1</bitWidth>
            </field>
            <field>
              <name>FSPOL</name>
              <bitOffset>17</bitOffset>
              <bitWidth>1</bitWidth>
            </field>
            <field>
              <name>FSOFF</name>
              <bitOffset>18</bitOffset>
              <bitWidth>1</bitWidth>
            </field>
          </fields>
        </register>
        <register>
          <name>FRCRA</name>
          <addressOffset>0xc</addressOffset>
          <size>0x20</size>
          <fields>
            <field>
              <name>FRL</name>
              <bitOffset>0</bitOffset>
              <bitWidth>8</bitWidth>
            </field>
            <field>
              <name>FSALL</name>
              <bitOffset>8</bitOffset>
              <bitWidth>7</bitWidth>
            </field>
            <field>
              <name>FSDEF</name>
              <bitOffset>16</bitOffset>
              <bitWidth>1</bitWidth>
            </field>
            <field>
              <name>FSPOL</name>
              <bitOffset>17</bitOffset>
              <bitWidth>1</bitWidth>
            </field>
            <field>
              <name>FSOFF</name>
              <bitOffset>18</bitOffset>
              <bitWidth>1</bitWidth>
            </field>
          </fields>
        </register>
        <register>
          <name>SLOTRA</name>
          <addressOffset>0x10</addressOffset>
          <size>0x20</size>
          <fields>
            <field>
              <name>FBOFF</name>
              <bitOffset>0</bitOffset>
              <bitWidth>5</bitWidth>
            </field>
            <field>
              <name>SLOTSZ</name>
              <bitOffset>6</bitOffset>
              <bitWidth>2</bitWidth>
            </field>
            <field>
              <name>NBSLOT</name>
              <bitOffset>8</bitOffset>
              <bitWidth>4</bitWidth>
            </field>
            <field>
              <name>SLOTEN</name>
              <bitOffset>16</bitOffset>
              <bitWidth>16</bitWidth>
            </field>
          </fields>
        </register>
        <register>
          <name>SLOTRA</name>
          <addressOffset>0x10</addressOffset>
          <size>0x20</size>
          <fields>
            <field>
              <name>FBOFF</name>
              <bitOffset>0</bitOffset>
              <bitWidth>5</bitWidth>
            </field>
            <field>
              <name>SLOTSZ</name>
              <bitOffset>6</bitOffset>
              <bitWidth>2</bitWidth>
            </field>
            <field>
              <name>NBSLOT</name>
              <bitOffset>8</bitOffset>
              <bitWidth>4</bitWidth>
            </field>
            <field>
              <name>SLOTEN</name>
              <bitOffset>16</bitOffset>
              <bitWidth>16</bitWidth>
            </field>
          </fields>
        </register>
        <register>
          <name>SLOTRA</name>
          <addressOffset>0x10</addressOffset>
          <size>0x20</size>
          <fields>
            <field>
              <name>FBOFF</name>
              <bitOffset>0</bitOffset>
              <bitWidth>5</bitWidth>
            </field>
            <field>
              <name>SLOTSZ</name>
              <bitOffset>6</bitOffset>
              <bitWidth>2</bitWidth>
            </field>
            <field>
              <name>NBSLOT</name>
              <bitOffset>8</bitOffset>
              <bitWidth>4</bitWidth>
            </field>
            <field>
              <name>SLOTEN</name>
              <bitOffset>16</bitOffset>
              <bitWidth>16</bitWidth>
            </field>
          </fields>
        </register>
        <register>
          <name>SLOTRA</name>
          <addressOffset>0x10</addressOffset>
          <size>0x20</size>
          <fields>
            <field>
              <name>FBOFF</name>
              <bitOffset>0</bitOffset>
              <bitWidth>5</bitWidth>
            </field>
            <field>
              <name>SLOTSZ</name>
              <bitOffset>6</bitOffset>
              <bitWidth>2</bitWidth>
            </field>
            <field>
              <name>NBSLOT</name>
              <bitOffset>8</bitOffset>
              <bitWidth>4</bitWidth>
            </field>
            <field>
              <name>SLOTEN</name>
              <bitOffset>16</bitOffset>
              <bitWidth>16</bitWidth>
            </field>
          </fields>
        </register>
        <register>
          <name>IMRA</name>
          <addressOffset>0x14</addressOffset>
          <size>0x20</size>
          <fields>
            <field>
              <name>OVRUDRIE</name>
              <bitOffset>0</bitOffset>
              <bitWidth>1</bitWidth>
            </field>
            <field>
              <name>MUTEDETIE</name>
              <bitOffset>1</bitOffset>
              <bitWidth>1</bitWidth>
            </field>
            <field>
              <name>WCKCFGIE</name>
              <bitOffset>2</bitOffset>
              <bitWidth>1</bitWidth>
            </field>
            <field>
              <name>FREQIE</name>
              <bitOffset>3</bitOffset>
              <bitWidth>1</bitWidth>
            </field>
            <field>
              <name>CNRDYIE</name>
              <bitOffset>4</bitOffset>
              <bitWidth>1</bitWidth>
            </field>
            <field>
              <name>AFSDETIE</name>
              <bitOffset>5</bitOffset>
              <bitWidth>1</bitWidth>
            </field>
            <field>
              <name>LFSDETIE</name>
              <bitOffset>6</bitOffset>
              <bitWidth>1</bitWidth>
            </field>
          </fields>
        </register>
        <register>
          <name>IMRA</name>
          <addressOffset>0x14</addressOffset>
          <size>0x20</size>
          <fields>
            <field>
              <name>OVRUDRIE</name>
              <bitOffset>0</bitOffset>
              <bitWidth>1</bitWidth>
            </field>
            <field>
              <name>MUTEDETIE</name>
              <bitOffset>1</bitOffset>
              <bitWidth>1</bitWidth>
            </field>
            <field>
              <name>WCKCFGIE</name>
              <bitOffset>2</bitOffset>
              <bitWidth>1</bitWidth>
            </field>
            <field>
              <name>FREQIE</name>
              <bitOffset>3</bitOffset>
              <bitWidth>1</bitWidth>
            </field>
            <field>
              <name>CNRDYIE</name>
              <bitOffset>4</bitOffset>
              <bitWidth>1</bitWidth>
            </field>
            <field>
              <name>AFSDETIE</name>
              <bitOffset>5</bitOffset>
              <bitWidth>1</bitWidth>
            </field>
            <field>
              <name>LFSDETIE</name>
              <bitOffset>6</bitOffset>
              <bitWidth>1</bitWidth>
            </field>
          </fields>
        </register>
        <register>
          <name>IMRA</name>
          <addressOffset>0x14</addressOffset>
          <size>0x20</size>
          <fields>
            <field>
              <name>OVRUDRIE</name>
              <bitOffset>0</bitOffset>
              <bitWidth>1</bitWidth>
            </field>
            <field>
              <name>MUTEDETIE</name>
              <bitOffset>1</bitOffset>
              <bitWidth>1</bitWidth>
            </field>
            <field>
              <name>WCKCFGIE</name>
              <bitOffset>2</bitOffset>
              <bitWidth>1</bitWidth>
            </field>
            <field>
              <name>FREQIE</name>
              <bitOffset>3</bitOffset>
              <bitWidth>1</bitWidth>
            </field>
            <field>
              <name>CNRDYIE</name>
              <bitOffset>4</bitOffset>
              <bitWidth>1</bitWidth>
            </field>
            <field>
              <name>AFSDETIE</name>
              <bitOffset>5</bitOffset>
              <bitWidth>1</bitWidth>
            </field>
            <field>
              <name>LFSDETIE</name>
              <bitOffset>6</bitOffset>
              <bitWidth>1</bitWidth>
            </field>
          </fields>
        </register>
        <register>
          <name>IMRA</name>
          <addressOffset>0x14</addressOffset>
          <size>0x20</size>
          <fields>
            <field>
              <name>OVRUDRIE</name>
              <bitOffset>0</bitOffset>
              <bitWidth>1</bitWidth>
            </field>
            <field>
              <name>MUTEDETIE</name>
              <bitOffset>1</bitOffset>
              <bitWidth>1</bitWidth>
            </field>
            <field>
              <name>WCKCFGIE</name>
              <bitOffset>2</bitOffset>
              <bitWidth>1</bitWidth>
            </field>
            <field>
              <name>FREQIE</name>
              <bitOffset>3</bitOffset>
              <bitWidth>1</bitWidth>
            </field>
            <field>
              <name>CNRDYIE</name>
              <bitOffset>4</bitOffset>
              <bitWidth>1</bitWidth>
            </field>
            <field>
              <name>AFSDETIE</name>
              <bitOffset>5</bitOffset>
              <bitWidth>1</bitWidth>
            </field>
            <field>
              <name>LFSDETIE</name>
              <bitOffset>6</bitOffset>
              <bitWidth>1</bitWidth>
            </field>
          </fields>
        </register>
        <register>
          <name>SRA</name>
          <addressOffset>0x18</addressOffset>
          <size>0x20</size>
          <fields>
            <field>
              <name>OVRUDR</name>
              <bitOffset>0</bitOffset>
              <bitWidth>1</bitWidth>
            </field>
            <field>
              <name>MUTEDET</name>
              <bitOffset>1</bitOffset>
              <bitWidth>1</bitWidth>
            </field>
            <field>
              <name>WCKCFG</name>
              <bitOffset>2</bitOffset>
              <bitWidth>1</bitWidth>
            </field>
            <field>
              <name>FREQ</name>
              <bitOffset>3</bitOffset>
              <bitWidth>1</bitWidth>
            </field>
            <field>
              <name>CNRDY</name>
              <bitOffset>4</bitOffset>
              <bitWidth>1</bitWidth>
            </field>
            <field>
              <name>AFSDET</name>
              <bitOffset>5</bitOffset>
              <bitWidth>1</bitWidth>
            </field>
            <field>
              <name>LFSDET</name>
              <bitOffset>6</bitOffset>
              <bitWidth>1</bitWidth>
            </field>
            <field>
              <name>FLVL</name>
              <bitOffset>16</bitOffset>
              <bitWidth>3</bitWidth>
            </field>
          </fields>
        </register>
        <register>
          <name>SRA</name>
          <addressOffset>0x18</addressOffset>
          <size>0x20</size>
          <fields>
            <field>
              <name>OVRUDR</name>
              <bitOffset>0</bitOffset>
              <bitWidth>1</bitWidth>
            </field>
            <field>
              <name>MUTEDET</name>
              <bitOffset>1</bitOffset>
              <bitWidth>1</bitWidth>
            </field>
            <field>
              <name>WCKCFG</name>
              <bitOffset>2</bitOffset>
              <bitWidth>1</bitWidth>
            </field>
            <field>
              <name>FREQ</name>
              <bitOffset>3</bitOffset>
              <bitWidth>1</bitWidth>
            </field>
            <field>
              <name>CNRDY</name>
              <bitOffset>4</bitOffset>
              <bitWidth>1</bitWidth>
            </field>
            <field>
              <name>AFSDET</name>
              <bitOffset>5</bitOffset>
              <bitWidth>1</bitWidth>
            </field>
            <field>
              <name>LFSDET</name>
              <bitOffset>6</bitOffset>
              <bitWidth>1</bitWidth>
            </field>
            <field>
              <name>FLVL</name>
              <bitOffset>16</bitOffset>
              <bitWidth>3</bitWidth>
            </field>
          </fields>
        </register>
        <register>
          <name>SRA</name>
          <addressOffset>0x18</addressOffset>
          <size>0x20</size>
          <fields>
            <field>
              <name>OVRUDR</name>
              <bitOffset>0</bitOffset>
              <bitWidth>1</bitWidth>
            </field>
            <field>
              <name>MUTEDET</name>
              <bitOffset>1</bitOffset>
              <bitWidth>1</bitWidth>
            </field>
            <field>
              <name>WCKCFG</name>
              <bitOffset>2</bitOffset>
              <bitWidth>1</bitWidth>
            </field>
            <field>
              <name>FREQ</name>
              <bitOffset>3</bitOffset>
              <bitWidth>1</bitWidth>
            </field>
            <field>
              <name>CNRDY</name>
              <bitOffset>4</bitOffset>
              <bitWidth>1</bitWidth>
            </field>
            <field>
              <name>AFSDET</name>
              <bitOffset>5</bitOffset>
              <bitWidth>1</bitWidth>
            </field>
            <field>
              <name>LFSDET</name>
              <bitOffset>6</bitOffset>
              <bitWidth>1</bitWidth>
            </field>
            <field>
              <name>FLVL</name>
              <bitOffset>16</bitOffset>
              <bitWidth>3</bitWidth>
            </field>
          </fields>
        </register>
        <register>
          <name>SRA</name>
          <addressOffset>0x18</addressOffset>
          <size>0x20</size>
          <fields>
            <field>
              <name>OVRUDR</name>
              <bitOffset>0</bitOffset>
              <bitWidth>1</bitWidth>
            </field>
            <field>
              <name>MUTEDET</name>
              <bitOffset>1</bitOffset>
              <bitWidth>1</bitWidth>
            </field>
            <field>
              <name>WCKCFG</name>
              <bitOffset>2</bitOffset>
              <bitWidth>1</bitWidth>
            </field>
            <field>
              <name>FREQ</name>
              <bitOffset>3</bitOffset>
              <bitWidth>1</bitWidth>
            </field>
            <field>
              <name>CNRDY</name>
              <bitOffset>4</bitOffset>
              <bitWidth>1</bitWidth>
            </field>
            <field>
              <name>AFSDET</name>
              <bitOffset>5</bitOffset>
              <bitWidth>1</bitWidth>
            </field>
            <field>
              <name>LFSDET</name>
              <bitOffset>6</bitOffset>
              <bitWidth>1</bitWidth>
            </field>
            <field>
              <name>FLVL</name>
              <bitOffset>16</bitOffset>
              <bitWidth>3</bitWidth>
            </field>
          </fields>
        </register>
        <register>
          <name>CLRFRA</name>
          <addressOffset>0x1c</addressOffset>
          <size>0x20</size>
          <fields>
            <field>
              <name>COVRUDR</name>
              <bitOffset>0</bitOffset>
              <bitWidth>1</bitWidth>
            </field>
            <field>
              <name>CMUTEDET</name>
              <bitOffset>1</bitOffset>
              <bitWidth>1</bitWidth>
            </field>
            <field>
              <name>CWCKCFG</name>
              <bitOffset>2</bitOffset>
              <bitWidth>1</bitWidth>
            </field>
            <field>
              <name>CFREQ</name>
              <bitOffset>3</bitOffset>
              <bitWidth>1</bitWidth>
            </field>
            <field>
              <name>CCNRDY</name>
              <bitOffset>4</bitOffset>
              <bitWidth>1</bitWidth>
            </field>
            <field>
              <name>CAFSDET</name>
              <bitOffset>5</bitOffset>
              <bitWidth>1</bitWidth>
            </field>
            <field>
              <name>CLFSDET</name>
              <bitOffset>6</bitOffset>
              <bitWidth>1</bitWidth>
            </field>
          </fields>
        </register>
        <register>
          <name>CLRFRA</name>
          <addressOffset>0x1c</addressOffset>
          <size>0x20</size>
          <fields>
            <field>
              <name>COVRUDR</name>
              <bitOffset>0</bitOffset>
              <bitWidth>1</bitWidth>
            </field>
            <field>
              <name>CMUTEDET</name>
              <bitOffset>1</bitOffset>
              <bitWidth>1</bitWidth>
            </field>
            <field>
              <name>CWCKCFG</name>
              <bitOffset>2</bitOffset>
              <bitWidth>1</bitWidth>
            </field>
            <field>
              <name>CFREQ</name>
              <bitOffset>3</bitOffset>
              <bitWidth>1</bitWidth>
            </field>
            <field>
              <name>CCNRDY</name>
              <bitOffset>4</bitOffset>
              <bitWidth>1</bitWidth>
            </field>
            <field>
              <name>CAFSDET</name>
              <bitOffset>5</bitOffset>
              <bitWidth>1</bitWidth>
            </field>
            <field>
              <name>CLFSDET</name>
              <bitOffset>6</bitOffset>
              <bitWidth>1</bitWidth>
            </field>
          </fields>
        </register>
        <register>
          <name>CLRFRA</name>
          <addressOffset>0x1c</addressOffset>
          <size>0x20</size>
          <fields>
            <field>
              <name>COVRUDR</name>
              <bitOffset>0</bitOffset>
              <bitWidth>1</bitWidth>
            </field>
            <field>
              <name>CMUTEDET</name>
              <bitOffset>1</bitOffset>
              <bitWidth>1</bitWidth>
            </field>
            <field>
              <name>CWCKCFG</name>
              <bitOffset>2</bitOffset>
              <bitWidth>1</bitWidth>
            </field>
            <field>
              <name>CFREQ</name>
              <bitOffset>3</bitOffset>
              <bitWidth>1</bitWidth>
            </field>
            <field>
              <name>CCNRDY</name>
              <bitOffset>4</bitOffset>
              <bitWidth>1</bitWidth>
            </field>
            <field>
              <name>CAFSDET</name>
              <bitOffset>5</bitOffset>
              <bitWidth>1</bitWidth>
            </field>
            <field>
              <name>CLFSDET</name>
              <bitOffset>6</bitOffset>
              <bitWidth>1</bitWidth>
            </field>
          </fields>
        </register>
        <register>
          <name>CLRFRA</name>
          <addressOffset>0x1c</addressOffset>
          <size>0x20</size>
          <fields>
            <field>
              <name>COVRUDR</name>
              <bitOffset>0</bitOffset>
              <bitWidth>1</bitWidth>
            </field>
            <field>
              <name>CMUTEDET</name>
              <bitOffset>1</bitOffset>
              <bitWidth>1</bitWidth>
            </field>
            <field>
              <name>CWCKCFG</name>
              <bitOffset>2</bitOffset>
              <bitWidth>1</bitWidth>
            </field>
            <field>
              <name>CFREQ</name>
              <bitOffset>3</bitOffset>
              <bitWidth>1</bitWidth>
            </field>
            <field>
              <name>CCNRDY</name>
              <bitOffset>4</bitOffset>
              <bitWidth>1</bitWidth>
            </field>
            <field>
              <name>CAFSDET</name>
              <bitOffset>5</bitOffset>
              <bitWidth>1</bitWidth>
            </field>
            <field>
              <name>CLFSDET</name>
              <bitOffset>6</bitOffset>
              <bitWidth>1</bitWidth>
            </field>
          </fields>
        </register>
        <register>
          <name>DRA</name>
          <addressOffset>0x20</addressOffset>
          <size>0x20</size>
          <fields>
            <field>
              <name>DATA</name>
              <bitOffset>0</bitOffset>
              <bitWidth>32</bitWidth>
            </field>
          </fields>
        </register>
        <register>
          <name>DRA</name>
          <addressOffset>0x20</addressOffset>
          <size>0x20</size>
          <fields>
            <field>
              <name>DATA</name>
              <bitOffset>0</bitOffset>
              <bitWidth>32</bitWidth>
            </field>
          </fields>
        </register>
        <register>
          <name>DRA</name>
          <addressOffset>0x20</addressOffset>
          <size>0x20</size>
          <fields>
            <field>
              <name>DATA</name>
              <bitOffset>0</bitOffset>
              <bitWidth>32</bitWidth>
            </field>
          </fields>
        </register>
        <register>
          <name>DRA</name>
          <addressOffset>0x20</addressOffset>
          <size>0x20</size>
          <fields>
            <field>
              <name>DATA</name>
              <bitOffset>0</bitOffset>
              <bitWidth>32</bitWidth>
            </field>
          </fields>
        </register>
        <register>
          <name>CR1B</name>
          <addressOffset>0x24</addressOffset>
          <size>0x20</size>
          <fields>
            <field>
              <name>MODE</name>
              <bitOffset>0</bitOffset>
              <bitWidth>2</bitWidth>
            </field>
            <field>
              <name>PRTCFG</name>
              <bitOffset>2</bitOffset>
              <bitWidth>2</bitWidth>
            </field>
            <field>
              <name>DS</name>
              <bitOffset>5</bitOffset>
              <bitWidth>3</bitWidth>
            </field>
            <field>
              <name>LSBFIRST</name>
              <bitOffset>8</bitOffset>
              <bitWidth>1</bitWidth>
            </field>
            <field>
              <name>CKSTR</name>
              <bitOffset>9</bitOffset>
              <bitWidth>1</bitWidth>
            </field>
            <field>
              <name>SYNCEN</name>
              <bitOffset>10</bitOffset>
              <bitWidth>2</bitWidth>
            </field>
            <field>
              <name>MONO</name>
              <bitOffset>12</bitOffset>
              <bitWidth>1</bitWidth>
            </field>
            <field>
              <name>OUTDRIV</name>
              <bitOffset>13</bitOffset>
              <bitWidth>1</bitWidth>
            </field>
            <field>
              <name>SAIEN</name>
              <bitOffset>16</bitOffset>
              <bitWidth>1</bitWidth>
            </field>
            <field>
              <name>DMAEN</name>
              <bitOffset>17</bitOffset>
              <bitWidth>1</bitWidth>
            </field>
            <field>
              <name>NODIV</name>
              <bitOffset>19</bitOffset>
              <bitWidth>1</bitWidth>
            </field>
            <field>
              <name>MCKDIV</name>
              <bitOffset>20</bitOffset>
              <bitWidth>6</bitWidth>
            </field>
            <field>
              <name>OSR</name>
              <bitOffset>26</bitOffset>
              <bitWidth>1</bitWidth>
            </field>
            <field>
              <name>MCKEN</name>
              <bitOffset>27</bitOffset>
              <bitWidth>1</bitWidth>
            </field>
          </fields>
        </register>
        <register>
          <name>CR1B</name>
          <addressOffset>0x24</addressOffset>
          <size>0x20</size>
          <fields>
            <field>
              <name>MODE</name>
              <bitOffset>0</bitOffset>
              <bitWidth>2</bitWidth>
            </field>
            <field>
              <name>PRTCFG</name>
              <bitOffset>2</bitOffset>
              <bitWidth>2</bitWidth>
            </field>
            <field>
              <name>DS</name>
              <bitOffset>5</bitOffset>
              <bitWidth>3</bitWidth>
            </field>
            <field>
              <name>LSBFIRST</name>
              <bitOffset>8</bitOffset>
              <bitWidth>1</bitWidth>
            </field>
            <field>
              <name>CKSTR</name>
              <bitOffset>9</bitOffset>
              <bitWidth>1</bitWidth>
            </field>
            <field>
              <name>SYNCEN</name>
              <bitOffset>10</bitOffset>
              <bitWidth>2</bitWidth>
            </field>
            <field>
              <name>MONO</name>
              <bitOffset>12</bitOffset>
              <bitWidth>1</bitWidth>
            </field>
            <field>
              <name>OUTDRIV</name>
              <bitOffset>13</bitOffset>
              <bitWidth>1</bitWidth>
            </field>
            <field>
              <name>SAIEN</name>
              <bitOffset>16</bitOffset>
              <bitWidth>1</bitWidth>
            </field>
            <field>
              <name>DMAEN</name>
              <bitOffset>17</bitOffset>
              <bitWidth>1</bitWidth>
            </field>
            <field>
              <name>NODIV</name>
              <bitOffset>19</bitOffset>
              <bitWidth>1</bitWidth>
            </field>
            <field>
              <name>MCKDIV</name>
              <bitOffset>20</bitOffset>
              <bitWidth>6</bitWidth>
            </field>
            <field>
              <name>OSR</name>
              <bitOffset>26</bitOffset>
              <bitWidth>1</bitWidth>
            </field>
            <field>
              <name>MCKEN</name>
              <bitOffset>27</bitOffset>
              <bitWidth>1</bitWidth>
            </field>
          </fields>
        </register>
        <register>
          <name>CR1B</name>
          <addressOffset>0x24</addressOffset>
          <size>0x20</size>
          <fields>
            <field>
              <name>MODE</name>
              <bitOffset>0</bitOffset>
              <bitWidth>2</bitWidth>
            </field>
            <field>
              <name>PRTCFG</name>
              <bitOffset>2</bitOffset>
              <bitWidth>2</bitWidth>
            </field>
            <field>
              <name>DS</name>
              <bitOffset>5</bitOffset>
              <bitWidth>3</bitWidth>
            </field>
            <field>
              <name>LSBFIRST</name>
              <bitOffset>8</bitOffset>
              <bitWidth>1</bitWidth>
            </field>
            <field>
              <name>CKSTR</name>
              <bitOffset>9</bitOffset>
              <bitWidth>1</bitWidth>
            </field>
            <field>
              <name>SYNCEN</name>
              <bitOffset>10</bitOffset>
              <bitWidth>2</bitWidth>
            </field>
            <field>
              <name>MONO</name>
              <bitOffset>12</bitOffset>
              <bitWidth>1</bitWidth>
            </field>
            <field>
              <name>OUTDRIV</name>
              <bitOffset>13</bitOffset>
              <bitWidth>1</bitWidth>
            </field>
            <field>
              <name>SAIEN</name>
              <bitOffset>16</bitOffset>
              <bitWidth>1</bitWidth>
            </field>
            <field>
              <name>DMAEN</name>
              <bitOffset>17</bitOffset>
              <bitWidth>1</bitWidth>
            </field>
            <field>
              <name>NODIV</name>
              <bitOffset>19</bitOffset>
              <bitWidth>1</bitWidth>
            </field>
            <field>
              <name>MCKDIV</name>
              <bitOffset>20</bitOffset>
              <bitWidth>6</bitWidth>
            </field>
            <field>
              <name>OSR</name>
              <bitOffset>26</bitOffset>
              <bitWidth>1</bitWidth>
            </field>
            <field>
              <name>MCKEN</name>
              <bitOffset>27</bitOffset>
              <bitWidth>1</bitWidth>
            </field>
          </fields>
        </register>
        <register>
          <name>CR1B</name>
          <addressOffset>0x24</addressOffset>
          <size>0x20</size>
          <fields>
            <field>
              <name>MODE</name>
              <bitOffset>0</bitOffset>
              <bitWidth>2</bitWidth>
            </field>
            <field>
              <name>PRTCFG</name>
              <bitOffset>2</bitOffset>
              <bitWidth>2</bitWidth>
            </field>
            <field>
              <name>DS</name>
              <bitOffset>5</bitOffset>
              <bitWidth>3</bitWidth>
            </field>
            <field>
              <name>LSBFIRST</name>
              <bitOffset>8</bitOffset>
              <bitWidth>1</bitWidth>
            </field>
            <field>
              <name>CKSTR</name>
              <bitOffset>9</bitOffset>
              <bitWidth>1</bitWidth>
            </field>
            <field>
              <name>SYNCEN</name>
              <bitOffset>10</bitOffset>
              <bitWidth>2</bitWidth>
            </field>
            <field>
              <name>MONO</name>
              <bitOffset>12</bitOffset>
              <bitWidth>1</bitWidth>
            </field>
            <field>
              <name>OUTDRIV</name>
              <bitOffset>13</bitOffset>
              <bitWidth>1</bitWidth>
            </field>
            <field>
              <name>SAIEN</name>
              <bitOffset>16</bitOffset>
              <bitWidth>1</bitWidth>
            </field>
            <field>
              <name>DMAEN</name>
              <bitOffset>17</bitOffset>
              <bitWidth>1</bitWidth>
            </field>
            <field>
              <name>NODIV</name>
              <bitOffset>19</bitOffset>
              <bitWidth>1</bitWidth>
            </field>
            <field>
              <name>MCKDIV</name>
              <bitOffset>20</bitOffset>
              <bitWidth>6</bitWidth>
            </field>
            <field>
              <name>OSR</name>
              <bitOffset>26</bitOffset>
              <bitWidth>1</bitWidth>
            </field>
            <field>
              <name>MCKEN</name>
              <bitOffset>27</bitOffset>
              <bitWidth>1</bitWidth>
            </field>
          </fields>
        </register>
        <register>
          <name>CR2B</name>
          <addressOffset>0x28</addressOffset>
          <size>0x20</size>
          <fields>
            <field>
              <name>FTH</name>
              <bitOffset>0</bitOffset>
              <bitWidth>3</bitWidth>
            </field>
            <field>
              <name>FFLUSH</name>
              <bitOffset>3</bitOffset>
              <bitWidth>1</bitWidth>
            </field>
            <field>
              <name>TRIS</name>
              <bitOffset>4</bitOffset>
              <bitWidth>1</bitWidth>
            </field>
            <field>
              <name>MUTE</name>
              <bitOffset>5</bitOffset>
              <bitWidth>1</bitWidth>
            </field>
            <field>
              <name>MUTEVAL</name>
              <bitOffset>6</bitOffset>
              <bitWidth>1</bitWidth>
            </field>
            <field>
              <name>MUTECNT</name>
              <bitOffset>7</bitOffset>
              <bitWidth>6</bitWidth>
            </field>
            <field>
              <name>CPL</name>
              <bitOffset>13</bitOffset>
              <bitWidth>1</bitWidth>
            </field>
            <field>
              <name>COMP</name>
              <bitOffset>14</bitOffset>
              <bitWidth>2</bitWidth>
            </field>
          </fields>
        </register>
        <register>
          <name>CR2B</name>
          <addressOffset>0x28</addressOffset>
          <size>0x20</size>
          <fields>
            <field>
              <name>FTH</name>
              <bitOffset>0</bitOffset>
              <bitWidth>3</bitWidth>
            </field>
            <field>
              <name>FFLUSH</name>
              <bitOffset>3</bitOffset>
              <bitWidth>1</bitWidth>
            </field>
            <field>
              <name>TRIS</name>
              <bitOffset>4</bitOffset>
              <bitWidth>1</bitWidth>
            </field>
            <field>
              <name>MUTE</name>
              <bitOffset>5</bitOffset>
              <bitWidth>1</bitWidth>
            </field>
            <field>
              <name>MUTEVAL</name>
              <bitOffset>6</bitOffset>
              <bitWidth>1</bitWidth>
            </field>
            <field>
              <name>MUTECNT</name>
              <bitOffset>7</bitOffset>
              <bitWidth>6</bitWidth>
            </field>
            <field>
              <name>CPL</name>
              <bitOffset>13</bitOffset>
              <bitWidth>1</bitWidth>
            </field>
            <field>
              <name>COMP</name>
              <bitOffset>14</bitOffset>
              <bitWidth>2</bitWidth>
            </field>
          </fields>
        </register>
        <register>
          <name>CR2B</name>
          <addressOffset>0x28</addressOffset>
          <size>0x20</size>
          <fields>
            <field>
              <name>FTH</name>
              <bitOffset>0</bitOffset>
              <bitWidth>3</bitWidth>
            </field>
            <field>
              <name>FFLUSH</name>
              <bitOffset>3</bitOffset>
              <bitWidth>1</bitWidth>
            </field>
            <field>
              <name>TRIS</name>
              <bitOffset>4</bitOffset>
              <bitWidth>1</bitWidth>
            </field>
            <field>
              <name>MUTE</name>
              <bitOffset>5</bitOffset>
              <bitWidth>1</bitWidth>
            </field>
            <field>
              <name>MUTEVAL</name>
              <bitOffset>6</bitOffset>
              <bitWidth>1</bitWidth>
            </field>
            <field>
              <name>MUTECNT</name>
              <bitOffset>7</bitOffset>
              <bitWidth>6</bitWidth>
            </field>
            <field>
              <name>CPL</name>
              <bitOffset>13</bitOffset>
              <bitWidth>1</bitWidth>
            </field>
            <field>
              <name>COMP</name>
              <bitOffset>14</bitOffset>
              <bitWidth>2</bitWidth>
            </field>
          </fields>
        </register>
        <register>
          <name>CR2B</name>
          <addressOffset>0x28</addressOffset>
          <size>0x20</size>
          <fields>
            <field>
              <name>FTH</name>
              <bitOffset>0</bitOffset>
              <bitWidth>3</bitWidth>
            </field>
            <field>
              <name>FFLUSH</name>
              <bitOffset>3</bitOffset>
              <bitWidth>1</bitWidth>
            </field>
            <field>
              <name>TRIS</name>
              <bitOffset>4</bitOffset>
              <bitWidth>1</bitWidth>
            </field>
            <field>
              <name>MUTE</name>
              <bitOffset>5</bitOffset>
              <bitWidth>1</bitWidth>
            </field>
            <field>
              <name>MUTEVAL</name>
              <bitOffset>6</bitOffset>
              <bitWidth>1</bitWidth>
            </field>
            <field>
              <name>MUTECNT</name>
              <bitOffset>7</bitOffset>
              <bitWidth>6</bitWidth>
            </field>
            <field>
              <name>CPL</name>
              <bitOffset>13</bitOffset>
              <bitWidth>1</bitWidth>
            </field>
            <field>
              <name>COMP</name>
              <bitOffset>14</bitOffset>
              <bitWidth>2</bitWidth>
            </field>
          </fields>
        </register>
        <register>
          <name>FRCRB</name>
          <addressOffset>0x2c</addressOffset>
          <size>0x20</size>
          <fields>
            <field>
              <name>FRL</name>
              <bitOffset>0</bitOffset>
              <bitWidth>8</bitWidth>
            </field>
            <field>
              <name>FSALL</name>
              <bitOffset>8</bitOffset>
              <bitWidth>7</bitWidth>
            </field>
            <field>
              <name>FSDEF</name>
              <bitOffset>16</bitOffset>
              <bitWidth>1</bitWidth>
            </field>
            <field>
              <name>FSPOL</name>
              <bitOffset>17</bitOffset>
              <bitWidth>1</bitWidth>
            </field>
            <field>
              <name>FSOFF</name>
              <bitOffset>18</bitOffset>
              <bitWidth>1</bitWidth>
            </field>
          </fields>
        </register>
        <register>
          <name>FRCRB</name>
          <addressOffset>0x2c</addressOffset>
          <size>0x20</size>
          <fields>
            <field>
              <name>FRL</name>
              <bitOffset>0</bitOffset>
              <bitWidth>8</bitWidth>
            </field>
            <field>
              <name>FSALL</name>
              <bitOffset>8</bitOffset>
              <bitWidth>7</bitWidth>
            </field>
            <field>
              <name>FSDEF</name>
              <bitOffset>16</bitOffset>
              <bitWidth>1</bitWidth>
            </field>
            <field>
              <name>FSPOL</name>
              <bitOffset>17</bitOffset>
              <bitWidth>1</bitWidth>
            </field>
            <field>
              <name>FSOFF</name>
              <bitOffset>18</bitOffset>
              <bitWidth>1</bitWidth>
            </field>
          </fields>
        </register>
        <register>
          <name>FRCRB</name>
          <addressOffset>0x2c</addressOffset>
          <size>0x20</size>
          <fields>
            <field>
              <name>FRL</name>
              <bitOffset>0</bitOffset>
              <bitWidth>8</bitWidth>
            </field>
            <field>
              <name>FSALL</name>
              <bitOffset>8</bitOffset>
              <bitWidth>7</bitWidth>
            </field>
            <field>
              <name>FSDEF</name>
              <bitOffset>16</bitOffset>
              <bitWidth>1</bitWidth>
            </field>
            <field>
              <name>FSPOL</name>
              <bitOffset>17</bitOffset>
              <bitWidth>1</bitWidth>
            </field>
            <field>
              <name>FSOFF</name>
              <bitOffset>18</bitOffset>
              <bitWidth>1</bitWidth>
            </field>
          </fields>
        </register>
        <register>
          <name>FRCRB</name>
          <addressOffset>0x2c</addressOffset>
          <size>0x20</size>
          <fields>
            <field>
              <name>FRL</name>
              <bitOffset>0</bitOffset>
              <bitWidth>8</bitWidth>
            </field>
            <field>
              <name>FSALL</name>
              <bitOffset>8</bitOffset>
              <bitWidth>7</bitWidth>
            </field>
            <field>
              <name>FSDEF</name>
              <bitOffset>16</bitOffset>
              <bitWidth>1</bitWidth>
            </field>
            <field>
              <name>FSPOL</name>
              <bitOffset>17</bitOffset>
              <bitWidth>1</bitWidth>
            </field>
            <field>
              <name>FSOFF</name>
              <bitOffset>18</bitOffset>
              <bitWidth>1</bitWidth>
            </field>
          </fields>
        </register>
        <register>
          <name>SLOTRB</name>
          <addressOffset>0x30</addressOffset>
          <size>0x20</size>
          <fields>
            <field>
              <name>FBOFF</name>
              <bitOffset>0</bitOffset>
              <bitWidth>5</bitWidth>
            </field>
            <field>
              <name>SLOTSZ</name>
              <bitOffset>6</bitOffset>
              <bitWidth>2</bitWidth>
            </field>
            <field>
              <name>NBSLOT</name>
              <bitOffset>8</bitOffset>
              <bitWidth>4</bitWidth>
            </field>
            <field>
              <name>SLOTEN</name>
              <bitOffset>16</bitOffset>
              <bitWidth>16</bitWidth>
            </field>
          </fields>
        </register>
        <register>
          <name>SLOTRB</name>
          <addressOffset>0x30</addressOffset>
          <size>0x20</size>
          <fields>
            <field>
              <name>FBOFF</name>
              <bitOffset>0</bitOffset>
              <bitWidth>5</bitWidth>
            </field>
            <field>
              <name>SLOTSZ</name>
              <bitOffset>6</bitOffset>
              <bitWidth>2</bitWidth>
            </field>
            <field>
              <name>NBSLOT</name>
              <bitOffset>8</bitOffset>
              <bitWidth>4</bitWidth>
            </field>
            <field>
              <name>SLOTEN</name>
              <bitOffset>16</bitOffset>
              <bitWidth>16</bitWidth>
            </field>
          </fields>
        </register>
        <register>
          <name>SLOTRB</name>
          <addressOffset>0x30</addressOffset>
          <size>0x20</size>
          <fields>
            <field>
              <name>FBOFF</name>
              <bitOffset>0</bitOffset>
              <bitWidth>5</bitWidth>
            </field>
            <field>
              <name>SLOTSZ</name>
              <bitOffset>6</bitOffset>
              <bitWidth>2</bitWidth>
            </field>
            <field>
              <name>NBSLOT</name>
              <bitOffset>8</bitOffset>
              <bitWidth>4</bitWidth>
            </field>
            <field>
              <name>SLOTEN</name>
              <bitOffset>16</bitOffset>
              <bitWidth>16</bitWidth>
            </field>
          </fields>
        </register>
        <register>
          <name>SLOTRB</name>
          <addressOffset>0x30</addressOffset>
          <size>0x20</size>
          <fields>
            <field>
              <name>FBOFF</name>
              <bitOffset>0</bitOffset>
              <bitWidth>5</bitWidth>
            </field>
            <field>
              <name>SLOTSZ</name>
              <bitOffset>6</bitOffset>
              <bitWidth>2</bitWidth>
            </field>
            <field>
              <name>NBSLOT</name>
              <bitOffset>8</bitOffset>
              <bitWidth>4</bitWidth>
            </field>
            <field>
              <name>SLOTEN</name>
              <bitOffset>16</bitOffset>
              <bitWidth>16</bitWidth>
            </field>
          </fields>
        </register>
        <register>
          <name>IMRB</name>
          <addressOffset>0x34</addressOffset>
          <size>0x20</size>
          <fields>
            <field>
              <name>OVRUDRIE</name>
              <bitOffset>0</bitOffset>
              <bitWidth>1</bitWidth>
            </field>
            <field>
              <name>MUTEDETIE</name>
              <bitOffset>1</bitOffset>
              <bitWidth>1</bitWidth>
            </field>
            <field>
              <name>WCKCFGIE</name>
              <bitOffset>2</bitOffset>
              <bitWidth>1</bitWidth>
            </field>
            <field>
              <name>FREQIE</name>
              <bitOffset>3</bitOffset>
              <bitWidth>1</bitWidth>
            </field>
            <field>
              <name>CNRDYIE</name>
              <bitOffset>4</bitOffset>
              <bitWidth>1</bitWidth>
            </field>
            <field>
              <name>AFSDETIE</name>
              <bitOffset>5</bitOffset>
              <bitWidth>1</bitWidth>
            </field>
            <field>
              <name>LFSDETIE</name>
              <bitOffset>6</bitOffset>
              <bitWidth>1</bitWidth>
            </field>
          </fields>
        </register>
        <register>
          <name>IMRB</name>
          <addressOffset>0x34</addressOffset>
          <size>0x20</size>
          <fields>
            <field>
              <name>OVRUDRIE</name>
              <bitOffset>0</bitOffset>
              <bitWidth>1</bitWidth>
            </field>
            <field>
              <name>MUTEDETIE</name>
              <bitOffset>1</bitOffset>
              <bitWidth>1</bitWidth>
            </field>
            <field>
              <name>WCKCFGIE</name>
              <bitOffset>2</bitOffset>
              <bitWidth>1</bitWidth>
            </field>
            <field>
              <name>FREQIE</name>
              <bitOffset>3</bitOffset>
              <bitWidth>1</bitWidth>
            </field>
            <field>
              <name>CNRDYIE</name>
              <bitOffset>4</bitOffset>
              <bitWidth>1</bitWidth>
            </field>
            <field>
              <name>AFSDETIE</name>
              <bitOffset>5</bitOffset>
              <bitWidth>1</bitWidth>
            </field>
            <field>
              <name>LFSDETIE</name>
              <bitOffset>6</bitOffset>
              <bitWidth>1</bitWidth>
            </field>
          </fields>
        </register>
        <register>
          <name>IMRB</name>
          <addressOffset>0x34</addressOffset>
          <size>0x20</size>
          <fields>
            <field>
              <name>OVRUDRIE</name>
              <bitOffset>0</bitOffset>
              <bitWidth>1</bitWidth>
            </field>
            <field>
              <name>MUTEDETIE</name>
              <bitOffset>1</bitOffset>
              <bitWidth>1</bitWidth>
            </field>
            <field>
              <name>WCKCFGIE</name>
              <bitOffset>2</bitOffset>
              <bitWidth>1</bitWidth>
            </field>
            <field>
              <name>FREQIE</name>
              <bitOffset>3</bitOffset>
              <bitWidth>1</bitWidth>
            </field>
            <field>
              <name>CNRDYIE</name>
              <bitOffset>4</bitOffset>
              <bitWidth>1</bitWidth>
            </field>
            <field>
              <name>AFSDETIE</name>
              <bitOffset>5</bitOffset>
              <bitWidth>1</bitWidth>
            </field>
            <field>
              <name>LFSDETIE</name>
              <bitOffset>6</bitOffset>
              <bitWidth>1</bitWidth>
            </field>
          </fields>
        </register>
        <register>
          <name>IMRB</name>
          <addressOffset>0x34</addressOffset>
          <size>0x20</size>
          <fields>
            <field>
              <name>OVRUDRIE</name>
              <bitOffset>0</bitOffset>
              <bitWidth>1</bitWidth>
            </field>
            <field>
              <name>MUTEDETIE</name>
              <bitOffset>1</bitOffset>
              <bitWidth>1</bitWidth>
            </field>
            <field>
              <name>WCKCFGIE</name>
              <bitOffset>2</bitOffset>
              <bitWidth>1</bitWidth>
            </field>
            <field>
              <name>FREQIE</name>
              <bitOffset>3</bitOffset>
              <bitWidth>1</bitWidth>
            </field>
            <field>
              <name>CNRDYIE</name>
              <bitOffset>4</bitOffset>
              <bitWidth>1</bitWidth>
            </field>
            <field>
              <name>AFSDETIE</name>
              <bitOffset>5</bitOffset>
              <bitWidth>1</bitWidth>
            </field>
            <field>
              <name>LFSDETIE</name>
              <bitOffset>6</bitOffset>
              <bitWidth>1</bitWidth>
            </field>
          </fields>
        </register>
        <register>
          <name>SRB</name>
          <addressOffset>0x38</addressOffset>
          <size>0x20</size>
          <fields>
            <field>
              <name>OVRUDR</name>
              <bitOffset>0</bitOffset>
              <bitWidth>1</bitWidth>
            </field>
            <field>
              <name>MUTEDET</name>
              <bitOffset>1</bitOffset>
              <bitWidth>1</bitWidth>
            </field>
            <field>
              <name>WCKCFG</name>
              <bitOffset>2</bitOffset>
              <bitWidth>1</bitWidth>
            </field>
            <field>
              <name>FREQ</name>
              <bitOffset>3</bitOffset>
              <bitWidth>1</bitWidth>
            </field>
            <field>
              <name>CNRDY</name>
              <bitOffset>4</bitOffset>
              <bitWidth>1</bitWidth>
            </field>
            <field>
              <name>AFSDET</name>
              <bitOffset>5</bitOffset>
              <bitWidth>1</bitWidth>
            </field>
            <field>
              <name>LFSDET</name>
              <bitOffset>6</bitOffset>
              <bitWidth>1</bitWidth>
            </field>
            <field>
              <name>FLVL</name>
              <bitOffset>16</bitOffset>
              <bitWidth>3</bitWidth>
            </field>
          </fields>
        </register>
        <register>
          <name>SRB</name>
          <addressOffset>0x38</addressOffset>
          <size>0x20</size>
          <fields>
            <field>
              <name>OVRUDR</name>
              <bitOffset>0</bitOffset>
              <bitWidth>1</bitWidth>
            </field>
            <field>
              <name>MUTEDET</name>
              <bitOffset>1</bitOffset>
              <bitWidth>1</bitWidth>
            </field>
            <field>
              <name>WCKCFG</name>
              <bitOffset>2</bitOffset>
              <bitWidth>1</bitWidth>
            </field>
            <field>
              <name>FREQ</name>
              <bitOffset>3</bitOffset>
              <bitWidth>1</bitWidth>
            </field>
            <field>
              <name>CNRDY</name>
              <bitOffset>4</bitOffset>
              <bitWidth>1</bitWidth>
            </field>
            <field>
              <name>AFSDET</name>
              <bitOffset>5</bitOffset>
              <bitWidth>1</bitWidth>
            </field>
            <field>
              <name>LFSDET</name>
              <bitOffset>6</bitOffset>
              <bitWidth>1</bitWidth>
            </field>
            <field>
              <name>FLVL</name>
              <bitOffset>16</bitOffset>
              <bitWidth>3</bitWidth>
            </field>
          </fields>
        </register>
        <register>
          <name>SRB</name>
          <addressOffset>0x38</addressOffset>
          <size>0x20</size>
          <fields>
            <field>
              <name>OVRUDR</name>
              <bitOffset>0</bitOffset>
              <bitWidth>1</bitWidth>
            </field>
            <field>
              <name>MUTEDET</name>
              <bitOffset>1</bitOffset>
              <bitWidth>1</bitWidth>
            </field>
            <field>
              <name>WCKCFG</name>
              <bitOffset>2</bitOffset>
              <bitWidth>1</bitWidth>
            </field>
            <field>
              <name>FREQ</name>
              <bitOffset>3</bitOffset>
              <bitWidth>1</bitWidth>
            </field>
            <field>
              <name>CNRDY</name>
              <bitOffset>4</bitOffset>
              <bitWidth>1</bitWidth>
            </field>
            <field>
              <name>AFSDET</name>
              <bitOffset>5</bitOffset>
              <bitWidth>1</bitWidth>
            </field>
            <field>
              <name>LFSDET</name>
              <bitOffset>6</bitOffset>
              <bitWidth>1</bitWidth>
            </field>
            <field>
              <name>FLVL</name>
              <bitOffset>16</bitOffset>
              <bitWidth>3</bitWidth>
            </field>
          </fields>
        </register>
        <register>
          <name>SRB</name>
          <addressOffset>0x38</addressOffset>
          <size>0x20</size>
          <fields>
            <field>
              <name>OVRUDR</name>
              <bitOffset>0</bitOffset>
              <bitWidth>1</bitWidth>
            </field>
            <field>
              <name>MUTEDET</name>
              <bitOffset>1</bitOffset>
              <bitWidth>1</bitWidth>
            </field>
            <field>
              <name>WCKCFG</name>
              <bitOffset>2</bitOffset>
              <bitWidth>1</bitWidth>
            </field>
            <field>
              <name>FREQ</name>
              <bitOffset>3</bitOffset>
              <bitWidth>1</bitWidth>
            </field>
            <field>
              <name>CNRDY</name>
              <bitOffset>4</bitOffset>
              <bitWidth>1</bitWidth>
            </field>
            <field>
              <name>AFSDET</name>
              <bitOffset>5</bitOffset>
              <bitWidth>1</bitWidth>
            </field>
            <field>
              <name>LFSDET</name>
              <bitOffset>6</bitOffset>
              <bitWidth>1</bitWidth>
            </field>
            <field>
              <name>FLVL</name>
              <bitOffset>16</bitOffset>
              <bitWidth>3</bitWidth>
            </field>
          </fields>
        </register>
        <register>
          <name>CLRFRB</name>
          <addressOffset>0x3c</addressOffset>
          <size>0x20</size>
          <fields>
            <field>
              <name>COVRUDR</name>
              <bitOffset>0</bitOffset>
              <bitWidth>1</bitWidth>
            </field>
            <field>
              <name>CMUTEDET</name>
              <bitOffset>1</bitOffset>
              <bitWidth>1</bitWidth>
            </field>
            <field>
              <name>CWCKCFG</name>
              <bitOffset>2</bitOffset>
              <bitWidth>1</bitWidth>
            </field>
            <field>
              <name>CFREQ</name>
              <bitOffset>3</bitOffset>
              <bitWidth>1</bitWidth>
            </field>
            <field>
              <name>CCNRDY</name>
              <bitOffset>4</bitOffset>
              <bitWidth>1</bitWidth>
            </field>
            <field>
              <name>CAFSDET</name>
              <bitOffset>5</bitOffset>
              <bitWidth>1</bitWidth>
            </field>
            <field>
              <name>CLFSDET</name>
              <bitOffset>6</bitOffset>
              <bitWidth>1</bitWidth>
            </field>
          </fields>
        </register>
        <register>
          <name>CLRFRB</name>
          <addressOffset>0x3c</addressOffset>
          <size>0x20</size>
          <fields>
            <field>
              <name>COVRUDR</name>
              <bitOffset>0</bitOffset>
              <bitWidth>1</bitWidth>
            </field>
            <field>
              <name>CMUTEDET</name>
              <bitOffset>1</bitOffset>
              <bitWidth>1</bitWidth>
            </field>
            <field>
              <name>CWCKCFG</name>
              <bitOffset>2</bitOffset>
              <bitWidth>1</bitWidth>
            </field>
            <field>
              <name>CFREQ</name>
              <bitOffset>3</bitOffset>
              <bitWidth>1</bitWidth>
            </field>
            <field>
              <name>CCNRDY</name>
              <bitOffset>4</bitOffset>
              <bitWidth>1</bitWidth>
            </field>
            <field>
              <name>CAFSDET</name>
              <bitOffset>5</bitOffset>
              <bitWidth>1</bitWidth>
            </field>
            <field>
              <name>CLFSDET</name>
              <bitOffset>6</bitOffset>
              <bitWidth>1</bitWidth>
            </field>
          </fields>
        </register>
        <register>
          <name>CLRFRB</name>
          <addressOffset>0x3c</addressOffset>
          <size>0x20</size>
          <fields>
            <field>
              <name>COVRUDR</name>
              <bitOffset>0</bitOffset>
              <bitWidth>1</bitWidth>
            </field>
            <field>
              <name>CMUTEDET</name>
              <bitOffset>1</bitOffset>
              <bitWidth>1</bitWidth>
            </field>
            <field>
              <name>CWCKCFG</name>
              <bitOffset>2</bitOffset>
              <bitWidth>1</bitWidth>
            </field>
            <field>
              <name>CFREQ</name>
              <bitOffset>3</bitOffset>
              <bitWidth>1</bitWidth>
            </field>
            <field>
              <name>CCNRDY</name>
              <bitOffset>4</bitOffset>
              <bitWidth>1</bitWidth>
            </field>
            <field>
              <name>CAFSDET</name>
              <bitOffset>5</bitOffset>
              <bitWidth>1</bitWidth>
            </field>
            <field>
              <name>CLFSDET</name>
              <bitOffset>6</bitOffset>
              <bitWidth>1</bitWidth>
            </field>
          </fields>
        </register>
        <register>
          <name>CLRFRB</name>
          <addressOffset>0x3c</addressOffset>
          <size>0x20</size>
          <fields>
            <field>
              <name>COVRUDR</name>
              <bitOffset>0</bitOffset>
              <bitWidth>1</bitWidth>
            </field>
            <field>
              <name>CMUTEDET</name>
              <bitOffset>1</bitOffset>
              <bitWidth>1</bitWidth>
            </field>
            <field>
              <name>CWCKCFG</name>
              <bitOffset>2</bitOffset>
              <bitWidth>1</bitWidth>
            </field>
            <field>
              <name>CFREQ</name>
              <bitOffset>3</bitOffset>
              <bitWidth>1</bitWidth>
            </field>
            <field>
              <name>CCNRDY</name>
              <bitOffset>4</bitOffset>
              <bitWidth>1</bitWidth>
            </field>
            <field>
              <name>CAFSDET</name>
              <bitOffset>5</bitOffset>
              <bitWidth>1</bitWidth>
            </field>
            <field>
              <name>CLFSDET</name>
              <bitOffset>6</bitOffset>
              <bitWidth>1</bitWidth>
            </field>
          </fields>
        </register>
        <register>
          <name>DRB</name>
          <addressOffset>0x40</addressOffset>
          <size>0x20</size>
          <fields>
            <field>
              <name>DATA</name>
              <bitOffset>0</bitOffset>
              <bitWidth>32</bitWidth>
            </field>
          </fields>
        </register>
        <register>
          <name>DRB</name>
          <addressOffset>0x40</addressOffset>
          <size>0x20</size>
          <fields>
            <field>
              <name>DATA</name>
              <bitOffset>0</bitOffset>
              <bitWidth>32</bitWidth>
            </field>
          </fields>
        </register>
        <register>
          <name>DRB</name>
          <addressOffset>0x40</addressOffset>
          <size>0x20</size>
          <fields>
            <field>
              <name>DATA</name>
              <bitOffset>0</bitOffset>
              <bitWidth>32</bitWidth>
            </field>
          </fields>
        </register>
        <register>
          <name>DRB</name>
          <addressOffset>0x40</addressOffset>
          <size>0x20</size>
          <fields>
            <field>
              <name>DATA</name>
              <bitOffset>0</bitOffset>
              <bitWidth>32</bitWidth>
            </field>
          </fields>
        </register>
        <register>
          <name>PDMCR</name>
          <addressOffset>0x44</addressOffset>
          <size>0x20</size>
          <fields>
            <field>
              <name>PDMEN</name>
              <bitOffset>0</bitOffset>
              <bitWidth>1</bitWidth>
            </field>
            <field>
              <name>MICNBR</name>
              <bitOffset>4</bitOffset>
              <bitWidth>2</bitWidth>
            </field>
            <field>
              <name>CKEN1</name>
              <bitOffset>8</bitOffset>
              <bitWidth>1</bitWidth>
            </field>
            <field>
              <name>CKEN2</name>
              <bitOffset>9</bitOffset>
              <bitWidth>1</bitWidth>
            </field>
            <field>
              <name>CKEN3</name>
              <bitOffset>10</bitOffset>
              <bitWidth>1</bitWidth>
            </field>
            <field>
              <name>CKEN4</name>
              <bitOffset>11</bitOffset>
              <bitWidth>1</bitWidth>
            </field>
          </fields>
        </register>
        <register>
          <name>PDMDLY</name>
          <addressOffset>0x48</addressOffset>
          <size>0x20</size>
          <fields>
            <field>
              <name>DLYM1L</name>
              <bitOffset>0</bitOffset>
              <bitWidth>3</bitWidth>
            </field>
            <field>
              <name>DLYM1R</name>
              <bitOffset>4</bitOffset>
              <bitWidth>3</bitWidth>
            </field>
            <field>
              <name>DLYM2L</name>
              <bitOffset>8</bitOffset>
              <bitWidth>3</bitWidth>
            </field>
            <field>
              <name>DLYM2R</name>
              <bitOffset>12</bitOffset>
              <bitWidth>3</bitWidth>
            </field>
            <field>
              <name>DLYM3L</name>
              <bitOffset>16</bitOffset>
              <bitWidth>3</bitWidth>
            </field>
            <field>
              <name>DLYM3R</name>
              <bitOffset>20</bitOffset>
              <bitWidth>3</bitWidth>
            </field>
            <field>
              <name>DLYM4L</name>
              <bitOffset>24</bitOffset>
              <bitWidth>3</bitWidth>
            </field>
            <field>
              <name>DLYM4R</name>
              <bitOffset>28</bitOffset>
              <bitWidth>3</bitWidth>
            </field>
          </fields>
        </register>
      </registers>
    </peripheral>
    <peripheral>
      <name>SAI2</name>
      <baseAddress>0x40015c00</baseAddress>
      <registers>
        <register>
          <name>GCR</name>
          <addressOffset>0x0</addressOffset>
          <size>0x20</size>
          <fields>
            <field>
              <name>SYNCIN</name>
              <bitOffset>0</bitOffset>
              <bitWidth>2</bitWidth>
            </field>
            <field>
              <name>SYNCOUT</name>
              <bitOffset>4</bitOffset>
              <bitWidth>2</bitWidth>
            </field>
          </fields>
        </register>
        <register>
          <name>CR1A</name>
          <addressOffset>0x4</addressOffset>
          <size>0x20</size>
          <fields>
            <field>
              <name>MODE</name>
              <bitOffset>0</bitOffset>
              <bitWidth>2</bitWidth>
            </field>
            <field>
              <name>PRTCFG</name>
              <bitOffset>2</bitOffset>
              <bitWidth>2</bitWidth>
            </field>
            <field>
              <name>DS</name>
              <bitOffset>5</bitOffset>
              <bitWidth>3</bitWidth>
            </field>
            <field>
              <name>LSBFIRST</name>
              <bitOffset>8</bitOffset>
              <bitWidth>1</bitWidth>
            </field>
            <field>
              <name>CKSTR</name>
              <bitOffset>9</bitOffset>
              <bitWidth>1</bitWidth>
            </field>
            <field>
              <name>SYNCEN</name>
              <bitOffset>10</bitOffset>
              <bitWidth>2</bitWidth>
            </field>
            <field>
              <name>MONO</name>
              <bitOffset>12</bitOffset>
              <bitWidth>1</bitWidth>
            </field>
            <field>
              <name>OUTDRIV</name>
              <bitOffset>13</bitOffset>
              <bitWidth>1</bitWidth>
            </field>
            <field>
              <name>SAIEN</name>
              <bitOffset>16</bitOffset>
              <bitWidth>1</bitWidth>
            </field>
            <field>
              <name>DMAEN</name>
              <bitOffset>17</bitOffset>
              <bitWidth>1</bitWidth>
            </field>
            <field>
              <name>NODIV</name>
              <bitOffset>19</bitOffset>
              <bitWidth>1</bitWidth>
            </field>
            <field>
              <name>MCKDIV</name>
              <bitOffset>20</bitOffset>
              <bitWidth>6</bitWidth>
            </field>
            <field>
              <name>OSR</name>
              <bitOffset>26</bitOffset>
              <bitWidth>1</bitWidth>
            </field>
            <field>
              <name>MCKEN</name>
              <bitOffset>27</bitOffset>
              <bitWidth>1</bitWidth>
            </field>
          </fields>
        </register>
        <register>
          <name>CR1A</name>
          <addressOffset>0x4</addressOffset>
          <size>0x20</size>
          <fields>
            <field>
              <name>MODE</name>
              <bitOffset>0</bitOffset>
              <bitWidth>2</bitWidth>
            </field>
            <field>
              <name>PRTCFG</name>
              <bitOffset>2</bitOffset>
              <bitWidth>2</bitWidth>
            </field>
            <field>
              <name>DS</name>
              <bitOffset>5</bitOffset>
              <bitWidth>3</bitWidth>
            </field>
            <field>
              <name>LSBFIRST</name>
              <bitOffset>8</bitOffset>
              <bitWidth>1</bitWidth>
            </field>
            <field>
              <name>CKSTR</name>
              <bitOffset>9</bitOffset>
              <bitWidth>1</bitWidth>
            </field>
            <field>
              <name>SYNCEN</name>
              <bitOffset>10</bitOffset>
              <bitWidth>2</bitWidth>
            </field>
            <field>
              <name>MONO</name>
              <bitOffset>12</bitOffset>
              <bitWidth>1</bitWidth>
            </field>
            <field>
              <name>OUTDRIV</name>
              <bitOffset>13</bitOffset>
              <bitWidth>1</bitWidth>
            </field>
            <field>
              <name>SAIEN</name>
              <bitOffset>16</bitOffset>
              <bitWidth>1</bitWidth>
            </field>
            <field>
              <name>DMAEN</name>
              <bitOffset>17</bitOffset>
              <bitWidth>1</bitWidth>
            </field>
            <field>
              <name>NODIV</name>
              <bitOffset>19</bitOffset>
              <bitWidth>1</bitWidth>
            </field>
            <field>
              <name>MCKDIV</name>
              <bitOffset>20</bitOffset>
              <bitWidth>6</bitWidth>
            </field>
            <field>
              <name>OSR</name>
              <bitOffset>26</bitOffset>
              <bitWidth>1</bitWidth>
            </field>
            <field>
              <name>MCKEN</name>
              <bitOffset>27</bitOffset>
              <bitWidth>1</bitWidth>
            </field>
          </fields>
        </register>
        <register>
          <name>CR1A</name>
          <addressOffset>0x4</addressOffset>
          <size>0x20</size>
          <fields>
            <field>
              <name>MODE</name>
              <bitOffset>0</bitOffset>
              <bitWidth>2</bitWidth>
            </field>
            <field>
              <name>PRTCFG</name>
              <bitOffset>2</bitOffset>
              <bitWidth>2</bitWidth>
            </field>
            <field>
              <name>DS</name>
              <bitOffset>5</bitOffset>
              <bitWidth>3</bitWidth>
            </field>
            <field>
              <name>LSBFIRST</name>
              <bitOffset>8</bitOffset>
              <bitWidth>1</bitWidth>
            </field>
            <field>
              <name>CKSTR</name>
              <bitOffset>9</bitOffset>
              <bitWidth>1</bitWidth>
            </field>
            <field>
              <name>SYNCEN</name>
              <bitOffset>10</bitOffset>
              <bitWidth>2</bitWidth>
            </field>
            <field>
              <name>MONO</name>
              <bitOffset>12</bitOffset>
              <bitWidth>1</bitWidth>
            </field>
            <field>
              <name>OUTDRIV</name>
              <bitOffset>13</bitOffset>
              <bitWidth>1</bitWidth>
            </field>
            <field>
              <name>SAIEN</name>
              <bitOffset>16</bitOffset>
              <bitWidth>1</bitWidth>
            </field>
            <field>
              <name>DMAEN</name>
              <bitOffset>17</bitOffset>
              <bitWidth>1</bitWidth>
            </field>
            <field>
              <name>NODIV</name>
              <bitOffset>19</bitOffset>
              <bitWidth>1</bitWidth>
            </field>
            <field>
              <name>MCKDIV</name>
              <bitOffset>20</bitOffset>
              <bitWidth>6</bitWidth>
            </field>
            <field>
              <name>OSR</name>
              <bitOffset>26</bitOffset>
              <bitWidth>1</bitWidth>
            </field>
            <field>
              <name>MCKEN</name>
              <bitOffset>27</bitOffset>
              <bitWidth>1</bitWidth>
            </field>
          </fields>
        </register>
        <register>
          <name>CR1A</name>
          <addressOffset>0x4</addressOffset>
          <size>0x20</size>
          <fields>
            <field>
              <name>MODE</name>
              <bitOffset>0</bitOffset>
              <bitWidth>2</bitWidth>
            </field>
            <field>
              <name>PRTCFG</name>
              <bitOffset>2</bitOffset>
              <bitWidth>2</bitWidth>
            </field>
            <field>
              <name>DS</name>
              <bitOffset>5</bitOffset>
              <bitWidth>3</bitWidth>
            </field>
            <field>
              <name>LSBFIRST</name>
              <bitOffset>8</bitOffset>
              <bitWidth>1</bitWidth>
            </field>
            <field>
              <name>CKSTR</name>
              <bitOffset>9</bitOffset>
              <bitWidth>1</bitWidth>
            </field>
            <field>
              <name>SYNCEN</name>
              <bitOffset>10</bitOffset>
              <bitWidth>2</bitWidth>
            </field>
            <field>
              <name>MONO</name>
              <bitOffset>12</bitOffset>
              <bitWidth>1</bitWidth>
            </field>
            <field>
              <name>OUTDRIV</name>
              <bitOffset>13</bitOffset>
              <bitWidth>1</bitWidth>
            </field>
            <field>
              <name>SAIEN</name>
              <bitOffset>16</bitOffset>
              <bitWidth>1</bitWidth>
            </field>
            <field>
              <name>DMAEN</name>
              <bitOffset>17</bitOffset>
              <bitWidth>1</bitWidth>
            </field>
            <field>
              <name>NODIV</name>
              <bitOffset>19</bitOffset>
              <bitWidth>1</bitWidth>
            </field>
            <field>
              <name>MCKDIV</name>
              <bitOffset>20</bitOffset>
              <bitWidth>6</bitWidth>
            </field>
            <field>
              <name>OSR</name>
              <bitOffset>26</bitOffset>
              <bitWidth>1</bitWidth>
            </field>
            <field>
              <name>MCKEN</name>
              <bitOffset>27</bitOffset>
              <bitWidth>1</bitWidth>
            </field>
          </fields>
        </register>
        <register>
          <name>CR2A</name>
          <addressOffset>0x8</addressOffset>
          <size>0x20</size>
          <fields>
            <field>
              <name>FTH</name>
              <bitOffset>0</bitOffset>
              <bitWidth>3</bitWidth>
            </field>
            <field>
              <name>FFLUSH</name>
              <bitOffset>3</bitOffset>
              <bitWidth>1</bitWidth>
            </field>
            <field>
              <name>TRIS</name>
              <bitOffset>4</bitOffset>
              <bitWidth>1</bitWidth>
            </field>
            <field>
              <name>MUTE</name>
              <bitOffset>5</bitOffset>
              <bitWidth>1</bitWidth>
            </field>
            <field>
              <name>MUTEVAL</name>
              <bitOffset>6</bitOffset>
              <bitWidth>1</bitWidth>
            </field>
            <field>
              <name>MUTECNT</name>
              <bitOffset>7</bitOffset>
              <bitWidth>6</bitWidth>
            </field>
            <field>
              <name>CPL</name>
              <bitOffset>13</bitOffset>
              <bitWidth>1</bitWidth>
            </field>
            <field>
              <name>COMP</name>
              <bitOffset>14</bitOffset>
              <bitWidth>2</bitWidth>
            </field>
          </fields>
        </register>
        <register>
          <name>CR2A</name>
          <addressOffset>0x8</addressOffset>
          <size>0x20</size>
          <fields>
            <field>
              <name>FTH</name>
              <bitOffset>0</bitOffset>
              <bitWidth>3</bitWidth>
            </field>
            <field>
              <name>FFLUSH</name>
              <bitOffset>3</bitOffset>
              <bitWidth>1</bitWidth>
            </field>
            <field>
              <name>TRIS</name>
              <bitOffset>4</bitOffset>
              <bitWidth>1</bitWidth>
            </field>
            <field>
              <name>MUTE</name>
              <bitOffset>5</bitOffset>
              <bitWidth>1</bitWidth>
            </field>
            <field>
              <name>MUTEVAL</name>
              <bitOffset>6</bitOffset>
              <bitWidth>1</bitWidth>
            </field>
            <field>
              <name>MUTECNT</name>
              <bitOffset>7</bitOffset>
              <bitWidth>6</bitWidth>
            </field>
            <field>
              <name>CPL</name>
              <bitOffset>13</bitOffset>
              <bitWidth>1</bitWidth>
            </field>
            <field>
              <name>COMP</name>
              <bitOffset>14</bitOffset>
              <bitWidth>2</bitWidth>
            </field>
          </fields>
        </register>
        <register>
          <name>CR2A</name>
          <addressOffset>0x8</addressOffset>
          <size>0x20</size>
          <fields>
            <field>
              <name>FTH</name>
              <bitOffset>0</bitOffset>
              <bitWidth>3</bitWidth>
            </field>
            <field>
              <name>FFLUSH</name>
              <bitOffset>3</bitOffset>
              <bitWidth>1</bitWidth>
            </field>
            <field>
              <name>TRIS</name>
              <bitOffset>4</bitOffset>
              <bitWidth>1</bitWidth>
            </field>
            <field>
              <name>MUTE</name>
              <bitOffset>5</bitOffset>
              <bitWidth>1</bitWidth>
            </field>
            <field>
              <name>MUTEVAL</name>
              <bitOffset>6</bitOffset>
              <bitWidth>1</bitWidth>
            </field>
            <field>
              <name>MUTECNT</name>
              <bitOffset>7</bitOffset>
              <bitWidth>6</bitWidth>
            </field>
            <field>
              <name>CPL</name>
              <bitOffset>13</bitOffset>
              <bitWidth>1</bitWidth>
            </field>
            <field>
              <name>COMP</name>
              <bitOffset>14</bitOffset>
              <bitWidth>2</bitWidth>
            </field>
          </fields>
        </register>
        <register>
          <name>CR2A</name>
          <addressOffset>0x8</addressOffset>
          <size>0x20</size>
          <fields>
            <field>
              <name>FTH</name>
              <bitOffset>0</bitOffset>
              <bitWidth>3</bitWidth>
            </field>
            <field>
              <name>FFLUSH</name>
              <bitOffset>3</bitOffset>
              <bitWidth>1</bitWidth>
            </field>
            <field>
              <name>TRIS</name>
              <bitOffset>4</bitOffset>
              <bitWidth>1</bitWidth>
            </field>
            <field>
              <name>MUTE</name>
              <bitOffset>5</bitOffset>
              <bitWidth>1</bitWidth>
            </field>
            <field>
              <name>MUTEVAL</name>
              <bitOffset>6</bitOffset>
              <bitWidth>1</bitWidth>
            </field>
            <field>
              <name>MUTECNT</name>
              <bitOffset>7</bitOffset>
              <bitWidth>6</bitWidth>
            </field>
            <field>
              <name>CPL</name>
              <bitOffset>13</bitOffset>
              <bitWidth>1</bitWidth>
            </field>
            <field>
              <name>COMP</name>
              <bitOffset>14</bitOffset>
              <bitWidth>2</bitWidth>
            </field>
          </fields>
        </register>
        <register>
          <name>FRCRA</name>
          <addressOffset>0xc</addressOffset>
          <size>0x20</size>
          <fields>
            <field>
              <name>FRL</name>
              <bitOffset>0</bitOffset>
              <bitWidth>8</bitWidth>
            </field>
            <field>
              <name>FSALL</name>
              <bitOffset>8</bitOffset>
              <bitWidth>7</bitWidth>
            </field>
            <field>
              <name>FSDEF</name>
              <bitOffset>16</bitOffset>
              <bitWidth>1</bitWidth>
            </field>
            <field>
              <name>FSPOL</name>
              <bitOffset>17</bitOffset>
              <bitWidth>1</bitWidth>
            </field>
            <field>
              <name>FSOFF</name>
              <bitOffset>18</bitOffset>
              <bitWidth>1</bitWidth>
            </field>
          </fields>
        </register>
        <register>
          <name>FRCRA</name>
          <addressOffset>0xc</addressOffset>
          <size>0x20</size>
          <fields>
            <field>
              <name>FRL</name>
              <bitOffset>0</bitOffset>
              <bitWidth>8</bitWidth>
            </field>
            <field>
              <name>FSALL</name>
              <bitOffset>8</bitOffset>
              <bitWidth>7</bitWidth>
            </field>
            <field>
              <name>FSDEF</name>
              <bitOffset>16</bitOffset>
              <bitWidth>1</bitWidth>
            </field>
            <field>
              <name>FSPOL</name>
              <bitOffset>17</bitOffset>
              <bitWidth>1</bitWidth>
            </field>
            <field>
              <name>FSOFF</name>
              <bitOffset>18</bitOffset>
              <bitWidth>1</bitWidth>
            </field>
          </fields>
        </register>
        <register>
          <name>FRCRA</name>
          <addressOffset>0xc</addressOffset>
          <size>0x20</size>
          <fields>
            <field>
              <name>FRL</name>
              <bitOffset>0</bitOffset>
              <bitWidth>8</bitWidth>
            </field>
            <field>
              <name>FSALL</name>
              <bitOffset>8</bitOffset>
              <bitWidth>7</bitWidth>
            </field>
            <field>
              <name>FSDEF</name>
              <bitOffset>16</bitOffset>
              <bitWidth>1</bitWidth>
            </field>
            <field>
              <name>FSPOL</name>
              <bitOffset>17</bitOffset>
              <bitWidth>1</bitWidth>
            </field>
            <field>
              <name>FSOFF</name>
              <bitOffset>18</bitOffset>
              <bitWidth>1</bitWidth>
            </field>
          </fields>
        </register>
        <register>
          <name>FRCRA</name>
          <addressOffset>0xc</addressOffset>
          <size>0x20</size>
          <fields>
            <field>
              <name>FRL</name>
              <bitOffset>0</bitOffset>
              <bitWidth>8</bitWidth>
            </field>
            <field>
              <name>FSALL</name>
              <bitOffset>8</bitOffset>
              <bitWidth>7</bitWidth>
            </field>
            <field>
              <name>FSDEF</name>
              <bitOffset>16</bitOffset>
              <bitWidth>1</bitWidth>
            </field>
            <field>
              <name>FSPOL</name>
              <bitOffset>17</bitOffset>
              <bitWidth>1</bitWidth>
            </field>
            <field>
              <name>FSOFF</name>
              <bitOffset>18</bitOffset>
              <bitWidth>1</bitWidth>
            </field>
          </fields>
        </register>
        <register>
          <name>SLOTRA</name>
          <addressOffset>0x10</addressOffset>
          <size>0x20</size>
          <fields>
            <field>
              <name>FBOFF</name>
              <bitOffset>0</bitOffset>
              <bitWidth>5</bitWidth>
            </field>
            <field>
              <name>SLOTSZ</name>
              <bitOffset>6</bitOffset>
              <bitWidth>2</bitWidth>
            </field>
            <field>
              <name>NBSLOT</name>
              <bitOffset>8</bitOffset>
              <bitWidth>4</bitWidth>
            </field>
            <field>
              <name>SLOTEN</name>
              <bitOffset>16</bitOffset>
              <bitWidth>16</bitWidth>
            </field>
          </fields>
        </register>
        <register>
          <name>SLOTRA</name>
          <addressOffset>0x10</addressOffset>
          <size>0x20</size>
          <fields>
            <field>
              <name>FBOFF</name>
              <bitOffset>0</bitOffset>
              <bitWidth>5</bitWidth>
            </field>
            <field>
              <name>SLOTSZ</name>
              <bitOffset>6</bitOffset>
              <bitWidth>2</bitWidth>
            </field>
            <field>
              <name>NBSLOT</name>
              <bitOffset>8</bitOffset>
              <bitWidth>4</bitWidth>
            </field>
            <field>
              <name>SLOTEN</name>
              <bitOffset>16</bitOffset>
              <bitWidth>16</bitWidth>
            </field>
          </fields>
        </register>
        <register>
          <name>SLOTRA</name>
          <addressOffset>0x10</addressOffset>
          <size>0x20</size>
          <fields>
            <field>
              <name>FBOFF</name>
              <bitOffset>0</bitOffset>
              <bitWidth>5</bitWidth>
            </field>
            <field>
              <name>SLOTSZ</name>
              <bitOffset>6</bitOffset>
              <bitWidth>2</bitWidth>
            </field>
            <field>
              <name>NBSLOT</name>
              <bitOffset>8</bitOffset>
              <bitWidth>4</bitWidth>
            </field>
            <field>
              <name>SLOTEN</name>
              <bitOffset>16</bitOffset>
              <bitWidth>16</bitWidth>
            </field>
          </fields>
        </register>
        <register>
          <name>SLOTRA</name>
          <addressOffset>0x10</addressOffset>
          <size>0x20</size>
          <fields>
            <field>
              <name>FBOFF</name>
              <bitOffset>0</bitOffset>
              <bitWidth>5</bitWidth>
            </field>
            <field>
              <name>SLOTSZ</name>
              <bitOffset>6</bitOffset>
              <bitWidth>2</bitWidth>
            </field>
            <field>
              <name>NBSLOT</name>
              <bitOffset>8</bitOffset>
              <bitWidth>4</bitWidth>
            </field>
            <field>
              <name>SLOTEN</name>
              <bitOffset>16</bitOffset>
              <bitWidth>16</bitWidth>
            </field>
          </fields>
        </register>
        <register>
          <name>IMRA</name>
          <addressOffset>0x14</addressOffset>
          <size>0x20</size>
          <fields>
            <field>
              <name>OVRUDRIE</name>
              <bitOffset>0</bitOffset>
              <bitWidth>1</bitWidth>
            </field>
            <field>
              <name>MUTEDETIE</name>
              <bitOffset>1</bitOffset>
              <bitWidth>1</bitWidth>
            </field>
            <field>
              <name>WCKCFGIE</name>
              <bitOffset>2</bitOffset>
              <bitWidth>1</bitWidth>
            </field>
            <field>
              <name>FREQIE</name>
              <bitOffset>3</bitOffset>
              <bitWidth>1</bitWidth>
            </field>
            <field>
              <name>CNRDYIE</name>
              <bitOffset>4</bitOffset>
              <bitWidth>1</bitWidth>
            </field>
            <field>
              <name>AFSDETIE</name>
              <bitOffset>5</bitOffset>
              <bitWidth>1</bitWidth>
            </field>
            <field>
              <name>LFSDETIE</name>
              <bitOffset>6</bitOffset>
              <bitWidth>1</bitWidth>
            </field>
          </fields>
        </register>
        <register>
          <name>IMRA</name>
          <addressOffset>0x14</addressOffset>
          <size>0x20</size>
          <fields>
            <field>
              <name>OVRUDRIE</name>
              <bitOffset>0</bitOffset>
              <bitWidth>1</bitWidth>
            </field>
            <field>
              <name>MUTEDETIE</name>
              <bitOffset>1</bitOffset>
              <bitWidth>1</bitWidth>
            </field>
            <field>
              <name>WCKCFGIE</name>
              <bitOffset>2</bitOffset>
              <bitWidth>1</bitWidth>
            </field>
            <field>
              <name>FREQIE</name>
              <bitOffset>3</bitOffset>
              <bitWidth>1</bitWidth>
            </field>
            <field>
              <name>CNRDYIE</name>
              <bitOffset>4</bitOffset>
              <bitWidth>1</bitWidth>
            </field>
            <field>
              <name>AFSDETIE</name>
              <bitOffset>5</bitOffset>
              <bitWidth>1</bitWidth>
            </field>
            <field>
              <name>LFSDETIE</name>
              <bitOffset>6</bitOffset>
              <bitWidth>1</bitWidth>
            </field>
          </fields>
        </register>
        <register>
          <name>IMRA</name>
          <addressOffset>0x14</addressOffset>
          <size>0x20</size>
          <fields>
            <field>
              <name>OVRUDRIE</name>
              <bitOffset>0</bitOffset>
              <bitWidth>1</bitWidth>
            </field>
            <field>
              <name>MUTEDETIE</name>
              <bitOffset>1</bitOffset>
              <bitWidth>1</bitWidth>
            </field>
            <field>
              <name>WCKCFGIE</name>
              <bitOffset>2</bitOffset>
              <bitWidth>1</bitWidth>
            </field>
            <field>
              <name>FREQIE</name>
              <bitOffset>3</bitOffset>
              <bitWidth>1</bitWidth>
            </field>
            <field>
              <name>CNRDYIE</name>
              <bitOffset>4</bitOffset>
              <bitWidth>1</bitWidth>
            </field>
            <field>
              <name>AFSDETIE</name>
              <bitOffset>5</bitOffset>
              <bitWidth>1</bitWidth>
            </field>
            <field>
              <name>LFSDETIE</name>
              <bitOffset>6</bitOffset>
              <bitWidth>1</bitWidth>
            </field>
          </fields>
        </register>
        <register>
          <name>IMRA</name>
          <addressOffset>0x14</addressOffset>
          <size>0x20</size>
          <fields>
            <field>
              <name>OVRUDRIE</name>
              <bitOffset>0</bitOffset>
              <bitWidth>1</bitWidth>
            </field>
            <field>
              <name>MUTEDETIE</name>
              <bitOffset>1</bitOffset>
              <bitWidth>1</bitWidth>
            </field>
            <field>
              <name>WCKCFGIE</name>
              <bitOffset>2</bitOffset>
              <bitWidth>1</bitWidth>
            </field>
            <field>
              <name>FREQIE</name>
              <bitOffset>3</bitOffset>
              <bitWidth>1</bitWidth>
            </field>
            <field>
              <name>CNRDYIE</name>
              <bitOffset>4</bitOffset>
              <bitWidth>1</bitWidth>
            </field>
            <field>
              <name>AFSDETIE</name>
              <bitOffset>5</bitOffset>
              <bitWidth>1</bitWidth>
            </field>
            <field>
              <name>LFSDETIE</name>
              <bitOffset>6</bitOffset>
              <bitWidth>1</bitWidth>
            </field>
          </fields>
        </register>
        <register>
          <name>SRA</name>
          <addressOffset>0x18</addressOffset>
          <size>0x20</size>
          <fields>
            <field>
              <name>OVRUDR</name>
              <bitOffset>0</bitOffset>
              <bitWidth>1</bitWidth>
            </field>
            <field>
              <name>MUTEDET</name>
              <bitOffset>1</bitOffset>
              <bitWidth>1</bitWidth>
            </field>
            <field>
              <name>WCKCFG</name>
              <bitOffset>2</bitOffset>
              <bitWidth>1</bitWidth>
            </field>
            <field>
              <name>FREQ</name>
              <bitOffset>3</bitOffset>
              <bitWidth>1</bitWidth>
            </field>
            <field>
              <name>CNRDY</name>
              <bitOffset>4</bitOffset>
              <bitWidth>1</bitWidth>
            </field>
            <field>
              <name>AFSDET</name>
              <bitOffset>5</bitOffset>
              <bitWidth>1</bitWidth>
            </field>
            <field>
              <name>LFSDET</name>
              <bitOffset>6</bitOffset>
              <bitWidth>1</bitWidth>
            </field>
            <field>
              <name>FLVL</name>
              <bitOffset>16</bitOffset>
              <bitWidth>3</bitWidth>
            </field>
          </fields>
        </register>
        <register>
          <name>SRA</name>
          <addressOffset>0x18</addressOffset>
          <size>0x20</size>
          <fields>
            <field>
              <name>OVRUDR</name>
              <bitOffset>0</bitOffset>
              <bitWidth>1</bitWidth>
            </field>
            <field>
              <name>MUTEDET</name>
              <bitOffset>1</bitOffset>
              <bitWidth>1</bitWidth>
            </field>
            <field>
              <name>WCKCFG</name>
              <bitOffset>2</bitOffset>
              <bitWidth>1</bitWidth>
            </field>
            <field>
              <name>FREQ</name>
              <bitOffset>3</bitOffset>
              <bitWidth>1</bitWidth>
            </field>
            <field>
              <name>CNRDY</name>
              <bitOffset>4</bitOffset>
              <bitWidth>1</bitWidth>
            </field>
            <field>
              <name>AFSDET</name>
              <bitOffset>5</bitOffset>
              <bitWidth>1</bitWidth>
            </field>
            <field>
              <name>LFSDET</name>
              <bitOffset>6</bitOffset>
              <bitWidth>1</bitWidth>
            </field>
            <field>
              <name>FLVL</name>
              <bitOffset>16</bitOffset>
              <bitWidth>3</bitWidth>
            </field>
          </fields>
        </register>
        <register>
          <name>SRA</name>
          <addressOffset>0x18</addressOffset>
          <size>0x20</size>
          <fields>
            <field>
              <name>OVRUDR</name>
              <bitOffset>0</bitOffset>
              <bitWidth>1</bitWidth>
            </field>
            <field>
              <name>MUTEDET</name>
              <bitOffset>1</bitOffset>
              <bitWidth>1</bitWidth>
            </field>
            <field>
              <name>WCKCFG</name>
              <bitOffset>2</bitOffset>
              <bitWidth>1</bitWidth>
            </field>
            <field>
              <name>FREQ</name>
              <bitOffset>3</bitOffset>
              <bitWidth>1</bitWidth>
            </field>
            <field>
              <name>CNRDY</name>
              <bitOffset>4</bitOffset>
              <bitWidth>1</bitWidth>
            </field>
            <field>
              <name>AFSDET</name>
              <bitOffset>5</bitOffset>
              <bitWidth>1</bitWidth>
            </field>
            <field>
              <name>LFSDET</name>
              <bitOffset>6</bitOffset>
              <bitWidth>1</bitWidth>
            </field>
            <field>
              <name>FLVL</name>
              <bitOffset>16</bitOffset>
              <bitWidth>3</bitWidth>
            </field>
          </fields>
        </register>
        <register>
          <name>SRA</name>
          <addressOffset>0x18</addressOffset>
          <size>0x20</size>
          <fields>
            <field>
              <name>OVRUDR</name>
              <bitOffset>0</bitOffset>
              <bitWidth>1</bitWidth>
            </field>
            <field>
              <name>MUTEDET</name>
              <bitOffset>1</bitOffset>
              <bitWidth>1</bitWidth>
            </field>
            <field>
              <name>WCKCFG</name>
              <bitOffset>2</bitOffset>
              <bitWidth>1</bitWidth>
            </field>
            <field>
              <name>FREQ</name>
              <bitOffset>3</bitOffset>
              <bitWidth>1</bitWidth>
            </field>
            <field>
              <name>CNRDY</name>
              <bitOffset>4</bitOffset>
              <bitWidth>1</bitWidth>
            </field>
            <field>
              <name>AFSDET</name>
              <bitOffset>5</bitOffset>
              <bitWidth>1</bitWidth>
            </field>
            <field>
              <name>LFSDET</name>
              <bitOffset>6</bitOffset>
              <bitWidth>1</bitWidth>
            </field>
            <field>
              <name>FLVL</name>
              <bitOffset>16</bitOffset>
              <bitWidth>3</bitWidth>
            </field>
          </fields>
        </register>
        <register>
          <name>CLRFRA</name>
          <addressOffset>0x1c</addressOffset>
          <size>0x20</size>
          <fields>
            <field>
              <name>COVRUDR</name>
              <bitOffset>0</bitOffset>
              <bitWidth>1</bitWidth>
            </field>
            <field>
              <name>CMUTEDET</name>
              <bitOffset>1</bitOffset>
              <bitWidth>1</bitWidth>
            </field>
            <field>
              <name>CWCKCFG</name>
              <bitOffset>2</bitOffset>
              <bitWidth>1</bitWidth>
            </field>
            <field>
              <name>CFREQ</name>
              <bitOffset>3</bitOffset>
              <bitWidth>1</bitWidth>
            </field>
            <field>
              <name>CCNRDY</name>
              <bitOffset>4</bitOffset>
              <bitWidth>1</bitWidth>
            </field>
            <field>
              <name>CAFSDET</name>
              <bitOffset>5</bitOffset>
              <bitWidth>1</bitWidth>
            </field>
            <field>
              <name>CLFSDET</name>
              <bitOffset>6</bitOffset>
              <bitWidth>1</bitWidth>
            </field>
          </fields>
        </register>
        <register>
          <name>CLRFRA</name>
          <addressOffset>0x1c</addressOffset>
          <size>0x20</size>
          <fields>
            <field>
              <name>COVRUDR</name>
              <bitOffset>0</bitOffset>
              <bitWidth>1</bitWidth>
            </field>
            <field>
              <name>CMUTEDET</name>
              <bitOffset>1</bitOffset>
              <bitWidth>1</bitWidth>
            </field>
            <field>
              <name>CWCKCFG</name>
              <bitOffset>2</bitOffset>
              <bitWidth>1</bitWidth>
            </field>
            <field>
              <name>CFREQ</name>
              <bitOffset>3</bitOffset>
              <bitWidth>1</bitWidth>
            </field>
            <field>
              <name>CCNRDY</name>
              <bitOffset>4</bitOffset>
              <bitWidth>1</bitWidth>
            </field>
            <field>
              <name>CAFSDET</name>
              <bitOffset>5</bitOffset>
              <bitWidth>1</bitWidth>
            </field>
            <field>
              <name>CLFSDET</name>
              <bitOffset>6</bitOffset>
              <bitWidth>1</bitWidth>
            </field>
          </fields>
        </register>
        <register>
          <name>CLRFRA</name>
          <addressOffset>0x1c</addressOffset>
          <size>0x20</size>
          <fields>
            <field>
              <name>COVRUDR</name>
              <bitOffset>0</bitOffset>
              <bitWidth>1</bitWidth>
            </field>
            <field>
              <name>CMUTEDET</name>
              <bitOffset>1</bitOffset>
              <bitWidth>1</bitWidth>
            </field>
            <field>
              <name>CWCKCFG</name>
              <bitOffset>2</bitOffset>
              <bitWidth>1</bitWidth>
            </field>
            <field>
              <name>CFREQ</name>
              <bitOffset>3</bitOffset>
              <bitWidth>1</bitWidth>
            </field>
            <field>
              <name>CCNRDY</name>
              <bitOffset>4</bitOffset>
              <bitWidth>1</bitWidth>
            </field>
            <field>
              <name>CAFSDET</name>
              <bitOffset>5</bitOffset>
              <bitWidth>1</bitWidth>
            </field>
            <field>
              <name>CLFSDET</name>
              <bitOffset>6</bitOffset>
              <bitWidth>1</bitWidth>
            </field>
          </fields>
        </register>
        <register>
          <name>CLRFRA</name>
          <addressOffset>0x1c</addressOffset>
          <size>0x20</size>
          <fields>
            <field>
              <name>COVRUDR</name>
              <bitOffset>0</bitOffset>
              <bitWidth>1</bitWidth>
            </field>
            <field>
              <name>CMUTEDET</name>
              <bitOffset>1</bitOffset>
              <bitWidth>1</bitWidth>
            </field>
            <field>
              <name>CWCKCFG</name>
              <bitOffset>2</bitOffset>
              <bitWidth>1</bitWidth>
            </field>
            <field>
              <name>CFREQ</name>
              <bitOffset>3</bitOffset>
              <bitWidth>1</bitWidth>
            </field>
            <field>
              <name>CCNRDY</name>
              <bitOffset>4</bitOffset>
              <bitWidth>1</bitWidth>
            </field>
            <field>
              <name>CAFSDET</name>
              <bitOffset>5</bitOffset>
              <bitWidth>1</bitWidth>
            </field>
            <field>
              <name>CLFSDET</name>
              <bitOffset>6</bitOffset>
              <bitWidth>1</bitWidth>
            </field>
          </fields>
        </register>
        <register>
          <name>DRA</name>
          <addressOffset>0x20</addressOffset>
          <size>0x20</size>
          <fields>
            <field>
              <name>DATA</name>
              <bitOffset>0</bitOffset>
              <bitWidth>32</bitWidth>
            </field>
          </fields>
        </register>
        <register>
          <name>DRA</name>
          <addressOffset>0x20</addressOffset>
          <size>0x20</size>
          <fields>
            <field>
              <name>DATA</name>
              <bitOffset>0</bitOffset>
              <bitWidth>32</bitWidth>
            </field>
          </fields>
        </register>
        <register>
          <name>DRA</name>
          <addressOffset>0x20</addressOffset>
          <size>0x20</size>
          <fields>
            <field>
              <name>DATA</name>
              <bitOffset>0</bitOffset>
              <bitWidth>32</bitWidth>
            </field>
          </fields>
        </register>
        <register>
          <name>DRA</name>
          <addressOffset>0x20</addressOffset>
          <size>0x20</size>
          <fields>
            <field>
              <name>DATA</name>
              <bitOffset>0</bitOffset>
              <bitWidth>32</bitWidth>
            </field>
          </fields>
        </register>
        <register>
          <name>CR1B</name>
          <addressOffset>0x24</addressOffset>
          <size>0x20</size>
          <fields>
            <field>
              <name>MODE</name>
              <bitOffset>0</bitOffset>
              <bitWidth>2</bitWidth>
            </field>
            <field>
              <name>PRTCFG</name>
              <bitOffset>2</bitOffset>
              <bitWidth>2</bitWidth>
            </field>
            <field>
              <name>DS</name>
              <bitOffset>5</bitOffset>
              <bitWidth>3</bitWidth>
            </field>
            <field>
              <name>LSBFIRST</name>
              <bitOffset>8</bitOffset>
              <bitWidth>1</bitWidth>
            </field>
            <field>
              <name>CKSTR</name>
              <bitOffset>9</bitOffset>
              <bitWidth>1</bitWidth>
            </field>
            <field>
              <name>SYNCEN</name>
              <bitOffset>10</bitOffset>
              <bitWidth>2</bitWidth>
            </field>
            <field>
              <name>MONO</name>
              <bitOffset>12</bitOffset>
              <bitWidth>1</bitWidth>
            </field>
            <field>
              <name>OUTDRIV</name>
              <bitOffset>13</bitOffset>
              <bitWidth>1</bitWidth>
            </field>
            <field>
              <name>SAIEN</name>
              <bitOffset>16</bitOffset>
              <bitWidth>1</bitWidth>
            </field>
            <field>
              <name>DMAEN</name>
              <bitOffset>17</bitOffset>
              <bitWidth>1</bitWidth>
            </field>
            <field>
              <name>NODIV</name>
              <bitOffset>19</bitOffset>
              <bitWidth>1</bitWidth>
            </field>
            <field>
              <name>MCKDIV</name>
              <bitOffset>20</bitOffset>
              <bitWidth>6</bitWidth>
            </field>
            <field>
              <name>OSR</name>
              <bitOffset>26</bitOffset>
              <bitWidth>1</bitWidth>
            </field>
            <field>
              <name>MCKEN</name>
              <bitOffset>27</bitOffset>
              <bitWidth>1</bitWidth>
            </field>
          </fields>
        </register>
        <register>
          <name>CR1B</name>
          <addressOffset>0x24</addressOffset>
          <size>0x20</size>
          <fields>
            <field>
              <name>MODE</name>
              <bitOffset>0</bitOffset>
              <bitWidth>2</bitWidth>
            </field>
            <field>
              <name>PRTCFG</name>
              <bitOffset>2</bitOffset>
              <bitWidth>2</bitWidth>
            </field>
            <field>
              <name>DS</name>
              <bitOffset>5</bitOffset>
              <bitWidth>3</bitWidth>
            </field>
            <field>
              <name>LSBFIRST</name>
              <bitOffset>8</bitOffset>
              <bitWidth>1</bitWidth>
            </field>
            <field>
              <name>CKSTR</name>
              <bitOffset>9</bitOffset>
              <bitWidth>1</bitWidth>
            </field>
            <field>
              <name>SYNCEN</name>
              <bitOffset>10</bitOffset>
              <bitWidth>2</bitWidth>
            </field>
            <field>
              <name>MONO</name>
              <bitOffset>12</bitOffset>
              <bitWidth>1</bitWidth>
            </field>
            <field>
              <name>OUTDRIV</name>
              <bitOffset>13</bitOffset>
              <bitWidth>1</bitWidth>
            </field>
            <field>
              <name>SAIEN</name>
              <bitOffset>16</bitOffset>
              <bitWidth>1</bitWidth>
            </field>
            <field>
              <name>DMAEN</name>
              <bitOffset>17</bitOffset>
              <bitWidth>1</bitWidth>
            </field>
            <field>
              <name>NODIV</name>
              <bitOffset>19</bitOffset>
              <bitWidth>1</bitWidth>
            </field>
            <field>
              <name>MCKDIV</name>
              <bitOffset>20</bitOffset>
              <bitWidth>6</bitWidth>
            </field>
            <field>
              <name>OSR</name>
              <bitOffset>26</bitOffset>
              <bitWidth>1</bitWidth>
            </field>
            <field>
              <name>MCKEN</name>
              <bitOffset>27</bitOffset>
              <bitWidth>1</bitWidth>
            </field>
          </fields>
        </register>
        <register>
          <name>CR1B</name>
          <addressOffset>0x24</addressOffset>
          <size>0x20</size>
          <fields>
            <field>
              <name>MODE</name>
              <bitOffset>0</bitOffset>
              <bitWidth>2</bitWidth>
            </field>
            <field>
              <name>PRTCFG</name>
              <bitOffset>2</bitOffset>
              <bitWidth>2</bitWidth>
            </field>
            <field>
              <name>DS</name>
              <bitOffset>5</bitOffset>
              <bitWidth>3</bitWidth>
            </field>
            <field>
              <name>LSBFIRST</name>
              <bitOffset>8</bitOffset>
              <bitWidth>1</bitWidth>
            </field>
            <field>
              <name>CKSTR</name>
              <bitOffset>9</bitOffset>
              <bitWidth>1</bitWidth>
            </field>
            <field>
              <name>SYNCEN</name>
              <bitOffset>10</bitOffset>
              <bitWidth>2</bitWidth>
            </field>
            <field>
              <name>MONO</name>
              <bitOffset>12</bitOffset>
              <bitWidth>1</bitWidth>
            </field>
            <field>
              <name>OUTDRIV</name>
              <bitOffset>13</bitOffset>
              <bitWidth>1</bitWidth>
            </field>
            <field>
              <name>SAIEN</name>
              <bitOffset>16</bitOffset>
              <bitWidth>1</bitWidth>
            </field>
            <field>
              <name>DMAEN</name>
              <bitOffset>17</bitOffset>
              <bitWidth>1</bitWidth>
            </field>
            <field>
              <name>NODIV</name>
              <bitOffset>19</bitOffset>
              <bitWidth>1</bitWidth>
            </field>
            <field>
              <name>MCKDIV</name>
              <bitOffset>20</bitOffset>
              <bitWidth>6</bitWidth>
            </field>
            <field>
              <name>OSR</name>
              <bitOffset>26</bitOffset>
              <bitWidth>1</bitWidth>
            </field>
            <field>
              <name>MCKEN</name>
              <bitOffset>27</bitOffset>
              <bitWidth>1</bitWidth>
            </field>
          </fields>
        </register>
        <register>
          <name>CR1B</name>
          <addressOffset>0x24</addressOffset>
          <size>0x20</size>
          <fields>
            <field>
              <name>MODE</name>
              <bitOffset>0</bitOffset>
              <bitWidth>2</bitWidth>
            </field>
            <field>
              <name>PRTCFG</name>
              <bitOffset>2</bitOffset>
              <bitWidth>2</bitWidth>
            </field>
            <field>
              <name>DS</name>
              <bitOffset>5</bitOffset>
              <bitWidth>3</bitWidth>
            </field>
            <field>
              <name>LSBFIRST</name>
              <bitOffset>8</bitOffset>
              <bitWidth>1</bitWidth>
            </field>
            <field>
              <name>CKSTR</name>
              <bitOffset>9</bitOffset>
              <bitWidth>1</bitWidth>
            </field>
            <field>
              <name>SYNCEN</name>
              <bitOffset>10</bitOffset>
              <bitWidth>2</bitWidth>
            </field>
            <field>
              <name>MONO</name>
              <bitOffset>12</bitOffset>
              <bitWidth>1</bitWidth>
            </field>
            <field>
              <name>OUTDRIV</name>
              <bitOffset>13</bitOffset>
              <bitWidth>1</bitWidth>
            </field>
            <field>
              <name>SAIEN</name>
              <bitOffset>16</bitOffset>
              <bitWidth>1</bitWidth>
            </field>
            <field>
              <name>DMAEN</name>
              <bitOffset>17</bitOffset>
              <bitWidth>1</bitWidth>
            </field>
            <field>
              <name>NODIV</name>
              <bitOffset>19</bitOffset>
              <bitWidth>1</bitWidth>
            </field>
            <field>
              <name>MCKDIV</name>
              <bitOffset>20</bitOffset>
              <bitWidth>6</bitWidth>
            </field>
            <field>
              <name>OSR</name>
              <bitOffset>26</bitOffset>
              <bitWidth>1</bitWidth>
            </field>
            <field>
              <name>MCKEN</name>
              <bitOffset>27</bitOffset>
              <bitWidth>1</bitWidth>
            </field>
          </fields>
        </register>
        <register>
          <name>CR2B</name>
          <addressOffset>0x28</addressOffset>
          <size>0x20</size>
          <fields>
            <field>
              <name>FTH</name>
              <bitOffset>0</bitOffset>
              <bitWidth>3</bitWidth>
            </field>
            <field>
              <name>FFLUSH</name>
              <bitOffset>3</bitOffset>
              <bitWidth>1</bitWidth>
            </field>
            <field>
              <name>TRIS</name>
              <bitOffset>4</bitOffset>
              <bitWidth>1</bitWidth>
            </field>
            <field>
              <name>MUTE</name>
              <bitOffset>5</bitOffset>
              <bitWidth>1</bitWidth>
            </field>
            <field>
              <name>MUTEVAL</name>
              <bitOffset>6</bitOffset>
              <bitWidth>1</bitWidth>
            </field>
            <field>
              <name>MUTECNT</name>
              <bitOffset>7</bitOffset>
              <bitWidth>6</bitWidth>
            </field>
            <field>
              <name>CPL</name>
              <bitOffset>13</bitOffset>
              <bitWidth>1</bitWidth>
            </field>
            <field>
              <name>COMP</name>
              <bitOffset>14</bitOffset>
              <bitWidth>2</bitWidth>
            </field>
          </fields>
        </register>
        <register>
          <name>CR2B</name>
          <addressOffset>0x28</addressOffset>
          <size>0x20</size>
          <fields>
            <field>
              <name>FTH</name>
              <bitOffset>0</bitOffset>
              <bitWidth>3</bitWidth>
            </field>
            <field>
              <name>FFLUSH</name>
              <bitOffset>3</bitOffset>
              <bitWidth>1</bitWidth>
            </field>
            <field>
              <name>TRIS</name>
              <bitOffset>4</bitOffset>
              <bitWidth>1</bitWidth>
            </field>
            <field>
              <name>MUTE</name>
              <bitOffset>5</bitOffset>
              <bitWidth>1</bitWidth>
            </field>
            <field>
              <name>MUTEVAL</name>
              <bitOffset>6</bitOffset>
              <bitWidth>1</bitWidth>
            </field>
            <field>
              <name>MUTECNT</name>
              <bitOffset>7</bitOffset>
              <bitWidth>6</bitWidth>
            </field>
            <field>
              <name>CPL</name>
              <bitOffset>13</bitOffset>
              <bitWidth>1</bitWidth>
            </field>
            <field>
              <name>COMP</name>
              <bitOffset>14</bitOffset>
              <bitWidth>2</bitWidth>
            </field>
          </fields>
        </register>
        <register>
          <name>CR2B</name>
          <addressOffset>0x28</addressOffset>
          <size>0x20</size>
          <fields>
            <field>
              <name>FTH</name>
              <bitOffset>0</bitOffset>
              <bitWidth>3</bitWidth>
            </field>
            <field>
              <name>FFLUSH</name>
              <bitOffset>3</bitOffset>
              <bitWidth>1</bitWidth>
            </field>
            <field>
              <name>TRIS</name>
              <bitOffset>4</bitOffset>
              <bitWidth>1</bitWidth>
            </field>
            <field>
              <name>MUTE</name>
              <bitOffset>5</bitOffset>
              <bitWidth>1</bitWidth>
            </field>
            <field>
              <name>MUTEVAL</name>
              <bitOffset>6</bitOffset>
              <bitWidth>1</bitWidth>
            </field>
            <field>
              <name>MUTECNT</name>
              <bitOffset>7</bitOffset>
              <bitWidth>6</bitWidth>
            </field>
            <field>
              <name>CPL</name>
              <bitOffset>13</bitOffset>
              <bitWidth>1</bitWidth>
            </field>
            <field>
              <name>COMP</name>
              <bitOffset>14</bitOffset>
              <bitWidth>2</bitWidth>
            </field>
          </fields>
        </register>
        <register>
          <name>CR2B</name>
          <addressOffset>0x28</addressOffset>
          <size>0x20</size>
          <fields>
            <field>
              <name>FTH</name>
              <bitOffset>0</bitOffset>
              <bitWidth>3</bitWidth>
            </field>
            <field>
              <name>FFLUSH</name>
              <bitOffset>3</bitOffset>
              <bitWidth>1</bitWidth>
            </field>
            <field>
              <name>TRIS</name>
              <bitOffset>4</bitOffset>
              <bitWidth>1</bitWidth>
            </field>
            <field>
              <name>MUTE</name>
              <bitOffset>5</bitOffset>
              <bitWidth>1</bitWidth>
            </field>
            <field>
              <name>MUTEVAL</name>
              <bitOffset>6</bitOffset>
              <bitWidth>1</bitWidth>
            </field>
            <field>
              <name>MUTECNT</name>
              <bitOffset>7</bitOffset>
              <bitWidth>6</bitWidth>
            </field>
            <field>
              <name>CPL</name>
              <bitOffset>13</bitOffset>
              <bitWidth>1</bitWidth>
            </field>
            <field>
              <name>COMP</name>
              <bitOffset>14</bitOffset>
              <bitWidth>2</bitWidth>
            </field>
          </fields>
        </register>
        <register>
          <name>FRCRB</name>
          <addressOffset>0x2c</addressOffset>
          <size>0x20</size>
          <fields>
            <field>
              <name>FRL</name>
              <bitOffset>0</bitOffset>
              <bitWidth>8</bitWidth>
            </field>
            <field>
              <name>FSALL</name>
              <bitOffset>8</bitOffset>
              <bitWidth>7</bitWidth>
            </field>
            <field>
              <name>FSDEF</name>
              <bitOffset>16</bitOffset>
              <bitWidth>1</bitWidth>
            </field>
            <field>
              <name>FSPOL</name>
              <bitOffset>17</bitOffset>
              <bitWidth>1</bitWidth>
            </field>
            <field>
              <name>FSOFF</name>
              <bitOffset>18</bitOffset>
              <bitWidth>1</bitWidth>
            </field>
          </fields>
        </register>
        <register>
          <name>FRCRB</name>
          <addressOffset>0x2c</addressOffset>
          <size>0x20</size>
          <fields>
            <field>
              <name>FRL</name>
              <bitOffset>0</bitOffset>
              <bitWidth>8</bitWidth>
            </field>
            <field>
              <name>FSALL</name>
              <bitOffset>8</bitOffset>
              <bitWidth>7</bitWidth>
            </field>
            <field>
              <name>FSDEF</name>
              <bitOffset>16</bitOffset>
              <bitWidth>1</bitWidth>
            </field>
            <field>
              <name>FSPOL</name>
              <bitOffset>17</bitOffset>
              <bitWidth>1</bitWidth>
            </field>
            <field>
              <name>FSOFF</name>
              <bitOffset>18</bitOffset>
              <bitWidth>1</bitWidth>
            </field>
          </fields>
        </register>
        <register>
          <name>FRCRB</name>
          <addressOffset>0x2c</addressOffset>
          <size>0x20</size>
          <fields>
            <field>
              <name>FRL</name>
              <bitOffset>0</bitOffset>
              <bitWidth>8</bitWidth>
            </field>
            <field>
              <name>FSALL</name>
              <bitOffset>8</bitOffset>
              <bitWidth>7</bitWidth>
            </field>
            <field>
              <name>FSDEF</name>
              <bitOffset>16</bitOffset>
              <bitWidth>1</bitWidth>
            </field>
            <field>
              <name>FSPOL</name>
              <bitOffset>17</bitOffset>
              <bitWidth>1</bitWidth>
            </field>
            <field>
              <name>FSOFF</name>
              <bitOffset>18</bitOffset>
              <bitWidth>1</bitWidth>
            </field>
          </fields>
        </register>
        <register>
          <name>FRCRB</name>
          <addressOffset>0x2c</addressOffset>
          <size>0x20</size>
          <fields>
            <field>
              <name>FRL</name>
              <bitOffset>0</bitOffset>
              <bitWidth>8</bitWidth>
            </field>
            <field>
              <name>FSALL</name>
              <bitOffset>8</bitOffset>
              <bitWidth>7</bitWidth>
            </field>
            <field>
              <name>FSDEF</name>
              <bitOffset>16</bitOffset>
              <bitWidth>1</bitWidth>
            </field>
            <field>
              <name>FSPOL</name>
              <bitOffset>17</bitOffset>
              <bitWidth>1</bitWidth>
            </field>
            <field>
              <name>FSOFF</name>
              <bitOffset>18</bitOffset>
              <bitWidth>1</bitWidth>
            </field>
          </fields>
        </register>
        <register>
          <name>SLOTRB</name>
          <addressOffset>0x30</addressOffset>
          <size>0x20</size>
          <fields>
            <field>
              <name>FBOFF</name>
              <bitOffset>0</bitOffset>
              <bitWidth>5</bitWidth>
            </field>
            <field>
              <name>SLOTSZ</name>
              <bitOffset>6</bitOffset>
              <bitWidth>2</bitWidth>
            </field>
            <field>
              <name>NBSLOT</name>
              <bitOffset>8</bitOffset>
              <bitWidth>4</bitWidth>
            </field>
            <field>
              <name>SLOTEN</name>
              <bitOffset>16</bitOffset>
              <bitWidth>16</bitWidth>
            </field>
          </fields>
        </register>
        <register>
          <name>SLOTRB</name>
          <addressOffset>0x30</addressOffset>
          <size>0x20</size>
          <fields>
            <field>
              <name>FBOFF</name>
              <bitOffset>0</bitOffset>
              <bitWidth>5</bitWidth>
            </field>
            <field>
              <name>SLOTSZ</name>
              <bitOffset>6</bitOffset>
              <bitWidth>2</bitWidth>
            </field>
            <field>
              <name>NBSLOT</name>
              <bitOffset>8</bitOffset>
              <bitWidth>4</bitWidth>
            </field>
            <field>
              <name>SLOTEN</name>
              <bitOffset>16</bitOffset>
              <bitWidth>16</bitWidth>
            </field>
          </fields>
        </register>
        <register>
          <name>SLOTRB</name>
          <addressOffset>0x30</addressOffset>
          <size>0x20</size>
          <fields>
            <field>
              <name>FBOFF</name>
              <bitOffset>0</bitOffset>
              <bitWidth>5</bitWidth>
            </field>
            <field>
              <name>SLOTSZ</name>
              <bitOffset>6</bitOffset>
              <bitWidth>2</bitWidth>
            </field>
            <field>
              <name>NBSLOT</name>
              <bitOffset>8</bitOffset>
              <bitWidth>4</bitWidth>
            </field>
            <field>
              <name>SLOTEN</name>
              <bitOffset>16</bitOffset>
              <bitWidth>16</bitWidth>
            </field>
          </fields>
        </register>
        <register>
          <name>SLOTRB</name>
          <addressOffset>0x30</addressOffset>
          <size>0x20</size>
          <fields>
            <field>
              <name>FBOFF</name>
              <bitOffset>0</bitOffset>
              <bitWidth>5</bitWidth>
            </field>
            <field>
              <name>SLOTSZ</name>
              <bitOffset>6</bitOffset>
              <bitWidth>2</bitWidth>
            </field>
            <field>
              <name>NBSLOT</name>
              <bitOffset>8</bitOffset>
              <bitWidth>4</bitWidth>
            </field>
            <field>
              <name>SLOTEN</name>
              <bitOffset>16</bitOffset>
              <bitWidth>16</bitWidth>
            </field>
          </fields>
        </register>
        <register>
          <name>IMRB</name>
          <addressOffset>0x34</addressOffset>
          <size>0x20</size>
          <fields>
            <field>
              <name>OVRUDRIE</name>
              <bitOffset>0</bitOffset>
              <bitWidth>1</bitWidth>
            </field>
            <field>
              <name>MUTEDETIE</name>
              <bitOffset>1</bitOffset>
              <bitWidth>1</bitWidth>
            </field>
            <field>
              <name>WCKCFGIE</name>
              <bitOffset>2</bitOffset>
              <bitWidth>1</bitWidth>
            </field>
            <field>
              <name>FREQIE</name>
              <bitOffset>3</bitOffset>
              <bitWidth>1</bitWidth>
            </field>
            <field>
              <name>CNRDYIE</name>
              <bitOffset>4</bitOffset>
              <bitWidth>1</bitWidth>
            </field>
            <field>
              <name>AFSDETIE</name>
              <bitOffset>5</bitOffset>
              <bitWidth>1</bitWidth>
            </field>
            <field>
              <name>LFSDETIE</name>
              <bitOffset>6</bitOffset>
              <bitWidth>1</bitWidth>
            </field>
          </fields>
        </register>
        <register>
          <name>IMRB</name>
          <addressOffset>0x34</addressOffset>
          <size>0x20</size>
          <fields>
            <field>
              <name>OVRUDRIE</name>
              <bitOffset>0</bitOffset>
              <bitWidth>1</bitWidth>
            </field>
            <field>
              <name>MUTEDETIE</name>
              <bitOffset>1</bitOffset>
              <bitWidth>1</bitWidth>
            </field>
            <field>
              <name>WCKCFGIE</name>
              <bitOffset>2</bitOffset>
              <bitWidth>1</bitWidth>
            </field>
            <field>
              <name>FREQIE</name>
              <bitOffset>3</bitOffset>
              <bitWidth>1</bitWidth>
            </field>
            <field>
              <name>CNRDYIE</name>
              <bitOffset>4</bitOffset>
              <bitWidth>1</bitWidth>
            </field>
            <field>
              <name>AFSDETIE</name>
              <bitOffset>5</bitOffset>
              <bitWidth>1</bitWidth>
            </field>
            <field>
              <name>LFSDETIE</name>
              <bitOffset>6</bitOffset>
              <bitWidth>1</bitWidth>
            </field>
          </fields>
        </register>
        <register>
          <name>IMRB</name>
          <addressOffset>0x34</addressOffset>
          <size>0x20</size>
          <fields>
            <field>
              <name>OVRUDRIE</name>
              <bitOffset>0</bitOffset>
              <bitWidth>1</bitWidth>
            </field>
            <field>
              <name>MUTEDETIE</name>
              <bitOffset>1</bitOffset>
              <bitWidth>1</bitWidth>
            </field>
            <field>
              <name>WCKCFGIE</name>
              <bitOffset>2</bitOffset>
              <bitWidth>1</bitWidth>
            </field>
            <field>
              <name>FREQIE</name>
              <bitOffset>3</bitOffset>
              <bitWidth>1</bitWidth>
            </field>
            <field>
              <name>CNRDYIE</name>
              <bitOffset>4</bitOffset>
              <bitWidth>1</bitWidth>
            </field>
            <field>
              <name>AFSDETIE</name>
              <bitOffset>5</bitOffset>
              <bitWidth>1</bitWidth>
            </field>
            <field>
              <name>LFSDETIE</name>
              <bitOffset>6</bitOffset>
              <bitWidth>1</bitWidth>
            </field>
          </fields>
        </register>
        <register>
          <name>IMRB</name>
          <addressOffset>0x34</addressOffset>
          <size>0x20</size>
          <fields>
            <field>
              <name>OVRUDRIE</name>
              <bitOffset>0</bitOffset>
              <bitWidth>1</bitWidth>
            </field>
            <field>
              <name>MUTEDETIE</name>
              <bitOffset>1</bitOffset>
              <bitWidth>1</bitWidth>
            </field>
            <field>
              <name>WCKCFGIE</name>
              <bitOffset>2</bitOffset>
              <bitWidth>1</bitWidth>
            </field>
            <field>
              <name>FREQIE</name>
              <bitOffset>3</bitOffset>
              <bitWidth>1</bitWidth>
            </field>
            <field>
              <name>CNRDYIE</name>
              <bitOffset>4</bitOffset>
              <bitWidth>1</bitWidth>
            </field>
            <field>
              <name>AFSDETIE</name>
              <bitOffset>5</bitOffset>
              <bitWidth>1</bitWidth>
            </field>
            <field>
              <name>LFSDETIE</name>
              <bitOffset>6</bitOffset>
              <bitWidth>1</bitWidth>
            </field>
          </fields>
        </register>
        <register>
          <name>SRB</name>
          <addressOffset>0x38</addressOffset>
          <size>0x20</size>
          <fields>
            <field>
              <name>OVRUDR</name>
              <bitOffset>0</bitOffset>
              <bitWidth>1</bitWidth>
            </field>
            <field>
              <name>MUTEDET</name>
              <bitOffset>1</bitOffset>
              <bitWidth>1</bitWidth>
            </field>
            <field>
              <name>WCKCFG</name>
              <bitOffset>2</bitOffset>
              <bitWidth>1</bitWidth>
            </field>
            <field>
              <name>FREQ</name>
              <bitOffset>3</bitOffset>
              <bitWidth>1</bitWidth>
            </field>
            <field>
              <name>DAMDF</name>
              <bitOffset>14</bitOffset>
              <bitWidth>2</bitWidth>
            </field>
            <field>
              <name>CKMODE</name>
              <bitOffset>16</bitOffset>
              <bitWidth>2</bitWidth>
            </field>
            <field>
              <name>PRESC</name>
              <bitOffset>18</bitOffset>
              <bitWidth>4</bitWidth>
            </field>
            <field>
              <name>VREFEN</name>
              <bitOffset>22</bitOffset>
              <bitWidth>1</bitWidth>
            </field>
            <field>
              <name>TSEN</name>
              <bitOffset>23</bitOffset>
              <bitWidth>1</bitWidth>
            </field>
            <field>
              <name>VBATEN</name>
              <bitOffset>24</bitOffset>
              <bitWidth>1</bitWidth>
            </field>
          </fields>
        </register>
        <register>
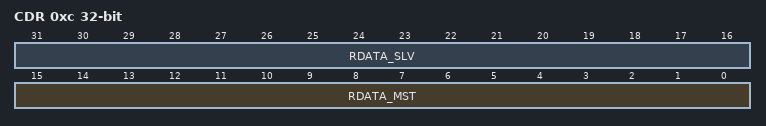
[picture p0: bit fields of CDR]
          <name>CDR</name>
          <addressOffset>0xc</addressOffset>
          <size>0x20</size>
          <fields>
            <field>
              <name>RDATA_MST</name>
              <bitOffset>0</bitOffset>
              <bitWidth>16</bitWidth>
            </field>
            <field>
              <name>RDATA_SLV</name>
              <bitOffset>16</bitOffset>
              <bitWidth>16</bitWidth>
            </field>
          </fields>
        </register>
        <register>
          <name>CDR2</name>
          <addressOffset>0x10</addressOffset>
          <size>0x20</size>
          <fields>
            <field>
              <name>RDATA_ALT</name>
              <bitOffset>0</bitOffset>
              <bitWidth>32</bitWidth>
            </field>
          </fields>
        </register>
      </registers>
    </peripheral>
    <peripheral>
      <name>HSEM</name>
      <baseAddress>0x58026400</baseAddress>
      <registers>
        <register>
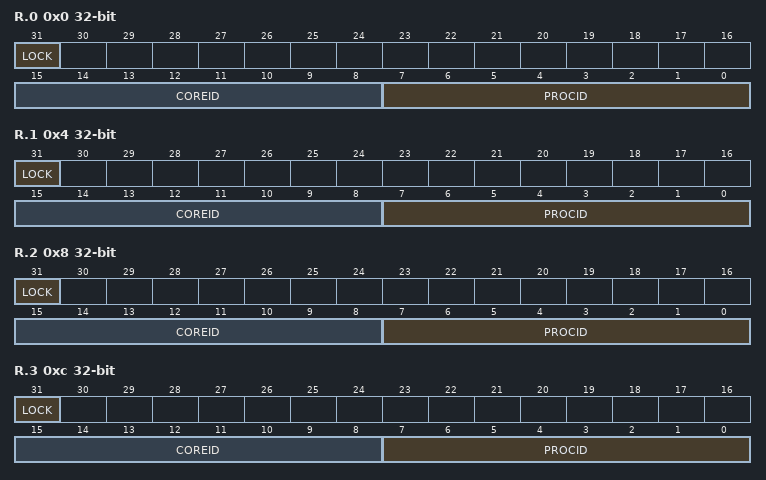
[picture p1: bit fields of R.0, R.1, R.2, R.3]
          <name>R.0</name>
          <addressOffset>0x0</addressOffset>
          <size>0x20</size>
          <fields>
            <field>
              <name>PROCID</name>
              <bitOffset>0</bitOffset>
              <bitWidth>8</bitWidth>
            </field>
            <field>
              <name>COREID</name>
              <bitOffset>8</bitOffset>
              <bitWidth>8</bitWidth>
            </field>
            <field>
              <name>LOCK</name>
              <bitOffset>31</bitOffset>
              <bitWidth>1</bitWidth>
            </field>
          </fields>
        </register>
        <register>
          <name>R.1</name>
          <addressOffset>0x4</addressOffset>
          <size>0x20</size>
          <fields>
            <field>
              <name>PROCID</name>
              <bitOffset>0</bitOffset>
              <bitWidth>8</bitWidth>
            </field>
            <field>
              <name>COREID</name>
              <bitOffset>8</bitOffset>
              <bitWidth>8</bitWidth>
            </field>
            <field>
              <name>LOCK</name>
              <bitOffset>31</bitOffset>
              <bitWidth>1</bitWidth>
            </field>
          </fields>
        </register>
        <register>
          <name>R.2</name>
          <addressOffset>0x8</addressOffset>
          <size>0x20</size>
          <fields>
            <field>
              <name>PROCID</name>
              <bitOffset>0</bitOffset>
              <bitWidth>8</bitWidth>
            </field>
            <field>
              <name>COREID</name>
              <bitOffset>8</bitOffset>
              <bitWidth>8</bitWidth>
            </field>
            <field>
              <name>LOCK</name>
              <bitOffset>31</bitOffset>
              <bitWidth>1</bitWidth>
            </field>
          </fields>
        </register>
        <register>
          <name>R.3</name>
          <addressOffset>0xc</addressOffset>
          <size>0x20</size>
          <fields>
            <field>
              <name>PROCID</name>
              <bitOffset>0</bitOffset>
              <bitWidth>8</bitWidth>
            </field>
            <field>
              <name>COREID</name>
              <bitOffset>8</bitOffset>
              <bitWidth>8</bitWidth>
            </field>
            <field>
              <name>LOCK</name>
              <bitOffset>31</bitOffset>
              <bitWidth>1</bitWidth>
            </field>
          </fields>
        </register>
        <register>
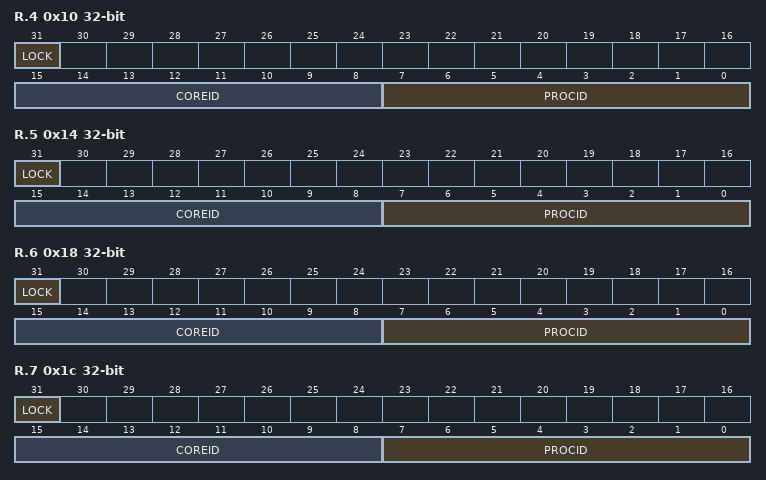
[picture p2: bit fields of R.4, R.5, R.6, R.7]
          <name>R.4</name>
          <addressOffset>0x10</addressOffset>
          <size>0x20</size>
          <fields>
            <field>
              <name>PROCID</name>
              <bitOffset>0</bitOffset>
              <bitWidth>8</bitWidth>
            </field>
            <field>
              <name>COREID</name>
              <bitOffset>8</bitOffset>
              <bitWidth>8</bitWidth>
            </field>
            <field>
              <name>LOCK</name>
              <bitOffset>31</bitOffset>
              <bitWidth>1</bitWidth>
            </field>
          </fields>
        </register>
        <register>
          <name>R.5</name>
          <addressOffset>0x14</addressOffset>
          <size>0x20</size>
          <fields>
            <field>
              <name>PROCID</name>
              <bitOffset>0</bitOffset>
              <bitWidth>8</bitWidth>
            </field>
            <field>
              <name>COREID</name>
              <bitOffset>8</bitOffset>
              <bitWidth>8</bitWidth>
            </field>
            <field>
              <name>LOCK</name>
              <bitOffset>31</bitOffset>
              <bitWidth>1</bitWidth>
            </field>
          </fields>
        </register>
        <register>
          <name>R.6</name>
          <addressOffset>0x18</addressOffset>
          <size>0x20</size>
          <fields>
            <field>
              <name>PROCID</name>
              <bitOffset>0</bitOffset>
              <bitWidth>8</bitWidth>
            </field>
            <field>
              <name>COREID</name>
              <bitOffset>8</bitOffset>
              <bitWidth>8</bitWidth>
            </field>
            <field>
              <name>LOCK</name>
              <bitOffset>31</bitOffset>
              <bitWidth>1</bitWidth>
            </field>
          </fields>
        </register>
        <register>
          <name>R.7</name>
          <addressOffset>0x1c</addressOffset>
          <size>0x20</size>
          <fields>
            <field>
              <name>PROCID</name>
              <bitOffset>0</bitOffset>
              <bitWidth>8</bitWidth>
            </field>
            <field>
              <name>COREID</name>
              <bitOffset>8</bitOffset>
              <bitWidth>8</bitWidth>
            </field>
            <field>
              <name>LOCK</name>
              <bitOffset>31</bitOffset>
              <bitWidth>1</bitWidth>
            </field>
          </fields>
        </register>
        <register>
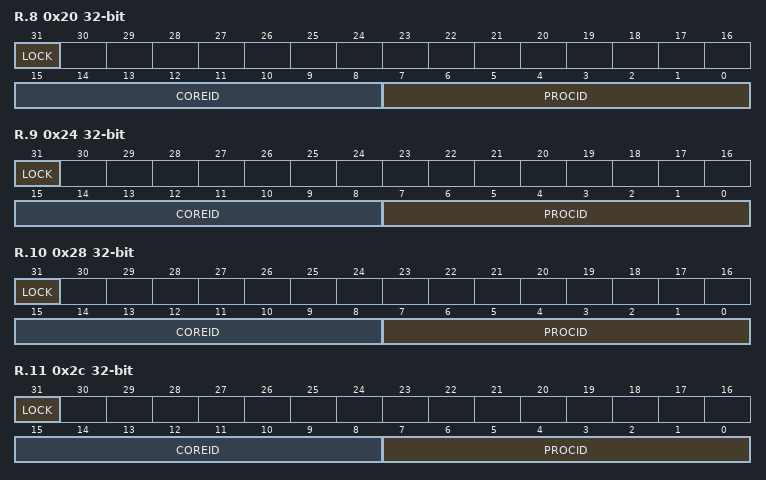
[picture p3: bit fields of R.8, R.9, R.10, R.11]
          <name>R.8</name>
          <addressOffset>0x20</addressOffset>
          <size>0x20</size>
          <fields>
            <field>
              <name>PROCID</name>
              <bitOffset>0</bitOffset>
              <bitWidth>8</bitWidth>
            </field>
            <field>
              <name>COREID</name>
              <bitOffset>8</bitOffset>
              <bitWidth>8</bitWidth>
            </field>
            <field>
              <name>LOCK</name>
              <bitOffset>31</bitOffset>
              <bitWidth>1</bitWidth>
            </field>
          </fields>
        </register>
        <register>
          <name>R.9</name>
          <addressOffset>0x24</addressOffset>
          <size>0x20</size>
          <fields>
            <field>
              <name>PROCID</name>
              <bitOffset>0</bitOffset>
              <bitWidth>8</bitWidth>
            </field>
            <field>
              <name>COREID</name>
              <bitOffset>8</bitOffset>
              <bitWidth>8</bitWidth>
            </field>
            <field>
              <name>LOCK</name>
              <bitOffset>31</bitOffset>
              <bitWidth>1</bitWidth>
            </field>
          </fields>
        </register>
        <register>
          <name>R.10</name>
          <addressOffset>0x28</addressOffset>
          <size>0x20</size>
          <fields>
            <field>
              <name>PROCID</name>
              <bitOffset>0</bitOffset>
              <bitWidth>8</bitWidth>
            </field>
            <field>
              <name>COREID</name>
              <bitOffset>8</bitOffset>
              <bitWidth>8</bitWidth>
            </field>
            <field>
              <name>LOCK</name>
              <bitOffset>31</bitOffset>
              <bitWidth>1</bitWidth>
            </field>
          </fields>
        </register>
        <register>
          <name>R.11</name>
          <addressOffset>0x2c</addressOffset>
          <size>0x20</size>
          <fields>
            <field>
              <name>PROCID</name>
              <bitOffset>0</bitOffset>
              <bitWidth>8</bitWidth>
            </field>
            <field>
              <name>COREID</name>
              <bitOffset>8</bitOffset>
              <bitWidth>8</bitWidth>
            </field>
            <field>
              <name>LOCK</name>
              <bitOffset>31</bitOffset>
              <bitWidth>1</bitWidth>
            </field>
          </fields>
        </register>
        <register>
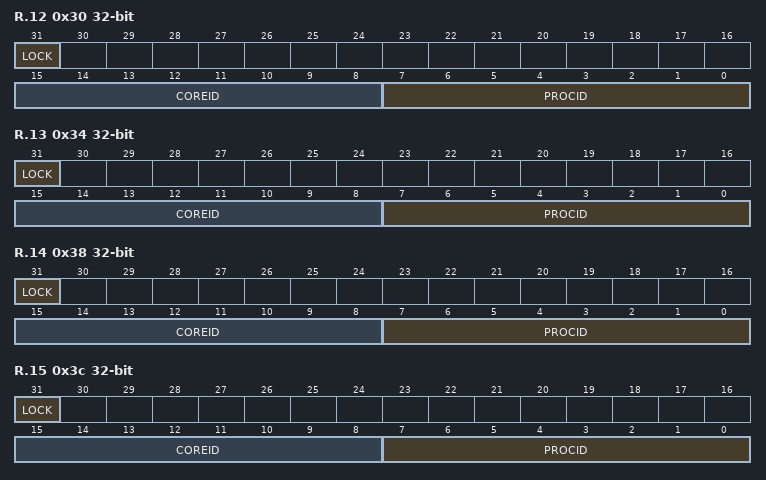
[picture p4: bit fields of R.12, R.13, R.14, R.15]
          <name>R.12</name>
          <addressOffset>0x30</addressOffset>
          <size>0x20</size>
          <fields>
            <field>
              <name>PROCID</name>
              <bitOffset>0</bitOffset>
              <bitWidth>8</bitWidth>
            </field>
            <field>
              <name>COREID</name>
              <bitOffset>8</bitOffset>
              <bitWidth>8</bitWidth>
            </field>
            <field>
              <name>LOCK</name>
              <bitOffset>31</bitOffset>
              <bitWidth>1</bitWidth>
            </field>
          </fields>
        </register>
        <register>
          <name>R.13</name>
          <addressOffset>0x34</addressOffset>
          <size>0x20</size>
          <fields>
            <field>
              <name>PROCID</name>
              <bitOffset>0</bitOffset>
              <bitWidth>8</bitWidth>
            </field>
            <field>
              <name>COREID</name>
              <bitOffset>8</bitOffset>
              <bitWidth>8</bitWidth>
            </field>
            <field>
              <name>LOCK</name>
              <bitOffset>31</bitOffset>
              <bitWidth>1</bitWidth>
            </field>
          </fields>
        </register>
        <register>
          <name>R.14</name>
          <addressOffset>0x38</addressOffset>
          <size>0x20</size>
          <fields>
            <field>
              <name>PROCID</name>
              <bitOffset>0</bitOffset>
              <bitWidth>8</bitWidth>
            </field>
            <field>
              <name>COREID</name>
              <bitOffset>8</bitOffset>
              <bitWidth>8</bitWidth>
            </field>
            <field>
              <name>LOCK</name>
              <bitOffset>31</bitOffset>
              <bitWidth>1</bitWidth>
            </field>
          </fields>
        </register>
        <register>
          <name>R.15</name>
          <addressOffset>0x3c</addressOffset>
          <size>0x20</size>
          <fields>
            <field>
              <name>PROCID</name>
              <bitOffset>0</bitOffset>
              <bitWidth>8</bitWidth>
            </field>
            <field>
              <name>COREID</name>
              <bitOffset>8</bitOffset>
              <bitWidth>8</bitWidth>
            </field>
            <field>
              <name>LOCK</name>
              <bitOffset>31</bitOffset>
              <bitWidth>1</bitWidth>
            </field>
          </fields>
        </register>
        <register>
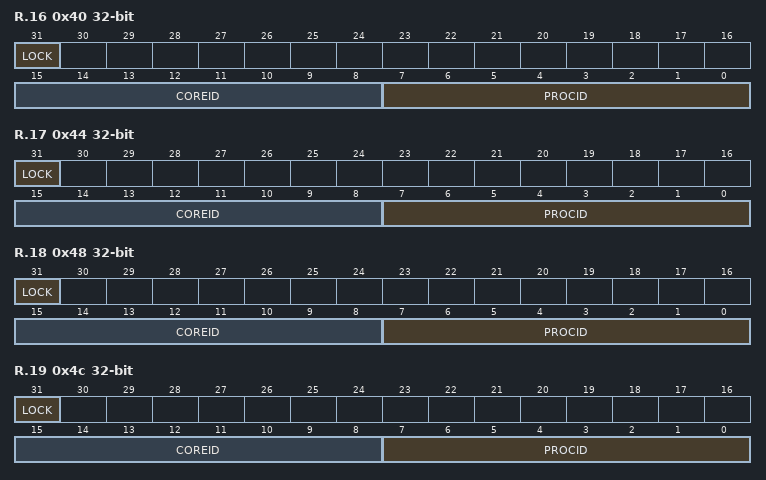
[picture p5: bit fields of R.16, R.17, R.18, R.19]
          <name>R.16</name>
          <addressOffset>0x40</addressOffset>
          <size>0x20</size>
          <fields>
            <field>
              <name>PROCID</name>
              <bitOffset>0</bitOffset>
              <bitWidth>8</bitWidth>
            </field>
            <field>
              <name>COREID</name>
              <bitOffset>8</bitOffset>
              <bitWidth>8</bitWidth>
            </field>
            <field>
              <name>LOCK</name>
              <bitOffset>31</bitOffset>
              <bitWidth>1</bitWidth>
            </field>
          </fields>
        </register>
        <register>
          <name>R.17</name>
          <addressOffset>0x44</addressOffset>
          <size>0x20</size>
          <fields>
            <field>
              <name>PROCID</name>
              <bitOffset>0</bitOffset>
              <bitWidth>8</bitWidth>
            </field>
            <field>
              <name>COREID</name>
              <bitOffset>8</bitOffset>
              <bitWidth>8</bitWidth>
            </field>
            <field>
              <name>LOCK</name>
              <bitOffset>31</bitOffset>
              <bitWidth>1</bitWidth>
            </field>
          </fields>
        </register>
        <register>
          <name>R.18</name>
          <addressOffset>0x48</addressOffset>
          <size>0x20</size>
          <fields>
            <field>
              <name>PROCID</name>
              <bitOffset>0</bitOffset>
              <bitWidth>8</bitWidth>
            </field>
            <field>
              <name>COREID</name>
              <bitOffset>8</bitOffset>
              <bitWidth>8</bitWidth>
            </field>
            <field>
              <name>LOCK</name>
              <bitOffset>31</bitOffset>
              <bitWidth>1</bitWidth>
            </field>
          </fields>
        </register>
        <register>
          <name>R.19</name>
          <addressOffset>0x4c</addressOffset>
          <size>0x20</size>
          <fields>
            <field>
              <name>PROCID</name>
              <bitOffset>0</bitOffset>
              <bitWidth>8</bitWidth>
            </field>
            <field>
              <name>COREID</name>
              <bitOffset>8</bitOffset>
              <bitWidth>8</bitWidth>
            </field>
            <field>
              <name>LOCK</name>
              <bitOffset>31</bitOffset>
              <bitWidth>1</bitWidth>
            </field>
          </fields>
        </register>
        <register>
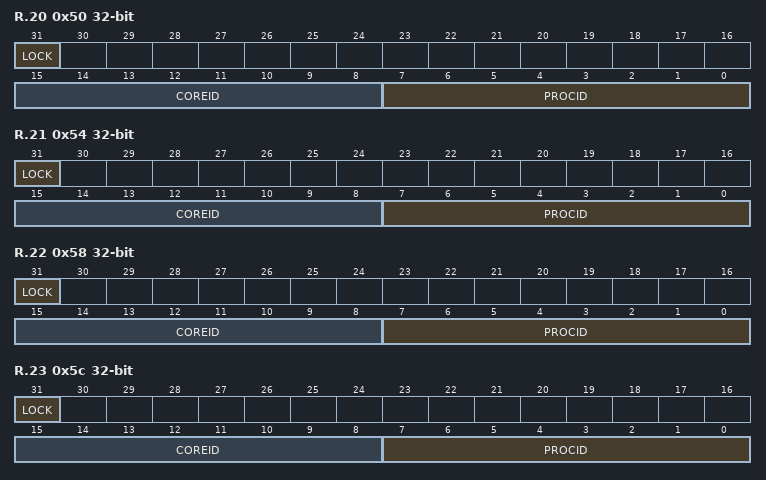
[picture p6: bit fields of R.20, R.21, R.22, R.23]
          <name>R.20</name>
          <addressOffset>0x50</addressOffset>
          <size>0x20</size>
          <fields>
            <field>
              <name>PROCID</name>
              <bitOffset>0</bitOffset>
              <bitWidth>8</bitWidth>
            </field>
            <field>
              <name>COREID</name>
              <bitOffset>8</bitOffset>
              <bitWidth>8</bitWidth>
            </field>
            <field>
              <name>LOCK</name>
              <bitOffset>31</bitOffset>
              <bitWidth>1</bitWidth>
            </field>
          </fields>
        </register>
        <register>
          <name>R.21</name>
          <addressOffset>0x54</addressOffset>
          <size>0x20</size>
          <fields>
            <field>
              <name>PROCID</name>
              <bitOffset>0</bitOffset>
              <bitWidth>8</bitWidth>
            </field>
            <field>
              <name>COREID</name>
              <bitOffset>8</bitOffset>
              <bitWidth>8</bitWidth>
            </field>
            <field>
              <name>LOCK</name>
              <bitOffset>31</bitOffset>
              <bitWidth>1</bitWidth>
            </field>
          </fields>
        </register>
        <register>
          <name>R.22</name>
          <addressOffset>0x58</addressOffset>
          <size>0x20</size>
          <fields>
            <field>
              <name>PROCID</name>
              <bitOffset>0</bitOffset>
              <bitWidth>8</bitWidth>
            </field>
            <field>
              <name>COREID</name>
              <bitOffset>8</bitOffset>
              <bitWidth>8</bitWidth>
            </field>
            <field>
              <name>LOCK</name>
              <bitOffset>31</bitOffset>
              <bitWidth>1</bitWidth>
            </field>
          </fields>
        </register>
        <register>
          <name>R.23</name>
          <addressOffset>0x5c</addressOffset>
          <size>0x20</size>
          <fields>
            <field>
              <name>PROCID</name>
              <bitOffset>0</bitOffset>
              <bitWidth>8</bitWidth>
            </field>
            <field>
              <name>COREID</name>
              <bitOffset>8</bitOffset>
              <bitWidth>8</bitWidth>
            </field>
            <field>
              <name>LOCK</name>
              <bitOffset>31</bitOffset>
              <bitWidth>1</bitWidth>
            </field>
          </fields>
        </register>
        <register>
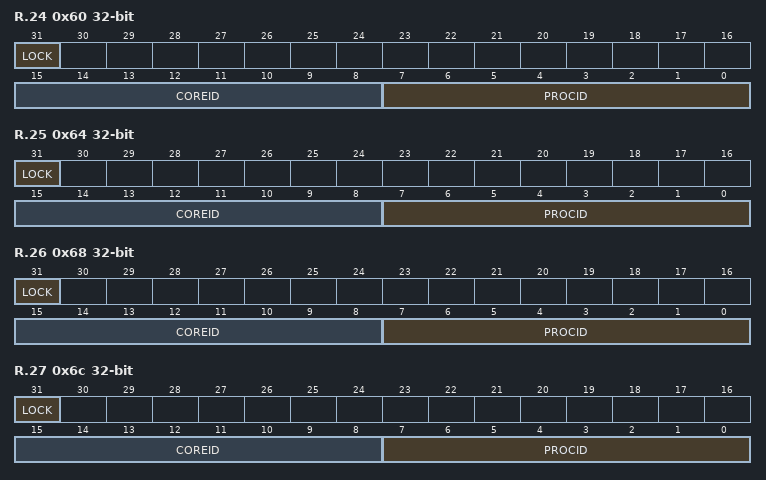
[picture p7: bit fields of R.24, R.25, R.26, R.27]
          <name>R.24</name>
          <addressOffset>0x60</addressOffset>
          <size>0x20</size>
          <fields>
            <field>
              <name>PROCID</name>
              <bitOffset>0</bitOffset>
              <bitWidth>8</bitWidth>
            </field>
            <field>
              <name>COREID</name>
              <bitOffset>8</bitOffset>
              <bitWidth>8</bitWidth>
            </field>
            <field>
              <name>LOCK</name>
              <bitOffset>31</bitOffset>
              <bitWidth>1</bitWidth>
            </field>
          </fields>
        </register>
        <register>
          <name>R.25</name>
          <addressOffset>0x64</addressOffset>
          <size>0x20</size>
          <fields>
            <field>
              <name>PROCID</name>
              <bitOffset>0</bitOffset>
              <bitWidth>8</bitWidth>
            </field>
            <field>
              <name>COREID</name>
              <bitOffset>8</bitOffset>
              <bitWidth>8</bitWidth>
            </field>
            <field>
              <name>LOCK</name>
              <bitOffset>31</bitOffset>
              <bitWidth>1</bitWidth>
            </field>
          </fields>
        </register>
        <register>
          <name>R.26</name>
          <addressOffset>0x68</addressOffset>
          <size>0x20</size>
          <fields>
            <field>
              <name>PROCID</name>
              <bitOffset>0</bitOffset>
              <bitWidth>8</bitWidth>
            </field>
            <field>
              <name>COREID</name>
              <bitOffset>8</bitOffset>
              <bitWidth>8</bitWidth>
            </field>
            <field>
              <name>LOCK</name>
              <bitOffset>31</bitOffset>
              <bitWidth>1</bitWidth>
            </field>
          </fields>
        </register>
        <register>
          <name>R.27</name>
          <addressOffset>0x6c</addressOffset>
          <size>0x20</size>
          <fields>
            <field>
              <name>PROCID</name>
              <bitOffset>0</bitOffset>
              <bitWidth>8</bitWidth>
            </field>
            <field>
              <name>COREID</name>
              <bitOffset>8</bitOffset>
              <bitWidth>8</bitWidth>
            </field>
            <field>
              <name>LOCK</name>
              <bitOffset>31</bitOffset>
              <bitWidth>1</bitWidth>
            </field>
          </fields>
        </register>
        <register>
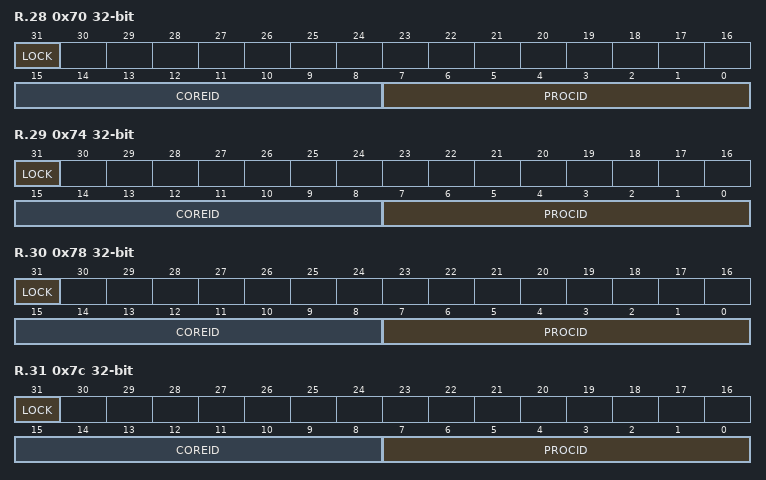
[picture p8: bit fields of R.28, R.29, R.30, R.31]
          <name>R.28</name>
          <addressOffset>0x70</addressOffset>
          <size>0x20</size>
          <fields>
            <field>
              <name>PROCID</name>
              <bitOffset>0</bitOffset>
              <bitWidth>8</bitWidth>
            </field>
            <field>
              <name>COREID</name>
              <bitOffset>8</bitOffset>
              <bitWidth>8</bitWidth>
            </field>
            <field>
              <name>LOCK</name>
              <bitOffset>31</bitOffset>
              <bitWidth>1</bitWidth>
            </field>
          </fields>
        </register>
        <register>
          <name>R.29</name>
          <addressOffset>0x74</addressOffset>
          <size>0x20</size>
          <fields>
            <field>
              <name>PROCID</name>
              <bitOffset>0</bitOffset>
              <bitWidth>8</bitWidth>
            </field>
            <field>
              <name>COREID</name>
              <bitOffset>8</bitOffset>
              <bitWidth>8</bitWidth>
            </field>
            <field>
              <name>LOCK</name>
              <bitOffset>31</bitOffset>
              <bitWidth>1</bitWidth>
            </field>
          </fields>
        </register>
        <register>
          <name>R.30</name>
          <addressOffset>0x78</addressOffset>
          <size>0x20</size>
          <fields>
            <field>
              <name>PROCID</name>
              <bitOffset>0</bitOffset>
              <bitWidth>8</bitWidth>
            </field>
            <field>
              <name>COREID</name>
              <bitOffset>8</bitOffset>
              <bitWidth>8</bitWidth>
            </field>
            <field>
              <name>LOCK</name>
              <bitOffset>31</bitOffset>
              <bitWidth>1</bitWidth>
            </field>
          </fields>
        </register>
        <register>
          <name>R.31</name>
          <addressOffset>0x7c</addressOffset>
          <size>0x20</size>
          <fields>
            <field>
              <name>PROCID</name>
              <bitOffset>0</bitOffset>
              <bitWidth>8</bitWidth>
            </field>
            <field>
              <name>COREID</name>
              <bitOffset>8</bitOffset>
              <bitWidth>8</bitWidth>
            </field>
            <field>
              <name>LOCK</name>
              <bitOffset>31</bitOffset>
              <bitWidth>1</bitWidth>
            </field>
          </fields>
        </register>
        <register>
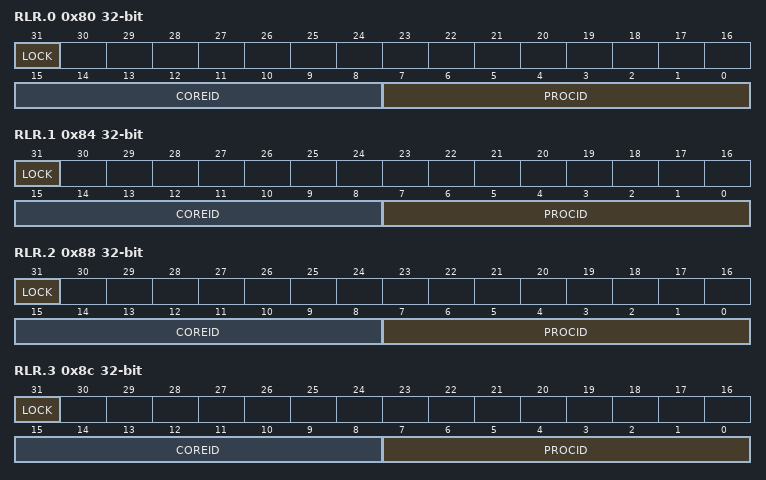
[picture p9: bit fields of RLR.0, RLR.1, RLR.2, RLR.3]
          <name>RLR.0</name>
          <addressOffset>0x80</addressOffset>
          <size>0x20</size>
          <fields>
            <field>
              <name>PROCID</name>
              <bitOffset>0</bitOffset>
              <bitWidth>8</bitWidth>
            </field>
            <field>
              <name>COREID</name>
              <bitOffset>8</bitOffset>
              <bitWidth>8</bitWidth>
            </field>
            <field>
              <name>LOCK</name>
              <bitOffset>31</bitOffset>
              <bitWidth>1</bitWidth>
            </field>
          </fields>
        </register>
        <register>
          <name>RLR.1</name>
          <addressOffset>0x84</addressOffset>
          <size>0x20</size>
          <fields>
            <field>
              <name>PROCID</name>
              <bitOffset>0</bitOffset>
              <bitWidth>8</bitWidth>
            </field>
            <field>
              <name>COREID</name>
              <bitOffset>8</bitOffset>
              <bitWidth>8</bitWidth>
            </field>
            <field>
              <name>LOCK</name>
              <bitOffset>31</bitOffset>
              <bitWidth>1</bitWidth>
            </field>
          </fields>
        </register>
        <register>
          <name>RLR.2</name>
          <addressOffset>0x88</addressOffset>
          <size>0x20</size>
          <fields>
            <field>
              <name>PROCID</name>
              <bitOffset>0</bitOffset>
              <bitWidth>8</bitWidth>
            </field>
            <field>
              <name>COREID</name>
              <bitOffset>8</bitOffset>
              <bitWidth>8</bitWidth>
            </field>
            <field>
              <name>LOCK</name>
              <bitOffset>31</bitOffset>
              <bitWidth>1</bitWidth>
            </field>
          </fields>
        </register>
        <register>
          <name>RLR.3</name>
          <addressOffset>0x8c</addressOffset>
          <size>0x20</size>
          <fields>
            <field>
              <name>PROCID</name>
              <bitOffset>0</bitOffset>
              <bitWidth>8</bitWidth>
            </field>
            <field>
              <name>COREID</name>
              <bitOffset>8</bitOffset>
              <bitWidth>8</bitWidth>
            </field>
            <field>
              <name>LOCK</name>
              <bitOffset>31</bitOffset>
              <bitWidth>1</bitWidth>
            </field>
          </fields>
        </register>
        <register>
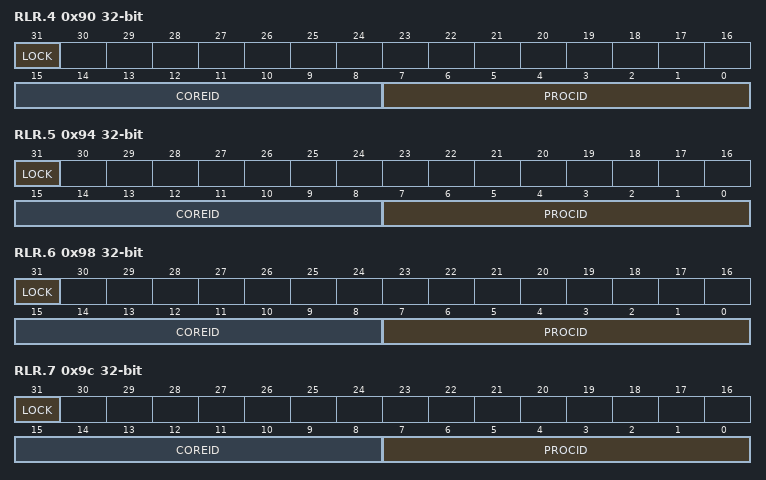
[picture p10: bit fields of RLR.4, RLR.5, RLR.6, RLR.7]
          <name>RLR.4</name>
          <addressOffset>0x90</addressOffset>
          <size>0x20</size>
          <fields>
            <field>
              <name>PROCID</name>
              <bitOffset>0</bitOffset>
              <bitWidth>8</bitWidth>
            </field>
            <field>
              <name>COREID</name>
              <bitOffset>8</bitOffset>
              <bitWidth>8</bitWidth>
            </field>
            <field>
              <name>LOCK</name>
              <bitOffset>31</bitOffset>
              <bitWidth>1</bitWidth>
            </field>
          </fields>
        </register>
        <register>
          <name>RLR.5</name>
          <addressOffset>0x94</addressOffset>
          <size>0x20</size>
          <fields>
            <field>
              <name>PROCID</name>
              <bitOffset>0</bitOffset>
              <bitWidth>8</bitWidth>
            </field>
            <field>
              <name>COREID</name>
              <bitOffset>8</bitOffset>
              <bitWidth>8</bitWidth>
            </field>
            <field>
              <name>LOCK</name>
              <bitOffset>31</bitOffset>
              <bitWidth>1</bitWidth>
            </field>
          </fields>
        </register>
        <register>
          <name>RLR.6</name>
          <addressOffset>0x98</addressOffset>
          <size>0x20</size>
          <fields>
            <field>
              <name>PROCID</name>
              <bitOffset>0</bitOffset>
              <bitWidth>8</bitWidth>
            </field>
            <field>
              <name>COREID</name>
              <bitOffset>8</bitOffset>
              <bitWidth>8</bitWidth>
            </field>
            <field>
              <name>LOCK</name>
              <bitOffset>31</bitOffset>
              <bitWidth>1</bitWidth>
            </field>
          </fields>
        </register>
        <register>
          <name>RLR.7</name>
          <addressOffset>0x9c</addressOffset>
          <size>0x20</size>
          <fields>
            <field>
              <name>PROCID</name>
              <bitOffset>0</bitOffset>
              <bitWidth>8</bitWidth>
            </field>
            <field>
              <name>COREID</name>
              <bitOffset>8</bitOffset>
              <bitWidth>8</bitWidth>
            </field>
            <field>
              <name>LOCK</name>
              <bitOffset>31</bitOffset>
              <bitWidth>1</bitWidth>
            </field>
          </fields>
        </register>
        <register>
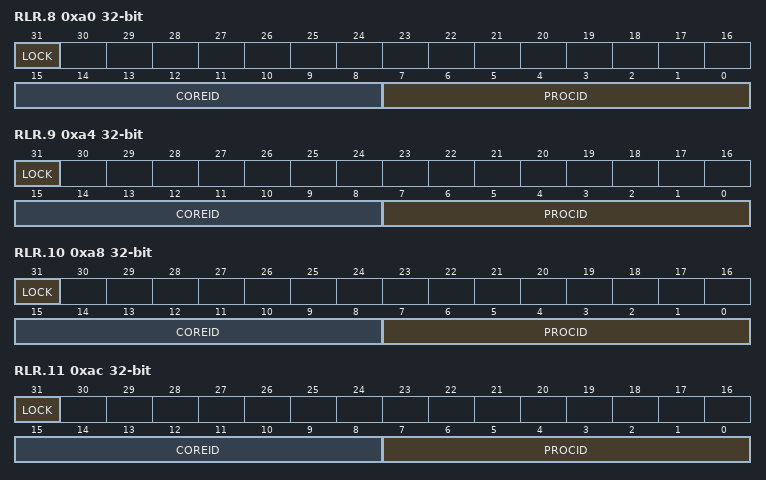
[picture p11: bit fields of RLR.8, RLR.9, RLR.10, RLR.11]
          <name>RLR.8</name>
          <addressOffset>0xa0</addressOffset>
          <size>0x20</size>
          <fields>
            <field>
              <name>PROCID</name>
              <bitOffset>0</bitOffset>
              <bitWidth>8</bitWidth>
            </field>
            <field>
              <name>COREID</name>
              <bitOffset>8</bitOffset>
              <bitWidth>8</bitWidth>
            </field>
            <field>
              <name>LOCK</name>
              <bitOffset>31</bitOffset>
              <bitWidth>1</bitWidth>
            </field>
          </fields>
        </register>
        <register>
          <name>RLR.9</name>
          <addressOffset>0xa4</addressOffset>
          <size>0x20</size>
          <fields>
            <field>
              <name>PROCID</name>
              <bitOffset>0</bitOffset>
              <bitWidth>8</bitWidth>
            </field>
            <field>
              <name>COREID</name>
              <bitOffset>8</bitOffset>
              <bitWidth>8</bitWidth>
            </field>
            <field>
              <name>LOCK</name>
              <bitOffset>31</bitOffset>
              <bitWidth>1</bitWidth>
            </field>
          </fields>
        </register>
        <register>
          <name>RLR.10</name>
          <addressOffset>0xa8</addressOffset>
          <size>0x20</size>
          <fields>
            <field>
              <name>PROCID</name>
              <bitOffset>0</bitOffset>
              <bitWidth>8</bitWidth>
            </field>
            <field>
              <name>COREID</name>
              <bitOffset>8</bitOffset>
              <bitWidth>8</bitWidth>
            </field>
            <field>
              <name>LOCK</name>
              <bitOffset>31</bitOffset>
              <bitWidth>1</bitWidth>
            </field>
          </fields>
        </register>
        <register>
          <name>RLR.11</name>
          <addressOffset>0xac</addressOffset>
          <size>0x20</size>
          <fields>
            <field>
              <name>PROCID</name>
              <bitOffset>0</bitOffset>
              <bitWidth>8</bitWidth>
            </field>
            <field>
              <name>COREID</name>
              <bitOffset>8</bitOffset>
              <bitWidth>8</bitWidth>
            </field>
            <field>
              <name>LOCK</name>
              <bitOffset>31</bitOffset>
              <bitWidth>1</bitWidth>
            </field>
          </fields>
        </register>
        <register>
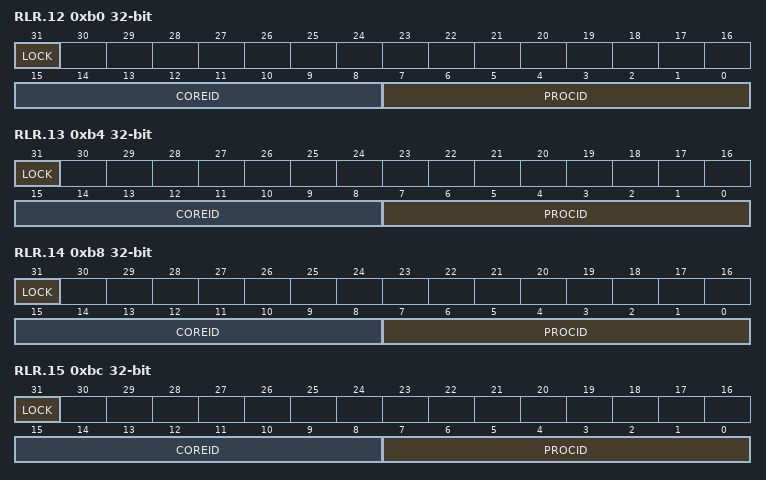
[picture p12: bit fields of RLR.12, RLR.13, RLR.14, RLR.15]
          <name>RLR.12</name>
          <addressOffset>0xb0</addressOffset>
          <size>0x20</size>
          <fields>
            <field>
              <name>PROCID</name>
              <bitOffset>0</bitOffset>
              <bitWidth>8</bitWidth>
            </field>
            <field>
              <name>COREID</name>
              <bitOffset>8</bitOffset>
              <bitWidth>8</bitWidth>
            </field>
            <field>
              <name>LOCK</name>
              <bitOffset>31</bitOffset>
              <bitWidth>1</bitWidth>
            </field>
          </fields>
        </register>
        <register>
          <name>RLR.13</name>
          <addressOffset>0xb4</addressOffset>
          <size>0x20</size>
          <fields>
            <field>
              <name>PROCID</name>
              <bitOffset>0</bitOffset>
              <bitWidth>8</bitWidth>
            </field>
            <field>
              <name>COREID</name>
              <bitOffset>8</bitOffset>
              <bitWidth>8</bitWidth>
            </field>
            <field>
              <name>LOCK</name>
              <bitOffset>31</bitOffset>
              <bitWidth>1</bitWidth>
            </field>
          </fields>
        </register>
        <register>
          <name>RLR.14</name>
          <addressOffset>0xb8</addressOffset>
          <size>0x20</size>
          <fields>
            <field>
              <name>PROCID</name>
              <bitOffset>0</bitOffset>
              <bitWidth>8</bitWidth>
            </field>
            <field>
              <name>COREID</name>
              <bitOffset>8</bitOffset>
              <bitWidth>8</bitWidth>
            </field>
            <field>
              <name>LOCK</name>
              <bitOffset>31</bitOffset>
              <bitWidth>1</bitWidth>
            </field>
          </fields>
        </register>
        <register>
          <name>RLR.15</name>
          <addressOffset>0xbc</addressOffset>
          <size>0x20</size>
          <fields>
            <field>
              <name>PROCID</name>
              <bitOffset>0</bitOffset>
              <bitWidth>8</bitWidth>
            </field>
            <field>
              <name>COREID</name>
              <bitOffset>8</bitOffset>
              <bitWidth>8</bitWidth>
            </field>
            <field>
              <name>LOCK</name>
              <bitOffset>31</bitOffset>
              <bitWidth>1</bitWidth>
            </field>
          </fields>
        </register>
        <register>
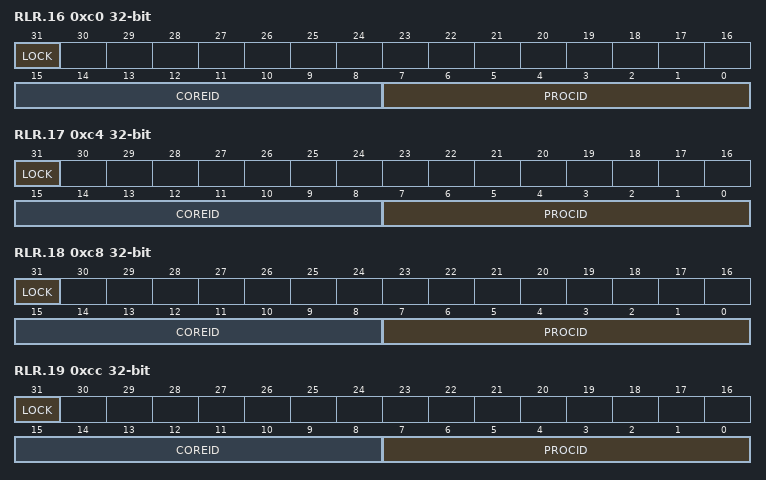
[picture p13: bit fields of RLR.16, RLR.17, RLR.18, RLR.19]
          <name>RLR.16</name>
          <addressOffset>0xc0</addressOffset>
          <size>0x20</size>
          <fields>
            <field>
              <name>PROCID</name>
              <bitOffset>0</bitOffset>
              <bitWidth>8</bitWidth>
            </field>
            <field>
              <name>COREID</name>
              <bitOffset>8</bitOffset>
              <bitWidth>8</bitWidth>
            </field>
            <field>
              <name>LOCK</name>
              <bitOffset>31</bitOffset>
              <bitWidth>1</bitWidth>
            </field>
          </fields>
        </register>
        <register>
          <name>RLR.17</name>
          <addressOffset>0xc4</addressOffset>
          <size>0x20</size>
          <fields>
            <field>
              <name>PROCID</name>
              <bitOffset>0</bitOffset>
              <bitWidth>8</bitWidth>
            </field>
            <field>
              <name>COREID</name>
              <bitOffset>8</bitOffset>
              <bitWidth>8</bitWidth>
            </field>
            <field>
              <name>LOCK</name>
              <bitOffset>31</bitOffset>
              <bitWidth>1</bitWidth>
            </field>
          </fields>
        </register>
        <register>
          <name>RLR.18</name>
          <addressOffset>0xc8</addressOffset>
          <size>0x20</size>
          <fields>
            <field>
              <name>PROCID</name>
              <bitOffset>0</bitOffset>
              <bitWidth>8</bitWidth>
            </field>
            <field>
              <name>COREID</name>
              <bitOffset>8</bitOffset>
              <bitWidth>8</bitWidth>
            </field>
            <field>
              <name>LOCK</name>
              <bitOffset>31</bitOffset>
              <bitWidth>1</bitWidth>
            </field>
          </fields>
        </register>
        <register>
          <name>RLR.19</name>
          <addressOffset>0xcc</addressOffset>
          <size>0x20</size>
          <fields>
            <field>
              <name>PROCID</name>
              <bitOffset>0</bitOffset>
              <bitWidth>8</bitWidth>
            </field>
            <field>
              <name>COREID</name>
              <bitOffset>8</bitOffset>
              <bitWidth>8</bitWidth>
            </field>
            <field>
              <name>LOCK</name>
              <bitOffset>31</bitOffset>
              <bitWidth>1</bitWidth>
            </field>
          </fields>
        </register>
        <register>
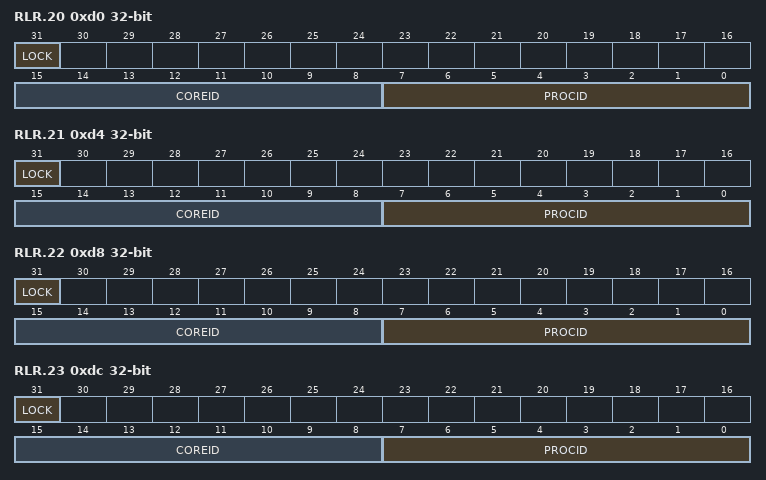
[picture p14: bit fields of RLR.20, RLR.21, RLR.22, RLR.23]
          <name>RLR.20</name>
          <addressOffset>0xd0</addressOffset>
          <size>0x20</size>
          <fields>
            <field>
              <name>PROCID</name>
              <bitOffset>0</bitOffset>
              <bitWidth>8</bitWidth>
            </field>
            <field>
              <name>COREID</name>
              <bitOffset>8</bitOffset>
              <bitWidth>8</bitWidth>
            </field>
            <field>
              <name>LOCK</name>
              <bitOffset>31</bitOffset>
              <bitWidth>1</bitWidth>
            </field>
          </fields>
        </register>
        <register>
          <name>RLR.21</name>
          <addressOffset>0xd4</addressOffset>
          <size>0x20</size>
          <fields>
            <field>
              <name>PROCID</name>
              <bitOffset>0</bitOffset>
              <bitWidth>8</bitWidth>
            </field>
            <field>
              <name>COREID</name>
              <bitOffset>8</bitOffset>
              <bitWidth>8</bitWidth>
            </field>
            <field>
              <name>LOCK</name>
              <bitOffset>31</bitOffset>
              <bitWidth>1</bitWidth>
            </field>
          </fields>
        </register>
        <register>
          <name>RLR.22</name>
          <addressOffset>0xd8</addressOffset>
          <size>0x20</size>
          <fields>
            <field>
              <name>PROCID</name>
              <bitOffset>0</bitOffset>
              <bitWidth>8</bitWidth>
            </field>
            <field>
              <name>COREID</name>
              <bitOffset>8</bitOffset>
              <bitWidth>8</bitWidth>
            </field>
            <field>
              <name>LOCK</name>
              <bitOffset>31</bitOffset>
              <bitWidth>1</bitWidth>
            </field>
          </fields>
        </register>
        <register>
          <name>RLR.23</name>
          <addressOffset>0xdc</addressOffset>
          <size>0x20</size>
          <fields>
            <field>
              <name>PROCID</name>
              <bitOffset>0</bitOffset>
              <bitWidth>8</bitWidth>
            </field>
            <field>
              <name>COREID</name>
              <bitOffset>8</bitOffset>
              <bitWidth>8</bitWidth>
            </field>
            <field>
              <name>LOCK</name>
              <bitOffset>31</bitOffset>
              <bitWidth>1</bitWidth>
            </field>
          </fields>
        </register>
        <register>
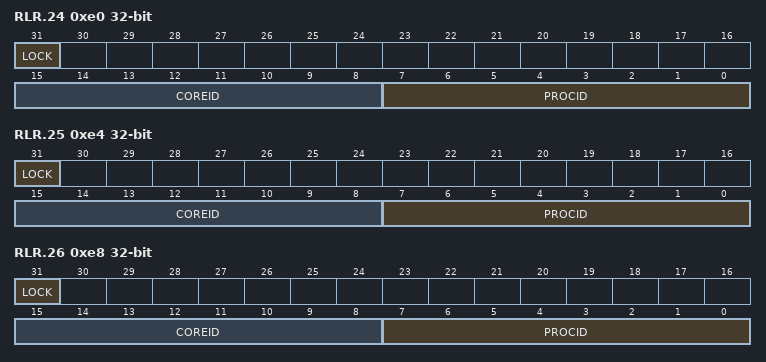
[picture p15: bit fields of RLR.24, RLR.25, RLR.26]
          <name>RLR.24</name>
          <addressOffset>0xe0</addressOffset>
          <size>0x20</size>
          <fields>
            <field>
              <name>PROCID</name>
              <bitOffset>0</bitOffset>
              <bitWidth>8</bitWidth>
            </field>
            <field>
              <name>COREID</name>
              <bitOffset>8</bitOffset>
              <bitWidth>8</bitWidth>
            </field>
            <field>
              <name>LOCK</name>
              <bitOffset>31</bitOffset>
              <bitWidth>1</bitWidth>
            </field>
          </fields>
        </register>
        <register>
          <name>RLR.25</name>
          <addressOffset>0xe4</addressOffset>
          <size>0x20</size>
          <fields>
            <field>
              <name>PROCID</name>
              <bitOffset>0</bitOffset>
              <bitWidth>8</bitWidth>
            </field>
            <field>
              <name>COREID</name>
              <bitOffset>8</bitOffset>
              <bitWidth>8</bitWidth>
            </field>
            <field>
              <name>LOCK</name>
              <bitOffset>31</bitOffset>
              <bitWidth>1</bitWidth>
            </field>
          </fields>
        </register>
        <register>
          <name>RLR.26</name>
          <addressOffset>0xe8</addressOffset>
          <size>0x20</size>
          <fields>
            <field>
              <name>PROCID</name>
              <bitOffset>0</bitOffset>
              <bitWidth>8</bitWidth>
            </field>
            <field>
              <name>COREID</name>
              <bitOffset>8</bitOffset>
              <bitWidth>8</bitWidth>
            </field>
            <field>
              <name>LOCK</name>
              <bitOffset>31</bitOffset>
              <bitWidth>1</bitWidth>
            </field>
          </fields>
        </register>
        <register>
          <name>RLR.27</name>
          <addressOffset>0xec</addressOffset>
          <size>0x20</size>
          <fields>
            <field>
              <name>PROCID</name>
              <bitOffset>0</bitOffset>
              <bitWidth>8</bitWidth>
            </field>
            <field>
              <name>COREID</name>
              <bitOffset>8</bitOffset>
              <bitWidth>8</bitWidth>
            </field>
            <field>
              <name>LOCK</name>
              <bitOffset>31</bitOffset>
              <bitWidth>1</bitWidth>
            </field>
          </fields>
        </register>
        <register>
          <name>RLR.28</name>
          <addressOffset>0xf0</addressOffset>
          <size>0x20</size>
          <fields>
            <field>
              <name>PROCID</name>
              <bitOffset>0</bitOffset>
              <bitWidth>8</bitWidth>
            </field>
            <field>
              <name>COREID</name>
              <bitOffset>8</bitOffset>
              <bitWidth>8</bitWidth>
            </field>
            <field>
              <name>LOCK</name>
              <bitOffset>31</bitOffset>
              <bitWidth>1</bitWidth>
            </field>
          </fields>
        </register>
        <register>
          <name>RLR.29</name>
          <addressOffset>0xf4</addressOffset>
          <size>0x20</size>
          <fields>
            <field>
              <name>PROCID</name>
              <bitOffset>0</bitOffset>
              <bitWidth>8</bitWidth>
            </field>
            <field>
              <name>COREID</name>
              <bitOffset>8</bitOffset>
              <bitWidth>8</bitWidth>
            </field>
            <field>
              <name>LOCK</name>
              <bitOffset>31</bitOffset>
              <bitWidth>1</bitWidth>
            </field>
          </fields>
        </register>
        <register>
          <name>RLR.30</name>
          <addressOffset>0xf8</addressOffset>
          <size>0x20</size>
          <fields>
            <field>
              <name>PROCID</name>
              <bitOffset>0</bitOffset>
              <bitWidth>8</bitWidth>
            </field>
            <field>
              <name>COREID</name>
              <bitOffset>8</bitOffset>
              <bitWidth>8</bitWidth>
            </field>
            <field>
              <name>LOCK</name>
              <bitOffset>31</bitOffset>
              <bitWidth>1</bitWidth>
            </field>
          </fields>
        </register>
        <register>
          <name>RLR.31</name>
          <addressOffset>0xfc</addressOffset>
          <size>0x20</size>
          <fields>
            <field>
              <name>PROCID</name>
              <bitOffset>0</bitOffset>
              <bitWidth>8</bitWidth>
            </field>
            <field>
              <name>COREID</name>
              <bitOffset>8</bitOffset>
              <bitWidth>8</bitWidth>
            </field>
            <field>
              <name>LOCK</name>
              <bitOffset>31</bitOffset>
              <bitWidth>1</bitWidth>
            </field>
          </fields>
        </register>
        <register>
          <name>C1IER</name>
          <addressOffset>0x100</addressOffset>
          <size>0x20</size>
          <fields>
            <field>
              <name>ISE0</name>
              <bitOffset>0</bitOffset>
              <bitWidth>1</bitWidth>
            </field>
            <field>
              <name>ISE1</name>
              <bitOffset>1</bitOffset>
              <bitWidth>1</bitWidth>
            </field>
            <field>
              <name>ISE2</name>
              <bitOffset>2</bitOffset>
              <bitWidth>1</bitWidth>
            </field>
            <field>
              <name>ISE3</name>
              <bitOffset>3</bitOffset>
              <bitWidth>1</bitWidth>
            </field>
            <field>
              <name>ISE4</name>
              <bitOffset>4</bitOffset>
              <bitWidth>1</bitWidth>
            </field>
            <field>
              <name>ISE5</name>
              <bitOffset>5</bitOffset>
              <bitWidth>1</bitWidth>
            </field>
            <field>
              <name>ISE6</name>
              <bitOffset>6</bitOffset>
              <bitWidth>1</bitWidth>
            </field>
            <field>
              <name>ISE7</name>
              <bitOffset>7</bitOffset>
              <bitWidth>1</bitWidth>
            </field>
            <field>
              <name>ISE8</name>
              <bitOffset>8</bitOffset>
              <bitWidth>1</bitWidth>
            </field>
            <field>
              <name>ISE9</name>
              <bitOffset>9</bitOffset>
              <bitWidth>1</bitWidth>
            </field>
            <field>
              <name>ISE10</name>
              <bitOffset>10</bitOffset>
              <bitWidth>1</bitWidth>
            </field>
            <field>
              <name>ISE11</name>
              <bitOffset>11</bitOffset>
              <bitWidth>1</bitWidth>
            </field>
            <field>
              <name>ISE12</name>
              <bitOffset>12</bitOffset>
              <bitWidth>1</bitWidth>
            </field>
            <field>
              <name>ISE13</name>
              <bitOffset>13</bitOffset>
              <bitWidth>1</bitWidth>
            </field>
            <field>
              <name>ISE14</name>
              <bitOffset>14</bitOffset>
              <bitWidth>1</bitWidth>
            </field>
            <field>
              <name>ISE15</name>
              <bitOffset>15</bitOffset>
              <bitWidth>1</bitWidth>
            </field>
            <field>
              <name>ISE16</name>
              <bitOffset>16</bitOffset>
              <bitWidth>1</bitWidth>
            </field>
            <field>
              <name>ISE17</name>
              <bitOffset>17</bitOffset>
              <bitWidth>1</bitWidth>
            </field>
            <field>
              <name>ISE18</name>
              <bitOffset>18</bitOffset>
              <bitWidth>1</bitWidth>
            </field>
            <field>
              <name>ISE19</name>
              <bitOffset>19</bitOffset>
              <bitWidth>1</bitWidth>
            </field>
            <field>
              <name>ISE20</name>
              <bitOffset>20</bitOffset>
              <bitWidth>1</bitWidth>
            </field>
            <field>
              <name>ISE21</name>
              <bitOffset>21</bitOffset>
              <bitWidth>1</bitWidth>
            </field>
            <field>
              <name>ISE22</name>
              <bitOffset>22</bitOffset>
              <bitWidth>1</bitWidth>
            </field>
            <field>
              <name>ISE23</name>
              <bitOffset>23</bitOffset>
              <bitWidth>1</bitWidth>
            </field>
            <field>
              <name>ISE24</name>
              <bitOffset>24</bitOffset>
              <bitWidth>1</bitWidth>
            </field>
            <field>
              <name>ISE25</name>
              <bitOffset>25</bitOffset>
              <bitWidth>1</bitWidth>
            </field>
            <field>
              <name>ISE26</name>
              <bitOffset>26</bitOffset>
              <bitWidth>1</bitWidth>
            </field>
            <field>
              <name>ISE27</name>
              <bitOffset>27</bitOffset>
              <bitWidth>1</bitWidth>
            </field>
            <field>
              <name>ISE28</name>
              <bitOffset>28</bitOffset>
              <bitWidth>1</bitWidth>
            </field>
            <field>
              <name>ISE29</name>
              <bitOffset>29</bitOffset>
              <bitWidth>1</bitWidth>
            </field>
            <field>
              <name>ISE30</name>
              <bitOffset>30</bitOffset>
              <bitWidth>1</bitWidth>
            </field>
            <field>
              <name>ISE31</name>
              <bitOffset>31</bitOffset>
              <bitWidth>1</bitWidth>
            </field>
          </fields>
        </register>
        <register>
          <name>C1ICR</name>
          <addressOffset>0x104</addressOffset>
          <size>0x20</size>
          <fields>
            <field>
              <name>ISC0</name>
              <bitOffset>0</bitOffset>
              <bitWidth>1</bitWidth>
            </field>
            <field>
              <name>ISC1</name>
              <bitOffset>1</bitOffset>
              <bitWidth>1</bitWidth>
            </field>
            <field>
              <name>ISC2</name>
              <bitOffset>2</bitOffset>
              <bitWidth>1</bitWidth>
            </field>
            <field>
              <name>ISC3</name>
              <bitOffset>3</bitOffset>
              <bitWidth>1</bitWidth>
            </field>
            <field>
              <name>ISC4</name>
              <bitOffset>4</bitOffset>
              <bitWidth>1</bitWidth>
            </field>
            <field>
              <name>ISC5</name>
              <bitOffset>5</bitOffset>
              <bitWidth>1</bitWidth>
            </field>
            <field>
              <name>ISC6</name>
              <bitOffset>6</bitOffset>
              <bitWidth>1</bitWidth>
            </field>
            <field>
              <name>ISC7</name>
              <bitOffset>7</bitOffset>
              <bitWidth>1</bitWidth>
            </field>
            <field>
              <name>ISC8</name>
              <bitOffset>8</bitOffset>
              <bitWidth>1</bitWidth>
            </field>
            <field>
              <name>ISC9</name>
              <bitOffset>9</bitOffset>
              <bitWidth>1</bitWidth>
            </field>
            <field>
              <name>ISC10</name>
              <bitOffset>10</bitOffset>
              <bitWidth>1</bitWidth>
            </field>
            <field>
              <name>ISC11</name>
              <bitOffset>11</bitOffset>
              <bitWidth>1</bitWidth>
            </field>
            <field>
              <name>ISC12</name>
              <bitOffset>12</bitOffset>
              <bitWidth>1</bitWidth>
            </field>
            <field>
              <name>ISC13</name>
              <bitOffset>13</bitOffset>
              <bitWidth>1</bitWidth>
            </field>
            <field>
              <name>ISC14</name>
              <bitOffset>14</bitOffset>
              <bitWidth>1</bitWidth>
            </field>
            <field>
              <name>ISC15</name>
              <bitOffset>15</bitOffset>
              <bitWidth>1</bitWidth>
            </field>
            <field>
              <name>ISC16</name>
              <bitOffset>16</bitOffset>
              <bitWidth>1</bitWidth>
            </field>
            <field>
              <name>ISC17</name>
              <bitOffset>17</bitOffset>
              <bitWidth>1</bitWidth>
            </field>
            <field>
              <name>ISC18</name>
              <bitOffset>18</bitOffset>
              <bitWidth>1</bitWidth>
            </field>
            <field>
              <name>ISC19</name>
              <bitOffset>19</bitOffset>
              <bitWidth>1</bitWidth>
            </field>
            <field>
              <name>ISC20</name>
              <bitOffset>20</bitOffset>
              <bitWidth>1</bitWidth>
            </field>
            <field>
              <name>ISC21</name>
              <bitOffset>21</bitOffset>
              <bitWidth>1</bitWidth>
            </field>
            <field>
              <name>ISC22</name>
              <bitOffset>22</bitOffset>
              <bitWidth>1</bitWidth>
            </field>
            <field>
              <name>ISC23</name>
              <bitOffset>23</bitOffset>
              <bitWidth>1</bitWidth>
            </field>
            <field>
              <name>ISC24</name>
              <bitOffset>24</bitOffset>
              <bitWidth>1</bitWidth>
            </field>
            <field>
              <name>ISC25</name>
              <bitOffset>25</bitOffset>
              <bitWidth>1</bitWidth>
            </field>
            <field>
              <name>ISC26</name>
              <bitOffset>26</bitOffset>
              <bitWidth>1</bitWidth>
            </field>
            <field>
              <name>ISC27</name>
              <bitOffset>27</bitOffset>
              <bitWidth>1</bitWidth>
            </field>
            <field>
              <name>ISC28</name>
              <bitOffset>28</bitOffset>
              <bitWidth>1</bitWidth>
            </field>
            <field>
              <name>ISC29</name>
              <bitOffset>29</bitOffset>
              <bitWidth>1</bitWidth>
            </field>
            <field>
              <name>ISC30</name>
              <bitOffset>30</bitOffset>
              <bitWidth>1</bitWidth>
            </field>
            <field>
              <name>ISC31</name>
              <bitOffset>31</bitOffset>
              <bitWidth>1</bitWidth>
            </field>
          </fields>
        </register>
        <register>
          <name>C1ISR</name>
          <addressOffset>0x108</addressOffset>
          <size>0x20</size>
          <fields>
            <field>
              <name>ISF0</name>
              <bitOffset>0</bitOffset>
              <bitWidth>1</bitWidth>
            </field>
            <field>
              <name>ISF1</name>
              <bitOffset>1</bitOffset>
              <bitWidth>1</bitWidth>
            </field>
            <field>
              <name>ISF2</name>
              <bitOffset>2</bitOffset>
              <bitWidth>1</bitWidth>
            </field>
            <field>
              <name>ISF3</name>
              <bitOffset>3</bitOffset>
              <bitWidth>1</bitWidth>
            </field>
            <field>
              <name>ISF4</name>
              <bitOffset>4</bitOffset>
              <bitWidth>1</bitWidth>
            </field>
            <field>
              <name>ISF5</name>
              <bitOffset>5</bitOffset>
              <bitWidth>1</bitWidth>
            </field>
            <field>
              <name>ISF6</name>
              <bitOffset>6</bitOffset>
              <bitWidth>1</bitWidth>
            </field>
            <field>
              <name>ISF7</name>
              <bitOffset>7</bitOffset>
              <bitWidth>1</bitWidth>
            </field>
            <field>
              <name>ISF8</name>
              <bitOffset>8</bitOffset>
              <bitWidth>1</bitWidth>
            </field>
            <field>
              <name>ISF9</name>
              <bitOffset>9</bitOffset>
              <bitWidth>1</bitWidth>
            </field>
            <field>
              <name>ISF10</name>
              <bitOffset>10</bitOffset>
              <bitWidth>1</bitWidth>
            </field>
            <field>
              <name>ISF11</name>
              <bitOffset>11</bitOffset>
              <bitWidth>1</bitWidth>
            </field>
            <field>
              <name>ISF12</name>
              <bitOffset>12</bitOffset>
              <bitWidth>1</bitWidth>
            </field>
            <field>
              <name>ISF13</name>
              <bitOffset>13</bitOffset>
              <bitWidth>1</bitWidth>
            </field>
            <field>
              <name>ISF14</name>
              <bitOffset>14</bitOffset>
              <bitWidth>1</bitWidth>
            </field>
            <field>
              <name>ISF15</name>
              <bitOffset>15</bitOffset>
              <bitWidth>1</bitWidth>
            </field>
            <field>
              <name>ISF16</name>
              <bitOffset>16</bitOffset>
              <bitWidth>1</bitWidth>
            </field>
            <field>
              <name>ISF17</name>
              <bitOffset>17</bitOffset>
              <bitWidth>1</bitWidth>
            </field>
            <field>
              <name>ISF18</name>
              <bitOffset>18</bitOffset>
              <bitWidth>1</bitWidth>
            </field>
            <field>
              <name>ISF19</name>
              <bitOffset>19</bitOffset>
              <bitWidth>1</bitWidth>
            </field>
            <field>
              <name>ISF20</name>
              <bitOffset>20</bitOffset>
              <bitWidth>1</bitWidth>
            </field>
            <field>
              <name>ISF21</name>
              <bitOffset>21</bitOffset>
              <bitWidth>1</bitWidth>
            </field>
            <field>
              <name>ISF22</name>
              <bitOffset>22</bitOffset>
              <bitWidth>1</bitWidth>
            </field>
            <field>
              <name>ISF23</name>
              <bitOffset>23</bitOffset>
              <bitWidth>1</bitWidth>
            </field>
            <field>
              <name>ISF24</name>
              <bitOffset>24</bitOffset>
              <bitWidth>1</bitWidth>
            </field>
            <field>
              <name>ISF25</name>
              <bitOffset>25</bitOffset>
              <bitWidth>1</bitWidth>
            </field>
            <field>
              <name>ISF26</name>
              <bitOffset>26</bitOffset>
              <bitWidth>1</bitWidth>
            </field>
            <field>
              <name>ISF27</name>
              <bitOffset>27</bitOffset>
              <bitWidth>1</bitWidth>
            </field>
            <field>
              <name>ISF28</name>
              <bitOffset>28</bitOffset>
              <bitWidth>1</bitWidth>
            </field>
            <field>
              <name>ISF29</name>
              <bitOffset>29</bitOffset>
              <bitWidth>1</bitWidth>
            </field>
            <field>
              <name>ISF30</name>
              <bitOffset>30</bitOffset>
              <bitWidth>1</bitWidth>
            </field>
            <field>
              <name>ISF31</name>
              <bitOffset>31</bitOffset>
              <bitWidth>1</bitWidth>
            </field>
          </fields>
        </register>
        <register>
          <name>C1MISR</name>
          <addressOffset>0x10c</addressOffset>
          <size>0x20</size>
          <fields>
            <field>
              <name>MISF0</name>
              <bitOffset>0</bitOffset>
              <bitWidth>1</bitWidth>
            </field>
            <field>
              <name>MISF1</name>
              <bitOffset>1</bitOffset>
              <bitWidth>1</bitWidth>
            </field>
            <field>
              <name>MISF2</name>
              <bitOffset>2</bitOffset>
              <bitWidth>1</bitWidth>
            </field>
            <field>
              <name>MISF3</name>
              <bitOffset>3</bitOffset>
              <bitWidth>1</bitWidth>
            </field>
            <field>
              <name>MISF4</name>
              <bitOffset>4</bitOffset>
              <bitWidth>1</bitWidth>
            </field>
            <field>
              <name>MISF5</name>
              <bitOffset>5</bitOffset>
              <bitWidth>1</bitWidth>
            </field>
            <field>
              <name>MISF6</name>
              <bitOffset>6</bitOffset>
              <bitWidth>1</bitWidth>
            </field>
            <field>
              <name>MISF7</name>
              <bitOffset>7</bitOffset>
              <bitWidth>1</bitWidth>
            </field>
            <field>
              <name>MISF8</name>
              <bitOffset>8</bitOffset>
              <bitWidth>1</bitWidth>
            </field>
            <field>
              <name>MISF9</name>
              <bitOffset>9</bitOffset>
              <bitWidth>1</bitWidth>
            </field>
            <field>
              <name>MISF10</name>
              <bitOffset>10</bitOffset>
              <bitWidth>1</bitWidth>
            </field>
            <field>
              <name>MISF11</name>
              <bitOffset>11</bitOffset>
              <bitWidth>1</bitWidth>
            </field>
            <field>
              <name>MISF12</name>
              <bitOffset>12</bitOffset>
              <bitWidth>1</bitWidth>
            </field>
            <field>
              <name>MISF13</name>
              <bitOffset>13</bitOffset>
              <bitWidth>1</bitWidth>
            </field>
            <field>
              <name>MISF14</name>
              <bitOffset>14</bitOffset>
              <bitWidth>1</bitWidth>
            </field>
            <field>
              <name>MISF15</name>
              <bitOffset>15</bitOffset>
              <bitWidth>1</bitWidth>
            </field>
            <field>
              <name>MISF16</name>
              <bitOffset>16</bitOffset>
              <bitWidth>1</bitWidth>
            </field>
            <field>
              <name>MISF17</name>
              <bitOffset>17</bitOffset>
              <bitWidth>1</bitWidth>
            </field>
            <field>
              <name>MISF18</name>
              <bitOffset>18</bitOffset>
              <bitWidth>1</bitWidth>
            </field>
            <field>
              <name>MISF19</name>
              <bitOffset>19</bitOffset>
              <bitWidth>1</bitWidth>
            </field>
            <field>
              <name>MISF20</name>
              <bitOffset>20</bitOffset>
              <bitWidth>1</bitWidth>
            </field>
            <field>
              <name>MISF21</name>
              <bitOffset>21</bitOffset>
              <bitWidth>1</bitWidth>
            </field>
            <field>
              <name>MISF22</name>
              <bitOffset>22</bitOffset>
              <bitWidth>1</bitWidth>
            </field>
            <field>
              <name>MISF23</name>
              <bitOffset>23</bitOffset>
              <bitWidth>1</bitWidth>
            </field>
            <field>
              <name>MISF24</name>
              <bitOffset>24</bitOffset>
              <bitWidth>1</bitWidth>
            </field>
            <field>
              <name>MISF25</name>
              <bitOffset>25</bitOffset>
              <bitWidth>1</bitWidth>
            </field>
            <field>
              <name>MISF26</name>
              <bitOffset>26</bitOffset>
              <bitWidth>1</bitWidth>
            </field>
            <field>
              <name>MISF27</name>
              <bitOffset>27</bitOffset>
              <bitWidth>1</bitWidth>
            </field>
            <field>
              <name>MISF28</name>
              <bitOffset>28</bitOffset>
              <bitWidth>1</bitWidth>
            </field>
            <field>
              <name>MISF29</name>
              <bitOffset>29</bitOffset>
              <bitWidth>1</bitWidth>
            </field>
            <field>
              <name>MISF30</name>
              <bitOffset>30</bitOffset>
              <bitWidth>1</bitWidth>
            </field>
            <field>
              <name>MISF31</name>
              <bitOffset>31</bitOffset>
              <bitWidth>1</bitWidth>
            </field>
          </fields>
        </register>
        <register>
          <name>C2IER</name>
          <addressOffset>0x110</addressOffset>
          <size>0x20</size>
          <fields>
            <field>
              <name>ISE0</name>
              <bitOffset>0</bitOffset>
              <bitWidth>1</bitWidth>
            </field>
            <field>
              <name>ISE1</name>
              <bitOffset>1</bitOffset>
              <bitWidth>1</bitWidth>
            </field>
            <field>
              <name>ISE2</name>
              <bitOffset>2</bitOffset>
              <bitWidth>1</bitWidth>
            </field>
            <field>
              <name>ISE3</name>
              <bitOffset>3</bitOffset>
              <bitWidth>1</bitWidth>
            </field>
            <field>
              <name>ISE4</name>
              <bitOffset>4</bitOffset>
              <bitWidth>1</bitWidth>
            </field>
            <field>
              <name>ISE5</name>
              <bitOffset>5</bitOffset>
              <bitWidth>1</bitWidth>
            </field>
            <field>
              <name>ISE6</name>
              <bitOffset>6</bitOffset>
              <bitWidth>1</bitWidth>
            </field>
            <field>
              <name>ISE7</name>
              <bitOffset>7</bitOffset>
              <bitWidth>1</bitWidth>
            </field>
            <field>
              <name>ISE8</name>
              <bitOffset>8</bitOffset>
              <bitWidth>1</bitWidth>
            </field>
            <field>
              <name>ISE9</name>
              <bitOffset>9</bitOffset>
              <bitWidth>1</bitWidth>
            </field>
            <field>
              <name>ISE10</name>
              <bitOffset>10</bitOffset>
              <bitWidth>1</bitWidth>
            </field>
            <field>
              <name>ISE11</name>
              <bitOffset>11</bitOffset>
              <bitWidth>1</bitWidth>
            </field>
            <field>
              <name>ISE12</name>
              <bitOffset>12</bitOffset>
              <bitWidth>1</bitWidth>
            </field>
            <field>
              <name>ISE13</name>
              <bitOffset>13</bitOffset>
              <bitWidth>1</bitWidth>
            </field>
            <field>
              <name>ISE14</name>
              <bitOffset>14</bitOffset>
              <bitWidth>1</bitWidth>
            </field>
            <field>
              <name>ISE15</name>
              <bitOffset>15</bitOffset>
              <bitWidth>1</bitWidth>
            </field>
            <field>
              <name>ISE16</name>
              <bitOffset>16</bitOffset>
              <bitWidth>1</bitWidth>
            </field>
            <field>
              <name>ISE17</name>
              <bitOffset>17</bitOffset>
              <bitWidth>1</bitWidth>
            </field>
            <field>
              <name>ISE18</name>
              <bitOffset>18</bitOffset>
              <bitWidth>1</bitWidth>
            </field>
            <field>
              <name>ISE19</name>
              <bitOffset>19</bitOffset>
              <bitWidth>1</bitWidth>
            </field>
            <field>
              <name>ISE20</name>
              <bitOffset>20</bitOffset>
              <bitWidth>1</bitWidth>
            </field>
            <field>
              <name>ISE21</name>
              <bitOffset>21</bitOffset>
              <bitWidth>1</bitWidth>
            </field>
            <field>
              <name>ISE22</name>
              <bitOffset>22</bitOffset>
              <bitWidth>1</bitWidth>
            </field>
            <field>
              <name>ISE23</name>
              <bitOffset>23</bitOffset>
              <bitWidth>1</bitWidth>
            </field>
            <field>
              <name>ISE24</name>
              <bitOffset>24</bitOffset>
              <bitWidth>1</bitWidth>
            </field>
            <field>
              <name>ISE25</name>
              <bitOffset>25</bitOffset>
              <bitWidth>1</bitWidth>
            </field>
            <field>
              <name>ISE26</name>
              <bitOffset>26</bitOffset>
              <bitWidth>1</bitWidth>
            </field>
            <field>
              <name>ISE27</name>
              <bitOffset>27</bitOffset>
              <bitWidth>1</bitWidth>
            </field>
            <field>
              <name>ISE28</name>
              <bitOffset>28</bitOffset>
              <bitWidth>1</bitWidth>
            </field>
            <field>
              <name>ISE29</name>
              <bitOffset>29</bitOffset>
              <bitWidth>1</bitWidth>
            </field>
            <field>
              <name>ISE30</name>
              <bitOffset>30</bitOffset>
              <bitWidth>1</bitWidth>
            </field>
            <field>
              <name>ISE31</name>
              <bitOffset>31</bitOffset>
              <bitWidth>1</bitWidth>
            </field>
          </fields>
        </register>
        <register>
          <name>C2ICR</name>
          <addressOffset>0x114</addressOffset>
          <size>0x20</size>
          <fields>
            <field>
              <name>ISC0</name>
              <bitOffset>0</bitOffset>
              <bitWidth>1</bitWidth>
            </field>
            <field>
              <name>ISC1</name>
              <bitOffset>1</bitOffset>
              <bitWidth>1</bitWidth>
            </field>
            <field>
              <name>ISC2</name>
              <bitOffset>2</bitOffset>
              <bitWidth>1</bitWidth>
            </field>
            <field>
              <name>ISC3</name>
              <bitOffset>3</bitOffset>
              <bitWidth>1</bitWidth>
            </field>
            <field>
              <name>ISC4</name>
              <bitOffset>4</bitOffset>
              <bitWidth>1</bitWidth>
            </field>
            <field>
              <name>ISC5</name>
              <bitOffset>5</bitOffset>
              <bitWidth>1</bitWidth>
            </field>
            <field>
              <name>ISC6</name>
              <bitOffset>6</bitOffset>
              <bitWidth>1</bitWidth>
            </field>
            <field>
              <name>ISC7</name>
              <bitOffset>7</bitOffset>
              <bitWidth>1</bitWidth>
            </field>
            <field>
              <name>ISC8</name>
              <bitOffset>8</bitOffset>
              <bitWidth>1</bitWidth>
            </field>
            <field>
              <name>ISC9</name>
              <bitOffset>9</bitOffset>
              <bitWidth>1</bitWidth>
            </field>
            <field>
              <name>ISC10</name>
              <bitOffset>10</bitOffset>
              <bitWidth>1</bitWidth>
            </field>
            <field>
              <name>ISC11</name>
              <bitOffset>11</bitOffset>
              <bitWidth>1</bitWidth>
            </field>
            <field>
              <name>ISC12</name>
              <bitOffset>12</bitOffset>
              <bitWidth>1</bitWidth>
            </field>
            <field>
              <name>ISC13</name>
              <bitOffset>13</bitOffset>
              <bitWidth>1</bitWidth>
            </field>
            <field>
              <name>ISC14</name>
              <bitOffset>14</bitOffset>
              <bitWidth>1</bitWidth>
            </field>
            <field>
              <name>ISC15</name>
              <bitOffset>15</bitOffset>
              <bitWidth>1</bitWidth>
            </field>
            <field>
              <name>ISC16</name>
              <bitOffset>16</bitOffset>
              <bitWidth>1</bitWidth>
            </field>
            <field>
              <name>ISC17</name>
              <bitOffset>17</bitOffset>
              <bitWidth>1</bitWidth>
            </field>
            <field>
              <name>ISC18</name>
              <bitOffset>18</bitOffset>
              <bitWidth>1</bitWidth>
            </field>
            <field>
              <name>ISC19</name>
              <bitOffset>19</bitOffset>
              <bitWidth>1</bitWidth>
            </field>
            <field>
              <name>ISC20</name>
              <bitOffset>20</bitOffset>
              <bitWidth>1</bitWidth>
            </field>
            <field>
              <name>ISC21</name>
              <bitOffset>21</bitOffset>
              <bitWidth>1</bitWidth>
            </field>
            <field>
              <name>ISC22</name>
              <bitOffset>22</bitOffset>
              <bitWidth>1</bitWidth>
            </field>
            <field>
              <name>ISC23</name>
              <bitOffset>23</bitOffset>
              <bitWidth>1</bitWidth>
            </field>
            <field>
              <name>ISC24</name>
              <bitOffset>24</bitOffset>
              <bitWidth>1</bitWidth>
            </field>
            <field>
              <name>ISC25</name>
              <bitOffset>25</bitOffset>
              <bitWidth>1</bitWidth>
            </field>
            <field>
              <name>ISC26</name>
              <bitOffset>26</bitOffset>
              <bitWidth>1</bitWidth>
            </field>
            <field>
              <name>ISC27</name>
              <bitOffset>27</bitOffset>
              <bitWidth>1</bitWidth>
            </field>
            <field>
              <name>ISC28</name>
              <bitOffset>28</bitOffset>
              <bitWidth>1</bitWidth>
            </field>
            <field>
              <name>ISC29</name>
              <bitOffset>29</bitOffset>
              <bitWidth>1</bitWidth>
            </field>
            <field>
              <name>ISC30</name>
              <bitOffset>30</bitOffset>
              <bitWidth>1</bitWidth>
            </field>
            <field>
              <name>ISC31</name>
              <bitOffset>31</bitOffset>
              <bitWidth>1</bitWidth>
            </field>
          </fields>
        </register>
        <register>
          <name>C2ISR</name>
          <addressOffset>0x118</addressOffset>
          <size>0x20</size>
          <fields>
            <field>
              <name>ISF0</name>
              <bitOffset>0</bitOffset>
              <bitWidth>1</bitWidth>
            </field>
            <field>
              <name>ISF1</name>
              <bitOffset>1</bitOffset>
              <bitWidth>1</bitWidth>
            </field>
            <field>
              <name>ISF2</name>
              <bitOffset>2</bitOffset>
              <bitWidth>1</bitWidth>
            </field>
            <field>
              <name>ISF3</name>
              <bitOffset>3</bitOffset>
              <bitWidth>1</bitWidth>
            </field>
            <field>
              <name>ISF4</name>
              <bitOffset>4</bitOffset>
              <bitWidth>1</bitWidth>
            </field>
            <field>
              <name>ISF5</name>
              <bitOffset>5</bitOffset>
              <bitWidth>1</bitWidth>
            </field>
            <field>
              <name>ISF6</name>
              <bitOffset>6</bitOffset>
              <bitWidth>1</bitWidth>
            </field>
            <field>
              <name>ISF7</name>
              <bitOffset>7</bitOffset>
              <bitWidth>1</bitWidth>
            </field>
            <field>
              <name>ISF8</name>
              <bitOffset>8</bitOffset>
              <bitWidth>1</bitWidth>
            </field>
            <field>
              <name>ISF9</name>
              <bitOffset>9</bitOffset>
              <bitWidth>1</bitWidth>
            </field>
            <field>
              <name>ISF10</name>
              <bitOffset>10</bitOffset>
              <bitWidth>1</bitWidth>
            </field>
            <field>
              <name>ISF11</name>
              <bitOffset>11</bitOffset>
              <bitWidth>1</bitWidth>
            </field>
            <field>
              <name>ISF12</name>
              <bitOffset>12</bitOffset>
              <bitWidth>1</bitWidth>
            </field>
            <field>
              <name>ISF13</name>
              <bitOffset>13</bitOffset>
              <bitWidth>1</bitWidth>
            </field>
            <field>
              <name>ISF14</name>
              <bitOffset>14</bitOffset>
              <bitWidth>1</bitWidth>
            </field>
            <field>
              <name>ISF15</name>
              <bitOffset>15</bitOffset>
              <bitWidth>1</bitWidth>
            </field>
            <field>
              <name>ISF16</name>
              <bitOffset>16</bitOffset>
              <bitWidth>1</bitWidth>
            </field>
            <field>
              <name>ISF17</name>
              <bitOffset>17</bitOffset>
              <bitWidth>1</bitWidth>
            </field>
            <field>
              <name>ISF18</name>
              <bitOffset>18</bitOffset>
              <bitWidth>1</bitWidth>
            </field>
            <field>
              <name>ISF19</name>
              <bitOffset>19</bitOffset>
              <bitWidth>1</bitWidth>
            </field>
            <field>
              <name>ISF20</name>
              <bitOffset>20</bitOffset>
              <bitWidth>1</bitWidth>
            </field>
            <field>
              <name>ISF21</name>
              <bitOffset>21</bitOffset>
              <bitWidth>1</bitWidth>
            </field>
            <field>
              <name>ISF22</name>
              <bitOffset>22</bitOffset>
              <bitWidth>1</bitWidth>
            </field>
            <field>
              <name>ISF23</name>
              <bitOffset>23</bitOffset>
              <bitWidth>1</bitWidth>
            </field>
            <field>
              <name>ISF24</name>
              <bitOffset>24</bitOffset>
              <bitWidth>1</bitWidth>
            </field>
            <field>
              <name>ISF25</name>
              <bitOffset>25</bitOffset>
              <bitWidth>1</bitWidth>
            </field>
            <field>
              <name>ISF26</name>
              <bitOffset>26</bitOffset>
              <bitWidth>1</bitWidth>
            </field>
            <field>
              <name>ISF27</name>
              <bitOffset>27</bitOffset>
              <bitWidth>1</bitWidth>
            </field>
            <field>
              <name>ISF28</name>
              <bitOffset>28</bitOffset>
              <bitWidth>1</bitWidth>
            </field>
            <field>
              <name>ISF29</name>
              <bitOffset>29</bitOffset>
              <bitWidth>1</bitWidth>
            </field>
            <field>
              <name>ISF30</name>
              <bitOffset>30</bitOffset>
              <bitWidth>1</bitWidth>
            </field>
            <field>
              <name>ISF31</name>
              <bitOffset>31</bitOffset>
              <bitWidth>1</bitWidth>
            </field>
          </fields>
        </register>
        <register>
          <name>C2MISR</name>
          <addressOffset>0x11c</addressOffset>
          <size>0x20</size>
          <fields>
            <field>
              <name>MISF0</name>
              <bitOffset>0</bitOffset>
              <bitWidth>1</bitWidth>
            </field>
            <field>
              <name>MISF1</name>
              <bitOffset>1</bitOffset>
              <bitWidth>1</bitWidth>
            </field>
            <field>
              <name>MISF2</name>
              <bitOffset>2</bitOffset>
              <bitWidth>1</bitWidth>
            </field>
            <field>
              <name>MISF3</name>
              <bitOffset>3</bitOffset>
              <bitWidth>1</bitWidth>
            </field>
            <field>
              <name>MISF4</name>
              <bitOffset>4</bitOffset>
              <bitWidth>1</bitWidth>
            </field>
            <field>
              <name>MISF5</name>
              <bitOffset>5</bitOffset>
              <bitWidth>1</bitWidth>
            </field>
            <field>
              <name>MISF6</name>
              <bitOffset>6</bitOffset>
              <bitWidth>1</bitWidth>
            </field>
            <field>
              <name>MISF7</name>
              <bitOffset>7</bitOffset>
              <bitWidth>1</bitWidth>
            </field>
            <field>
              <name>MISF8</name>
              <bitOffset>8</bitOffset>
              <bitWidth>1</bitWidth>
            </field>
            <field>
              <name>MISF9</name>
              <bitOffset>9</bitOffset>
              <bitWidth>1</bitWidth>
            </field>
            <field>
              <name>MISF10</name>
              <bitOffset>10</bitOffset>
              <bitWidth>1</bitWidth>
            </field>
            <field>
              <name>MISF11</name>
              <bitOffset>11</bitOffset>
              <bitWidth>1</bitWidth>
            </field>
            <field>
              <name>MISF12</name>
              <bitOffset>12</bitOffset>
              <bitWidth>1</bitWidth>
            </field>
            <field>
              <name>MISF13</name>
              <bitOffset>13</bitOffset>
              <bitWidth>1</bitWidth>
            </field>
            <field>
              <name>MISF14</name>
              <bitOffset>14</bitOffset>
              <bitWidth>1</bitWidth>
            </field>
            <field>
              <name>MISF15</name>
              <bitOffset>15</bitOffset>
              <bitWidth>1</bitWidth>
            </field>
            <field>
              <name>MISF16</name>
              <bitOffset>16</bitOffset>
              <bitWidth>1</bitWidth>
            </field>
            <field>
              <name>MISF17</name>
              <bitOffset>17</bitOffset>
              <bitWidth>1</bitWidth>
            </field>
            <field>
              <name>MISF18</name>
              <bitOffset>18</bitOffset>
              <bitWidth>1</bitWidth>
            </field>
            <field>
              <name>MISF19</name>
              <bitOffset>19</bitOffset>
              <bitWidth>1</bitWidth>
            </field>
            <field>
              <name>MISF20</name>
              <bitOffset>20</bitOffset>
              <bitWidth>1</bitWidth>
            </field>
            <field>
              <name>MISF21</name>
              <bitOffset>21</bitOffset>
              <bitWidth>1</bitWidth>
            </field>
            <field>
              <name>MISF22</name>
              <bitOffset>22</bitOffset>
              <bitWidth>1</bitWidth>
            </field>
            <field>
              <name>MISF23</name>
              <bitOffset>23</bitOffset>
              <bitWidth>1</bitWidth>
            </field>
            <field>
              <name>MISF24</name>
              <bitOffset>24</bitOffset>
              <bitWidth>1</bitWidth>
            </field>
            <field>
              <name>MISF25</name>
              <bitOffset>25</bitOffset>
              <bitWidth>1</bitWidth>
            </field>
            <field>
              <name>MISF26</name>
              <bitOffset>26</bitOffset>
              <bitWidth>1</bitWidth>
            </field>
            <field>
              <name>MISF27</name>
              <bitOffset>27</bitOffset>
              <bitWidth>1</bitWidth>
            </field>
            <field>
              <name>MISF28</name>
              <bitOffset>28</bitOffset>
              <bitWidth>1</bitWidth>
            </field>
            <field>
              <name>MISF29</name>
              <bitOffset>29</bitOffset>
              <bitWidth>1</bitWidth>
            </field>
            <field>
              <name>MISF30</name>
              <bitOffset>30</bitOffset>
              <bitWidth>1</bitWidth>
            </field>
            <field>
              <name>MISF31</name>
              <bitOffset>31</bitOffset>
              <bitWidth>1</bitWidth>
            </field>
          </fields>
        </register>
        <register>
          <name>CR</name>
          <addressOffset>0x140</addressOffset>
          <size>0x20</size>
          <fields>
            <field>
              <name>COREID</name>
              <bitOffset>8</bitOffset>
              <bitWidth>8</bitWidth>
            </field>
            <field>
              <name>KEY</name>
              <bitOffset>16</bitOffset>
              <bitWidth>16</bitWidth>
            </field>
          </fields>
        </register>
        <register>
          <name>KEYR</name>
          <addressOffset>0x144</addressOffset>
          <size>0x20</size>
          <fields>
            <field>
              <name>KEY</name>
              <bitOffset>16</bitOffset>
              <bitWidth>16</bitWidth>
            </field>
          </fields>
        </register>
      </registers>
    </peripheral>
    <peripheral>
      <name>HSEM_COMMON</name>
      <baseAddress>0x58026510</baseAddress>
      <registers>
        <register>
          <name>IER</name>
          <addressOffset>0x0</addressOffset>
          <size>0x20</size>
        </register>
        <register>
          <name>ICR</name>
          <addressOffset>0x4</addressOffset>
          <size>0x20</size>
        </register>
        <register>
          <name>ISR</name>
          <addressOffset>0x8</addressOffset>
          <size>0x20</size>
        </register>
        <register>
          <name>MISR</name>
          <addressOffset>0xc</addressOffset>
          <size>0x20</size>
        </register>
      </registers>
    </peripheral>
    <peripheral>
      <name>RAMECC3</name>
      <baseAddress>0x58027000</baseAddress>
      <registers>
        <register>
          <name>IER</name>
          <addressOffset>0x0</addressOffset>
          <size>0x20</size>
          <fields>
            <field>
              <name>GIE</name>
              <bitOffset>0</bitOffset>
              <bitWidth>1</bitWidth>
            </field>
            <field>
              <name>GECCSEIE</name>
              <bitOffset>1</bitOffset>
              <bitWidth>1</bitWidth>
            </field>
            <field>
              <name>GECCDEIE</name>
              <bitOffset>2</bitOffset>
              <bitWidth>1</bitWidth>
            </field>
            <field>
              <name>GECCDEBWIE</name>
              <bitOffset>3</bitOffset>
              <bitWidth>1</bitWidth>
            </field>
          </fields>
        </register>
        <register>
          <name>CR1</name>
          <addressOffset>0x20</addressOffset>
          <size>0x20</size>
          <fields>
            <field>
              <name>ECCSEIE</name>
              <bitOffset>2</bitOffset>
              <bitWidth>1</bitWidth>
            </field>
            <field>
              <name>ECCDEIE</name>
              <bitOffset>3</bitOffset>
              <bitWidth>1</bitWidth>
            </field>
            <field>
              <name>ECCDEBWIE</name>
              <bitOffset>4</bitOffset>
              <bitWidth>1</bitWidth>
            </field>
            <field>
              <name>ECCELEN</name>
              <bitOffset>5</bitOffset>
              <bitWidth>1</bitWidth>
            </field>
          </fields>
        </register>
        <register>
          <name>CR1</name>
          <addressOffset>0x20</addressOffset>
          <size>0x20</size>
          <fields>
            <field>
              <name>ECCSEIE</name>
              <bitOffset>2</bitOffset>
              <bitWidth>1</bitWidth>
            </field>
            <field>
              <name>ECCDEIE</name>
              <bitOffset>3</bitOffset>
              <bitWidth>1</bitWidth>
            </field>
            <field>
              <name>ECCDEBWIE</name>
              <bitOffset>4</bitOffset>
              <bitWidth>1</bitWidth>
            </field>
            <field>
              <name>ECCELEN</name>
              <bitOffset>5</bitOffset>
              <bitWidth>1</bitWidth>
            </field>
          </fields>
        </register>
        <register>
          <name>CR1</name>
          <addressOffset>0x20</addressOffset>
          <size>0x20</size>
          <fields>
            <field>
              <name>ECCSEIE</name>
              <bitOffset>2</bitOffset>
              <bitWidth>1</bitWidth>
            </field>
            <field>
              <name>ECCDEIE</name>
              <bitOffset>3</bitOffset>
              <bitWidth>1</bitWidth>
            </field>
            <field>
              <name>ECCDEBWIE</name>
              <bitOffset>4</bitOffset>
              <bitWidth>1</bitWidth>
            </field>
            <field>
              <name>ECCELEN</name>
              <bitOffset>5</bitOffset>
              <bitWidth>1</bitWidth>
            </field>
          </fields>
        </register>
        <register>
          <name>SR1</name>
          <addressOffset>0x24</addressOffset>
          <size>0x20</size>
          <fields>
            <field>
              <name>SEDCF</name>
              <bitOffset>0</bitOffset>
              <bitWidth>1</bitWidth>
            </field>
            <field>
              <name>DEDF</name>
              <bitOffset>1</bitOffset>
              <bitWidth>1</bitWidth>
            </field>
            <field>
              <name>DEBWDF</name>
              <bitOffset>2</bitOffset>
              <bitWidth>1</bitWidth>
            </field>
          </fields>
        </register>
        <register>
          <name>SR1</name>
          <addressOffset>0x24</addressOffset>
          <size>0x20</size>
          <fields>
            <field>
              <name>SEDCF</name>
              <bitOffset>0</bitOffset>
              <bitWidth>1</bitWidth>
            </field>
            <field>
              <name>DEDF</name>
              <bitOffset>1</bitOffset>
              <bitWidth>1</bitWidth>
            </field>
            <field>
              <name>DEBWDF</name>
              <bitOffset>2</bitOffset>
              <bitWidth>1</bitWidth>
            </field>
          </fields>
        </register>
        <register>
          <name>SR1</name>
          <addressOffset>0x24</addressOffset>
          <size>0x20</size>
          <fields>
            <field>
              <name>SEDCF</name>
              <bitOffset>0</bitOffset>
              <bitWidth>1</bitWidth>
            </field>
            <field>
              <name>DEDF</name>
              <bitOffset>1</bitOffset>
              <bitWidth>1</bitWidth>
            </field>
            <field>
              <name>DEBWDF</name>
              <bitOffset>2</bitOffset>
              <bitWidth>1</bitWidth>
            </field>
          </fields>
        </register>
        <register>
          <name>FAR1</name>
          <addressOffset>0x28</addressOffset>
          <size>0x20</size>
          <fields>
            <field>
              <name>FDATAL</name>
              <bitOffset>0</bitOffset>
              <bitWidth>32</bitWidth>
            </field>
          </fields>
        </register>
        <register>
          <name>FAR1</name>
          <addressOffset>0x28</addressOffset>
          <size>0x20</size>
          <fields>
            <field>
              <name>FDATAL</name>
              <bitOffset>0</bitOffset>
              <bitWidth>32</bitWidth>
            </field>
          </fields>
        </register>
        <register>
          <name>FAR1</name>
          <addressOffset>0x28</addressOffset>
          <size>0x20</size>
          <fields>
            <field>
              <name>FDATAL</name>
              <bitOffset>0</bitOffset>
              <bitWidth>32</bitWidth>
            </field>
          </fields>
        </register>
        <register>
          <name>FDRL1</name>
          <addressOffset>0x2c</addressOffset>
          <size>0x20</size>
        </register>
        <register>
          <name>FDRL1</name>
          <addressOffset>0x2c</addressOffset>
          <size>0x20</size>
        </register>
        <register>
          <name>FDRL1</name>
          <addressOffset>0x2c</addressOffset>
          <size>0x20</size>
        </register>
        <register>
          <name>FDRH1</name>
          <addressOffset>0x30</addressOffset>
          <size>0x20</size>
        </register>
        <register>
          <name>FDRH1</name>
          <addressOffset>0x30</addressOffset>
          <size>0x20</size>
        </register>
        <register>
          <name>FDRH1</name>
          <addressOffset>0x30</addressOffset>
          <size>0x20</size>
        </register>
        <register>
          <name>FECR1</name>
          <addressOffset>0x34</addressOffset>
          <size>0x20</size>
          <fields>
            <field>
              <name>FEC</name>
              <bitOffset>0</bitOffset>
              <bitWidth>32</bitWidth>
            </field>
          </fields>
        </register>
        <register>
          <name>FECR1</name>
          <addressOffset>0x34</addressOffset>
          <size>0x20</size>
          <fields>
            <field>
              <name>FEC</name>
              <bitOffset>0</bitOffset>
              <bitWidth>32</bitWidth>
            </field>
          </fields>
        </register>
        <register>
          <name>FECR1</name>
          <addressOffset>0x34</addressOffset>
          <size>0x20</size>
          <fields>
            <field>
              <name>FEC</name>
              <bitOffset>0</bitOffset>
              <bitWidth>32</bitWidth>
            </field>
          </fields>
        </register>
        <register>
          <name>CR2</name>
          <addressOffset>0x40</addressOffset>
          <size>0x20</size>
          <fields>
            <field>
              <name>ECCSEIE</name>
              <bitOffset>2</bitOffset>
              <bitWidth>1</bitWidth>
            </field>
            <field>
              <name>ECCDEIE</name>
              <bitOffset>3</bitOffset>
              <bitWidth>1</bitWidth>
            </field>
            <field>
              <name>ECCDEBWIE</name>
              <bitOffset>4</bitOffset>
              <bitWidth>1</bitWidth>
            </field>
            <field>
              <name>ECCELEN</name>
              <bitOffset>5</bitOffset>
              <bitWidth>1</bitWidth>
            </field>
          </fields>
        </register>
        <register>
          <name>CR2</name>
          <addressOffset>0x40</addressOffset>
          <size>0x20</size>
          <fields>
            <field>
              <name>ECCSEIE</name>
              <bitOffset>2</bitOffset>
              <bitWidth>1</bitWidth>
            </field>
            <field>
              <name>ECCDEIE</name>
              <bitOffset>3</bitOffset>
              <bitWidth>1</bitWidth>
            </field>
            <field>
              <name>ECCDEBWIE</name>
              <bitOffset>4</bitOffset>
              <bitWidth>1</bitWidth>
            </field>
            <field>
              <name>ECCELEN</name>
              <bitOffset>5</bitOffset>
              <bitWidth>1</bitWidth>
            </field>
          </fields>
        </register>
        <register>
          <name>CR2</name>
          <addressOffset>0x40</addressOffset>
          <size>0x20</size>
          <fields>
            <field>
              <name>ECCSEIE</name>
              <bitOffset>2</bitOffset>
              <bitWidth>1</bitWidth>
            </field>
            <field>
              <name>ECCDEIE</name>
              <bitOffset>3</bitOffset>
              <bitWidth>1</bitWidth>
            </field>
            <field>
              <name>ECCDEBWIE</name>
              <bitOffset>4</bitOffset>
              <bitWidth>1</bitWidth>
            </field>
            <field>
              <name>ECCELEN</name>
              <bitOffset>5</bitOffset>
              <bitWidth>1</bitWidth>
            </field>
          </fields>
        </register>
        <register>
          <name>SR2</name>
          <addressOffset>0x44</addressOffset>
          <size>0x20</size>
          <fields>
            <field>
              <name>SEDCF</name>
              <bitOffset>0</bitOffset>
              <bitWidth>1</bitWidth>
            </field>
            <field>
              <name>DEDF</name>
              <bitOffset>1</bitOffset>
              <bitWidth>1</bitWidth>
            </field>
            <field>
              <name>DEBWDF</name>
              <bitOffset>2</bitOffset>
              <bitWidth>1</bitWidth>
            </field>
          </fields>
        </register>
        <register>
          <name>SR2</name>
          <addressOffset>0x44</addressOffset>
          <size>0x20</size>
          <fields>
            <field>
              <name>SEDCF</name>
              <bitOffset>0</bitOffset>
              <bitWidth>1</bitWidth>
            </field>
            <field>
              <name>DEDF</name>
              <bitOffset>1</bitOffset>
              <bitWidth>1</bitWidth>
            </field>
            <field>
              <name>DEBWDF</name>
              <bitOffset>2</bitOffset>
              <bitWidth>1</bitWidth>
            </field>
          </fields>
        </register>
        <register>
          <name>SR2</name>
          <addressOffset>0x44</addressOffset>
          <size>0x20</size>
          <fields>
            <field>
              <name>SEDCF</name>
              <bitOffset>0</bitOffset>
              <bitWidth>1</bitWidth>
            </field>
            <field>
              <name>DEDF</name>
              <bitOffset>1</bitOffset>
              <bitWidth>1</bitWidth>
            </field>
            <field>
              <name>DEBWDF</name>
              <bitOffset>2</bitOffset>
              <bitWidth>1</bitWidth>
            </field>
          </fields>
        </register>
        <register>
          <name>FAR2</name>
          <addressOffset>0x48</addressOffset>
          <size>0x20</size>
          <fields>
            <field>
              <name>FDATAL</name>
              <bitOffset>0</bitOffset>
              <bitWidth>32</bitWidth>
            </field>
          </fields>
        </register>
        <register>
          <name>FAR2</name>
          <addressOffset>0x48</addressOffset>
          <size>0x20</size>
          <fields>
            <field>
              <name>FDATAL</name>
              <bitOffset>0</bitOffset>
              <bitWidth>32</bitWidth>
            </field>
          </fields>
        </register>
        <register>
          <name>FAR2</name>
          <addressOffset>0x48</addressOffset>
          <size>0x20</size>
          <fields>
            <field>
              <name>FDATAL</name>
              <bitOffset>0</bitOffset>
              <bitWidth>32</bitWidth>
            </field>
          </fields>
        </register>
        <register>
          <name>FDRL2</name>
          <addressOffset>0x4c</addressOffset>
          <size>0x20</size>
        </register>
        <register>
          <name>FDRL2</name>
          <addressOffset>0x4c</addressOffset>
          <size>0x20</size>
        </register>
        <register>
          <name>FDRL2</name>
          <addressOffset>0x4c</addressOffset>
          <size>0x20</size>
        </register>
        <register>
          <name>FDRH2</name>
          <addressOffset>0x50</addressOffset>
          <size>0x20</size>
        </register>
        <register>
          <name>FDRH2</name>
          <addressOffset>0x50</addressOffset>
          <size>0x20</size>
        </register>
        <register>
          <name>FDRH2</name>
          <addressOffset>0x50</addressOffset>
          <size>0x20</size>
        </register>
        <register>
          <name>FECR2</name>
          <addressOffset>0x54</addressOffset>
          <size>0x20</size>
          <fields>
            <field>
              <name>FEC</name>
              <bitOffset>0</bitOffset>
              <bitWidth>32</bitWidth>
            </field>
          </fields>
        </register>
        <register>
          <name>FECR2</name>
          <addressOffset>0x54</addressOffset>
          <size>0x20</size>
          <fields>
            <field>
              <name>FEC</name>
              <bitOffset>0</bitOffset>
              <bitWidth>32</bitWidth>
            </field>
          </fields>
        </register>
        <register>
          <name>FECR2</name>
          <addressOffset>0x54</addressOffset>
          <size>0x20</size>
          <fields>
            <field>
              <name>FEC</name>
              <bitOffset>0</bitOffset>
              <bitWidth>32</bitWidth>
            </field>
          </fields>
        </register>
        <register>
          <name>CR3</name>
          <addressOffset>0x60</addressOffset>
          <size>0x20</size>
          <fields>
            <field>
              <name>ECCSEIE</name>
              <bitOffset>2</bitOffset>
              <bitWidth>1</bitWidth>
            </field>
            <field>
              <name>ECCDEIE</name>
              <bitOffset>3</bitOffset>
              <bitWidth>1</bitWidth>
            </field>
            <field>
              <name>ECCDEBWIE</name>
              <bitOffset>4</bitOffset>
              <bitWidth>1</bitWidth>
            </field>
            <field>
              <name>ECCELEN</name>
              <bitOffset>5</bitOffset>
              <bitWidth>1</bitWidth>
            </field>
          </fields>
        </register>
        <register>
          <name>CR3</name>
          <addressOffset>0x60</addressOffset>
          <size>0x20</size>
          <fields>
            <field>
              <name>ECCSEIE</name>
              <bitOffset>2</bitOffset>
              <bitWidth>1</bitWidth>
            </field>
            <field>
              <name>ECCDEIE</name>
              <bitOffset>3</bitOffset>
              <bitWidth>1</bitWidth>
            </field>
            <field>
              <name>ECCDEBWIE</name>
              <bitOffset>4</bitOffset>
              <bitWidth>1</bitWidth>
            </field>
            <field>
              <name>ECCELEN</name>
              <bitOffset>5</bitOffset>
              <bitWidth>1</bitWidth>
            </field>
          </fields>
        </register>
        <register>
          <name>SR3</name>
          <addressOffset>0x64</addressOffset>
          <size>0x20</size>
          <fields>
            <field>
              <name>SEDCF</name>
              <bitOffset>0</bitOffset>
              <bitWidth>1</bitWidth>
            </field>
            <field>
              <name>DEDF</name>
              <bitOffset>1</bitOffset>
              <bitWidth>1</bitWidth>
            </field>
            <field>
              <name>DEBWDF</name>
              <bitOffset>2</bitOffset>
              <bitWidth>1</bitWidth>
            </field>
          </fields>
        </register>
        <register>
          <name>SR3</name>
          <addressOffset>0x64</addressOffset>
          <size>0x20</size>
          <fields>
            <field>
              <name>SEDCF</name>
              <bitOffset>0</bitOffset>
              <bitWidth>1</bitWidth>
            </field>
            <field>
              <name>DEDF</name>
              <bitOffset>1</bitOffset>
              <bitWidth>1</bitWidth>
            </field>
            <field>
              <name>DEBWDF</name>
              <bitOffset>2</bitOffset>
              <bitWidth>1</bitWidth>
            </field>
          </fields>
        </register>
        <register>
          <name>FAR3</name>
          <addressOffset>0x68</addressOffset>
          <size>0x20</size>
          <fields>
            <field>
              <name>FDATAL</name>
              <bitOffset>0</bitOffset>
              <bitWidth>32</bitWidth>
            </field>
          </fields>
        </register>
        <register>
          <name>FAR3</name>
          <addressOffset>0x68</addressOffset>
          <size>0x20</size>
          <fields>
            <field>
              <name>FDATAL</name>
              <bitOffset>0</bitOffset>
              <bitWidth>32</bitWidth>
            </field>
          </fields>
        </register>
        <register>
          <name>FDRL3</name>
          <addressOffset>0x6c</addressOffset>
          <size>0x20</size>
        </register>
        <register>
          <name>FDRL3</name>
          <addressOffset>0x6c</addressOffset>
          <size>0x20</size>
        </register>
        <register>
          <name>FDRH3</name>
          <addressOffset>0x70</addressOffset>
          <size>0x20</size>
        </register>
        <register>
          <name>FDRH3</name>
          <addressOffset>0x70</addressOffset>
          <size>0x20</size>
        </register>
        <register>
          <name>FECR3</name>
          <addressOffset>0x74</addressOffset>
          <size>0x20</size>
          <fields>
            <field>
              <name>FEC</name>
              <bitOffset>0</bitOffset>
              <bitWidth>32</bitWidth>
            </field>
          </fields>
        </register>
        <register>
          <name>FECR3</name>
          <addressOffset>0x74</addressOffset>
          <size>0x20</size>
          <fields>
            <field>
              <name>FEC</name>
              <bitOffset>0</bitOffset>
              <bitWidth>32</bitWidth>
            </field>
          </fields>
        </register>
        <register>
          <name>CR4</name>
          <addressOffset>0x80</addressOffset>
          <size>0x20</size>
          <fields>
            <field>
              <name>ECCSEIE</name>
              <bitOffset>2</bitOffset>
              <bitWidth>1</bitWidth>
            </field>
            <field>
              <name>ECCDEIE</name>
              <bitOffset>3</bitOffset>
              <bitWidth>1</bitWidth>
            </field>
            <field>
              <name>ECCDEBWIE</name>
              <bitOffset>4</bitOffset>
              <bitWidth>1</bitWidth>
            </field>
            <field>
              <name>ECCELEN</name>
              <bitOffset>5</bitOffset>
              <bitWidth>1</bitWidth>
            </field>
          </fields>
        </register>
        <register>
          <name>CR4</name>
          <addressOffset>0x80</addressOffset>
          <size>0x20</size>
          <fields>
            <field>
              <name>ECCSEIE</name>
              <bitOffset>2</bitOffset>
              <bitWidth>1</bitWidth>
            </field>
            <field>
              <name>ECCDEIE</name>
              <bitOffset>3</bitOffset>
              <bitWidth>1</bitWidth>
            </field>
            <field>
              <name>ECCDEBWIE</name>
              <bitOffset>4</bitOffset>
              <bitWidth>1</bitWidth>
            </field>
            <field>
              <name>ECCELEN</name>
              <bitOffset>5</bitOffset>
              <bitWidth>1</bitWidth>
            </field>
          </fields>
        </register>
        <register>
          <name>SR4</name>
          <addressOffset>0x84</addressOffset>
          <size>0x20</size>
          <fields>
            <field>
              <name>SEDCF</name>
              <bitOffset>0</bitOffset>
              <bitWidth>1</bitWidth>
            </field>
            <field>
              <name>DEDF</name>
              <bitOffset>1</bitOffset>
              <bitWidth>1</bitWidth>
            </field>
            <field>
              <name>DEBWDF</name>
              <bitOffset>2</bitOffset>
              <bitWidth>1</bitWidth>
            </field>
          </fields>
        </register>
        <register>
          <name>SR4</name>
          <addressOffset>0x84</addressOffset>
          <size>0x20</size>
          <fields>
            <field>
              <name>SEDCF</name>
              <bitOffset>0</bitOffset>
              <bitWidth>1</bitWidth>
            </field>
            <field>
              <name>DEDF</name>
              <bitOffset>1</bitOffset>
              <bitWidth>1</bitWidth>
            </field>
            <field>
              <name>DEBWDF</name>
              <bitOffset>2</bitOffset>
              <bitWidth>1</bitWidth>
            </field>
          </fields>
        </register>
        <register>
          <name>FAR4</name>
          <addressOffset>0x88</addressOffset>
          <size>0x20</size>
          <fields>
            <field>
              <name>FDATAL</name>
              <bitOffset>0</bitOffset>
              <bitWidth>32</bitWidth>
            </field>
          </fields>
        </register>
        <register>
          <name>FAR4</name>
          <addressOffset>0x88</addressOffset>
          <size>0x20</size>
          <fields>
            <field>
              <name>FDATAL</name>
              <bitOffset>0</bitOffset>
              <bitWidth>32</bitWidth>
            </field>
          </fields>
        </register>
        <register>
          <name>FDRL4</name>
          <addressOffset>0x8c</addressOffset>
          <size>0x20</size>
        </register>
        <register>
          <name>FDRL4</name>
          <addressOffset>0x8c</addressOffset>
          <size>0x20</size>
        </register>
        <register>
          <name>FDRH4</name>
          <addressOffset>0x90</addressOffset>
          <size>0x20</size>
        </register>
        <register>
          <name>FDRH4</name>
          <addressOffset>0x90</addressOffset>
          <size>0x20</size>
        </register>
        <register>
          <name>FECR4</name>
          <addressOffset>0x94</addressOffset>
          <size>0x20</size>
          <fields>
            <field>
              <name>FEC</name>
              <bitOffset>0</bitOffset>
              <bitWidth>32</bitWidth>
            </field>
          </fields>
        </register>
        <register>
          <name>FECR4</name>
          <addressOffset>0x94</addressOffset>
          <size>0x20</size>
          <fields>
            <field>
              <name>FEC</name>
              <bitOffset>0</bitOffset>
              <bitWidth>32</bitWidth>
            </field>
          </fields>
        </register>
        <register>
          <name>CR5</name>
          <addressOffset>0xa0</addressOffset>
          <size>0x20</size>
          <fields>
            <field>
              <name>ECCSEIE</name>
              <bitOffset>2</bitOffset>
              <bitWidth>1</bitWidth>
            </field>
            <field>
              <name>ECCDEIE</name>
              <bitOffset>3</bitOffset>
              <bitWidth>1</bitWidth>
            </field>
            <field>
              <name>ECCDEBWIE</name>
              <bitOffset>4</bitOffset>
              <bitWidth>1</bitWidth>
            </field>
            <field>
              <name>ECCELEN</name>
              <bitOffset>5</bitOffset>
              <bitWidth>1</bitWidth>
            </field>
          </fields>
        </register>
        <register>
          <name>CR5</name>
          <addressOffset>0xa0</addressOffset>
          <size>0x20</size>
          <fields>
            <field>
              <name>ECCSEIE</name>
              <bitOffset>2</bitOffset>
              <bitWidth>1</bitWidth>
            </field>
            <field>
              <name>ECCDEIE</name>
              <bitOffset>3</bitOffset>
              <bitWidth>1</bitWidth>
            </field>
            <field>
              <name>ECCDEBWIE</name>
              <bitOffset>4</bitOffset>
              <bitWidth>1</bitWidth>
            </field>
            <field>
              <name>ECCELEN</name>
              <bitOffset>5</bitOffset>
              <bitWidth>1</bitWidth>
            </field>
          </fields>
        </register>
        <register>
          <name>SR5</name>
          <addressOffset>0xa4</addressOffset>
          <size>0x20</size>
          <fields>
            <field>
              <name>SEDCF</name>
              <bitOffset>0</bitOffset>
              <bitWidth>1</bitWidth>
            </field>
            <field>
              <name>DEDF</name>
              <bitOffset>1</bitOffset>
              <bitWidth>1</bitWidth>
            </field>
            <field>
              <name>DEBWDF</name>
              <bitOffset>2</bitOffset>
              <bitWidth>1</bitWidth>
            </field>
          </fields>
        </register>
        <register>
          <name>SR5</name>
          <addressOffset>0xa4</addressOffset>
          <size>0x20</size>
          <fields>
            <field>
              <name>SEDCF</name>
              <bitOffset>0</bitOffset>
              <bitWidth>1</bitWidth>
            </field>
            <field>
              <name>DEDF</name>
              <bitOffset>1</bitOffset>
              <bitWidth>1</bitWidth>
            </field>
            <field>
              <name>DEBWDF</name>
              <bitOffset>2</bitOffset>
              <bitWidth>1</bitWidth>
            </field>
          </fields>
        </register>
        <register>
          <name>FAR5</name>
          <addressOffset>0xa8</addressOffset>
          <size>0x20</size>
          <fields>
            <field>
              <name>FDATAL</name>
              <bitOffset>0</bitOffset>
              <bitWidth>32</bitWidth>
            </field>
          </fields>
        </register>
        <register>
          <name>FAR5</name>
          <addressOffset>0xa8</addressOffset>
          <size>0x20</size>
          <fields>
            <field>
              <name>FDATAL</name>
              <bitOffset>0</bitOffset>
              <bitWidth>32</bitWidth>
            </field>
          </fields>
        </register>
        <register>
          <name>FDRL5</name>
          <addressOffset>0xac</addressOffset>
          <size>0x20</size>
        </register>
        <register>
          <name>FDRL5</name>
          <addressOffset>0xac</addressOffset>
          <size>0x20</size>
        </register>
        <register>
          <name>FDRH5</name>
          <addressOffset>0xb0</addressOffset>
          <size>0x20</size>
        </register>
        <register>
          <name>FDRH5</name>
          <addressOffset>0xb0</addressOffset>
          <size>0x20</size>
        </register>
        <register>
          <name>FECR5</name>
          <addressOffset>0xb4</addressOffset>
          <size>0x20</size>
          <fields>
            <field>
              <name>FEC</name>
              <bitOffset>0</bitOffset>
              <bitWidth>32</bitWidth>
            </field>
          </fields>
        </register>
        <register>
          <name>FECR5</name>
          <addressOffset>0xb4</addressOffset>
          <size>0x20</size>
          <fields>
            <field>
              <name>FEC</name>
              <bitOffset>0</bitOffset>
              <bitWidth>32</bitWidth>
            </field>
          </fields>
        </register>
      </registers>
    </peripheral>
    <peripheral>
      <name>DBGMCU</name>
      <baseAddress>0x5c001000</baseAddress>
      <registers>
        <register>
          <name>IDCODE</name>
          <addressOffset>0x0</addressOffset>
          <size>0x20</size>
          <fields>
            <field>
              <name>DEV_ID</name>
              <bitOffset>0</bitOffset>
              <bitWidth>12</bitWidth>
            </field>
            <field>
              <name>REV_ID</name>
              <bitOffset>16</bitOffset>
              <bitWidth>16</bitWidth>
            </field>
          </fields>
        </register>
        <register>
          <name>CR</name>
          <addressOffset>0x4</addressOffset>
          <size>0x20</size>
          <fields>
            <field>
              <name>DBG_SLEEPD1</name>
              <bitOffset>0</bitOffset>
              <bitWidth>1</bitWidth>
            </field>
            <field>
              <name>DBG_STOPD1</name>
              <bitOffset>1</bitOffset>
              <bitWidth>1</bitWidth>
            </field>
            <field>
              <name>DBG_STANDBYD1</name>
              <bitOffset>2</bitOffset>
              <bitWidth>1</bitWidth>
            </field>
            <field>
              <name>DBG_SLEEPD2</name>
              <bitOffset>3</bitOffset>
              <bitWidth>1</bitWidth>
            </field>
            <field>
              <name>DBG_STOPD2</name>
              <bitOffset>4</bitOffset>
              <bitWidth>1</bitWidth>
            </field>
            <field>
              <name>DBG_STANDBYD2</name>
              <bitOffset>5</bitOffset>
              <bitWidth>1</bitWidth>
            </field>
            <field>
              <name>DBG_TRACECKEN</name>
              <bitOffset>20</bitOffset>
              <bitWidth>1</bitWidth>
            </field>
            <field>
              <name>DBG_CKD1EN</name>
              <bitOffset>21</bitOffset>
              <bitWidth>1</bitWidth>
            </field>
            <field>
              <name>DBG_CKD3EN</name>
              <bitOffset>22</bitOffset>
              <bitWidth>1</bitWidth>
            </field>
            <field>
              <name>DBG_TRGOEN</name>
              <bitOffset>28</bitOffset>
              <bitWidth>1</bitWidth>
            </field>
          </fields>
        </register>
        <register>
          <name>APB3FZ1</name>
          <addressOffset>0x34</addressOffset>
          <size>0x20</size>
          <fields>
            <field>
              <name>DBG_WWDG1</name>
              <bitOffset>6</bitOffset>
              <bitWidth>1</bitWidth>
            </field>
          </fields>
        </register>
        <register>
          <name>APB3FZ2</name>
          <addressOffset>0x38</addressOffset>
          <size>0x20</size>
          <fields>
            <field>
              <name>DBG_WWDG1</name>
              <bitOffset>6</bitOffset>
              <bitWidth>1</bitWidth>
            </field>
          </fields>
        </register>
        <register>
          <name>APB1LFZ1</name>
          <addressOffset>0x3c</addressOffset>
          <size>0x20</size>
          <fields>
            <field>
              <name>DBG_TIM2</name>
              <bitOffset>0</bitOffset>
              <bitWidth>1</bitWidth>
            </field>
            <field>
              <name>DBG_TIM3</name>
              <bitOffset>1</bitOffset>
              <bitWidth>1</bitWidth>
            </field>
            <field>
              <name>DBG_TIM4</name>
              <bitOffset>2</bitOffset>
              <bitWidth>1</bitWidth>
            </field>
            <field>
              <name>DBG_TIM5</name>
              <bitOffset>3</bitOffset>
              <bitWidth>1</bitWidth>
            </field>
            <field>
              <name>DBG_TIM6</name>
              <bitOffset>4</bitOffset>
              <bitWidth>1</bitWidth>
            </field>
            <field>
              <name>DBG_TIM7</name>
              <bitOffset>5</bitOffset>
              <bitWidth>1</bitWidth>
            </field>
            <field>
              <name>DBG_TIM12</name>
              <bitOffset>6</bitOffset>
              <bitWidth>1</bitWidth>
            </field>
            <field>
              <name>DBG_TIM13</name>
              <bitOffset>7</bitOffset>
              <bitWidth>1</bitWidth>
            </field>
            <field>
              <name>DBG_TIM14</name>
              <bitOffset>8</bitOffset>
              <bitWidth>1</bitWidth>
            </field>
            <field>
              <name>DBG_LPTIM1</name>
              <bitOffset>9</bitOffset>
              <bitWidth>1</bitWidth>
            </field>
            <field>
              <name>DBG_WWDG2</name>
              <bitOffset>11</bitOffset>
              <bitWidth>1</bitWidth>
            </field>
            <field>
              <name>DBG_I2C1</name>
              <bitOffset>21</bitOffset>
              <bitWidth>1</bitWidth>
            </field>
            <field>
              <name>DBG_I2C2</name>
              <bitOffset>22</bitOffset>
              <bitWidth>1</bitWidth>
            </field>
            <field>
              <name>DBG_I2C3</name>
              <bitOffset>23</bitOffset>
              <bitWidth>1</bitWidth>
            </field>
          </fields>
        </register>
        <register>
          <name>APB1LFZ2</name>
          <addressOffset>0x40</addressOffset>
          <size>0x20</size>
          <fields>
            <field>
              <name>DBG_TIM2</name>
              <bitOffset>0</bitOffset>
              <bitWidth>1</bitWidth>
            </field>
            <field>
              <name>DBG_TIM3</name>
              <bitOffset>1</bitOffset>
              <bitWidth>1</bitWidth>
            </field>
            <field>
              <name>DBG_TIM4</name>
              <bitOffset>2</bitOffset>
              <bitWidth>1</bitWidth>
            </field>
            <field>
              <name>DBG_TIM5</name>
              <bitOffset>3</bitOffset>
              <bitWidth>1</bitWidth>
            </field>
            <field>
              <name>DBG_TIM6</name>
              <bitOffset>4</bitOffset>
              <bitWidth>1</bitWidth>
            </field>
            <field>
              <name>DBG_TIM7</name>
              <bitOffset>5</bitOffset>
              <bitWidth>1</bitWidth>
            </field>
            <field>
              <name>DBG_TIM12</name>
              <bitOffset>6</bitOffset>
              <bitWidth>1</bitWidth>
            </field>
            <field>
              <name>DBG_TIM13</name>
              <bitOffset>7</bitOffset>
              <bitWidth>1</bitWidth>
            </field>
            <field>
              <name>DBG_TIM14</name>
              <bitOffset>8</bitOffset>
              <bitWidth>1</bitWidth>
            </field>
            <field>
              <name>DBG_LPTIM1</name>
              <bitOffset>9</bitOffset>
              <bitWidth>1</bitWidth>
            </field>
            <field>
              <name>DBG_WWDG2</name>
              <bitOffset>11</bitOffset>
              <bitWidth>1</bitWidth>
            </field>
            <field>
              <name>DBG_I2C1</name>
              <bitOffset>21</bitOffset>
              <bitWidth>1</bitWidth>
            </field>
            <field>
              <name>DBG_I2C2</name>
              <bitOffset>22</bitOffset>
              <bitWidth>1</bitWidth>
            </field>
            <field>
              <name>DBG_I2C3</name>
              <bitOffset>23</bitOffset>
              <bitWidth>1</bitWidth>
            </field>
          </fields>
        </register>
        <register>
          <name>APB1HFZ1</name>
          <addressOffset>0x44</addressOffset>
          <size>0x20</size>
          <fields>
            <field>
              <name>DBG_FDCAN</name>
              <bitOffset>8</bitOffset>
              <bitWidth>1</bitWidth>
            </field>
          </fields>
        </register>
        <register>
          <name>APB1HFZ2</name>
          <addressOffset>0x48</addressOffset>
          <size>0x20</size>
          <fields>
            <field>
              <name>DBG_FDCAN</name>
              <bitOffset>8</bitOffset>
              <bitWidth>1</bitWidth>
            </field>
          </fields>
        </register>
        <register>
          <name>APB2FZ1</name>
          <addressOffset>0x4c</addressOffset>
          <size>0x20</size>
          <fields>
            <field>
              <name>DBG_TIM1</name>
              <bitOffset>0</bitOffset>
              <bitWidth>1</bitWidth>
            </field>
            <field>
              <name>DBG_TIM8</name>
              <bitOffset>1</bitOffset>
              <bitWidth>1</bitWidth>
            </field>
            <field>
              <name>DBG_TIM15</name>
              <bitOffset>16</bitOffset>
              <bitWidth>1</bitWidth>
            </field>
            <field>
              <name>DBG_TIM16</name>
              <bitOffset>17</bitOffset>
              <bitWidth>1</bitWidth>
            </field>
            <field>
              <name>DBG_TIM17</name>
              <bitOffset>18</bitOffset>
              <bitWidth>1</bitWidth>
            </field>
            <field>
              <name>DBG_HRTIM</name>
              <bitOffset>29</bitOffset>
              <bitWidth>1</bitWidth>
            </field>
          </fields>
        </register>
        <register>
          <name>APB2FZ2</name>
          <addressOffset>0x50</addressOffset>
          <size>0x20</size>
          <fields>
            <field>
              <name>DBG_TIM1</name>
              <bitOffset>0</bitOffset>
              <bitWidth>1</bitWidth>
            </field>
            <field>
              <name>DBG_TIM8</name>
              <bitOffset>1</bitOffset>
              <bitWidth>1</bitWidth>
            </field>
            <field>
              <name>DBG_TIM15</name>
              <bitOffset>16</bitOffset>
              <bitWidth>1</bitWidth>
            </field>
            <field>
              <name>DBG_TIM16</name>
              <bitOffset>17</bitOffset>
              <bitWidth>1</bitWidth>
            </field>
            <field>
              <name>DBG_TIM17</name>
              <bitOffset>18</bitOffset>
              <bitWidth>1</bitWidth>
            </field>
            <field>
              <name>DBG_HRTIM</name>
              <bitOffset>29</bitOffset>
              <bitWidth>1</bitWidth>
            </field>
          </fields>
        </register>
        <register>
          <name>APB4FZ1</name>
          <addressOffset>0x54</addressOffset>
          <size>0x20</size>
          <fields>
            <field>
              <name>DBG_I2C4</name>
              <bitOffset>7</bitOffset>
              <bitWidth>1</bitWidth>
            </field>
            <field>
              <name>DBG_LPTIM2</name>
              <bitOffset>9</bitOffset>
              <bitWidth>1</bitWidth>
            </field>
            <field>
              <name>DBG_LPTIM3</name>
              <bitOffset>10</bitOffset>
              <bitWidth>1</bitWidth>
            </field>
            <field>
              <name>DBG_LPTIM4</name>
              <bitOffset>11</bitOffset>
              <bitWidth>1</bitWidth>
            </field>
            <field>
              <name>DBG_LPTIM5</name>
              <bitOffset>12</bitOffset>
              <bitWidth>1</bitWidth>
            </field>
            <field>
              <name>DBG_RTC</name>
              <bitOffset>16</bitOffset>
              <bitWidth>1</bitWidth>
            </field>
            <field>
              <name>DBG_IWDG1</name>
              <bitOffset>18</bitOffset>
              <bitWidth>1</bitWidth>
            </field>
            <field>
              <name>DBG_IWDG2</name>
              <bitOffset>19</bitOffset>
              <bitWidth>1</bitWidth>
            </field>
          </fields>
        </register>
        <register>
          <name>APB4FZ2</name>
          <addressOffset>0x58</addressOffset>
          <size>0x20</size>
          <fields>
            <field>
              <name>DBG_I2C4</name>
              <bitOffset>7</bitOffset>
              <bitWidth>1</bitWidth>
            </field>
            <field>
              <name>DBG_LPTIM2</name>
              <bitOffset>9</bitOffset>
              <bitWidth>1</bitWidth>
            </field>
            <field>
              <name>DBG_LPTIM3</name>
              <bitOffset>10</bitOffset>
              <bitWidth>1</bitWidth>
            </field>
            <field>
              <name>DBG_LPTIM4</name>
              <bitOffset>11</bitOffset>
              <bitWidth>1</bitWidth>
            </field>
            <field>
              <name>DBG_LPTIM5</name>
              <bitOffset>12</bitOffset>
              <bitWidth>1</bitWidth>
            </field>
            <field>
              <name>DBG_RTC</name>
              <bitOffset>16</bitOffset>
              <bitWidth>1</bitWidth>
            </field>
            <field>
              <name>DBG_IWDG1</name>
              <bitOffset>18</bitOffset>
              <bitWidth>1</bitWidth>
            </field>
            <field>
              <name>DBG_IWDG2</name>
              <bitOffset>19</bitOffset>
              <bitWidth>1</bitWidth>
            </field>
          </fields>
        </register>
      </registers>
    </peripheral>
  </peripherals>
</device>
